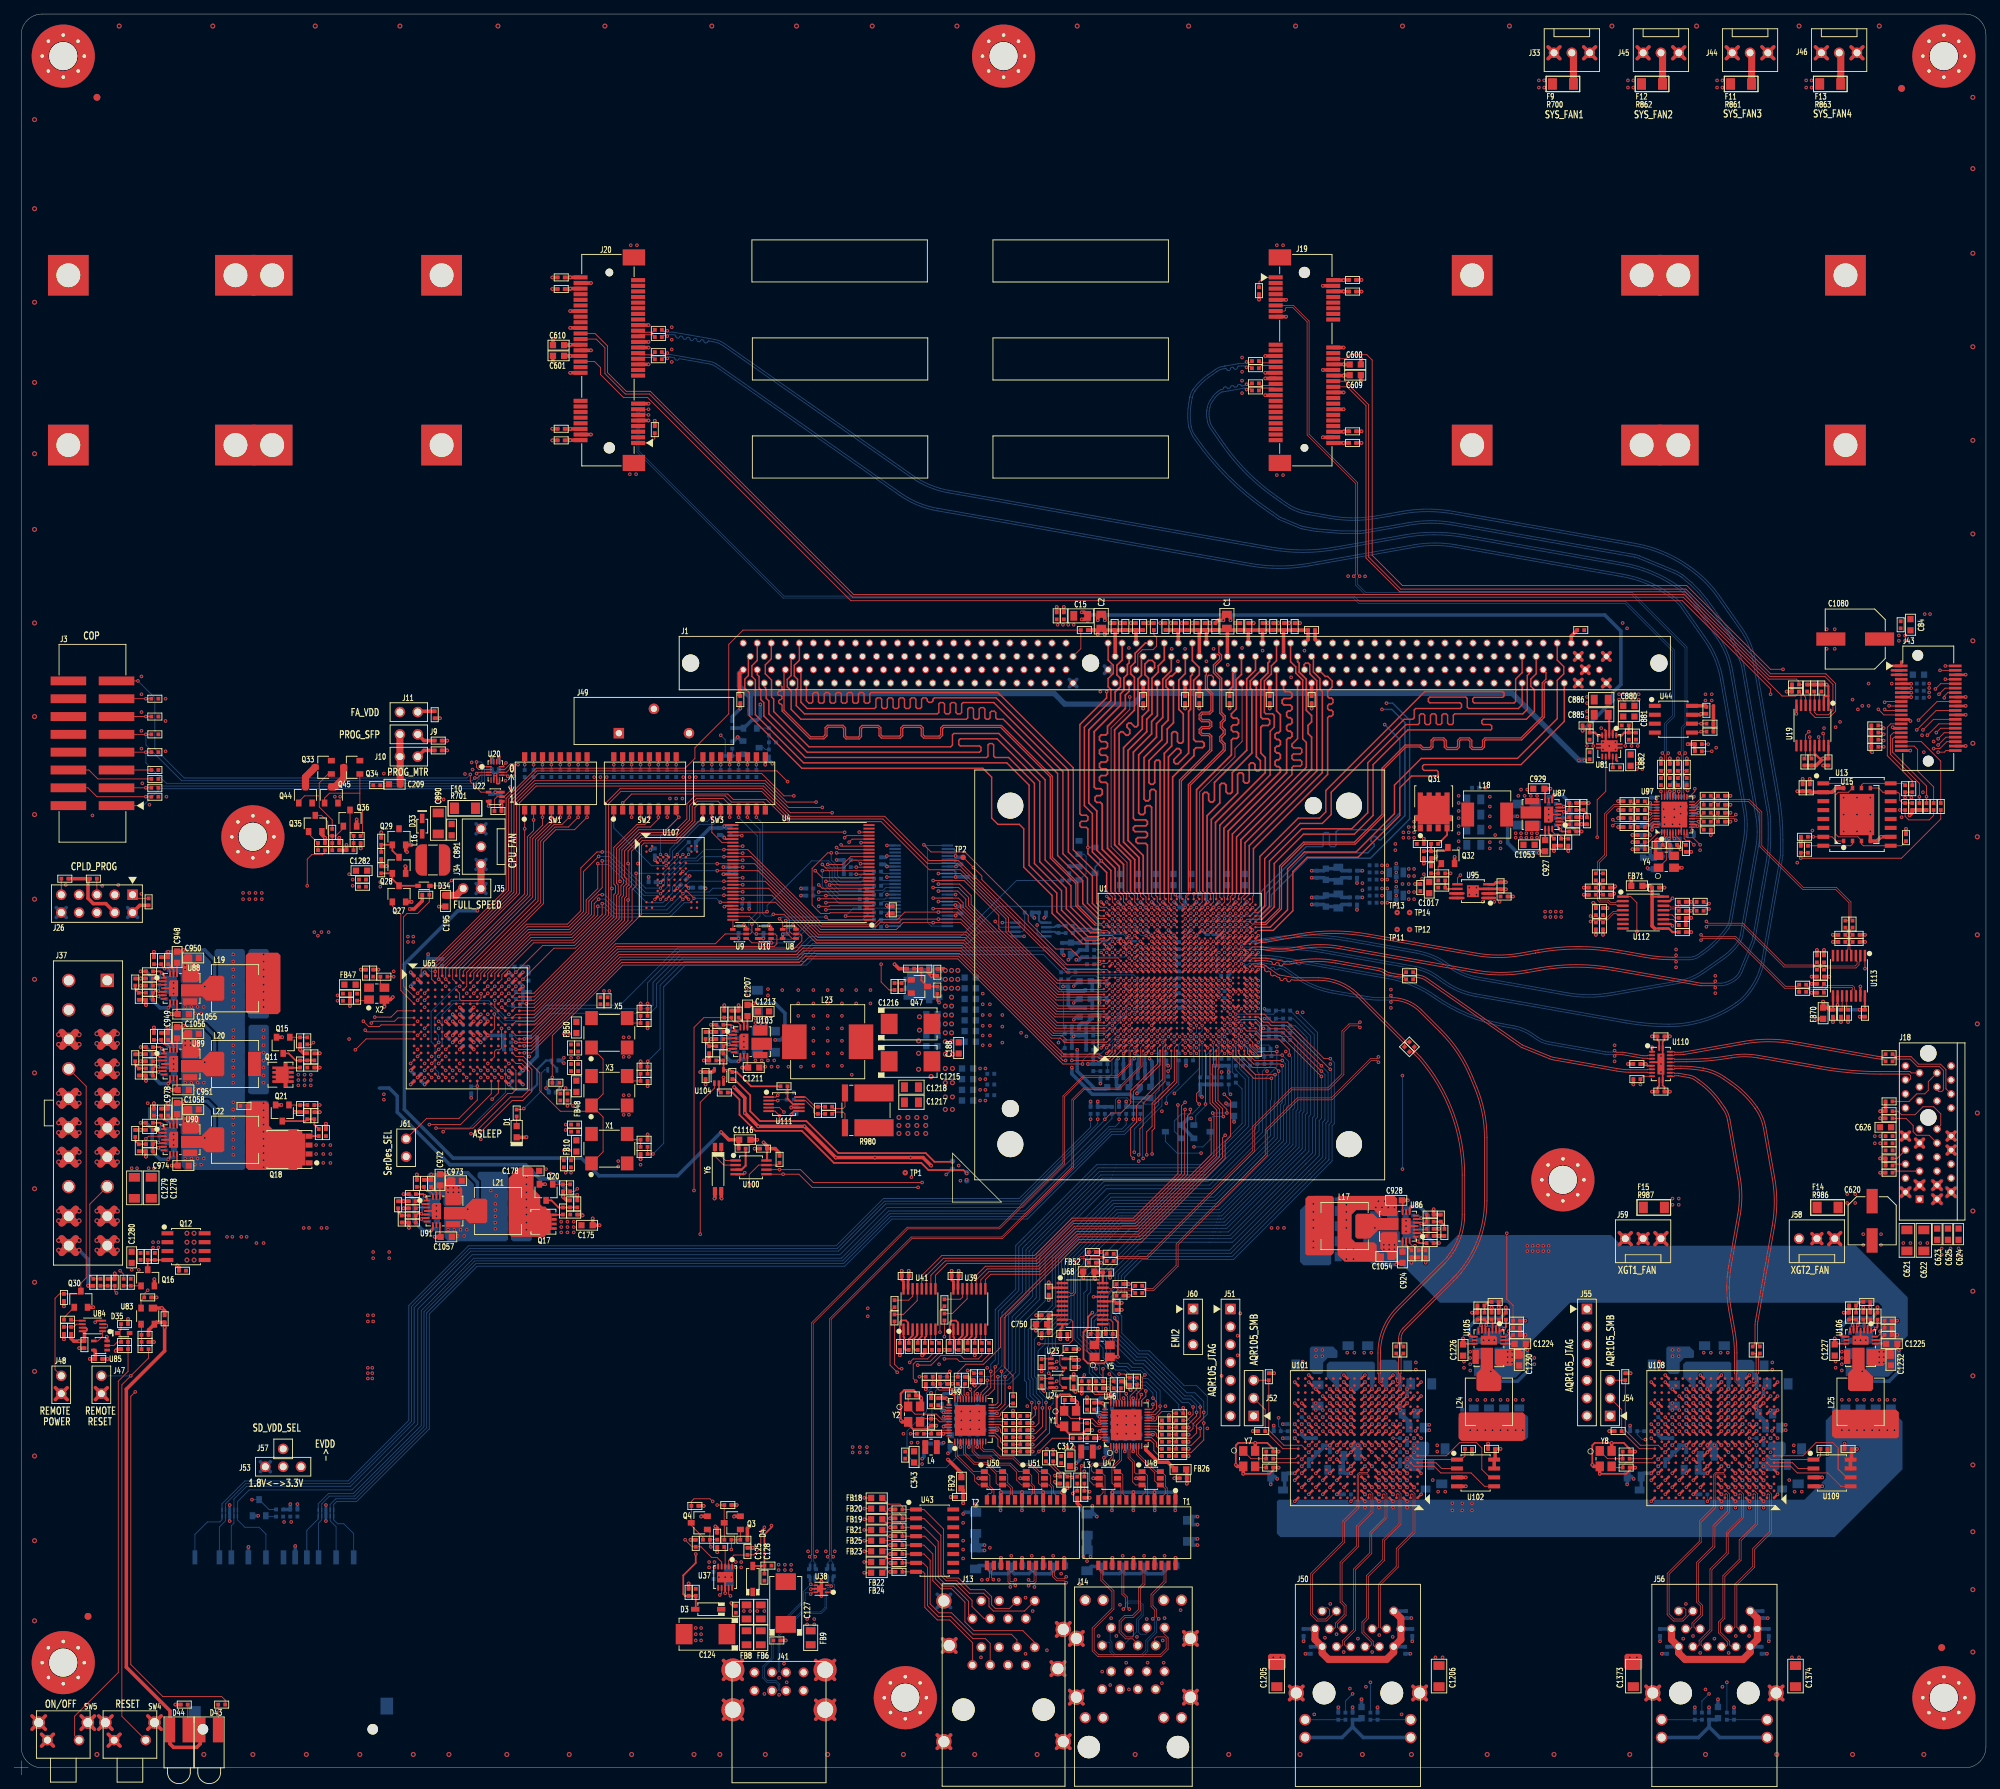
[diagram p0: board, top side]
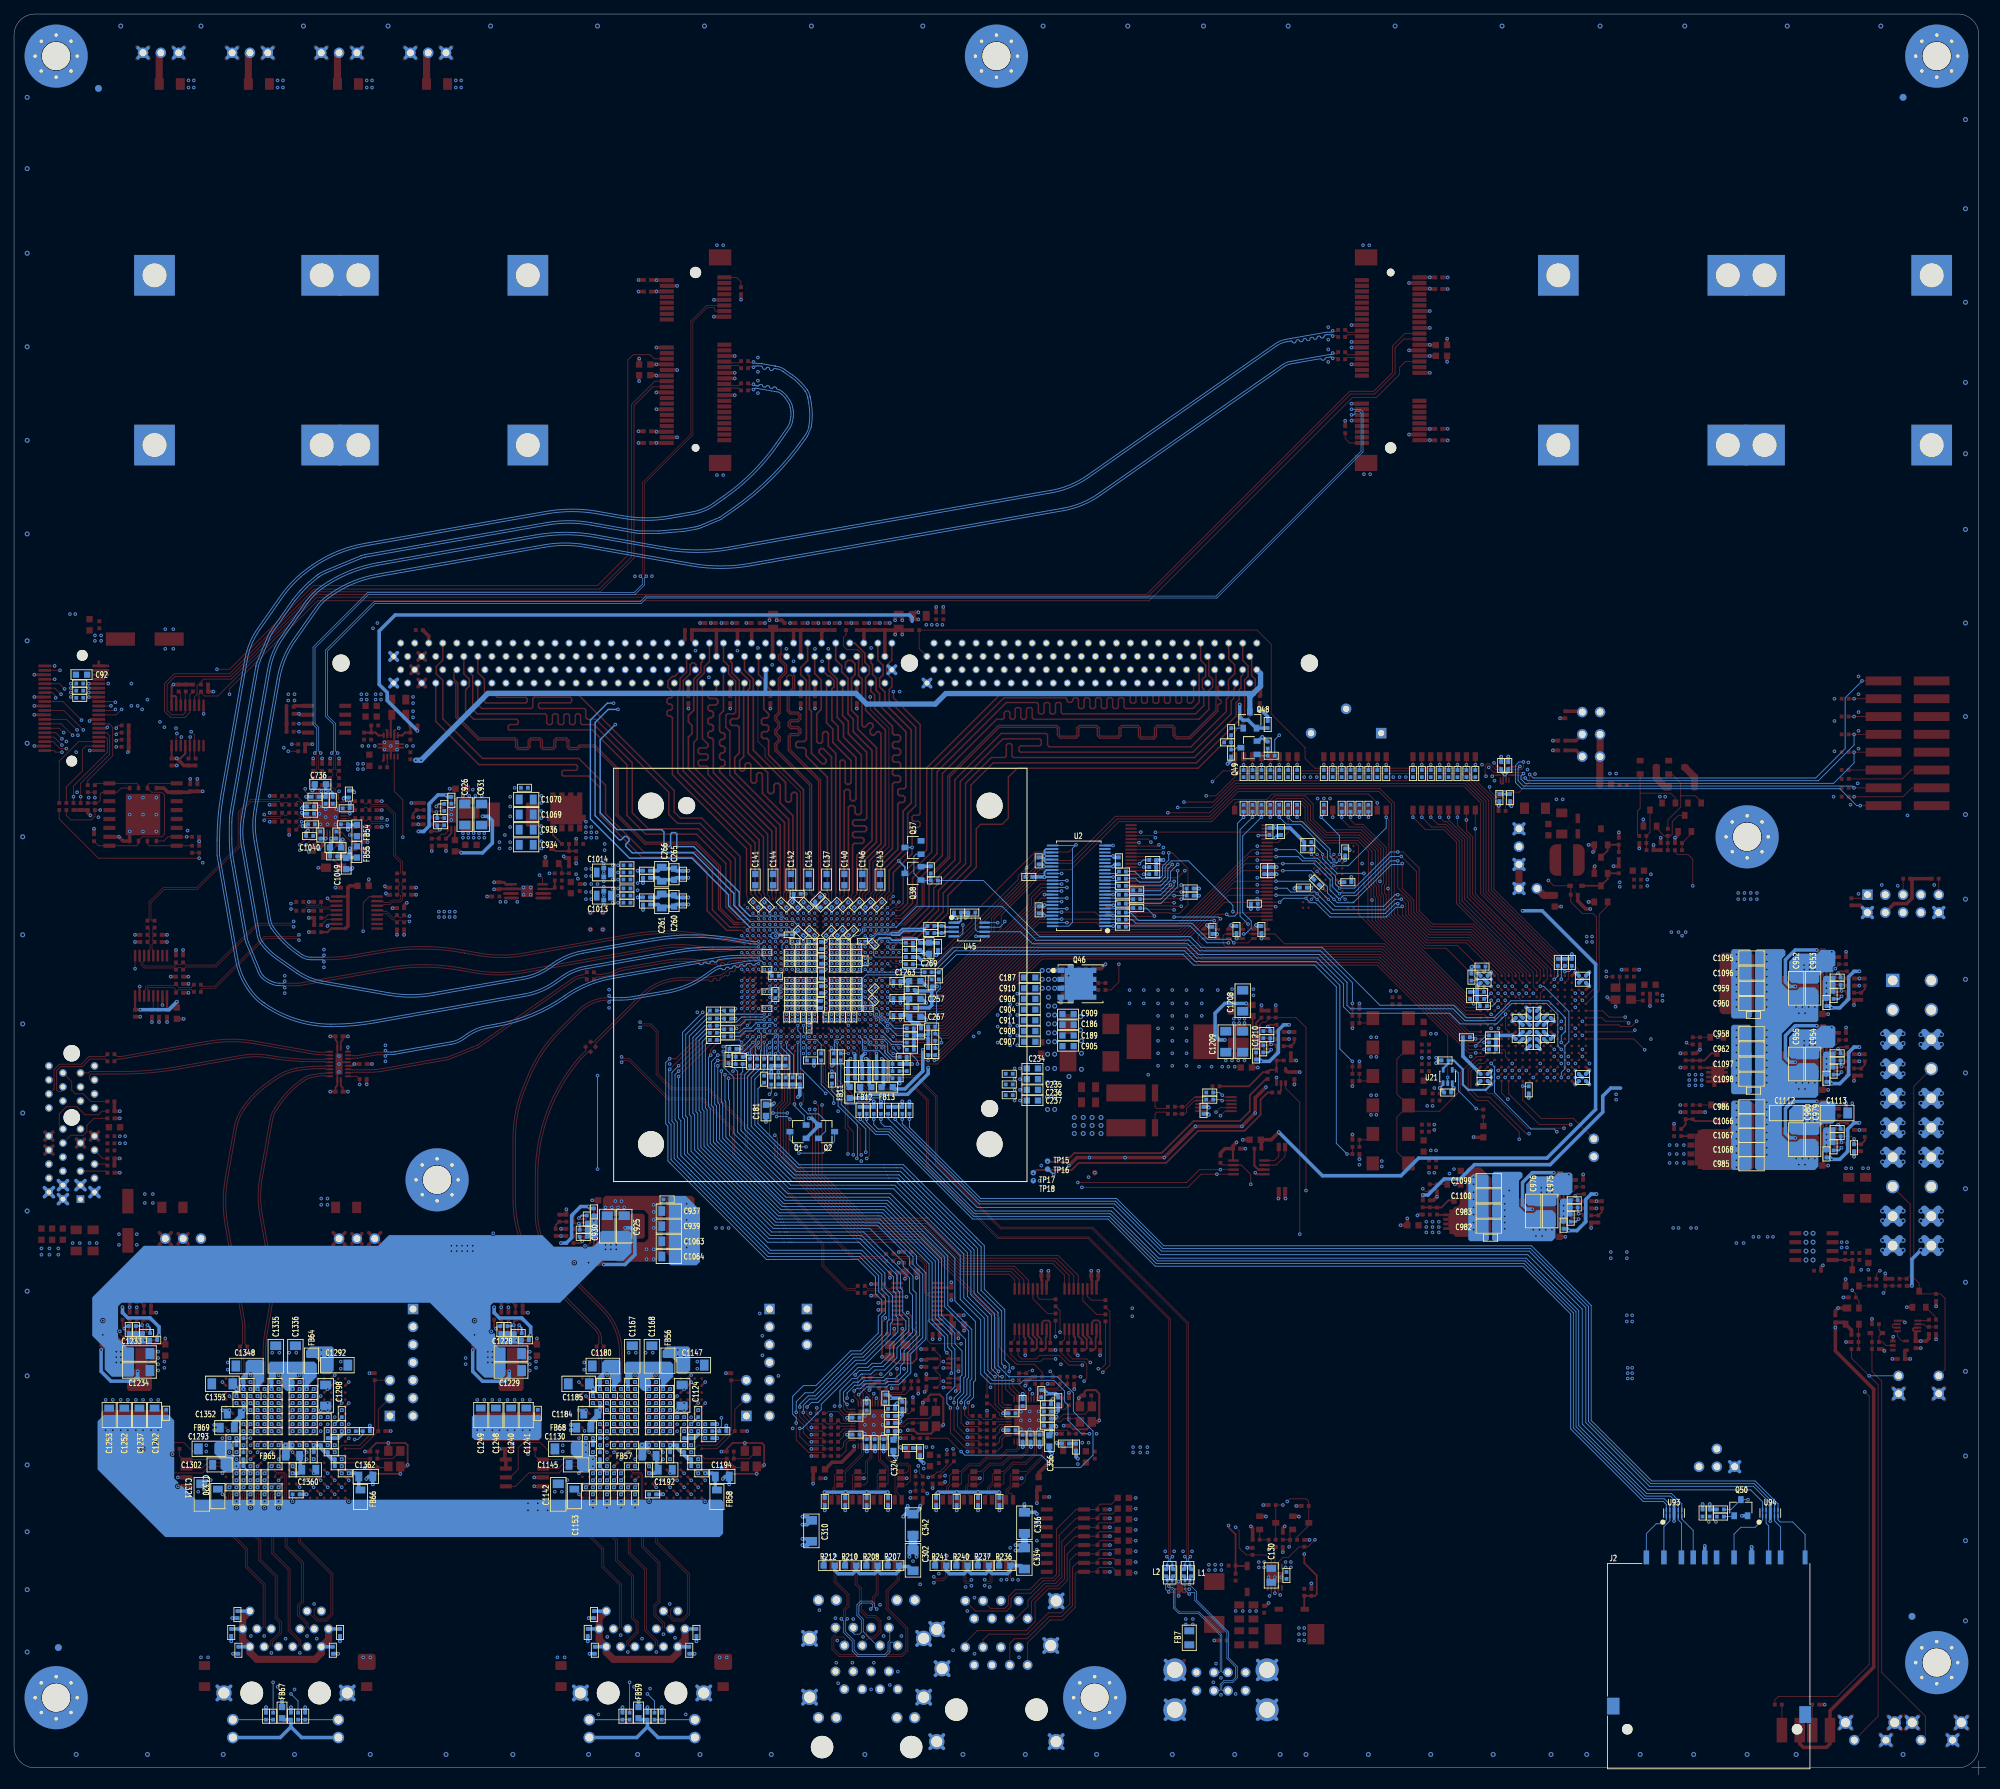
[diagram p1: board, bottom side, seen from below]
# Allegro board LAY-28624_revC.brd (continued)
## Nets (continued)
GND: C1.2 C2.2 C3.2 C4.2 C5.2 C6.2 C7.2 C8.2 C9.2 C10.2 C11.2 C12.2 C13.2 C14.2 C15.2 C16.2 C17.2 C18.2 C19.2 C20.2 C21.2 C22.2 C23.2 C24.2 C25.2 C26.2 C30.2 C31.2 C32.2 C33.2 C34.2 C35.2 C36.2 C37.2 C38.2 C39.2 C48.2 C49.2 C50.2 C51.2 C52.2 C53.2 C54.2 C55.1 C56.2 C57.2 C58.2 C84.2 C85.2 C92.2 C93.2 C94.2 C124.2 C125.2 C126.2 C127.2 C128.2 C129.2 C130.2 C131.2 C132.2 C133.2 C134.2 C135.2 C136.2 C137.2 C138.2 C139.2 C140.2 C141.2 C142.2 C143.2 C144.2 C145.2 C146.2 C147.2 C148.2 C149.2 C150.2 C151.2 C152.2 C153.2 C154.2 C155.2 C156.2 C157.2 C158.2 C159.2 C160.2 C161.2 C162.2 C163.2 C164.2 C165.2 C166.2 C167.2 C168.2 C169.2 C170.2 C171.2 C172.2 C173.2 C174.2 C175.2 C176.2 C177.2 C178.2 C179.2 C180.2 C181.2 C182.2 C183.2 C184.2 C185.2 C186.2 C187.2 C188.2 C189.2 C192.2 C195.2 C196.2 C197.2 C198.2 C199.2 C200.2 C201.2 C202.2 C203.2 C204.2 C205.2 C206.2 C207.2 C208.2 C209.2 C210.2 C211.2 C212.2 C213.2 C214.2 C215.2 C216.2 C217.2 C218.2 C219.2 C220.2 C222.2 C223.2 C224.2 C225.2 C226.2 C227.2 C228.2 C229.2 C230.2 C232.2 C234.2 C235.2 C236.2 C237.2 C238.2 C239.2 C240.2 C241.2 C242.2 C243.2 C244.2 C245.2 C246.2 C247.2 C248.2 C249.2 C250.2 C251.2 C252.2 C253.2 C254.2 C255.2 C257.2 C258.2 C267.2 C268.2 C269.2 C270.2 C272.2 C273.2 C275.2 C276.2 C277.2 C278.2 C279.2 C286.2 C287.2 C288.2 C289.2 C290.2 C291.2 C292.2 C293.2 C295.2 C296.1 C297.2 C298.1 C299.1 C300.1 C301.1 C303.2 C304.2 C305.2 C307.2 C308.2 C309.2 C310.1 C312.2 C313.2 C314.2 C315.2 C316.2 C317.2 C319.2 C320.2 C321.2 C322.2 C323.2 C324.2 C325.2 C326.2 C328.1 C329.2 C330.1 C331.1 C332.1 C333.1 C335.2 C336.1 C337.2 C338.2 C339.2 C340.2 C341.2 C342.1 C343.2 C344.2 C346.2 C347.2 C348.2 C349.2 C350.2 C351.2 C353.2 C354.2 C355.2 C356.2 C357.2 C358.2 C600.2 C601.2 C602.2 C603.2 C604.2 C605.2 C609.2 C610.2 C611.2 C612.2 C613.2 C614.2 C620.2 C621.2 C622.2 C623.2 C624.2 C625.2 C626.2 C627.2 C628.2 C629.2 C698.2 C699.2 C700.2 C701.2 C702.2 C703.2 C704.2 C705.2 C706.2 C707.2 C708.2 C709.2 C710.2 C711.2 C712.2 C713.2 C714.2 C715.2 C716.2 C718.2 C720.2 C721.2 C722.2 C723.2 C728.2 C729.2 C730.2 C731.2 C732.2 C733.2 C734.2 C735.2 C736.2 C737.2 C738.2 C739.2 C742.2 C743.2 C746.2 C747.2 C750.2 C751.2 C873.1 C875.1 C876.1 C880.2 C881.2 C882.2 C883.2 C884.2 C885.2 C886.2 C887.2 C892.2 C893.2 C894.2 C895.2 C896.2 C897.2 C898.2 C904.2 C905.2 C906.2 C907.2 C908.2 C909.2 C910.2 C911.2 C912.2 C913.2 C914.2 C915.2 C916.2 C917.2 C918.2 C919.2 C920.2 C921.2 C922.2 C923.2 C925.2 C926.2 C928.1 C929.1 C930.2 C931.2 C932.1 C933.2 C934.2 C936.2 C937.2 C938.1 C939.2 C940.2 C944.2 C945.2 C946.2 C947.2 C950.1 C951.1 C952.2 C953.2 C954.2 C955.2 C956.1 C957.1 C958.2 C959.2 C960.2 C961.2 C962.2 C963.2 C968.2 C969.2 C970.2 C971.2 C973.1 C974.1 C975.2 C976.2 C977.1 C979.2 C980.2 C981.1 C982.2 C983.2 C984.2 C985.2 C986.2 C987.2 C992.2 C993.2 C994.2 C995.2 C996.1 C998.2 C999.2 C1002.2 C1003.2 C1004.2 C1005.2 C1006.2 C1007.2 C1008.2 C1009.2 C1010.2 C1011.2 C1012.2 C1013.3 C1013.4 C1014.3 C1014.4 C1015.2 C1016.2 C1017.2 C1023.1 C1024.2 C1026.2 C1027.2 C1028.2 C1029.2 C1030.2 C1031.2 C1032.2 C1033.2 C1034.2 C1035.2 C1036.2 C1037.2 C1038.2 C1039.2 C1040.2 C1041.2 C1044.2 C1045.2 C1046.2 C1047.2 C1048.2 C1049.2 C1050.2 C1051.2 C1052.2 C1053.1 C1054.1 C1055.1 C1056.1 C1057.1 C1058.1 C1063.2 C1064.2 C1066.2 C1067.2 C1068.2 C1069.2 C1070.2 C1079.2 C1080.2 C1081.2 C1095.2 C1096.2 C1097.2 C1098.2 C1099.2 C1100.2 C1101.2 C1102.2 C1103.2 C1104.2 C1105.2 C1112.2 C1113.2 C1114.2 C1115.2 C1116.2 C1119.2 C1120.2 C1121.2 C1122.1 C1123.1 C1124.2 C1125.1 C1126.2 C1127.2 C1128.2 C1129.2 C1130.2 C1131.1 C1132.1 C1133.1 C1134.1 C1135.1 C1136.2 C1137.2 C1138.2 C1139.2 C1140.2 C1141.2 C1142.2 C1143.1 C1144.1 C1145.2 C1146.1 C1147.2 C1148.1 C1149.2 C1150.1 C1151.2 C1152.2 C1153.2 C1154.1 C1155.1 C1156.1 C1157.1 C1158.1 C1159.1 C1160.2 C1161.2 C1162.2 C1163.2 C1164.2 C1165.2 C1166.1 C1167.2 C1168.2 C1169.1 C1170.1 C1171.1 C1172.1 C1173.1 C1174.1 C1175.1 C1176.1 C1177.2 C1178.2 C1179.2 C1180.2 C1181.2 C1182.1 C1183.2 C1184.2 C1185.2 C1186.1 C1187.1 C1188.1 C1189.1 C1190.1 C1191.2 C1192.2 C1193.2 C1194.2 C1197.2 C1198.1 C1199.1 C1200.2 C1201.1 C1202.1 C1203.2 C1204.1 C1205.1 C1206.1 C1208.2 C1209.2 C1210.2 C1211.2 C1212.1 C1213.2 C1215.2 C1216.2 C1217.2 C1218.2 C1220.2 C1221.2 C1222.2 C1223.2 C1226.1 C1227.1 C1228.2 C1229.2 C1230.1 C1231.1 C1232.1 C1233.2 C1234.2 C1235.1 C1236.2 C1237.2 C1238.2 C1240.2 C1241.2 C1242.2 C1246.2 C1247.2 C1248.2 C1249.2 C1250.2 C1251.2 C1252.2 C1253.2 C1262.2 C1263.2 C1264.2 C1273.1 C1274.2 C1275.2 C1276.2 C1277.2 C1278.2 C1279.2 C1280.2 C1281.2 C1282.2 C1283.2 C1284.2 C1287.2 C1288.2 C1289.2 C1290.1 C1291.1 C1292.2 C1293.2 C1294.2 C1295.1 C1296.1 C1297.1 C1298.2 C1299.1 C1300.2 C1301.2 C1302.2 C1303.1 C1304.1 C1305.1 C1306.1 C1307.2 C1308.2 C1309.2 C1310.2 C1311.1 C1312.1 C1313.1 C1314.2 C1315.2 C1316.2 C1317.2 C1318.2 C1319.2 C1320.2 C1321.2 C1322.1 C1323.1 C1324.1 C1325.1 C1326.1 C1327.1 C1328.2 C1329.2 C1330.1 C1331.2 C1332.2 C1333.2 C1334.2 C1335.2 C1336.2 C1337.1 C1338.1 C1339.1 C1340.1 C1341.1 C1342.1 C1343.1 C1344.1 C1345.2 C1346.2 C1347.2 C1348.2 C1349.2 C1350.1 C1351.2 C1352.2 C1353.2 C1354.1 C1355.1 C1356.1 C1357.1 C1358.1 C1359.2 C1360.2 C1361.2 C1362.2 C1365.2 C1366.1 C1367.1 C1368.2 C1369.1 C1370.1 C1371.2 C1372.1 C1373.1 C1374.1 C1375.2 C1376.2 C1377.2 C1379.2 C1390.2 C1391.2 C1392.2 C1393.2 D1.1 FB7.2 FB9.2 J1.2(VSS#2) J1.5(VSS#5) J1.8(VSS#8) J1.11(VSS#11) J1.14(VSS#14) J1.17(VSS#17) J1.20(VSS#20) J1.23(VSS#23) J1.26(VSS#26) J1.29(VSS#29) J1.32(VSS#32) J1.35(VSS#35) J1.38(VSS#38) J1.41(VSS#41) J1.44(VSS#44) J1.47(VSS#47) J1.80(VSS#80) J1.83(VSS#83) J1.86(VSS#86) J1.89(VSS#89) J1.92(VSS#92) J1.95(VSS#95) J1.98(VSS#98) J1.101(VSS#101) J1.104(VSS#104) J1.107(VSS#107) J1.110(VSS#110) J1.113(VSS#113) J1.116(VSS#116) J1.119(SA2) J1.121(VSS#121) J1.124(VSS#124) J1.127(VSS#127) J1.130(VSS#130) J1.133(VSS#133) J1.136(VSS#136) J1.139(VSS#139) J1.142(VSS#142) J1.145(VSS#145) J1.148(VSS#148) J1.151(VSS#151) J1.154(VSS#154) J1.157(VSS#157) J1.160(VSS#160) J1.163(VSS#163) J1.166(VSS#166) J1.199(VSS#199) J1.202(VSS#202) J1.205(VSS#205) J1.208(VSS#208) J1.211(VSS#211) J1.214(VSS#214) J1.217(VSS#217) J1.220(VSS#220) J1.223(VSS#223) J1.226(VSS#226) J1.229(VSS#229) J1.232(VSS#232) J1.235(VSS#235) J1.237(SA1) J1.239(VSS#239) J2.3(VSS#3) J2.6(VSS#6) J2.12(COM1) J2.13(COM2) J3.12 J3.16 J13.A4 J13.A5 J13.B4 J13.B5 J14.A10 J14.B10 J18.A1(P\R\S\N\T\1\) J18.A4(GND#A4) J18.A12(GND#A12) J18.A15(GND#A15) J18.A18(GND#A18) J18.B4(GND#B4) J18.B7(GND#B7) J18.B13(GND#B13) J18.B16(GND#B16) J18.B18(GND#B18) J19.4(GND#4) J19.9(GND#9) J19.15(GND#15) J19.18(GND#18) J19.21(GND#21) J19.26(GND#26) J19.27(GND#27) J19.29(GND#29) J19.34(GND#34) J19.35(GND#35) J19.40(GND#40) J19.50(GND#50) J19.53(MS1) J19.54(MS2) J20.4(GND#4) J20.9(GND#9) J20.15(GND#15) J20.18(GND#18) J20.21(GND#21) J20.26(GND#26) J20.27(GND#27) J20.29(GND#29) J20.34(GND#34) J20.35(GND#35) J20.40(GND#40) J20.50(GND#50) J20.53(MS1) J20.54(MS2) J26.2 J26.10 J33.1 J33.3 J35.2 J37.3(COM#3) J37.5(COM#5) J37.7(COM#7) J37.13(COM#13) J37.15(COM#15) J37.16(COM#16) J37.17(COM#17) J43.5 J43.15 J43.19 J43.23 J43.26 J43.30 J43.37 J43.40 J44.1 J44.3 J45.1 J45.3 J46.1 J46.3 J47.2 J48.2 J49.2 J51.7 J52.1 J54.1 J55.7 J58.1 J58.3 J59.1 J59.3 J60.1 J61.2 M3.1 M4.1 M5.1 M6.1 M7.1 M8.1 M9.1 M10.1 M11.1 M12.1 M13.1 M14.1 M15.1 M16.1 M17.1 M18.1 Q3.2(S) Q4.2(S) Q15.2(S) Q16.2(S) Q20.2(S) Q21.2(S) Q27.2(S) Q28.2(S) Q29.2(S) Q30.2(E) Q32.2(S) Q35.2(S) Q36.2(S) Q37.2(S) Q38.2(S) Q47.2(S) Q49.2(S) R3.1 R13.1 R17.2 R19.2 R21.2 R23.2 R25.2 R27.2 R29.2 R31.2 R33.2 R34.2 R35.2 R36.2 R37.2 R38.2 R39.2 R40.2 R104.1 R105.1 R106.1 R123.1 R124.2 R161.1 R162.1 R165.1 R166.1 R171.1 R172.1 R173.1 R176.1 R177.1 R178.1 R179.1 R190.2 R193.2 R227.1 R228.2 R233.2 R256.1 R257.2 R261.2 R262.2 R400.2 R401.2 R496.1 R499.2 R500.2 R501.2 R503.2 R505.2 R507.2 R509.2 R513.1 R518.1 R519.2 R523.2 R524.1 R527.2 R528.1 R534.2 R535.1 R538.1 R541.1 R542.1 R543.1 R544.1 R656.1 R669.1 R671.1 R672.1 R673.1 R684.1 R685.1 R696.1 R699.1 R708.1 R712.1 R742.1 R743.1 R744.1 R745.1 R760.1 R761.1 R762.1 R763.1 R778.1 R779.1 R780.1 R781.1 R782.1 R786.1 R807.1 R814.1 R815.1 R821.1 R831.1 R835.2 R838.2 R842.1 R870.1 R888.2 R889.2 R890.2 R891.2 R892.2 R899.2 R900.2 R901.1 R909.1 R911.1 R913.1 R920.1 R935.1 R936.1 R937.1 R938.1 R945.1 R949.1 R950.1 R951.1 R955.1 R961.2 R962.2 R963.2 R964.2 R967.2 R972.2 R973.2 R974.1 R975.1 R979.1 R983.1 R984.1 R993.2 R995.2 R997.2 R999.2 R1000.2 R1001.2 R1002.2 R1003.2 R1004.1 R1005.1 R1006.1 R1007.1 R1008.1 R1009.1 R1010.1 R1011.1 R1013.2 R1014.1 SW3.9 SW4.1 SW4.3 SW4.4 SW5.1 SW5.3 SW5.4 U1.A2(GND001) U1.A20(GND002) U1.A27(GND003) U1.AA7(GND148) U1.AA11(GND149) U1.AA13(SD_GND05) U1.AA15(SD_GND06) U1.AA17(SD_GND08) U1.AA19(SD_GND09) U1.AA21(SD_GND11) U1.AA24(GND150) U1.AB2(GND151) U1.AB5(GND152) U1.AB7(GND153) U1.AB13(SD_GND12) U1.AB17(SD_GND13) U1.AB21(SD_GND14) U1.AB22(GND154) U1.AB26(GND155) U1.AC1(NC_AC1) U1.AC2(NC_AC2) U1.AC10(NC_AC10) U1.AC11(NC_AC11) U1.AC13(SD_GND15) U1.AC14(SD_GND16) U1.AC16(SD_GND17) U1.AC17(SD_GND18) U1.AC19(SD_GND19) U1.AC20(SD_GND20) U1.AC24(GND156) U1.AC26(GND157) U1.AD4(GND158) U1.AD6(GND159) U1.AD9(NC_AD9) U1.AD12(NC_AD12) U1.AD15(SD_GND21) U1.AD18(SD_GND22) U1.AD21(SD_GND23) U1.AD22(GND160) U1.AE2(GND161) U1.AE9(NC_AE9) U1.AE12(NC_AE12) U1.AE15(SD_GND24) U1.AE18(SD_GND25) U1.AE21(SD_GND26) U1.AE24(GND162) U1.AE26(GND163) U1.AF9(GND164) U1.AF10(NC_AF10) U1.AF11(NC_AF11) U1.AF12(NC_AF12) U1.AF13(NC_AF13) U1.AF14(NC_AF14) U1.AF15(SD_GND27) U1.AF16(SD_GND28) U1.AF17(SD_GND29) U1.AF18(SD_GND30) U1.AF19(SD_GND31) U1.AF20(SD_GND32) U1.AF21(GND165) U1.AG1(GND166) U1.AG4(GND167) U1.AG6(GND168) U1.AG9(NC_AG9) U1.AG10(NC_AG10) U1.AG11(NC_AG11) U1.AG12(NC_AG12) U1.AG13(NC_AG13) U1.AG14(NC_AG14) U1.AG15(SD_GND33) U1.AG18(SD_GND34) U1.AG21(SD_GND35) U1.AG22(GND169) U1.AG23(GND170) U1.AG26(GND171) U1.AH2(GND172) U1.AH9(NC_AH9) U1.AH10(NC_AH10) U1.AH11(NC_AH11) U1.AH12(NC_AH12) U1.AH13(NC_AH13) U1.AH14(NC_AH14) U1.AH15(SD_GND36) U1.AH18(SD_GND37) U1.AH21(SD_GND38) U1.B1(GND004) U1.B4(GND005) U1.B7(GND006) U1.B10(GND007) U1.B13(GND008) U1.B16(GND009) U1.B19(GND010) U1.B23(GND011) U1.B25(GND012) U1.B28(GND013) U1.C22(GND014) U1.C26(GND015) U1.D2(GND016) U1.D20(GND017) U1.D21(GND018) U1.D24(GND019) U1.E1(USB_AGND01) U1.E2(USB_AGND02) U1.E3(USB_AGND03) U1.E5(GND020) U1.E7(GND021) U1.E10(GND022) U1.E13(GND023) U1.E16(GND024) U1.E19(GND025) U1.E22(GND026) U1.E26(GND027) U1.F3(USB_AGND04) U1.F15(GND028) U1.F24(GND029) U1.G1(USB_AGND05) U1.G2(USB_AGND06) U1.G3(USB_AGND07) U1.G5(USB_AGND08) U1.G7(GND030) U1.G13(GND031) U1.G16(GND032) U1.G22(GND033) U1.G26(GND034) U1.H3(USB_AGND09) U1.H7(GND035) U1.H8(GND036) U1.H9(GND037) U1.H10(GND038) U1.H11(GND039) U1.H12(GND040) U1.H13(GND041) U1.H14(GND042) U1.H15(GND043) U1.H16(GND044) U1.H17(GND045) U1.H18(GND046) U1.H19(GND047) U1.H20(GND048) U1.H24(GND049) U1.J1(USB_AGND10) U1.J2(USB_AGND11) U1.J3(USB_AGND12) U1.J7(GND050) U1.J22(GND051) U1.J26(GND052) U1.K2(GND053) U1.K5(GND054) U1.K6(GND055) U1.K7(GND056) U1.K12(GND057) U1.K14(GND058) U1.K16(GND059) U1.K18(GND060) U1.K20(GND061) U1.K24(GND062) U1.L7(GND063) U1.L9(GND064) U1.L11(GND065) U1.L13(GND066) U1.L15(GND067) U1.L17(GND068) U1.L19(GND069) U1.L22(GND070) U1.L26(GND071) U1.M7(GND072) U1.M10(GND073) U1.M12(GND074) U1.M14(GND075) U1.M16(GND076) U1.M18(GND077) U1.M20(GND078) U1.M24(GND079) U1.N2(GND080) U1.N5(GND081) U1.N7(GND082) U1.N9(GND083) U1.N11(GND084) U1.N13(GND085) U1.N15(GND086) U1.N17(GND087) U1.N19(GND088) U1.N22(GND089) U1.N26(GND090) U1.P7(GND091) U1.P10(GND092) U1.P12(GND093) U1.P14(GND094) U1.P16(GND095) U1.P18(GND096) U1.P20(GND097) U1.P24(GND098) U1.R7(GND099) U1.R9(GND100) U1.R11(GND101) U1.R13(GND102) U1.R15(GND103) U1.R17(GND104) U1.R19(GND105) U1.R22(GND106) U1.R26(GND107) U1.T2(GND108) U1.T5(GND109) U1.T7(GND110) U1.T10(GND111) U1.T12(GND112) U1.T14(GND113) U1.T16(GND114) U1.T18(GND115) U1.T20(GND116) U1.T22(GND117) U1.T26(GND118) U1.U7(GND119) U1.U9(GND120) U1.U11(GND121) U1.U13(GND122) U1.U15(GND123) U1.U17(GND124) U1.U19(GND125) U1.U24(GND126) U1.V7(GND127) U1.V10(GND128) U1.V12(GND129) U1.V14(GND130) U1.V16(GND131) U1.V18(GND132) U1.V20(GND133) U1.V22(GND134) U1.V26(GND135) U1.W2(GND136) U1.W5(GND137) U1.W7(GND138) U1.W9(GND139) U1.W11(GND140) U1.W13(GND141) U1.W24(GND142) U1.Y7(GND143) U1.Y10(GND144) U1.Y12(GND145) U1.Y14(SD_GND01) U1.Y16(SD_GND02) U1.Y17(SD_GND03) U1.Y18(SD_GND04) U1.Y22(GND146) U1.Y26(GND147) U2.1(O\E\1\) U2.4(GND#4) U2.10(GND#10) U2.15(GND#15) U2.21(GND#21) U2.24(O\E\2\) U2.26(2D8) U2.27(2D7) U2.28(GND#28) U2.29(2D6) U2.30(2D5) U2.32(2D4) U2.34(GND#34) U2.39(GND#39) U2.45(GND#45) U4.33(GND#33) U4.52(GND#52) U8.3(GND) U9.3(GND) U10.3(GND) U13.10(GND) U15.4(GND) U15.9(EPAD) U19.8(VSS) U20.6(GND#6) U20.7(GND#7) U20.8(O\E\) U21.3(GND) U22.3(GND) U23.3(GND) U24.3(GND) U37.8(GND) U37.11(EPAD) U38.2 U39.15(GND) U41.15(GND) U43.9 U43.10 U43.11 U43.12 U43.13 U43.14 U43.15 U43.16 U44.1(A0) U44.2(A1) U44.3(A2) U44.4(GND) U44.7(WP) U45.5(GND) U46.47(GND) U46.49(EPAD) U47.2 U48.2 U49.47(GND) U49.49(EPAD) U50.2 U51.2 U65.A1(GNDIO#A1) U65.A16(GNDIO#A16) U65.B2(GNDIO#B2) U65.B15(GNDIO#B15) U65.G7(GNDIO#G7) U65.G8(GNDIO#G8) U65.G9(GNDIO#G9) U65.G10(GNDIO#G10) U65.H7(GNDINT#H7) U65.H9(GNDINT#H9) U65.J8(GNDINT#J8) U65.J10(GNDINT#J10) U65.K7(GNDIO#K7) U65.K8(GNDIO#K8) U65.K9(GNDIO#K9) U65.K10(GNDIO#K10) U65.R2(GNDIO#R2) U65.R15(GNDIO#R15) U65.T1(GNDIO#T1) U65.T16(GNDIO#T16) U68.17(VEE) U81.4(PGND) U81.8(GND) U81.11(PAD) U83.1(GND) U84.4(GND) U85.3(GND) U86.4(GND#4) U86.11(PGND) U86.17(GND#17) U87.4(GND#4) U87.11(PGND) U87.17(GND#17) U88.4(GND#4) U88.11(PGND) U88.17(GND#17) U89.4(GND#4) U89.11(PGND) U89.17(GND#17) U90.4(GND#4) U90.11(PGND) U90.17(GND#17) U91.4(GND#4) U91.11(PGND) U91.17(GND#17) U93.9 U94.9 U95.3(GND) U95.9(EPAD) U97.8(GNDDIG) U97.41(EPAD) U100.4(GND) U101.A1(RG_A1) U101.A18(RG_A18) U101.B3(AVSS#B3) U101.B5(AVSS#B5) U101.B7(AVSS#B7) U101.B9(AVSS#B9) U101.B12(AVSS#B12) U101.B14(AVSS#B14) U101.B16(AVSS#B16) U101.C2(AVSS#C2) U101.C4(AVSS#C4) U101.C6(AVSS#C6) U101.C8(AVSS#C8) U101.C11(AVSS#C11) U101.C13(AVSS#C13) U101.C15(AVSS#C15) U101.C17(AVSS#C17) U101.D3(AVSS#D3) U101.D5(AVSS#D5) U101.D7(AVSS#D7) U101.D9(AVSS#D9) U101.D12(AVSS#D12) U101.D14(AVSS#D14) U101.D16(AVSS#D16) U101.D18(AVSS#D18) U101.E1(DC_MASTER_N) U101.E4(AVSS#E4) U101.E6(AVSS_PLL) U101.E11(AVSS#E11) U101.E13(AVSS#E13) U101.E15(AVSS#E15) U101.E17(AVSS#E17) U101.F6(AVSS#F6) U101.F8(AVSS#F8) U101.F10(AVSS#F10) U101.F12(AVSS#F12) U101.G5(AVSS#G5) U101.G7(AVSS#G7) U101.G9(AVSS#G9) U101.G11(AVSS#G11) U101.H4(MDIO_1P2_SELECT_N) U101.H6(AVSS#H6) U101.H8(AVSS#H8) U101.H10(AVSS#H10) U101.H12(AVSS#H12) U101.J5(VSS#J5) U101.J7(VSS#J7) U101.J9(VSS#J9) U101.J11(VSS#J11) U101.J13(VSS#J13) U101.K6(VSS#K6) U101.K8(VSS#K8) U101.K10(VSS#K10) U101.K12(VSS#K12) U101.L4(RG_L4) U101.L7(VSS#L7) U101.L9(VSS#L9) U101.L11(VSS#L11) U101.L13(VSS#L13) U101.M6(VSS#M6) U101.M8(VSS#M8) U101.M10(VSS#M10) U101.M12(VSS#M12) U101.N1(VSS_SRDS#N1) U101.N2(VSS_SRDS#N2) U101.N5(VSS#N5) U101.N7(VSS#N7) U101.N9(VSS#N9) U101.N11(VSS#N11) U101.N13(VSS#N13) U101.P3(VSS_SRDS#P3) U101.P6(VSS#P6) U101.P8(VSS#P8) U101.P10(VSS#P10) U101.P12(VSS#P12) U101.P17(VSS_SRDS#P17) U101.P18(VSS_SRDS#P18) U101.R1(VSS_SRDS#R1) U101.R2(VSS_SRDS#R2) U101.R4(VSS_SRDS#R4) U101.R6(VSS_SRDS#R6) U101.R7(VSS#R7) U101.R9(VSS#R9) U101.R11(VSS#R11) U101.R13(VSS#R13) U101.R14(VSS_SRDS#R14) U101.T3(VSS_SRDS#T3) U101.T5(VSS_SRDS#T5) U101.T7(VSS_SRDS#T7) U101.T9(VSS_SRDS#T9) U101.T11(VSS_SRDS#T11) U101.T13(VSS_SRDS#T13) U101.T15(VSS_SRDS#T15) U101.U1(VSS_SRDS#U1) U101.U5(VSS_SRDS#U5) U101.U9(VSS_SRDS#U9) U101.U11(VSS_SRDS#U11) U101.U16(VSS_SRDS#U16) U101.U18(VSS_SRDS#U18) U101.V5(VSS_SRDS#V5) U101.V9(VSS_SRDS#V9) U101.V11(VSS_SRDS#V11) U101.V16(VSS_SRDS#V16) U102.4(GND) U103.4(GND#4) U103.11(PGND) U103.17(GND#17) U104.3(GND) U105.4(GND#4) U105.11(PGND) U105.17(GND#17) U106.4(GND#4) U106.11(PGND) U106.17(GND#17) U107.C5(VSS#C5) U107.F7(VSS#F7) U107.K3(VSS#K3) U107.K8(VSS#K8) U108.A1(RG_A1) U108.A18(RG_A18) U108.B3(AVSS#B3) U108.B5(AVSS#B5) U108.B7(AVSS#B7) U108.B9(AVSS#B9) U108.B12(AVSS#B12) U108.B14(AVSS#B14) U108.B16(AVSS#B16) U108.C2(AVSS#C2) U108.C4(AVSS#C4) U108.C6(AVSS#C6) U108.C8(AVSS#C8) U108.C11(AVSS#C11) U108.C13(AVSS#C13) U108.C15(AVSS#C15) U108.C17(AVSS#C17) U108.D3(AVSS#D3) U108.D5(AVSS#D5) U108.D7(AVSS#D7) U108.D9(AVSS#D9) U108.D12(AVSS#D12) U108.D14(AVSS#D14) U108.D16(AVSS#D16) U108.D18(AVSS#D18) U108.E1(DC_MASTER_N) U108.E4(AVSS#E4) U108.E6(AVSS_PLL) U108.E11(AVSS#E11) U108.E13(AVSS#E13) U108.E15(AVSS#E15) U108.E17(AVSS#E17) U108.F6(AVSS#F6) U108.F8(AVSS#F8) U108.F10(AVSS#F10) U108.F12(AVSS#F12) U108.G5(AVSS#G5) U108.G7(AVSS#G7) U108.G9(AVSS#G9) U108.G11(AVSS#G11) U108.H4(MDIO_1P2_SELECT_N) U108.H6(AVSS#H6) U108.H8(AVSS#H8) U108.H10(AVSS#H10) U108.H12(AVSS#H12) U108.J5(VSS#J5) U108.J7(VSS#J7) U108.J9(VSS#J9) U108.J11(VSS#J11) U108.J13(VSS#J13) U108.K6(VSS#K6) U108.K8(VSS#K8) U108.K10(VSS#K10) U108.K12(VSS#K12) U108.L4(RG_L4) U108.L7(VSS#L7) U108.L9(VSS#L9) U108.L11(VSS#L11) U108.L13(VSS#L13) U108.M6(VSS#M6) U108.M8(VSS#M8) U108.M10(VSS#M10) U108.M12(VSS#M12) U108.N1(VSS_SRDS#N1) U108.N2(VSS_SRDS#N2) U108.N5(VSS#N5) U108.N7(VSS#N7) U108.N9(VSS#N9) U108.N11(VSS#N11) U108.N13(VSS#N13) U108.P3(VSS_SRDS#P3) U108.P6(VSS#P6) U108.P8(VSS#P8) U108.P10(VSS#P10) U108.P12(VSS#P12) U108.P17(VSS_SRDS#P17) U108.P18(VSS_SRDS#P18) U108.R1(VSS_SRDS#R1) U108.R2(VSS_SRDS#R2) U108.R4(VSS_SRDS#R4) U108.R6(VSS_SRDS#R6) U108.R7(VSS#R7) U108.R9(VSS#R9) U108.R11(VSS#R11) U108.R13(VSS#R13) U108.R14(VSS_SRDS#R14) U108.T3(VSS_SRDS#T3) U108.T5(VSS_SRDS#T5) U108.T7(VSS_SRDS#T7) U108.T9(VSS_SRDS#T9) U108.T11(VSS_SRDS#T11) U108.T13(VSS_SRDS#T13) U108.T15(VSS_SRDS#T15) U108.U1(VSS_SRDS#U1) U108.U5(VSS_SRDS#U5) U108.U9(VSS_SRDS#U9) U108.U11(VSS_SRDS#U11) U108.U16(VSS_SRDS#U16) U108.U18(VSS_SRDS#U18) U108.V5(VSS_SRDS#V5) U108.V9(VSS_SRDS#V9) U108.V11(VSS_SRDS#V11) U108.V16(VSS_SRDS#V16) U109.4(GND) U110.2(PD) U110.5(GND#5) U110.11(GND#11) U110.20(GND#20) U110.21(EPAD) U111.7(GND) U112.10(VEE#10) U112.15(VEE#15) U113.10(VEE#10) U113.15(VEE#15) X1.2(GND) X2.2(GND) X3.2(GND) X5.2(GND) Y1.2 Y1.4 Y2.2 Y2.4 Y4.2 Y4.4 Y5.2 Y5.4 Y6.2 Y6.3 Y7.2 Y7.4 Y8.2 Y8.4 Z105.1 Z105.2 Z105.3 Z105.4 Z105.5 Z105.6 Z105.7 Z105.8 Z106.1 Z106.2 Z106.3 Z106.4 Z106.5 Z106.6 Z106.7 Z106.8 Z109.1 Z109.2 Z109.3 Z109.4 Z109.5 Z109.6 Z109.7 Z109.8 Z110.1 Z110.2 Z110.3 Z110.4 Z110.5 Z110.6 Z110.7 Z110.8 Z111.1 Z111.2 Z111.3 Z111.4 Z111.5 Z111.6 Z111.7 Z111.8 Z112.1 Z112.2 Z112.3 Z112.4 Z112.5 Z112.6 Z112.7 Z112.8
SVDD: C242.1 C243.1 C244.1 C245.1 C246.1 C247.1 C248.1 C1013.1 C1027.1 R139.1 U1.W15(S1VDD1) U1.W16(S1VDD2) U1.W17(S1VDD3) U1.W18(S1VDD4) U1.W19(S1VDD5) U1.W20(S1VDD6) U1.Y13(S1VDD7)
VDD_EN: U65.N5(IO_B1_N5) U95.5(EN)
VDD_EN_N: R919.1 U65.N12(IO_B1_N12)
VDD_SD: C38.1 C39.1 J2.4(VDD) J53.2 R954.1
VDD_SD_SENSE: Q50.3(C) R955.2 U65.D3(IO_B1_D3)
ASLEEP: R101.1 U1.B2(ASLEEP) U21.2(A)
BOOT_FLASH_SEL: R502.2 SW3.4 U65.F15(IO_B2_F15)
CFG_VBANK0: R504.2 SW3.5 U10.2(I1) U65.J16(IO_B2_J16)
CFG_VBANK1: R506.2 SW3.6 U9.2(I1) U65.H16(IO_B2_H16)
CFG_VBANK2: R508.2 SW3.7 U8.2(I1) U65.J15(IO_B2_J15)
CKE_ISO_EN: R830.1 U65.L4(IO_B1_L4)
CKSTP_OUT_N: R102.1 U1.F18(C\K\S\T\P\_\O\U\T\) U22.2(A)
COP_CKSTP_OUT_N: J3.15 U22.4(O)
COP_HRESET_N: J3.13 R107.2 U65.G1(IO_B1_G1)
COP_SRESET_N: J3.11 R110.2 U65.H1(IO_B1_H1)
COP_TCK: J3.7 R113.2 U20.3(A3)
COP_TDI: J3.3 R111.2 U20.1(A1)
COP_TDO: J3.1 U20.2(A2)
COP_TMS: J3.9 R114.2 U20.4(A4)
COP_TRST_N: J3.4 R109.1 U65.J1(IO_B1_J1)
CPLD_INT_N: R69.1 U1.F7(IRQ0) U65.E13(IO_B2_E13)
CPLD_REFCLK: R495.2 U65.H5(GCLK0P)
CPLD_TCK: J26.1 R496.2 U65.P3(TCK)
CPLD_TDI: J26.9 R498.2 U65.L6(TDI)
CPLD_TDO: J26.3 U65.M5(TDO)
CPLD_TMS: J26.5 R497.2 U65.N4(TMS)
DDR_DQ0: J1.3(DQ0) U1.C21(D1_MDQ00)
DDR_DQ1: J1.4(DQ1) U1.A22(D1_MDQ01)
DDR_DQ2: J1.9(DQ2) U1.A26(D1_MDQ02)
DDR_DQ3: J1.10(DQ3) U1.B26(D1_MDQ03)
DDR_DQ4: J1.122(DQ4) U1.B21(D1_MDQ04)
DDR_DQ5: J1.123(DQ5) U1.A21(D1_MDQ05)
DDR_DQ6: J1.128(DQ6) U1.B24(D1_MDQ06)
DDR_DQ7: J1.129(DQ7) U1.A25(D1_MDQ07)
DDR_DQ8: J1.12(DQ8) U1.C23(D1_MDQ08)
DDR_DQ9: J1.13(DQ9) U1.C24(D1_MDQ09)
DDR_DQ10: J1.18(DQ10) U1.F25(D1_MDQ10)
DDR_DQ11: J1.19(DQ11) U1.F26(D1_MDQ11)
DDR_DQ12: J1.131(DQ12) U1.D22(D1_MDQ12)
DDR_DQ13: J1.132(DQ13) U1.D23(D1_MDQ13)
DDR_DQ14: J1.137(DQ14) U1.B27(D1_MDQ14)
DDR_DQ15: J1.138(DQ15) U1.E25(D1_MDQ15)
DDR_DQ16: J1.21(DQ16) U1.E23(D1_MDQ16)
DDR_DQ17: J1.22(DQ17) U1.E24(D1_MDQ17)
DDR_DQ18: J1.27(DQ18) U1.J23(D1_MDQ18)
DDR_DQ19: J1.28(DQ19) U1.K23(D1_MDQ19)
DDR_DQ20: J1.140(DQ20) U1.F22(D1_MDQ20)
DDR_DQ21: J1.141(DQ21) U1.H22(D1_MDQ21)
DDR_DQ22: J1.146(DQ22) U1.H23(D1_MDQ22)
DDR_DQ23: J1.147(DQ23) U1.J24(D1_MDQ23)
DDR_DQ24: J1.30(DQ24) U1.H26(D1_MDQ24)
DDR_DQ25: J1.31(DQ25) U1.J25(D1_MDQ25)
DDR_DQ26: J1.36(DQ26) U1.P26(D1_MDQ26)
DDR_DQ27: J1.37(DQ27) U1.N25(D1_MDQ27)
DDR_DQ28: J1.149(DQ28) U1.G25(D1_MDQ28)
DDR_DQ29: J1.150(DQ29) U1.H25(D1_MDQ29)
DDR_DQ30: J1.155(DQ30) U1.M26(D1_MDQ30)
DDR_DQ31: J1.156(DQ31) U1.M25(D1_MDQ31)
DDR_DQ32: J1.81(DQ32) U1.T25(D1_MDQ32)
DDR_DQ33: J1.82(DQ33) U1.U25(D1_MDQ33)
DDR_DQ34: J1.87(DQ34) U1.AA26(D1_MDQ34)
DDR_DQ35: J1.88(DQ35) U1.AA25(D1_MDQ35)
DDR_DQ36: J1.200(DQ36) U1.P25(D1_MDQ36)
DDR_DQ37: J1.201(DQ37) U1.R25(D1_MDQ37)
DDR_DQ38: J1.206(DQ38) U1.W26(D1_MDQ38)
DDR_DQ39: J1.207(DQ39) U1.Y25(D1_MDQ39)
DDR_DQ40: J1.90(DQ40) U1.V24(D1_MDQ40)
DDR_DQ41: J1.91(DQ41) U1.W23(D1_MDQ41)
DDR_DQ42: J1.96(DQ42) U1.AA22(D1_MDQ42)
DDR_DQ43: J1.97(DQ43) U1.AC22(D1_MDQ43)
DDR_DQ44: J1.209(DQ44) U1.W22(D1_MDQ44)
DDR_DQ45: J1.210(DQ45) U1.V23(D1_MDQ45)
DDR_DQ46: J1.215(DQ46) U1.AB24(D1_MDQ46)
DDR_DQ47: J1.216(DQ47) U1.AB23(D1_MDQ47)
DDR_DQ48: J1.99(DQ48) U1.AD26(D1_MDQ48)
DDR_DQ49: J1.100(DQ49) U1.AD25(D1_MDQ49)
DDR_DQ50: J1.105(DQ50) U1.AD23(D1_MDQ50)
DDR_DQ51: J1.106(DQ51) U1.AE22(D1_MDQ51)
DDR_DQ52: J1.218(DQ52) U1.AB25(D1_MDQ52)
DDR_DQ53: J1.219(DQ53) U1.AC25(D1_MDQ53)
DDR_DQ54: J1.224(DQ54) U1.AC23(D1_MDQ54)
DDR_DQ55: J1.225(DQ55) U1.AE23(D1_MDQ55)
DDR_DQ56: J1.108(DQ56) U1.AG25(D1_MDQ56)
DDR_DQ57: J1.109(DQ57) U1.AH25(D1_MDQ57)
DDR_DQ58: J1.114(DQ58) U1.AH22(D1_MDQ58)
DDR_DQ59: J1.115(DQ59) U1.AF22(D1_MDQ59)
DDR_DQ60: J1.227(DQ60) U1.AF26(D1_MDQ60)
DDR_DQ61: J1.228(DQ61) U1.AH26(D1_MDQ61)
DDR_DQ62: J1.233(DQ62) U1.AH23(D1_MDQ62)
DDR_DQ63: J1.234(DQ63) U1.AF23(D1_MDQ63)
DDR_ECC0: J1.39(CB0) U1.L24(D1_MECC0)
DDR_ECC1: J1.40(CB1) U1.N23(D1_MECC1)
DDR_ECC2: J1.45(CB2) U1.T23(D1_MECC2)
DDR_ECC3: J1.46(CB3) U1.U23(D1_MECC3)
DDR_ECC4: J1.158(CB4) U1.L23(D1_MECC4)
DDR_ECC5: J1.159(CB5) U1.M23(D1_MECC5)
DDR_ECC6: J1.164(CB6) U1.R24(D1_MECC6)
DDR_ECC7: J1.165(CB7) U1.T24(D1_MECC7)
DDR_MA0: J1.188(A0) U1.V28(D1_MA00)
DDR_MA1: J1.181(A1) U1.N28(D1_MA01)
DDR_MA2: J1.61(A2) U1.N27(D1_MA02)
DDR_MA3: J1.180(A3) U1.M28(D1_MA03)
DDR_MA4: J1.59(A4) U1.L27(D1_MA04)
DDR_MA5: J1.58(A5) U1.L28(D1_MA05)
DDR_MA6: J1.178(A6) U1.K28(D1_MA06)
DDR_MA7: J1.56(A7) U1.J28(D1_MA07)
DDR_MA8: J1.177(A8) U1.J27(D1_MA08)
DDR_MA9: J1.175(A9) U1.G27(D1_MA09)
DDR_MA10: J1.70(A10/AP) U1.Y27(D1_MA10)
DDR_MA11: J1.55(A11) U1.H28(D1_MA11)
DDR_MA12: J1.174(A12/B\C\) U1.G28(D1_MA12)
DDR_MA13: J1.196(A13) U1.AE28(D1_MA13)
DDR_MA14: J1.172(A14) U1.E27(D1_MA14)
DDR_MA15: J1.171(A15) U1.D28(D1_MA15)
DDR_MAPAR_ERR: J1.53(E\R\R\O\U\T\/NC) R4.2 U1.F28(D\1\_\M\A\P\A\R\_\E\R\R\)
DDR_MAPAR_OUT: J1.68(PARIN/NC) U1.V27(D1_MAPAR_OUT)
DDR_MBA0: J1.71(BA0) U1.Y28(D1_MBA0)
DDR_MBA1: J1.190(BA1) U1.W28(D1_MBA1)
DDR_MBA2: J1.52(BA2) U1.E28(D1_MBA2)
DDR_MCAS_N: J1.74(C\A\S\) U1.AC28(D\1\_\M\C\A\S\)
DDR_MCK0_N: J1.185(C\K\0\) U1.T28(D\1\_\M\C\K\0\)
DDR_MCK0_P: J1.184(CK0) U1.T27(D1_MCK0)
DDR_MCK1_N: J1.64(C\K\1\) U1.R28(D\1\_\M\C\K\1\)
DDR_MCK1_P: J1.63(CK1) U1.R27(D1_MCK1)
DDR_MCKE0: J1.50(CKE0) Q37.3(D) U1.C27(D1_MCKE0)
DDR_MCKE1: J1.169(CKE1) Q38.3(D) U1.C28(D1_MCKE1)
DDR_MCS0_N: J1.193(S\0\) U1.AB28(D\1\_\M\C\S\0\)
DDR_MCS1_N: J1.76(S\1\) U1.AC27(D\1\_\M\C\S\1\)
DDR_MCS2_N: J1.79(S\2\/NC) U1.AG27(D\1\_\M\C\S\2\)
DDR_MCS3_N: J1.198(S\3\/NC) U1.AF28(D\1\_\M\C\S\3\)
DDR_MDM0: J1.125(DM0/DQS9) U1.B22(D1_MDM0)
DDR_MDM1: J1.134(DM1/DQS10) U1.C25(D1_MDM1)
DDR_MDM2: J1.143(DM2/DQS11) U1.F23(D1_MDM2)
DDR_MDM3: J1.152(DM3/DQS12) U1.K26(D1_MDM3)
DDR_MDM4: J1.203(DM4/DQS13) U1.U26(D1_MDM4)
DDR_MDM5: J1.212(DM5/DQS14) U1.Y24(D1_MDM5)
DDR_MDM6: J1.221(DM6/DQS15) U1.AD24(D1_MDM6)
DDR_MDM7: J1.230(DM7/DQS16) U1.AF24(D1_MDM7)
DDR_MDM8: J1.161(DM8/DQS17) U1.N24(D1_MDM8)
DDR_MDQS0_N: J1.6(D\Q\S\0\) U1.A23(D\1\_\M\D\Q\S\0\)
DDR_MDQS0_P: J1.7(DQS0) U1.A24(D1_MDQS0)
DDR_MDQS1_N: J1.15(D\Q\S\1\) U1.D25(D\1\_\M\D\Q\S\1\)
DDR_MDQS1_P: J1.16(DQS1) U1.D26(D1_MDQS1)
DDR_MDQS2_N: J1.24(D\Q\S\2\) U1.G23(D\1\_\M\D\Q\S\2\)
DDR_MDQS2_P: J1.25(DQS2) U1.G24(D1_MDQS2)
DDR_MDQS3_N: J1.33(D\Q\S\3\) U1.K25(D\1\_\M\D\Q\S\3\)
DDR_MDQS3_P: J1.34(DQS3) U1.L25(D1_MDQS3)
DDR_MDQS4_N: J1.84(D\Q\S\4\) U1.V25(D\1\_\M\D\Q\S\4\)
DDR_MDQS4_P: J1.85(DQS4) U1.W25(D1_MDQS4)
DDR_MDQS5_N: J1.93(D\Q\S\5\) U1.Y23(D\1\_\M\D\Q\S\5\)
DDR_MDQS5_P: J1.94(DQS5) U1.AA23(D1_MDQS5)
DDR_MDQS6_N: J1.102(D\Q\S\6\) U1.AF25(D\1\_\M\D\Q\S\6\)
DDR_MDQS6_P: J1.103(DQS6) U1.AE25(D1_MDQS6)
DDR_MDQS7_N: J1.111(D\Q\S\7\) U1.AH24(D\1\_\M\D\Q\S\7\)
DDR_MDQS7_P: J1.112(DQS7) U1.AG24(D1_MDQS7)
DDR_MDQS8_N: J1.42(D\Q\S\8\) U1.P23(D\1\_\M\D\Q\S\8\)
DDR_MDQS8_P: J1.43(DQS8) U1.R23(D1_MDQS8)
DDR_MODT0: J1.195(ODT0) U1.AD28(D1_MODT0)
DDR_MODT1: J1.77(ODT1) U1.AE27(D1_MODT1)
DDR_MRAS_N: J1.192(R\A\S\) U1.AA28(D\1\_\M\R\A\S\)
DDR_MWE_N: J1.73(W\E\) U1.AB27(D\1\_\M\W\E\)
DDR_REFCLK: R517.2 R518.2 U1.J21(DDRCLK)
DDR_RST_N: J1.168(R\E\S\E\T\) R2.2 U65.A2(IO_B2_A2)
DDRPWR_EN: U65.P4(IO_B1_P4) U81.7(EN)
DDRPWR_EN_N: R785.1 R948.1 U65.R4(IO_B1_R4)
DIFSYSCLK_OE_N: R844.2 U65.N15(IO_B2_N15) U97.38(O\E\5\)
EARTH: C302.2 C310.2 C334.2 C336.2 C342.2 C1205.2 C1206.2 C1373.2 C1374.2 J13.17 J13.18 J13.19 J13.20 J13.21 J13.22 J14.25 J14.26 J14.27 J14.28 J41.9 J41.10 J41.11 J41.12 J50.20 J50.21 J56.20 J56.21 Z107.1 Z107.2 Z107.3 Z107.4 Z107.5 Z107.6 Z107.7 Z107.8 Z108.1 Z108.2 Z108.3 Z108.4 Z108.5 Z108.6 Z108.7 Z108.8
EC1_GTXCLK: R127.1 U49.22(TXC)
EC1_INT_N: R71.1 R250.2 U1.AB4(IRQ2)
EC1_LED0: R247.1 R262.1 U49.34(LED0/PHY_AD0)
EC1_LED1: R248.1 R263.1 U49.35(LED1/PHY_AD1)
EC1_MDI0_N: T2.11 U49.2(MDI-[0]) U50.1
EC1_MDI0_P: T2.12 U49.1(MDI+[0]) U50.3
EC1_MDI1_N: T2.8 U49.5(MDI-[1]) U50.6
EC1_MDI1_P: T2.9 U49.4(MDI+[1]) U50.4
EC1_MDI2_N: T2.5 U49.8(MDI-[2]) U51.1
EC1_MDI2_P: T2.6 U49.7(MDI+[2]) U51.3
EC1_MDI3_N: T2.2 U49.11(MDI-[3]) U51.6
EC1_MDI3_P: T2.3 U49.10(MDI+[3]) U51.4
EC1_MDX0_N: J14.B2 T2.14
EC1_MDX0_P: J14.B1 T2.13
EC1_MDX1_N: J14.B6 T2.17
EC1_MDX1_P: J14.B3 T2.16
EC1_MDX2_N: J14.B5 T2.20
EC1_MDX2_P: J14.B4 T2.19
EC1_MDX3_N: J14.B8 T2.23
EC1_MDX3_P: J14.B7 T2.22
EC1_PME_N: R72.1 R251.2 U1.AC5(IRQ3) U65.P13(IO_B1_P13)
EC1_REFCLK: R246.2 U1.AG3(EC1_GTX_CLK125)
EC1_RST_N: R249.1 R252.2 U65.H3(IO_B1_H3)
EC1_RXCLK: R238.1 U1.AD1(EC1_RX_CLK)
EC1_RXCTL: R245.1 R261.1 U1.AG2(EC1_RX_DV)
EC1_RXD0: R239.1 R257.1 U1.AF2(EC1_RXD0)
EC1_RXD1: R242.1 R258.1 U1.AF1(EC1_RXD1)
EC1_RXD2: R243.1 R259.1 U1.AE1(EC1_RXD2)
EC1_RXD3: R244.1 R260.1 U1.AD2(EC1_RXD3)
EC1_RXDLY: R264.1 U49.32(LED2/RXDLY)
EC1_TXCTL: R125.1 U49.27(TXCTL)
EC1_TXD0: R115.1 U49.23(TXD0)
EC1_TXD1: R116.1 U49.24(TXD1)
EC1_TXD2: R119.1 U49.25(TXD2)
EC1_TXD3: R121.1 U49.26(TXD3)
EC2_GTXCLK: R128.2 U46.22(TXC)
EC2_INT_N: R73.1 R221.2 U1.L4(IRQ4)
EC2_LED0: R218.1 R233.1 U46.34(LED0/PHY_AD0)
EC2_LED1: R219.1 R234.1 U46.35(LED1/PHY_AD1)
EC2_MDI0_N: T1.11 U46.2(MDI-[0]) U47.1
EC2_MDI0_P: T1.12 U46.1(MDI+[0]) U47.3
EC2_MDI1_N: T1.8 U46.5(MDI-[1]) U47.6
EC2_MDI1_P: T1.9 U46.4(MDI+[1]) U47.4
EC2_MDI2_N: T1.5 U46.8(MDI-[2]) U48.1
EC2_MDI2_P: T1.6 U46.7(MDI+[2]) U48.3
EC2_MDI3_N: T1.2 U46.11(MDI-[3]) U48.6
EC2_MDI3_P: T1.3 U46.10(MDI+[3]) U48.4
EC2_MDX0_N: J14.A2 T1.14
EC2_MDX0_P: J14.A1 T1.13
EC2_MDX1_N: J14.A6 T1.17
EC2_MDX1_P: J14.A3 T1.16
EC2_MDX2_N: J14.A5 T1.20
EC2_MDX2_P: J14.A4 T1.19
EC2_MDX3_N: J14.A8 T1.23
EC2_MDX3_P: J14.A7 T1.22
EC2_PME_N: R74.1 R222.2 U1.U3(IRQ5)
EC2_REFCLK: R217.2 U1.AE5(TSEC_1588_TRIG_IN2)
EC2_RST_N: R220.1 R823.2 U65.J2(IO_B1_J2)
EC2_RXCLK: R211.1 U1.AF5(TSEC_1588_ALARM_OUT1)
EC2_RXCTL: R216.1 R232.1 U1.AF8(GPIO3_24)
EC2_RXD0: R209.1 R228.1 U1.AE8(GPIO3_25)
EC2_RXD1: R213.1 R229.1 U1.AH7(GPIO3_28)
EC2_RXD2: R214.1 R230.1 U1.AE6(TSEC_1588_PULSE_OUT1)
EC2_RXD3: R215.1 R231.1 U1.AH6(GPIO3_27)
EC2_RXDLY: R235.1 U46.32(LED2/RXDLY)
EC2_TXCTL: R126.2 U46.27(TXCTL)
EC2_TXD0: R117.2 U46.23(TXD0)
EC2_TXD1: R118.2 U46.24(TXD1)
EC2_TXD2: R120.2 U46.25(TXD2)
EC2_TXD3: R122.2 U46.26(TXD3)
EMI1_MDC: U23.2(B) U46.30(MDC)
EMI1_MDC_SLP: R129.1 R132.2 U23.1(A) U49.30(MDC)
EMI1_MDIO: U24.2(B) U46.31(MDIO)
EMI1_MDIO_SLP: R131.2 U1.AH4(EMI1_MDIO) U24.1(A) U49.31(MDIO)
EMI2_MDC: J60.3 R130.2 R134.2 U101.J18(MDC) U108.J18(MDC)
EMI2_MDIO: J60.2 R133.2 U1.V6(EMI2_MDIO) U101.L18(MDIO) U108.L18(MDIO)
ETH_REFCLK1_N: C1384.1 R543.2 U68.4(Q\0\)
ETH_REFCLK1_P: C1382.1 R544.2 U68.3(Q0)
ETH_REFCLK2_N: C1389.1 R541.2 U68.18(Q\1\)
ETH_REFCLK2_P: C1387.1 R542.2 U68.19(Q1)
ETH_REFCLK_SEL: U65.T12(IO_B1_T12) U68.9(F_SEL0)
EVDD: C185.1 C1282.1 C1283.1 C1284.1 J57.1 Q33.2(S) Q34.2(S) R60.2 R62.2 R63.2 R64.2 R67.2 R68.2 R815.2 U1.L8(EVDD)
EVDD_SEL: R820.1 U65.F1(IO_B1_F1)
EVT_BRD_ISO: R81.1 U1.A3(I\R\Q\_\O\U\T\) U65.K16(IO_B2_K16)
EVT_PWR_EN: R85.1 U1.C1(E\V\T\2\) U65.L15(IO_B2_L15)
EVT_PWR_OK: R813.1 U1.C2(E\V\T\3\) U65.L16(IO_B2_L16)
FAN_PWM: Q27.1(G) U65.E1(IO_B1_E1)
HRESET_N: R96.2 U1.E8(H\R\E\S\E\T\) U65.D14(IO_B2_D14)
I2C1_SCL: Q1.2(S) R89.1 U1.W1(IIC1_SCL) U44.6(SCL)
I2C1_SCL_SLP: J1.118(SCL) Q1.3(D) R91.1 U45.8(SCLK) U97.9(SCLK_3.3) U100.6(SCL) U111.5(SCL)
I2C1_SDA: Q2.2(S) R88.1 U1.V1(IIC1_SDA) U44.5(SDA)
I2C1_SDA_SLP: J1.238(SDA) Q2.3(D) R90.1 U45.7(SDATA) U97.10(SDATA_3.3) U100.5(SDA) U111.4(SDA)
I2C2_MPEX1_SCL: J19.30(SMB_CLK) R398.1 U19.5(SC0)
I2C2_MPEX1_SDA: J19.32(SMB_DATA) R404.1 U19.4(SD0)
I2C2_MPEX2_SCL: J20.30(SMB_CLK) R409.1 U19.7(SC1)
I2C2_MPEX2_SDA: J20.32(SMB_DATA) R410.1 U19.6(SD1)
I2C2_PEX_SCL: J18.B5(SMCLK) R406.1 U19.12(SC3)
I2C2_PEX_SDA: J18.B6(SMDAT) R407.1 U19.11(SD3)
IFC_A5: R14.2 U10.1(I0)
IFC_A6: R15.2 U9.1(I0)
IFC_A7: R16.2 U8.1(I0)
IFC_A8: R18.2 U4.2(A22)
IFC_A9: R20.2 U4.15(A21)
IFC_A10: R22.2 U4.12(A20)
IFC_A11: R24.2 U4.11(A19)
IFC_A12: R26.2 U4.18(A18)
IFC_A13: R28.2 U4.19(A17)
IFC_A14: R30.2 U4.54(A16)
IFC_A15: R32.2 U4.3(A15)
IFC_A16: R797.2 SW2.5 U1.C5(IFC_A16) U4.4(A14) U65.D16(IO_B2_D16)
IFC_A17: R798.2 SW2.6 U1.C6(IFC_A17) U4.5(A13) U65.E15(IO_B2_E15)
IFC_A18: R799.2 SW2.3 U1.D7(IFC_A18) U4.6(A12) U65.F14(IO_B2_F14)
IFC_A19: R800.2 SW2.4 U1.C7(IFC_A19) U4.7(A11) U65.F13(IO_B2_F13)
IFC_A20: R13.2 R864.2 U1.D8(IFC_A20) U4.8(A10)
IFC_A21: SW2.7 U1.C8(IFC_A21) U4.9(A9) U65.C10(IO_B2_C10)
IFC_A22: U1.D9(IFC_A22) U4.10(A8)
IFC_A23: U1.C9(IFC_A23) U4.20(A7)
IFC_A24: U1.D10(IFC_A24) U4.21(A6)
IFC_A25: U1.C10(IFC_A25) U4.22(A5)
IFC_A26: U1.E11(IFC_A26) U4.23(A4)
IFC_A27: U1.C11(IFC_A27) U4.24(A3) U65.C13(IO_B2_C13)
IFC_A28: U1.D11(IFC_A28) U4.25(A2) U65.C12(IO_B2_C12)
IFC_A29: U1.C12(IFC_A29) U4.26(A1) U65.C11(IO_B2_C11)
IFC_A30: U1.D12(IFC_A30) U4.31(A0) U65.D12(IO_B2_D12)
IFC_A31: U1.E12(IFC_A31) U65.A5(IO_B2_A5)
IFC_AD0: U1.A4(IFC_AD00) U4.51(DQ15/A-1) U65.A13(IO_B2_A13) U107.J8(I/O7)
IFC_AD1: U1.B5(IFC_AD01) U4.49(DQ14) U65.B13(IO_B2_B13) U107.K7(I/O6)
IFC_AD2: U1.A5(IFC_AD02) U4.47(DQ13) U65.B12(IO_B2_B12) U107.J7(I/O5)
IFC_AD3: U1.B6(IFC_AD03) U4.45(DQ12) U65.A12(IO_B2_A12) U107.K6(I/O4)
IFC_AD4: U1.A6(IFC_AD04) U4.42(DQ11) U65.A11(IO_B2_A11) U107.K5(I/O3)
IFC_AD5: U1.A7(IFC_AD05) U2.47(1D1) U4.40(DQ10) U65.B11(IO_B2_B11) U107.K4(I/O2)
IFC_AD6: U1.B8(IFC_AD06) U2.46(1D2) U4.38(DQ9) U65.B10(IO_B2_B10) U107.J4(I/O1)
IFC_AD7: U1.A8(IFC_AD07) U2.44(1D3) U4.36(DQ8) U65.A10(IO_B2_A10) U107.H4(I/O0)
IFC_AD8: SW1.1 U1.B9(IFC_AD08) U2.43(1D4) U4.50(DQ7) U65.A6(IO_B2_A6)
IFC_AD9: SW1.2 U1.A9(IFC_AD09) U2.41(1D5) U4.48(DQ6) U65.B7(IO_B2_B7)
IFC_AD10: SW1.3 U1.A10(IFC_AD10) U2.40(1D6) U4.46(DQ5) U65.A7(IO_B2_A7)
IFC_AD11: SW1.4 U1.B11(IFC_AD11) U2.38(1D7) U4.44(DQ4) U65.B8(IO_B2_B8)
IFC_AD12: SW1.5 U1.A11(IFC_AD12) U2.37(1D8) U4.41(DQ3) U65.A8(IO_B2_A8)
IFC_AD13: SW1.6 U1.B12(IFC_AD13) U2.36(2D1) U4.39(DQ2) U65.C8(IO_B2_C8)
IFC_AD14: SW1.7 U1.A12(IFC_AD14) U2.35(2D2) U4.37(DQ1) U65.A9(IO_B2_A9)
IFC_AD15: SW1.8 U1.A13(IFC_AD15) U2.33(2D3) U4.35(DQ0) U65.B9(IO_B2_B9)
IFC_AVD: R801.1 SW2.8 U1.D17(IFC_AVD) U2.25(LE2) U2.48(LE1) U65.C9(IO_B2_C9) U107.C4(ALE)
IFC_CLE: SW2.1 U1.F16(IFC_CLE) U65.D15(IO_B2_D15) U107.D5(CLE)
IFC_CLK: R12.2 U65.J12(GCLK2P)
IFC_CLK_R: R12.1 U1.A17(IFC_CLK0)
IFC_CS0_N: R11.1 U1.C13(I\F\C\_\C\S\0\) U65.B6(IO_B2_B6)
IFC_CS1_N: R10.1 U1.E15(I\F\C\_\C\S\1\) U65.B5(IO_B2_B5)
IFC_CS2_N: R9.1 U1.D16(I\F\C\_\C\S\2\) U65.A4(IO_B2_A4)
IFC_NDWE_N: U1.D14(IFC_NDDDR_CLK) U107.C7(W\E\)
IFC_OE_N: R803.1 SW3.2 U1.D15(I\F\C\_\O\E\) U4.34(O\E\) U65.G15(IO_B2_G15) U107.D4(R\E\)
IFC_RB0_N: R7.1 U1.B15(I\F\C\_\R\B\0\) U65.A15(IO_B2_A15)
IFC_RB1_N: R6.1 U1.A15(I\F\C\_\R\B\1\) U65.B16(IO_B2_B16)
IFC_TE: SW2.2 U1.B14(IFC_TE) U65.D11(IO_B2_D11)
IFC_VA5: U4.55(A25) U10.4(O)
IFC_VA6: U4.56(A24) U9.4(O)
IFC_VA7: U4.1(A23) U8.4(O)
IFC_WE_N: R804.1 SW3.1 U1.D13(I\F\C\_\W\E\0\) U4.13(W\E\) U65.H15(IO_B2_H15)
IFC_WP_N: R802.1 SW3.3 U1.F17(I\F\C\_\W\P\0\) U65.F16(IO_B2_F16) U107.C3(W\P\)
INA_VCORE_N: C1378.2 R982.1 U111.9(VIN-)
INA_VCORE_P: C1378.1 R981.1 U111.10(VIN+)
IO_B1: U65.B1(IO_B2_B1)
IO_B3: U65.B3(IO_B2_B3)
IO_B14: U65.B14(IO_B2_B14)
IO_C4: U65.C4(IO_B2_C4)
IO_C5: U65.C5(IO_B2_C5)
IO_C6: U65.C6(IO_B2_C6)
IO_D4: U65.D4(IO_B2_D4)
IO_D5: U65.D5(IO_B2_D5)
IO_E2: U65.E2(IO_B1_E2)
IO_E3: U65.E3(IO_B1_E3)
IO_E4: U65.E4(IO_B1_E4)
IO_F2: U65.F2(IO_B1_F2)
IO_F3: U65.F3(IO_B1_F3)
IO_G2: U65.G2(IO_B1_G2)
IO_G3: U65.G3(IO_B1_G3)
IO_G14: U65.G14(IO_B2_G14)
IO_H2: U65.H2(IO_B1_H2)
IO_H14: U65.H14(IO_B2_H14)
IO_J3: U65.J3(IO_B1_J3)
IO_J14: U65.J14(IO_B2_J14)
IO_K2: U65.K2(IO_B1_K2)
IO_K3: U65.K3(IO_B1_K3)
IO_K14: U65.K14(IO_B2_K14)
IO_L1: U65.L1(IO_B1_L1)
IO_L2: U65.L2(IO_B1_L2)
IO_L3: U65.L3(IO_B1_L3)
IO_L13: U65.L13(IO_B2_L13)
IO_L14: U65.L14(IO_B2_L14)
IO_M1: U65.M1(IO_B1_M1)
IO_M3: U65.M3(IO_B1_M3)
IO_M13: U65.M13(IO_B2_M13)
IO_M14: U65.M14(IO_B2_M14)
IO_N2: U65.N2(IO_B1_N2)
IO_N3: U65.N3(IO_B1_N3)
IO_N13: U65.N13(IO_B2_N13)
IO_P2: U65.P2(IO_B1_P2)
IO_P8: U65.P8(IO_B1_P8)
IO_P14: U65.P14(IO_B2_P14)
IO_R1: U65.R1(IO_B1_R1)
IO_R6: U65.R6(IO_B1_R6)
IO_R7: U65.R7(IO_B1_R7)
IO_R9: U65.R9(IO_B1_R9)
IO_R10: U65.R10(IO_B1_R10)
IO_R16: U65.R16(IO_B1_R16)
IO_T4: U65.T4(IO_B1_T4)
IO_T5: U65.T5(IO_B1_T5)
IO_T6: U65.T6(IO_B1_T6)
IO_T7: U65.T7(IO_B1_T7)
IO_T8: U65.T8(IO_B1_T8)
IO_T9: U65.T9(IO_B1_T9)
IO_T10: J61.1 R1016.1 U65.T10(IO_B1_T10)
IO_T11: U65.T11(IO_B1_T11)
IO_T15: U65.T15(IO_B1_T15)
IOPWR_EN: C938.2 C956.2 C1231.2 C1235.2 R670.1 R732.2 R750.2 R925.2 R927.2 U65.R8(IO_B1_R8) U86.16(EN) U88.16(EN) U105.16(EN) U106.16(EN)
IOPWR_EN_N: R666.1 R681.1 R682.1 U65.P10(IO_B1_P10)
JTAG_TCK: U1.E18(TCK) U20.10(B3)
JTAG_TDI: U1.A18(TDI) U20.12(B1)
JTAG_TDO: U1.C18(TDO) U20.11(B2)
JTAG_TMS: U1.B18(TMS) U20.9(B4)
JTAG_TRST_N: U1.D19(T\R\S\T\) U65.B4(IO_B2_B4)
LED_STATUS: R702.1 U65.D2(IO_B1_D2)
MPEX1_REFCLK_N: J19.13(REFCLK+) R526.2 R528.2
MPEX1_REFCLK_P: J19.11(REFCLK-) R524.2 R525.2
MPEX1_RST_N: J19.22(P\E\R\S\T\) U65.T2(IO_B1_T2)
MPEX1_RX_N: C1266.2 U1.AG19(SD1_RX2_N)
MPEX1_RX_P: C1265.2 U1.AH19(SD1_RX2_P)
MPEX1_TX_N: C599.2 U1.AE19(SD1_TX2_N)
MPEX1_TX_P: C598.2 U1.AD19(SD1_TX2_P)
MPEX2_REFCLK_N: J20.13(REFCLK+) R532.2 R534.1
MPEX2_REFCLK_P: J20.11(REFCLK-) R527.1 R530.2
MPEX2_RST_N: J20.22(P\E\R\S\T\) U65.R3(IO_B1_R3)
MPEX2_RX_N: C1270.2 U1.AG20(SD1_RX3_N)
MPEX2_RX_P: C1269.2 U1.AH20(SD1_RX3_P)
MPEX2_TX_N: C631.2 U1.AE20(SD1_TX3_N)
MPEX2_TX_P: C630.2 U1.AD20(SD1_TX3_P)
MVREF: C21.1 C22.1 Q48.2(S) R945.2 U1.F20(D1_MVREF)
MVREF_SLP: C18.1 C19.1 C883.1 J1.1(VREFDQ) J1.67(VREFCA) Q48.3(D) U81.6(REFOUT)
NAND_CS_N: R952.1 U65.G16(IO_B2_G16) U107.C6(C\E\)
NAND_RB_N: R953.1 U65.C7(IO_B2_C7) U107.C8(R/B\)
NOR_CS_N: R43.1 U4.32(C\E\) U65.D13(IO_B2_D13)
NOR_RB_N: R44.1 U4.17(RDY/B\U\S\Y\) U65.E14(IO_B2_E14)
NOR_RST_N: R47.1 U4.14(R\E\S\E\T\) U65.C14(IO_B2_C14)
OVDD_OSC_DDR: C731.1 C732.1 FB50.2 X5.4(VDD)
OVDD_OSC_SYS: C722.1 C723.1 FB48.2 X3.4(VDD)
PCIE_REFCLK1_N: C1386.1 R1012.2 R1013.1
PCIE_REFCLK1_P: C1388.1 R1014.2 R1015.2
PCIE_REFCLK2_N: C1383.1 R537.2 R538.2
PCIE_REFCLK2_P: C1385.1 R535.2 R536.2
PEX_PRS_N: J18.B17(P\R\S\N\T\2\_X1) R405.1 U65.P5(IO_B1_P5)
PEX_REFCLK_N: J18.A14(REFCLK-) R521.2 R523.1
PEX_REFCLK_P: J18.A13(REFCLK+) R519.1 R520.2
PEX_RST_N: J18.A11(P\E\R\S\T\) U65.R5(IO_B1_R5)
PEX_RX_N: J18.A17(PERN0) U110.17(B1+)
PEX_RX_P: J18.A16(PERP0) U110.16(B1-)
PEX_SEL_N: R979.2 U65.P6(IO_B1_P6) U110.9(SEL)
PEX_TX_N: C607.2 U110.18(B0-)
PEX_TX_P: C606.2 U110.19(B0+)
PEXCLK_OE_N: R843.2 U65.N16(IO_B2_N16) U97.13(O\E\0\) U97.21(O\E\1\) U97.24(O\E\2\) U97.30(O\E\3\) U97.35(O\E\4\)
PORESET_N: R94.2 U1.F13(P\O\R\E\S\E\T\) U65.C15(IO_B2_C15)
PWR_EN_N: J37.14(P\S\_\O\N\) J48.1 Q30.3(C) R710.1
PWR_GOOD: C894.1 R709.1 R712.2 U65.C2(IO_B1_C2)
PWR_RST_N: R708.2 U65.C3(IO_B1_C3) U83.2(R\E\S\E\T\)
RESET_REQ_N: R98.2 U1.B3(R\E\S\E\T\_\R\E\Q\) U65.K15(IO_B2_K15)
RS232_CTS1: C276.1 FB21.2 J13.A8 U43.4
RS232_CTS2: C289.1 FB25.2 J13.B8 U43.5
RS232_RTS1: C277.1 FB20.2 J13.A1 U43.2
RS232_RTS2: C290.1 FB24.2 J13.B1 U43.8
RS232_RXD1: C278.1 FB19.2 J13.A6 U43.3
RS232_RXD2: C291.1 FB23.2 J13.B6 U43.6
RS232_TXD1: C279.1 FB18.2 J13.A3 U43.1
RS232_TXD2: C292.1 FB22.2 J13.B3 U43.7
RTC_INT_N: R940.1 U65.P9(IO_B1_P9) U100.7(SQW\I\N\T\)
SD_REFCLK1_C_N: C68.2 U1.AA14(SD1_REF_CLK1_N)
SD_REFCLK1_C_P: C67.2 U1.AB14(SD1_REF_CLK1_P)
SD_REFCLK1_N: C68.1 R997.1 U113.14(Q0)
SD_REFCLK1_P: C67.1 R993.1 U113.13(Q\0\)
SD_REFCLK2_C_N: C1381.1 U1.AA18(SD1_REF_CLK2_N)
SD_REFCLK2_C_P: C1380.1 U1.AB18(SD1_REF_CLK2_P)
SD_REFCLK2_N: C1381.2 R995.1 U112.13(Q\0\)
SD_REFCLK2_P: C1380.2 R999.1 U112.14(Q0)
SD_REFCLK_SEL: U65.T13(IO_B1_T13) U112.1(CLK_SEL) U113.1(CLK_SEL)
SD_RX1_N: C1268.1 U110.7(A1+)
SD_RX1_P: C1267.1 U110.8(A1-)
SD_TX1_N: U1.AE17(SD1_TX1_N) U110.4(A0-)
SD_TX1_P: U1.AD17(SD1_TX1_P) U110.3(A0+)
SDHC_CD_N: J2.10(I\N\S\E\R\T\) R66.1 U1.L5(S\D\H\C\_\C\D\) U93.4 U93.5
SDHC_CLK: J2.5(CLK/SCLK) R61.2 R68.1 U94.1 U94.8
SDHC_CMD: J2.2(CMD/DIN) R67.1 U1.K3(SDHC_CMD) U93.3 U93.6
SDHC_DAT0: J2.7(D0/DOUT) R60.1 U1.L2(SDHC_DAT0) U94.2 U94.7
SDHC_DAT1: J2.8(D1/RSV) R62.1 U1.K4(SDHC_DAT1) U94.3 U94.6
SDHC_DAT2: J2.9(D2/RSV) R63.1 U1.L3(SDHC_DAT2) U93.1 U93.8
SDHC_DAT3: J2.1(D3/C\S\) R64.1 U1.L1(SDHC_DAT3) U93.2 U93.7
SDHC_VS: R874.1 R882.2 U65.M16(IO_B2_M16)
SDHC_WP: J2.11(P\R\O\T\E\C\T\) R65.1 U1.M5(SDHC_WP) U94.4 U94.5
SENSEGND: TP18.1(TP) U1.G20(SENSEGND)
SENSEGNDC: TP16.1(TP) U1.AB10(SENSEGNDC)
SENSEVDD: R918.1 TP17.1(TP) U1.G19(SENSEVDD)
SENSEVDD_EN_N: U65.P7(IO_B1_P7) U104.1(O\E\)
SENSEVDDC: R917.1 TP15.1(TP) U1.AB9(SENSEVDDC)
SGMII_RX_N: U108.V6(TX_LN2_N) U110.13(C1+)
SGMII_RX_P: U108.U6(TX_LN2_P) U110.12(C1-)
SGMII_TX_N: C1285.1 U110.14(C0-)
SGMII_TX_P: C1286.1 U110.15(C0+)
SPI_CLK: R59.2 R865.1 R867.2
SPI_CS0_N: R56.1 U1.M1(S\P\I\_\C\S\0\) U13.7(C\S\) U15.1(C\S\)
SPI_MISO: R54.1 R58.1 R868.2 U1.P1(SPI_MISO)
SPI_MOSI: R866.1 R869.2 U1.P2(SPI_MOSI)
SYS_REFCLK: R511.2 R513.2 U1.G15(SYSCLK)
SYS_REFCLK_N: R837.2 R838.1 U1.F14(D\I\F\F\_\S\Y\S\C\L\K\)
SYS_REFCLK_P: R835.1 R836.2 U1.G14(DIFF_SYSCLK)
SYSCLK_OE: U65.M15(IO_B2_M15) X1.1(OE) X3.1(OE) X5.1(OE)
TDMA_RCK_CLK8_12: J43.21 U1.M4(CLK12)
TDMA_RQ: J43.3 U1.R2(TDMA_RQ)
TDMA_RSYNC: J43.11 U1.U1(TDMA_RSYNC)
TDMA_RXD: J43.13 U1.U2(TDMA_RXD)
TDMA_TCK_CLK9: J43.17 U1.P4(CLK09)
TDMA_TSYNC: J43.9 U1.R1(TDMA_TSYNC)
TDMA_TXD: J43.7 U1.T1(TDMA_TXD)
TDMB_RCK_CLK10: J43.29 U1.P3(CLK10)
TDMB_RQ: J43.24 U1.R4(TDMB_RQ)
TDMB_RSYNC: J43.18 U1.T3(TDMB_RSYNC)
TDMB_RXD: J43.1 U1.U4(TDMB_RXD)
TDMB_TCK_CLK11: J43.39 U1.N4(CLK11)
TDMB_TSYNC: J43.22 U1.R3(TDMB_TSYNC)
TDMB_TXD: J43.20 U1.T4(TDMB_TXD)
TDMR1_INT_N: J43.31 R850.2 U65.R12(IO_B1_R12)
TDMR2_INT_N: J43.33 R851.2 U65.P11(IO_B1_P11)
TDMR_PRS_N: J43.27 R849.2 U65.P12(IO_B1_P12)
TDMR_RST_N: J43.35 R852.2 U65.R11(IO_B1_R11)
TDMR_SLP_N: J43.25 U65.R13(IO_B1_R13)
TDMR_SPI_CS0_N: J43.32 R872.1 U1.M2(S\P\I\_\C\S\1\)
TDMR_SPI_CS1_N: J43.34 R871.1 U1.M3(S\P\I\_\C\S\2\)
TEMP_DIODE_N: R206.1 U1.G21(TD1_CATHODE)
TEMP_DIODE_P: R205.1 U1.E21(TD1_ANODE)
TEST_SEL_N: R83.1 SW3.8 U1.G8(T\E\S\T\_\S\E\L\) U65.E16(IO_B2_E16)
THERM_ALERT_N: R853.1 U45.6(A\L\E\R\T\/T\H\E\R\M\2\) U65.M4(IO_B1_M4)
THERM_FAULT_N: D34.1 R204.1 U45.4(T\H\E\R\M\) U65.D1(IO_B1_D1)
U_EC2_GTXCLK: C56.1 R128.1 U1.AC8(TSEC_1588_CLK_IN)
U_EC2_TXCTL: R124.1 R126.1 U1.AD8(TSEC_1588_PULSE_OUT2)
U_EC2_TXD0: R117.1 U1.AC7(TSEC_1588_ALARM_OUT2)
U_EC2_TXD1: R118.1 U1.AD7(TSEC_1588_CLK_OUT)
U_EC2_TXD2: R120.1 U1.AB6(TSEC_1588_TRIG_IN1)
U_EC2_TXD3: R122.1 U1.AC6(GPIO3_26)
UART1_CTS_N: U1.Y2(U\A\R\T\1\_\C\T\S\) U39.9(R2-OUT)
UART1_RTS_N: U1.Y1(U\A\R\T\1\_\R\T\S\) U39.10(T2-IN)
UART1_RXD: U1.AA1(UART1_SIN) U39.12(R1-OUT)
UART1_TXD: U1.AA2(UART1_SOUT) U39.11(T1-IN)
UART2_CTS_N: U1.Y4(U\A\R\T\2\_\C\T\S\) U41.9(R2-OUT)
UART2_RTS_N: U1.V4(U\A\R\T\2\_\R\T\S\) U41.10(T2-IN)
UART2_RXD: U1.W4(UART2_SIN) U41.12(R1-OUT)
UART2_TXD: U1.AA4(UART2_SOUT) U41.11(T1-IN)
USB1_DM: J41.6 L1.3 R168.2 U38.4
USB1_DP: J41.7 L1.2 R167.2 U38.6
USB1_FLG_N: Q3.1(G) R157.2 R159.1 U37.9(F\L\T\A\)
USB1_PWREN: R162.2 U1.F6(USB1_DRVVBUS) U37.2(ONA)
USB1_VBUS: FB6.1 J41.5
USB1_VBUSCLMP: D4.2 R164.1 R166.2 U1.E4(USB1_VBUSCLMP)
USB2_DM: J41.2 L2.3 R170.2 U38.3
USB2_DP: J41.3 L2.2 R169.2 U38.1
USB2_FLG_N: Q4.1(G) R158.1 R160.2 U37.7(F\L\T\B\)
USB2_PWREN: R161.2 U1.J5(USB2_DRVVBUS) U37.4(ONB)
USB2_VBUS: FB8.1 J41.1
USB2_VBUSCLMP: D3.2 R163.1 R165.2 U1.J4(USB2_VBUSCLMP)
USB_REFCLK: R175.2 R176.2 R873.1 R880.2
VCORE: C186.1 C187.1 C188.1 C189.1 C200.1 C201.1 C202.1 C203.1 C204.1 C205.1 C206.1 C207.1 C212.1 C213.1 C214.1 C215.1 C216.1 C217.1 C218.1 C219.1 C223.1 C224.1 C225.1 C226.1 C227.1 C228.1 C229.1 C230.1 C904.1 C905.1 C906.1 C907.1 C908.1 C909.1 C910.1 C911.1 C912.1 C913.1 C914.1 C915.1 C1003.1 C1004.1 C1005.1 C1006.1 C1007.1 C1008.1 C1009.1 C1010.1 C1029.1 C1030.1 C1031.1 C1032.1 C1033.1 C1034.1 C1035.1 C1036.1 FB11.2 J11.2 Q46.1 Q46.2 Q46.3 R909.2 U1.K15(VDD01) U1.K17(VDD02) U1.K19(VDD03) U1.L12(VDD04) U1.L14(VDD05) U1.L16(VDD06) U1.L18(VDD07) U1.L20(NC_L20) U1.M9(NC_M9) U1.M13(VDD08) U1.M15(VDD09) U1.M17(VDD10) U1.M19(NC_M19) U1.N12(VDD11) U1.N14(VDD12) U1.N16(VDD13) U1.N18(VDD14) U1.N20(NC_N20) U1.P9(NC_P9) U1.P11(VDD15) U1.P13(VDD16) U1.P15(VDD17) U1.P17(VDD18) U1.P19(NC_P19) U1.R12(VDD19) U1.R14(VDD20) U1.R16(VDD21) U1.R18(VDD22) U1.R20(NC_R20) U1.T9(NC_T9) U1.T13(VDD23) U1.T15(VDD24) U1.T17(VDD25) U1.T19(NC_T19) U1.U14(VDD26) U1.U16(VDD27) U1.U18(VDD28) U1.U20(NC_U20) U1.V9(NC_V9) U1.V13(VDD29) U1.V15(VDD30) U1.V17(VDD31) U1.V19(NC_V19) U1.W14(NC_W14) U1.Y8(NC_Y8) U1.Y9(NC_Y9) U1.Y11(NC_Y11)
VCORE_EN: C1212.2 R906.2 U65.R14(IO_B1_R14) U103.16(EN)
VCORE_SLP: C234.1 C235.1 C236.1 C237.1 C238.1 C239.1 C240.1 C241.1 C916.1 C917.1 C918.1 C919.1 C920.1 C921.1 C922.1 C923.1 C1037.1 C1038.1 C1039.1 Q46.5 R980.4 U1.K11(VDDC01) U1.K13(VDDC02) U1.L10(VDDC03) U1.M11(VDDC04) U1.N10(VDDC05) U1.R10(VDDC06) U1.T11(VDDC07) U1.U10(VDDC08) U1.U12(VDDC09) U1.V11(VDDC10) U1.W10(VDDC11) U1.W12(VDDC12)
VTT: C15.1 C16.1 C17.1 C885.1 C886.1 J1.48(VTT/NC#48) J1.49(VTT/NC#49) J1.120(VTT#120) J1.240(VTT#240) R694.2 U81.3(VO)
XFI_RX_C_N: C60.2 U1.AG16(SD1_RX0_N)
XFI_RX_C_P: C59.2 U1.AH16(SD1_RX0_P)
XFI_RX_N: C60.1 U101.V6(TX_LN2_N)
XFI_RX_P: C59.1 U101.U6(TX_LN2_P)
XFI_TX_N: C1117.1 U1.AE16(SD1_TX0_N)
XFI_TX_P: C1118.1 U1.AD16(SD1_TX0_P)
XGT1_CM_N: J50.15 U101.D8(CM_N)
XGT1_CM_P: J50.14 U101.E8(CM_P)
XGT1_INT_N: R884.1 R885.2 U65.M2(IO_B1_M2)
XGT1_LED_GRN: R902.2 U101.K1(LED0)
XGT1_LED_YEL: R903.2 U101.L1(LED1)
XGT1_MDI0_N: J50.9 U101.A2(A_N)
XGT1_MDI0_P: J50.8 U101.B2(A_P)
XGT1_MDI1_N: J50.3 U101.A4(B_N)
XGT1_MDI1_P: J50.2 U101.B4(B_P)
XGT1_MDI2_N: J50.5 U101.A6(C_N)
XGT1_MDI2_P: J50.4 U101.B6(C_P)
XGT1_MDI3_N: J50.11 U101.A8(D_N)
XGT1_MDI3_P: J50.10 U101.B8(D_P)
XGT1_RST_N: R896.1 U65.P15(IO_B2_P15)
XGT1_SPI_CS_N: R943.1 U101.G2(CE_N) U102.1(C\S\)
XGT1_SPI_SCLK: U101.G1(SCLK) U102.6(SCK)
XGT1_SPI_SDI: U101.F2(SOUT) U102.5(SI)
XGT1_SPI_SDO: U101.F1(SIN) U102.2(SO)
XGT1_TCK: J51.3 U101.K14(TCK)
XGT1_TDI: J51.1 U101.L14(TDI)
XGT1_TDO: J51.5 U101.L15(TDO)
XGT1_TMS: J51.2 U101.M16(TMS)
XGT1_TRST_N: J51.4 R950.2 U101.M15(TRST_N)
XGT2_CM_N: J56.15 U108.D8(CM_N)
XGT2_CM_P: J56.14 U108.E8(CM_P)
XGT2_INT_N: R957.1 R959.2 U65.N1(IO_B1_N1)
XGT2_LED_GRN: R977.2 U108.K1(LED0)
XGT2_LED_YEL: R978.2 U108.L1(LED1)
XGT2_MDI0_N: J56.9 U108.A2(A_N)
XGT2_MDI0_P: J56.8 U108.B2(A_P)
XGT2_MDI1_N: J56.3 U108.A4(B_N)
XGT2_MDI1_P: J56.2 U108.B4(B_P)
XGT2_MDI2_N: J56.5 U108.A6(C_N)
XGT2_MDI2_P: J56.4 U108.B6(C_P)
XGT2_MDI3_N: J56.11 U108.A8(D_N)
XGT2_MDI3_P: J56.10 U108.B8(D_P)
XGT2_RST_N: R969.1 U65.N14(IO_B2_N14)
XGT2_SPI_CS_N: R976.1 U108.G2(CE_N) U109.1(C\S\)
XGT2_SPI_SCLK: U108.G1(SCLK) U109.6(SCK)
XGT2_SPI_SDI: U108.F2(SOUT) U109.5(SI)
XGT2_SPI_SDO: U108.F1(SIN) U109.2(SO)
XGT2_TCK: J55.3 U108.K14(TCK)
XGT2_TDI: J55.1 U108.L14(TDI)
XGT2_TDO: J55.5 U108.L15(TDO)
XGT2_TMS: J55.2 U108.M16(TMS)
XGT2_TRST_N: J55.4 R975.2 U108.M15(TRST_N)
XVDD: C249.1 C250.1 C251.1 C252.1 C253.1 C254.1 C255.1 C1014.2 C1026.1 R140.1 U1.AC9(NC_AC9) U1.AC12(X1VDD1) U1.AC15(X1VDD2) U1.AC18(X1VDD3) U1.AC21(X1VDD4)
N16747459: R1.2 U1.U28(D1_MDIC1)
N16747463: R3.2 U1.P28(D1_MDIC0)
N16800565: R42.1 U4.53(B\Y\T\E\)
N16800570: R41.1 U4.16(W\P\/ACC)
N16821816: R5.1 U1.E14(I\F\C\_\P\E\R\R\)
N16864329: R58.2 U13.8(SO) U15.2(SO)
N16864338: R55.1 R866.2 U13.15(SI) U15.5(SI)
N16864354: R865.2 U13.16(SCK) U15.6(SCK)
N16864378: R57.1 U13.1(H\O\L\D\) U13.9(W\P\) U15.3(W\P\) U15.7(H\O\L\D\)
N16869850: C300.2 R211.2 U46.19(RXC)
N16869910: R209.2 U46.14(RXD0/SELRGV)
N16869938: R213.2 U46.16(RXD1/TXDLY)
N16869959: R214.2 U46.17(RXD2/AN0)
N16869976: R215.2 U46.18(RXD3/AN1)
N16869978: R216.2 U46.13(RXCTL/PHY_AD2)
N16870294: R207.1 T1.15
N16870296: C302.1 R207.2 R208.2 R210.2 R212.2
N16870306: R208.1 T1.18
N16870310: R210.1 T1.21
N16870330: R212.1 T1.24
N16870380: C296.2 C298.2 C299.2 C301.2 T1.1 T1.4 T1.7 T1.10
N16870828: C297.1 FB26.2 J14.A11
N16870844: C307.1 FB63.2 J14.A12
N16870888: FB63.1 R219.2
N16870890: C308.1 FB62.2 J14.A9
N16870898: FB62.1 R218.2
N16871038: R221.1 U46.20(I\N\T\)
N16873302: C304.1 U46.42(CKXTAL1) Y1.1
N16873318: C305.1 U46.43(CKXTAL2) Y1.3
N16873350: R220.2 U46.29(P\H\Y\R\S\T\)
N16874872: C303.1 R217.1 U46.46(CLK125)
N16877780: R222.1 U46.33(P\M\E\)
N16879465: L3.1 R224.1 U46.48(REG_OUT)
N16880733: R822.2 U46.38(ENSWREG)
N16880820: C309.1 R224.2
N16890207: R227.2 U46.39(RSET)
N16973728: L4.1 R253.1 U49.48(REG_OUT)
N16973810: R825.2 U49.38(ENSWREG)
N16973842: C341.1 R253.2
N16974061: C331.2 R238.2 U49.19(RXC)
N16974094: R239.2 U49.14(RXD0/SELRGV)
N16974110: R242.2 U49.16(RXD1/TXDLY)
N16974123: R243.2 U49.17(RXD2/AN0)
N16974136: R244.2 U49.18(RXD3/AN1)
N16974138: R245.2 U49.13(RXCTL/PHY_AD2)
N16974225: R236.1 T2.15
N16974227: C334.1 R236.2 R237.2 R240.2 R241.2
N16974244: R237.1 T2.18
N16974248: R240.1 T2.21
N16974260: R241.1 T2.24
N16974322: C328.2 C330.2 C332.2 C333.2 T2.1 T2.4 T2.7 T2.10
N16974528: C329.1 FB29.2 J14.B11
N16974538: C337.1 FB61.2 J14.B12
N16974570: FB61.1 R248.2
N16974572: C338.1 FB60.2 J14.B9
N16974576: FB60.1 R247.2
N16974631: R250.1 U49.20(I\N\T\)
N16974829: C339.1 U49.42(CKXTAL1) Y2.1
N16974847: C340.1 U49.43(CKXTAL2) Y2.3
N16974885: R249.2 U49.29(P\H\Y\R\S\T\)
N16975047: C335.1 R246.1 U49.46(CLK125)
N16975158: R251.1 U49.33(P\M\E\)
N16975193: R256.2 U49.39(RSET)
N16980127: J18.B11(W\A\K\E\) R408.1
N16980167: J18.A8(JTAG5_TMS) R403.1
N16980179: J18.B9(JTAG1_T\R\S\T\) R400.1
N16980191: J18.A5(JTAG2_TCK) R401.1
N16980203: J18.A6(JTAG3_TDI) R402.1
N16980532: C607.1 J18.B15(PETN0)
N16980534: C606.1 J18.B14(PETP0)
N16984231: C598.1 J19.33(PETP0)
N16984233: C599.1 J19.31(PETN0)
N16984263: C1265.1 J19.25(PERP0)
N16984265: C1266.1 J19.23(PERN0)
N16985354: C630.1 J20.33(PETP0)
N16985356: C631.1 J20.31(PETN0)
N16985386: C1269.1 J20.25(PERP0)
N16985388: C1270.1 J20.23(PERN0)
N17013042: L1.1 R167.1 U1.F1(USB1_UDP)
N17013078: L1.4 R168.1 U1.F2(USB1_UDM)
N17013302: R172.2 U1.H4(USB2_UID)
N17013307: R173.2 U1.F4(USB1_UID)
N17013374: C1022.1 R171.2 U1.G4(USB_IBIAS_REXT)
N17020476: L2.1 R169.1 U1.H1(USB2_UDP)
N17020482: L2.4 R170.1 U1.H2(USB2_UDM)
N17021052: FB9.1 J41.4
N17021059: FB7.1 J41.8
N17021121: Q3.3(D) R156.1 R157.1 U1.F5(USB1_PWRFAULT)
N17021131: Q4.3(D) R155.1 R160.1 U1.H5(USB2_PWRFAULT)
N17040696: R59.1 U1.N1(SPI_CLK)
N17040868: R61.1 U1.K1(SDHC_CLK)
N17055310: C273.1 U39.2(V+)
N17055339: C275.1 U39.6(V-)
N17055373: C271.2 U39.1(C1+)
N17055376: C271.1 U39.3(C1-)
N17055394: C274.2 U39.4(C2+)
N17055396: C274.1 U39.5(C2-)
N17055419: R196.1 U39.14(T1-OUT)
N17055422: R197.1 U39.13(R1-IN)
N17055459: R199.1 U39.8(R2-IN)
N17055461: R198.1 U39.7(T2-OUT)
N17055495: FB18.1 R196.2
N17055507: FB19.1 R197.2
N17055527: FB20.1 R198.2
N17055529: FB21.1 R199.2
N17056698: C287.1 U41.2(V+)
N17056714: C288.1 U41.6(V-)
N17056740: C285.2 U41.1(C1+)
N17056750: C285.1 U41.3(C1-)
N17056764: C284.2 U41.4(C2+)
N17056766: C284.1 U41.5(C2-)
N17056776: R200.1 U41.14(T1-OUT)
N17056778: R201.1 U41.13(R1-IN)
N17056796: R203.1 U41.8(R2-IN)
N17056798: R202.1 U41.7(T2-OUT)
N17056816: FB22.1 R200.2
N17056834: FB23.1 R201.2
N17056844: FB24.1 R202.2
N17056846: FB25.1 R203.2
N17059643: R130.1 U1.U6(EMI2_MDC)
N17059732: R121.2 U1.AC3(EC1_TXD3)
N17059733: R116.2 U1.AE4(EC1_TXD1)
N17059734: R119.2 U1.AD3(EC1_TXD2)
N17059735: R115.2 U1.AE3(EC1_TXD0)
N17059985: R123.2 R125.2 U1.AF4(EC1_TX_EN)
N17060054: C55.2 R127.2 U1.AF3(EC1_GTX_CLK)
N17060498: R129.2 U1.AH3(EMI1_MDC)
N17072443: R106.2 TP2.1(TP) U1.B17(RTC)
N17082319: R140.2 U1.Y20(SD1_IMP_CAL_TX)
N17082346: R139.2 U1.AA12(SD1_IMP_CAL_RX)
N17109221: R95.1 U1.AA3(IIC4_SCL)
N17109223: R97.1 U1.AB3(IIC4_SDA)
N17109295: R87.1 U1.V3(IIC2_SCL) U19.14(SCL)
N17109336: R86.1 U1.Y3(IIC2_SDA) U19.15(SDA)
N17111815: J19.1(W\A\K\E\) R399.1
N17112169: J20.1(W\A\K\E\) R411.1
N17112712: R99.2 U19.3(R\E\S\E\T\)
N17112758: R104.2 U1.C20(FA_ANALOG_G_V)
N17112821: R105.2 U1.B20(FA_ANALOG_PIN)
N17112937: R84.1 U1.F9(S\C\A\N\_\M\O\D\E\)
N17116912: R70.1 R873.2 R874.2 U1.D3(IRQ1)
N17170143: C718.1 R511.1 X3.3(OUT)
N17232338: C728.1 R517.1 X5.3(OUT)
N17271631: R82.1 U1.F19(T\M\P\_\D\E\T\E\C\T\)
N17321001: R103.1 U21.4(O)
N17321019: D1.2 R103.2
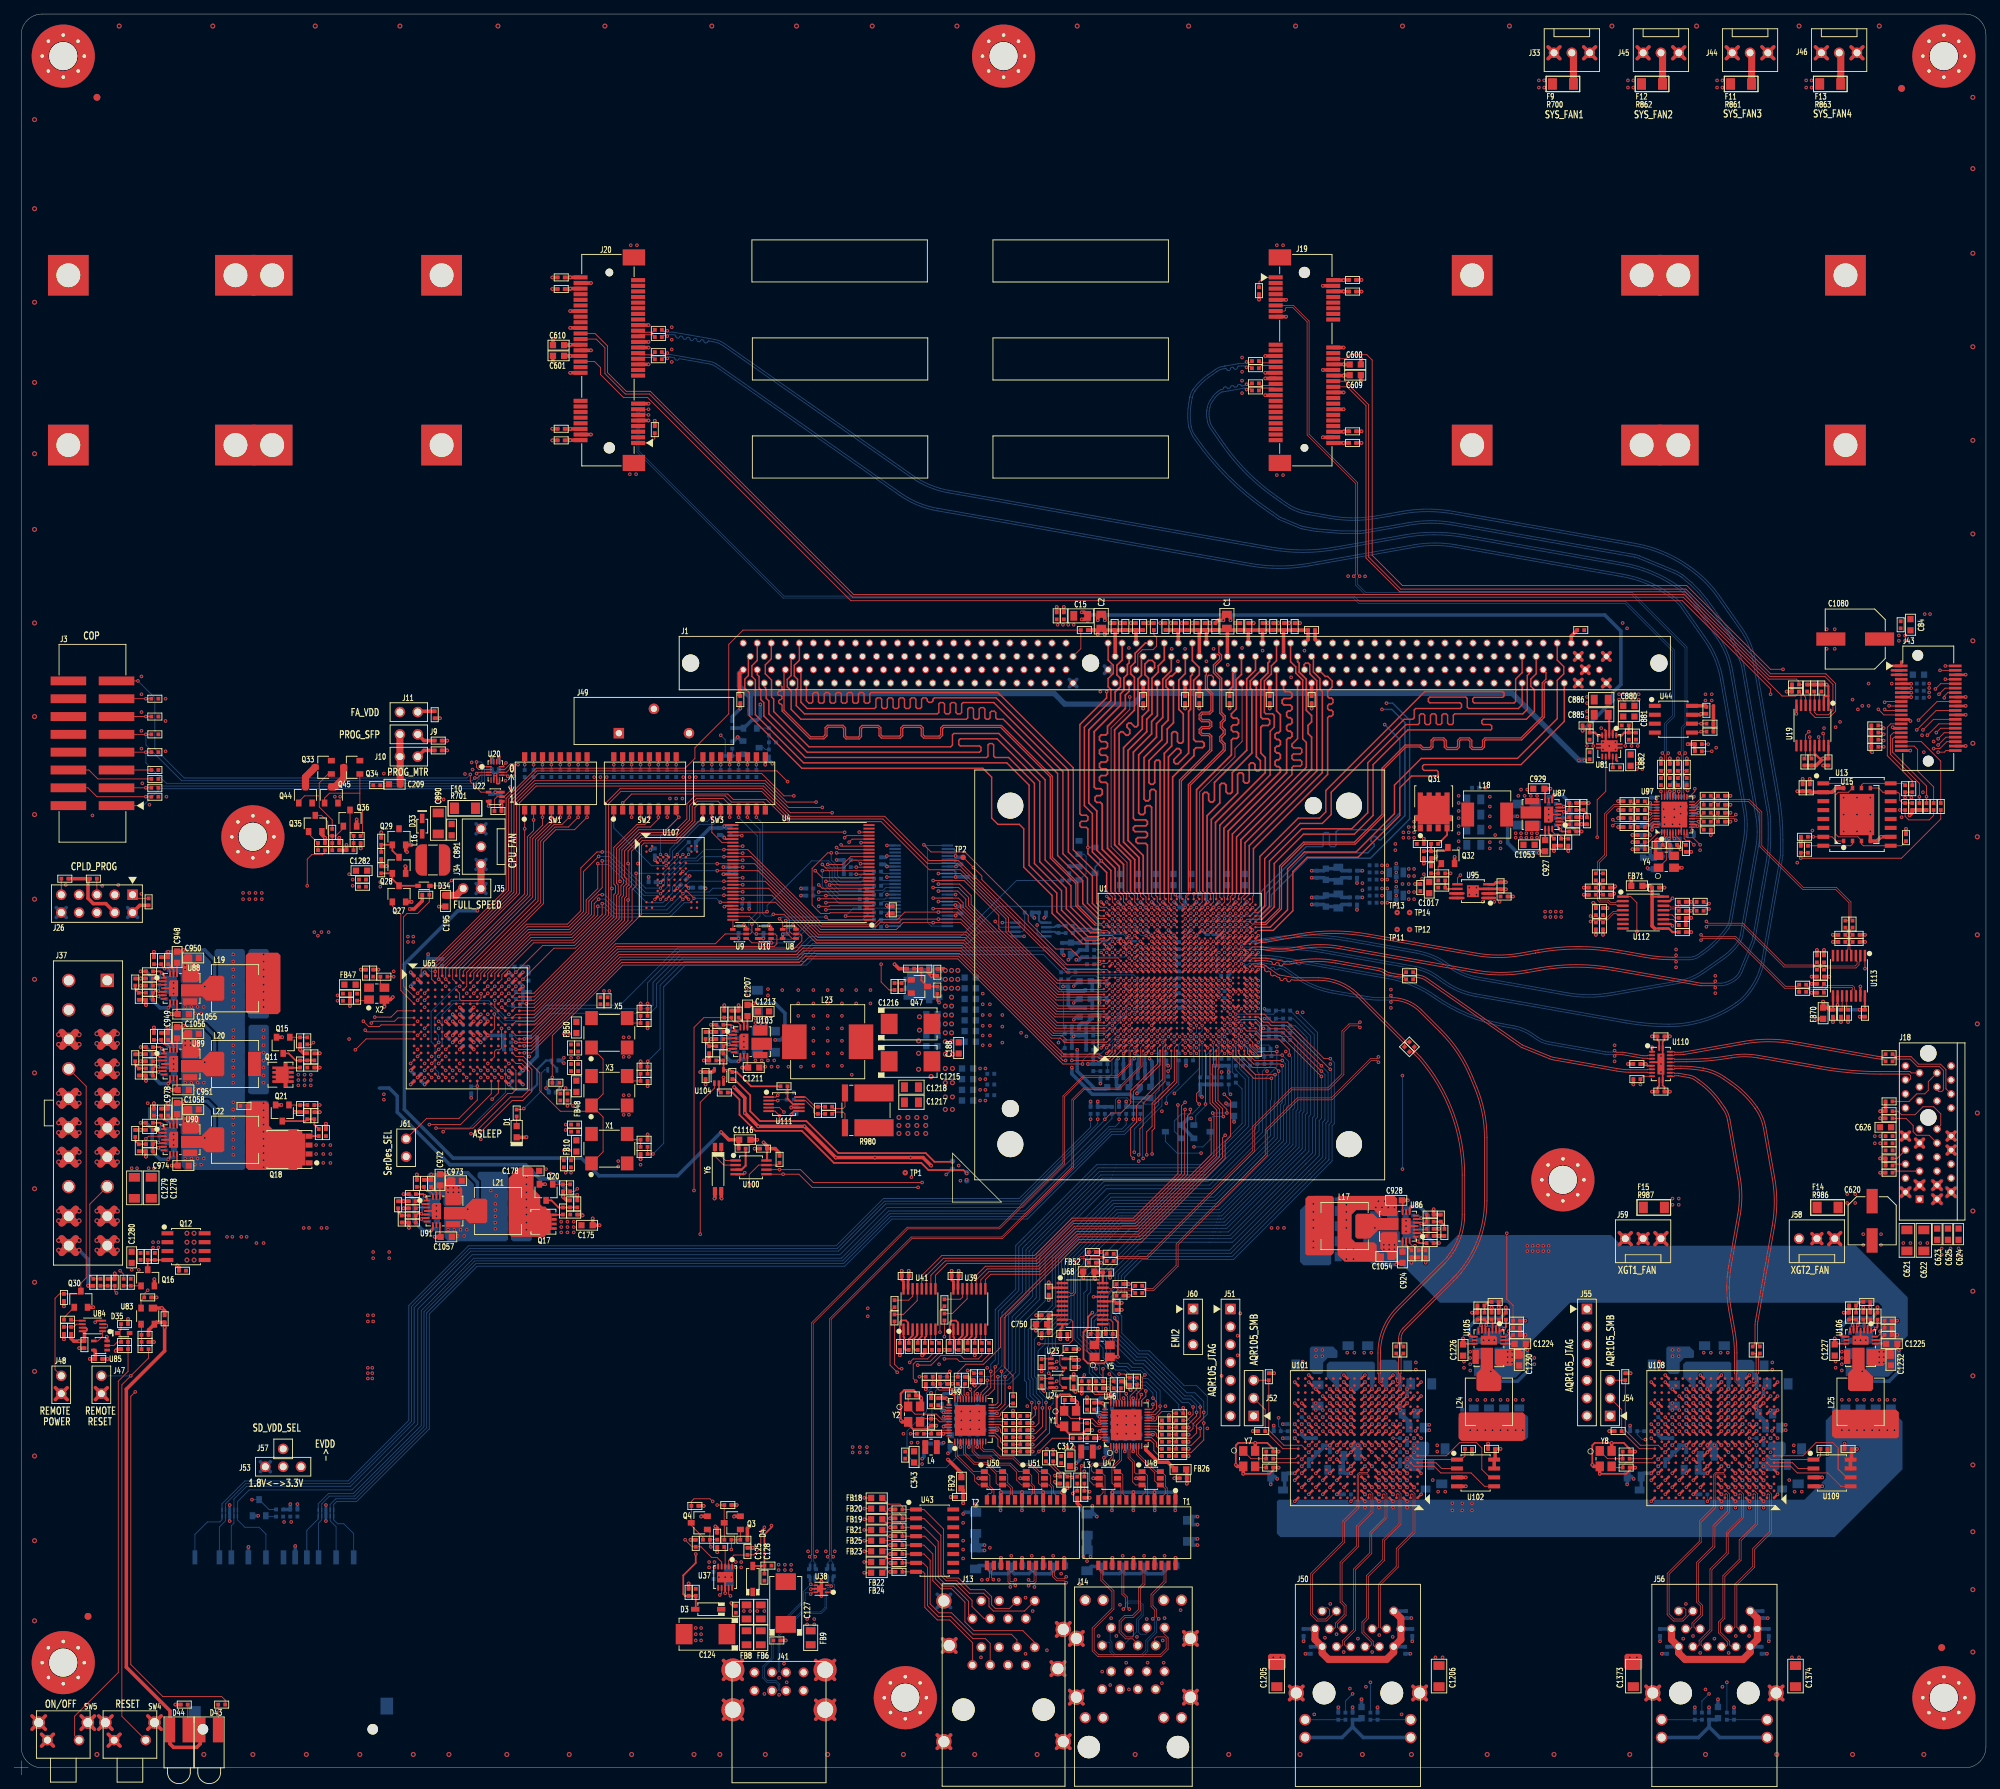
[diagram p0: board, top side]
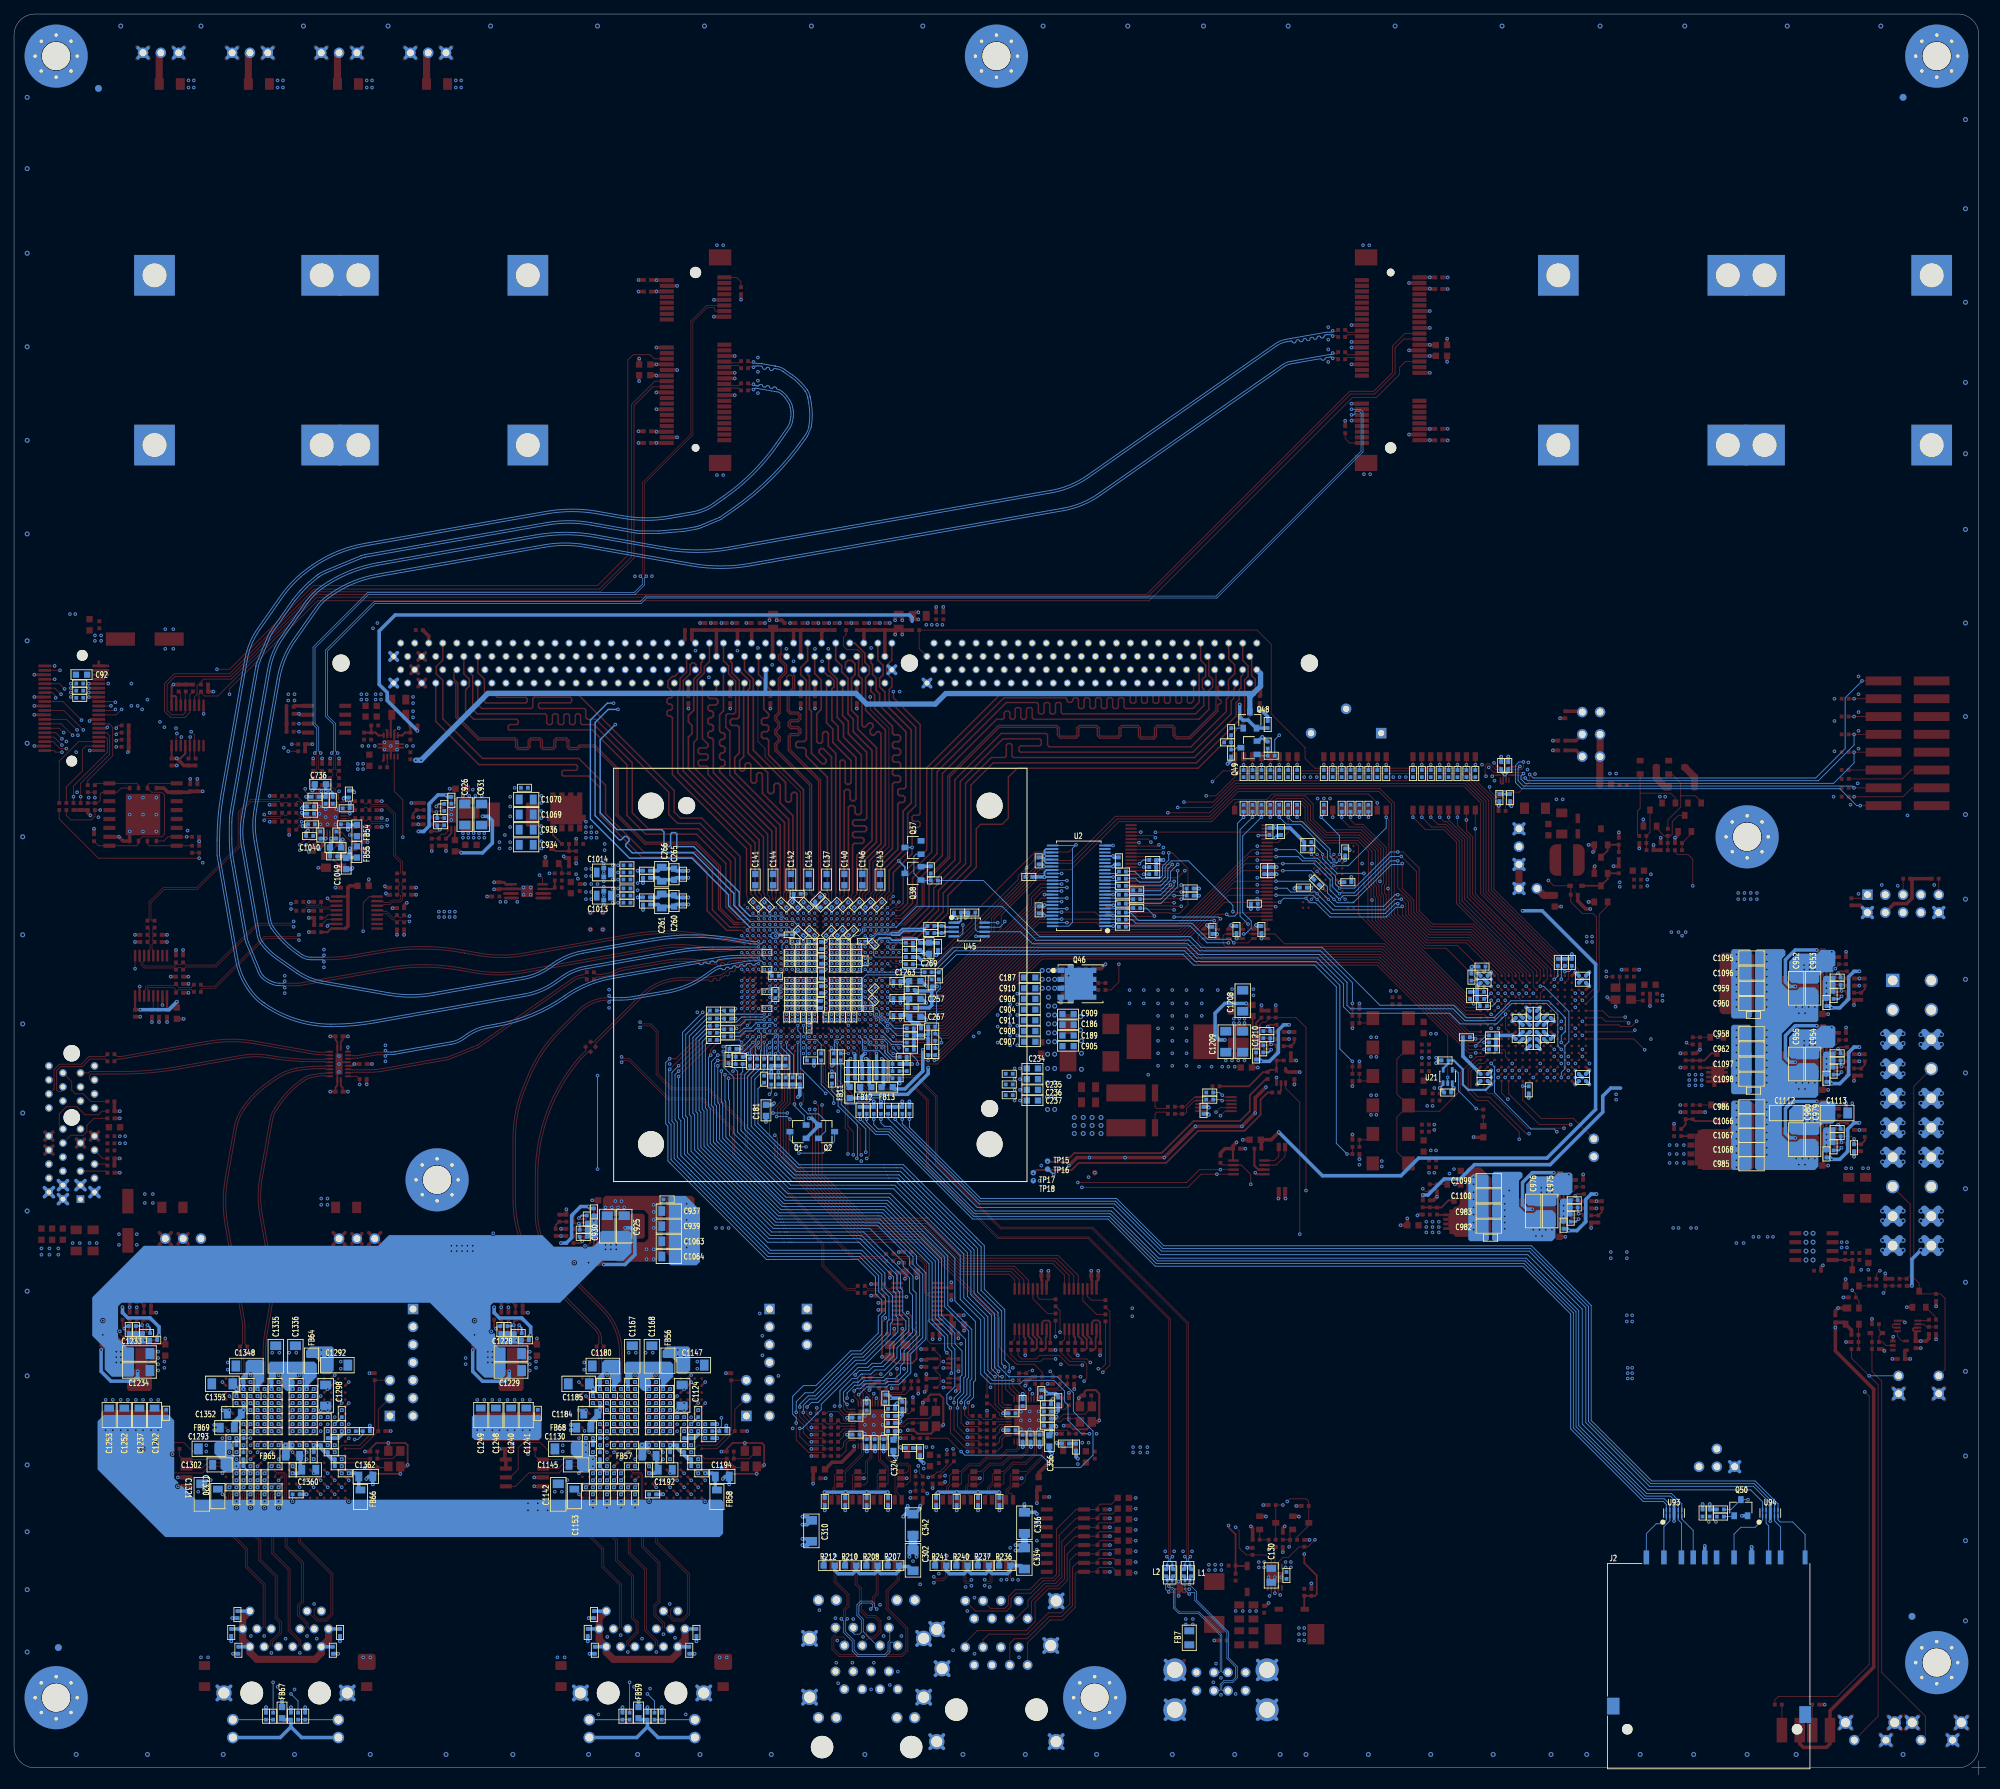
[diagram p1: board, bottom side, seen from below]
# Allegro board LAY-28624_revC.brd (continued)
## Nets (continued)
N17399246: C893.1 R705.1 R707.2 U83.3(M\R\)
N17399288: J47.1 R707.1 SW4.2
N17400346: D35.2 R711.1 R714.1 SW5.2
N17401317: U84.1(CLK) U85.4(O)
N17401544: C895.1 D35.1 R714.2 U85.2(I)
N17403382: C890.2 C891.2 J34.1 J34.3 J35.1 L16.2
N17403388: C890.1 C891.1 D33.1 F10.2 J34.2 R701.2
N17423481: J3.5 R112.2
N17423546: J3.6 R108.1
N17523688: U84.2(D) U84.3(Q\)
N17523697: R713.1 U84.5(Q)
N17523706: C896.1 R715.2 U84.6(C\L\R\)
N17523733: D33.2 L16.1 Q29.3(D)
N17524661: C892.1 Q28.3(D) Q29.1(G) R704.1
N17525004: D34.2 Q27.3(D) Q28.1(G) R703.1
N17736577: R17.1 SW1.16
N17736598: R19.1 SW1.15
N17736619: R21.1 SW1.14
N17736629: R23.1 SW1.13
N17736659: R25.1 SW1.12
N17736669: R27.1 SW1.11
N17736681: R29.1 SW1.10
N17736695: R31.1 SW1.9
N17736739: R33.1 SW2.16
N17736751: R34.1 SW2.15
N17736763: R35.1 SW2.14
N17736781: R36.1 SW2.13
N17736801: R39.1 SW2.11
N17736803: R37.1 SW2.12
N17736817: R38.1 SW2.10
N17736835: R40.1 SW2.9
N18263878: R904.2 U103.15(FF)
N18263905: C1220.1 R910.1 U103.8(3VCBP)
N18263955: R910.2 R911.2 U103.1(FCCM)
N18263961: C1207.2 L23.1 R905.1 R907.2 U103.12(PHASE)
N18263987: C1214.1 C1219.1 R905.2
N18264005: C1214.2 C1215.1 C1216.1 C1217.1 C1218.1 L23.2 R915.2 R980.1
N18264015: C1219.2 R913.2 R914.2 U103.5(FB)
N18264194: R908.2 U103.3(PGOOD)
N18264460: C1221.1 U103.6(SS)
N18264464: C1207.1 U103.14(BOOT)
N18264487: R907.1 U103.2(ISET)
N18271716: Q15.1(G) R666.2 R669.2
N18271718: C873.2 Q15.3(D) R659.2 R662.2
N18271794: Q11.4 R659.1
N18272820: C875.2 Q20.3(D) R675.2 R678.2
N18272822: Q20.1(G) R681.2 R684.2
N18272905: Q17.4 R675.1
N18273179: Q21.1(G) R682.2 R685.2
N18273181: C876.2 Q21.3(D) R676.2 R679.2
N18273262: Q18.4 R676.1
N18273767: Q16.1(G) R670.2 R671.2
N18273907: C874.2 Q12.4 Q16.3(D) R663.2
N18275087: C887.1 R695.1 R696.2 U81.1(REFIN)
N18275123: C884.1 R694.1 U81.5(VOSNS)
N18275169: R697.1 U81.9(PGOOD)
N18287015: R138.1 U23.4(C) U24.4(C)
N18382428: R499.1 SW3.16
N18382505: R500.1 SW3.15
N18382570: R501.1 SW3.14
N18382580: R503.1 SW3.13
N18382664: R507.1 SW3.11
N18382676: R509.1 SW3.10
N18562864: Q30.1(B) R713.2
N18563122: J37.8(PWR_OK) R706.1 R709.2
N18583652: R918.2 U104.2(A)
N18583655: R914.1 R915.1 R917.2 R985.2 U104.4(B)
N18586245: C294.2 R205.2 U45.2(D+)
N18586247: C294.1 R206.2 U45.3(D-)
N18848286: C1117.2 U101.V4(RX_LN2_N)
N18848288: C1118.2 U101.U4(RX_LN2_P)
N18849311: R885.1 U101.K18(INT_N)
N18850569: R897.1 U101.H3(RST_OUT_N)
N18882897: R901.2 U101.A10(RREF_BG)
N19017659: C1198.2 C1199.2 C1201.2 C1202.2 C1204.2 J50.1 J50.6 J50.7 J50.12 J50.13
N19034153: C1200.1 J50.16 R902.1
N19034169: C1197.1 FB59.1 J50.17 J50.19
N19034241: C1203.1 J50.18 R903.1
N19126530: R505.1 SW3.12
N19163046: R495.1 X2.3(OUT)
N19163064: R494.2 X2.1(OE)
N19623883: C996.2 Q32.3(D) R783.2 R784.2
N19623885: Q32.1(G) R785.2 R786.2
N19623968: Q31.4 R783.1
N19644915: C927.2 L18.1 R731.2 R735.1 U87.12(PHASE)
N19644936: C941.2 C943.2 R735.2
N19644956: C943.1 R736.1 R745.2 U87.5(FB)
N19644972: R739.2 U87.3(PGOOD)
N19644986: C932.2 R734.2 U87.16(EN)
N19645019: C946.1 R741.1 U87.8(3VCBP)
N19645035: R741.2 R743.2 U87.1(FCCM)
N19645080: C947.1 U87.6(SS)
N19645160: R728.2 U87.15(FF)
N19645192: C927.1 U87.14(BOOT)
N19645200: R731.1 U87.2(ISET)
N19646811: C949.2 L20.1 R749.2 R755.1 U89.12(PHASE)
N19646830: C965.2 C967.2 R755.2
N19646848: C967.1 R757.1 R763.2 U89.5(FB)
N19646866: R749.1 U89.2(ISET)
N19646870: R756.2 U89.3(PGOOD)
N19646891: C957.2 R754.2 U89.16(EN)
N19646930: C970.1 R759.1 U89.8(3VCBP)
N19646940: R759.2 R761.2 U89.1(FCCM)
N19646995: C971.1 U89.6(SS)
N19647070: R747.2 U89.15(FF)
N19647102: C949.1 U89.14(BOOT)
N19648273: C978.2 L22.1 R767.2 R775.1 U90.12(PHASE)
N19648275: C989.2 C991.2 R775.2
N19648310: C991.1 R772.1 R781.2 U90.5(FB)
N19648328: R767.1 U90.2(ISET)
N19648366: C981.2 R770.2 U90.16(EN)
N19648414: C994.1 R777.1 U90.8(3VCBP)
N19648420: R777.2 R779.2 U90.1(FCCM)
N19648465: C995.1 U90.6(SS)
N19648544: R765.2 U90.15(FF)
N19648572: C978.1 U90.14(BOOT)
N19650144: C972.2 L21.1 R766.2 R769.1 U91.12(PHASE)
N19650163: C988.2 C990.2 R769.2
N19650181: C990.1 R774.1 R780.2 U91.5(FB)
N19650199: R766.1 U91.2(ISET)
N19650212: R773.2 U91.3(PGOOD)
N19650233: C977.2 R768.2 U91.16(EN)
N19650272: C992.1 R776.1 U91.8(3VCBP)
N19650282: R776.2 R778.2 U91.1(FCCM)
N19650331: C993.1 U91.6(SS)
N19650402: R764.2 U91.15(FF)
N19650430: C972.1 U91.14(BOOT)
N19651609: C948.2 L19.1 R748.2 R751.1 U88.12(PHASE)
N19651628: C964.2 C966.2 R751.2
N19651646: C966.1 R753.1 R762.2 U88.5(FB)
N19651664: R748.1 U88.2(ISET)
N19651683: R752.2 U88.3(PGOOD)
N19651731: C968.1 R758.1 U88.8(3VCBP)
N19651747: R758.2 R760.2 U88.1(FCCM)
N19651788: C969.1 U88.6(SS)
N19651863: R746.2 U88.15(FF)
N19651895: C948.1 U88.14(BOOT)
N19653096: C924.2 L17.1 R729.2 R733.1 U86.12(PHASE)
N19653107: C935.2 C942.2 R733.2
N19653133: C942.1 R738.1 R744.2 U86.5(FB)
N19653151: R729.1 U86.2(ISET)
N19653170: R737.2 U86.3(PGOOD)
N19653218: C944.1 R740.1 U86.8(3VCBP)
N19653234: R740.2 R742.2 U86.1(FCCM)
N19653275: C945.1 U86.6(SS)
N19653350: R730.2 U86.15(FF)
N19653382: C924.1 U86.14(BOOT)
N20366563: R806.1 R807.2 U95.6(FB/ADJ)
N20516568: TP1.1(TP) U1.E6(CLK_OUT)
N20553507: Q37.1(G) Q38.1(G) R830.2 R831.2
N20559490: Q35.1(G) R820.2 R821.2
N20559492: C1023.2 Q35.3(D) Q36.1(G) R816.2 R818.2
N20559589: Q33.1(G) Q44.1(G) R816.1
N20559634: Q33.3(D) Q44.3(D)
N20559669: C1024.1 Q36.3(D) R817.1 R819.1
N20559724: Q34.1(G) Q45.1(G) R817.2
N20562248: TP11.1(TP) U1.Y15(SD1_PLL1_TPA)
N20562257: TP12.1(TP) U1.AB15(SD1_PLL1_TPD)
N20562271: TP13.1(TP) U1.Y19(SD1_PLL2_TPA)
N20562273: TP14.1(TP) U1.AB19(SD1_PLL2_TPD)
N20562350: C1022.2 R814.2
N21227087: J37.1(+3.3VDC#1)
N21227093: J37.2(+3.3VDC#2)
N21227121: J37.11(+3.3VDC#11)
N21754633: J43.28 R867.1
N21754692: J43.36 R868.1
N21754708: J43.38 R869.1
N22257590: R14.1 U2.2(1Q1)
N22257592: R15.1 U2.3(1Q2)
N22257594: R16.1 U2.5(1Q3)
N22258098: R20.1 U2.8(1Q5)
N22258100: R22.1 U2.9(1Q6)
N22258102: R24.1 U2.11(1Q7)
N22258104: R26.1 U2.12(1Q8)
N22258216: R18.1 U2.6(1Q4)
N22258634: R28.1 U2.13(2Q1)
N22258636: R30.1 U2.14(2Q2)
N22258638: R32.1 U2.16(2Q3)
N22360230: F9.2 J33.2 R700.2
N22360382: F11.2 J44.2 R861.2
N22360534: F12.2 J45.2 R862.2
N22361017: F13.2 J46.2 R863.2
N22361656: D43.1 R702.2
N22361689: D44.1 R699.2
N22440478: Q34.3(D) Q45.3(D)
N23085337: C1116.1 J49.1 R883.1
N23085351: R883.2 U100.3(VBACKUP)
N23085389: U100.2(X2) Y6.1
N23085395: U100.1(X1) Y6.4
N23146172: R520.1 U97.14(DIF0)
N23146174: R521.1 U97.15(D\I\F\0\)
N23146290: C733.1 U97.2(X1_25) Y4.1
N23146296: C734.1 U97.3(X2) Y4.3
N23146369: R525.1 U97.22(DIF2)
N23146371: R526.1 U97.23(D\I\F\2\)
N23146377: R530.1 U97.28(DIF3)
N23146379: R532.1 U97.29(D\I\F\3\)
N23146385: R536.1 U97.33(DIF4)
N23146387: R537.1 U97.34(D\I\F\4\)
N23146565: R837.1 U97.37(D\I\F\5\)
N23146571: R836.1 U97.36(DIF5)
N23146840: R829.2 R842.2 U97.1(SS_EN_TRI)
N23147063: R834.2 U97.6(SADR/REF1.8)
N23147551: C132.1 R175.1 X1.3(OUT)
N23148282: C739.1 U68.13(XTAL_IN) Y5.1
N23148288: C738.1 U68.12(XTAL_OUT) Y5.3
N23178619: R875.2 U1.AB1(NC_AB1)
N23180170: R881.2 U1.AD5(NC_AD5)
N23238405: C1119.1 R898.1 Y7.1
N23238411: C1120.1 U101.F18(XTAL_I) Y7.3
N23238429: R898.2 U101.G18(XTAL_O)
N23238970: R886.2 U101.N17(RX_DC_RST_N)
N23239280: R889.1 U101.J15(ADDR1)
N23239284: R892.1 U101.G17(ADDR4)
N23239286: R891.1 U101.H16(ADDR3)
N23239292: R890.1 U101.J16(ADDR2)
N23239393: R888.1 U101.K15(ADDR0)
N23240310: R895.2 R896.2 U101.J4(RST_N)
N23240770: R900.1 U101.F17(XTAL_SELECT_N)
N23240781: R899.1 U101.G13(50M_CLK_TERM)
N23327185: R887.2 U101.F5(TX_EN)
N23371818: R876.1 R882.1 U1.D1(NC_D1)
N23371833: R877.1 U1.D4(NC_D4)
N23371894: R878.1 U1.D5(NC_D5)
N23373428: R879.1 U1.E9(NC_E9)
N23374222: R880.1 U1.F8(NC_F8)
N23395649: C1224.2 L24.1 R922.2 R926.1 U105.12(PHASE)
N23395651: C1239.2 C1244.2 R926.2
N23395686: C1244.1 R930.1 R937.2 U105.5(FB)
N23395694: R922.1 U105.2(ISET)
N23395911: C1224.1 U105.14(BOOT)
N23398740: R931.2 U105.3(PGOOD)
N23398788: C1246.1 R933.1 U105.8(3VCBP)
N23398805: R933.2 R935.2 U105.1(FCCM)
N23398854: C1247.1 U105.6(SS)
N23398896: R923.2 U105.15(FF)
N23399971: C1225.2 L25.1 R924.2 R928.1 U106.12(PHASE)
N23399992: C1243.2 C1245.2 R928.2
N23400010: C1245.1 R929.1 R938.2 U106.5(FB)
N23400026: R924.1 U106.2(ISET)
N23400036: R932.2 U106.3(PGOOD)
N23400099: C1250.1 R934.1 U106.8(3VCBP)
N23400105: R934.2 R936.2 U106.1(FCCM)
N23400150: C1251.1 U106.6(SS)
N23400230: R921.2 U106.15(FF)
N23400248: C1225.1 U106.14(BOOT)
N23495851: Q49.1(G) R948.2 R949.2
N23495853: C1273.2 Q49.3(D) R946.2 R947.2
N23495929: Q48.1(G) R946.1
N23503182: J52.3 R942.1 U101.H17(SMB_CLK)
N23503185: J52.2 R941.1 U101.H18(SMB_DAT)
N23535138: R951.2 U37.3(ISET)
N23647021: Q50.1(B) R954.2
N23886478: C1285.2 U108.V4(RX_LN2_N)
N23886479: C1286.2 U108.U4(RX_LN2_P)
N23886494: R959.1 U108.K18(INT_N)
N23886496: R970.1 U108.H3(RST_OUT_N)
N23886499: R974.2 U108.A10(RREF_BG)
N23886523: C1287.1 R971.1 Y8.1
N23886526: C1288.1 U108.F18(XTAL_I) Y8.3
N23886535: R971.2 U108.G18(XTAL_O)
N23886543: R958.2 U108.N17(RX_DC_RST_N)
N23886546: R962.1 U108.J15(ADDR1)
N23886548: R967.1 U108.G17(ADDR4)
N23886549: R964.1 U108.H16(ADDR3)
N23886551: R963.1 U108.J16(ADDR2)
N23886557: R961.1 U108.K15(ADDR0)
N23886561: R968.2 R969.2 U108.J4(RST_N)
N23886562: R973.1 U108.F17(XTAL_SELECT_N)
N23886563: R972.1 U108.G13(50M_CLK_TERM)
N23886575: R960.2 U108.F5(TX_EN)
N23886602: J54.3 R965.1 U108.H17(SMB_CLK)
N23886603: J54.2 R966.1 U108.H18(SMB_DAT)
N23890340: C1366.2 C1367.2 C1369.2 C1370.2 C1372.2 J56.1 J56.6 J56.7 J56.12 J56.13
N23890653: C1368.1 J56.16 R977.1
N23890655: C1365.1 FB67.1 J56.17 J56.19
N23890663: C1371.1 J56.18 R978.1
N23926306: Q46.4 R912.2
N23926329: C1222.1 Q47.3(D) R912.1 R916.1
N23926341: Q47.1(G) R919.2 R920.2
N23927707: R980.2 R981.2
N23927714: R980.3 R982.2
N23928633: R983.2 U111.2(A0)
N23928636: R984.2 U111.1(A1)
N23929117: R985.1 U111.8(VBUS)
N23965067: C1268.2 U1.AG17(SD1_RX1_N)
N23965070: C1267.2 U1.AH17(SD1_RX1_P)
N24071716: F14.2 J58.2 R986.2
N24071917: F15.2 J59.2 R987.2
N24117705: R1015.1 U97.18(DIF1)
N24117707: R1012.1 U97.19(D\I\F\1\)
N24120812: C1382.2 R990.2 R1008.2 U113.3(P\C\L\K\0\)
N24120822: C1388.2 R996.2 R1004.2 U113.5(P\C\L\K\1\)
N24120824: C1386.2 R992.2 R1006.2 U113.4(PCLK1)
N24120892: C1384.2 R988.2 R1010.2 U113.2(PCLK0)
N24121080: R1000.1 U113.12(Q1)
N24121082: R1002.1 U113.11(Q\1\)
N24122901: C1385.2 R991.2 R1009.2 U112.3(P\C\L\K\0\)
N24122903: C1389.2 R998.2 R1005.2 U112.5(P\C\L\K\1\)
N24122905: C1387.2 R994.2 R1007.2 U112.4(PCLK1)
N24122973: C1383.2 R989.2 R1011.2 U112.2(PCLK0)
N24123129: R1001.1 U112.12(Q1)
N24123131: R1003.1 U112.11(Q\1\)

Pads without a net: J1 126 135 144 153 162 167 187 204 213 222 231; J3 2 8 10 14; J13 A2 A7 B2 B7; J18 A7 B12; J19 3 5 7 8 10 12 14 16 17 19 20 36 37 38 39 41 42 43 44 45 46 47 49 51; J20 3 5 7 8 10 12 14 16 17 19 20 36 37 38 39 41 42 43 44 45 46 47 49 51; J26 6 7 8; J43 8; U1 A14 A16 A19 AA5 AA6 AA8 AA9 AA10 AB8 AB11 AB12 AC4 AD10 AD11 AD13 AD14 AE7 AE10 AE11 AE13 AE14 AF6 AF7 AG5 AG7 AG8 AG28 AH5 AH8 AH27 C3 C4 C14 C15 C16 C17 C19 D6 D18 E17 F10 F21 G6 G17 H6 H21 J6 J20 K22 L6 M6 M22 N3 N6 P5 P6 P22 R5 R6 U5 U22 V2 V5 V21 W3 W6 W21 Y5 Y6 Y21; U2 17 19 20 22 23; U4 27 28 30; U13 3 4 5 6 11 12 13 14; U19 9 10; U20 5 14 15; U46 12; U47 5; U48 5; U49 12; U50 5; U51 5; U65 D6 D7 D8 D9 D10 E5 E6 E7 E8 E9 E10 E11 E12 F4 F5 F6 F7 F10 F11 F12 G4 G5 G6 G11 G12 G13 H4 H12 H13 J4 J5 J13 K4 K5 K6 K11 K12 K13 L5 L7 L10 L11 L12 M6 M7 M8 M9 M10 M11 M12 N6 N7 N8 N9 N10 N11; U68 1 5 6 7 11 14 15; U85 1; U86 7 9; U87 7 9; U88 7 9; U89 7 9; U90 7 9; U91 7 9; U97 7 20 25 40; U101 A11 A12 A13 A14 A15 A16 A17 B1 B10 B11 B13 B15 B17 B18 C1 C10 C12 C14 C16 C18 D1 D2 D10 D11 D13 D15 D17 E2 E12 E14 E16 F3 F4 F7 F9 F11 F13 F14 F15 F16 G3 G4 G6 G8 G10 G12 G14 G15 G16 H1 H2 H5 H7 H9 H11 H13 H14 H15 J1 J2 J14 J17 K2 K3 K17 L2 L3 L5 L17 M1 M2 M3 M4 M5 M14 M17 M18 N3 N4 N14 N15 N16 N18 P1 P2 P14 P15 P16 R15 R16 R17 R18 T1 T2 T14 T16 T17 T18 U2 U3 U7 U8 U10 U12 U13 U14 U15 U17 V1 V2 V3 V7 V8 V10 V12 V13 V14 V15 V17 V18; U103 7 9; U105 7 9; U106 7 9; U107 A1 A2 A9 A10 B1 B9 B10 D6 D7 D8 E3 E4 E5 E6 E7 E8 F3 F4 F5 F6 F8 G3 G5 G6 G7 G8 H3 H5 H6 H7 J3 J5 L1 L2 L9 L10 M1 M2 M9 M10; U108 A11 A12 A13 A14 A15 A16 A17 B1 B10 B11 B13 B15 B17 B18 C1 C10 C12 C14 C16 C18 D1 D2 D10 D11 D13 D15 D17 E2 E12 E14 E16 F3 F4 F7 F9 F11 F13 F14 F15 F16 G3 G4 G6 G8 G10 G12 G14 G15 G16 H1 H2 H5 H7 H9 H11 H13 H14 H15 J1 J2 J14 J17 K2 K3 K17 L2 L3 L5 L17 M1 M2 M3 M4 M5 M14 M17 M18 N3 N4 N14 N15 N16 N18 P1 P2 P14 P15 P16 R15 R16 R17 R18 T1 T2 T14 T16 T17 T18 U2 U3 U7 U8 U10 U12 U13 U14 U15 U17 V1 V2 V3 V7 V8 V10 V12 V13 V14 V15 V17 V18; U111 3; U112 6 7 8; U113 6 7 8; Z97 1; Z98 1; Z99 1; Z100 1; Z101 1; Z102 1; Z103 1; Z104 1

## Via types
v1: diameter 0.508, hole 0.254, TOP to BOTTOM, 2637 vias
v2: diameter 0.457, hole 0.254, TOP to BOTTOM, 618 vias
v3: diameter 0.711, hole 0.406, TOP to BOTTOM, 193 vias

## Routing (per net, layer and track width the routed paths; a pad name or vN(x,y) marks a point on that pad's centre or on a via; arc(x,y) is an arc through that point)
0V85: length 57.6
  TOP w0.305: U101.L10 v1(190.52,50.01) ; U101.K5 v1(196.52,49.01) ; U108.J8 v1(244.32,47.01) ; U101.P5 v1(196.52,53.01) ; U101.K9 v1(192.52,49.01) ; U101.J8 v1(193.52,47.01) ; U108.N8 v1(244.32,52.01) ; U101.K11 v1(189.52,49.01) ; U101.R8 v1(193.52,54.01) ; U101.N6 v1(195.52,52.01) ; U101.J12 v1(188.52,47.01) ; U108.K7 v1(245.32,49.01) ; U101.M13 v1(187.52,51.01) ; U101.R10 v1(190.52,54.01) ; U101.J10 v1(190.52,47.01) ; U108.J6 v1(246.32,47.01) ; U108.N12 v1(239.32,52.01) ; U108.L10 v1(241.32,50.01) ; U108.R12 v1(239.32,54.01) ; U108.P9 v1(243.32,53.01) ; U108.R8 v1(244.32,54.01) ; U101.L8 v1(193.52,50.01) ; U101.P13 v1(187.52,53.01) ; U108.M13 v1(238.32,51.01) ; U108.M7 v1(245.32,51.01) ; U101.K7 v1(194.52,49.01) ; U108.K11 v1(240.32,49.01) ; U108.M9 v1(243.32,51.01) ; U101.N12 v1(188.52,52.01) ; U108.K13 v1(238.32,49.01) ; U101.L12 v1(188.52,50.01) ; U101.P11 v1(189.52,53.01) ; U101.L6 v1(195.52,50.01) ; U101.M11 v1(189.52,51.01) ; U108.P11 v1(240.32,53.01) ; U108.P13 v1(238.32,53.01) ; U101.J6 v1(195.52,47.01) ; U108.J10 v1(241.32,47.01) ; U108.K5 v1(247.32,49.01) ; U108.N6 v1(246.32,52.01) ; U108.J12 v1(239.32,47.01) ; U108.N10 v1(241.32,52.01) ; U108.R10 v1(241.32,54.01) ; U108.L12 v1(239.32,50.01) ; U108.L8 v1(244.32,50.01) ; U108.M11 v1(240.32,51.01) ; U108.L6 v1(246.32,50.01) ; U108.K9 v1(243.32,49.01) ; U101.M7 v1(194.52,51.01) ; U108.P7 v1(245.32,53.01) ; U101.M9 v1(192.52,51.01) ; U101.P7 v1(194.52,53.01) ; U101.K13 v1(187.52,49.01) ; U101.N8 v1(193.52,52.01) ; U101.P9 v1(192.52,53.01) ; U108.P5 v1(247.32,53.01) ; U101.N10 v1(190.52,52.01) ; U101.R12 v1(188.52,54.01)
  TOP w0.508: v1(202.3,80.64) R738.2 202.31,79.88 C935.1
  L3SIG w0.508: 188.59,82.04 190.63,82.04 192.66,80.01 199.64,80.01 200.27,80.64 v1(202.3,80.64)
  vias: v1(185.17,81.41) v1(185.17,80.26) v1(185.17,79.12) v1(185.17,77.98) v1(185.17,76.07) v1(185.17,75.18) v1(185.55,60.58) v1(185.55,59.69) v1(185.51,53.01) v1(185.51,52.01) v1(186.44,60.58) v1(186.44,59.69) v1(186.51,52.01) v1(191.52,47.01) v1(236.35,60.58) v1(236.35,59.69) v1(236.31,53.01) v1(236.31,52.01) v1(237.24,60.58) v1(237.24,59.69) v1(237.31,52.01) v1(242.32,46.99)
0V85_XGT1_AFE: length 4.3
  TOP w0.305: U101.E10 v1(190.52,43.01)
  BOTTOM w0.508: FB57.1 189.41,45.4 189.41,43.7 C1192.1 189.71,43 C1191.1
0V85_XGT1_VDDSRDS: length 4.8
  TOP w0.305: U101.R5 v1(196.52,54.01) ; U101.T8 v1(193.52,55.01) ; U101.T12 v1(188.52,55.01) ; U101.T10 v1(190.52,55.01)
  BOTTOM w0.508: C1165.1 C1161.1 v1(193.52,55.01) ; C1164.1 C1162.1 v1(190.52,55.01)
0V85_XGT2_AFE: length 4.3
  TOP w0.305: U108.E10 v1(241.32,43.01)
  BOTTOM w0.508: FB65.1 240.21,45.4 240.21,43.7 C1360.1 240.51,43 C1359.1
0V85_XGT2_VDDSRDS: length 4.8
  TOP w0.305: U108.T8 v1(244.32,55.01) ; U108.T12 v1(239.32,55.01) ; U108.T10 v1(241.32,55.01) ; U108.R5 v1(247.32,54.01)
  BOTTOM w0.508: v1(241.32,55.01) C1332.1 C1333.1 ; v1(244.32,55.01) C1328.1 C1334.1
1V0_FA_VL: length 119.3
  TOP w0.305: U1.G18 v2(159.72,116.45)
  TOP w0.508: J11.1 57.65,151.63 R179.2
  L3SIG w0.508: 158.33,116.59 154.75,116.59 154.3,117.03 154.3,118.75 143.51,129.54 139.7,129.54 133.48,135.76 124.08,135.76 112.65,147.19 71.5,147.19 68.96,149.73 59.31,149.73 J11.1
1V0_USB_SVDD: length 5.4
  TOP w0.305: U1.K10 v2(162.12,110.05) ; U1.K9 v2(162.12,109.25)
  BOTTOM w0.457: C149.1 162.17,101.73 v2(161.8,102.11)
  BOTTOM w0.508: FB11.1 162.17,98.33 C1262.1 C138.1 C149.1
1V0S: length 3.8
  TOP w0.381: 204.64,125.01 U95.8 206.54,125.01 ; 204.65,125.66 U95.7 206.55,125.66
  vias: v1(198.75,125.86) v1(198.75,124.84) v1(199.52,125.86) v1(199.52,124.84)
1V2: length 43.3
  TOP w0.305: U108.D4 v1(248.32,42.01) ; U101.E9 v1(192.52,44.01) ; U108.E5 v1(247.32,43.01) ; U108.E9 v1(243.32,44.01) ; U1.T6 v2(167.72,106.85) ; U101.D6 v1(195.52,42.01) ; U101.E5 v1(196.52,43.01) ; U101.E7 v1(194.52,43.01) ; U101.D4 v1(197.52,42.01) ; U108.D6 v1(246.32,42.01) ; U108.E7 v1(245.32,43.01)
  TOP w0.508: C1239.1 208.54,65.91 R930.2 v1(207.78,65.9)
  L3SIG w0.508: v1(207.52,49.15) 206.76,49.91 206.76,54.61 208.41,56.26 208.41,63.37 207.78,64 v1(207.78,65.9)
  L6SIG w1.524: 216.66,49.78 v1(216.66,58.55) v1(216.66,59.44)
  BOTTOM w0.203: R960.1 C1308.1 ; R887.1 C1126.1
  BOTTOM w0.508: R895.1 197.52,44 R887.1 ; R968.1 248.32,44 R960.1 ; R133.1 v1(180.81,50.01) ; R134.1 v1(180.81,48.01)
  vias: v1(198.52,45) v1(198.52,44) v1(199.52,47.01) v1(199.52,46) v1(208.53,49.15) v1(209.68,49.15) v1(210.69,49.15) v1(211.84,49.15) v1(212.85,49.15) v1(214,49.15) v1(215.01,49.15) v1(249.32,44) v2(171.72,106.05)
1V5: length 33.7
  TOP w0.508: C609.1 189.54,199.53 v1(189.48,199.48) J19.28 ; C964.1 18.8,110.5 R753.2 v1(18.8,109.74) ; J19.48 v1(189.48,191.48) 189.53,191.53 C612.1 ; J20.28 v1(79.25,203.88) 79.2,203.82 C610.1 ; C611.1 189.5,211.45 v1(189.48,211.48) J19.6 ; C614.1 79.23,191.9 v1(79.25,191.88) J20.6 ; J20.48 v1(79.25,211.88) 79.2,211.82 C613.1
  L3SIG w0.508: v1(35.56,109.47) 34.8,108.71 30.23,108.71 28.45,110.49 21.72,110.49 20.96,109.74 v1(18.8,109.74)
  vias: v1(35.56,116.97) v1(35.56,115.95) v1(35.56,114.81) v1(35.56,113.79) v1(35.56,112.65) v1(35.56,111.63) v1(35.56,110.49)
1V05_EC1_AVDD: length 6.1
  TOP w0.203: U49.3 v1(134.87,46.75) ; U49.9 v1(137.27,46.75) ; v1(132.46,51.69) 132.6,51.55 U49.40
  BOTTOM w0.508: v1(134.87,46.75) 134.87,46.76 C354.1 ; C355.1 132.59,51.82 v1(132.46,51.69) 132.21,51.94 R826.2 ; C353.1 137.29,46.77 v1(137.27,46.75)
  vias: v1(127.89,47.37) v1(128.78,47.37)
1V05_EC1_DVDD: length 9.5
  TOP w0.203: U49.28 v1(137.27,54.34) ; v1(133.86,54.36) 134.07,54.14 U49.36
  L3SIG w0.508: v1(137.27,54.34) 136.52,53.59 134.62,53.59 v1(133.86,54.36)
  BOTTOM w0.508: C348.1 137.29,54.32 v1(137.27,54.34) ; C349.1 134.23,54.86 133.86,54.48 v1(133.86,54.36) 132.57,54.36 132.21,54 R826.1
1V05_EC2_AVDD: length 6.1
  TOP w0.203: U46.9 v1(159.5,46.12) ; U46.3 v1(157.1,46.12) ; v1(154.69,51.05) 154.83,50.91 U46.40
  BOTTOM w0.508: C322.1 154.81,51.18 v1(154.69,51.05) 154.43,51.31 R824.2 ; v1(157.1,46.12) 157.1,46.12 C323.1 ; v1(159.5,46.12) 159.51,46.13 C321.1
  vias: v1(150.11,46.74) v1(151,46.74)
1V05_EC2_DVDD: length 9.5
  TOP w0.203: U46.36 156.3,53.51 v1(156.08,53.72) ; U46.28 v1(159.5,53.7)
  L3SIG w0.508: v1(156.08,53.72) 156.84,52.96 158.75,52.96 v1(159.5,53.7)
  BOTTOM w0.508: R824.1 154.43,53.36 154.79,53.72 v1(156.08,53.72) 156.08,53.82 156.49,54.22 C316.1 ; v1(159.5,53.7) 159.51,53.69 C317.1
1V8: length 67.6
  TOP w0.203: v1(69.09,145.16) 69.18,145.07 U20.13
  TOP w0.254: U4.29 101.37,135.4 v1(101.22,135.25)
  TOP w0.305: U107.G4 v2(92.13,127.22) ; U1.J18 v2(161.32,117.25) ; U107.J6 v2(94.53,126.42) ; U1.J14 v2(161.32,113.25) ; U1.J15 v2(161.32,114.85) ; U107.H8 v2(96.13,126.42) ; U1.G9 v2(159.72,109.25) ; U1.J16 v2(161.32,115.65) ; U107.D3 v2(91.33,130.42) ; U1.J17 v2(161.32,116.45) ; U1.J19 v2(161.32,118.05)
  TOP w0.381: U10.5 v1(106.79,119.24) ; v1(69.46,138.17) 69.53,138.24 U22.1 ; U8.5 109.54,119.83 v1(109.55,119.84) ; U9.5 v1(103.25,119.24)
  TOP w0.508: v1(124.36,123.97) 124.51,123.82 C23.1 ; R102.2 v1(69.46,138.17) ; C195.1 v1(60.54,123.79)
  BOTTOM w0.254: v1(124.36,123.97) 124.38,124 U2.7 ; U2.42 v1(134.16,124) ; U2.31 v1(134.24,129.5) ; U2.18 v1(124.39,129.5)
  BOTTOM w0.508: R7.2 73.24,115.23 v1(73.28,115.19) 73.32,115.15 R6.2 ; v1(124.39,129.5) 124.09,129.8 C24.1 ; R82.2 152.15,116.59 151.76,116.2 v1(151.38,116.2) ; C30.1 v1(103.25,119.24) ; R47.2 R41.2 R44.2 v1(117.22,130.43) ; 150.24,111.76 150.24,109.73 150.62,109.35 R188.1 ; 150.24,111.76 152.53,111.76 R939.1 ; 150.24,111.76 R5.2 v1(149.49,112.4) ; v2(92.13,127.22) 92.09,127.25 C1276.1 ; C25.1 134.54,129.8 v1(134.24,129.5) ; 35.11,44.65 J53.3 ; J53.3 36.52,44.65 ; J53.3 35.11,43.23 ; J53.3 36.52,43.23 ; v2(94.53,126.42) 95.01,126.9 C1277.1 ; R42.2 v1(104.77,123.45) ; C53.1 69.34,138.29 v1(69.46,138.17) ; v1(106.79,119.24) 106.81,119.25 C32.1 ; v1(149.61,116.84) 149.35,117.09 R195.1 ; v1(109.55,119.84) 109.61,119.9 C31.1 ; R43.2 101.48,134.99 v1(101.22,135.25) 100.96,134.99 C35.1 99.17,134.99 R952.2 R953.2 ; C1275.1 96.2,126.49 v2(96.13,126.42) ; R864.1 v1(112.14,126.37) ; v1(59.01,117.01) R9.2 R10.2 R11.2 ; v2(91.33,130.42) 91.31,130.43 C1274.1 ; C50.1 v1(69.09,145.16) ; C26.1 134.33,123.82 v1(134.16,124) ; v1(151.51,103.38) 151.51,100.33 154.05,97.79 155.54,97.79 FB13.2
  vias: v1(40.51,99.82) v1(40.51,99.06) v1(40.51,98.3) v1(41.4,99.82) v1(41.4,99.06) v1(41.4,98.3) v1(42.29,99.82) v1(42.29,99.06) v1(42.29,98.3) v1(42.8,120.14) v1(43.31,119.63) v1(52.7,97.03) v1(52.7,96.27) v1(56.13,119.51) v1(56.13,118.75) v1(56.9,119.51) v1(56.9,118.75) v1(78.36,105.66) v1(79.12,105.66) v1(93.47,139.19) v1(94.36,139.19) v1(95.25,139.19)
1V8_0641_VDD: length 8.3
  TOP w0.203: v1(240.03,137.16) 239.98,137.11 U97.16 ; v1(234.06,139.19) 234.06,139.16 234.1,139.12 U97.31
  BOTTOM w0.508: v1(234.06,139.19) 233.93,139.33 C1051.1 ; R839.1 233.9,130.94 C1049.1 233.63,130.77 ; FB55.2 233.63,130.77 ; 233.63,130.77 233.17,131.23 v1(233.17,132.08) ; R841.1 v1(239.39,139.45) ; C1050.1 239.9,137.03 v1(240.03,137.16)
1V8_0641_VDDA: length 3.7
  TOP w0.203: U97.26 236.4,139.88 236.6,140.08 v1(236.6,140.21)
  BOTTOM w0.508: R841.2 236.61,139.45 C737.1 v1(236.6,140.21) 236.6,141.19 C736.1
1V8_0641_VDDIO: length 12.4
  TOP w0.203: U97.32 233.42,138.31 v1(233.17,138.56) ; v1(239.9,135.25) 239.65,135.51 U97.12 ; v1(235.97,140.21) 236,140.17 U97.27 ; v1(236.6,133.48) 236.4,133.68 U97.5 ; U97.17 239.61,137.51 239.9,137.79 v1(240.03,137.79) ; U97.39 233.68,135.51 233.43,135.25 v1(233.43,134.74)
  BOTTOM w0.508: C1052.1 236.61,133.48 v1(236.6,133.48) ; C1045.1 235.58,139.83 v1(235.97,140.21) ; v1(233.43,134.74) 233.43,134.75 C1047.1 233.34,135.42 FB54.1 ; C1044.1 239.78,138.05 v1(240.03,137.79) ; v1(233.17,138.56) 233.18,138.55 C1046.1 ; v1(239.9,135.25) 239.52,135.25 239.27,135.51 C1048.1
1V8_0641_VDDXTAL: length 4.4
  TOP w0.203: U97.4 236,133.64 v1(235.84,133.48)
  BOTTOM w0.508: C1041.1 235.83,133.48 v1(235.84,133.48) 235.84,132.37 C1040.1 235.96,132.16 R839.2
1V8_MTR: length 119.9
  TOP w0.305: U1.F11 v2(158.92,110.85)
  TOP w0.508: J10.1 58.42,146.05 R178.2
  L3SIG w0.508: 155.32,111.12 154.94,111.12 154.05,112.01 154.05,113.54 152.02,115.57 152.02,117.98 142.75,127.25 137.67,127.25 135.89,129.03 135.89,130.3 132.72,133.48 123.32,133.48 111.89,144.91 70.74,144.91 68.83,146.81 59.18,146.81 J10.1
  BOTTOM w0.305: C208.1 158.74,110.67 v2(158.92,110.85)
1V8_SFP: length 117.6
  TOP w0.305: U1.F12 v2(158.92,111.65)
  TOP w0.508: R177.2 58.42,147.45 J9.1
  L3SIG w0.508: 155.32,113.03 155.32,113.28 152.78,115.82 152.78,118.24 143,128.02 139.19,128.02 132.97,134.24 123.57,134.24 112.14,145.67 70.99,145.67 68.45,148.21 57.66,148.21 J9.1
  BOTTOM w0.305: v2(158.92,111.65) 158.74,111.82 C192.1
1V8_SLP: length 81.5
  TOP w0.203: U97.11 239.1,134.66 v1(239.14,134.62)
  TOP w0.305: U1.J13 v2(161.32,112.45) ; U1.J12 v2(161.32,111.65) ; U1.J11 v2(161.32,110.85)
  TOP w0.381: U65.A3 v1(58.52,114.43) ; U65.P16 v1(72.52,100.43) ; 209.25,125.66 U95.2 211.15,125.66 ; U65.F8 v1(63.52,109.43) ; 209.26,125.01 U95.1 211.03,125.01 ; U65.H10 v1(66.52,107.43) ; U65.J11 v1(67.52,105.43) ; U65.C16 v1(72.52,112.43) ; U65.J9 v1(65.52,105.43) ; U65.J7 v1(62.52,105.43) ; U65.A14 v1(70.52,114.43) ; U65.H8 v1(63.52,107.43) ; U65.F9 v1(65.52,109.43) ; U65.H11 v1(67.52,107.43)
  TOP w0.508: R834.1 v1(239.01,131.58) ; R843.1 v1(241.8,133.99) ; R829.1 v1(230.63,132.97) ; v1(18.8,98.94) R757.2 18.8,99.7 C965.1 ; R844.1 v1(230.63,133.98)
  TOP w1.016: J9.2 J10.2 55.03,145.12 C209.1
  L3SIG w0.508: v1(35.56,98.68) 34.8,97.92 29.84,97.92 28.19,99.57 21.46,99.57 20.84,98.94 v1(18.8,98.94)
  L5PWR w0.508: 54.28,149.04 J9.2 54.28,147.63 ; 54.28,144.45 J10.2 54.28,145.87
  BOTTOM w0.305: R96.1 72.52,110.24 72.13,109.85 R69.2 ; v1(77.85,97.92) 77.36,98.41 U21.1
  BOTTOM w0.508: v1(151,105.28) 150.75,105.03 R876.2 ; v1(151,105.28) 151.14,105.42 R194.1 151.77,105.41 R84.2 ; v1(151,105.28) 150.74,105.54 R70.2 ; v1(65.52,109.43) 65.02,108.93 C712.1 ; v1(58.52,114.43) 58.02,113.93 C715.1 ; v1(70.52,114.43) 71.01,113.93 C1105.1 ; R81.2 74.54,102.45 v1(72.52,100.43) 72.02,99.93 C713.1 ; R84.2 R878.2 R877.2 ; R84.2 152.78,105.42 ; R84.2 R879.2 ; U65.J9 v1(65.52,105.43) ; v1(239.14,134.62) 239.39,134.37 C735.1 ; C711.1 64.01,108.93 v1(63.52,109.43) ; R83.2 R94.1 ; R94.1 72.52,112.42 v1(72.52,112.43) 72.02,112.92 C1104.1 ; R94.1 R96.1 ; v1(67.52,107.43) 67.02,107.92 C714.1 ; v1(77.85,97.92) 77.22,97.28 C52.1 ; C716.1 67.02,104.93 v1(67.52,105.43) R813.2 R98.1 R85.2 ; U65.H10 v1(66.52,107.43) ; U65.J7 v1(62.52,105.43) ; U65.H8 v1(63.52,107.43)
  vias: v1(35.56,106.17) v1(35.56,105.16) v1(35.56,104.01) v1(35.56,103) v1(35.56,101.85) v1(35.56,100.84) v1(35.56,99.7) v1(78.36,89.03) v1(78.61,97.92) v1(79.12,89.03) v1(209.3,124.46) v1(210.95,124.46) v1(211.71,124.46)
1V8_USB_OVDD: length 5.4
  TOP w0.305: U1.J9 v2(161.32,109.25) ; U1.J10 v2(161.32,110.05)
  BOTTOM w0.457: v2(157.35,102.11) 157.11,101.86 C172.1
  BOTTOM w0.508: FB13.1 157.11,98.33 C174.1 C173.1 C172.1
1V8_XGT1_VREGSRDS: length 2.4
  TOP w0.305: v1(197.52,55.01) 197.35,54.84 197.31,54.79 197.3,54.79 U101.T4 ; U101.T6 v1(195.52,55.01)
  BOTTOM w0.508: C1179.1 C1178.1 v1(197.52,55.01)
1V8_XGT2_VREGSRDS: length 2.4
  TOP w0.305: U108.T6 v1(246.32,55.01) ; v1(248.32,55.01) 248.15,54.84 248.11,54.79 248.1,54.79 U108.T4
  BOTTOM w0.508: v1(248.32,55.01) C1346.1 C1347.1
1V35: length 20.3
  TOP w0.305: U1.M27 v2(163.72,124.45) ; U1.P27 v2(165.32,124.45) ; U1.AA27 v2(171.72,124.45) ; U1.D27 v2(157.32,124.45) ; U1.L21 v2(162.92,119.65) ; U1.U21 v2(168.52,119.65) ; U1.M21 v2(163.72,119.65) ; U1.AD27 v2(174.12,124.45) ; U1.W27 v2(170.12,124.45) ; U1.K27 v2(162.12,124.45) ; U1.N21 v2(164.52,119.65) ; U1.R21 v2(166.92,119.65) ; U1.F27 v2(158.92,124.45) ; U1.AF27 v2(175.72,124.45) ; U1.H27 v2(160.52,124.45) ; U1.U27 v2(168.52,124.45) ; U1.P21 v2(165.32,119.65) ; U1.K21 v2(162.12,119.65) ; U1.T21 v2(167.72,119.65)
  TOP w0.508: C1260.1 v1(157.61,164.2) ; C1254.1 v1(180.21,164.2) ; R4.1 v1(161.68,164.2) C1259.1 ; C1261.1 v1(163.33,164.2) ; C1255.1 v1(183.25,164.2) ; C1257.1 v1(170.43,164.2) ; C1256.1 v1(174,164.2) ; C1258.1 v1(166.38,164.2)
  BOTTOM w0.457: v2(170.12,124.45) 169.92,124.64 R1.1
  BOTTOM w0.508: R192.2 v1(191.38,127.13) ; R189.2 v1(191.38,123.32)
  vias: v1(197.99,134.37) v1(197.99,133.6) v1(198.75,135.13) v1(198.75,134.37) v1(198.75,133.6) v1(198.75,129.16) v1(198.75,128.14) v1(199.52,135.89) v1(199.52,135.13) v1(199.52,134.37) v1(199.52,133.6) v1(199.52,129.16) v1(199.52,128.14)
1V35_SLP: length 129.7
  TOP w0.305: U81.2 227.83,148.84 227.97,148.97
  TOP w0.508: C1259.2 C7.1 ; C7.1 159.9,163.19 ; C7.1 C1260.2 C12.1 ; C7.1 159.89,161.37 J1.173 ; 154.67,163.19 154.43,162.96 v1(154.43,162.56) ; 154.67,163.19 R2.1 ; 154.67,163.19 C2.1 155.2,163.2 ; J1.62 168.91,155.64 C10.1 ; C13.1 184.91,155.64 J1.78 ; J1.189 175.89,161.37 C998.1 ; J1.60 166.88,155.61 C9.1 ; C6.1 C1255.2 184.4,163.2 C999.1 184.41,161.84 J1.197 ; C6.1 180.92,163.14 J1.194 ; C6.1 180.98,163.19 ; C6.1 C1254.2 C4.1 ; v1(224.4,138.55) C941.1 222.63,138.55 R736.2 ; 168.78,163.2 C1257.2 169.93,163.2 ; 168.78,163.2 C5.1 C1258.2 C11.1 ; 168.78,163.2 168.92,163.07 J1.182 ; C998.1 C4.1 ; C998.1 C1256.2 173.11,163.2 172.92,163.4 ; 172.92,163.4 C1.1 172.58,163.2 C8.1 169.93,163.2 ; 172.92,163.4 J1.186 ; J1.183 169.93,161.36 169.93,163.2 ; C3.1 160.91,155.64 J1.54 ; C11.1 165.92,162.89 J1.179 ; C11.1 C1261.2 ; C4.1 177.93,161.36 J1.191 ; C14.1 178.94,155.62 J1.72 ; C12.1 156.92,163.13 J1.170 ; C12.1 155.2,163.2 ; 155.2,163.2 155.45,162.96 v1(155.45,162.56)
  L4PWR w0.508: 172.39,158.92 J1.186 ; J1.186 173.45,158.92 ; J1.186 172.39,159.98 ; J1.186 173.45,159.98 ; 181.39,157.02 J1.75 ; J1.75 182.45,157.02 ; J1.75 181.39,158.08 ; J1.75 182.45,158.08 ; J1.72 179.45,155.12 ; J1.72 179.45,156.18 ; J1.72 178.39,156.18 ; J1.72 178.39,155.12 ; J1.60 167.45,156.18 ; J1.60 166.39,156.18 ; J1.60 166.39,155.12 ; J1.60 167.45,155.12 ; 163.39,157.02 J1.57 ; J1.57 164.45,158.08 ; J1.57 164.45,157.02 ; J1.57 163.39,158.08 ; 172.39,155.12 J1.66 ; J1.66 172.39,156.18 ; J1.66 173.45,155.12 ; J1.66 173.45,156.18 ; 168.39,158.92 J1.182 ; J1.182 169.45,159.98 ; J1.182 168.39,159.98 ; J1.191 178.45,160.82 ; J1.191 177.39,161.88 ; J1.191 178.45,161.88 ; J1.191 177.39,160.82 ; 162.39,159.98 J1.176 ; J1.176 162.39,158.92 ; J1.176 163.45,158.92 ; J1.176 163.45,159.98 ; 175.39,157.02 J1.69 ; J1.69 176.45,157.02 ; J1.69 176.45,158.08 ; J1.69 175.39,158.08 ; J1.54 161.45,155.12 ; J1.54 160.39,155.12 ; J1.54 161.45,156.18 ; J1.54 160.39,156.18 ; 184.39,155.12 J1.78 ; J1.78 184.39,156.18 ; J1.78 185.45,156.18 ; J1.78 185.45,155.12 ; 183.39,160.82 J1.197 ; J1.197 183.39,161.88 ; J1.197 184.45,160.82 ; J1.197 184.45,161.88 ; J1.51 158.45,158.08 ; J1.51 157.39,158.08 ; J1.51 157.39,157.02 ; J1.51 158.45,157.02 ; J1.194 181.45,158.92 ; J1.194 180.39,159.98 ; J1.194 181.45,159.98 ; J1.194 180.39,158.92 ; 168.39,156.18 J1.62 ; J1.62 169.45,155.12 ; J1.62 169.45,156.18 ; J1.62 168.39,155.12 ; J1.65 172.45,157.02 ; J1.65 171.39,157.02 ; J1.65 171.39,158.08 ; J1.183 170.45,161.88 ; J1.183 169.39,161.88 ; J1.183 169.39,160.82 ; J1.170 157.45,158.92 ; J1.170 156.39,158.92 ; J1.170 157.45,159.98 ; J1.170 156.39,159.98 ; 175.39,161.88 J1.189 ; J1.189 176.45,161.88 ; J1.189 176.45,160.82 ; 165.39,161.88 J1.179 166.45,161.88 ; J1.173 160.45,160.82 ; J1.173 160.45,161.88 ; J1.173 159.39,161.88
  vias: v1(205.87,139.57) v1(205.87,138.56) v1(205.87,137.41) v1(205.87,136.4) v1(205.87,135.25) v1(205.87,134.24) v1(205.87,133.1) v1(205.87,132.08) v1(228.73,154.05) v1(228.73,153.29) v1(229.49,154.05) v1(229.49,153.29)
2V1: length 35.2
  TOP w0.305: U108.C3 v1(249.32,41.01) ; U101.C3 v1(198.52,41.01) ; U108.A3 v1(249.32,39.01) ; U108.C7 v1(245.32,41.01) ; U101.A3 v1(198.52,39.01) ; U108.A9 v1(243.32,39.01) ; U101.A7 v1(194.52,39.01) ; U101.C5 v1(196.52,41.01) ; U108.A7 v1(245.32,39.01) ; U101.C9 v1(192.52,41.01) ; U101.C7 v1(194.52,41.01) ; U101.A9 v1(192.52,39.01) ; U108.C9 v1(243.32,41.01) ; U108.C5 v1(247.32,41.01) ; U108.A5 v1(247.32,39.01) ; U101.A5 v1(196.52,39.01)
  TOP w0.508: v1(260.74,65.91) R929.2 261.5,65.91 C1243.1
  L3SIG w0.508: v1(260.74,65.91) 260.74,63.87 261.37,63.25 261.37,56.39 259.72,54.74 259.72,49.91 v1(260.48,49.15)
  BOTTOM w0.508: v1(252.48,49.91) 252.03,49.91 FB69.2 251.98,49.15 v1(252.48,49.15) ; v1(201.68,49.91) 201.23,49.91 FB68.2 201.18,49.15 v1(201.68,49.15)
  vias: v1(192.52,38.1) v1(194.52,38.1) v1(196.52,38.1) v1(198.52,38.1) v1(204.98,38.73) v1(204.98,37.72) v1(206.38,38.73) v1(206.38,37.72) v1(207.77,38.73) v1(207.77,37.72) v1(261.49,49.15) v1(262.64,49.15) v1(263.65,49.15) v1(264.8,49.15) v1(265.81,49.15) v1(266.95,49.15) v1(267.97,49.15)
2V1_XGT1_VDDSRDS: length 8.8
  TOP w0.305: U101.P4 197.02,52.51 ; 197.02,52.51 v1(197.52,53.01) 198.02,53.5 U101.R3 v1(198.52,54.01) ; 197.02,52.51 v1(197.52,52.01)
  BOTTOM w0.508: v1(197.52,53.01) v1(197.52,52.01) 197.52,51.81 C1184.1 ; C1185.1 198.52,55.24 C1181.1
  BOTTOM w0.762: C1184.1 197.82,51.23 198.82,50.23 FB68.1
  vias: v1(198.52,55.01)
2V1_XGT1_XTAL: length 4.3
  TOP w0.305: U101.E18 v1(182.52,43.01)
  BOTTOM w0.508: FB58.1 181.09,40.86 C1194.1 181.55,43.01 v1(182.52,43.01)
2V1_XGT2_VDDSRDS: length 8.8
  TOP w0.305: v1(249.32,54.01) U108.R3 v1(248.32,53.01) U108.P4 v1(248.32,52.01)
  BOTTOM w0.508: C1352.1 248.32,51.81 v1(248.32,52.01) v1(248.32,53.01) ; C1353.1 249.32,55.24 C1349.1
  BOTTOM w0.762: FB69.1 249.62,50.2 248.62,51.2 C1352.1
  vias: v1(249.32,55.01)
2V1_XGT2_XTAL: length 4.3
  TOP w0.305: U108.E18 v1(233.32,43.01)
  BOTTOM w0.508: FB66.1 231.89,40.86 C1362.1 232.35,43.01 v1(233.32,43.01)
2V5: length 120.8
  TOP w0.203: v1(162.31,48.51) 162.3,48.51 U46.15 ; U46.21 v1(162.29,50.91)
  TOP w0.305: U108.L16 v1(235.32,50.01) ; U101.J3 v1(198.52,48.01) ; U101.E3 v1(198.52,43.01) ; U101.L16 v1(184.52,50.01) ; U108.J3 v1(249.32,48.01) ; U1.V8 v2(169.32,108.45) ; U101.K16 v1(184.52,49.01) ; U101.K4 v1(197.52,49.01) ; U1.W8 v2(170.12,108.45) ; U108.K16 v1(235.32,49.01) ; U108.K4 v1(248.32,49.01) ; U108.E3 v1(249.32,43.01)
  TOP w0.508: R232.2 v1(167.39,45.47) ; R230.2 v1(167.39,48.51) ; U102.7 U102.8 211.07,45.09 C1121.1 v1(211.84,46.48) ; U109.7 U109.8 261.87,45.09 C1289.1 v1(262.64,46.48) ; R966.2 v1(227.33,49.02) ; R941.2 v1(176.53,49.02) ; U109.3 v1(257.68,42.42) ; R976.2 v1(258.44,45.73) ; R943.2 v1(207.76,45.73) ; R138.2 v1(151.76,60.71) ; R942.2 v1(179.57,57.27) ; R229.2 v1(167.39,47.5) ; R965.2 v1(230.37,57.27) ; R231.2 v1(167.39,49.53) ; U102.3 v1(206.88,42.42)
  L3SIG w0.508: v1(252.98,42.04) 252.98,24.38 251.59,22.99 251.59,16.38 249.17,13.97 246,13.97 v1(242.82,10.79) ; v1(192.02,10.79) 195.2,13.97 198.37,13.97 200.79,16.38 200.79,22.99 202.18,24.38 v1(202.18,42.04)
  L5PWR w0.508: J55.6 224.86,53.01 ; J55.6 223.45,54.43 ; J55.6 224.86,54.43 ; J55.6 223.45,53.01 ; 172.65,53.01 J51.6 ; J51.6 172.65,54.43 ; J51.6 174.06,53.01 ; J51.6 174.06,54.43
  BOTTOM w0.203: v1(184.52,50.01) 184.51,50.01 R886.1 ; R958.1 235.31,50.01 v1(235.32,50.01)
  BOTTOM w0.508: C315.1 162.27,50.93 v1(162.29,50.91) ; FB59.2 v1(192.02,10.79) ; R957.2 v1(230.31,49.81) ; C314.1 v1(162.31,48.51) ; R970.2 249.32,48 v1(249.32,48.01) ; FB67.2 v1(242.82,10.79) ; v1(198.52,48.01) 198.52,48 R897.2 ; R884.2 v1(179.51,49.81)
  vias: v1(77.98,78.87) v1(77.98,78.11) v1(77.98,77.34) v1(78.87,78.87) v1(78.87,78.11) v1(78.87,77.34) v1(79.76,78.87) v1(79.76,78.11) v1(79.76,77.34) v1(179.2,77.98) v1(180.09,77.98) v1(180.97,77.98)
2V5_SLP: length 36.4
  TOP w0.203: U49.15 140.08,49.15 v1(140.08,49.15) ; U49.21 v1(140.06,51.55)
  TOP w0.305: U1.U8 v2(168.52,108.45) ; U1.T8 v2(167.72,108.45)
  TOP w0.381: C58.1 150.85,59.32 U23.5 ; U24.5 150.85,56.53 C57.1
  TOP w0.508: v1(146.81,54.74) 146.43,55.12 R131.1 ; v1(56.27,77.99) R774.2 56.26,78.75 C988.1 ; R258.2 v1(145.16,48.13) ; R259.2 v1(145.16,49.15) ; R132.1 v1(146.43,57.53) ; C58.1 v1(151.76,59.17) ; R260.2 v1(145.16,50.16) ; C57.1 v1(151,57.15)
  L3SIG w0.508: v1(73.03,77.72) 71.25,75.95 58.31,75.95 v1(56.27,77.99)
  BOTTOM w0.508: C347.1 v1(140.08,49.15) ; R72.2 v1(173.1,100.2) R71.2 R875.1 R881.1 ; v1(140.06,51.55) 140.05,51.56 C346.1
  vias: v1(73.03,85.22) v1(73.03,84.2) v1(73.03,83.06) v1(73.03,82.04) v1(73.03,80.9) v1(73.03,79.88) v1(73.03,78.74)
3V3: length 168.5
  TOP w0.203: U46.44 154.98,49.31 v1(154.69,49.02) 154.8,48.91 U46.45 ; U20.16 67.98,145.07 v1(68.07,145.16) ; v1(155.19,52.96) 155.5,52.66 U46.37 ; v1(154.69,50.42) 154.78,50.51 U46.41 ; U46.6 v1(158.3,46.12)
  TOP w0.254: v1(232.54,101.35) 232.79,101.1 U110.6 ; U110.10 234.45,98.24 234.2,97.99 C1375.1 ; C1377.1 234.2,104.77 234.45,104.52 U110.1 ; U4.43 101.25,128.4 101.24,128.4 v1(101.09,128.4)
  TOP w0.305: U19.2 257.91,153.64 258.06,153.8 258.56,153.8 ; U1.P8 v2(165.32,108.45) ; 258.56,153.8 258.56,155.19 v1(258.31,155.44) ; 258.56,153.8 U19.1 ; U19.16 258.56,144.91 C48.1 ; U1.N8 v2(164.52,108.45) ; C742.1 156.89,67.51 U68.16 ; C743.1 149.11,63.51 149.4,63.8 U68.10 ; v1(257.82,144.9) 257.31,144.9 256.61,145.6 U19.13 ; U1.R8 v2(166.92,108.45) ; U1.M8 v2(163.72,108.45)
  TOP w0.381: U41.16 126.76,70.35 126.5,70.6 C286.1 ; J43.12 v1(270.36,154.92) ; U22.5 v1(67.63,138.11) ; C272.1 133.6,71.11 133.6,70.61 133.87,70.35 U39.16 ; J43.16 v1(270.36,153.65) ; J43.14 v1(270.36,154.28) ; J43.10 v1(270.36,155.55)
  TOP w0.508: J18.B8 276.61,89.64 ; J18.B8 276.61,88.51 ; J18.B8 275.48,88.51 ; J18.B8 275.48,89.64 ; J20.52 v1(79.25,213.48) 79.25,213.47 C605.1 ; R402.2 R403.2 v1(265.94,87.88) ; R991.1 v1(223.71,126.49) ; R989.1 227.97,126.49 v1(228.16,126.68) ; C272.1 v1(133.61,71.87) ; C742.1 v1(157.85,67.3) ; 270.98,90.64 J18.A9 ; J18.A9 270.98,89.51 ; J18.A9 272.11,89.51 ; J18.A9 272.11,90.64 ; R156.2 v1(102.99,38.48) ; R155.2 v1(98.29,38.35) ; 268.98,91.64 J18.A10 ; J18.A10 270.11,91.64 ; J18.A10 268.98,90.51 ; J18.A10 270.11,90.51 ; v1(161.29,46.86) 161.29,46.35 163.07,44.58 164.43,44.58 FB26.1 ; 260.73,140.68 259.68,140.68 259.08,140.08 U13.2 256.04,140.08 C36.1 C37.1 v1(254.13,140.22) ; 275.48,90.51 J18.B10 ; J18.B10 276.61,91.64 ; J18.B10 275.48,91.64 ; J18.B10 276.61,90.51 ; R234.2 v1(152.15,54.36) ; FB70.1 v1(256.83,107.78) ; J19.2 v1(189.48,213.08) 189.51,213.11 C603.1 ; R57.2 v1(269.62,134.87) ; C1377.1 v1(233.43,105.28) ; C1376.1 v1(232.54,101.35) ; R411.2 v1(91.31,193.04) ; J20.2 v1(79.25,190.28) 79.22,190.25 C604.1 ; FB71.1 v1(230.47,127.67) ; R871.2 R872.2 R55.2 270.51,137.16 v1(270.13,136.78) ; R410.2 R409.2 v1(252.6,154.43) ; C1375.1 v1(233.43,97.41) ; C601.1 79.23,202.29 v1(79.25,202.28) J20.24 ; J19.24 v1(189.48,201.08) 189.5,201.06 C600.1 ; C743.1 v1(149.11,62.11) ; R996.1 v1(259.21,119.76) ; v1(104.77,35.43) 104.51,35.17 R159.2 ; v1(152.4,70.87) 152.36,70.9 FB52.1 ; R822.1 155.07,53.08 v1(155.19,52.96) ; R849.1 R850.1 R851.1 R852.1 264.68,145.92 v1(264.8,145.8) ; R407.2 R406.2 256.82,143.9 v1(257.82,144.9) C48.1 ; R399.2 v1(177.42,210.31) ; R549.1 v1(146.44,62.24) ; R235.2 158.12,56.13 158.62,55.63 159,55.63 R823.1 159,54.99 v1(159.13,54.86) ; R54.2 v1(254.63,133.1) 254.64,133.1 R56.2 ; R405.2 R408.2 v1(265.94,94.62) ; v1(225.04,124.33) 225.42,123.95 R994.1 ; R88.2 R89.2 242.18,152.39 242.19,152.4 ; R998.1 v1(225.42,119.76) ; R990.1 v1(256.92,117.6) ; C293.1 241.04,152.4 U44.8 ; R988.1 v1(256.17,113.8) ; v1(258.31,155.44) R99.1 R404.2 R398.2 ; J19.52 v1(189.48,189.88) 189.48,189.88 C602.1 ; R992.1 v1(263.78,119.76) ; R158.2 100.2,35.18 v1(99.94,35.43) ; C286.1 v1(126.5,71.87)
  L4PWR w0.508: 275.48,90.51 J18.B10 ; J18.B10 275.48,91.64 ; J18.B10 276.61,90.51 ; J18.B10 276.61,91.64 ; 275.48,89.64 J18.B8 ; J18.B8 276.61,88.51 ; J18.B8 275.48,88.51 ; J18.B8 276.61,89.64 ; 268.98,90.51 J18.A10 ; J18.A10 268.98,91.64 ; J18.A10 270.11,90.51 ; J18.A10 270.11,91.64 ; 270.98,90.64 J18.A9 ; J18.A9 272.11,90.64 ; J18.A9 270.98,89.51 ; J18.A9 272.11,89.51 ; 40.19,44.65 J53.1 ; J53.1 41.6,43.23 ; J53.1 40.19,43.23 ; J53.1 41.6,44.65
  BOTTOM w0.508: v1(158.3,46.12) 158.37,46.19 C326.1 ; C319.1 154.94,50.16 v1(154.69,50.42) ; Q50.2 v1(34.79,36.95) ; C51.1 67.82,138.3 v1(67.63,138.11) ; C49.1 v1(68.07,145.16) ; v1(154.69,49.02) C325.1 155.46,48.04 C324.1 ; R65.2 v1(153.42,96.01) ; v1(160.02,97.16) 160.44,97.57 FB12.2 ; v1(155.19,52.96) 155.46,52.7 C320.1 ; v1(164.47,101.09) 164.21,101.35 R73.2 ; Q1.1 166.38,92.51 Q2.1 167.33,93.6 v1(167.77,93.6) ; R66.2 v1(157.48,96.01) ; R74.2 v1(167.01,101.1) ; v1(169.29,96.65) 169.04,96.9 R87.2 R86.2 R95.2 R97.2 ; v1(101.09,128.4) 101.1,128.4 C34.1 C33.1 ; C181.1 v1(173.86,93.09)
  vias: v1(21.59,153.42) v1(21.59,150.24) v1(21.59,145.92) v1(21.72,139.45) v1(32.64,125.73) v1(32.64,124.84) v1(33.53,125.73) v1(33.53,124.84) v1(34.42,125.73) v1(34.42,124.84) v1(35.31,125.73) v1(35.31,124.84) v1(43.05,89.79) v1(43.05,88.52) v1(43.05,87.25) v1(44.07,89.79) v1(44.07,88.52) v1(44.07,87.25) v1(45.09,89.79) v1(45.09,88.52) v1(45.09,87.25) v1(45.72,139.45) v1(46.47,139.45) v1(88.9,129.92) v1(241.05,154.05) v1(241.05,153.16) v1(241.94,154.05) v1(241.94,153.16)
3V3_859S0212I_1: length 12.7
  TOP w0.305: C1390.1 259.22,109.1 U113.9 ; U113.16 263.77,109.1 C1391.1
  TOP w0.508: v1(257.81,110.24) FB70.2 258.53,109.39 258.83,109.09 C1390.1 ; C1391.1 v1(263.02,109.09)
  BOTTOM w0.508: v1(263.02,109.09) 258.96,109.09 v1(257.81,110.24)
3V3_859S0212I_2: length 12.7
  TOP w0.305: U112.16 233.44,125.21 233.43,125.22 ; C1393.1 236.35,120.14 235.83,120.66 U112.9 233.82,120.66 233.81,120.65
  TOP w0.508: FB71.2 233.18,126.75 C1392.1 233.43,121.02 233.81,120.65
3V3_PGOOD: length 52
  TOP w0.127: v1(48.64,103.38) 50.19,104.93 U65.K1 ; U90.3 19.17,91.05 v1(18.8,90.68)
  L3SIG w0.102: v1(18.8,90.68) 20.83,90.68 22.23,89.28 27.43,89.28 30.35,92.2 36.7,92.2 39.37,94.87 39.37,100.33 41.27,102.23 44.51,102.23 45.66,103.38 v1(48.64,103.38)
  BOTTOM w0.127: R771.2 v1(18.8,90.68)
3V3_SLP: length 179.8
  TOP w0.203: U49.41 132.55,51.15 v1(132.46,51.05) ; U49.45 132.57,49.55 v1(132.46,49.66) 132.75,49.95 U49.44 ; v1(132.97,53.59) 133.27,53.29 U49.37 ; U49.6 v1(136.07,46.75)
  TOP w0.254: v1(110.74,94.11) 110.74,94.23 111.14,94.63 U111.6
  TOP w0.305: U100.8 107.31,87.67 C1115.1 ; 228.47,144.53 228.33,144.67 U81.10
  TOP w0.381: U65.J6 v1(61.52,105.43) ; U65.L8 v1(63.52,103.43) ; U65.L9 v1(65.52,103.43) ; U65.C1 v1(56.52,112.43) ; U65.T14 v1(70.52,98.43) ; U65.H6 v1(61.52,107.43) ; U65.T3 v1(58.52,98.43) ; C1016.1 211.83,127.25 211.2,127.25 210.91,126.96 U95.4 ; U65.P1 v1(56.52,100.43)
  TOP w0.508: 222.39,159.98 J1.236 ; J1.236 222.39,158.92 ; J1.236 223.45,158.92 ; J1.236 223.45,159.98 ; v1(212.6,127.25) 212.59,127.25 C1016.1 ; U104.5 99.48,100.2 C1223.1 v1(97.79,100.2) ; v1(136.91,55.5) 136.78,55.63 R252.1 136.77,56.26 136.4,56.26 135.9,56.76 R264.2 ; J1.117 224.45,157.02 ; J1.117 224.45,158.08 ; J1.117 223.39,158.08 ; J1.117 223.39,157.02 ; R204.2 58.17,124.59 57.02,123.44 v1(56.39,123.44) ; v1(133.1,44.96) 135,43.05 FB29.1 ; D43.2 26.54,4.44 26.04,3.94 22.73,3.94 22.23,4.45 D44.2 22.23,9.14 16,15.37 16,54.99 21.46,60.45 v1(21.46,63.75) C1002.1 20.27,64.52 U83.4 19.17,63.42 R705.2 ; v1(18.8,88.14) 18.8,88.15 R772.2 R771.1 C989.1 ; v1(53.09,129.54) 53.08,129.53 R703.2 R704.2 ; v1(106.81,90.17) 107.31,89.67 C1115.1 108.46,89.28 109.09,88.65 R940.2 ; v1(238.51,146.94) R91.2 R90.2 ; R263.2 v1(129.93,54.99) ; v1(132.97,53.59) 132.85,53.71 R825.1 ; R498.1 R497.1 10.54,127.5 10.54,124.97 11.3,124.21 13.08,124.21 J26.4
  L3SIG w0.508: v1(18.8,88.14) 20.83,88.14 21.34,88.65 29.08,88.65 30.1,87.63 v1(35.56,87.63)
  L4PWR w0.508: J26.4 15.06,122.23 ; J26.4 15.06,123.64 ; J26.4 13.64,123.64 ; J26.4 13.64,122.23
  BOTTOM w0.305: U21.5 77.36,100.7 76.59,101.46 C54.1 75.82,101.85 74.55,100.58 74.55,98.43 73.79,97.66 71.28,97.66 v1(70.52,98.43) ; U45.1 146.35,121.5 146.06,121.79 C295.1
  BOTTOM w0.508: v1(132.46,49.66) 132.59,49.78 C357.1 133.23,48.67 C356.1 ; C358.1 136.14,46.82 v1(136.07,46.75) ; C707.1 57.01,99.93 v1(56.52,100.43) ; C350.1 132.72,50.8 v1(132.46,51.05) ; C1379.1 110.88,94.24 v1(110.74,94.11) ; v1(65.52,103.43) 65.02,103.92 C1103.1 ; v1(61.52,107.43) 62.01,107.92 C706.1 ; v1(63.52,103.43) 64.01,103.92 C1102.1 ; v1(145.41,122.17) 145.03,122.56 R853.2 C295.1 ; v1(58.52,98.43) 58.02,98.92 C708.1 ; v1(56.52,112.43) 57.01,112.92 C705.1 ; v1(61.52,105.43) 62.01,104.93 C709.1 ; v1(132.97,53.59) 133.23,53.33 C351.1 ; R1016.2 v1(65.15,96.52) ; v1(70.52,98.43) 71.01,98.92 C710.1 ; R771.1 v1(18.8,88.14)
  vias: v1(35.56,95.76) v1(35.56,94.74) v1(35.56,93.73) v1(35.56,92.71) v1(35.56,91.69) v1(35.56,90.68) v1(35.56,89.66) v1(35.56,88.65) v1(35.56,86.61) v1(43.81,120.14) v1(46.1,111.12) v1(46.1,110.36) v1(229.23,164.21) v1(229.87,163.45) v1(231.27,144.14) v1(231.27,143.38) v1(232.03,144.14) v1(232.03,143.38)
3V3_USB_HVDD: length 5.6
  TOP w0.305: U1.J8 v2(161.32,108.45) ; U1.K8 v2(162.12,108.45)
  BOTTOM w0.457: v2(159.64,102.11) 159.51,102.11 159.14,101.73 C160.1
  BOTTOM w0.508: FB12.1 159.14,98.34 C161.1 C162.1 C160.1
3V3A_843002: length 4.7
  TOP w0.305: U68.8 147.47,65.56 C751.1
  TOP w0.508: C751.1 147.44,64.47 C750.1 147.44,64.05 R549.2
3V3O_843002: length 13.7
  TOP w0.305: C747.1 147.45,69.46 U68.2 ; C746.1 155.15,71.57 U68.20
  TOP w0.508: C746.1 154.09,71.63 FB52.2 153.96,70.83 v1(154.05,70.74) ; C747.1 v1(147.45,70.23)
  L6SIG w0.508: v1(154.05,70.74) 153.27,69.95 147.72,69.95 v1(147.45,70.23)
5V0_SB: length 20.8
  TOP w0.254: U84.7 10.23,63.76 10.39,63.6 10.39,63.41 10.23,63.26 9.78,63.26 ; 9.78,63.26 10.03,63 ; 9.78,63.26 U84.8
  TOP w0.508: R710.2 v1(7.11,66.8) ; 10.03,63 C898.1 v1(9.28,61.84) 8.52,61.84 8.13,62.23 R715.1 ; U85.5 11.56,60.37 C897.1 v1(10.79,59.31) ; R711.2 14.73,60.71 v1(14.48,60.45)
  TOP w1.016: J37.9 14.28,78.67 ; J37.9 12.3,78.67 ; J37.9 12.3,80.65 ; J37.9 14.28,80.65
  BOTTOM w1.016: J37.9 14.28,78.67 ; J37.9 14.28,80.65 ; J37.9 12.3,80.65 ; J37.9 12.3,78.67
  vias: v3(11.81,80.39) v3(11.81,78.99) v3(14.73,80.39) v3(14.73,78.99)
5V0_SLP: length 164.8
  TOP w0.254: C1057.2 60.69,76.81 U91.10 ; C1211.1 104.51,100.94 U103.10 ; U86.10 197.88,81.81 C928.2 ; U89.10 23.23,97.77 C951.2 ; C929.2 218.2,140.49 U87.10 ; U105.10 206.61,61.48 C1226.2 ; C1227.2 259.56,61.48 U106.10 ; v1(113.54,26.48) 113.6,26.54 U38.5 ; C1055.2 23.23,108.56 U88.10 ; U90.10 23.23,86.97 C974.2
  TOP w0.508: v1(219.46,131.7) R728.1 R734.1 ; R752.1 v1(18.03,112.52) ; R768.1 R764.1 v1(59.44,85.6) ; R737.1 v1(203.07,77.85) ; v1(22.48,108.46) C1055.2 ; v1(22.48,86.87) C974.2 ; v1(59.94,76.71) C1057.2 ; R732.1 R730.1 v1(199.14,73.03) ; v1(268.35,62.74) R921.1 R927.1 ; R739.1 v1(223.39,136.52) ; v1(21.97,95.76) R765.1 R770.1 ; v1(215.39,62.73) R923.1 R925.1 ; R908.1 v1(99.31,104.9) ; v1(21.97,117.35) R746.1 R750.1 ; R756.1 v1(18.03,101.73) ; R754.1 R747.1 v1(21.97,106.55) ; R706.2 v1(10.55,69.73) ; R906.1 R904.1 v1(103.25,109.73) ; v1(198.63,81.92) C928.2 ; v1(218.95,140.59) C929.2 ; R931.1 v1(210.57,66.67) ; v1(206.5,62.22) C1226.2 ; v1(22.48,97.66) C951.2 ; R773.1 v1(55.5,80.77) ; R932.1 v1(263.53,66.68) ; v1(259.46,62.23) C1227.2 ; C1211.1 v1(103.76,100.84)
  TOP w1.016: 6.8,74.47 J37.20 ; J37.20 8.78,76.45 ; J37.20 8.78,74.47 ; J37.20 6.8,76.45 ; 12.3,101.65 J37.4 ; J37.4 14.28,101.65 ; J37.4 12.3,99.67 ; J37.4 14.28,99.67 ; 6.8,80.65 J37.19 ; J37.19 6.8,78.67 ; J37.19 8.78,78.67 ; J37.19 8.78,80.65 ; 12.3,91.27 J37.6 ; J37.6 12.3,93.25 ; J37.6 14.28,91.27 ; J37.6 14.28,93.25
  L3SIG w1.016: 12.3,91.27 J37.6 ; J37.6 14.28,91.27 ; J37.6 14.28,93.25 ; J37.6 12.3,93.25 ; 6.8,80.65 J37.19 ; J37.19 8.78,78.67 ; J37.19 8.78,80.65 ; J37.19 6.8,78.67 ; J37.20 8.78,74.47 ; J37.20 8.78,76.45 ; J37.20 6.8,74.47 ; J37.20 6.8,76.45 ; J37.4 14.28,101.65 ; J37.4 14.28,99.67 ; J37.4 12.3,99.67 ; J37.4 12.3,101.65
  L5PWR w1.016: J37.20 8.78,76.45 ; J37.20 6.8,74.47 ; J37.20 8.78,74.47 ; J37.20 6.8,76.45 ; 12.3,91.27 J37.6 ; J37.6 14.28,91.27 ; J37.6 12.3,93.25 ; J37.6 14.28,93.25 ; J37.4 14.28,99.67 ; J37.4 12.3,101.65 ; J37.4 14.28,101.65 ; J37.4 12.3,99.67 ; J37.19 8.78,78.67 ; J37.19 8.78,80.65 ; J37.19 6.8,80.65 ; J37.19 6.8,78.67
  L6SIG w1.016: 6.8,80.65 J37.19 ; J37.19 6.8,78.67 ; J37.19 8.78,78.67 ; J37.19 8.78,80.65 ; 6.8,76.45 J37.20 ; J37.20 8.78,74.47 ; J37.20 8.78,76.45 ; J37.20 6.8,74.47 ; 12.3,91.27 J37.6 ; J37.6 14.28,93.25 ; J37.6 12.3,93.25 ; J37.6 14.28,91.27 ; 12.3,99.67 J37.4 ; J37.4 14.28,101.65 ; J37.4 14.28,99.67 ; J37.4 12.3,101.65
  BOTTOM w0.508: v1(10.55,69.73) 10.55,73.53 v3(9.27,74.8)
  BOTTOM w1.016: 12.3,101.65 J37.4 ; J37.4 12.3,99.67 ; J37.4 14.28,99.67 ; J37.4 14.28,101.65 ; 6.8,78.67 J37.19 ; J37.19 8.78,78.67 ; J37.19 8.78,80.65 ; J37.19 6.8,80.65 ; 12.3,91.27 J37.6 ; J37.6 14.28,93.25 ; J37.6 12.3,93.25 ; J37.6 14.28,91.27 ; 6.8,76.45 J37.20 ; J37.20 8.78,76.45 ; J37.20 6.8,74.47 ; J37.20 8.78,74.47
  vias: v1(24.38,115.44) v1(24.38,114.81) v1(24.38,104.65) v1(24.38,104.01) v1(24.38,93.85) v1(24.38,93.22) v1(25.15,115.44) v1(25.15,114.81) v1(25.15,104.65) v1(25.15,104.01) v1(25.15,93.85) v1(25.15,93.22) v1(25.91,115.44) v1(25.91,114.81) v1(25.91,104.65) v1(25.91,104.01) v1(25.91,93.85) v1(25.91,93.22) v1(61.85,83.69) v1(61.85,83.06) v1(62.61,83.69) v1(62.61,83.06) v1(63.37,83.69) v1(63.37,83.06) v1(99.05,30.35) v1(99.05,29.59) v1(99.82,30.35) v1(99.82,29.59) v1(102.86,30.35) v1(102.86,29.59) v1(103.63,30.35) v1(103.63,29.59) v1(105.66,107.82) v1(105.66,107.19) v1(106.43,107.82) v1(106.43,107.19) v1(107.19,107.82) v1(107.19,107.19) v1(195.2,75.57) v1(195.2,74.93) v1(195.96,75.57) v1(195.96,74.93) v1(196.72,75.57) v1(196.72,74.93) v1(212.85,60.32) v1(212.85,59.56) v1(212.85,58.8) v1(213.49,60.32) v1(213.49,59.56) v1(213.49,58.8) v1(214,134.24) v1(214,133.6) v1(214.76,134.24) v1(214.76,133.6) v1(215.52,134.24) v1(215.52,133.6) v1(215.65,75.44) v1(215.65,74.68) v1(216.28,134.24) v1(216.28,133.6) v1(216.41,75.44) v1(216.41,74.68) v1(217.04,134.24) v1(217.04,133.6) v1(217.17,75.44) v1(217.17,74.68) v1(217.93,75.44) v1(217.93,74.68) v1(218.19,123.06) v1(218.19,122.3) v1(218.69,75.44) v1(218.69,74.68) v1(218.95,123.06) v1(218.95,122.3) v1(219.71,123.06) v1(219.71,122.3) v1(220.47,123.06) v1(220.47,122.3) v1(265.81,60.32) v1(265.81,59.56) v1(265.81,58.8) v1(266.45,60.32) v1(266.45,59.56) v1(266.45,58.8) v3(6.35,80.39) v3(6.35,78.99) v3(6.35,76.2) v3(6.35,74.8) v3(9.27,80.39) v3(9.27,78.99) v3(9.27,76.2) v3(11.81,101.35) v3(11.81,99.95) v3(11.81,92.96) v3(11.81,91.57) v3(14.73,101.35) v3(14.73,99.95) v3(14.73,92.96) v3(14.73,91.57)
12V: length 39.2
  TOP w0.381: J43.6 267.61,156.82 ; J43.4 267.61,157.46 ; 268.95,158.71 J43.2 267.61,158.09
  TOP w0.508: 275.48,82.51 J18.B2 ; J18.B2 276.61,83.64 ; J18.B2 275.48,83.64 ; J18.B2 276.61,82.51 ; J18.B3 274.61,83.51 ; J18.B3 273.48,84.64 ; J18.B3 273.48,83.51 ; J18.B3 274.61,84.64 ; 270.98,83.51 J18.A3 ; J18.A3 272.11,84.64 ; J18.A3 270.98,84.64 ; J18.A3 272.11,83.51 ; J18.A2 270.11,83.64 ; J18.A2 270.11,82.51 ; J18.A2 268.98,83.64 ; J18.A2 268.98,82.51 ; J18.B1 274.61,81.51 ; J18.B1 273.48,81.51 ; J18.B1 273.48,82.64 ; J18.B1 274.61,82.64
  BOTTOM w0.508: 270.89,84.73 J18.A3 ; J18.A3 272.2,84.73 ; J18.A3 272.2,83.42 ; J18.A3 270.89,83.42 ; 275.39,83.73 J18.B2 ; J18.B2 276.7,82.42 ; J18.B2 275.39,82.42 ; J18.B2 276.7,83.73 ; 273.39,84.73 J18.B3 ; J18.B3 273.39,83.42 ; J18.B3 274.7,83.42 ; J18.B3 274.7,84.73 ; 268.89,82.42 J18.A2 ; J18.A2 268.89,83.73 ; J18.A2 270.2,83.73 ; J18.A2 270.2,82.42 ; J18.B1 274.7,81.42 ; J18.B1 273.39,81.42 ; J18.B1 274.7,82.73 ; J18.B1 273.39,82.73
  vias: v1(217.3,241.55) v1(217.3,240.54) v1(218.06,241.55) v1(218.06,240.54) v1(230,241.55) v1(230,240.54) v1(230.76,241.55) v1(230.76,240.54) v1(236.35,82.17) v1(236.35,81.28) v1(237.24,82.17) v1(237.24,81.28) v1(242.7,241.55) v1(242.7,240.54) v1(243.46,241.55) v1(243.46,240.54) v1(255.4,241.55) v1(255.4,240.54) v1(256.16,241.55) v1(256.16,240.54) v1(261.24,82.8) v1(261.24,81.53) v1(262.38,82.8) v1(262.38,81.53) v1(268.61,162.43) v1(268.61,161.67) v1(269.49,162.43) v1(269.49,161.67) v3(24.64,77.22) v3(24.64,75.95) v3(24.64,74.68) v3(24.64,73.41) v3(25.65,77.22) v3(25.65,75.95) v3(25.65,74.68) v3(25.65,73.41)
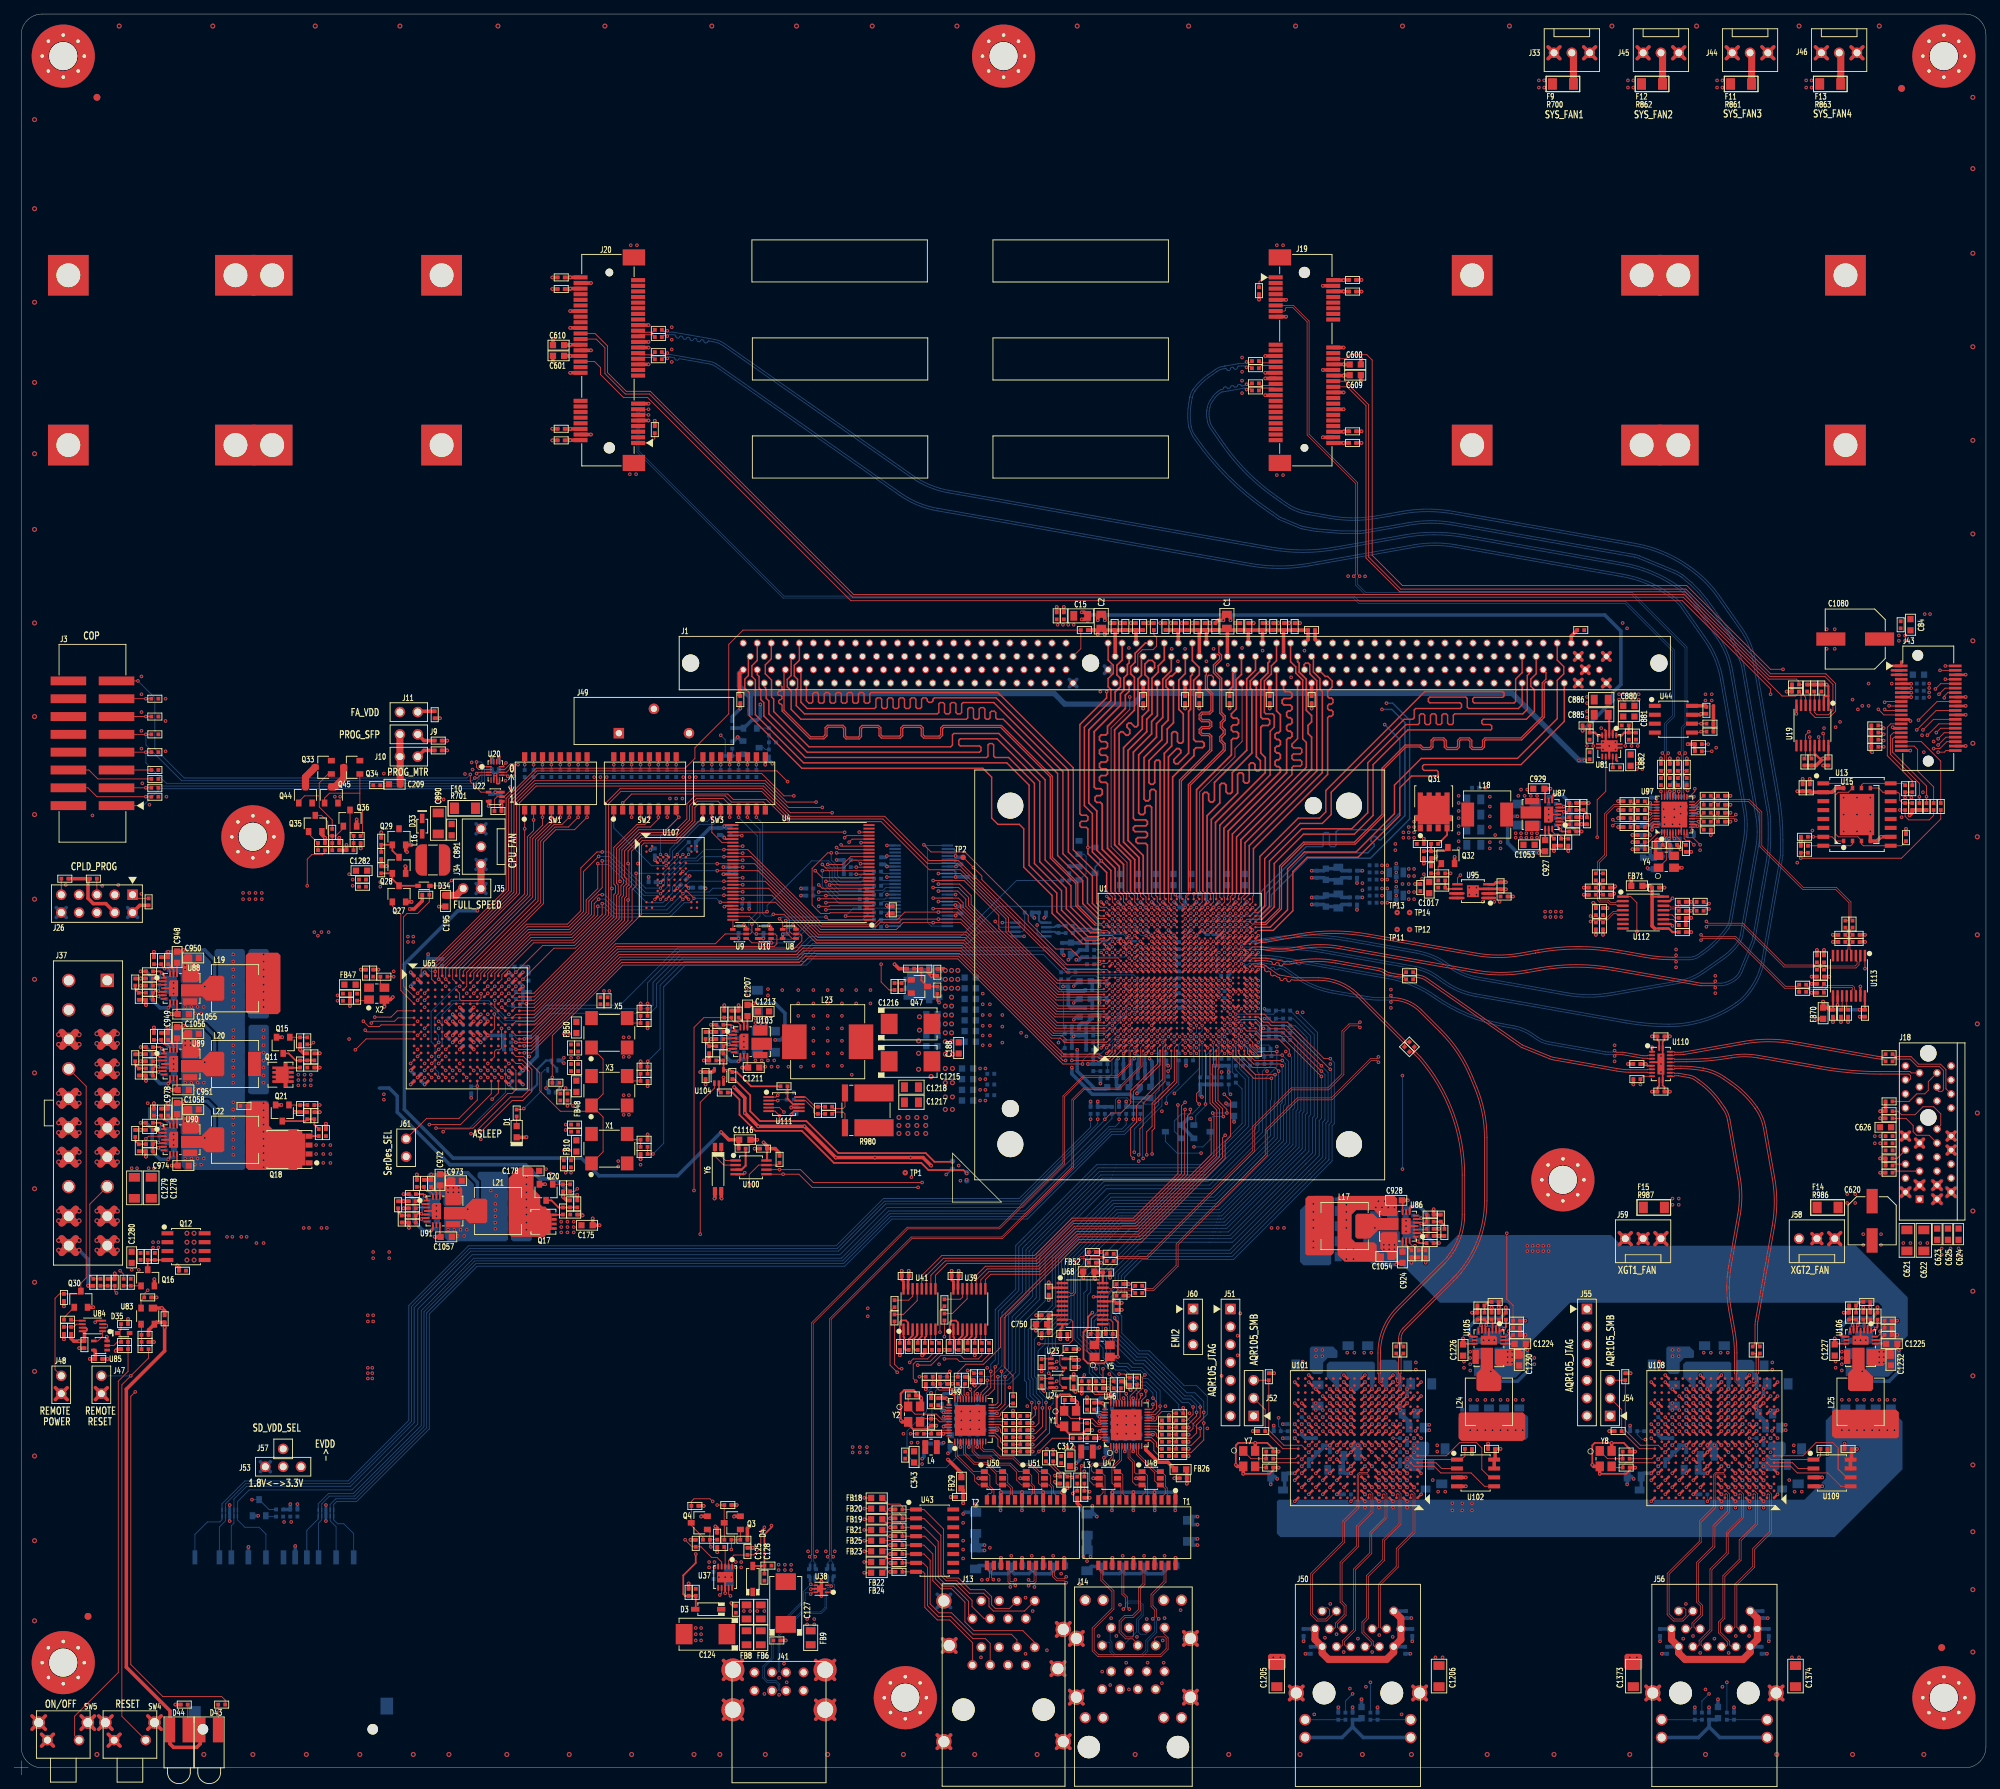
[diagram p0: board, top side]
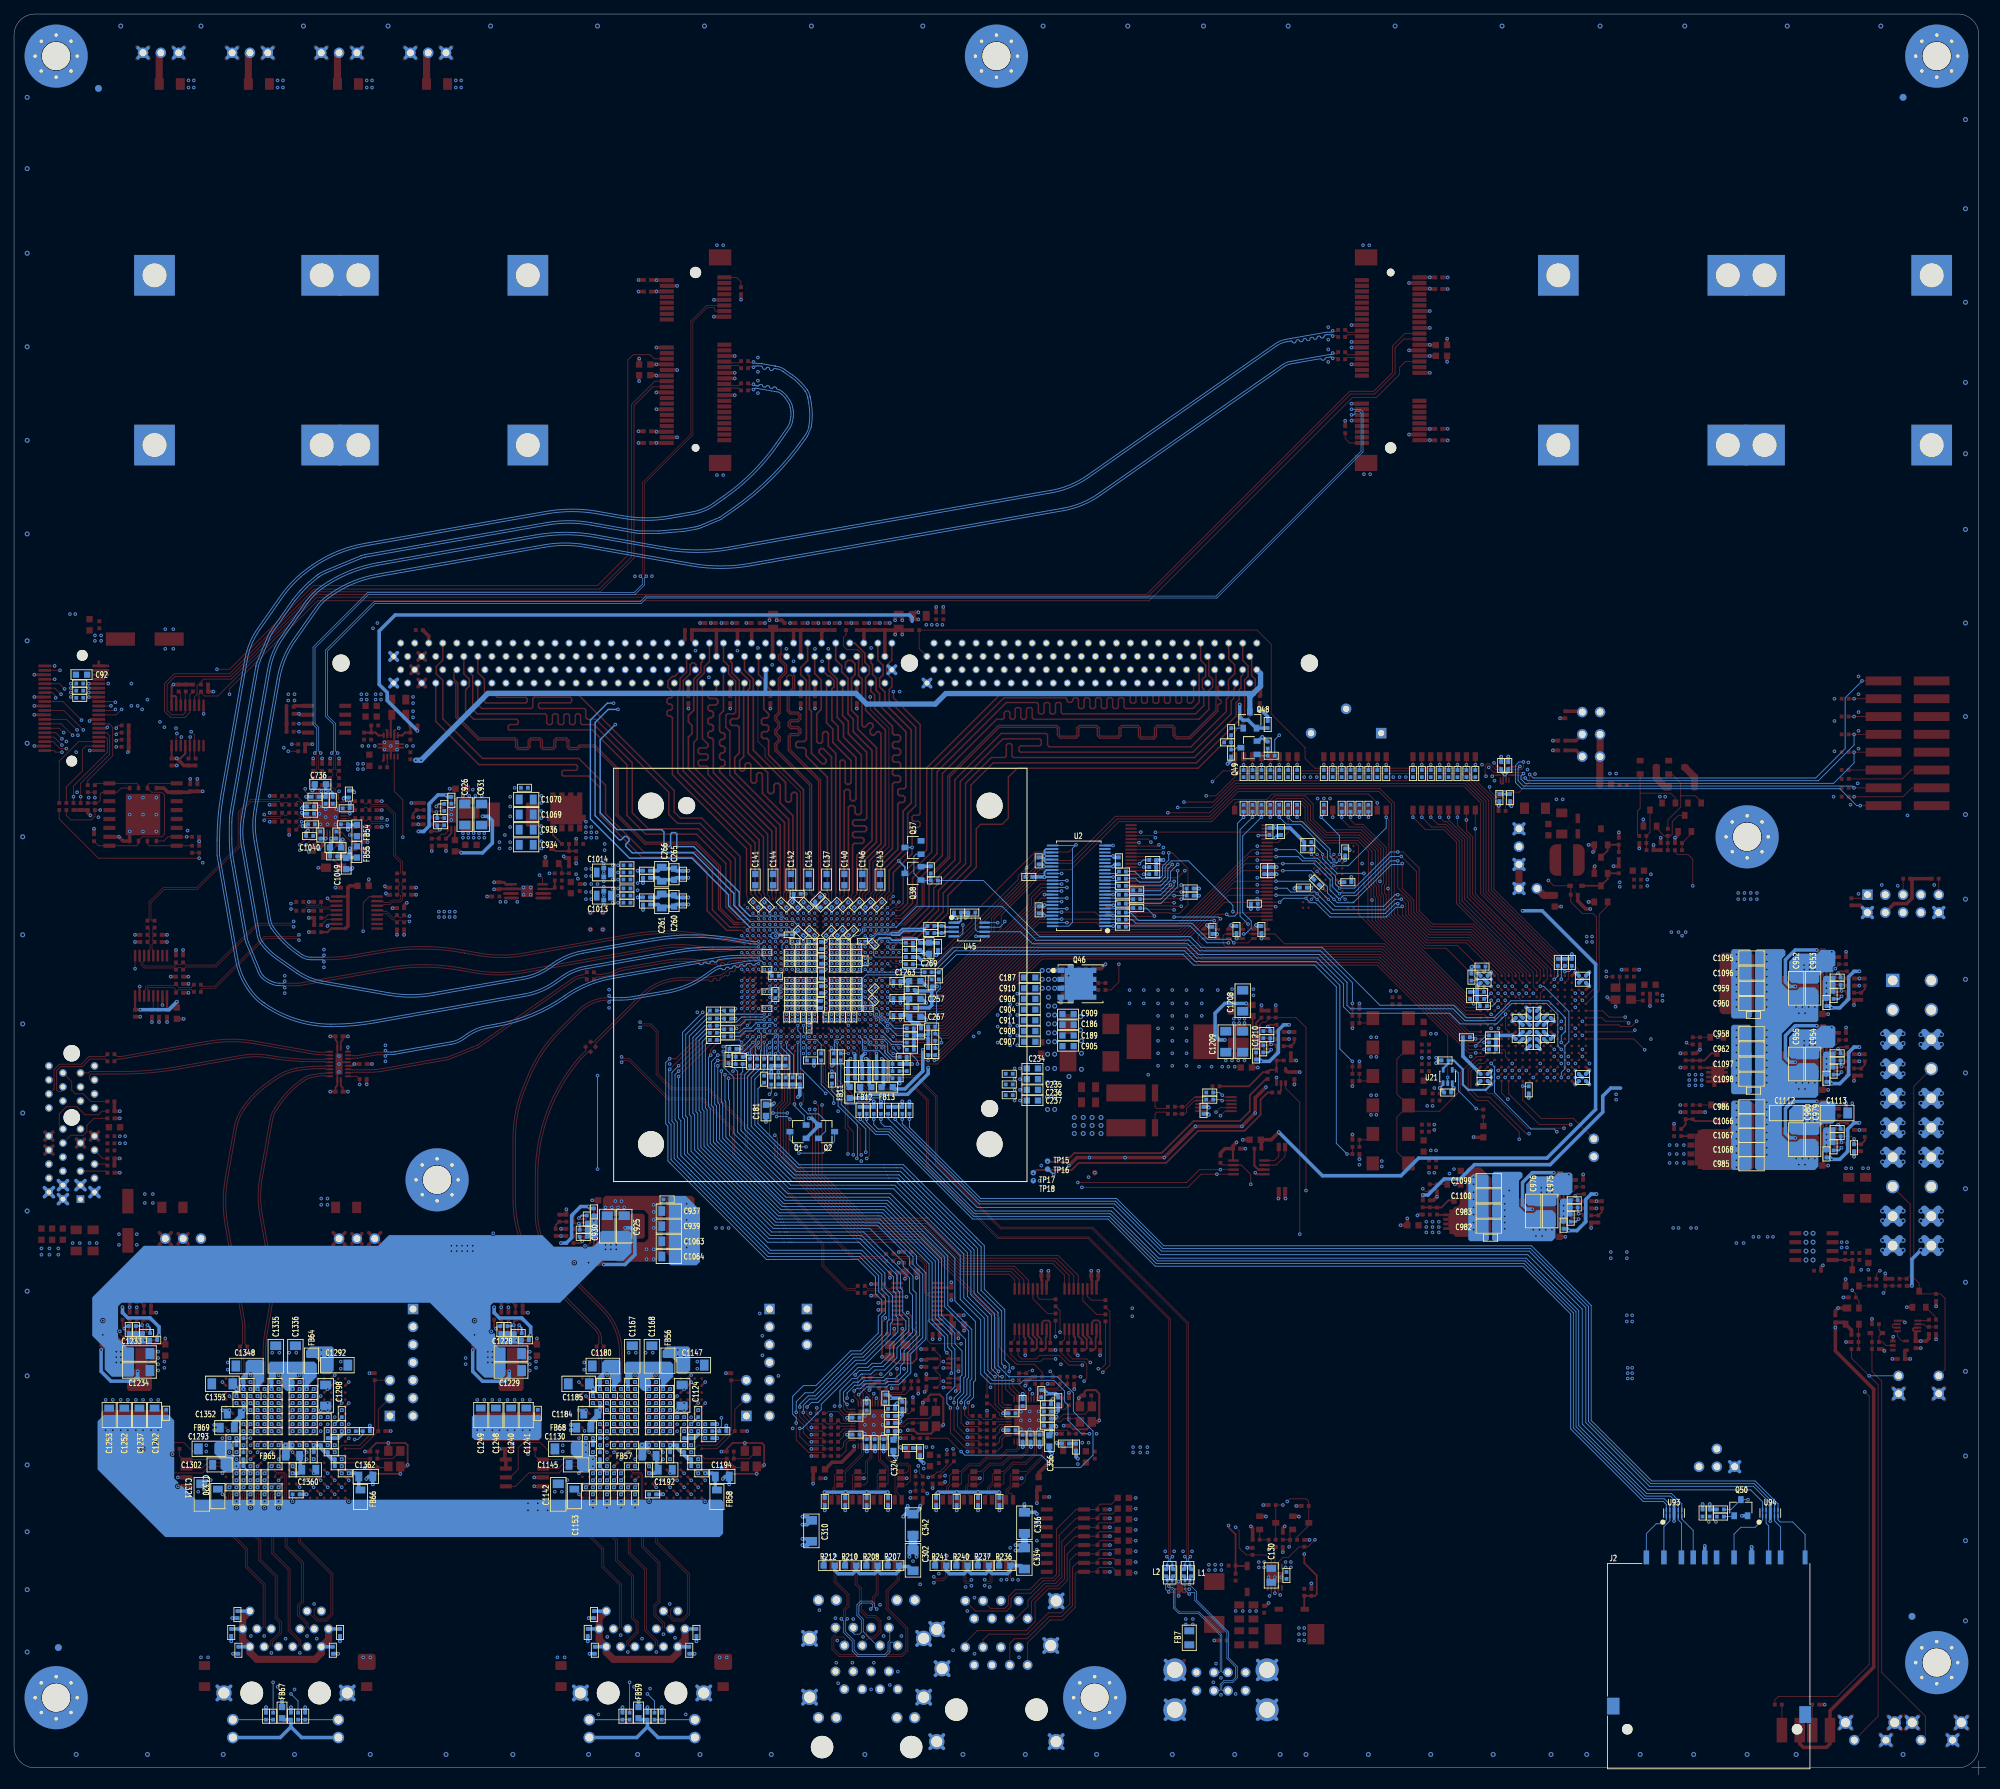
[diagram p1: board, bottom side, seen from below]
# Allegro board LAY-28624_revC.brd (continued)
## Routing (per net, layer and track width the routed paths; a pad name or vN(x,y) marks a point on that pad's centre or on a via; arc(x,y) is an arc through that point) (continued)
12V_SLP: length 432.8
  TOP w0.508: v1(43.56,102.87) 43.55,102.86 R662.1 ; R679.1 43.55,94.48 v1(43.56,94.49) ; R818.1 R819.2 v1(47.38,132.58) ; v1(125.48,115.57) 126.11,114.94 R916.2 ; R784.1 v1(200.91,129.92) ; R678.1 v1(80.26,82.68)
  TOP w1.016: 12.3,76.45 J37.10 ; J37.10 14.28,74.47 ; J37.10 12.3,74.47 ; J37.10 14.28,76.45
  L6SIG w0.508: 101.85,163.07 153.54,163.07 153.92,163.45 225.93,163.45 227.97,161.42 227.97,153.42 224.54,149.99 217.42,149.99 208.41,140.97 208.41,132.72 205.61,129.92 v1(200.91,129.92) ; 101.85,163.07 101.85,152.02 108.08,145.8 v1(108.08,144.14) ; 101.85,163.07 60.71,163.07 47.38,149.74 v1(47.38,132.58) 48.89,131.06 55.37,131.06 62.67,123.76 62.67,111.44 64.39,109.73 64.39,106.93 64.9,106.43 68.2,106.43 68.96,105.66 71.5,105.66 79.76,113.92 123.83,113.92 v1(125.48,115.57)
  BOTTOM w0.508: R947.1 107.57,144.65 v1(108.08,144.14) ; 52.07,97.92 53.47,97.92 54.61,96.77 54.61,94.49 62.1,87 72.9,87 74.93,84.96 77.22,84.96 79.5,82.68 v1(80.26,82.68)
  BOTTOM w1.016: 12.3,74.47 J37.10 ; J37.10 14.28,76.45 ; J37.10 12.3,76.45 ; J37.10 14.28,74.47
  vias: v1(19.81,75.95) v1(19.81,75.18) v1(20.57,75.95) v1(20.57,75.18) v1(60.32,139.06) v1(61.21,139.06) v3(11.81,76.2) v3(11.81,74.8) v3(14.73,76.2) v3(14.73,74.8)
AGND_SD1_PLL1: length 6.4
  TOP w0.305: U1.AA16 v2(171.72,115.65)
  BOTTOM w0.508: R190.1 189.21,125.09 C261.2 188.52,125.39 C260.2 186.64,125.09 C259.2 v1(184.92,125.09)
AGND_SD1_PLL2: length 6.4
  TOP w0.305: U1.AA20 v2(171.72,118.85)
  BOTTOM w0.508: R193.1 189.21,128.91 C266.2 188.52,129.2 C265.2 186.64,128.9 C264.2 v1(184.92,128.9)
AVDD_CGA1: length 3.9
  TOP w0.305: U1.G11 v2(159.72,110.85)
  BOTTOM w0.457: C258.1 154.69,110.06 v2(154.71,110.04)
  BOTTOM w0.508: R188.2 153.66,110.41 C257.1 153.58,110.74 C258.1
AVDD_CGA2: length 3.9
  TOP w0.305: U1.G12 v2(159.72,111.65)
  BOTTOM w0.457: v2(154.71,112.44) 154.69,112.46 C1264.1
  BOTTOM w0.508: C1264.1 C1263.1 153.66,112.95 R939.2
AVDD_DDR1: length 10.2
  TOP w0.305: U1.E20 v2(158.12,118.85)
  BOTTOM w0.254: v2(158.12,118.85) 157.66,119.3 156.21,119.3 155.91,119 154.69,119 154.38,119.3 152.45,119.3 151.89,118.75 C270.1
  BOTTOM w0.508: R195.2 150.58,118.61 C269.1 150.67,118.61 C270.1
AVDD_PLAT: length 5.4
  TOP w0.305: U1.G10 v2(159.72,110.05)
  BOTTOM w0.457: v2(154.71,107.64) 154.69,107.65 C268.1
  BOTTOM w0.508: R194.2 151.76,106.81 152.15,107.19 152.91,107.19 153.45,107.73 C267.1 153.71,108.33 C268.1
AVDD_SD1_PLL1: length 6.4
  TOP w0.305: U1.AB16 v2(172.52,115.65)
  BOTTOM w0.508: R189.1 189.21,124.08 C261.1 188.52,123.79 C260.1 186.64,124.09 C259.1 v1(184.92,124.09)
AVDD_SD1_PLL2: length 6.4
  TOP w0.305: U1.AB20 v2(172.52,118.85)
  BOTTOM w0.508: R192.1 189.21,127.89 C266.1 188.52,127.6 C265.1 186.64,127.9 C264.1 v1(184.92,127.9)
GND: length 2305.2
  TOP w0.203: v1(154.69,48.01) 154.79,48.11 U46.47 ; U20.6 68.38,142.42 v1(68.58,142.62) 68.78,142.42 U20.7 68.78,141.35 68.83,141.3 69.09,141.3 69.18,141.39 U20.8 ; U97.8 237.6,135.91 U97.41 ; U49.47 132.57,48.75 v1(132.46,48.64)
  TOP w0.254: C1375.2 235.2,98.05 234.95,98.3 U110.11 234.95,99.95 v1(234.7,100.2) ; U105.4 U105.17 ; v1(225.97,42.93) 229.74,42.93 230.24,43.43 C1288.2 ; U106.4 U106.17 ; v1(234.7,101.35) 234.45,101.6 U110.5 ; v1(174.12,44.2) 174.12,46.99 174.46,47.33 v1(176.87,47.33) 178.6,47.33 179.44,46.49 C1119.2 ; C1377.2 235.2,104.77 234.95,104.52 U110.20 234.95,102.74 v1(234.7,102.49) ; U86.4 U86.17 ; v1(224.92,44.2) 224.92,46.99 225.26,47.33 v1(227.67,47.33) 229.4,47.33 230.24,46.49 C1287.2 ; U103.4 v1(104.01,104.52) ; v1(153.67,65.91) 153.03,65.28 153.03,63.75 152.4,63.12 152.4,59.31 153.03,58.67 155.32,58.67 156.17,59.52 Y5.2 ; U89.4 U89.17 ; C1120.2 179.44,43.43 178.94,42.93 v1(175.17,42.93) ; U87.4 U87.17 ; U111.7 v1(110.75,95.13) ; v1(157.31,59.6) 157.31,64.56 156.84,65.02 v1(156.84,65.15) ; v1(101.34,28.19) U37.8 v1(101.34,25.91) ; U90.4 U90.17 ; U110.2 v1(233.45,103.74) ; U84.4 11.8,64.76 v1(11.56,64.52) ; v1(101.22,133.6) 101.42,133.4 U4.33 ; v1(101.22,123.77) 101.36,123.9 U4.52 ; U91.4 U91.17 ; U88.4 U88.17
  TOP w0.305: U101.N13 v1(187.52,52.01) ; U108.C17 v1(234.32,41.01) ; U1.N11 v2(164.52,110.85) ; U101.G7 v1(194.52,45.01) ; U1.AE21 v2(174.92,119.65) ; U1.M7 v2(163.72,107.65) ; U1.Y14 v2(170.92,113.25) ; U108.V9 v1(243.32,57.01) ; U108.R4 v1(248.32,54.01) U108.T3 ; U1.R15 v2(166.92,114.85) ; U101.C6 v1(195.52,41.01) ; U1.AC20 v2(173.32,118.85) ; U1.AF20 U1.AG21 v2(176.52,119.65) ; U1.AA19 v2(170.92,117.25) U1.Y18 ; U108.L11 v1(240.32,50.01) ; U100.4 103.93,85.64 v1(104.14,85.85) ; U101.U9 v1(192.52,56.01) ; U101.E1 v1(200.52,43.01) ; U1.D21 v2(157.32,118.85) U1.D20 ; U1.V14 v2(169.32,113.25) ; U101.P3 v1(198.52,53.01) ; U1.R11 v2(166.92,110.85) ; U108.E17 v1(234.32,43.01) ; U1.AF12 v2(175.72,111.65) ; U101.B12 v1(188.52,40.01) ; U1.N17 v2(164.52,116.45) ; U101.P12 v1(188.52,53.01) ; U108.R1 v1(251.32,54.01) ; U108.U18 v1(233.32,56.01) ; U101.D5 v1(196.52,42.01) ; U1.AC11 v2(173.32,110.85) ; U1.K7 v2(162.12,107.65) ; U101.H4 v1(196.52,46.01) ; U108.G9 v1(243.32,45.01) ; U1.AA11 v2(171.72,110.85) ; U1.AC26 v2(173.32,123.65) ; U108.J13 v1(238.32,47.01) ; U1.AH10 v2(177.32,110.05) ; U107.K3 v2(91.33,124.82) ; U1.G16 v2(159.72,115.65) ; U1.E19 v2(158.12,118.05) ; C340.2 130.56,49.79 130.05,49.28 128.14,49.28 127.42,50 Y2.2 ; U101.E13 v1(187.52,43.01) ; U1.N15 v2(164.52,114.85) ; U108.J5 v1(247.32,47.01) ; U101.C11 v1(189.52,41.01) ; U1.N5 v2(164.52,106.05) ; U1.AG14 v2(176.52,113.25) ; U108.U9 v1(243.32,56.01) ; U1.Y17 v2(170.92,116.45) ; U1.AF16 v2(175.72,114.85) U1.AF15 ; U1.K18 v2(162.12,117.25) ; U101.N2 v1(199.52,52.01) ; U108.E15 v1(236.32,43.01) ; v1(148.59,49.91) 148.59,53.72 149.1,54.23 150.41,54.23 150.74,53.9 C304.2 ; U1.E3 v2(158.12,104.45) ; U108.B12 v1(239.32,40.01) ; U108.C2 v1(250.32,41.01) ; U1.J2 v2(161.32,103.65) ; v1(236.35,121.03) 236.07,121.31 U112.10 ; U101.R7 v1(194.52,54.01) ; U1.B4 v2(155.72,105.25) ; U108.J7 v1(245.32,47.01) ; U1.F24 v2(158.92,122.05) ; U101.L7 v1(194.52,50.01) ; U1.V20 v2(169.32,118.85) ; U1.M12 v2(163.72,111.65) ; U1.H11 v2(160.52,110.85) ; U101.R13 v1(187.52,54.01) ; U101.T5 v1(196.52,55.01) ; U1.L26 v2(162.92,123.65) ; U101.A18 v1(182.52,39.01) ; U101.N5 v1(196.52,52.01) ; U1.AC2 v2(173.32,103.65) ; U108.N7 v1(245.32,52.01) ; U1.N26 v2(164.52,123.65) ; U1.B28 v2(155.72,125.25) ; U101.T13 v1(187.52,55.01) ; U1.P7 v2(165.32,107.65) ; U101.T11 v1(189.52,55.01) ; U112.15 235.94,124.56 v1(236.35,124.97) ; U113.10 v1(259.87,109.75) ; U108.H8 v1(244.32,46.01) ; U1.W5 v2(170.12,106.05) ; U101.N1 v1(200.52,52.01) ; U1.AB21 v2(172.52,119.65) ; U101.B5 v1(196.52,40.01) ; U101.J7 v1(194.52,47.01) ; v1(247.32,50.01) U108.L4 v1(248.32,50.01) ; U108.R14 v1(237.32,54.01) ; U1.E26 v2(158.12,123.65) ; U1.AD22 v2(174.12,120.45) ; U1.F15 v2(158.92,114.85) ; U108.B14 v1(237.32,40.01) ; U108.F8 v1(244.32,44.01) ; U1.R26 v2(166.92,123.65) ; U1.H9 v2(160.52,109.25) ; U1.B23 v2(155.72,121.25) ; U101.D12 v1(188.52,42.01) ; U108.E11 v1(241.32,44.01) U108.F10 ; U1.K14 v2(162.12,113.25) ; U101.D7 v1(194.52,42.01) ; U1.K24 v2(162.12,122.05) ; U101.P10 v1(190.52,53.01) ; U1.U15 v2(168.52,114.85) ; U1.P12 v2(165.32,111.65) ; U1.AE15 v2(174.92,114.85) ; U1.AD6 v2(174.12,106.85) ; U1.K6 v2(162.12,106.85) ; U1.T7 v2(167.72,107.65) ; U101.D9 v1(192.52,42.01) ; U1.L9 v2(162.92,109.25) ; U108.R13 v1(238.32,54.01) ; U1.R9 v2(166.92,109.25) ; U101.R9 v1(192.52,54.01) ; U1.T10 v2(167.72,110.05) ; U108.E4 v1(248.32,43.01) ; U1.AA15 v2(171.72,114.85) ; U81.8 v1(227.33,146.69) 226.83,147.19 U81.4 226.83,148.84 226.69,148.97 ; U108.P3 v1(249.32,53.01) ; U101.U18 v1(182.52,56.01) ; U1.T12 v2(167.72,111.65) ; U1.AD21 v2(174.12,119.65) ; U108.M10 v1(241.32,51.01) ; U101.H8 v1(193.52,46.01) ; U108.M6 v1(246.32,51.01) ; U101.C13 v1(187.52,41.01) ; C305.2 152.79,49.16 152.27,48.64 150.37,48.64 149.65,49.36 Y1.2 ; U108.V16 v1(235.32,57.01) ; U1.M18 v2(163.72,117.25) ; U1.Y10 v2(170.92,110.05) ; U1.M16 v2(163.72,115.65) ; U1.P20 v2(165.32,118.85) ; U1.L17 v2(162.92,116.45) ; U101.L11 v1(189.52,50.01) ; U101.H10 v1(190.52,46.01) U101.G11 ; U1.AH12 v2(177.32,111.65) ; U1.A2 v2(154.92,103.65) ; U101.M6 v1(195.52,51.01) ; U1.AG26 v2(176.52,123.65) ; U1.AA17 v2(171.72,116.45) ; U1.G22 v2(159.72,120.45) ; U1.V16 v2(169.32,115.65) ; v1(197.52,50.01) U101.L4 v1(196.52,50.01) ; U108.T13 v1(238.32,55.01) ; U108.V5 v1(247.32,57.01) ; U108.E1 v1(251.32,43.01) ; U1.U11 v2(168.52,110.85) ; U1.M20 v2(163.72,118.85) ; U1.T14 v2(167.72,113.25) ; U68.17 v1(153.84,68.16) ; U101.L9 v1(192.52,50.01) ; U1.AC16 v2(173.32,115.65) ; U101.M12 v1(188.52,51.01) ; U108.C6 v1(246.32,41.01) ; U1.V12 v2(169.32,111.65) ; U1.AB17 v2(172.52,116.45) ; U1.AG13 v2(176.52,112.45) ; v2(176.52,117.25) U1.AG18 U1.AF17 ; U107.F7 v2(95.33,128.82) ; U1.L19 v2(162.92,118.05) ; U108.K6 v1(246.32,49.01) ; U1.T16 v2(167.72,115.65) ; U1.AD12 v2(174.12,111.65) ; U1.K5 v2(162.12,106.05) ; U1.AF9 v2(175.72,109.25) ; U1.T20 v2(167.72,118.85) ; U101.C15 v1(185.52,41.01) ; U1.AG23 v2(176.52,120.45) U1.AG22 ; U108.G11 v1(241.32,46.01) U108.H10 ; U108.C11 v1(240.32,41.01) ; U1.K12 v2(162.12,111.65) ; U108.H6 v1(246.32,46.01) ; U108.H12 v1(239.32,46.01) ; U1.U9 v2(168.52,109.25) ; U101.D18 v1(182.52,42.01) ; U1.Y22 v2(170.92,120.45) ; U1.AA7 v2(170.92,107.65) U1.Y7 ; U101.P6 v1(195.52,53.01) ; U1.D24 v2(157.32,122.05) ; U101.J11 v1(189.52,47.01) ; U1.AF13 v2(175.72,112.45) ; U101.C17 v1(183.52,41.01) ; U101.E6 v1(195.52,43.01) ; U101.B16 v1(184.52,40.01) ; U1.AE2 v2(174.92,103.65) ; U1.W2 v2(170.12,103.65) ; U1.AC24 v2(173.32,122.05) ; U1.AC10 v2(173.32,110.05) ; U108.J9 v1(243.32,47.01) ; U101.R4 v1(197.52,54.01) U101.T3 ; U108.J11 v1(240.32,47.01) ; U1.AC19 v2(173.32,118.05) ; U1.AF19 v2(175.72,117.25) U1.AF18 ; U1.AF10 v2(175.72,110.05) ; U1.AH13 v2(177.32,112.45) ; U101.V5 v1(196.52,57.01) ; U108.T15 v1(236.32,55.01) ; U108.C13 v1(238.32,41.01) ; U108.B16 v1(235.32,40.01) ; U1.AH11 v2(177.32,110.85) ; U108.N13 v1(238.32,52.01) ; U1.B16 v2(156.52,115.65) ; U1.D2 v2(157.32,103.65) ; U1.Y26 v2(170.92,123.65) ; U1.AD18 v2(174.12,117.25) ; U1.C26 v2(156.52,123.65) ; U101.D3 v1(198.52,42.01) ; U1.R7 v2(166.92,107.65) ; U1.AB7 v2(172.52,107.65) ; U101.T15 v1(185.52,55.01) ; U1.U13 v2(168.52,112.45) ; U1.E5 v2(158.12,106.05) ; U108.N5 v1(247.32,52.01) ; U1.P24 v2(165.32,122.05) ; U1.M14 v2(163.72,113.25) ; U108.E13 v1(238.32,43.01) ; U108.D14 v1(237.32,42.01) ; U1.H16 v2(160.52,115.65) ; U108.D3 v1(249.32,42.01) ; U1.R22 v2(166.92,120.45) ; U1.AH9 v2(177.32,109.25) ; U1.B10 v2(155.72,110.05) ; U1.AA21 U1.AB22 v2(172.52,120.45) ; U101.P8 v1(193.52,53.01) ; U108.U16 v1(235.32,56.01) ; U1.G5 v2(159.72,106.05) ; U101.N11 v1(189.52,52.01) ; U101.R2 v1(199.52,54.01) ; U1.Y12 v2(170.92,111.65) ; U1.AG11 v2(176.52,110.85) ; U1.AF14 v2(175.72,113.25) ; U108.K8 v1(244.32,49.01) ; U1.AC14 v2(173.32,113.25) ; U108.C15 v1(236.32,41.01) ; U101.R6 v1(195.52,54.01) ; U101.B9 v1(192.52,40.01) ; U1.H10 v2(160.52,110.05) ; U1.E1 v2(158.12,102.85) ; U108.U1 v1(251.32,56.01) ; U1.W9 v2(170.12,109.25) ; U1.AG4 v2(176.52,105.25) ; U1.V22 v2(169.32,120.45) ; U1.AG10 v2(176.52,110.05) ; U108.P18 v1(233.32,53.01) ; U1.L11 v2(162.92,110.85) ; U108.E6 v1(246.32,43.01) ; U101.B14 v1(186.52,40.01) ; U101.D14 v1(186.52,42.01) ; U1.AG6 v2(176.52,106.85) ; U1.N7 v2(164.52,107.65) ; U1.B25 v2(155.72,122.85) ; U101.F8 v1(193.52,44.01) ; U108.L13 v1(238.32,50.01) ; U1.P18 v2(165.32,117.25) ; v1(126.37,50.55) 126.37,54.36 126.87,54.86 128.19,54.86 128.52,54.53 C339.2 ; U1.U19 v2(168.52,118.05) ; U1.T22 v2(167.72,120.45) ; U108.T9 v1(243.32,55.01) ; U1.G26 v2(159.72,123.65) ; U19.8 254.01,151.27 v1(254,151.26) ; U1.P14 v2(165.32,113.25) ; U101.T7 v1(194.52,55.01) ; U1.AG12 v2(176.52,111.65) ; U1.AE18 v2(174.92,117.25) ; U108.G5 v1(247.32,45.01) ; U108.D7 v1(245.32,42.01) ; U101.V11 v1(189.52,57.01) ; U108.D9 v1(243.32,42.01) ; U1.H7 v2(160.52,107.65) ; U1.H20 v2(160.52,118.85) ; U101.F10 v1(190.52,44.01) U101.E11 ; U108.R9 v1(243.32,54.01) ; U108.U11 v1(240.32,56.01) ; U1.H12 v2(160.52,111.65) ; U1.V10 v2(169.32,110.05) ; U108.C4 v1(248.32,41.01) ; U108.L7 v1(245.32,50.01) ; U101.G9 v1(192.52,45.01) ; U1.E10 v2(158.12,110.05) ; U101.J5 v1(196.52,47.01) ; U108.T7 v1(245.32,55.01) ; U108.P17 v1(234.32,53.01) ; U101.F12 v1(188.52,45.01) ; U101.E15 v1(185.52,43.01) ; U1.V7 v2(169.32,107.65) ; U108.D12 v1(239.32,42.01) ; U101.G5 v1(196.52,45.01) ; U1.G3 v2(159.72,104.45) ; U1.U7 v2(168.52,107.65) ; U108.C8 v1(244.32,41.01) ; U101.N7 v1(194.52,52.01) ; U108.H4 v1(247.32,46.01) ; U1.H18 v2(160.52,117.25) ; U108.D18 v1(233.32,42.01) ; U101.E4 v1(197.52,43.01) ; U1.A20 v2(155.72,118.05) U1.B19 ; U1.AH15 v2(177.32,114.85) ; U1.M10 v2(163.72,110.05) ; U1.AD15 v2(174.12,114.85) ; U1.AE12 v2(174.92,111.65) ; U101.N9 v1(192.52,52.01) ; U1.H3 v2(160.52,104.45) ; U1.W24 v2(170.12,122.05) ; U1.L7 v2(162.92,107.65) ; U1.R17 v2(166.92,116.45) ; U1.B1 v2(155.72,102.85) ; U108.A18 v1(233.32,39.01) ; U101.K12 v1(188.52,49.01) ; U107.C5 v2(92.93,131.22) ; U1.N2 v2(164.52,103.65) ; U108.B7 v1(245.32,40.01) ; U108.R2 v1(250.32,54.01) ; U108.N2 v1(250.32,52.01) ; U101.R11 v1(189.52,54.01) ; U108.N11 v1(240.32,52.01) ; U108.R11 v1(240.32,54.01) ; U1.AE26 v2(174.92,123.65) ; U1.U24 v2(168.52,122.05) ; U101.K6 v1(195.52,49.01) ; U1.AA24 v2(171.72,122.05) ; U108.L9 v1(243.32,50.01) ; U108.M12 v1(239.32,51.01) ; U107.K8 v2(96.13,124.82) ; U101.K10 v1(190.52,49.01) ; U1.H13 v2(160.52,112.45) ; U1.AE9 v2(174.12,109.25) U1.AD9 ; U1.AB13 v2(172.52,112.45) ; U1.AC13 v2(173.32,112.45) ; U101.C4 v1(197.52,41.01) ; U108.T11 v1(240.32,55.01) ; U108.B5 v1(247.32,40.01) ; U1.J22 v2(161.32,120.45) ; U1.H8 v2(160.52,108.45) ; U1.P10 v2(165.32,110.05) ; U108.B9 v1(243.32,40.01) ; U101.D16 v1(184.52,42.01) ; v1(263.12,112.4) U113.15 ; U1.J26 v2(161.32,123.65) ; U1.H14 v2(160.52,113.25) ; U108.P12 v1(239.32,53.01) ; U1.P16 v2(165.32,115.65) ; U1.B7 v2(155.72,107.65) ; U1.N19 v2(164.52,118.05) ; U1.V26 v2(169.32,123.65) ; U1.AG9 v2(176.52,109.25) ; U101.L13 v1(187.52,50.01) ; U1.E7 v2(158.12,107.65) ; U1.H17 v2(160.52,116.45) ; U1.AG1 v2(176.52,102.85) ; U1.Y16 v2(170.92,115.65) ; U101.V16 v1(184.52,57.01) ; U108.F12 v1(239.32,45.01) ; U101.U16 v1(184.52,56.01) ; U1.AB2 v2(172.52,103.65) ; U1.J3 v2(161.32,104.45) ; U1.L15 v2(162.92,114.85) ; U1.AH2 v2(177.32,103.65) ; U1.AH18 v2(177.32,117.25) ; U108.B3 v1(249.32,40.01) ; U108.M8 v1(244.32,51.01) ; U101.V9 v1(192.52,57.01) ; U101.J13 v1(187.52,47.01) ; U101.C8 v1(193.52,41.01) ; U101.R1 v1(200.52,54.01) ; U101.M8 v1(193.52,51.01) ; U101.K8 v1(193.52,49.01) ; U1.H19 v2(160.52,118.05) ; U1.U17 v2(168.52,116.45) ; U1.H15 v2(160.52,114.85) ; U1.AB26 v2(172.52,123.65) ; U1.G1 v2(159.72,102.85) ; U1.T26 v2(167.72,123.65) ; U108.F6 v1(246.32,44.01) ; U108.G7 v1(245.32,45.01) ; U101.U11 v1(189.52,56.01) ; U1.AH21 v2(177.32,119.65) ; U1.AG15 v2(176.52,114.85) ; U101.U1 v1(200.52,56.01) ; U108.R6 v1(246.32,54.01) ; U1.AC1 v2(173.32,102.85) ; U108.T5 v1(247.32,55.01) ; U1.G2 v2(159.72,103.65) ; U1.K20 v2(162.12,118.85) ; U108.V11 v1(240.32,57.01) ; U1.W13 v2(170.12,112.45) ; U101.U5 v1(196.52,56.01) ; U101.P18 v1(182.52,53.01) ; U1.V18 v2(169.32,117.25) ; U108.K12 v1(239.32,49.01) ; U1.AH14 v2(177.32,113.25) ; U101.A1 v1(200.52,40.01) ; U1.C22 v2(156.52,120.45) ; U1.J1 v2(161.32,102.85) ; U1.N22 v2(164.52,120.45) ; U101.C2 v1(199.52,41.01) ; U1.R19 v2(166.92,118.05) ; U1.AD4 v2(174.12,105.25) ; U108.N9 v1(243.32,52.01) ; U1.AF21 v2(175.72,119.65) ; U1.K16 v2(162.12,115.65) ; U1.F3 v2(158.92,104.45) ; U1.E2 v2(158.12,103.65) ; U101.P17 v1(183.52,53.01) ; U1.E22 v2(158.12,120.45) ; U108.U5 v1(247.32,56.01) ; U1.N13 v2(164.52,112.45) ; U1.M24 v2(163.72,122.05) ; U101.J9 v1(192.52,47.01) ; U1.AC17 v2(173.32,116.45) ; U101.F6 v1(195.52,44.01) ; U101.T9 v1(192.52,55.01) ; U1.R13 v2(166.92,112.45) ; U108.D5 v1(247.32,42.01) ; U1.T5 v2(167.72,106.05) ; U1.T18 v2(167.72,117.25) ; U1.G7 v2(159.72,107.65) ; U101.B7 v1(194.52,40.01) ; U1.W7 v2(170.12,107.65) ; U1.E16 v2(158.12,115.65) ; U1.L13 v2(162.92,112.45) ; U108.A1 v1(251.32,40.01) ; U1.AF11 v2(175.72,110.85) ; U108.P8 v1(244.32,53.01) ; U101.B3 v1(198.52,40.01) ; U1.B13 v2(155.72,112.45) ; U101.H12 v1(188.52,46.01) ; U1.T2 v2(167.72,103.65) ; U1.A27 v2(154.92,124.45) ; U1.J7 v2(161.32,107.65) ; U1.H24 v2(160.52,122.05) ; U1.W11 v2(170.12,110.85) ; U101.R14 v1(186.52,54.01) ; U1.G13 v2(159.72,112.45) ; U101.M10 v1(190.52,51.01) ; U1.AE24 v2(174.92,122.05) ; U1.AA13 v2(171.72,112.45) ; U101.H6 v1(195.52,46.01) ; U108.P6 v1(246.32,53.01) ; U108.K10 v1(241.32,49.01) ; U108.N1 v1(251.32,52.01) ; U108.D16 v1(235.32,42.01) ; U108.R7 v1(245.32,54.01) ; U1.K2 v2(162.12,103.65) ; U1.N9 v2(164.52,109.25) ; U101.E17 v1(183.52,43.01) ; U1.L22 v2(162.92,120.45) ; U1.E13 v2(158.12,112.45) ; U108.P10 v1(241.32,53.01) ; U1.AB5 v2(172.52,106.05)
  TOP w0.381: U65.B2 v1(57.52,113.43) ; J43.19 278.11,152.38 v1(278.13,152.4) ; U65.K10 v1(66.52,104.43) ; v1(208.41,126.49) 208.59,126.31 U95.3 211.77,126.31 C1016.2 ; v1(68.58,140.08) 68.59,140.1 U22.3 ; U23.3 v1(148.58,58.02) ; v1(278.13,153.67) 278.11,153.65 J43.15 ; J43.30 267.86,149.2 v1(267.72,149.35) ; J43.37 278.11,146.66 v1(278.13,146.69) ; C272.2 134.61,70.6 134.52,70.51 U39.15 ; U65.G10 v1(66.52,108.43) ; U65.K7 v1(62.52,104.43) ; v1(278.13,156.84) 278.11,156.82 J43.5 ; v1(278.13,151.13) 278.11,151.11 J43.23 ; U65.G7 v1(62.52,108.43) ; C286.2 127.5,70.6 127.41,70.51 U41.15 ; U65.T1 v1(56.52,98.43) ; U65.K8 v1(63.52,104.43) ; J43.26 270.02,150.47 v1(270.26,150.24) ; U65.K9 v1(65.52,104.43) ; v1(107.57,121.16) 107.88,120.84 U10.3 ; U65.A1 v1(56.52,114.43) ; U24.3 v1(148.58,55.23) ; U9.3 104.33,120.84 v1(104.01,121.16) ; J43.40 v1(270.23,146.03) ; U104.3 v1(101.11,99.43) ; U65.J8 v1(63.52,105.43) ; U65.J10 v1(66.52,105.43) ; v1(13.21,62.48) 13.27,62.42 U85.3 ; U65.T16 v1(72.52,98.43) ; U65.R15 v1(70.52,100.42) ; U65.G8 v1(63.52,108.43) ; U65.H9 v1(65.52,107.43) ; U8.3 111.44,120.72 v1(111,121.16) ; U65.B15 v1(71.52,113.43) ; U65.A16 v1(72.52,114.43) ; U65.R2 v1(57.52,99.43) ; U65.G9 v1(65.52,108.43) ; U65.H7 v1(62.52,107.43)
  TOP w0.508: R513.1 v1(89.29,101.72) ; R712.1 C894.2 v1(14.35,71.5) ; J19.9 v1(181.28,210.28) ; v1(237.49,131.95) 237.49,132.07 C734.2 ; C308.2 v1(153.29,39.5) ; C1121.2 v1(210.07,47.24) ; C892.2 v1(52.32,134.37) ; C611.2 v1(192.02,211.45) ; J33.1 225.39,246.34 ; J33.1 223.69,246.34 ; J33.1 223.69,244.64 ; J33.1 225.39,244.64 ; 5.88,55.21 J48.2 ; J48.2 5.88,53.51 ; J48.2 7.58,53.51 ; J48.2 7.58,55.21 ; 3.92,4.12 SW5.1 ; SW5.1 5.62,5.82 ; SW5.1 5.62,4.12 ; SW5.1 3.92,5.82 ; v1(234.19,133.35) 233.94,133.1 C733.2 233.93,132.58 233.93,131.45 Y4.4 ; C704.2 v1(51.94,114.8) ; U44.7 240.28,151.13 v1(240.41,151.26) C293.2 ; C998.2 176.65,164.2 v1(176.66,164.21) ; J58.3 260.31,77.3 ; J58.3 258.61,77.3 ; J58.3 260.31,75.6 ; J58.3 258.61,75.6 ; J59.3 235.55,77.3 ; J59.3 233.85,77.3 ; J59.3 235.55,75.6 ; J59.3 233.85,75.6 ; R1003.2 R1001.2 v1(239.01,122.17) ; 228.77,77.3 J59.1 ; J59.1 230.47,75.6 ; J59.1 228.77,75.6 ; J59.1 230.47,77.3 ; v1(124.39,122.5) 124.71,122.82 C23.2 ; U51.2 v1(143.38,42.29) ; C303.2 v1(154.69,48.01) ; C876.1 40.78,94.48 R685.1 40.01,94.5 v1(40,94.49) ; R177.1 v1(61.72,147.45) ; C129.2 v1(109.98,19.18) ; C276.2 v1(124.84,34.04) ; SW4.4 20.97,8.42 ; SW4.4 19.06,8.42 ; SW4.4 19.06,6.51 ; SW4.4 20.97,6.51 ; U48.2 v1(159.89,42.29) ; R544.1 v1(154.94,74.55) ; R227.1 v1(152.91,53.85) ; C17.2 v1(148.59,166.5) ; v1(224.92,44.2) 225.13,43.98 Y8.2 v1(225.97,42.93) ; C898.2 v1(9.28,60.84) ; R524.1 v1(238.38,144.91) ; C275.2 v1(136.91,59.82) ; C58.2 v1(151.76,58.17) ; J19.29 v1(178.31,199.08) ; Y6.3 100.78,82.23 v1(100.84,82.17) ; U109.4 v1(257.68,41.15) ; J44.3 245.71,244.64 ; J44.3 244.01,244.64 ; J44.3 244.01,246.34 ; J44.3 245.71,246.34 ; R165.1 v1(96.13,27.3) ; C610.2 v1(76.8,204.75) ; v1(132.59,60.58) 132.6,60.59 C273.2 ; v1(53.98,110.87) 53.63,110.53 X2.2 v1(52.79,109.52) ; v1(102.62,98.04) 104.14,96.52 v1(104.14,94.36) v1(106.05,92.46) v1(112.65,92.46) v1(117.09,88.01) v1(122.68,88.01) v1(127.76,88.01) 129.54,88.01 v1(130.68,86.87) ; C13.2 v1(184.91,152.02) ; v1(129.41,59.82) 129.79,60.2 C288.2 ; v1(178.69,164.21) 178.68,164.2 C4.2 ; J20.40 v1(79.25,208.68) ; C278.2 v1(124.84,35.31) ; C1377.2 v1(235.97,105.28) ; C600.2 v1(191.94,201.91) ; v1(155.45,164.59) 155.45,164.96 C2.2 154.43,164.96 v1(154.43,164.59) ; R684.1 v1(78.23,82.42) 78.75,81.91 C875.1 ; J19.35 v1(178.31,196.68) ; Y5.4 154.42,61.76 C739.2 v1(154.42,63.62) ; J1.199 185.41,161.85 C999.2 ; C1212.1 v1(101.22,109.73) ; R1006.1 v1(263.78,118.75) ; C1120.2 v1(180.21,43.81) ; C287.2 v1(126.24,59.82) ; C337.2 v1(150.11,40.89) ; C18.2 v1(173.23,152.02) ; J47.2 13.3,53.51 ; J47.2 13.3,55.21 ; J47.2 11.6,53.51 ; J47.2 11.6,55.21 ; J44.1 250.79,246.34 ; J44.1 250.79,244.64 ; J44.1 249.09,244.64 ; J44.1 249.09,246.34 ; J1.116 223.45,155.12 ; J1.116 222.39,156.18 ; J1.116 222.39,155.12 ; J1.116 223.45,156.18 ; C291.2 v1(124.84,31.5) ; R518.1 v1(89.29,109.97) ; SW4.1 15.12,5.82 ; SW4.1 13.42,4.12 ; SW4.1 15.12,4.12 ; SW4.1 13.42,5.82 ; J20.27 v1(90.42,203.48) ; R401.2 v1(265.94,85.85) ; C126.2 102.62,24.12 v1(102.23,24.51) ; J19.18 v1(189.48,203.48) ; C703.2 v1(49.41,114.8) ; C1235.1 v1(268.35,64.77) ; v1(115.06,27.56) U38.2 v1(115.06,25.53) ; C601.2 v1(76.8,201.44) ; C613.2 v1(76.71,211.82) ; J45.1 238.09,246.34 ; J45.1 236.39,246.34 ; J45.1 236.39,244.64 ; J45.1 238.09,244.64 ; R541.1 v1(158.88,68.33) ; v1(56.01,131.57) 55.81,131.77 Q29.2 v1(56.63,132.58) ; Q32.2 v1(205.29,130.88) ; v1(174.12,44.2) 174.33,43.98 Y7.2 v1(175.17,42.93) ; v1(151.89,38.35) 151.51,38.73 C307.2 ; J20.21 v1(90.42,201.08) ; R1008.1 v1(257.94,117.6) ; C19.2 v1(103.51,152.02) ; C742.2 v1(157.85,66.3) ; Y2.4 129.29,52.7 v1(129.29,53.72) 128.91,54.1 C339.2 ; C300.1 v1(164.58,51.3) ; R256.1 v1(130.68,54.48) ; C1023.1 v1(46.35,133.6) ; R179.1 v1(60.7,150.63) ; 267.44,133.73 v1(266.06,133.73) 265.47,133.13 U15.4 v1(264.54,134.49) ; C3.2 v1(160.91,152.02) ; R870.1 23.5,72.38 v1(23.24,72.64) ; v1(228.03,125.67) 227.84,125.48 R1011.1 ; C614.2 v1(76.71,191.9) ; R656.1 v1(43.56,100.84) ; C1119.2 v1(180.21,46.1) ; C1002.2 21.46,66.17 v1(21.08,66.55) 21.07,66.56 U83.1 ; R496.1 17.91,123.96 J26.2 ; R842.1 v1(230.63,131.95) ; R257.2 v1(145.16,47.12) ; 12.06,6.51 SW4.3 ; SW4.3 13.97,8.42 ; SW4.3 12.06,8.42 ; SW4.3 13.97,6.51 ; C290.2 v1(124.84,28.96) ; C718.2 v1(90.29,98.18) ; SW5.4 11.47,6.51 ; SW5.4 9.56,6.51 ; SW5.4 11.47,8.42 ; SW5.4 9.56,8.42 ; J19.50 v1(186.51,190.68) ; J19.21 v1(178.31,202.28) ; C1376.2 v1(230,101.35) ; J19.26 v1(186.51,200.28) ; Y4.2 v1(237.66,129.33) ; R1010.1 v1(258.7,113.8) ; J20.15 v1(90.42,195.48) ; U47.2 v1(153.8,42.29) ; Q36.2 v1(48.83,136.21) ; v1(89.28,87.76) 89.29,87.76 R176.1 ; C612.2 v1(192.02,191.53) ; Q16.2 v1(20,70.68) ; C609.2 v1(191.94,198.68) ; R835.2 v1(228.6,136.4) ; C1289.2 v1(260.87,47.24) ; C305.2 v1(153.66,49.16) ; R786.1 C996.1 202.45,130.69 v1(202.69,130.94) ; R1013.2 v1(244.6,139.57) ; C897.2 v1(13.34,59.31) ; J46.3 258.41,246.34 ; J46.3 258.41,244.64 ; J46.3 256.71,244.64 ; J46.3 256.71,246.34 ; R951.1 v1(100.21,31.76) ; v1(81.03,79.76) 80.9,79.88 R672.1 ; R1009.1 v1(223.71,125.48) ; J19.34 v1(189.48,197.08) ; Y7.4 v1(176.87,47.33) ; C277.2 v1(124.84,36.58) ; C6.2 v1(181.73,164.2) ; C938.1 v1(201.17,73.03) ; R261.2 v1(145.16,46.1) ; C1024.2 49.4,132.09 v1(49.4,132.08) ; Q35.2 43.88,134.04 v1(44.32,133.6) R821.1 ; v1(73.03,90.93) 72.99,90.89 D1.1 ; v1(55.75,129.54) 55.81,129.48 Q28.2 ; C1231.1 v1(215.39,64.76) ; v1(151.26,54.61) 151,54.86 C57.2 ; C1393.2 v1(239.01,120.14) ; C272.2 v1(134.61,71.87) ; C37.2 v1(254.89,141.99) ; C743.2 v1(150.11,62.11) ; J19.27 v1(178.31,199.88) ; Q15.2 v1(38.22,105.16) ; R534.2 v1(234.7,144.91) ; v1(56.64,124.46) 56.63,124.45 Q27.2 ; C329.2 v1(133.48,39.62) ; R673.1 v1(44.45,92.84) ; Y6.2 99.88,82.23 v1(99.82,82.17) ; C1287.2 v1(231.01,46.1) ; v1(105.28,32.38) 105.27,32.38 R162.1 ; R519.2 v1(244.6,135.89) ; C1391.2 v1(263.02,108.08) ; C896.2 v1(7.11,62.1) ; R542.1 v1(158.88,69.98) ; 2.56,6.51 SW5.3 ; SW5.3 4.47,8.42 ; SW5.3 4.47,6.51 ; SW5.3 2.56,8.42 ; C292.2 v1(124.84,30.23) ; C957.1 v1(19.94,106.55) ; C1375.2 v1(235.97,97.41) ; J20.35 v1(90.42,206.68) ; 231.31,246.34 J45.3 ; J45.3 231.31,244.64 ; J45.3 233.01,244.64 ; J45.3 233.01,246.34 ; J20.50 v1(82.22,212.68) ; v1(157.31,59.6) Y5.2 ; R782.1 v1(200.91,133.47) ; C14.2 v1(178.94,152.02) ; Q3.2 102.67,36.89 v1(102.61,36.83) ; C36.2 v1(255.91,141.99) ; C895.2 v1(16.25,65.02) ; R909.1 130.75,113.93 v1(130.74,113.92) 130.29,114.37 C1222.2 ; Q30.2 v1(11.3,66.67) ; Y2.2 126.58,50.33 v1(126.37,50.55) ; C279.2 v1(124.84,37.85) ; R538.1 v1(228.6,137.54) ; J19.4 v1(186.51,212.28) ; R699.1 v1(22.99,10.03) ; C297.2 v1(165.35,42.29) ; C1116.2 v1(105.92,90.55) ; J20.9 v1(90.42,193.08) ; R979.1 v1(230.77,98.43) ; C893.2 v1(19.94,61.72) ; R1014.1 v1(244.6,138.3) ; v1(152.15,164.72) 152.51,164.72 C15.2 152.51,165.73 v1(152.15,165.73) ; R995.2 v1(239.01,123.19) ; J33.3 220.31,246.34 ; J33.3 218.61,244.64 ; J33.3 220.31,244.64 ; J33.3 218.61,246.34 ; J19.15 v1(181.28,207.88) ; C10.2 v1(168.91,152.02) ; C604.2 v1(76.71,190.25) ; R543.1 v1(154.94,73.03) ; C338.2 148.58,41.54 v1(148.34,41.78) ; C977.1 v1(57.4,85.6) ; C48.2 v1(257.82,143.9) ; C1288.2 v1(231.01,43.81) ; C340.2 v1(131.44,49.79) ; J20.4 v1(82.22,191.08) ; Q21.2 v1(38.09,95.51) ; C603.2 v1(192.02,213.11) ; J20.26 v1(82.22,203.08) ; v1(83.44,78.36) C175.2 v1(82.46,79.34) ; R535.1 v1(228.6,138.81) ; J1.235 221.92,162.35 C20.2 ; C1016.2 v1(212.61,126.25) ; R400.2 v1(265.94,93.6) ; C956.1 v1(19.94,117.35) ; R669.1 v1(40.77,103.38) 41.28,102.86 C873.1 ; U102.4 v1(206.88,41.15) ; C286.2 v1(127.5,71.87) ; R1007.1 v1(227.08,123.56) ; C1390.2 v1(259.21,107.32) ; v1(148.59,49.91) 148.8,49.7 Y1.2 ; Q4.2 97.97,36.89 v1(97.91,36.83) ; R178.1 v1(61.72,146.05) ; C738.2 v1(155.58,63.62) ; C1223.2 v1(98.55,98.43) ; C605.2 v1(76.71,213.47) ; v1(47.87,109.61) C701.2 C702.2 ; R228.2 v1(167.39,46.48) ; C751.2 v1(145.67,65.53) ; C750.2 v1(145.63,63.33) ; J20.18 v1(79.25,199.88) ; C16.2 v1(149.61,166.5) ; R1005.1 v1(226.44,119.76) ; C11.2 v1(164.85,164.2) ; R997.2 v1(256.16,112.78) ; R838.2 v1(228.6,135.13) ; R1004.1 v1(259.21,118.75) ; R708.1 v1(20.32,68.07) ; R161.1 v1(96.4,33.52) ; C1115.2 v1(105.54,89.28) ; J20.34 v1(79.25,206.28) ; J46.1 263.49,246.34 ; J46.1 263.49,244.64 ; J46.1 261.79,244.64 ; J46.1 261.79,246.34 ; C981.1 v1(19.94,95.76) ; C602.2 v1(192.02,189.88) ; C7.2 v1(159.14,164.2) ; C746.2 v1(156.2,70.87) ; C12.2 v1(156.22,164.2) ; R523.2 v1(244.6,137.16) ; R262.2 v1(133.73,55.75) ; J19.40 v1(189.48,194.68) ; J20.29 v1(90.42,204.28) ; Y1.4 151.51,52.07 v1(151.51,53.09) 151.13,53.47 C304.2 ; C335.2 v1(132.46,48.64) ; R1000.2 v1(261.37,107.32) ; R1002.2 v1(260.35,107.32) ; C728.2 v1(90.29,106.43) ; v1(199.64,126.99) C1079.2 ; C132.2 v1(90.29,91.31) ; SW3.9 v1(107.06,144.02) ; R528.1 v1(237.11,144.91) ; R233.2 v1(155.96,55.12) ; v1(173.35,164.59) 173.35,164.96 C1.2 172.34,164.96 v1(172.34,164.59) 171.58,164.59 C8.2 ; C932.1 v1(221.49,131.7) ; C9.2 v1(166.88,152.02) ; C1015.2 v1(213.61,125.22) ; C747.2 v1(147.45,67.69) ; C331.1 v1(142.36,51.94) ; U50.2 v1(137.41,42.29) ; R527.2 v1(235.97,144.91) ; Q20.2 v1(75.68,84.21) ; C289.2 v1(124.84,32.77) ; C5.2 v1(167.89,164.2) ; Y8.4 v1(227.67,47.33) ; C1392.2 v1(235.2,126.49) ; R993.2 v1(256.16,111.51) ; R999.2 v1(239.01,124.46)
  TOP w1.016: 12.3,95.47 J37.5 ; J37.5 12.3,97.45 ; J37.5 14.28,95.47 ; J37.5 14.28,97.45 ; 12.3,87.07 J37.7 ; J37.7 12.3,89.05 ; J37.7 14.28,89.05 ; J37.7 14.28,87.07 ; 12.3,103.87 J37.3 ; J37.3 14.28,105.85 ; J37.3 12.3,105.85 ; J37.3 14.28,103.87 ; C195.2 63.03,125.39 J35.2 ; 6.8,95.47 J37.15 ; J37.15 6.8,97.45 ; J37.15 8.78,95.47 ; J37.15 8.78,97.45 ; J37.16 8.78,93.25 ; J37.16 6.8,93.25 ; J37.16 8.78,91.27 ; J37.16 6.8,91.27 ; 6.8,103.87 J37.13 ; J37.13 8.78,105.85 ; J37.13 8.78,103.87 ; J37.13 6.8,105.85 ; 6.8,87.07 J37.17 ; J37.17 8.78,87.07 ; J37.17 8.78,89.05 ; J37.17 6.8,89.05
  L2GND w0.508: SW5.1 5.47,4.26 ; SW5.1 4.06,5.67 ; SW5.1 4.06,4.26 ; SW5.1 5.47,5.67 ; 118.39,159.98 J1.136 ; J1.136 118.39,158.92 ; J1.136 119.45,159.98 ; J1.136 119.45,158.92 ; 231.45,246.2 J45.3 ; J45.3 232.86,244.78 ; J45.3 232.86,246.2 ; J45.3 231.45,244.78 ; 216.39,156.18 J1.110 ; J1.110 217.45,156.18 ; J1.110 216.39,155.12 ; J1.110 217.45,155.12 ; 103.39,161.88 J1.121 ; J1.121 104.45,161.88 ; J1.121 104.45,160.82 ; J1.121 103.39,160.82 ; 12.2,8.28 SW4.3 ; SW4.3 13.83,6.65 ; SW4.3 13.83,8.28 ; SW4.3 12.2,6.65 ; 116.39,155.12 J1.14 ; J1.14 117.45,155.12 ; J1.14 117.45,156.18 ; J1.14 116.39,156.18 ; 139.71,25.5 J13.A5 ; J13.A5 141.05,25.5 ; J13.A5 141.05,24.15 ; J13.A5 139.71,24.15 ; 140.98,16.34 J13.B5 ; J13.B5 140.98,14.99 ; J13.B5 142.32,14.99 ; J13.B5 142.32,16.34 ; 172.65,50.47 J51.7 ; J51.7 172.65,51.89 ; J51.7 174.06,51.89 ; J51.7 174.06,50.47 ; J1.107 214.45,157.02 ; J1.107 213.39,157.02 ; J1.107 213.39,158.08 ; J1.107 214.45,158.08 ; J1.130 113.45,159.98 ; J1.130 113.45,158.92 ; J1.130 112.39,158.92 ; J1.130 112.39,159.98 ; J1.214 201.45,158.92 ; J1.214 200.39,159.98 ; J1.214 200.39,158.92 ; J1.214 201.45,159.98 ; 275.48,98.51 J18.B16 ; J18.B16 275.48,99.64 ; J18.B16 276.61,99.64 ; J18.B16 276.61,98.51 ; 218.75,246.2 J33.3 ; J33.3 220.16,246.2 ; J33.3 220.16,244.78 ; J33.3 218.75,244.78 ; 268.98,94.51 J18.A12 ; J18.A12 270.11,95.64 ; J18.A12 268.98,95.64 ; J18.A12 270.11,94.51 ; 256.85,244.78 J46.3 ; J46.3 258.26,246.2 ; J46.3 258.26,244.78 ; J46.3 256.85,246.2 ; 128.39,155.12 J1.26 ; J1.26 129.45,155.12 ; J1.26 128.39,156.18 ; J1.26 129.45,156.18 ; J44.1 250.64,246.2 ; J44.1 250.64,244.78 ; J44.1 249.23,246.2 ; J44.1 249.23,244.78 ; J1.119 226.45,158.08 ; J1.119 226.45,157.02 ; J1.119 225.39,158.08 ; J1.119 225.39,157.02 ; J26.10 7.44,123.64 ; J26.10 6.02,122.23 ; J26.10 7.44,122.23 ; J26.10 6.02,123.64 ; 236.53,244.78 J45.1 ; J45.1 237.94,246.2 ; J45.1 237.94,244.78 ; J45.1 236.53,246.2 ; 133.39,161.88 J1.151 ; J1.151 134.45,161.88 ; J1.151 134.45,160.82 ; J1.151 133.39,160.82 ; J13.A4 142.32,22.96 ; J13.A4 140.98,21.61 ; J13.A4 142.32,21.61 ; J13.A4 140.98,22.96 ; 225.39,161.88 J1.239 ; J1.239 225.39,160.82 ; J1.239 226.45,161.88 ; J1.239 226.45,160.82 ; J48.2 7.44,55.06 ; J48.2 6.02,55.06 ; J48.2 6.02,53.65 ; J48.2 7.44,53.65 ; 192.39,156.18 J1.86 ; J1.86 193.45,156.18 ; J1.86 193.45,155.12 ; J1.86 192.39,155.12 ; J1.148 131.45,159.98 ; J1.148 131.45,158.92 ; J1.148 130.39,158.92 ; J1.148 130.39,159.98 ; 115.39,161.88 J1.133 ; J1.133 116.45,161.88 ; J1.133 116.45,160.82 ; J1.133 115.39,160.82 ; 131.39,157.02 J1.29 ; J1.29 132.45,158.08 ; J1.29 131.39,158.08 ; J1.29 132.45,157.02 ; J1.5 108.45,157.02 ; J1.5 107.39,158.08 ; J1.5 107.39,157.02 ; J1.5 108.45,158.08 ; J61.2 56.59,88.85 ; J61.2 56.59,87.43 ; J61.2 55.17,87.43 ; J61.2 55.17,88.85 ; 218.39,159.98 J1.232 ; J1.232 218.39,158.92 ; J1.232 219.45,158.92 ; J1.232 219.45,159.98 ; 11.74,53.65 J47.2 ; J47.2 11.74,55.06 ; J47.2 13.15,53.65 ; J47.2 13.15,55.06 ; J1.113 220.45,158.08 ; J1.113 220.45,157.02 ; J1.113 219.39,157.02 ; J1.113 219.39,158.08 ; 273.48,88.64 J18.B7 ; J18.B7 273.48,87.51 ; J18.B7 274.61,88.64 ; J18.B7 274.61,87.51 ; J1.20 123.45,155.12 ; J1.20 122.39,155.12 ; J1.20 123.45,156.18 ; J1.20 122.39,156.18 ; J1.95 202.45,157.02 ; J1.95 201.39,157.02 ; J1.95 202.45,158.08 ; J1.95 201.39,158.08 ; J18.A18 270.11,101.64 ; J18.A18 268.98,100.51 ; J18.A18 270.11,100.51 ; J18.A18 268.98,101.64 ; 207.39,158.08 J1.101 ; J1.101 208.45,158.08 ; J1.101 207.39,157.02 ; J1.101 208.45,157.02 ; J1.229 216.45,160.82 ; J1.229 215.39,160.82 ; J1.229 216.45,161.88 ; J1.229 215.39,161.88 ; 203.39,161.88 J1.217 ; J1.217 204.45,160.82 ; J1.217 203.39,160.82 ; J1.217 204.45,161.88 ; J1.226 213.45,158.92 ; J1.226 213.45,159.98 ; J1.226 212.39,159.98 ; J1.226 212.39,158.92 ; J1.8 111.45,155.12 ; J1.8 110.39,155.12 ; J1.8 111.45,156.18 ; J1.8 110.39,156.18 ; 175.73,52.11 J52.1 ; J52.1 177.59,50.25 ; J52.1 175.73,50.25 ; J52.1 177.59,52.11 ; J1.89 196.45,157.02 ; J1.89 195.39,158.08 ; J1.89 196.45,158.08 ; J1.89 195.39,157.02 ; J1.17 120.45,158.08 ; J1.17 120.45,157.02 ; J1.17 119.39,158.08 ; J1.17 119.39,157.02 ; 109.39,161.88 J1.127 ; J1.127 109.39,160.82 ; J1.127 110.45,161.88 ; J1.127 110.45,160.82 ; SW5.4 11.33,6.65 ; SW5.4 11.33,8.28 ; SW5.4 9.7,6.65 ; SW5.4 9.7,8.28 ; J1.220 207.45,158.92 ; J1.220 206.39,158.92 ; J1.220 206.39,159.98 ; J1.220 207.45,159.98 ; 197.39,160.82 J1.211 ; J1.211 197.39,161.88 ; J1.211 198.45,160.82 ; J1.211 198.45,161.88 ; J1.145 128.45,161.88 ; J1.145 127.39,160.82 ; J1.145 127.39,161.88 ; J1.145 128.45,160.82 ; J26.2 17.6,123.64 ; J26.2 16.18,123.64 ; J26.2 17.6,122.23 ; J26.2 16.18,122.23 ; J1.38 141.45,156.18 ; J1.38 140.39,156.18 ; J1.38 140.39,155.12 ; J1.38 141.45,155.12 ; J1.157 140.45,161.88 ; J1.157 139.39,160.82 ; J1.157 140.45,160.82 ; J1.157 139.39,161.88 ; J18.A4 270.11,85.64 ; J18.A4 270.11,84.51 ; J18.A4 268.98,85.64 ; J18.A4 268.98,84.51 ; 143.39,158.08 J1.41 ; J1.41 143.39,157.02 ; J1.41 144.45,158.08 ; J1.41 144.45,157.02 ; J18.B13 274.61,95.51 ; J18.B13 273.48,95.51 ; J18.B13 273.48,96.64 ; J18.B13 274.61,96.64 ; J1.160 143.45,158.92 ; J1.160 142.39,159.98 ; J1.160 142.39,158.92 ; J1.160 143.45,159.98 ; 226.53,52.11 J54.1 ; J54.1 226.53,50.25 ; J54.1 228.39,52.11 ; J54.1 228.39,50.25 ; J1.199 186.45,161.88 ; J1.199 185.39,160.82 ; J1.199 186.45,160.82 ; J1.199 185.39,161.88 ; 275.48,84.51 J18.B4 ; J18.B4 276.61,84.51 ; J18.B4 276.61,85.64 ; J18.B4 275.48,85.64 ; 113.39,157.02 J1.11 ; J1.11 114.45,158.08 ; J1.11 114.45,157.02 ; J1.11 113.39,158.08 ; 186.39,155.12 J1.80 ; J1.80 187.45,155.12 ; J1.80 186.39,156.18 ; J1.80 187.45,156.18 ; J60.1 168.95,65.49 ; J60.1 167.09,65.49 ; J60.1 167.09,67.35 ; J60.1 168.95,67.35 ; J1.83 190.45,158.08 ; J1.83 190.45,157.02 ; J1.83 189.39,157.02 ; J1.83 189.39,158.08 ; J1.104 211.45,155.12 ; J1.104 210.39,156.18 ; J1.104 210.39,155.12 ; J1.104 211.45,156.18 ; 149.39,157.02 J1.47 ; J1.47 150.45,158.08 ; J1.47 150.45,157.02 ; J1.47 149.39,158.08 ; J58.3 260.17,75.75 ; J58.3 260.17,77.16 ; J58.3 258.75,77.16 ; J58.3 258.75,75.75 ; J1.116 223.45,155.12 ; J1.116 222.39,156.18 ; J1.116 223.45,156.18 ; J1.116 222.39,155.12 ; 209.39,161.88 J1.223 ; J1.223 209.39,160.82 ; J1.223 210.45,160.82 ; J1.223 210.45,161.88 ; 106.39,158.92 J1.124 ; J1.124 107.45,158.92 ; J1.124 106.39,159.98 ; J1.124 107.45,159.98 ; 223.39,160.82 J1.237 ; J1.237 224.45,161.88 ; J1.237 224.45,160.82 ; J1.237 223.39,161.88 ; 191.39,161.88 J1.205 ; J1.205 192.45,160.82 ; J1.205 192.45,161.88 ; J1.205 191.39,160.82 ; 223.83,246.2 J33.1 ; J33.1 225.24,246.2 ; J33.1 223.83,244.78 ; J33.1 225.24,244.78 ; J49.2 91.89,151.27 ; J49.2 90.48,151.27 ; J49.2 91.89,152.68 ; J49.2 90.48,152.68 ; J1.139 122.45,160.82 ; J1.139 122.45,161.88 ; J1.139 121.39,161.88 ; J1.139 121.39,160.82 ; J58.1 255.09,77.16 ; J58.1 253.67,77.16 ; J58.1 255.09,75.75 ; J58.1 253.67,75.75 ; J59.3 235.4,75.75 ; J59.3 233.99,75.75 ; J59.3 233.99,77.16 ; J59.3 235.4,77.16 ; J1.154 137.45,158.92 ; J1.154 136.39,158.92 ; J1.154 136.39,159.98 ; J1.154 137.45,159.98 ; 139.71,18.88 J13.B4 ; J13.B4 139.71,17.53 ; J13.B4 141.05,17.53 ; J13.B4 141.05,18.88 ; 198.39,156.18 J1.92 ; J1.92 199.45,156.18 ; J1.92 199.45,155.12 ; J1.92 198.39,155.12 ; SW4.4 20.83,6.65 ; SW4.4 19.2,6.65 ; SW4.4 20.83,8.28 ; SW4.4 19.2,8.28 ; J44.3 245.56,244.78 ; J44.3 244.15,244.78 ; J44.3 245.56,246.2 ; J44.3 244.15,246.2 ; 275.48,100.51 J18.B18 ; J18.B18 276.61,100.51 ; J18.B18 275.48,101.64 ; J18.B18 276.61,101.64 ; 148.39,158.92 J1.166 ; J1.166 149.45,159.98 ; J1.166 149.45,158.92 ; J1.166 148.39,159.98 ; 194.39,159.98 J1.208 ; J1.208 195.45,159.98 ; J1.208 195.45,158.92 ; J1.208 194.39,158.92 ; 228.91,77.16 J59.1 ; J59.1 228.91,75.75 ; J59.1 230.32,77.16 ; J59.1 230.32,75.75 ; J1.32 135.45,156.18 ; J1.32 135.45,155.12 ; J1.32 134.39,156.18 ; J1.32 134.39,155.12 ; 223.45,51.89 J55.7 ; J55.7 224.86,51.89 ; J55.7 224.86,50.47 ; J55.7 223.45,50.47 ; 125.39,158.08 J1.23 ; J1.23 126.45,158.08 ; J1.23 125.39,157.02 ; J1.23 126.45,157.02 ; J1.98 205.45,156.18 ; J1.98 205.45,155.12 ; J1.98 204.39,155.12 ; J1.98 204.39,156.18 ; SW5.3 4.33,8.28 ; SW5.3 2.7,6.65 ; SW5.3 2.7,8.28 ; SW5.3 4.33,6.65 ; J1.35 138.45,158.08 ; J1.35 137.39,157.02 ; J1.35 137.39,158.08 ; J1.35 138.45,157.02 ; J1.163 146.45,161.88 ; J1.163 145.39,160.82 ; J1.163 145.39,161.88 ; J1.163 146.45,160.82 ; J1.235 222.45,161.88 ; J1.235 221.39,160.82 ; J1.235 221.39,161.88 ; J1.235 222.45,160.82 ; 104.39,155.12 J1.2 ; J1.2 105.45,156.18 ; J1.2 104.39,156.18 ; J1.2 105.45,155.12 ; J18.A1 272.27,82.8 ; J18.A1 272.27,81.35 ; J18.A1 270.82,81.35 ; J18.A1 270.82,82.8 ; 146.39,155.12 J1.44 ; J1.44 146.39,156.18 ; J1.44 147.45,156.18 ; J1.44 147.45,155.12 ; J1.202 189.45,159.98 ; J1.202 188.39,159.98 ; J1.202 188.39,158.92 ; J1.202 189.45,158.92 ; J46.1 263.34,246.2 ; J46.1 261.93,244.78 ; J46.1 263.34,244.78 ; J46.1 261.93,246.2 ; 13.56,5.67 SW4.1 ; SW4.1 14.97,4.26 ; SW4.1 14.97,5.67 ; SW4.1 13.56,4.26 ; J35.2 64.72,125.66 ; J35.2 63.3,125.66 ; J35.2 64.72,127.07 ; J35.2 63.3,127.07 ; 124.39,158.92 J1.142 ; J1.142 125.45,158.92 ; J1.142 125.45,159.98 ; J1.142 124.39,159.98 ; J18.A15 272.11,98.64 ; J18.A15 272.11,97.51 ; J18.A15 270.98,97.51 ; J18.A15 270.98,98.64
  L2GND w1.016: J37.17 8.78,87.07 ; J37.17 6.8,89.05 ; J37.17 8.78,89.05 ; J37.17 6.8,87.07 ; J37.3 14.28,103.87 ; J37.3 12.3,103.87 ; J37.3 12.3,105.85 ; J37.3 14.28,105.85 ; 12.3,97.45 J37.5 ; J37.5 12.3,95.47 ; J37.5 14.28,97.45 ; J37.5 14.28,95.47 ; 6.8,95.47 J37.15 ; J37.15 8.78,95.47 ; J37.15 6.8,97.45 ; J37.15 8.78,97.45 ; 12.3,87.07 J37.7 ; J37.7 14.28,89.05 ; J37.7 14.28,87.07 ; J37.7 12.3,89.05 ; J37.16 8.78,91.27 ; J37.16 8.78,93.25 ; J37.16 6.8,93.25 ; J37.16 6.8,91.27 ; 6.8,103.87 J37.13 ; J37.13 8.78,103.87 ; J37.13 6.8,105.85 ; J37.13 8.78,105.85
  L3SIG w0.508: v1(147.19,17.78) 149.48,17.78 151,16.26 151,14.48 153.42,12.06 153.42,10.92 155.2,9.14 J14.B10 ; J44.3 245.56,244.78 ; J44.3 245.56,246.2 ; J44.3 244.15,244.78 ; J44.3 244.15,246.2 ; 249.23,246.2 J44.1 ; J44.1 250.64,244.78 ; J44.1 250.64,246.2 ; J44.1 249.23,244.78 ; 236.53,244.78 J45.1 ; J45.1 237.94,244.78 ; J45.1 236.53,246.2 ; J45.1 237.94,246.2 ; J33.1 225.24,246.2 ; J33.1 225.24,244.78 ; J33.1 223.83,246.2 ; J33.1 223.83,244.78 ; 218.75,246.2 J33.3 ; J33.3 220.16,244.78 ; J33.3 220.16,246.2 ; J33.3 218.75,244.78 ; J46.3 258.26,244.78 ; J46.3 256.85,246.2 ; J46.3 258.26,246.2 ; J46.3 256.85,244.78 ; J46.1 263.34,246.2 ; J46.1 261.93,246.2 ; J46.1 263.34,244.78 ; J46.1 261.93,244.78 ; 231.45,244.78 J45.3 ; J45.3 232.86,244.78 ; J45.3 231.45,246.2 ; J45.3 232.86,246.2
  L4PWR w0.508: J44.3 245.56,244.78 ; J44.3 244.15,244.78 ; J44.3 245.56,246.2 ; J44.3 244.15,246.2 ; 236.53,244.78 J45.1 ; J45.1 237.94,246.2 ; J45.1 237.94,244.78 ; J45.1 236.53,246.2 ; 19.2,6.65 SW4.4 ; SW4.4 20.83,6.65 ; SW4.4 19.2,8.28 ; SW4.4 20.83,8.28 ; 13.56,5.67 SW4.1 ; SW4.1 13.56,4.26 ; SW4.1 14.97,4.26 ; SW4.1 14.97,5.67 ; SW4.3 13.83,8.28 ; SW4.3 12.2,8.28 ; SW4.3 13.83,6.65 ; SW4.3 12.2,6.65 ; 140.98,22.96 J13.A4 ; J13.A4 140.98,21.61 ; J13.A4 142.32,21.61 ; J13.A4 142.32,22.96 ; 139.71,17.53 J13.B4 ; J13.B4 141.05,18.88 ; J13.B4 141.05,17.53 ; J13.B4 139.71,18.88 ; 261.93,244.78 J46.1 ; J46.1 263.34,244.78 ; J46.1 263.34,246.2 ; J46.1 261.93,246.2 ; J46.3 258.26,246.2 ; J46.3 258.26,244.78 ; J46.3 256.85,246.2 ; J46.3 256.85,244.78 ; 6.02,123.64 J26.10 ; J26.10 7.44,122.23 ; J26.10 6.02,122.23 ; J26.10 7.44,123.64 ; J33.3 220.16,246.2 ; J33.3 218.75,246.2 ; J33.3 218.75,244.78 ; J33.3 220.16,244.78 ; 231.45,244.78 J45.3 ; J45.3 232.86,244.78 ; J45.3 231.45,246.2 ; J45.3 232.86,246.2 ; 226.53,52.11 J54.1 ; J54.1 228.39,50.25 ; J54.1 226.53,50.25 ; J54.1 228.39,52.11 ; J44.1 250.64,246.2 ; J44.1 249.23,244.78 ; J44.1 250.64,244.78 ; J44.1 249.23,246.2 ; 2.7,8.28 SW5.3 ; SW5.3 4.33,6.65 ; SW5.3 2.7,6.65 ; SW5.3 4.33,8.28 ; J48.2 7.44,55.06 ; J48.2 6.02,55.06 ; J48.2 7.44,53.65 ; J48.2 6.02,53.65 ; 11.74,53.65 J47.2 11.74,55.06 ; 9.7,8.28 SW5.4 ; SW5.4 9.7,6.65 ; SW5.4 11.33,6.65 ; SW5.4 11.33,8.28 ; J55.7 224.86,50.47 ; J55.7 224.86,51.89 ; J55.7 223.45,50.47 ; J55.7 223.45,51.89 ; J13.B5 142.32,16.34 ; J13.B5 140.98,16.34 ; J13.B5 142.32,14.99 ; J13.B5 140.98,14.99 ; 223.83,244.78 J33.1 ; J33.1 225.24,244.78 ; J33.1 225.24,246.2 ; J33.1 223.83,246.2 ; 141.05,24.15 J13.A5 139.71,24.15 ; SW5.1 5.47,5.67 ; SW5.1 4.06,5.67 ; SW5.1 5.47,4.26 ; SW5.1 4.06,4.26
  L4PWR w1.016: 6.8,91.27 J37.16 ; J37.16 6.8,93.25 ; J37.16 8.78,91.27 ; J37.16 8.78,93.25 ; 6.8,97.45 J37.15 ; J37.15 6.8,95.47 ; J37.15 8.78,95.47 ; J37.15 8.78,97.45 ; 6.8,87.07 J37.17 ; J37.17 6.8,89.05 ; J37.17 8.78,87.07 ; J37.17 8.78,89.05 ; 11.96,96.46 J37.5 12,95.91 ; 12,87.51 J37.7 11.96,88.06 ; J37.13 8.78,103.87 ; J37.13 6.8,103.87 ; J37.13 6.8,105.85 ; J37.13 8.78,105.85 ; 11.96,104.86 J37.3 12,104.31
  L5PWR w0.508: SW4.1 14.97,4.26 ; SW4.1 13.56,4.26 ; SW4.1 14.97,5.67 ; SW4.1 13.56,5.67 ; 253.67,77.16 J58.1 ; J58.1 255.09,77.16 ; J58.1 255.09,75.75 ; J58.1 253.67,75.75 ; J18.A18 270.11,101.64 ; J18.A18 270.11,100.51 ; J18.A18 268.98,100.51 ; J18.A18 268.98,101.64 ; 139.71,17.53 J13.B4 ; J13.B4 139.71,18.88 ; J13.B4 141.05,17.53 ; J13.B4 141.05,18.88 ; 228.91,77.16 J59.1 ; J59.1 230.32,77.16 ; J59.1 228.91,75.75 ; J59.1 230.32,75.75 ; J46.3 258.26,244.78 ; J46.3 258.26,246.2 ; J46.3 256.85,244.78 ; J46.3 256.85,246.2 ; 275.48,85.64 J18.B4 ; J18.B4 275.48,84.51 ; J18.B4 276.61,84.51 ; J18.B4 276.61,85.64 ; J13.A4 142.32,22.96 ; J13.A4 140.98,21.61 ; J13.A4 140.98,22.96 ; J13.A4 142.32,21.61 ; J18.B13 274.61,96.64 ; J18.B13 274.61,95.51 ; J18.B13 273.48,96.64 ; J18.B13 273.48,95.51 ; J47.2 13.15,53.65 ; J47.2 11.74,55.06 ; J47.2 13.15,55.06 ; J47.2 11.74,53.65 ; J18.B7 274.61,88.64 ; J18.B7 273.48,87.51 ; J18.B7 273.48,88.64 ; J18.B7 274.61,87.51 ; 268.98,84.51 J18.A4 ; J18.A4 270.11,84.51 ; J18.A4 270.11,85.64 ; J18.A4 268.98,85.64 ; 140.98,14.99 J13.B5 ; J13.B5 142.32,14.99 ; J13.B5 140.98,16.34 ; J13.B5 142.32,16.34 ; 258.75,77.16 J58.3 ; J58.3 260.17,77.16 ; J58.3 258.75,75.75 ; J58.3 260.17,75.75 ; J33.1 225.24,244.78 ; J33.1 225.24,246.2 ; J33.1 223.83,244.78 ; J33.1 223.83,246.2 ; J13.A5 141.05,25.5 ; J13.A5 139.71,25.5 ; J13.A5 139.71,24.15 ; J13.A5 141.05,24.15 ; J44.1 250.64,246.2 ; J44.1 249.23,246.2 ; J44.1 249.23,244.78 ; J44.1 250.64,244.78 ; J18.A1 272.27,82.8 ; J18.A1 270.82,82.8 ; J18.A1 272.27,81.35 ; J18.A1 270.82,81.35 ; 244.15,244.78 J44.3 ; J44.3 245.56,244.78 ; J44.3 245.56,246.2 ; J44.3 244.15,246.2 ; 218.75,246.2 J33.3 ; J33.3 220.16,244.78 ; J33.3 218.75,244.78 ; J33.3 220.16,246.2 ; 6.02,123.64 J26.10 ; J26.10 7.44,122.23 ; J26.10 7.44,123.64 ; J26.10 6.02,122.23 ; 6.02,53.65 J48.2 ; J48.2 6.02,55.06 ; J48.2 7.44,55.06 ; J48.2 7.44,53.65 ; 16.18,123.64 J26.2 ; J26.2 17.6,122.23 ; J26.2 17.6,123.64 ; J26.2 16.18,122.23 ; SW5.1 5.47,4.26 ; SW5.1 4.06,5.67 ; SW5.1 4.06,4.26 ; SW5.1 5.47,5.67 ; 9.7,8.28 SW5.4 ; SW5.4 11.33,6.65 ; SW5.4 9.7,6.65 ; SW5.4 11.33,8.28 ; J59.3 235.4,75.75 ; J59.3 235.4,77.16 ; J59.3 233.99,77.16 ; J59.3 233.99,75.75 ; J18.A15 272.11,98.64 ; J18.A15 270.98,97.51 ; J18.A15 270.98,98.64 ; J18.A15 272.11,97.51 ; J46.1 263.34,244.78 ; J46.1 261.93,244.78 ; J46.1 263.34,246.2 ; J46.1 261.93,246.2 ; J45.3 232.86,246.2 ; J45.3 231.45,244.78 ; J45.3 232.86,244.78 ; J45.3 231.45,246.2 ; J18.B18 276.61,101.64 ; J18.B18 275.48,101.64 ; J18.B18 275.48,100.51 ; J18.B18 276.61,100.51 ; J45.1 237.94,244.78 ; J45.1 237.94,246.2 ; J45.1 236.53,246.2 ; J45.1 236.53,244.78 ; 268.98,94.51 J18.A12 ; J18.A12 270.11,94.51 ; J18.A12 270.11,95.64 ; J18.A12 268.98,95.64 ; 275.48,98.51 J18.B16 ; J18.B16 275.48,99.64 ; J18.B16 276.61,98.51 ; J18.B16 276.61,99.64 ; SW4.4 20.83,8.28 ; SW4.4 20.83,6.65 ; SW4.4 19.2,6.65 ; SW4.4 19.2,8.28 ; SW5.3 4.33,6.65 ; SW5.3 4.33,8.28 ; SW5.3 2.7,6.65 ; SW5.3 2.7,8.28 ; 12.2,6.65 SW4.3 ; SW4.3 13.83,6.65 ; SW4.3 12.2,8.28 ; SW4.3 13.83,8.28
  L6SIG w0.508: 249.23,244.78 J44.1 ; J44.1 250.64,244.78 ; J44.1 249.23,246.2 ; J44.1 250.64,246.2 ; J33.3 220.16,246.2 ; J33.3 218.75,244.78 ; J33.3 218.75,246.2 ; J33.3 220.16,244.78 ; J33.1 225.24,244.78 ; J33.1 223.83,244.78 ; J33.1 225.24,246.2 ; J33.1 223.83,246.2 ; J46.3 258.26,244.78 ; J46.3 258.26,246.2 ; J46.3 256.85,244.78 ; J46.3 256.85,246.2 ; J45.1 237.94,246.2 ; J45.1 236.53,246.2 ; J45.1 237.94,244.78 ; J45.1 236.53,244.78 ; v1(154.3,36.83) 154.3,25.82 J14.A10 ; 261.93,244.78 J46.1 ; J46.1 261.93,246.2 ; J46.1 263.34,244.78 ; J46.1 263.34,246.2 ; 244.15,244.78 J44.3 ; J44.3 245.56,244.78 ; J44.3 244.15,246.2 ; J44.3 245.56,246.2 ; J45.3 232.86,244.78 ; J45.3 232.86,246.2 ; J45.3 231.45,244.78 ; J45.3 231.45,246.2
  L7GND w0.508: 222.39,156.18 J1.116 ; J1.116 223.45,155.12 ; J1.116 222.39,155.12 ; J1.116 223.45,156.18 ; 121.39,160.82 J1.139 ; J1.139 121.39,161.88 ; J1.139 122.45,160.82 ; J1.139 122.45,161.88 ; 110.39,156.18 J1.8 ; J1.8 110.39,155.12 ; J1.8 111.45,155.12 ; J1.8 111.45,156.18 ; J61.2 56.59,87.43 ; J61.2 55.17,87.43 ; J61.2 55.17,88.85 ; J61.2 56.59,88.85 ; 128.39,155.12 J1.26 ; J1.26 129.45,156.18 ; J1.26 128.39,156.18 ; J1.26 129.45,155.12 ; J58.1 255.09,77.16 ; J58.1 253.67,77.16 ; J58.1 255.09,75.75 ; J58.1 253.67,75.75 ; 270.98,98.64 J18.A15 ; J18.A15 272.11,98.64 ; J18.A15 272.11,97.51 ; J18.A15 270.98,97.51 ; J1.113 220.45,158.08 ; J1.113 219.39,158.08 ; J1.113 220.45,157.02 ; J1.113 219.39,157.02 ; 195.39,157.02 J1.89 ; J1.89 195.39,158.08 ; J1.89 196.45,158.08 ; J1.89 196.45,157.02 ; J1.47 150.45,158.08 ; J1.47 150.45,157.02 ; J1.47 149.39,158.08 ; J1.47 149.39,157.02 ; J1.20 123.45,156.18 ; J1.20 123.45,155.12 ; J1.20 122.39,156.18 ; J1.20 122.39,155.12 ; J18.B7 274.61,88.64 ; J18.B7 273.48,87.51 ; J18.B7 274.61,87.51 ; J18.B7 273.48,88.64 ; 140.39,156.18 J1.38 ; J1.38 141.45,155.12 ; J1.38 140.39,155.12 ; J1.38 141.45,156.18 ; 139.71,25.5 J13.A5 ; J13.A5 141.05,25.5 ; J13.A5 139.71,24.15 ; J13.A5 141.05,24.15 ; J1.239 226.45,160.82 ; J1.239 226.45,161.88 ; J1.239 225.39,161.88 ; J1.239 225.39,160.82 ; J1.124 107.45,159.98 ; J1.124 106.39,158.92 ; J1.124 107.45,158.92 ; J1.124 106.39,159.98 ; 143.39,157.02 J1.41 ; J1.41 144.45,158.08 ; J1.41 143.39,158.08 ; J1.41 144.45,157.02 ; SW4.3 13.83,8.28 ; SW4.3 13.83,6.65 ; SW4.3 12.2,6.65 ; SW4.3 12.2,8.28 ; J47.2 13.15,53.65 ; J47.2 11.74,55.06 ; J47.2 11.74,53.65 ; J47.2 13.15,55.06 ; J54.1 228.39,50.25 ; J54.1 228.39,52.11 ; J54.1 226.53,52.11 ; J54.1 226.53,50.25 ; 204.39,156.18 J1.98 ; J1.98 205.45,155.12 ; J1.98 204.39,155.12 ; J1.98 205.45,156.18 ; J1.11 114.45,158.08 ; J1.11 113.39,157.02 ; J1.11 114.45,157.02 ; J1.11 113.39,158.08 ; 268.98,94.51 J18.A12 ; J18.A12 270.11,95.64 ; J18.A12 268.98,95.64 ; J18.A12 270.11,94.51 ; J1.208 195.45,158.92 ; J1.208 195.45,159.98 ; J1.208 194.39,159.98 ; J1.208 194.39,158.92 ; 225.39,157.02 J1.119 ; J1.119 226.45,158.08 ; J1.119 226.45,157.02 ; J1.119 225.39,158.08 ; J18.B18 276.61,101.64 ; J18.B18 275.48,101.64 ; J18.B18 276.61,100.51 ; J18.B18 275.48,100.51 ; J46.1 263.34,244.78 ; J46.1 261.93,246.2 ; J46.1 261.93,244.78 ; J46.1 263.34,246.2 ; J1.86 193.45,155.12 ; J1.86 192.39,155.12 ; J1.86 192.39,156.18 ; J1.86 193.45,156.18 ; 107.39,158.08 J1.5 ; J1.5 108.45,158.08 ; J1.5 108.45,157.02 ; J1.5 107.39,157.02 ; J1.32 135.45,156.18 ; J1.32 135.45,155.12 ; J1.32 134.39,155.12 ; J1.32 134.39,156.18 ; 188.39,158.92 J1.202 ; J1.202 188.39,159.98 ; J1.202 189.45,158.92 ; J1.202 189.45,159.98 ; J49.2 91.89,151.27 ; J49.2 90.48,152.68 ; J49.2 91.89,152.68 ; J49.2 90.48,151.27 ; 175.73,50.25 J52.1 ; J52.1 175.73,52.11 ; J52.1 177.59,50.25 ; J52.1 177.59,52.11 ; 140.98,22.96 J13.A4 ; J13.A4 140.98,21.61 ; J13.A4 142.32,21.61 ; J13.A4 142.32,22.96 ; J18.B13 274.61,96.64 ; J18.B13 273.48,95.51 ; J18.B13 274.61,95.51 ; J18.B13 273.48,96.64 ; J1.142 125.45,158.92 ; J1.142 124.39,159.98 ; J1.142 124.39,158.92 ; J1.142 125.45,159.98 ; J45.3 232.86,246.2 ; J45.3 231.45,246.2 ; J45.3 231.45,244.78 ; J45.3 232.86,244.78 ; J33.1 225.24,244.78 ; J33.1 223.83,246.2 ; J33.1 225.24,246.2 ; J33.1 223.83,244.78 ; J1.226 213.45,159.98 ; J1.226 213.45,158.92 ; J1.226 212.39,158.92 ; J1.226 212.39,159.98 ; J1.163 146.45,161.88 ; J1.163 145.39,161.88 ; J1.163 146.45,160.82 ; J1.163 145.39,160.82 ; 249.23,244.78 J44.1 ; J44.1 250.64,246.2 ; J44.1 250.64,244.78 ; J44.1 249.23,246.2 ; SW5.3 4.33,6.65 ; SW5.3 2.7,8.28 ; SW5.3 4.33,8.28 ; SW5.3 2.7,6.65 ; J1.211 198.45,160.82 ; J1.211 197.39,161.88 ; J1.211 197.39,160.82 ; J1.211 198.45,161.88 ; 116.39,156.18 J1.14 ; J1.14 117.45,156.18 ; J1.14 116.39,155.12 ; J1.14 117.45,155.12 ; J1.83 190.45,157.02 ; J1.83 190.45,158.08 ; J1.83 189.39,157.02 ; J1.83 189.39,158.08 ; 139.39,160.82 J1.157 ; J1.157 140.45,161.88 ; J1.157 140.45,160.82 ; J1.157 139.39,161.88 ; J1.101 208.45,158.08 ; J1.101 208.45,157.02 ; J1.101 207.39,158.08 ; J1.101 207.39,157.02 ; J1.95 202.45,158.08 ; J1.95 201.39,158.08 ; J1.95 201.39,157.02 ; J1.95 202.45,157.02 ; 63.3,125.66 J35.2 ; J35.2 64.72,127.07 ; J35.2 64.72,125.66 ; J35.2 63.3,127.07 ; 172.65,51.89 J51.7 ; J51.7 172.65,50.47 ; J51.7 174.06,51.89 ; J51.7 174.06,50.47 ; 198.39,155.12 J1.92 ; J1.92 199.45,155.12 ; J1.92 198.39,156.18 ; J1.92 199.45,156.18 ; J58.3 260.17,75.75 ; J58.3 258.75,77.16 ; J58.3 260.17,77.16 ; J58.3 258.75,75.75 ; 148.39,158.92 J1.166 ; J1.166 149.45,159.98 ; J1.166 149.45,158.92 ; J1.166 148.39,159.98 ; 213.39,158.08 J1.107 ; J1.107 213.39,157.02 ; J1.107 214.45,158.08 ; J1.107 214.45,157.02 ; 104.39,155.12 J1.2 ; J1.2 105.45,156.18 ; J1.2 104.39,156.18 ; J1.2 105.45,155.12 ; 244.15,244.78 J44.3 ; J44.3 244.15,246.2 ; J44.3 245.56,244.78 ; J44.3 245.56,246.2 ; SW5.4 11.33,8.28 ; SW5.4 11.33,6.65 ; SW5.4 9.7,6.65 ; SW5.4 9.7,8.28 ; J1.235 222.45,161.88 ; J1.235 221.39,160.82 ; J1.235 222.45,160.82 ; J1.235 221.39,161.88 ; 275.48,98.51 J18.B16 ; J18.B16 276.61,98.51 ; J18.B16 276.61,99.64 ; J18.B16 275.48,99.64 ; J48.2 7.44,53.65 ; J48.2 6.02,55.06 ; J48.2 7.44,55.06 ; J48.2 6.02,53.65 ; 216.39,155.12 J1.110 ; J1.110 217.45,155.12 ; J1.110 217.45,156.18 ; J1.110 216.39,156.18 ; 218.75,244.78 J33.3 ; J33.3 220.16,244.78 ; J33.3 218.75,246.2 ; J33.3 220.16,246.2 ; 203.39,161.88 J1.217 ; J1.217 203.39,160.82 ; J1.217 204.45,160.82 ; J1.217 204.45,161.88 ; 13.56,4.26 SW4.1 ; SW4.1 14.97,5.67 ; SW4.1 13.56,5.67 ; SW4.1 14.97,4.26 ; 270.82,82.8 J18.A1 ; J18.A1 272.27,82.8 ; J18.A1 270.82,81.35 ; J18.A1 272.27,81.35 ; J1.136 119.45,159.98 ; J1.136 118.39,158.92 ; J1.136 118.39,159.98 ; J1.136 119.45,158.92 ; J1.232 219.45,158.92 ; J1.232 219.45,159.98 ; J1.232 218.39,158.92 ; J1.232 218.39,159.98 ; 139.71,18.88 J13.B4 ; J13.B4 139.71,17.53 ; J13.B4 141.05,17.53 ; J13.B4 141.05,18.88 ; 112.39,158.92 J1.130 ; J1.130 112.39,159.98 ; J1.130 113.45,159.98 ; J1.130 113.45,158.92 ; J18.B4 276.61,85.64 ; J18.B4 275.48,84.51 ; J18.B4 275.48,85.64 ; J18.B4 276.61,84.51 ; J1.29 132.45,157.02 ; J1.29 131.39,157.02 ; J1.29 131.39,158.08 ; J1.29 132.45,158.08 ; J26.2 17.6,122.23 ; J26.2 16.18,122.23 ; J26.2 16.18,123.64 ; J26.2 17.6,123.64 ; 167.09,67.35 J60.1 ; J60.1 167.09,65.49 ; J60.1 168.95,65.49 ; J60.1 168.95,67.35 ; 19.2,6.65 SW4.4 ; SW4.4 19.2,8.28 ; SW4.4 20.83,8.28 ; SW4.4 20.83,6.65 ; J1.237 224.45,160.82 ; J1.237 223.39,160.82 ; J1.237 223.39,161.88 ; J1.237 224.45,161.88 ; J1.145 128.45,160.82 ; J1.145 127.39,160.82 ; J1.145 127.39,161.88 ; J1.145 128.45,161.88 ; J1.154 137.45,158.92 ; J1.154 137.45,159.98 ; J1.154 136.39,158.92 ; J1.154 136.39,159.98 ; J18.A4 270.11,85.64 ; J18.A4 270.11,84.51 ; J18.A4 268.98,85.64 ; J18.A4 268.98,84.51 ; 210.39,155.12 J1.104 ; J1.104 210.39,156.18 ; J1.104 211.45,156.18 ; J1.104 211.45,155.12 ; J1.199 186.45,161.88 ; J1.199 186.45,160.82 ; J1.199 185.39,160.82 ; J1.199 185.39,161.88 ; 236.53,244.78 J45.1 ; J45.1 237.94,246.2 ; J45.1 236.53,246.2 ; J45.1 237.94,244.78 ; 223.45,50.47 J55.7 ; J55.7 224.86,51.89 ; J55.7 223.45,51.89 ; J55.7 224.86,50.47 ; 109.39,161.88 J1.127 ; J1.127 110.45,161.88 ; J1.127 109.39,160.82 ; J1.127 110.45,160.82 ; J26.10 7.44,123.64 ; J26.10 6.02,123.64 ; J26.10 6.02,122.23 ; J26.10 7.44,122.23 ; J1.220 207.45,158.92 ; J1.220 206.39,158.92 ; J1.220 207.45,159.98 ; J1.220 206.39,159.98 ; SW5.1 5.47,4.26 ; SW5.1 5.47,5.67 ; SW5.1 4.06,5.67 ; SW5.1 4.06,4.26 ; J59.1 230.32,75.75 ; J59.1 228.91,77.16 ; J59.1 230.32,77.16 ; J59.1 228.91,75.75 ; J1.17 120.45,158.08 ; J1.17 119.39,158.08 ; J1.17 120.45,157.02 ; J1.17 119.39,157.02 ; 137.39,158.08 J1.35 ; J1.35 138.45,157.02 ; J1.35 137.39,157.02 ; J1.35 138.45,158.08 ; J1.223 210.45,161.88 ; J1.223 210.45,160.82 ; J1.223 209.39,161.88 ; J1.223 209.39,160.82 ; J13.B5 142.32,16.34 ; J13.B5 142.32,14.99 ; J13.B5 140.98,16.34 ; J13.B5 140.98,14.99 ; J1.205 192.45,160.82 ; J1.205 191.39,161.88 ; J1.205 192.45,161.88 ; J1.205 191.39,160.82 ; 115.39,160.82 J1.133 ; J1.133 115.39,161.88 ; J1.133 116.45,161.88 ; J1.133 116.45,160.82 ; J1.229 216.45,161.88 ; J1.229 215.39,160.82 ; J1.229 216.45,160.82 ; J1.229 215.39,161.88 ; J1.214 201.45,159.98 ; J1.214 201.45,158.92 ; J1.214 200.39,158.92 ; J1.214 200.39,159.98 ; 186.39,155.12 J1.80 ; J1.80 187.45,156.18 ; J1.80 186.39,156.18 ; J1.80 187.45,155.12 ; 125.39,158.08 J1.23 ; J1.23 125.39,157.02 ; J1.23 126.45,157.02 ; J1.23 126.45,158.08 ; J18.A18 270.11,101.64 ; J18.A18 268.98,101.64 ; J18.A18 268.98,100.51 ; J18.A18 270.11,100.51 ; J1.44 147.45,155.12 ; J1.44 146.39,156.18 ; J1.44 146.39,155.12 ; J1.44 147.45,156.18 ; J1.151 134.45,160.82 ; J1.151 134.45,161.88 ; J1.151 133.39,161.88 ; J1.151 133.39,160.82 ; J1.160 143.45,159.98 ; J1.160 142.39,158.92 ; J1.160 142.39,159.98 ; J1.160 143.45,158.92 ; 256.85,244.78 J46.3 ; J46.3 256.85,246.2 ; J46.3 258.26,246.2 ; J46.3 258.26,244.78 ; 103.39,160.82 J1.121 ; J1.121 104.45,161.88 ; J1.121 103.39,161.88 ; J1.121 104.45,160.82 ; 130.39,159.98 J1.148 ; J1.148 131.45,159.98 ; J1.148 130.39,158.92 ; J1.148 131.45,158.92 ; J59.3 235.4,75.75 ; J59.3 235.4,77.16 ; J59.3 233.99,77.16 ; J59.3 233.99,75.75
  L7GND w1.016: 6.8,89.05 J37.17 ; J37.17 6.8,87.07 ; J37.17 8.78,87.07 ; J37.17 8.78,89.05 ; J37.7 14.28,87.07 ; J37.7 12.3,87.07 ; J37.7 12.3,89.05 ; J37.7 14.28,89.05 ; 6.8,103.87 J37.13 ; J37.13 6.8,105.85 ; J37.13 8.78,105.85 ; J37.13 8.78,103.87 ; 12.3,105.85 J37.3 ; J37.3 14.28,105.85 ; J37.3 12.3,103.87 ; J37.3 14.28,103.87 ; 6.8,95.47 J37.15 ; J37.15 8.78,95.47 ; J37.15 6.8,97.45 ; J37.15 8.78,97.45 ; 6.8,93.25 J37.16 ; J37.16 6.8,91.27 ; J37.16 8.78,91.27 ; J37.16 8.78,93.25 ; 12.3,97.45 J37.5 ; J37.5 14.28,95.47 ; J37.5 12.3,95.47 ; J37.5 14.28,97.45
  BOTTOM w0.254: U2.15 v1(124.39,128) ; U2.27 134.13,131.5 134.18,131.44 ; U2.45 v1(134.18,122.5) ; 134.18,131.44 v1(134.18,131) ; 134.18,131.44 134.18,131.76 133.94,132 U2.26 ; v1(134.18,131) U2.28 ; v1(134.18,131) 134.18,130.56 ; U2.4 v1(124.39,122.5) ; U2.1 v1(124.39,121) ; U2.24 v1(124.39,132.5) ; U2.10 v1(124.39,125.5) ; U2.39 v1(134.18,125.5) ; U2.21 v1(124.39,131) ; U2.29 134.12,130.5 134.18,130.56 ; U2.30 133.93,130 134.18,130.24 134.18,130.56 ; U2.32 133.89,129 134.18,128.71 v1(134.18,128) U2.34
  BOTTOM w0.305: v2(158.12,112.45) 158.3,112.26 C192.2 ; v2(158.12,110.05) 158.3,110.23 C208.2 ; v2(158.12,118.05) 158.3,118.23 C22.2 ; v1(75.82,97.92) 76.06,98.16 U21.3 ; U45.5 v1(143.93,119.55)
  BOTTOM w0.381: v1(44.45,38.48) U93.9 v1(44.45,36.2) ; C167.2 169.91,119.76 C254.2 ; v1(30.73,36.2) U94.9 v1(30.73,38.48)
  BOTTOM w0.457: v2(176.52,102.85) 177,102.36 C55.1 ; v2(158.12,102.85) 158.11,102.84 C172.2 ; v2(155.72,112.45) 155.69,112.47 C1264.2 ; v2(151,107.64) 151.44,108.08 C267.2 ; R123.1 177.46,103.51 v2(177.32,103.65) ; C913.2 165.41,118.75 v2(165.32,118.85) ; C257.2 151.58,110.62 v2(151,110.04) ; v2(178.18,109.22) 178.44,108.97 R124.2 ; v2(161.32,102.85) 161.17,102.7 C149.2 ; v2(166.92,109.25) 166.82,109.34 C238.2 ; C915.2 165.62,113.55 v2(165.32,113.25) ; C1263.2 151.72,113.16 v2(151,112.44) ; C914.2 165.52,111.44 v2(165.32,111.65) ; v2(155.72,110.05) 155.69,110.07 C258.2 ; C912.2 165.32,115.65 v2(165.32,115.65) ; C268.2 155.69,107.67 v2(155.72,107.65) ; v2(159.72,102.85) 159.74,102.82 159.82,102.82 160.22,102.41 160.22,101.43 C160.2 ; C169.2 166.12,123.65 v2(166.92,123.65) 166.85,123.71 R3.1 ; C56.2 v2(178.18,107.82)
  BOTTOM w0.508: 236.53,246.2 J45.1 ; J45.1 236.53,244.78 ; J45.1 237.94,244.78 ; J45.1 237.94,246.2 ; C50.2 69.09,143.13 v1(68.58,142.62) 68.07,143.13 C49.2 ; U65.H9 v1(65.52,107.43) ; v1(135.25,37.21) 135.49,37.44 C336.1 v1(137.03,38.61) ; R949.1 102.48,147.31 v1(103.12,147.95) 103.7,147.38 Q49.2 ; C332.1 v1(146.69,37.72) ; v1(103.51,152.02) 102.36,150.88 R945.1 ; C330.1 v1(143.64,37.72) ; v1(232.79,129.29) 232.96,129.12 C1049.2 ; J46.1 263.34,244.78 ; J46.1 261.93,246.2 ; J46.1 263.34,246.2 ; J46.1 261.93,244.78 ; v1(111,121.16) 110.74,120.9 C31.2 ; 244.15,244.78 J44.3 ; J44.3 245.56,246.2 ; J44.3 245.56,244.78 ; J44.3 244.15,246.2 ; v1(168.66,35.69) 168,35.69 C310.1 167.92,36.83 v1(168.66,36.83) ; v1(187.52,47.01) 187.51,47 R899.2 ; 2.7,8.28 SW5.3 ; SW5.3 4.33,8.28 ; SW5.3 2.7,6.65 ; SW5.3 4.33,6.65 ; J26.2 17.6,122.23 ; J26.2 17.6,123.64 ; J26.2 16.18,122.23 ; J26.2 16.18,123.64 ; R900.2 R892.2 184.91,45 185.51,45.6 R891.2 185.91,46 186.51,46.6 R889.2 C1182.1 ; v1(153.67,38.35) 153.67,37.55 153.31,37.19 ; v1(57.52,99.43) 58.01,99.92 C707.2 ; C705.2 58.01,112.93 v1(57.52,113.43) ; 11.74,53.65 J47.2 ; J47.2 13.15,53.65 ; J47.2 13.15,55.06 ; J47.2 11.74,55.06 ; SW4.3 13.83,8.28 ; SW4.3 13.83,6.65 ; SW4.3 12.2,6.65 ; SW4.3 12.2,8.28 ; 218.75,246.2 J33.3 ; J33.3 218.75,244.78 ; J33.3 220.16,244.78 ; J33.3 220.16,246.2 ; v1(234.31,49.01) 234.31,48.51 234.81,48.01 R963.2 236.31,48.01 R961.2 ; v1(65.52,104.43) 65.02,104.92 C1103.2 ; J26.10 7.44,122.23 ; J26.10 6.02,122.23 ; J26.10 6.02,123.64 ; J26.10 7.44,123.64 ; v1(153.03,101.35) 153.04,101.34 R814.1 153.8,101.35 ; U65.J10 v1(66.52,105.43) ; R901.1 188.52,40 v1(188.52,40.01) ; 19.2,8.28 SW4.4 ; SW4.4 19.2,6.65 ; SW4.4 20.83,6.65 ; SW4.4 20.83,8.28 ; 231.45,246.2 J45.3 ; J45.3 231.45,244.78 ; J45.3 232.86,246.2 ; J45.3 232.86,244.78 ; C1104.2 71.02,112.93 v1(71.52,113.43) ; R888.2 185.51,48.01 R890.2 184.01,48.01 183.51,48.51 v1(183.51,49.01) ; v1(78.36,101.47) 77.98,101.85 C54.2 ; v1(101.09,129.41) 101.1,129.41 C34.2 C33.2 ; C24.2 124.2,130.8 v1(124.39,131) ; 4.06,5.67 SW5.1 ; SW5.1 5.47,5.67 ; SW5.1 4.06,4.26 ; SW5.1 5.47,4.26 ; 13.56,5.67 SW4.1 ; SW4.1 14.97,4.26 ; SW4.1 13.56,4.26 ; SW4.1 14.97,5.67 ; R974.1 239.32,40 v1(239.32,40.01) ; v1(234.19,133.35) 234.4,133.13 C1040.2 ; C181.2 172.94,95.54 v1(172.72,95.76) ; C709.2 v1(62.52,104.43) ; v1(146.81,122.17) 147.06,122.42 C295.2 ; v1(155.32,45.21) 155.7,45.59 C324.2 ; R190.2 v1(192.15,125.09) ; v1(230.81,42.2) 230.46,42.55 C1362.2 v1(229.89,41.42) ; v1(63.52,108.43) 64.01,107.93 C711.2 ; 6.02,53.65 J48.2 ; J48.2 6.02,55.06 ; J48.2 7.44,53.65 ; J48.2 7.44,55.06 ; C52.2 76.21,97.53 v1(75.82,97.92) ; C1372.1 v1(234.83,17.28) ; v1(151.89,38.35) 151.89,37.97 152.68,37.19 C342.1 153.31,37.19 ; C333.1 v1(149.61,37.72) ; C1051.2 232.78,140.33 v1(232.54,140.08) ; C328.1 v1(140.59,37.72) ; v1(238.51,140.33) 238.16,140.68 C736.2 ; C1343.1 R962.2 237.31,46.6 236.71,46 R964.2 236.31,45.6 235.71,45 R967.2 R973.2 ; 9.7,8.28 SW5.4 ; SW5.4 11.33,8.28 ; SW5.4 9.7,6.65 ; SW5.4 11.33,6.65 ; C1274.2 90.92,132.07 v1(90.68,131.83) ; J33.1 225.24,244.78 ; J33.1 223.83,244.78 ; J33.1 225.24,246.2 ; J33.1 223.83,246.2 ; C298.1 v1(159.51,37.72) ; 153.31,37.19 153.95,37.19 v1(154.3,36.83) ; 249.23,244.78 J44.1 ; J44.1 249.23,246.2 ; J44.1 250.64,246.2 ; J44.1 250.64,244.78 ; C1379.2 110.86,95.24 v1(110.75,95.13) ; R13.1 v1(112.14,125.35) ; 256.85,246.2 J46.3 ; J46.3 258.26,246.2 ; J46.3 256.85,244.78 ; J46.3 258.26,244.78 ; C301.1 v1(165.48,37.72) ; Q38.2 151.7,129.53 R831.1 ; C38.2 v1(40.39,38.61) ; R172.1 v1(154.82,98.56) ; v1(179.09,41.42) C1194.2 179.66,42.55 v1(180.01,42.2) ; C341.2 129.67,45.34 v1(129.41,45.09) ; C715.2 v1(56.52,114.43) ; U65.J8 v1(63.52,105.43) ; C174.2 C173.2 C172.2 ; C706.2 v1(62.52,108.43) ; v1(65.52,108.43) 65.02,107.93 C712.2 ; v1(39.37,38.61) C39.2 39.36,37.85 R955.1 ; C1275.2 98.43,126.49 v1(98.55,126.37) ; 153.8,101.35 R171.1 ; 153.8,101.35 R173.1 ; C1365.2 v1(241.55,9.65) ; v1(151.38,44.45) 151.89,44.96 C309.2 ; C714.2 v1(66.52,108.43) ; C1197.2 v1(190.75,9.65) ; C1262.2 C138.2 C149.2 ; v1(134.18,128) 134.2,128.02 R106.1 ; C708.2 v1(56.52,98.43) ; C53.2 68.84,139.82 v1(68.58,140.08) 68.32,139.82 C51.2 ; v1(101.22,133.6) 100.83,133.99 C35.2 ; C1202.1 v1(184.03,17.28) ; R193.2 v1(192.15,128.91) ; C1102.2 64.01,104.92 v1(63.52,104.43) ; C1371.2 v1(239.52,9.65) ; C30.2 103.88,121.02 v1(104.01,121.16) ; C1200.2 v1(194.31,9.65) ; C1204.1 v1(183.77,19.05) ; J2.3 v1(40.07,32.64) ; C32.2 107.43,121.02 v1(107.57,121.16) ; C1367.1 v1(249.8,17.28) ; C299.1 v1(162.56,37.72) ; C296.1 v1(156.46,37.72) ; U65.H7 v1(62.52,107.43) ; R104.1 R105.1 151.9,117.6 C270.2 151.34,117.06 C269.2 150.62,116.59 v1(150.24,116.2) ; v1(133.1,45.85) 133.48,46.23 C356.2 ; v1(33.4,32.51) 33.4,32.51 J2.6 ; C1198.1 v1(199.13,22.36) ; C1199.1 v1(199.26,19.05) ; R972.2 238.31,47 v1(238.32,47.01) ; C161.2 C162.2 C160.2 ; C1201.1 v1(199,17.28) ; C1203.2 v1(188.72,9.65) ; C713.2 v1(70.52,100.42) ; C1370.1 v1(234.57,19.05) ; C1369.1 v1(250.06,19.05) ; v1(134.18,131) 134.37,130.8 C25.2 ; C1368.2 v1(245.11,9.65) ; C1366.1 v1(249.93,22.36) ; C1276.2 v1(90.43,128.01) ; C716.2 v1(66.52,104.43) ; C1277.2 v1(96.27,128.14) ; C1105.2 v1(72.52,114.43) ; C26.2 134.5,122.82 v1(134.18,122.5) ; C710.2 v1(72.52,98.43)
  BOTTOM w1.016: J37.15 8.78,95.47 ; J37.15 8.78,97.45 ; J37.15 6.8,97.45 ; J37.15 6.8,95.47 ; J37.3 14.28,103.87 ; J37.3 12.3,105.85 ; J37.3 14.28,105.85 ; J37.3 12.3,103.87 ; J37.5 14.28,95.47 ; J37.5 12.3,97.45 ; J37.5 12.3,95.47 ; J37.5 14.28,97.45 ; J37.17 8.78,89.05 ; J37.17 6.8,87.07 ; J37.17 6.8,89.05 ; J37.17 8.78,87.07 ; 12.3,87.07 J37.7 ; J37.7 12.3,89.05 ; J37.7 14.28,87.07 ; J37.7 14.28,89.05 ; J37.13 8.78,105.85 ; J37.13 6.8,105.85 ; J37.13 8.78,103.87 ; J37.13 6.8,103.87 ; 6.8,93.25 J37.16 ; J37.16 6.8,91.27 ; J37.16 8.78,93.25 ; J37.16 8.78,91.27
  vias: v1(7.37,126.87) v1(11.18,136.78) v1(12.57,126.75) v1(14.86,126.87) v1(16.76,86.49) v1(16.76,72.01) v1(17.53,86.49) v1(17.78,72.01) v1(18.16,156.59) v1(18.16,154.05) v1(18.16,151.51) v1(18.16,148.84) v1(18.16,146.3) v1(18.16,125.6) v1(18.29,141.35) v1(19.05,95.76) v1(19.18,86.49) v1(19.3,138.3) v1(19.94,86.49) v1(22.73,112.9) v1(22.73,112.14) v1(22.73,111.38) v1(22.73,102.11) v1(22.73,101.35) v1(22.73,100.58) v1(22.73,91.31) v1(22.73,90.55) v1(22.73,89.79) v1(24.38,109.47) v1(24.38,98.68) v1(24.38,87.88) v1(25.27,109.47) v1(25.27,98.68) v1(25.27,87.88) v1(25.78,108.59) v1(25.78,97.79) v1(25.78,87) v1(26.16,109.47) v1(26.16,98.68) v1(26.16,87.88) v1(26.67,108.59) v1(26.67,97.79) v1(26.67,87) v1(27.05,109.47) v1(27.05,98.68) v1(27.05,87.88) v1(30.35,76.71) v1(31.12,76.71) v1(31.24,116.97) v1(31.24,115.95) v1(31.24,114.81) v1(31.24,113.79) v1(31.24,112.65) v1(31.24,111.63) v1(31.24,110.49) v1(31.24,109.47) v1(31.24,106.17) v1(31.24,105.16) v1(31.24,104.01) v1(31.24,103) v1(31.24,101.85) v1(31.24,100.84) v1(31.24,99.7) v1(31.24,98.68) v1(31.24,95.89) v1(31.24,94.87) v1(31.24,93.73) v1(31.24,92.71) v1(31.24,91.57) v1(31.24,90.55) v1(31.24,89.41) v1(31.24,88.39) v1(32.38,76.71) v1(33.15,76.71) v1(34.54,75.82) v1(35.56,75.82) v1(41.27,77.98) v1(42.04,77.98) v1(43.81,77.98) v1(44.58,77.98) v1(44.83,120.14) v1(47.75,128.4) v1(48.26,127.64) v1(48.26,126.75) v1(50.42,65.53) v1(50.42,64.64) v1(50.42,58.04) v1(50.42,57.28) v1(50.42,56.52) v1(51.05,58.04) v1(51.05,57.28) v1(51.05,56.52) v1(51.18,74.55) v1(51.18,73.66) v1(51.18,65.53) v1(51.18,64.64) v1(52.7,142.75) v1(53.47,74.55) v1(53.47,73.66) v1(53.59,142.75) v1(54.1,114.55) v1(57.51,107.43) v1(57.51,103.42) v1(58.51,109.43) v1(58.51,105.43) v1(58.51,101.42) v1(59.51,102.42) v1(60.2,81.15) v1(60.2,80.39) v1(60.2,79.63) v1(60.52,106.43) v1(61.51,112.43) v1(61.51,102.42) v1(61.85,77.72) v1(62.51,99.42) v1(62.74,77.72) v1(63.25,76.84) v1(63.52,101.42) v1(63.63,77.72) v1(64.14,76.84) v1(64.26,142.68) v1(64.52,111.43) v1(64.52,77.72) v1(65.21,144.34) v1(65.34,143.32) v1(66.52,99.42) v1(67.52,108.43) v1(67.52,101.42) v1(67.95,83.31) v1(68.58,81.41) v1(68.58,80.52) v1(68.58,79.63) v1(68.58,78.74) v1(68.58,77.85) v1(68.71,82.55) v1(70.04,141.73) v1(70.52,108.43) v1(70.52,106.43) v1(71.82,144.02) v1(73.42,102.42) v1(75.82,86.36) v1(76.45,85.73) v1(78.36,102.23) v1(78.61,92.71) v1(78.61,91.95) v1(78.61,85.85) v1(78.87,95.38) v1(79.38,102.23) v1(79.38,85.85) v1(79.63,95.38) v1(80.39,102.23) v1(82.68,142.24) v1(83.57,142.24) v1(84.07,111.76) v1(84.45,142.24) v1(84.84,111.76) v1(86.11,87.5) v1(86.11,86.74) v1(86.87,105.16) v1(86.87,102.36) v1(86.87,96.9) v1(86.87,94.11) v1(87.63,105.16) v1(87.63,102.36) v1(87.63,96.9) v1(87.63,94.11) v1(87.76,185.42) v1(87.88,218.06) v1(88.65,185.42) v1(88.77,218.06) v1(89.28,87) v1(93.73,206.38) v1(93.73,204.6) v1(93.73,203.2) v1(93.73,201.42) v1(95.38,142.24) v1(96.27,142.24) v1(97.16,142.24) v1(97.15,20.95) v1(97.15,20.07) v1(97.15,19.18) v1(97.91,20.95) v1(97.91,20.07) v1(97.91,19.18) v1(100.45,28.19) v1(102.23,28.19) v1(104.01,105.28) v1(104.01,103.76) v1(104.01,23.37) v1(104.39,112.01) v1(104.39,111.12) v1(104.9,23.37) v1(105.66,101.85) v1(105.91,23.37) v1(106.55,101.85) v1(106.93,23.37) v1(106.93,11.56) v1(107.06,100.97) v1(107.44,112.01) v1(107.44,111.12) v1(107.44,101.85) v1(107.95,100.97) v1(108.33,101.85) v1(108.84,100.97) v1(108.96,29.97) v1(108.96,29.21) v1(109.03,13.84) v1(109.03,11.43) v1(109.47,111.89) v1(109.73,15.88) v1(109.85,29.97) v1(109.85,29.21) v1(110.11,13.21) v1(110.36,100.97) v1(110.74,29.97) v1(110.74,29.21) v1(111.76,111.89) v1(111.76,109.98) v1(111.76,108.2) v1(112.14,100.97) v1(113.02,22.23) v1(113.02,21.46) v1(113.15,31.88) v1(113.92,111.89) v1(113.92,109.98) v1(113.92,108.2) v1(113.92,106.43) v1(113.92,104.65) v1(113.92,102.87) v1(113.92,101.09) v1(114.04,22.23) v1(114.04,21.46) v1(114.42,31.88) v1(115.69,31.88) v1(115.95,111.89) v1(115.95,109.98) v1(115.95,108.2) v1(115.95,106.43) v1(115.95,104.65) v1(115.95,102.87) v1(115.95,101.09) v1(116.96,31.88) v1(117.98,111.89) v1(117.98,109.98) v1(117.98,108.2) v1(117.98,106.43) v1(117.98,104.65) v1(117.98,102.87) v1(117.98,101.09) v1(119.51,46.74) v1(119.51,45.97) v1(120.02,111.89) v1(120.02,109.98) v1(120.52,46.74) v1(120.52,45.97) v1(121.54,46.74) v1(121.54,45.97) v1(121.66,66.53) v1(121.66,65.38) v1(122.05,111.89) v1(122.05,109.98) v1(126.75,48.64) v1(127.89,85.22) v1(129.41,44.32) v1(131.83,58.55) v1(134.62,86.87) v1(134.87,84.71) v1(135,51.82) v1(135,50.55) v1(135,49.28) v1(135.25,35.94) v1(135.25,33.4) v1(135.25,32.13) v1(135.25,30.86) v1(136.27,51.82) v1(136.27,50.55) v1(136.27,49.28) v1(137.54,51.82) v1(137.54,50.55) v1(137.54,49.28) v1(137.79,16.76) v1(138.05,111.38) v1(138.05,109.86) v1(138.05,108.33) v1(138.05,106.81) v1(138.05,105.41) v1(138.05,104.01) v1(138.68,58.04) v1(139.06,109.86) v1(139.06,108.33) v1(139.06,106.81) v1(139.06,105.41) v1(139.06,104.01) v1(140.84,108.33) v1(140.84,106.68) v1(140.84,104.39) v1(141.86,55.24) v1(144.14,25.27) v1(144.14,17.27) v1(144.4,52.58) v1(145.16,23.37) v1(147.57,53.72) v1(151.38,43.69) v1(154.19,57.9) v1(154.81,154.43) v1(157.23,51.18) v1(157.23,49.91) v1(157.23,48.64) v1(158.5,51.18) v1(158.5,49.91) v1(158.5,48.64) v1(158.88,160.66) v1(159.77,51.18) v1(159.77,49.91) v1(159.77,48.64) v1(160.27,87.5) v1(161.54,53.34) v1(164.08,52.58) v1(164.97,160.53) v1(165.86,158.75) v1(166.88,160.53) v1(167.51,51.56) v1(169.93,158.75) v1(170.05,49.4) v1(170.94,160.53) v1(172.08,56.9) v1(172.97,158.24) v1(174.37,62.61) v1(174.37,59.82) v1(174.75,65.79) v1(175.01,202.06) v1(175.01,200.02) v1(175.01,198.75) v1(175.01,196.98) v1(175.01,160.66) v1(177.93,160.27) v1(178.56,100.33) v1(179.45,16.76) v1(179.96,218.06) v1(179.96,185.29) v1(179.96,103.82) v1(180.47,16.76) v1(180.85,218.06) v1(180.85,185.29) v1(181.23,103.12) v1(181.99,156.46) v1(183.51,50.01) v1(183.64,108.71) v1(183.64,58.93) v1(183.64,57.91) v1(183.9,160.27) v1(185.29,8.64) v1(186.51,51.01) v1(186.82,19.56) v1(187.58,101.35) v1(187.58,24.38) v1(188.47,20.07) v1(189.48,17.53) v1(189.86,81.28) v1(189.86,80.26) v1(189.86,79.12) v1(189.86,77.98) v1(189.86,74.93) v1(189.86,73.53) v1(189.99,60.2) v1(190.12,170.89) v1(190.37,12.32) v1(190.88,74.93) v1(190.88,73.53) v1(191.01,60.2) v1(191.52,19.43) v1(192.15,127.13) v1(192.15,126.11) v1(192.41,60.2) v1(192.53,170.87) v1(192.66,12.57) v1(193.42,60.2) v1(193.55,17.53) v1(194.06,80.9) v1(194.44,81.79) v1(194.56,19.94) v1(194.94,80.9) v1(195.33,81.79) v1(195.83,80.9) v1(196.22,111.95) v1(196.22,109.35) v1(196.47,19.69) v1(196.72,80.9) v1(196.85,132.72) v1(196.85,131.83) v1(196.98,129.92) v1(196.98,128.65) v1(196.98,127.38) v1(196.98,126.62) v1(196.98,125.35) v1(196.98,124.08) v1(197.74,8.64) v1(197.87,127) v1(198.37,78.99) v1(198.37,78.23) v1(198.37,77.47) v1(198.75,127) v1(199.52,48.01) v1(199.77,58.8) v1(199.77,57.78) v1(200.66,127.76) v1(200.91,128.4) v1(202.56,16.76) v1(202.82,46.99) v1(202.82,46.1) v1(202.95,40.39) v1(203.58,16.76) v1(203.96,40.39) v1(206.63,58.93) v1(206.63,58.04) v1(207.39,126.49) v1(207.39,125.48) v1(207.52,60.32) v1(207.52,59.44) v1(207.52,58.55) v1(207.52,57.66) v1(207.52,53.47) v1(208.41,125.48) v1(208.53,53.47) v1(209.42,61.97) v1(209.68,140.72) v1(209.68,53.47) v1(210.19,61.97) v1(210.31,139.45) v1(210.31,138.05) v1(210.31,136.65) v1(210.31,135.13) v1(210.31,132.97) v1(210.31,132.08) v1(210.69,53.47) v1(210.95,61.97) v1(211.07,133.98) v1(211.84,132.97) v1(211.84,132.08) v1(211.84,53.47) v1(212.85,53.47) v1(214,53.47) v1(214.38,139.57) v1(214.76,140.46) v1(215.01,53.47) v1(215.26,139.57) v1(215.65,140.46) v1(216.15,139.57) v1(217.04,139.57) v1(218.69,137.67) v1(218.69,136.91) v1(218.69,136.14) v1(224.16,153.67) v1(224.16,152.78) v1(224.16,151.64) v1(224.16,150.75) v1(224.16,146.69) v1(225.04,146.69) v1(226.19,149.22) v1(226.44,147.19) v1(226.44,146.18) v1(228.09,104.01) v1(228.09,101.73) v1(228.22,147.19) v1(228.22,146.18) v1(229.62,146.69) v1(230.25,16.76) v1(230.5,146.69) v1(230.76,154.05) v1(230.76,153.29) v1(231.27,16.76) v1(231.39,146.69) v1(231.52,154.05) v1(231.52,153.29) v1(234.31,50.01) v1(234.44,58.93) v1(234.44,57.91) v1(235.08,137.67) v1(235.2,136.52) v1(235.2,135.51) v1(236.35,135.51) v1(236.6,137.67) v1(236.6,136.52) v1(236.85,117.67) v1(236.85,115.13) v1(237.36,135.51) v1(237.31,51.01) v1(237.49,138.05) v1(237.49,137.03) v1(237.87,19.43) v1(238.25,24.38) v1(239.27,19.81) v1(240.28,131.83) v1(240.28,17.4) v1(240.79,60.2) v1(241.05,12.19) v1(241.81,60.2) v1(242.32,19.43) v1(242.44,113.92) v1(242.44,111.44) v1(242.57,146.43) v1(243.2,60.2) v1(243.32,38.1) v1(243.46,12.57) v1(244.22,60.2) v1(244.35,17.4) v1(245.32,38.1) v1(245.36,19.81) v1(247.32,38.1) v1(247.27,19.81) v1(249.32,45) v1(249.32,38.1) v1(250.32,48.01) v1(250.32,46) v1(250.57,58.8) v1(250.57,57.78) v1(253.36,16.76) v1(253.62,46.99) v1(253.62,46.1) v1(253.75,40.39) v1(254.13,130.05) v1(254.38,16.76) v1(254.76,40.39) v1(256.29,134.62) v1(257.94,149.22) v1(258.32,163.32) v1(258.32,160.53) v1(259.46,163.32) v1(259.46,160.53) v1(259.59,58.94) v1(259.59,58.05) v1(260.48,60.33) v1(260.48,59.44) v1(260.48,58.55) v1(260.48,57.67) v1(260.48,53.47) v1(260.73,139.32) v1(260.73,136.91) v1(260.73,134.49) v1(261.49,53.47) v1(262.38,61.98) v1(262.64,139.32) v1(262.64,136.91) v1(262.64,134.49) v1(262.64,53.47) v1(263.14,61.98) v1(263.53,77.09) v1(263.53,75.57) v1(263.65,53.47) v1(263.91,61.98) v1(264.29,155.57) v1(264.54,139.32) v1(264.54,136.91) v1(264.8,53.47) v1(265.18,91.06) v1(265.18,90.04) v1(265.81,53.47) v1(265.94,91.06) v1(265.94,90.04) v1(266.06,77.09) v1(266.06,75.57) v1(266.95,53.47) v1(267.59,155.57) v1(267.97,53.47) v1(268.99,136.52) v1(269.24,75.82) v1(270.26,75.82) v1(270.38,139.32) v1(271.65,75.82) v1(271.91,148.21) v1(272.03,140.08) v1(272.16,145.8) v1(272.29,165.48) v1(272.67,75.82) v1(272.92,155.57) v1(272.92,154.94) v1(272.92,154.3) v1(272.92,153.67) v1(273.05,165.48) v1(273.56,147.32) v1(274.7,75.06) v1(274.7,74.17) v1(275.97,75.06) v1(275.97,74.17) v1(277.11,75.06) v1(277.11,74.17) v2(158.91,109.24) v2(162.91,110.04) v2(166.12,105.25) v2(174.92,106.85) v3(2.92,235.97) v3(2.92,223.27) v3(2.92,209.93) v3(2.92,198.5) v3(2.92,188.34) v3(2.92,177.55) v3(2.92,164.21) v3(2.92,150.88) v3(2.92,136.91) v3(2.92,124.84) v3(2.92,113.41) v3(2.92,100.08) v3(2.92,83.57) v3(2.92,70.23) v3(2.92,57.53) v3(2.92,45.47) v3(2.92,33.4) v3(2.92,21.97) v3(6.35,105.54) v3(6.35,104.14) v3(6.35,97.16) v3(6.35,95.76) v3(6.35,92.96) v3(6.35,91.57) v3(6.35,88.77) v3(6.35,87.38) v3(9.27,105.54) v3(9.27,104.14) v3(9.27,97.16) v3(9.27,95.76) v3(9.27,92.96) v3(9.27,91.57) v3(9.27,88.77) v3(9.27,87.38) v3(11.81,105.66) v3(11.81,104.27) v3(11.81,97.16) v3(11.81,95.76) v3(11.81,88.77) v3(11.81,87.38) v3(11.81,2.92) v3(14.73,105.66) v3(14.73,104.27) v3(14.73,97.16) v3(14.73,95.76) v3(14.73,88.77) v3(14.73,87.38) v3(14.99,249.3) v3(27.05,2.92) v3(28.32,249.3) v3(34.04,2.92) v3(41.66,2.92) v3(42.93,249.3) v3(49.28,2.92) v3(54.99,249.3) v3(56.9,2.92) v3(61.98,2.92) v3(68.96,249.3) v3(70.23,2.92) v3(79.12,2.92) v3(84.2,249.3) v3(88.01,2.92) v3(96.9,2.92) v3(99.44,249.3) v3(111.51,249.3) v3(122.3,249.3) v3(128.91,104.65) v3(128.91,102.87) v3(128.91,100.58) v3(129.03,108.08) v3(129.03,106.17) v3(130.68,99.57) v3(132.72,102.74) v3(132.72,100.71) v3(132.72,98.68) v3(132.72,96.65) v3(132.72,94.87) v3(133.73,102.74) v3(133.73,100.71) v3(133.73,98.68) v3(133.73,96.65) v3(133.73,94.87) v3(134.37,249.3) v3(151.51,249.3) v3(167.39,249.3) v3(182.63,249.3) v3(197.87,249.3) v3(213.11,249.3) v3(227.71,249.3) v3(239.78,249.3) v3(254.38,249.3) v3(265.81,249.3) v3(279.15,239.14) v3(279.15,228.98) v3(279.15,216.92) v3(279.15,203.58) v3(279.15,190.25) v3(279.15,176.91) v3(279.15,161.67) v3(279.15,147.07) v3(279.15,80.39) v3(279.15,68.96) v3(279.15,56.9) v3(279.15,44.2) v3(279.15,34.67) v3(279.15,26.42) v3(279.15,17.53) v3(279.78,133.73) v3(279.78,119.76) v3(279.78,107.06) v3(279.78,94.36)
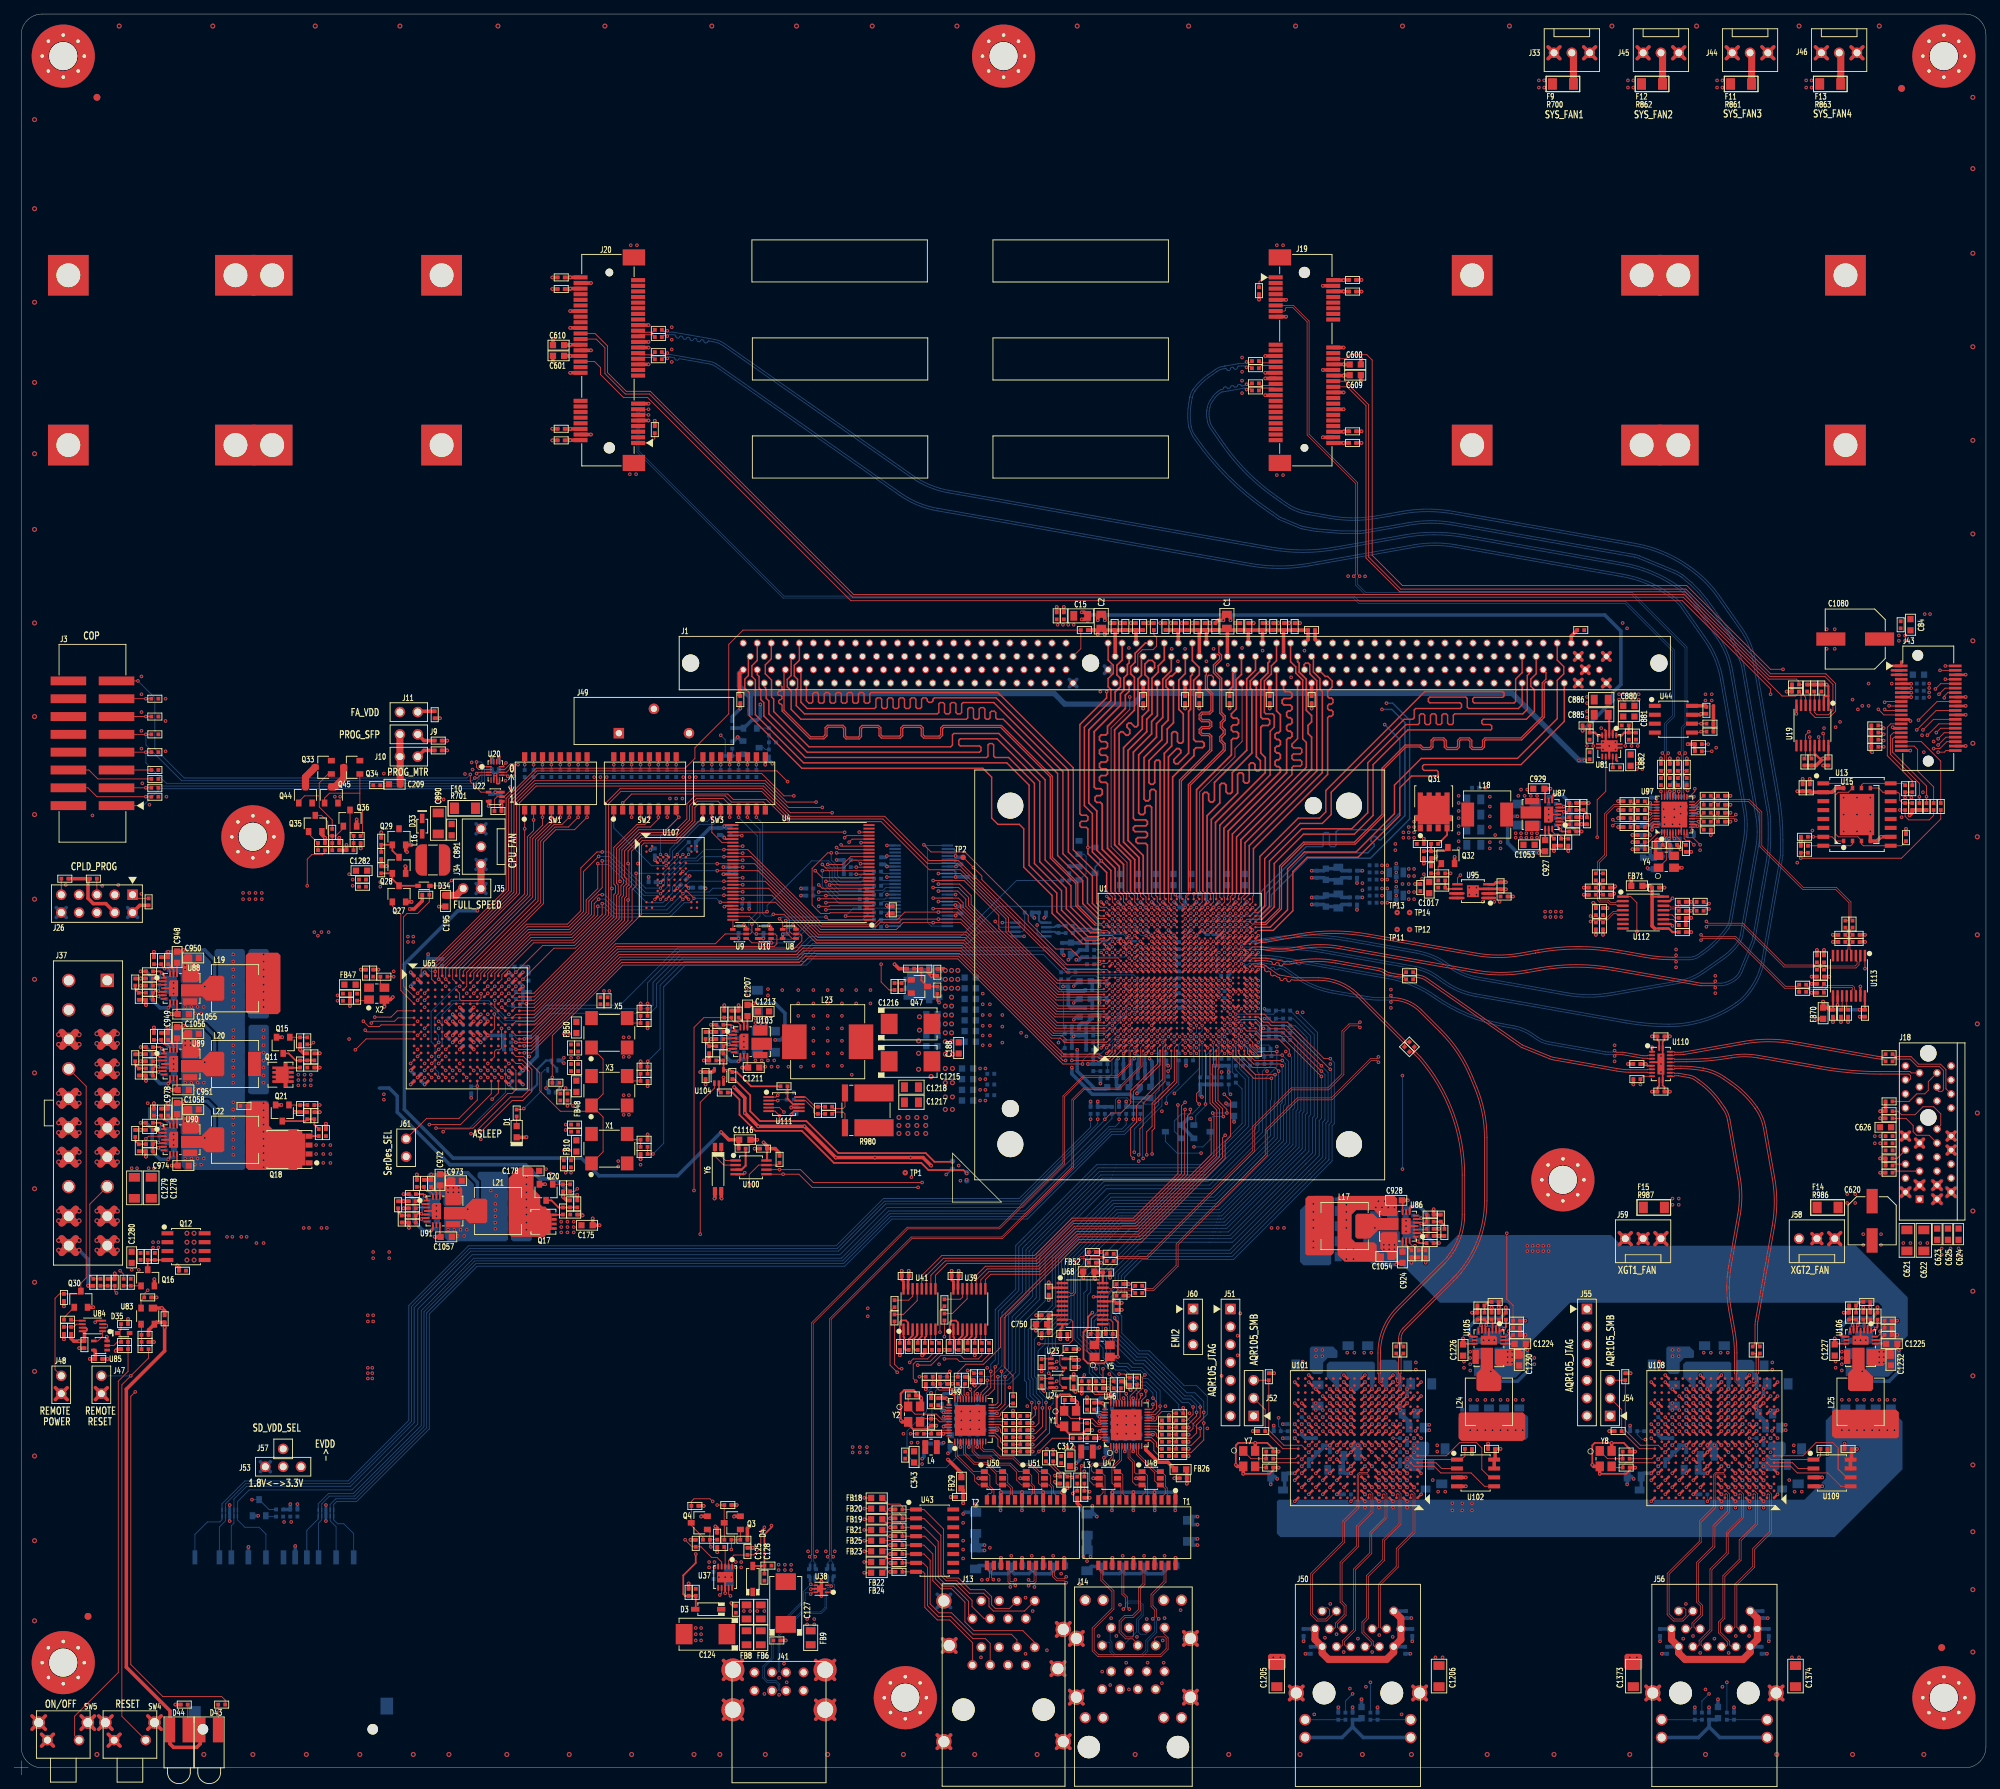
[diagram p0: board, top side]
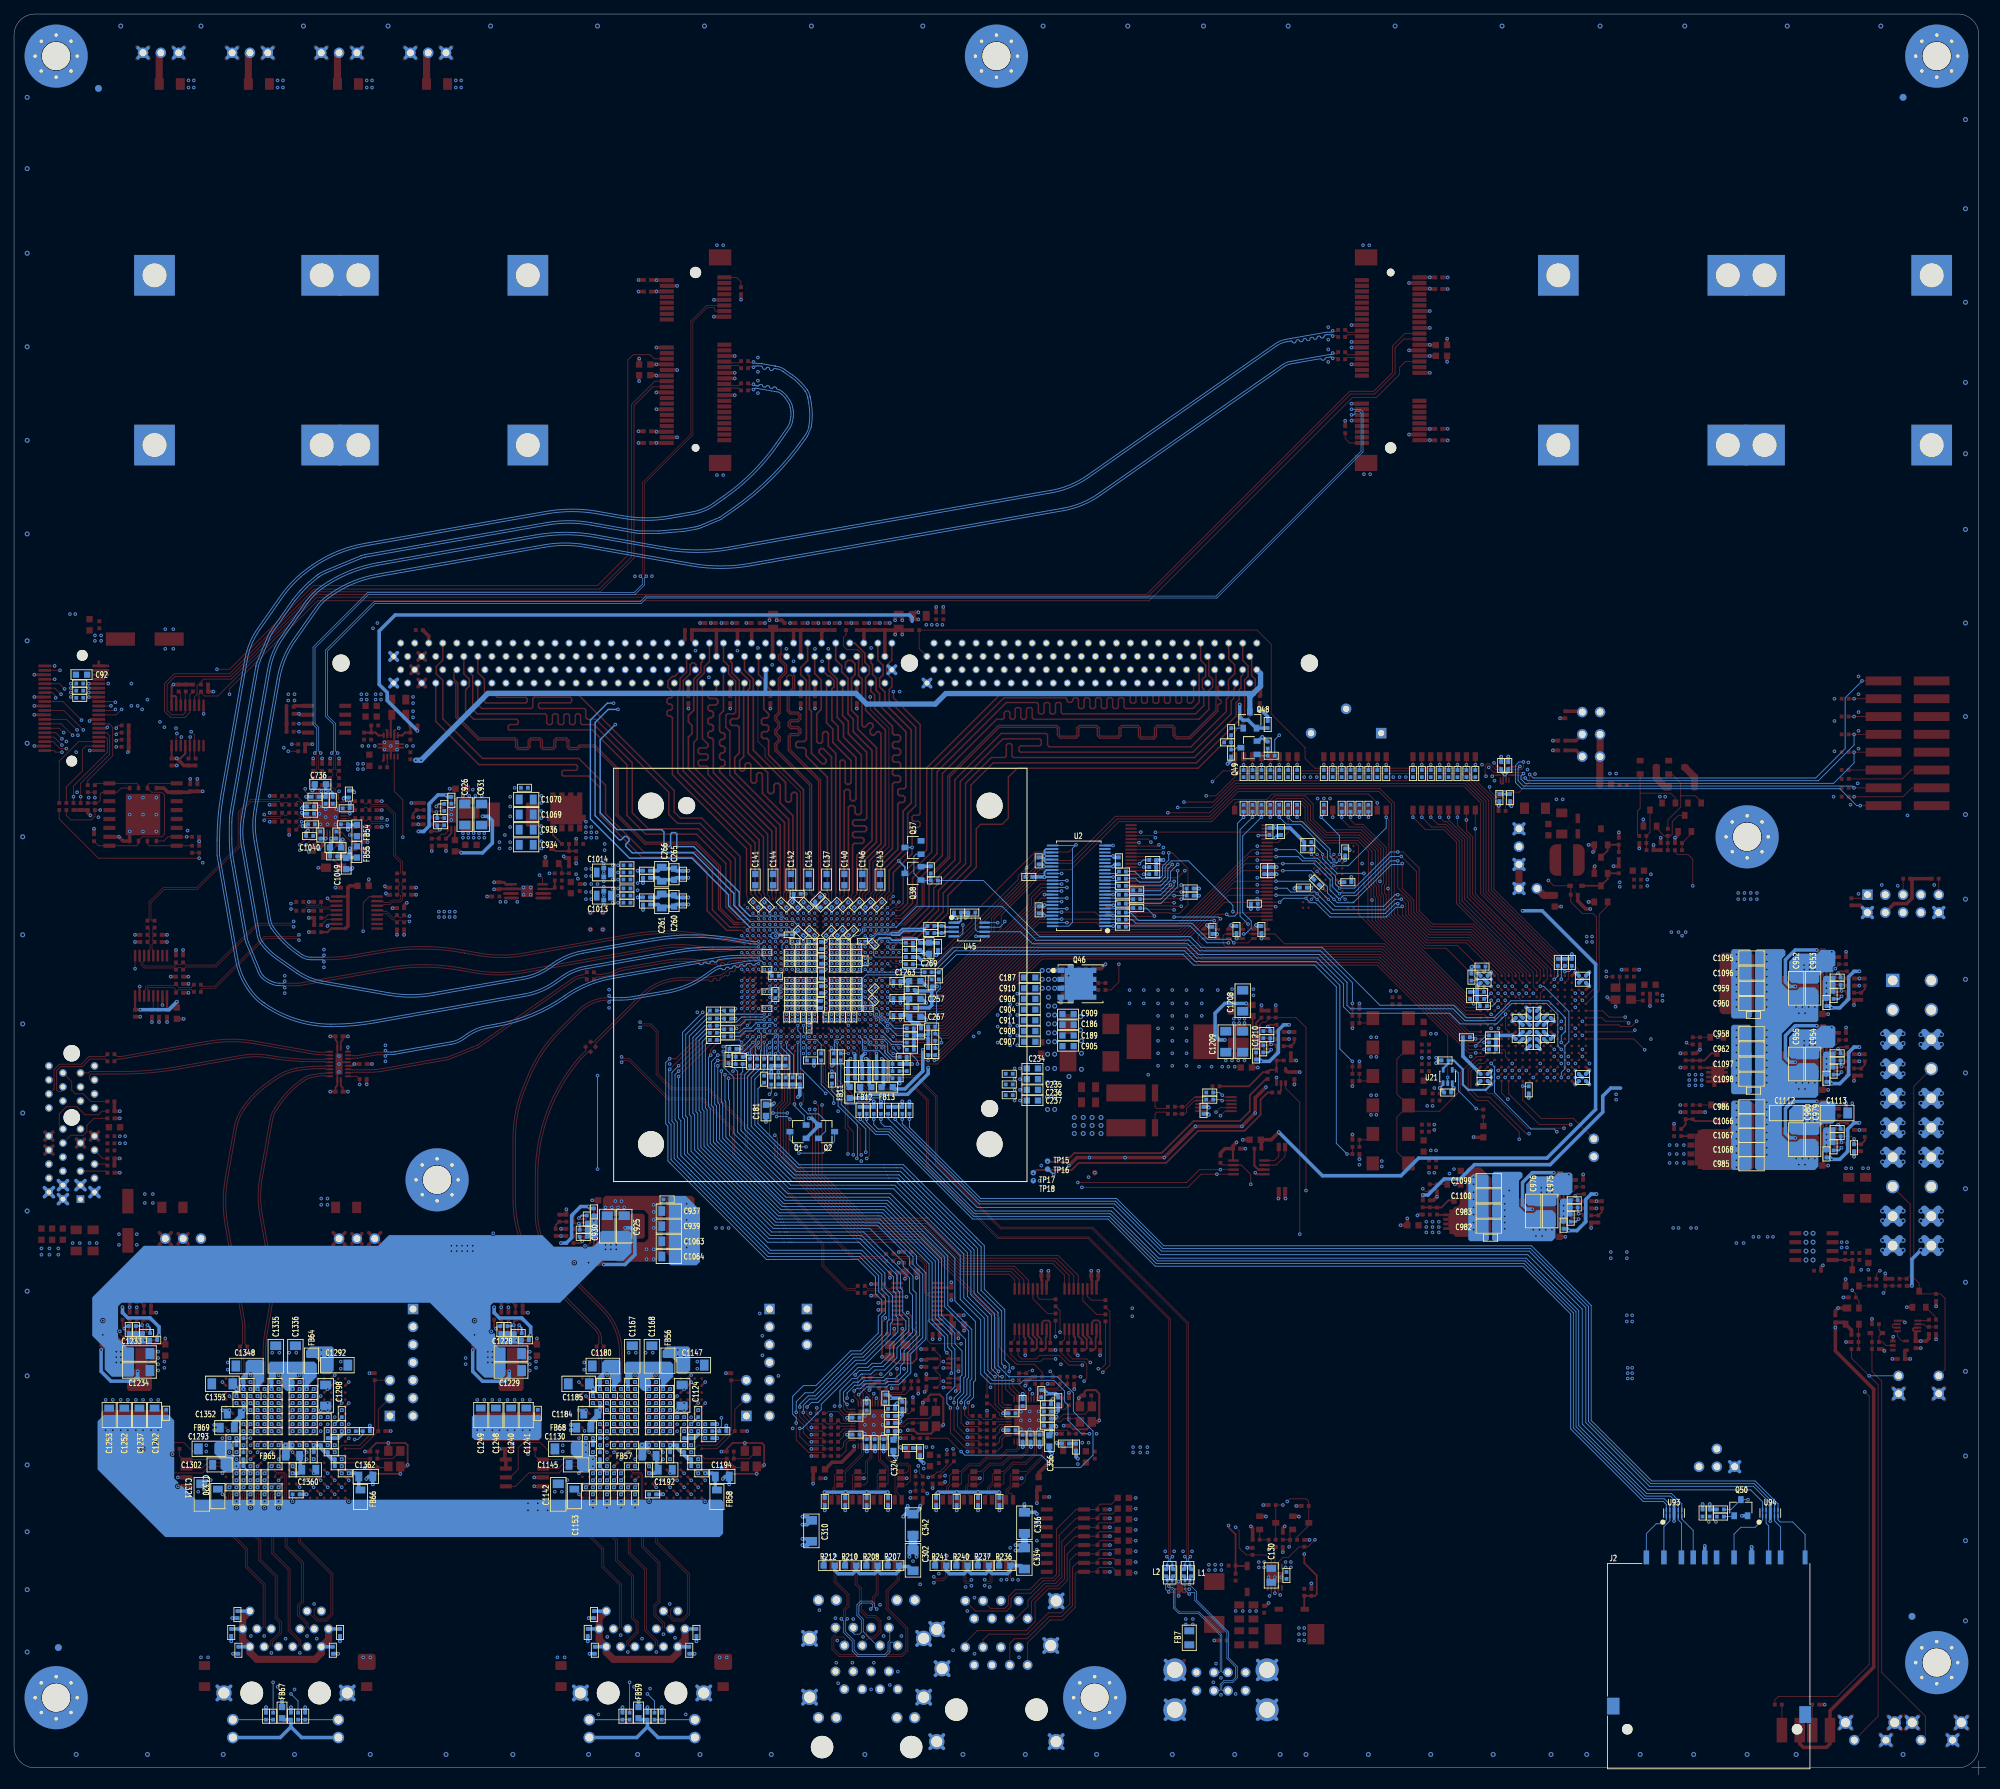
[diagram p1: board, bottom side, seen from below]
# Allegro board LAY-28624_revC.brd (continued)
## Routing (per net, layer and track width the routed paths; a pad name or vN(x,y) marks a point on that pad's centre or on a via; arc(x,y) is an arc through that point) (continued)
SVDD: length 5.9
  TOP w0.305: U1.W16 v2(170.12,115.65) ; U1.W18 v2(170.12,117.25) ; U1.Y13 v2(170.92,112.45) ; U1.W19 v2(170.12,118.05) ; U1.W17 v2(170.12,116.45) ; U1.W20 v2(170.12,118.85) ; U1.W15 v2(170.12,114.85)
  BOTTOM w0.127: R139.1 172.22,112.04 171.32,112.04 v2(170.92,112.45)
  vias: v1(194.94,126.37) v1(194.94,125.35) v1(194.94,124.33) v1(195.71,126.37) v1(195.71,124.33)
VDD_EN: length 397.4
  TOP w0.127: v1(206.12,128.27) 205.7,127.85 U95.5 ; U65.N5 v1(60.51,101.42)
  L6SIG w0.102: v1(60.51,101.42) 60.51,100.42 61.01,99.92 61.01,98.12 69.22,89.92 69.22,85.34 71.12,83.44 71.12,78.87 71.76,78.23 75.18,78.23 77.34,76.07 93.85,76.07 94.62,75.31 153.15,75.31 153.86,76.02 177.6,76.02 182.63,70.99 208.15,70.99 214.76,77.6 226.19,77.6 228.09,79.5 274.07,79.5 277.5,82.93 277.5,143.26 275.84,144.91 275.84,148.46 272.16,152.15 269.49,152.15 267.34,154.3 259.52,154.3 249.08,143.86 246.98,143.86 243.59,140.46 243.59,133.73 239.65,129.79 216.03,129.79 215.01,128.78 206.63,128.78 v1(206.12,128.27)
VDD_EN_N: length 68.5
  TOP w0.127: v1(69.47,106.43) 69.47,103.63 69.21,103.38 68.71,103.38 68.45,103.12 68.45,102.36 U65.N12 ; R919.1 124.71,111.89 123.57,113.03 v1(123.57,115.57)
  L6SIG w0.102: v1(123.57,115.57) 123.19,115.95 80.01,115.95 73.41,109.35 72.39,109.35 v1(69.47,106.43)
VDD_SD: length 4
  L3SIG w0.508: 37.65,44.65 J53.2 ; J53.2 37.65,43.23 ; J53.2 39.06,43.23 ; J53.2 39.06,44.65
  vias: v1(38.48,36.07) v1(39.5,36.07)
VDD_SD_SENSE: length 89.4
  TOP w0.127: v1(58.51,110.43) 59.01,110.93 U65.D3
  L6SIG w0.102: v1(33.91,39.25) 33.91,70.87 36.34,73.29 36.34,80.41 39.22,83.29 39.22,89.69 41.5,91.97 44.93,91.97 51.43,98.48 51.43,105.53 55.83,109.93 58.01,109.93 v1(58.51,110.43)
  BOTTOM w0.127: R955.2 36.33,37.85 Q50.3 v1(33.91,39.25)
ASLEEP: length 99.1
  TOP w0.127: v1(152.27,101.35) 149.48,101.35 134.49,116.33 113.03,116.33 112.14,115.44 86.74,115.44 76.71,105.41 v1(76.71,99.44) 76.72,99.43 R101.1 ; U1.B2 v2(155.72,103.65)
  BOTTOM w0.127: U21.2 v1(76.71,99.44) ; v2(155.72,103.65) 154.94,102.87 153.29,102.87 152.27,101.85 v1(152.27,101.35)
BOOT_FLASH_SEL: length 53.3
  TOP w0.127: U65.F15 71.52,109.43 74.12,109.43 74.12,109.43 86.61,121.92 86.61,125.09 86.87,125.35 86.87,126.62 87.25,127 87.25,127.76 87,128.02 87,131.7 89.28,133.98 94.11,133.98 96.27,136.14 96.27,138.18 97.28,139.19 101.09,139.19 101.98,138.3 SW3.4 v1(101.98,136.52)
  BOTTOM w0.127: R502.2 v1(101.98,136.52)
CFG_VBANK0: length 66.7
  TOP w0.127: v1(105.79,119.89) U10.2 108.46,119.89 108.71,119.63 108.71,118.49 108.33,118.11 85.85,118.11 73.67,105.93 U65.J16 ; SW3.5 v1(103.25,136.52)
  BOTTOM w0.127: v1(105.79,119.89) 105.54,119.89 104.71,120.71 104.71,121.73 105.92,122.94 105.92,133.86 v1(103.25,136.52) R504.2
CFG_VBANK1: length 58
  TOP w0.127: v1(105.16,121.29) 105.16,120.14 104.9,119.89 U9.2 101.35,119.89 99.95,118.49 85.73,118.49 74.16,106.93 U65.H16 ; SW3.6 v1(104.52,136.52)
  BOTTOM w0.127: R506.2 v1(104.52,136.52) 106.3,134.75 106.3,122.43 v1(105.16,121.29)
CFG_VBANK2: length 71.7
  TOP w0.127: U65.J15 71.52,105.43 73.68,105.43 85.98,117.73 111.12,117.73 112.27,118.87 112.27,119.63 112.01,119.89 U8.2 110.87,119.89 110.49,120.27 110.49,121.92 109.73,122.68 v1(108.2,122.68) ; 105.79,137.54 v1(105.79,136.52)
  BOTTOM w0.127: v1(108.2,122.68) 107.95,122.43 107.06,122.43 106.68,122.81 106.68,135.64 v1(105.79,136.52) R508.2
CKE_ISO_EN: length 104
  TOP w0.127: U65.L4 60.02,103.93 v1(60.51,104.42)
  BOTTOM w0.127: v1(60.51,104.42) 60.51,105.43 59.94,105.99 59.94,107.95 62.36,110.36 67.69,110.36 70.1,107.95 74.04,107.95 75.82,109.73 86.36,109.73 94.62,117.98 111.85,117.98 113.37,119.51 134.87,119.51 142.88,127.51 R830.1
CKSTP_OUT_N: length 108.1
  TOP w0.127: R102.1 68.46,139.07 68.83,139.45 U22.2 69.85,139.45 70.74,140.33 v1(70.74,140.84) ; U1.F18 v2(158.92,117.25)
  L6SIG w0.102: v1(70.74,140.84) 71.25,140.33 109.85,140.33 110.87,141.35 121.79,141.35 130.17,132.97 130.17,130.68 136.4,124.46 141.35,124.46 143.26,122.55 143.26,120.9 148.72,115.44 155.03,115.44 156.04,116.46 158.13,116.46 v2(158.92,117.25)
COP_CKSTP_OUT_N: length 64.8
  TOP w0.127: v1(65.02,142.62) 65.02,141.6 66.53,140.1 U22.4 ; J3.15 v1(17.65,155.96)
  BOTTOM w0.127: v1(65.02,142.62) 64.52,142.11 24.26,142.11 20.07,146.3 20.07,153.54 v1(17.65,155.96)
COP_HRESET_N: length 72.9
  TOP w0.127: J3.13 v1(18.8,153.42) R107.2 ; U65.G1 54.71,107.93 54.22,107.44 51.18,107.44 v1(50.93,107.19)
  L6SIG w0.102: v1(50.93,107.19) 50.93,107.32 50.29,107.95 46.99,107.95 38.73,116.2 38.73,117.6 20.32,136.02 20.32,148.46 19.43,149.35 19.43,150.37 19.56,150.5 19.56,151.76 18.8,152.53 v1(18.8,153.42)
COP_SRESET_N: length 70.6
  TOP w0.127: v1(49.78,107.44) 50.55,106.68 52.07,106.68 52.32,106.93 U65.H1 ; R110.2 v1(18.8,150.88) J3.11
  L6SIG w0.102: v1(18.8,150.88) 18.8,149.22 19.81,148.21 19.81,136.02 38.35,117.48 38.35,115.95 46.86,107.44 v1(49.78,107.44)
COP_TCK: length 58.2
  TOP w0.127: J3.7 v1(18.8,145.8) R113.2 ; v1(65.91,142.75) 66.09,142.93 U20.3
  BOTTOM w0.127: v1(18.8,145.8) 18.8,144.27 21.72,141.35 65.66,141.35 66.26,141.96 66.26,142.4 v1(65.91,142.75)
COP_TDI: length 56.7
  TOP w0.127: J3.3 v1(18.8,140.72) R111.2 ; U20.1 66.96,143.73 66.93,143.76 v1(66.42,143.76)
  BOTTOM w0.127: v1(66.42,143.76) 66.68,143.51 66.68,141.73 65.91,140.97 19.05,140.97 v1(18.8,140.72)
COP_TDO: length 60.2
  TOP w0.127: v1(65.91,144.4) 65.91,143.64 66.24,143.32 66.61,143.32 66.61,143.33 U20.2 ; J3.1 v1(17.91,138.18)
  BOTTOM w0.127: v1(17.91,138.18) 18.41,138.18 20.83,140.59 66.17,140.59 67.06,141.48 67.06,143.89 66.55,144.4 v1(65.91,144.4)
COP_TMS: length 57.8
  TOP w0.127: J3.9 v1(18.8,148.34) R114.2 ; U20.4 66.46,142.53 66.04,142.11 v1(65.66,142.11)
  BOTTOM w0.127: v1(65.66,142.11) 65.28,141.73 23.88,141.73 18.8,146.81 v1(18.8,148.34)
COP_TRST_N: length 67.1
  TOP w0.127: R109.1 v1(18.8,139.45) 11.81,139.45 10.54,140.72 J3.4 ; v1(50.04,106.17) 50.28,105.93 U65.J1
  L6SIG w0.102: v1(50.04,106.17) 49,107.21 46.77,107.21 45.27,108.71 45.09,108.71 37.97,115.82 37.97,117.35 18.8,136.52 v1(18.8,139.45)
CPLD_INT_N: length 102.2
  TOP w0.127: U1.F7 v2(158.92,107.65) ; v1(69.52,110.43) U65.E13
  L6SIG w0.102: v2(158.92,107.65) 158.92,107.48 158.5,107.06 158.5,105.89 158.27,105.66 158,105.66 157.73,105.4 157.73,105.13 157.46,104.85 147.62,104.85 136.7,115.77 126.8,115.77 125.86,116.71 79.63,116.71 73.85,110.93 70.02,110.93 v1(69.52,110.43)
  BOTTOM w0.127: R69.1 70.35,109.6 v1(69.52,110.43)
CPLD_REFCLK: length 11.2
  TOP w0.127: U65.H5 v1(60.51,107.43) ; R495.2 v1(54.1,113.79)
  L3SIG w0.102: v1(54.1,113.79) 54.1,112.9 59.57,107.43 v1(60.51,107.43)
CPLD_TCK: length 55.8
  TOP w0.127: U65.P3 v1(58.52,100.43) ; J26.1 17.41,124.96 R496.2
  L3SIG w0.102: J26.1 17.65,126.24 27.81,126.24 53.09,100.97 57.91,100.97 58.45,100.43 v1(58.52,100.43)
CPLD_TDI: length 68.5
  TOP w0.127: J26.9 6.74,125.48 R498.2 ; U65.L6 v1(61.52,103.43)
  L3SIG w0.102: v1(61.52,103.43) 61.09,103.86 51.34,103.86 27.81,127.38 8.64,127.38 J26.9
CPLD_TDO: length 57.7
  TOP w0.127: U65.M5 v1(60.52,102.43)
  L3SIG w0.102: J26.3 15.88,127 27.81,127 51.94,102.87 60.07,102.87 v1(60.52,102.43)
CPLD_TMS: length 63.2
  TOP w0.127: R497.2 11.8,125.48 J26.5 ; U65.N4 v1(59.52,101.43)
  L3SIG w0.102: v1(59.52,101.43) 59.02,101.92 52.51,101.92 27.81,126.62 16,126.62 15.49,126.11 15.49,124.97 14.9,124.38 12.91,124.38 J26.5
DDR_DQ0: length 82.1
  TOP w0.127: U1.C21 156.51,119.65 154.7,119.65 154.56,119.51 154.43,119.51
  TOP w0.203: J1.3 105.92,156.85 106.17,156.59 106.17,154.94 106.43,154.69 106.43,153.29 106.86,152.86 106.86,150.95 112.78,145.03 138.59,145.03 138.79,145.24 138.79,146.82 139,147.02 139.4,147.02 139.61,146.82 139.61,145.24 139.81,145.03 141.73,145.03 145.41,141.35 145.41,129.92 149.28,126.06 149.28,123.27 153.03,119.51 154.43,119.51
DDR_DQ1: length 82.3
  TOP w0.127: U1.A22 154.43,120.05
  TOP w0.203: 154.43,120.05 153.39,120.05 149.95,123.48 149.95,126.4 146.18,130.17 146.18,141.6 140.08,147.7 134.84,147.7 134.64,147.5 134.64,146.89 134.84,146.69 137.59,146.69 137.79,146.48 137.79,146 137.59,145.8 113.03,145.8 107.57,151.26 107.57,153.1 107.19,153.48 107.19,154.69 107.1,154.77 107.1,154.97 106.92,155.15 J1.4
DDR_DQ2: length 82.3
  TOP w0.127: U1.A26 154.67,123.25 154.43,123.48
  TOP w0.203: 154.43,123.48 153.67,124.24 153.67,128.14 150.24,131.57 150.24,143.26 139.95,153.54 131.16,153.54 130.96,153.34 130.96,153.11 130.75,152.91 130.35,152.91 130.14,153.11 130.14,153.34 129.94,153.54 129.54,153.54 129.33,153.34 129.33,152.22 129.13,152.02 128.72,152.02 128.52,152.22 128.52,153.34 128.32,153.54 127.91,153.54 127.71,153.34 127.71,152.22 127.5,152.02 127.1,152.02 126.89,152.22 126.89,153.34 126.69,153.54 126.28,153.54 126.08,153.34 126.08,152.22 125.88,152.02 125.47,152.02 125.27,152.22 125.27,153.34 125.06,153.54 124.66,153.54 124.46,153.34 124.46,152.22 124.25,152.02 123.85,152.02 123.64,152.22 123.64,153.34 123.44,153.54 123.03,153.54 122.83,153.34 122.83,152.22 122.63,152.02 113.03,152.02 112.14,152.91 112.14,157.32 J1.9
DDR_DQ3: length 82.2
  TOP w0.127: 154.43,124.14 154.88,123.7 155.66,123.7 U1.B26
  TOP w0.203: 154.43,124.14 154.3,124.27 154.3,128.52 150.95,131.88 150.95,143.56 140.21,154.3 122.16,154.3 121.95,154.1 121.95,152.98 121.75,152.78 121.34,152.78 121.14,152.98 121.14,154.1 120.94,154.3 120.53,154.3 120.33,154.1 120.33,152.98 120.12,152.78 119.72,152.78 119.51,152.98 119.51,154.1 119.31,154.3 118.91,154.3 118.7,154.1 118.7,152.98 118.5,152.78 118.09,152.78 117.89,152.98 117.89,154.1 117.69,154.3 117.28,154.3 117.08,154.1 117.08,152.98 116.87,152.78 116.47,152.78 116.26,152.98 116.26,154.1 116.06,154.3 115.65,154.3 115.45,154.1 115.45,152.98 115.25,152.78 114.84,152.78 114.64,152.98 114.64,154.1 114.43,154.3 114.03,154.3 113.83,154.1 113.83,152.98 113.62,152.78 113.28,152.78 112.92,153.15 J1.10
DDR_DQ4: length 82.3
  TOP w0.127: U1.B21 155.74,118.87 155.07,118.87 154.69,118.49
  TOP w0.203: 154.69,118.49 152.27,118.49 147.93,122.83 147.93,125.37 143.89,129.41 143.89,134.87 143.26,135.51 140.21,135.51 139.32,136.4 139.32,142.24 138.05,143.51 112.27,143.51 104.78,151 104.78,154.29 104.14,154.92 104.14,156.21 104.65,156.72 104.65,159.18 J1.122
DDR_DQ5: length 82.1
  TOP w0.127: 154.43,119 154.56,119 154.81,119.25 U1.A21
  TOP w0.203: J1.123 105.92,158.88 105.16,158.12 105.16,156.59 105.64,156.1 105.64,151.15 112.52,144.27 141.48,144.27 144.65,141.1 144.65,129.67 148.6,125.72 148.6,123.05 152.65,119 154.43,119
DDR_DQ6: length 82.2
  TOP w0.127: U1.B24 155.69,122.07 154.43,122.07
  TOP w0.203: J1.128 110.74,159.27 110.74,156.72 110.19,156.16 110.19,155.12 110.74,154.56 110.74,151.89 112.14,150.5 135.71,150.5 135.92,150.7 135.92,151.94 136.12,152.15 136.53,152.15 136.73,151.94 136.73,150.7 136.93,150.5 137.34,150.5 137.54,150.7 137.54,151.94 137.75,152.15 138.15,152.15 138.36,151.94 138.36,150.7 138.56,150.5 138.89,150.5 139.09,150.7 139.09,151.43 139.29,151.64 139.7,151.64 139.9,151.43 139.9,150.7 140.11,150.5 140.97,150.5 148.72,142.75 148.72,131.06 152.3,127.48 152.3,124.21 154.43,122.07
DDR_DQ7: length 82.2
  TOP w0.127: 154.43,122.81 154.79,122.45 U1.A25
  TOP w0.203: 154.43,122.81 152.97,124.27 152.97,127.83 149.48,131.32 149.48,143 139.61,152.87 135.24,152.87 135.04,152.67 135.04,151.46 134.84,151.26 134.43,151.26 134.23,151.46 134.23,152.67 134.02,152.87 133.62,152.87 133.41,152.67 133.41,151.46 133.21,151.26 132.81,151.26 132.6,151.46 132.6,152.67 132.4,152.87 131.99,152.87 131.79,152.67 131.79,151.46 131.59,151.26 112.65,151.26 111.47,152.44 111.47,154.78 111.66,154.97 111.66,156.18 111.19,156.66 111.19,158.18 111.92,158.91 J1.129
DDR_DQ8: length 69.4
  TOP w0.127: U1.C23 v2(156.52,121.25)
  L3SIG w0.102: 154.43,122.56 155.19,121.79 155.97,121.79 v2(156.52,121.25)
  L3SIG w0.203: 154.43,122.56 152.78,124.21 152.78,124.84 144.4,133.22 139.95,133.22 135.53,137.65 135.53,140.39 135.32,140.59 134.69,140.59 134.49,140.39 134.49,139.14 134.28,138.94 133.88,138.94 133.67,139.14 133.67,140.39 133.47,140.59 133.06,140.59 132.86,140.39 132.86,139.14 132.66,138.94 132.25,138.94 132.05,139.14 132.05,140.39 131.85,140.59 123.95,140.59 122.3,142.24 122.3,143.31 122.1,143.51 121.29,143.51 120.9,143.89 120.9,145.08 120.7,145.29 119.89,145.29 119.76,145.41 119.76,145.85 119.56,146.05 118.11,146.05 117.6,146.56 117.6,147.83 114.92,150.51 J1.12
DDR_DQ9: length 69.3
  TOP w0.127: U1.C24 v2(156.52,122.05)
  L3SIG w0.102: 154.43,123.44 155.45,122.43 156.13,122.43 v2(156.52,122.05)
  L3SIG w0.203: J1.13 116.08,157.71 116.08,158.55 115.87,158.75 115.44,158.75 115.19,158.5 115.19,156.84 115.64,156.39 115.64,150.93 117.73,148.84 119.05,148.84 119.25,148.64 119.25,148.13 118.75,147.62 118.75,147.14 118.95,146.94 120.32,146.94 120.52,146.74 120.52,146.25 120.73,146.05 121.54,146.05 121.67,145.92 121.67,144.62 121.87,144.42 122.92,144.42 123.06,144.27 123.06,142.62 124.33,141.35 136.13,141.35 136.33,141.15 136.33,137.99 140.33,133.98 144.78,133.98 153.54,125.22 153.54,124.33 154.43,123.44
DDR_DQ10: length 69
  TOP w0.127: U1.F25 v2(158.92,122.85)
  L3SIG w0.102: 157.49,125.73 157.49,125.59 158.01,125.07 158.01,124.31 158.5,123.83 158.5,123.8 158.5,123.8 158.5,123.19 158.84,122.85 v2(158.92,122.85)
  L3SIG w0.203: J1.18 120.92,154 121.12,153.8 128.96,153.8 129.16,153.59 129.16,153.11 128.96,152.91 128.09,152.91 127.89,152.7 127.89,152.25 128.09,152.04 128.96,152.04 129.16,151.84 129.16,151.43 128.96,151.23 128.09,151.23 127.89,151.03 127.89,146.13 128.09,145.92 140.78,145.92 151.03,135.67 151.03,133.83 151.26,133.6 151.69,133.6 151.89,133.81 151.89,134.05 152.1,134.26 152.55,134.26 152.75,134.05 152.75,133.17 152.95,132.97 153.59,132.97 153.8,132.77 153.8,131.14 154.13,130.81 154.43,130.81 154.62,131 154.62,131.43 154.83,131.64 155.07,131.64 156.06,130.65 156.06,127.83 157.49,126.4 157.49,125.73
DDR_DQ11: length 69.1
  TOP w0.127: U1.F26 v2(158.92,123.65)
  L3SIG w0.102: 158.17,125.73 158.17,125.43 158.39,125.2 158.39,124.31 158.92,123.79 v2(158.92,123.65)
  L3SIG w0.203: 158.17,125.73 158.17,126.68 156.73,128.11 156.73,131.05 141.1,146.69 131.73,146.69 131.53,146.89 131.53,148.89 131.33,149.1 130.92,149.1 130.72,148.89 130.72,146.89 130.51,146.69 130.12,146.69 129.92,146.89 129.92,147.71 129.72,147.92 128.85,147.92 128.65,148.12 128.65,148.53 128.85,148.73 129.72,148.73 129.92,148.93 129.92,149.34 129.72,149.54 128.85,149.54 128.65,149.75 128.65,150.15 128.85,150.36 129.72,150.36 129.92,150.56 129.92,154.48 129.72,154.69 122.17,154.69 121.92,154.94 J1.19
DDR_DQ12: length 70
  TOP w0.127: U1.D22 v2(157.32,120.45)
  L3SIG w0.102: v2(157.32,120.45) 157.28,120.45 156.84,120.02 155.19,120.02 154.43,120.78
  L3SIG w0.203: J1.131 113.92,159 113.03,158.11 113.03,157.1 113.67,156.46 113.67,155.21 113.42,154.97 113.42,149.72 115.89,147.26 115.89,146.11 122.81,139.19 127.51,139.19 129.29,137.41 133.6,137.41 139.32,131.7 143.51,131.7 154.43,120.78
DDR_DQ13: length 69.6
  TOP w0.127: U1.D23 v2(157.32,121.25)
  L3SIG w0.102: v2(157.32,121.25) 157.31,121.25 156.89,120.83 155.27,120.83 154.43,121.67
  L3SIG w0.203: J1.132 114.68,159.21 114.68,156.44 114.19,155.95 114.19,150.1 116.78,147.51 116.78,146.24 123.1,139.92 129.02,139.92 129.23,139.71 129.23,138.76 129.43,138.56 129.83,138.56 130.04,138.76 130.04,139.71 130.24,139.92 130.87,139.92 131.07,139.71 131.07,138.38 131.27,138.18 133.98,138.18 139.7,132.46 144.02,132.46 152.02,124.46 152.02,124.08 154.43,121.67
DDR_DQ14: length 69.9
  TOP w0.127: U1.B27 v2(155.72,124.45)
  L3SIG w0.102: v2(155.72,124.45) 155.07,125.09 155.07,125.73
  L3SIG w0.203: J1.137 119.23,160.66 118.67,160.66 117.98,159.97 117.98,158.75 117.09,157.86 117.09,156.72 117.64,156.17 117.64,155.11 117.35,154.81 117.35,151.64 118.49,150.5 121.54,150.5 121.79,150.24 121.79,149.81 121.59,149.61 121.11,149.61 120.9,149.4 120.9,148.92 121.11,148.72 121.59,148.72 121.79,148.51 121.79,147.95 121.94,147.81 124.51,147.81 124.71,147.61 124.71,143.13 124.97,142.88 137.85,142.88 138.05,142.67 138.05,138.43 140.97,135.51 145.29,135.51 155.07,125.73
DDR_DQ15: length 69.5
  TOP w0.127: U1.E25 v2(158.12,122.85)
  L3SIG w0.102: v2(158.12,122.85) 158.12,122.93 157.73,123.32 157.73,124.82 156.84,125.7 156.84,125.73
  L3SIG w0.203: 156.84,125.73 156.84,126.09 155.38,127.55 155.38,128.33 150.11,133.6 150.11,135.46 149.86,135.71 149.43,135.71 149.22,135.51 149.22,135.2 149.02,135 148.72,135 148.46,135.25 148.46,137.29 148.21,137.54 147.78,137.54 147.57,137.34 147.57,136.98 147.37,136.78 147.02,136.78 146.81,136.98 146.81,138.73 140.51,145.03 127.33,145.03 127.13,145.24 127.13,152.7 126.92,152.91 120.4,152.91 120.14,153.16 120.14,156.46 120.92,157.24 120.92,157.99 121.67,158.74 121.67,159.24 121.46,159.45 J1.138
DDR_DQ16: length 66.3
  TOP w0.127: U1.E23 v2(158.12,121.25)
  L6SIG w0.102: v2(158.12,121.25) 157.7,120.83 155.27,120.83 154.81,121.29 154.43,121.29
  L6SIG w0.203: 154.43,121.29 154.18,121.29 152.15,123.32 152.15,128.65 149.73,131.06 149.73,132.59 149.1,133.22 144.6,133.22 144.4,133.43 144.4,134.45 144.2,134.65 143.66,134.65 143.46,134.45 143.46,133.43 143.25,133.23 140.73,133.23 140.53,133.43 140.53,133.74 140.73,133.94 142.54,133.94 142.74,134.14 142.74,134.45 142.54,134.65 139.1,134.65 123.41,150.34 123.41,150.9 123.41,154.97 123.7,155.26 123.7,156.59 123.92,156.81 J1.21
DDR_DQ17: length 66.7
  TOP w0.127: U1.E24 v2(158.12,122.05)
  L6SIG w0.102: v2(158.12,122.05) 157.86,122.05 157.47,122.43 155.32,122.43 154.43,123.32
  L6SIG w0.203: J1.22 124.92,154.99 125.35,154.56 125.35,150.3 136.84,138.81 139.1,138.81 139.3,139.01 139.3,140.89 139.51,141.1 143.38,141.1 144.53,139.95 144.53,136.73 144.73,136.52 145.19,136.52 145.39,136.73 145.39,138.1 145.59,138.3 145.9,138.3 146.1,138.1 146.1,135.08 146.3,134.87 146.83,134.87 147.03,135.08 147.03,136.51 147.24,136.72 147.54,136.72 147.75,136.51 147.75,135.08 147.95,134.87 149.73,134.87 151.38,133.22 151.38,131.57 153.92,129.03 153.92,123.83 154.43,123.32
DDR_DQ18: length 66.8
  TOP w0.127: U1.J23 v2(161.32,121.25)
  L6SIG w0.102: v2(161.32,121.25) 161.32,121.26 160.9,121.68 160.9,122.2 160.64,122.46 160.36,122.46 160.1,122.73 160.1,125.57 159.94,125.73
  L6SIG w0.203: J1.27 129.64,157.27 129.64,155.17 129.41,154.94 129.41,151.76 129.67,151.51 130.16,151.51 130.36,151.31 130.36,150.06 130.57,149.86 130.97,149.86 131.18,150.06 131.18,151.31 131.38,151.51 132,151.51 132.21,151.31 132.21,150.06 132.41,149.86 135.89,149.86 136.14,149.61 136.14,148.97 136.4,148.72 139.61,148.72 139.81,148.51 139.81,148.11 139.61,147.9 137.62,147.9 137.41,147.7 137.41,147.29 137.62,147.09 140.42,147.09 140.62,147.29 140.62,148.51 140.83,148.72 141.22,148.72 157.35,132.59 157.35,129.79 159.47,127.67 159.47,126.19 159.94,125.73
DDR_DQ19: length 66.7
  TOP w0.127: U1.K23 v2(162.12,121.25)
  L6SIG w0.102: v2(162.12,121.25) 161.7,121.66 161.7,125.73
  L6SIG w0.203: J1.28 130.92,154.95 131.12,154.74 137.41,154.74 137.62,154.54 137.62,154.13 137.41,153.92 131.14,153.92 130.93,153.72 130.93,153.4 131.17,153.16 137.41,153.16 137.67,152.91 137.67,150.44 137.87,150.24 141.73,150.24 158.88,133.1 158.88,130.56 160.82,128.61 160.82,126.75 161.2,126.37 161.7,125.88 161.7,125.73
DDR_DQ20: length 66.4
  TOP w0.127: U1.F22 v2(158.92,120.45)
  L6SIG w0.102: 154.43,120.4 155.96,120.4 156.33,120.02 158.23,120.02 158.66,120.45 v2(158.92,120.45)
  L6SIG w0.203: J1.140 123.19,159.17 123.19,157.85 123.19,157.85 123.19,156.97 122.17,155.96 122.17,155.13 122.56,154.75 122.56,150.24 140.34,132.46 147.16,132.46 147.37,132.26 147.37,131.01 147.57,130.81 147.88,130.81 148.08,131.01 148.08,132.26 148.28,132.46 148.7,132.46 148.91,132.26 148.91,130.62 151.26,128.27 151.26,123.06 153.92,120.4 154.43,120.4
DDR_DQ21: length 67.2
  TOP w0.127: U1.H22 v2(160.52,120.45)
  L6SIG w0.102: 154.43,119.76 158.33,119.76 158.6,120.03 160.1,120.03 v2(160.52,120.45)
  L6SIG w0.203: 154.43,119.76 153.42,119.76 150.5,122.68 150.5,126.37 145.16,131.7 140.15,131.7 121.67,150.18 121.67,156.27 122.64,157.24 122.64,158.15 122.05,158.75 122.05,159.77 123.63,161.35 J1.141
DDR_DQ22: length 66.9
  TOP w0.127: U1.H23 v2(160.52,121.25)
  L6SIG w0.102: v2(160.52,121.25) 160.14,120.86 159.56,120.86 159.3,121.13 159.3,121.4 159.04,121.66 158.76,121.66 158.5,121.93 158.5,122.2 158.24,122.46 157.95,122.46 157.73,122.68 157.73,125.22 157.23,125.73
  L6SIG w0.203: J1.146 128.33,159.45 126.87,157.99 126.87,157.23 126.11,156.46 126.11,150.5 134.62,141.99 135.53,141.99 135.74,141.78 135.74,141.17 135.94,140.97 136.35,140.97 136.55,141.17 136.55,141.78 136.75,141.99 137.21,141.99 137.41,141.78 137.41,139.9 137.62,139.7 138.1,139.7 138.3,139.9 138.3,141.78 138.51,141.99 143.64,141.99 152.15,133.48 152.15,131.83 154.69,129.29 154.69,128.27 157.23,125.73
DDR_DQ23: length 66.8
  TOP w0.127: U1.J24 v2(161.32,122.05)
  L6SIG w0.102: v2(161.32,122.05) 161.32,122.27 160.94,122.66 160.94,125.69 160.89,125.73
  L6SIG w0.203: 160.89,125.73 160.53,126.09 160.15,126.47 160.15,128.14 158.11,130.17 158.11,132.84 141.48,149.48 137.11,149.48 136.91,149.68 136.91,150.52 136.7,150.72 133.3,150.72 133.1,150.93 133.1,151.33 133.3,151.54 136.7,151.54 136.91,151.74 136.91,152.2 136.7,152.4 130.38,152.4 130.17,152.6 130.17,156.34 130.81,156.97 130.81,158.12 129.92,159 129.92,161.34 J1.147
DDR_DQ24: length 56.9
  TOP w0.127: U1.H26 v2(160.52,123.65)
  L3SIG w0.102: 160.19,125.73 160.19,125.01 160.02,124.84 160.02,124.37 160.52,123.87 v2(160.52,123.65)
  L3SIG w0.203: J1.30 132.92,151.71 133.12,151.51 133.78,151.51 133.98,151.31 133.98,149.17 134.19,148.97 143.96,148.97 144.16,148.77 144.16,148.41 143.96,148.21 143.51,148.21 143.38,148.08 143.38,147.52 143.59,147.32 145.72,147.32 146.33,146.71 146.33,144.5 146.56,144.27 146.99,144.27 147.19,144.48 147.19,145.03 147.34,145.18 147.86,145.18 148.17,144.87 148.17,142.82 148.37,142.62 148.84,142.62 148.99,142.76 148.99,143.23 149.19,143.43 149.61,143.43 149.86,143.18 149.86,140.97 158.75,132.08 158.75,131.17 158.75,128.95 160.19,127.51 160.19,125.73
DDR_DQ25: length 56.9
  TOP w0.127: U1.J25 v2(161.32,122.85)
  L3SIG w0.102: v2(161.32,122.85) 160.91,123.25 160.91,125.09 160.86,125.15 160.86,125.73
  L3SIG w0.203: J1.31 133.92,156.9 133.69,156.68 133.69,152.48 133.9,152.27 134.54,152.27 134.75,152.07 134.75,149.94 134.95,149.73 144.59,149.73 144.91,149.42 144.91,148.34 145.05,148.19 146.07,148.19 147.19,147.07 147.19,146.13 147.4,145.92 148.34,145.92 148.97,145.29 148.97,144.46 149.16,144.27 149.99,144.27 150.69,143.57 150.69,141.29 150.88,141.1 151.31,141.1 151.51,141.3 151.51,141.86 151.65,142 152.26,142 152.46,141.8 152.46,139.51 159.42,132.55 159.42,129.25 160.86,127.81 160.86,125.73
DDR_DQ26: length 56.8
  TOP w0.127: U1.P26 v2(165.32,123.65)
  L3SIG w0.102: 164.72,125.73 164.72,124.21 165.28,123.65 v2(165.32,123.65)
  L3SIG w0.203: 164.72,125.73 164.72,129.29 163.19,130.81 163.19,135.89 162.69,136.4 162.69,139.5 162.48,139.7 162,139.7 161.8,139.5 161.8,138.06 161.59,137.86 161.11,137.86 160.91,138.06 160.91,142.96 160.71,143.16 160.24,143.16 160.04,142.96 160.04,141.96 159.83,141.75 159.33,141.75 159.13,141.96 159.13,144.02 149.35,153.8 139.7,153.8 138.92,154.58 J1.36
DDR_DQ27: length 57.1
  TOP w0.127: U1.N25 v2(164.52,122.85)
  L3SIG w0.102: 166.12,125.73 166.12,125.22 165.73,124.84 165.73,123.44 165.56,123.26 164.92,123.26 164.52,122.86 v2(164.52,122.85)
  L3SIG w0.203: 166.12,125.73 165.35,126.49 165.35,129.79 163.96,131.19 163.96,140.21 163.7,140.46 162,140.46 161.8,140.67 161.8,143.94 161.59,144.14 160.15,144.14 152.27,152.02 152.27,154.48 152.07,154.69 151.59,154.69 151.38,154.48 151.38,153.87 151.18,153.67 150.66,153.67 149.73,154.6 140.3,154.6 139.92,154.98 J1.37
DDR_DQ28: length 57.2
  TOP w0.127: U1.G25 v2(159.72,122.85)
  L3SIG w0.102: v2(159.72,122.85) 159.34,123.23 159.34,124.64 158.84,125.13 158.84,125.73
  L3SIG w0.203: J1.149 131.92,159.09 130.94,158.11 130.94,157.1 131.7,156.34 131.7,155.07 131.32,154.69 131.32,150.06 131.52,149.86 132.08,149.86 132.33,149.61 132.33,147.65 132.54,147.45 141.35,147.45 157.4,131.4 157.4,128.39 158.84,126.96 158.84,125.73
DDR_DQ29: length 56.7
  TOP w0.127: U1.H25 v2(160.52,122.85)
  L3SIG w0.102: v2(160.52,122.85) 160.14,123.23 160.14,123.84 159.64,124.33 159.64,124.84 159.51,124.97 159.51,125.73
  L3SIG w0.203: 159.51,125.73 159.51,127.23 158.08,128.67 158.08,131.74 144.59,145.22 144.59,145.61 144.78,145.8 145.34,145.8 145.54,146 145.54,146.36 145.34,146.56 143.26,146.56 141.61,148.21 133.48,148.21 133.22,148.46 133.22,150.42 133.02,150.62 132.33,150.62 132.19,150.77 132.19,156.44 132.92,157.17 J1.150
DDR_DQ30: length 56.4
  TOP w0.127: U1.M26 v2(163.72,123.65)
  L3SIG w0.102: v2(163.72,123.65) 163.72,123.81 163.32,124.21 163.32,125.71 163.3,125.73
  L3SIG w0.203: 163.3,125.73 163.3,128.68 161.77,130.2 161.77,134.65 159.13,137.29 159.13,138.54 158.93,138.75 157.67,138.75 157.48,138.94 157.48,143.51 148.72,152.27 138.94,152.27 137.41,153.8 137.41,154.75 137.73,155.06 137.73,156.15 137.03,156.84 137.03,158.09 137.92,158.97 J1.155
DDR_DQ31: length 56.8
  TOP w0.127: U1.M25 v2(163.72,122.85)
  L3SIG w0.102: 163.96,125.73 163.96,124.97 164.14,124.79 164.14,123.24 163.74,122.85 v2(163.72,122.85)
  L3SIG w0.203: J1.156 138.92,156.95 138.18,156.21 138.18,154.3 139.45,153.03 148.97,153.03 158.24,143.76 158.24,139.9 158.45,139.7 158.93,139.7 159.13,139.9 159.13,140.64 159.33,140.84 159.82,140.84 160.02,140.64 160.02,137.67 162.45,135.24 162.45,130.48 163.96,128.97 163.96,125.73
DDR_DQ32: length 56.6
  TOP w0.127: U1.T25 v2(167.72,122.85)
  L3SIG w0.102: 167.64,125.73 167.64,125.02 167.3,124.67 167.3,123.28 167.72,122.86 v2(167.72,122.85)
  L3SIG w0.203: 167.64,125.73 167.64,147.57 173.1,153.03 174.04,153.03 174.24,152.83 174.24,150.7 174.44,150.5 174.85,150.5 175.05,150.7 175.05,152.83 175.26,153.03 186.56,153.03 188.09,154.56 188.09,157.38 J1.81
DDR_DQ33: length 57.1
  TOP w0.127: U1.U25 v2(168.52,122.85)
  L3SIG w0.102: 168.66,125.73 168.66,125.48 168.4,125.22 168.27,125.22 167.77,124.71 167.77,124.13 168.1,123.8 168.1,123.26 v2(168.52,122.85)
  L3SIG w0.203: J1.82 188.92,154.25 186.05,151.38 184.01,151.38 183.8,151.59 183.8,152.16 183.6,152.36 183.19,152.36 182.99,152.16 182.99,151.59 182.79,151.38 182.46,151.38 182.25,151.59 182.25,152.16 182.05,152.36 181.64,152.36 181.44,152.16 181.44,151.59 181.24,151.38 180.83,151.38 180.63,151.59 180.63,152.16 180.42,152.36 180.02,152.36 179.81,152.16 179.81,151.59 179.61,151.38 178.24,151.38 178.04,151.59 178.04,152.16 177.84,152.36 177.43,152.36 177.23,152.16 177.23,151.59 177.02,151.38 176.15,151.38 175.89,151.13 175.89,149.94 175.69,149.73 170.81,149.73 168.66,147.57 168.66,125.73
DDR_DQ34: length 56.8
  TOP w0.127: U1.AA26 v2(171.72,123.65)
  L3SIG w0.102: 173.14,125.73 173.14,125.39 172.59,124.84 172.59,124.33 171.91,123.65 v2(171.72,123.65)
  L3SIG w0.203: J1.87 194.24,157.55 195.83,155.96 195.83,153.92 187.64,145.73 181.42,145.73 177.8,142.11 177.8,138.89 177.6,138.68 174.7,138.68 174.5,138.48 174.5,138 174.7,137.79 177.47,137.79 177.67,137.59 177.67,137.11 177.47,136.91 174.7,136.91 174.5,136.7 174.5,135.76 173.14,134.4 173.14,125.73
DDR_DQ35: length 56.5
  TOP w0.127: U1.AA25 v2(171.72,122.85)
  L3SIG w0.102: 172.47,125.73 172.47,125.35 172.19,125.08 172.19,124.31 171.94,124.06 171.56,124.06 171.32,123.83 171.32,123.24 v2(171.72,122.85)
  L3SIG w0.203: J1.88 195.07,155.49 195.07,154.18 187.33,146.43 180.85,146.43 177.31,142.89 175.53,142.89 175.39,142.75 175.39,142.22 175.59,142.01 176.83,142.01 177.04,141.81 177.04,141.3 176.83,141.1 174.84,141.1 174.64,140.89 174.64,140.54 174.84,140.33 176.82,140.33 177.02,140.13 177.02,139.68 176.78,139.45 173.94,139.45 173.74,139.24 173.74,136.02 172.47,134.75 172.47,125.73
DDR_DQ36: length 56.6
  TOP w0.127: U1.P25 v2(165.32,122.85)
  L3SIG w0.102: v2(165.32,122.85) 165.64,122.85 166.12,123.32 166.12,124.77 166.69,125.34 166.69,125.73
  L3SIG w0.203: 166.69,125.73 166.69,125.92 166.67,125.94 166.67,126.01 166.13,126.56 166.13,148.09 170.94,152.91 170.94,153.47 170.74,153.67 170.26,153.67 170.05,153.87 170.05,154.42 170.2,154.56 185.17,154.56 185.93,155.32 185.93,156.21 186.69,156.97 186.69,158.24 186.92,158.47 J1.200
DDR_DQ37: length 56.6
  TOP w0.127: U1.R25 v2(166.92,122.85)
  L3SIG w0.102: v2(166.92,122.85) 166.5,123.26 166.5,124.59 167.13,125.22 167.13,125.73
  L3SIG w0.203: J1.201 187.92,158.71 187.19,157.98 187.19,156.6 187.64,156.14 187.64,155.13 186.31,153.8 172.85,153.8 166.92,147.87 166.92,126.72 167.13,126.5 167.13,125.73
DDR_DQ38: length 56.8
  TOP w0.127: U1.W26 v2(170.12,123.65)
  L3SIG w0.102: 171.12,125.73 171.12,125.4 170.69,124.97 170.69,124.45 170.12,123.88 v2(170.12,123.65)
  L3SIG w0.203: 171.12,125.73 171.12,135.69 172.02,136.59 172.02,144.45 172.22,144.65 172.67,144.65 172.87,144.45 172.87,142.82 173.08,142.62 173.48,142.62 173.69,142.82 173.69,144.45 173.89,144.65 176.78,144.65 180.09,147.95 186.82,147.95 193.64,154.78 193.64,155.95 192.66,156.93 192.66,159.19 J1.206
DDR_DQ39: length 57
  TOP w0.127: U1.Y25 v2(170.92,122.85)
  L3SIG w0.102: 171.79,125.73 171.79,125.18 170.53,123.93 170.53,123.23 v2(170.92,122.85)
  L3SIG w0.203: J1.207 193.92,158.86 193.19,158.14 193.19,157.24 194.18,156.25 194.18,155.19 194.31,155.07 194.31,154.43 187.07,147.19 180.47,147.19 177.05,143.78 174.64,143.78 174.5,143.64 174.5,141.94 174.29,141.73 173.11,141.73 172.91,141.53 172.91,141.16 173.11,140.96 173.53,140.96 173.74,140.75 173.74,140.35 173.53,140.14 173.11,140.14 172.91,139.94 172.91,136.33 171.79,135.22 171.79,125.73
DDR_DQ40: length 65.5
  TOP w0.127: U1.V24 v2(169.32,122.05)
  L6SIG w0.102: 169.93,125.73 169.93,125.09 169.7,124.87 169.7,122.43 v2(169.32,122.05)
  L6SIG w0.203: J1.90 196.97,155.59 196.97,152.2 195.99,151.22 194.11,151.22 193.91,151.42 193.91,153.85 193.7,154.05 193.3,154.05 193.09,153.85 193.09,151.42 192.89,151.22 192.48,151.22 192.28,151.42 192.28,153.85 192.08,154.05 191.54,154.05 191.34,153.85 191.34,153.49 191.14,153.29 190.73,153.29 190.53,153.49 190.53,153.85 190.32,154.05 181.99,154.05 170.43,142.49 170.43,128.78 169.93,128.27 169.93,128.06 169.93,125.73
DDR_DQ41: length 65.4
  TOP w0.127: U1.W23 v2(170.12,121.25)
  L6SIG w0.102: 170.69,125.73 170.69,125.22 170.53,125.07 170.53,121.77 170.12,121.35 v2(170.12,121.25)
  L6SIG w0.203: 170.69,125.73 170.69,127.89 171.2,128.4 171.2,142.11 182.37,153.29 189.53,153.29 189.74,153.09 189.74,150.7 189.94,150.5 190.39,150.5 190.59,150.7 190.59,152.32 190.8,152.53 191.2,152.53 191.41,152.32 191.41,150.7 191.61,150.5 196.21,150.5 197.64,151.93 197.64,157.27 J1.91
DDR_DQ42: length 65.7
  TOP w0.127: U1.AA22 v2(171.72,120.45)
  L6SIG w0.102: v2(171.72,120.45) 171.72,120.53 172.05,120.86 172.67,120.86 172.93,121.13 172.93,121.4 173.2,121.66 173.47,121.66 173.73,121.93 173.73,122.2 173.96,122.43 174.27,122.43 174.53,122.69 174.53,125.73
  L6SIG w0.203: 174.53,125.73 174.53,126.27 175.26,127 175.26,139.06 178.44,142.24 180.77,142.24 180.97,142.44 180.97,142.8 180.77,143 180.16,143 179.96,143.21 179.96,143.56 180.16,143.76 185.42,143.76 185.67,144.02 185.67,145.34 185.88,145.54 186.26,145.54 186.46,145.34 186.46,143.97 186.66,143.76 187.07,143.76 187.27,143.97 187.27,145.34 187.48,145.54 198.25,145.54 203.33,150.62 203.33,155.24 J1.96
DDR_DQ43: length 65.5
  TOP w0.127: U1.AC22 v2(173.32,120.45)
  L6SIG w0.102: v2(173.32,120.45) 173.32,120.61 173.73,121.03 173.73,121.4 174,121.66 174.27,121.66 174.53,121.93 174.53,122.2 174.76,122.43 175.13,122.43 175.33,122.63 175.33,125.73
  L6SIG w0.203: 175.33,125.73 175.33,126.08 176.15,126.9 176.15,138.46 176.35,138.66 176.76,138.66 176.96,138.46 176.96,137.36 177.16,137.16 177.57,137.16 177.77,137.36 177.77,140.31 178.82,141.35 181.79,141.35 181.99,141.55 181.99,142.8 182.19,143 187.99,143 188.2,143.21 188.2,144.64 188.34,144.78 198.63,144.78 204.09,150.24 204.09,153.42 204.09,153.42 204.09,156.08 203.92,156.26 J1.97
DDR_DQ44: length 64.8
  TOP w0.127: U1.W22 v2(170.12,120.45)
  L6SIG w0.203: J1.209 195.92,158.96 195.07,158.11 195.07,156.72 195.71,156.08 195.71,155.19 195.2,154.69 195.2,153.16 v1(195.58,152.78)
  BOTTOM w0.127: v2(170.12,120.45) 170.12,120.46 170.5,120.84 176.15,120.84
  BOTTOM w0.203: v1(195.58,152.78) 196.47,152.78 198.88,150.37 198.88,136.27 193.29,130.68 184.4,130.68 179.2,125.48 179.2,123.89 176.15,120.84
DDR_DQ45: length 64.8
  TOP w0.127: U1.V23 v2(169.32,121.25)
  L6SIG w0.203: v1(194.94,151.89) 195.71,151.89 196.3,152.48 196.3,154.98 196.19,155.09 196.19,156.06 196.92,156.78 J1.210
  BOTTOM w0.127: v2(169.32,121.25) 169.51,121.25 169.91,121.65 171.88,121.65 171.89,121.67 172.34,121.67 172.35,121.65 176.14,121.65
  BOTTOM w0.203: 176.14,121.65 178.44,123.95 178.44,125.67 184.21,131.44 192.91,131.44 193.85,132.38 193.85,132.67 193.37,133.14 193.37,133.43 193.73,133.79 194.02,133.79 194.49,133.31 194.78,133.31 198.21,136.74 198.21,150.03 196.34,151.89 v1(194.94,151.89)
DDR_DQ46: length 65.5
  TOP w0.127: U1.AB24 v2(172.52,122.05)
  L6SIG w0.102: 172.9,125.73 172.9,122.69 172.52,122.31 v2(172.52,122.05)
  L6SIG w0.203: 172.9,125.73 172.9,126.41 173.61,127.13 173.61,139.7 179.45,145.54 181.91,145.54 182.12,145.75 182.12,146.1 181.91,146.3 180.92,146.3 180.72,146.51 180.72,146.86 180.92,147.07 197.49,147.07 201.68,151.26 201.68,156.08 201.04,156.72 201.04,158.11 201.92,158.99 J1.215
DDR_DQ47: length 65
  TOP w0.127: U1.AB23 v2(172.52,121.25)
  L6SIG w0.102: 173.73,125.73 173.73,122.73 173.47,122.46 173.2,122.46 172.93,122.2 172.93,121.79 172.52,121.37 v2(172.52,121.25)
  L6SIG w0.203: 173.73,125.73 173.73,126.49 174.5,127.25 174.5,139.45 179.7,144.65 182.75,144.65 182.99,144.89 182.99,146.1 183.19,146.3 183.72,146.3 183.92,146.1 183.92,144.86 184.12,144.65 184.53,144.65 184.73,144.86 184.73,146.1 184.94,146.3 197.87,146.3 202.56,151 202.56,154.69 202.19,155.06 202.19,156.09 202.92,156.81 J1.216
DDR_DQ48: length 65.4
  TOP w0.127: U1.AD26 v2(174.12,123.65)
  L3SIG w0.102: v2(174.12,123.65) 174.12,123.82 174.62,124.33 174.62,124.85 175.25,125.47 175.25,125.73
  L3SIG w0.203: J1.99 206.12,157.34 206.12,154.43 204.72,153.03 198.58,153.03 198.37,152.83 198.37,147.78 198.17,147.57 192.79,147.57 188.47,143.26 184.61,143.26 184.4,143.05 184.4,141.81 184.2,141.6 182.07,141.6 181.86,141.4 181.86,138.89 181.63,138.65 181.34,138.65 181.1,138.89 181.1,141.29 180.9,141.5 180.61,141.5 180.09,140.97 180.09,135.89 178.82,134.62 176.53,134.62 175.25,133.34 175.25,125.73
DDR_DQ49: length 65.4
  TOP w0.127: U1.AD25 v2(174.12,122.85)
  L3SIG w0.102: 176.02,125.73 175.01,124.71 175.01,124.3 174.53,123.83 174.53,123.48 174.12,123.06 v2(174.12,122.85)
  L3SIG w0.203: 176.02,125.73 176.02,133.1 176.78,133.86 179.2,133.86 180.97,135.64 180.97,137.59 181.18,137.79 181.99,137.79 182.63,138.43 182.63,140.64 182.83,140.84 185.04,140.84 185.29,141.1 185.29,142.24 185.55,142.49 188.85,142.49 191.39,145.03 195.76,145.03 195.96,145.24 195.96,145.72 195.76,145.92 193.15,145.92 192.94,146.13 192.94,146.61 193.15,146.81 198.88,146.81 199.14,147.07 199.14,152.07 199.34,152.27 205.1,152.27 206.92,154.08 J1.100
DDR_DQ50: length 65.2
  TOP w0.127: U1.AD23 v2(174.12,121.25)
  L3SIG w0.102: 177.8,120.27 177.6,120.06 174.76,120.06 174.5,120.32 174.5,120.86 v2(174.12,121.25)
  L3SIG w0.203: 177.8,120.27 181.86,124.33 181.86,128.02 184.28,130.43 186.87,130.43 187.07,130.63 187.07,131.37 187.27,131.57 187.88,131.57 188.09,131.37 188.09,130.63 188.29,130.43 192.79,130.43 205.61,143.26 205.61,144.27 213.87,152.53 213.87,156.08 212.4,157.55 J1.105
DDR_DQ51: length 65.2
  TOP w0.127: U1.AE22 v2(174.92,120.45)
  L3SIG w0.102: v2(174.92,120.45) 175.3,120.83 177.47,120.83 177.8,121.16
  L3SIG w0.203: 177.8,121.16 180.97,124.33 180.97,128.4 185.04,132.46 188.9,132.46 189.1,132.26 189.1,131.78 189.31,131.57 189.89,131.57 190.1,131.78 190.1,132.26 190.3,132.46 190.8,132.46 191.01,132.26 191.01,131.78 191.21,131.57 191.82,131.57 192.02,131.78 192.02,132.26 192.23,132.46 193.8,132.46 197.48,136.14 197.48,139.39 197.69,139.59 198.3,139.59 198.5,139.39 198.5,138.25 198.7,138.05 199.31,138.05 199.52,138.25 199.52,139.34 199.77,139.59 200.68,139.59 204.72,143.64 204.72,145.16 205.93,146.37 206.57,146.37 212.92,152.72 J1.106
DDR_DQ52: length 65.2
  TOP w0.127: U1.AB25 v2(172.52,122.85)
  L3SIG w0.102: 173.9,125.73 173.9,125.47 172.93,124.5 172.93,123.26 v2(172.52,122.85)
  L3SIG w0.203: J1.218 204.92,158.69 204.72,158.5 204.72,156.97 203.96,156.21 203.96,154.76 203.76,154.56 197.05,154.56 196.85,154.36 196.85,149.22 196.71,149.08 192.13,149.08 187.96,144.91 181.81,144.91 181.61,144.7 181.61,144.22 181.81,144.02 182.68,144.02 182.88,143.81 182.88,143.33 182.68,143.13 180.09,143.13 178.56,141.6 178.56,136.52 178.18,136.14 175.89,136.14 173.9,134.15 173.9,125.73
DDR_DQ53: length 65.2
  TOP w0.127: U1.AC25 v2(173.32,122.85)
  L3SIG w0.102: v2(173.32,122.85) 173.7,123.23 173.7,124.59 174.57,125.47 174.57,125.73
  L3SIG w0.203: 174.57,125.73 174.57,133.68 176.28,135.38 178.44,135.38 179.32,136.27 179.32,141.22 180.47,142.37 183.44,142.37 183.64,142.57 183.64,143.89 183.9,144.14 188.21,144.14 192.41,148.34 197.36,148.34 197.61,148.59 197.61,153.59 197.82,153.8 204.34,153.8 205.64,155.1 205.64,156.56 205.19,157.02 205.19,158.2 205.92,158.93 J1.219
DDR_DQ54: length 65.7
  TOP w0.127: U1.AC23 v2(173.32,121.25)
  L3SIG w0.102: v2(173.32,121.25) 173.73,121.66 175.13,121.66 175.51,122.05 176.91,122.05 177.8,122.94
  L3SIG w0.203: 177.8,122.94 179.49,124.63 179.49,129.2 184.28,133.98 193.04,133.98 195.83,136.78 195.83,140.33 196.72,141.22 200.02,141.22 202.95,144.14 202.95,148.08 203.33,148.46 206.38,148.46 211.2,153.29 211.2,154.6 211.71,155.1 211.71,155.96 210.69,156.97 210.69,159.22 J1.224
DDR_DQ55: length 65.6
  TOP w0.127: U1.AE23 v2(174.92,121.25)
  L3SIG w0.102: v2(174.92,121.25) 175.09,121.25 175.51,121.67 177.42,121.67 177.8,122.05
  L3SIG w0.203: 177.8,122.05 180.16,124.41 180.16,128.73 184.66,133.22 193.42,133.22 196.66,136.46 196.66,140.02 197.1,140.46 200.41,140.46 203.83,143.89 203.83,145.54 205.49,147.19 206.25,147.19 212.19,153.13 212.19,156.11 211.19,157.11 211.19,158.1 211.92,158.83 J1.225
DDR_DQ56: length 72.8
  TOP w0.127: U1.AG25 176.17,122.45 176.63,122.91 177.26,122.91 177.8,123.44
  TOP w0.203: 177.8,123.44 178.23,123.88 178.23,130.61 183.26,135.64 186.44,135.64 187.71,136.91 187.71,140.08 198.12,150.5 199.33,150.5 199.53,150.7 199.53,151.82 199.74,152.02 206.08,152.02 206.28,152.22 206.28,152.63 206.08,152.83 201.75,152.83 201.55,153.03 201.55,153.44 201.75,153.64 206.89,153.64 207.09,153.44 207.09,152.22 207.29,152.02 214.38,152.02 214.92,152.56 J1.108
DDR_DQ57: length 73
  TOP w0.127: 177.8,122.68 177.56,122.45 U1.AH25
  TOP w0.203: J1.109 215.92,156.99 215.65,156.72 215.65,151.89 215.01,151.26 205.31,151.26 205.11,151.05 205.11,149.94 204.9,149.73 204.5,149.73 204.29,149.94 204.29,151.05 204.09,151.26 203.69,151.26 203.48,151.05 203.48,149.94 203.28,149.73 202.87,149.73 202.67,149.94 202.67,151.05 202.47,151.26 202.06,151.26 201.86,151.05 201.86,149.94 201.65,149.73 201.25,149.73 201.04,149.94 201.04,151.05 200.84,151.26 200.48,151.26 200.28,151.05 200.28,149.94 200.08,149.73 198.37,149.73 192.91,144.27 192.91,137.16 190.63,134.87 183.51,134.87 178.9,130.26 178.9,123.79 177.8,122.68
DDR_DQ58: length 72.5
  TOP w0.127: U1.AH22 177.27,120.4 177.8,120.4
  TOP w0.203: 177.8,120.4 179.45,120.4 182.25,123.19 182.25,128.78 184.28,130.81 191.52,130.81 197.48,136.78 197.48,140.72 199.16,142.39 202.74,142.39 202.95,142.6 202.95,143 202.74,143.21 200.93,143.21 200.72,143.41 200.72,143.81 200.93,144.02 214.76,144.02 220.92,150.18 J1.114
DDR_DQ59: length 69.6
  TOP w0.127: U1.AF22 v2(175.72,120.45)
  L6SIG w0.102: 177.67,125.73 177.42,125.48 176.91,125.48 176.66,125.22 176.66,124.46 176.91,124.21 176.91,122.68 176.4,122.17 176.4,121.13 v2(175.72,120.45)
  L6SIG w0.203: 177.67,125.73 178.69,126.75 178.69,128.91 185.04,135.25 191.13,135.25 197.23,141.35 202.56,141.35 211.73,150.52 213.79,150.52 214,150.72 214,151.13 213.79,151.33 213.34,151.33 213.13,151.54 213.13,151.94 213.34,152.15 219.07,152.15 221.92,154.99 J1.115
DDR_DQ60: length 69.2
  TOP w0.127: U1.AF26 v2(175.72,123.65)
  L6SIG w0.102: 176.15,125.73 176.15,124.33 175.72,123.9 v2(175.72,123.65)
  L6SIG w0.203: 176.15,125.73 176.15,126.03 177.04,126.92 177.04,129.79 183.13,135.89 183.13,138.94 184.28,140.08 187.32,140.08 190.12,142.88 201.8,142.88 212.33,153.4 212.33,154.42 212.47,154.56 213.03,154.56 213.23,154.36 213.23,153.87 213.44,153.67 215.57,153.67 215.77,153.87 215.77,154.34 215.57,154.54 214.14,154.54 214,154.69 214,156.08 214.88,156.97 214.88,157.86 213.92,158.83 J1.227
DDR_DQ61: length 72.9
  TOP w0.127: 177.55,125.73 177.55,123.88 U1.AH26
  TOP w0.203: 177.55,125.73 177.55,130.94 183.01,136.4 186.05,136.4 186.94,137.29 186.94,140.33 201.04,154.43 212.14,154.43 212.34,154.23 212.34,153.82 212.14,153.62 208.09,153.62 207.88,153.42 207.88,153.01 208.09,152.81 213.77,152.81 214,153.04 214,156.21 214.92,157.13 J1.228
DDR_DQ62: length 72.7
  TOP w0.127: U1.AH23 177.8,120.85
  TOP w0.203: J1.233 219.92,158.93 220.85,157.99 220.85,156.97 219.92,156.03 219.92,150.57 214.25,144.91 200.53,144.91 196.72,141.1 196.72,137.03 191.26,131.57 183.9,131.57 181.48,129.16 181.48,123.32 179.01,120.85 177.8,120.85
DDR_DQ63: length 69
  TOP w0.127: U1.AF23 v2(175.72,121.25)
  L6SIG w0.102: v2(175.72,121.25) 175.72,122.25 176.13,122.67 176.13,123.94 176.4,124.21 176.4,125.48 176.66,125.73
  L6SIG w0.203: J1.234 220.92,157.16 219.96,156.21 219.96,154.76 219.76,154.56 217.63,154.56 217.42,154.36 217.42,153.14 217.22,152.93 213,152.93 202.18,142.11 190.5,142.11 187.55,139.16 187.55,137.51 186.18,136.14 184.53,136.14 177.8,129.41 177.8,126.87 176.66,125.73
DDR_ECC0: length 52.4
  TOP w0.127: U1.L24 v2(162.92,122.05)
  L6SIG w0.102: 162.86,125.73 162.86,124.42 163.32,123.95 163.32,122.45 v2(162.92,122.05)
  L6SIG w0.203: 162.86,125.73 162.85,125.73 162.85,132.02 162.65,132.22 160.99,132.22 160.78,132.42 160.78,132.83 160.99,133.03 162.65,133.03 162.85,133.24 162.85,133.65 162.65,133.86 160.78,133.86 142.88,151.76 141.17,151.76 140.97,151.97 140.97,154.43 140.19,155.21 140.19,156.06 141.67,157.55 J1.39
DDR_ECC1: length 52.5
  TOP w0.127: U1.N23 v2(164.52,121.25)
  L6SIG w0.102: v2(164.52,121.25) 164.55,121.25 164.97,121.66 165.47,121.66 165.73,121.93 165.73,124.64 164.94,125.44 164.94,125.73
  L6SIG w0.203: 164.94,125.73 164.94,134.78 162.81,136.91 160.73,136.91 160.53,137.11 160.53,137.46 160.73,137.67 161.58,137.67 161.78,137.87 161.78,138.23 161.58,138.43 159.09,138.43 158.88,138.64 158.88,138.99 159.08,139.19 160.02,139.19 160.22,139.4 160.22,139.75 160.02,139.95 157.73,139.95 143.64,154.05 143.64,154.93 J1.40
DDR_ECC2: length 52.7
  TOP w0.127: U1.T23 v2(167.72,121.25)
  L6SIG w0.102: 167.64,125.73 167.64,124.33 167.3,123.99 167.3,121.66 v2(167.72,121.25)
  L6SIG w0.203: J1.45 147.7,157.33 147.7,155.15 147.45,154.9 147.45,154.18 149.48,152.15 153.47,152.15 153.67,151.94 153.67,150.83 153.87,150.62 154.61,150.62 154.81,150.42 154.81,148.92 155.02,148.72 155.37,148.72 155.57,148.92 155.57,150.42 155.78,150.62 156.13,150.62 156.34,150.42 156.34,148.01 167.64,136.7 167.64,125.73
DDR_ECC3: length 52.6
  TOP w0.127: U1.U23 v2(168.52,121.25)
  L6SIG w0.102: v2(168.52,121.25) 168.9,121.63 168.9,123.94 169.2,124.24 169.2,125.73
  L6SIG w0.203: 169.2,125.73 169.2,136.92 157.62,148.5 157.62,151.94 157.42,152.15 155.4,152.15 155.19,152.35 155.19,152.7 155.4,152.91 157.53,152.91 157.73,153.11 157.73,153.47 157.53,153.67 149.99,153.67 148.92,154.74 J1.46
DDR_ECC4: length 53
  TOP w0.127: U1.L23 v2(162.92,121.25)
  L6SIG w0.102: v2(162.92,121.25) 162.85,121.25 162.5,121.6 162.5,124.9 162.18,125.22 162.18,125.73
  L6SIG w0.203: J1.158 140.92,157.43 139.64,156.15 139.64,151.21 139.85,151 142.62,151 159.89,133.73 159.89,131.65 160.1,131.44 161.98,131.44 162.18,131.24 162.18,130.89 161.98,130.68 161.49,130.68 161.29,130.48 161.29,130.17 161.49,129.97 161.98,129.97 162.18,129.77 162.18,125.73
DDR_ECC5: length 52.7
  TOP w0.127: U1.M23 v2(163.72,121.25)
  L6SIG w0.102: 163.54,125.73 163.54,125.3 164.1,124.75 164.1,121.63 v2(163.72,121.25)
  L6SIG w0.203: 163.54,125.73 163.54,134.15 163.07,134.62 161.04,134.62 143.15,152.51 141.94,152.51 141.73,152.71 141.73,156.33 142.64,157.24 142.64,158.22 141.92,158.95 J1.159
DDR_ECC6: length 52.8
  TOP w0.127: U1.R24 v2(166.92,122.05)
  L6SIG w0.102: 167,125.73 167,124.46 166.5,123.95 166.5,122.43 166.88,122.05 v2(166.92,122.05)
  L6SIG w0.203: J1.164 146.92,156.82 146.18,156.08 146.18,155.28 146.69,154.77 146.69,153.92 149.12,151.49 151.08,151.49 151.28,151.29 151.28,150.32 151.49,150.11 151.89,150.11 152.1,150.32 152.1,151.29 152.3,151.49 152.7,151.49 152.91,151.29 152.91,150.06 153.11,149.86 153.85,149.86 154.05,149.66 154.05,148.29 154.25,148.08 155.37,148.08 167,136.45 167,125.73
DDR_ECC7: length 53.2
  TOP w0.127: U1.T24 v2(167.72,122.05)
  L6SIG w0.102: 168.61,125.73 168.61,125.3 168.1,124.79 168.1,122.43 v2(167.72,122.05)
  L6SIG w0.203: J1.165 147.92,158.92 148.84,157.99 148.84,156.84 148.19,156.19 148.19,154.45 149.73,152.91 154.23,152.91 154.43,152.7 154.43,151.59 154.64,151.38 156.77,151.38 156.97,151.18 156.97,148.26 168.61,136.63 168.61,125.73
DDR_MA0: length 40.3
  TOP w0.127: 168.52,125.93 168.72,125.73 168.72,125.04 U1.V28
  TOP w0.241: J1.188 174.92,156.88 174.17,156.13 174.17,151.94 173.48,151.26 173.48,150.89 173.72,150.65 174.26,150.65 174.5,150.41 174.5,149.92 174.26,149.68 173.72,149.68 173.48,149.44 173.48,148.96 173.72,148.72 174.26,148.72 174.5,148.48 174.5,147.99 174.26,147.75 173.72,147.75 173.48,147.51 173.48,145.41 168.52,140.45 168.52,125.93
DDR_MA1: length 40.9
  TOP w0.127: 165.12,125.85 164.92,125.66 U1.N28
  TOP w0.241: 165.12,125.85 165.12,142.26 168.15,145.29 168.15,146.13 168.45,146.43 169.36,146.43 169.6,146.67 169.6,147.08 169.36,147.32 168.4,147.32 168.11,147.62 168.11,156.03 168.91,156.83 168.91,157.86 167.92,158.85 J1.181
DDR_MA2: length 40.6
  TOP w0.127: U1.N27 164.51,124.45 164.51,125.73
  TOP w0.241: 164.51,125.73 164.51,145.13 165.69,146.31 166.03,146.31 166.27,146.06 166.27,145.72 165.28,144.73 165.28,144.39 165.52,144.14 165.86,144.14 167.39,145.67 167.39,151.64 167.66,151.92 167.66,156.61 167.92,156.87 J1.61
DDR_MA3: length 40.1
  TOP w0.127: U1.M28 163.92,125.05 163.92,125.73
  TOP w0.241: J1.180 166.92,157.01 165.99,156.08 165.99,151.89 166.62,151.26 166.62,147.32 166.38,147.08 166.04,147.08 165.8,147.32 165.8,148.48 165.56,148.72 165.21,148.72 164.97,148.48 164.97,146.69 163.92,145.63 163.92,125.73
DDR_MA4: length 40.5
  TOP w0.127: 162.71,125.73 162.71,125.35 162.91,125.15 162.91,124.49 163.32,124.09 U1.L27
  TOP w0.241: J1.59 165.02,156.65 164.78,156.65 164.17,156.04 164.17,155.11 164.47,154.81 164.47,150.37 163.58,149.48 163.58,147.57 161.04,145.03 161.04,139.1 161.28,138.86 161.62,138.86 161.86,139.1 161.86,140.24 162.1,140.48 162.47,140.48 162.71,140.24 162.71,125.73
DDR_MA5: length 40.3
  TOP w0.127: U1.L28 163.32,125.73
  TOP w0.241: J1.58 165.23,155.34 165.23,149.99 164.34,149.1 164.34,147.2 161.74,144.6 161.74,141.47 161.98,141.22 162.32,141.22 162.56,141.47 162.56,144.42 162.8,144.66 163.14,144.66 163.31,144.49 163.31,125.93 163.32,125.93 163.32,125.73
DDR_MA6: length 40.5
  TOP w0.127: 162.11,125.73 162.11,125.25 U1.K28
  TOP w0.241: J1.178 164.92,157.42 163.7,156.21 163.7,150.75 162.81,149.86 162.81,147.95 160.27,145.41 160.27,137.15 160.52,136.91 160.92,136.91 161.16,137.15 161.16,137.93 161.4,138.18 161.87,138.18 162.11,137.93 162.11,125.73
DDR_MA7: length 40.2
  TOP w0.127: 161.52,125.73 161.52,125.65 161.72,125.45 U1.J28
  TOP w0.241: J1.56 162.92,154.74 162.94,154.72 162.94,151 162.12,150.18 162.12,148.4 159.51,145.8 159.51,136.39 159.75,136.14 161.27,136.14 161.52,135.9 161.52,135.53 161.27,135.29 159.75,135.29 159.51,135.05 159.51,134.71 159.75,134.47 161.27,134.47 161.52,134.23 161.52,133.86 161.27,133.62 160.13,133.62 159.89,133.38 159.89,133.04 160.13,132.79 161.27,132.79 161.52,132.55 161.52,125.73
DDR_MA8: length 40.7
  TOP w0.127: U1.J27 161.31,124.45 161.31,125.15 160.91,125.55 160.91,125.73
  TOP w0.241: 160.91,125.73 160.91,131.06 158.75,133.22 158.75,146.05 161.42,148.72 161.42,150.5 162.17,151.25 162.17,156.33 163.07,157.23 163.07,158.11 163.92,158.96 J1.177
DDR_MA9: length 41.6
  TOP w0.127: U1.G27 159.71,124.45 159.71,125.35 159.11,125.96
  TOP w0.241: 159.11,125.96 159.11,130.32 156.84,132.59 156.84,148.97 159.66,151.79 159.66,156.44 159.13,156.97 159.13,157.99 159.77,158.62 159.77,159.89 161.22,161.35 J1.175
DDR_MA10: length 41.1
  TOP w0.127: 170.62,125.93 170.92,125.63 170.92,124.45 U1.Y27
  TOP w0.241: J1.70 177.04,155.52 177.04,145.16 177.61,144.59 177.61,143.37 177.39,143.14 177.07,143.14 176.84,143.37 176.84,144.03 176.6,144.27 176.26,144.27 176.02,144.03 176.02,141.64 175.78,141.4 175.44,141.4 175.2,141.64 175.2,142.62 174.95,142.86 174.61,142.86 174.37,142.62 174.37,139.95 170.62,136.2 170.62,125.93
DDR_MA11: length 39.5
  TOP w0.127: U1.H28 160.51,125.25 160.51,125.73 160.31,125.93
  TOP w0.241: J1.55 162.25,157.55 162.54,157.84 162.54,158.51 162.18,158.88 161.67,158.88 161.16,158.37 161.16,156.84 161.67,156.34 161.67,151.76 160.78,150.88 160.78,149.1 158.11,146.43 158.11,132.97 160.31,130.77 160.31,125.93
DDR_MA12: length 40.2
  TOP w0.127: U1.G28 160.12,125.55 159.71,125.96
  TOP w0.241: 159.71,125.96 159.71,130.48 157.48,132.72 157.48,148.46 157.73,148.72 157.99,148.72 158.5,148.21 158.75,148.21 159,148.46 159,148.97 158.6,149.37 158.6,149.71 158.83,149.94 159.17,149.94 159.7,149.42 159.96,149.42 160.17,149.63 160.17,156.23 160.66,156.73 160.66,159.19 J1.174
DDR_MA13: length 40.2
  TOP w0.127: U1.AE28 174.52,125.41 174.84,125.73
  TOP w0.241: 174.84,125.73 174.84,133.31 184.91,143.38 184.91,147.94 184.4,148.45 184.4,149.61 184.91,150.11 184.91,151 184.15,151.76 184.15,156.21 183.13,157.23 183.13,158.5 182.92,158.71 J1.196
DDR_MA14: length 41.3
  TOP w0.127: 157.51,125.96 158.11,125.35 158.11,124.45 U1.E27
  TOP w0.241: J1.172 158.92,158.53 158.66,158.28 158.66,156.89 158.17,156.39 158.17,154.61 157.67,154.11 157.67,152.46 153.92,148.72 153.92,140.83 154.17,140.59 154.88,140.59 155.07,140.4 155.07,139.84 154.83,139.6 154.29,139.6 154.05,139.36 154.05,138.87 154.29,138.63 154.83,138.63 155.07,138.39 155.07,131.95 157.51,129.51 157.51,125.96
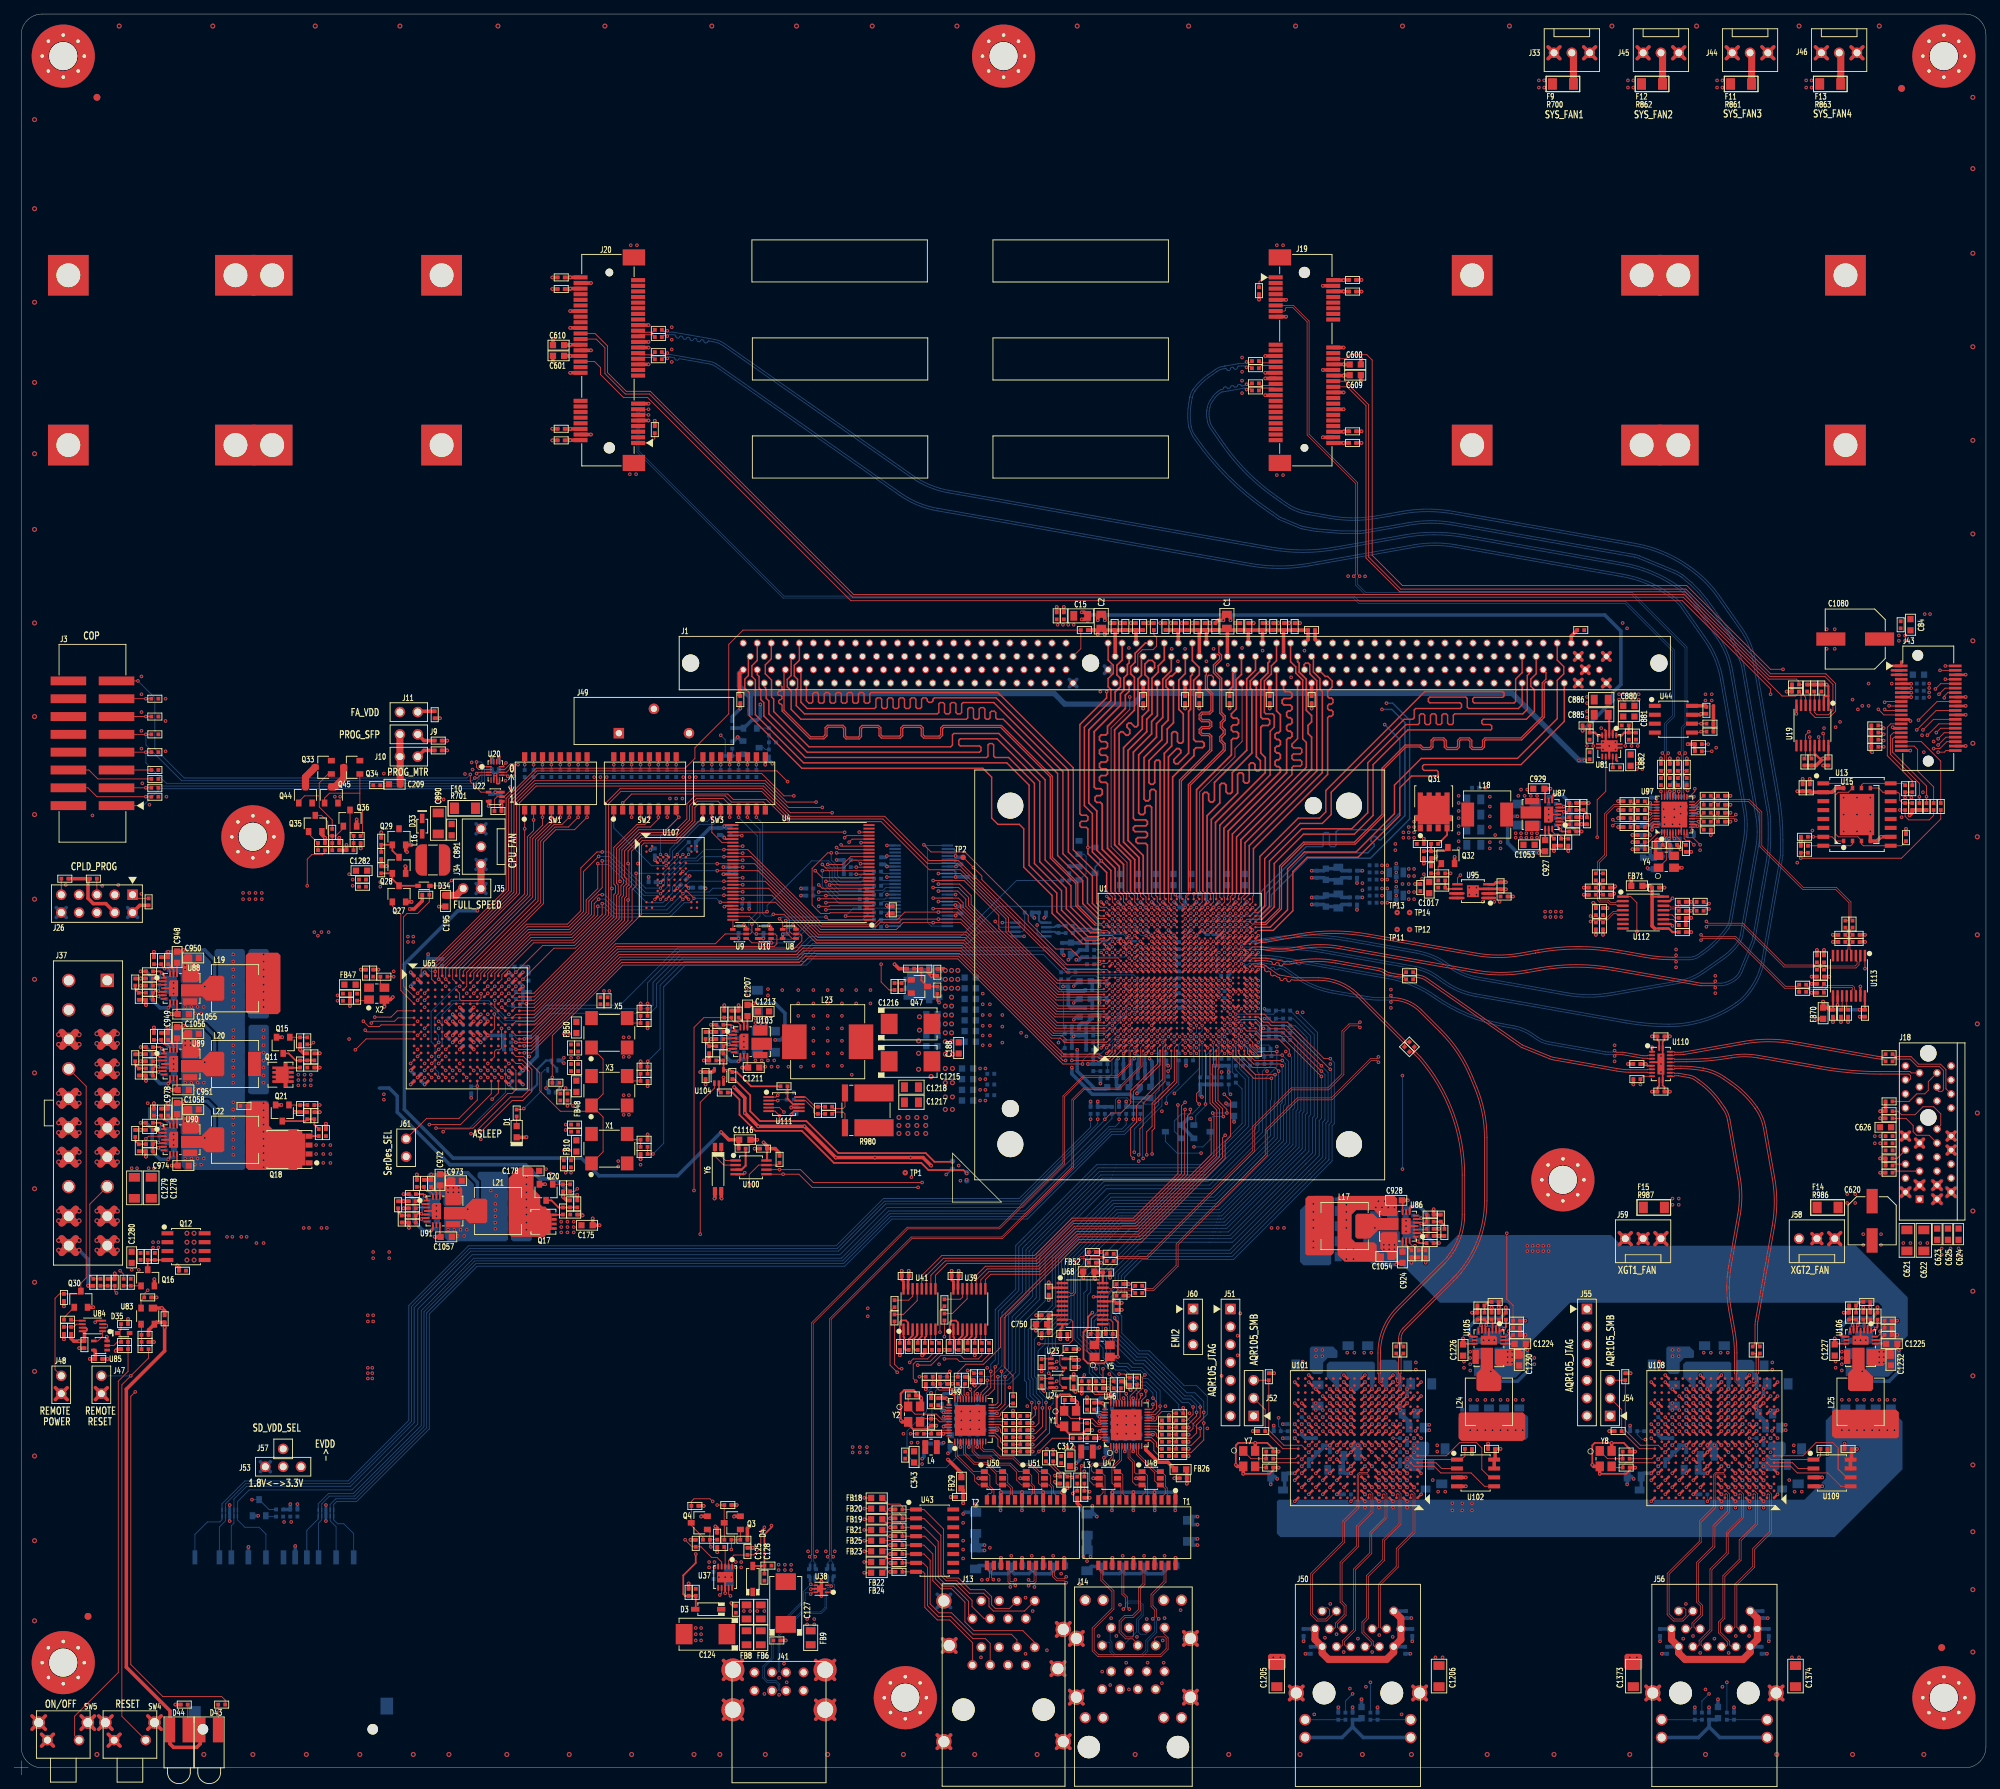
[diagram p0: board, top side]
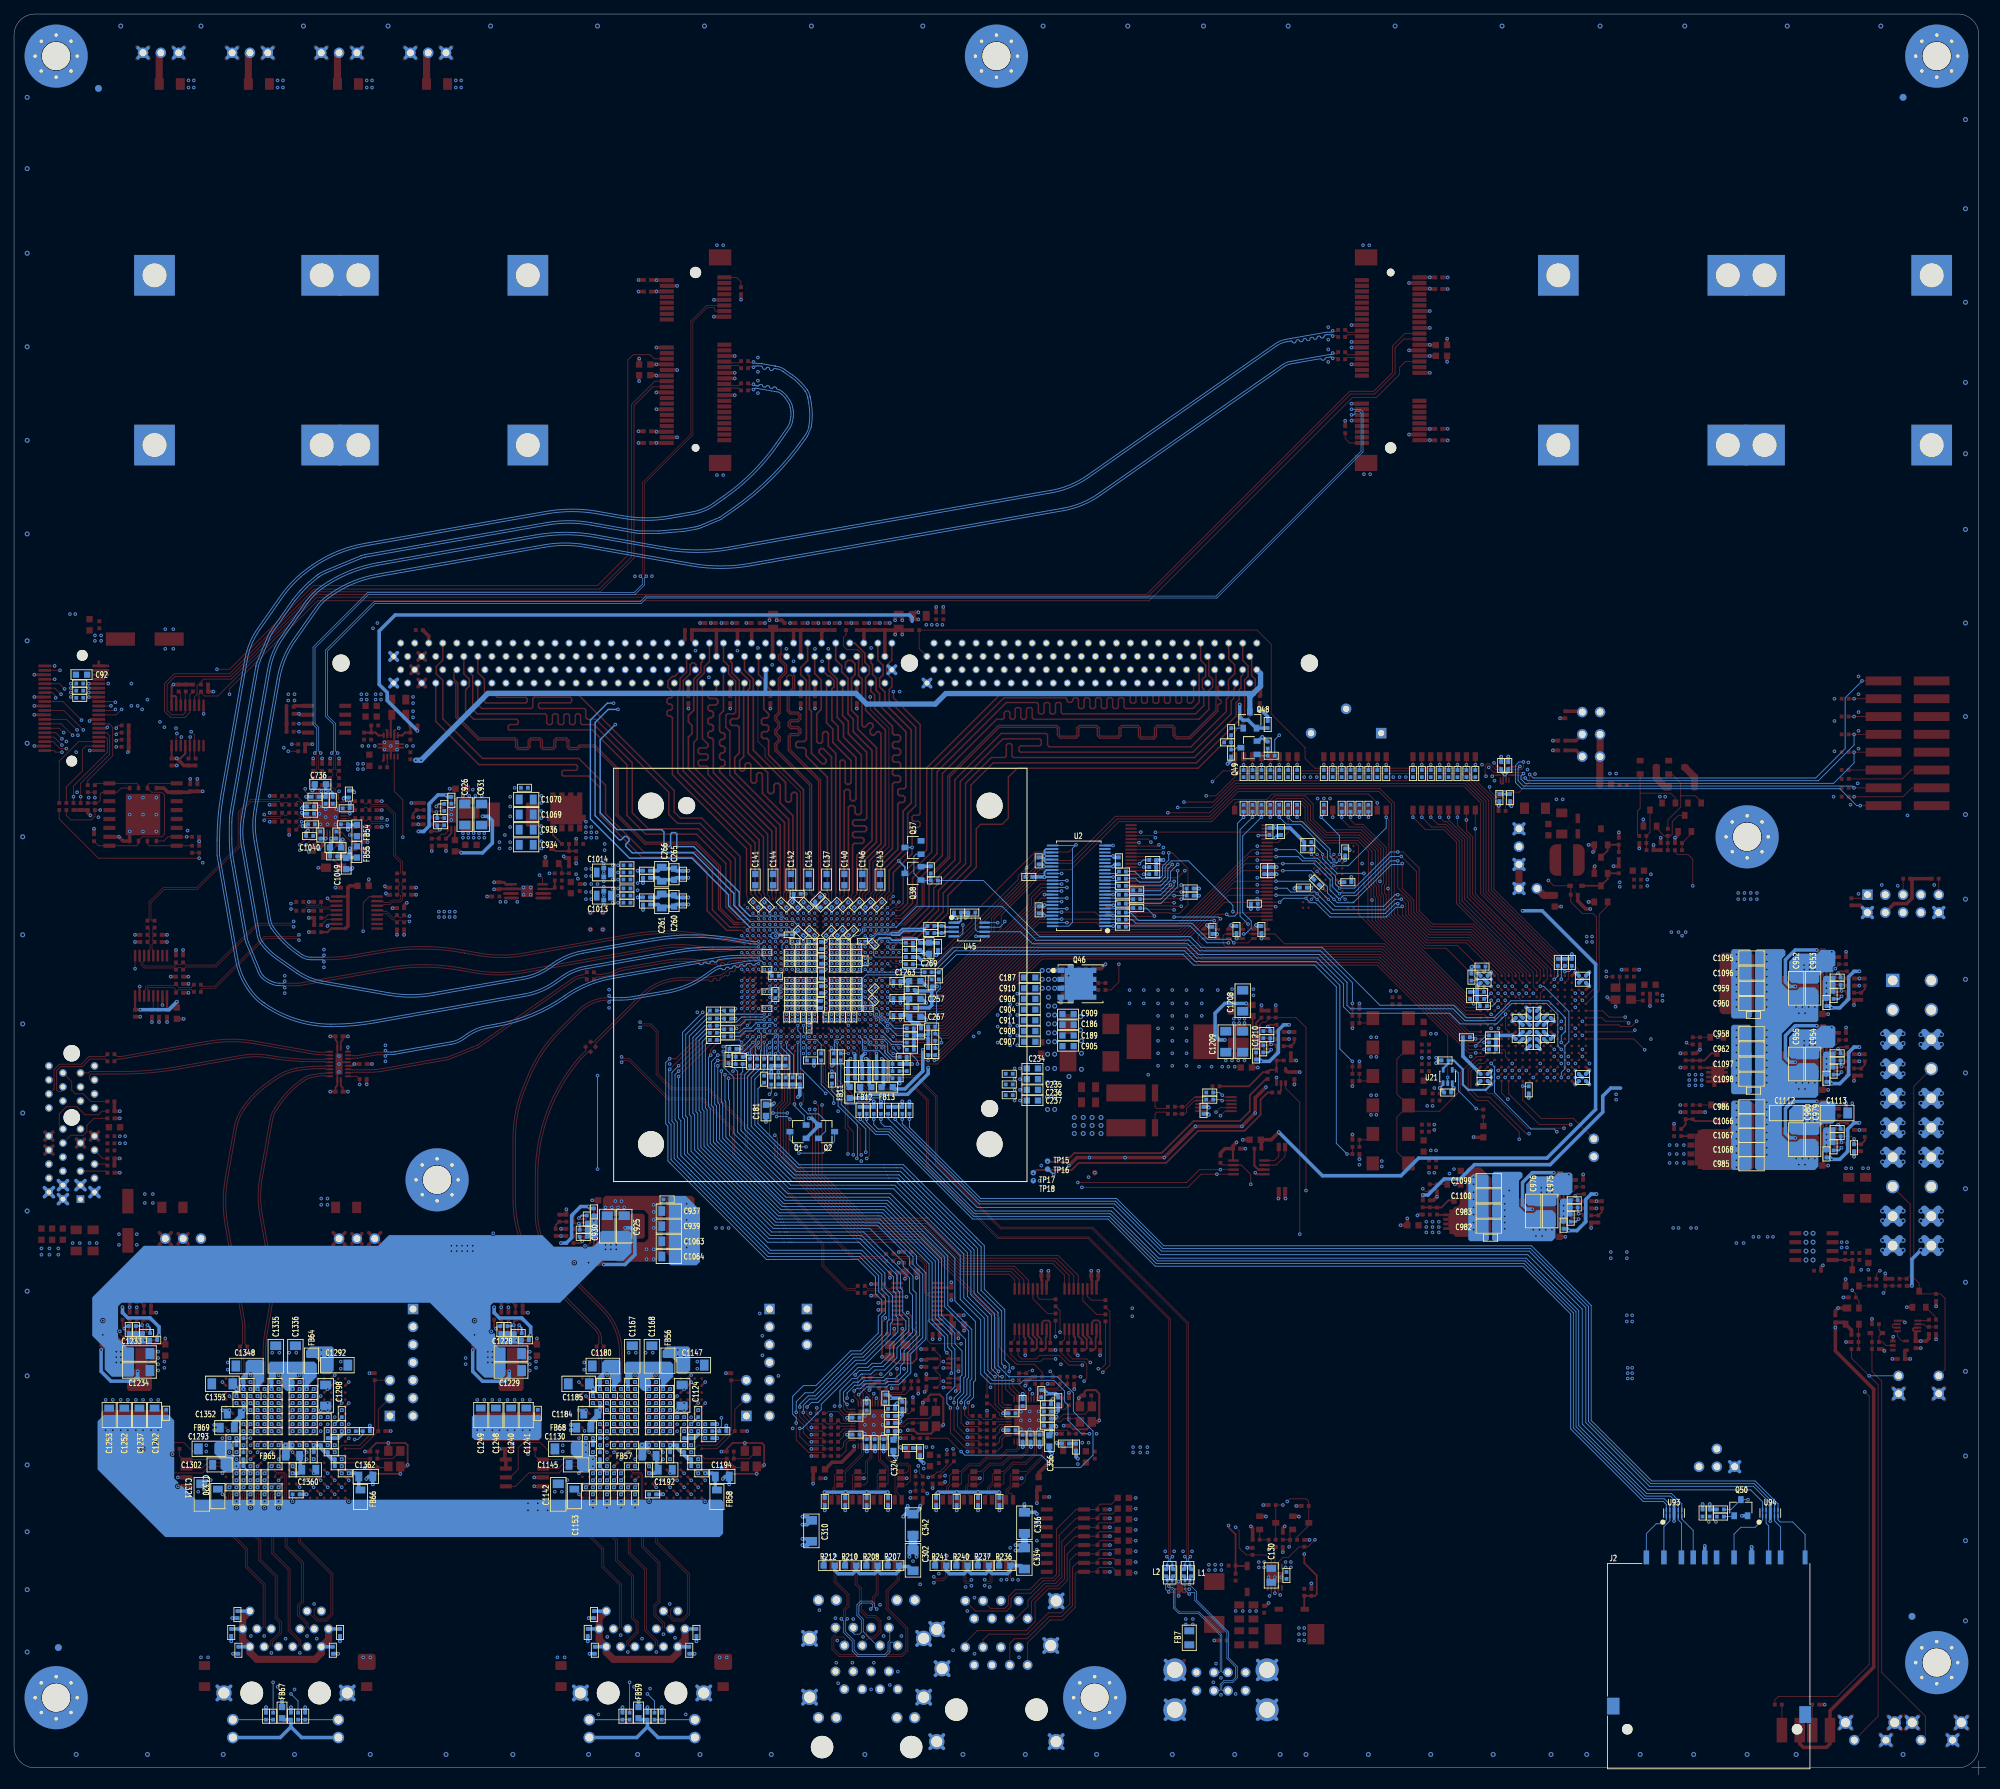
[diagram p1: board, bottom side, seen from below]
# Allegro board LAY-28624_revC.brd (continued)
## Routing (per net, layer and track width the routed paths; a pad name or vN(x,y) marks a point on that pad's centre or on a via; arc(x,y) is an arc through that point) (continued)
DDR_MA15: length 40.8
  TOP w0.127: 156.91,125.96 157.72,125.15 U1.D28
  TOP w0.241: 156.91,125.96 156.91,129.22 154.3,131.83 154.3,137.41 153.16,138.56 153.16,148.97 156.91,152.72 156.91,154.37 157.66,155.12 157.66,156.32 157.17,156.82 157.17,158.18 157.92,158.93 J1.171
DDR_MAPAR_ERR: length 43.3
  TOP w0.127: J1.53 160.15,157.78 160.15,159.77 160.78,160.4 162.31,160.4 162.81,160.91 162.81,162.18 162.43,162.56 R4.2 ; v1(159,153.67) 159,151.89 156.34,149.22 156.34,132.33 158.61,130.06 158.61,125.96 158.91,125.65 158.91,125.25 U1.F28
  L6SIG w0.102: J1.53 159.92,154.58 v1(159,153.67)
DDR_MAPAR_OUT: length 34.5
  TOP w0.127: J1.68 175.01,155.56 175.01,147.32 173.99,146.3 173.99,145.16 168.96,140.13 168.96,126.01 169.32,125.65 169.32,124.45 U1.V27
DDR_MBA0: length 39.8
  TOP w0.127: 170.02,125.93 170.52,125.43 U1.Y28
  TOP w0.241: J1.71 177.76,157.55 176.17,155.96 176.17,154.92 176.4,154.69 176.4,145.67 173.61,142.88 173.61,140.14 173.37,139.9 172.96,139.9 172.72,140.14 172.72,141.11 172.48,141.35 172.07,141.35 171.83,141.11 171.83,138.56 170.02,136.74 170.02,125.93
DDR_MBA1: length 41
  TOP w0.127: 169.42,126.03 169.72,125.73 U1.W28
  TOP w0.241: J1.190 176.92,157.49 175.66,156.23 175.66,146.07 171.07,141.48 171.07,138.93 170.83,138.69 170.49,138.69 170.24,138.94 170.24,139.83 170,140.07 169.66,140.07 169.42,139.83 169.42,126.03
DDR_MBA2: length 40.1
  TOP w0.127: 158.11,125.96 158.52,125.55 U1.E28
  TOP w0.241: 158.11,125.96 158.11,129.8 155.83,132.08 155.83,141.26 155.59,141.5 154.93,141.5 154.69,141.74 154.69,142.22 154.93,142.46 155.59,142.46 155.83,142.7 155.83,143.19 155.59,143.43 154.93,143.43 154.69,143.67 154.69,144.15 154.93,144.39 155.59,144.39 155.83,144.63 155.83,145.12 155.59,145.36 154.93,145.36 154.69,145.6 154.69,146.08 154.93,146.32 155.59,146.32 155.83,146.56 155.83,147.05 155.59,147.29 154.93,147.29 154.69,147.53 154.69,148.01 154.93,148.25 155.59,148.25 155.83,148.5 155.83,149.48 158.37,152.02 158.37,153.92 158.92,154.47 J1.52
DDR_MCAS_N: length 39.8
  TOP w0.127: 173.02,125.73 173.02,125.35 172.92,125.25 U1.AC28
  TOP w0.241: J1.74 180.92,154.66 181.16,154.41 181.88,154.41 182.12,154.17 182.12,153.69 181.88,153.45 180.96,153.45 180.72,153.21 180.72,152.78 180.97,152.53 181.88,152.53 182.12,152.29 182.12,151.92 181.88,151.68 181.6,151.68 181.36,151.43 181.36,150.95 181.6,150.71 181.88,150.71 182.12,150.47 182.12,149.99 181.88,149.75 181.6,149.75 181.36,149.5 181.36,149.02 181.6,148.78 181.88,148.78 182.12,148.54 182.12,148.06 181.88,147.82 181.6,147.82 181.36,147.57 181.36,142.88 173.02,134.54 173.02,125.73
DDR_MCK0_N: length 40.8
  TOP w0.102: U1.T28 167.13,125.03 167.13,125.22 167.59,125.68 167.59,126.02 167.63,126.06 167.63,126.09
  TOP w0.178: 167.63,126.09 167.63,141.07 172.59,146.04 172.59,147.01 172.11,147.49 172.11,147.88 172.59,148.36 172.59,148.99 172.17,149.41 172.17,149.93 172.59,150.35 172.59,150.97 172.11,151.45 172.11,156.31 171.2,157.23 171.2,158.1 172.08,158.99 172.08,159.64 171.7,160.02 171.7,161.13 J1.185
DDR_MCK0_P: length 40.7
  TOP w0.102: 167.35,126.09 167.35,126.06 167.39,126.02 167.39,125.76 166.93,125.31 166.93,124.43 U1.T27
  TOP w0.178: 167.35,126.09 167.35,141.19 172.31,146.15 172.31,146.89 171.83,147.37 171.83,148 172.31,148.48 172.31,148.87 171.89,149.29 171.89,150.04 172.31,150.46 172.31,150.85 171.83,151.34 171.83,156.2 170.92,157.11 170.92,158.22 171.81,159.11 171.81,159.52 171.58,159.75 171.22,159.75 J1.184
DDR_MCK1_N: length 40.8
  TOP w0.102: U1.R28 166.32,125.04 166.32,125.9 166.36,125.94 166.36,125.96
  TOP w0.178: 166.36,125.96 166.36,141.71 170.69,146.04 170.69,148.1 170.35,148.44 169.37,148.44 169.16,148.64 169.16,148.95 169.37,149.15 170.35,149.15 170.69,149.49 170.69,150.08 170.35,150.42 169.37,150.42 169.16,150.62 169.16,151.03 169.37,151.23 170.42,151.23 170.84,151.65 170.84,154.15 170.05,154.94 170.05,156.58 170.24,156.76 170.65,156.76 170.92,156.49 J1.64
DDR_MCK1_P: length 40.8
  TOP w0.102: 166.08,125.96 166.08,125.94 166.12,125.9 166.12,124.45 U1.R27
  TOP w0.178: 166.08,125.96 166.08,141.82 170.41,146.15 170.41,147.98 170.23,148.16 169.25,148.16 168.88,148.52 168.88,149.06 169.25,149.43 170.23,149.43 170.41,149.61 170.41,149.96 170.23,150.14 169.25,150.14 168.88,150.51 168.88,151.14 169.25,151.51 170.31,151.51 170.56,151.76 170.56,154.04 169.77,154.82 169.77,156.69 169.92,156.84 J1.63
DDR_MCKE0: length 39
  TOP w0.127: U1.C27 156.51,124.45 156.51,125.15 155.71,125.96
  TOP w0.216: v1(155.7,154.43) 155.7,153.54 151.89,149.73 151.89,137.02 152.11,136.81 152.82,136.81 153.03,136.59 153.03,136.16 152.82,135.94 152.11,135.94 151.89,135.73 151.89,135.29 152.11,135.08 152.82,135.08 153.03,134.86 v1(153.03,132.21) 153.03,131.32 155.71,128.64 155.71,125.96
  L6SIG w0.216: v1(155.7,154.43) J1.50
  BOTTOM w0.216: Q37.3 v1(153.03,132.21)
DDR_MCKE1: length 42.8
  TOP w0.127: 156.31,125.96 156.92,125.35 U1.C28
  TOP w0.216: 156.31,125.96 156.31,128.93 v1(154.94,130.3) 153.67,131.57 153.67,137.03 152.53,138.18 152.53,149.35 156.31,153.13 156.31,154.71 155.91,155.11 155.91,156.28 156.65,157.02 156.65,158.18 155.92,158.92 J1.169
  BOTTOM w0.216: v1(154.94,130.3) 154.06,129.42 Q38.3
DDR_MCS0_N: length 41.7
  TOP w0.127: 171.83,125.73 171.83,125.13 U1.AB28
  TOP w0.216: J1.193 179.92,158.83 179.18,158.1 179.18,156.95 178.18,155.95 178.18,151.47 178.4,151.26 179.36,151.26 179.58,151.04 179.58,149.35 179.01,148.78 179.01,142.56 171.83,135.38 171.83,125.73
DDR_MCS1_N: length 40.3
  TOP w0.127: 173.62,125.73 173.62,125.45 173.32,125.15 173.32,124.45 U1.AC27
  TOP w0.216: J1.76 182.92,147.74 182.12,146.94 182.12,146.62 182.33,146.41 183.3,146.41 183.51,146.19 183.51,145.76 183.3,145.54 182.33,145.54 182.12,145.33 182.12,144.89 182.33,144.68 183.3,144.68 183.51,144.46 183.51,144.03 183.3,143.81 182.33,143.81 182.12,143.6 182.12,142.62 173.62,134.12 173.62,125.73
DDR_MCS2_N: length 41.4
  TOP w0.127: U1.AG27 176.53,124.46 176.53,125.26 176.62,125.35 176.62,125.73
  TOP w0.216: J1.79 186.87,156.59 187.2,156.59 187.83,155.96 187.83,155.07 187.2,154.43 187.2,153.73 187.41,153.51 187.74,153.51 187.96,153.29 187.96,152.86 187.74,152.65 187.41,152.65 187.2,152.43 187.2,152 187.41,151.78 187.74,151.78 187.96,151.57 187.96,151.14 187.74,150.92 187.41,150.92 187.2,150.7 187.2,142.62 176.62,132.05 176.62,125.73
DDR_MCS3_N: length 39.8
  TOP w0.127: 176.02,125.73 176.02,125.55 U1.AF28
  TOP w0.216: 176.02,125.73 176.02,132.46 186.44,142.88 186.44,154.43 186.11,154.76 186.11,156.28 185.17,157.23 185.17,159.2 J1.198
DDR_MDM0: length 82.4
  TOP w0.127: U1.B22 155.77,120.4 154.94,120.4 154.81,120.52 154.43,120.52
  TOP w0.203: 154.43,120.52 153.8,120.52 150.62,123.7 150.62,126.75 146.94,130.43 146.94,141.86 140.33,148.46 133.93,148.46 133.73,148.26 133.73,146.81 133.48,146.56 113.28,146.56 108.25,151.59 108.25,153.36 107.95,153.67 107.95,156.08 107.06,156.97 107.06,158.24 107.92,159.1 J1.125
DDR_MDM1: length 69.6
  TOP w0.127: U1.C25 v2(156.52,122.85)
  L3SIG w0.102: v2(156.52,122.85) 156.52,122.88 155.83,123.57 155.07,123.57 154.43,124.21
  L3SIG w0.203: 154.43,124.21 154.18,124.46 154.18,125.6 145.03,134.75 140.72,134.75 137.22,138.24 137.22,141.91 137.02,142.11 124.59,142.11 123.83,142.88 123.83,144.96 123.62,145.16 122.72,145.16 122.52,145.36 122.52,145.83 122.72,146.03 123.73,146.03 123.93,146.24 123.93,146.74 123.73,146.94 121.38,146.94 121.17,147.14 121.17,147.68 121.03,147.83 120.22,147.83 120.02,148.03 120.02,149.4 119.81,149.61 118.11,149.61 116.46,151.26 116.46,154.81 116.19,155.08 116.19,156.32 116.64,156.78 116.64,159.17 J1.134
DDR_MDM2: length 66.6
  TOP w0.127: U1.F23 v2(158.92,121.25)
  L6SIG w0.102: v2(158.92,121.25) 158.66,121.25 158.24,121.66 155.45,121.66 154.94,122.17 154.43,122.17
  L6SIG w0.203: 154.43,122.17 153.03,123.57 153.03,128.91 150.5,131.44 150.5,132.97 149.48,133.98 145.49,133.98 145.29,134.19 145.29,135.31 145.08,135.51 139.19,135.51 138.95,135.75 138.95,136.03 139.56,136.63 139.56,136.92 139.25,137.22 138.97,137.22 138.37,136.62 138.08,136.62 137.81,136.89 137.81,137.18 138.03,137.4 138.03,137.69 137.75,137.97 137.46,137.97 137.24,137.75 136.95,137.75 124.19,150.51 124.19,156.06 124.97,156.84 124.97,158.12 125.92,159.06 J1.143
DDR_MDM3: length 56.3
  TOP w0.127: U1.K26 v2(162.12,123.65)
  L3SIG w0.102: v2(162.12,123.65) 161.53,124.23 161.53,125.73
  L3SIG w0.203: J1.152 134.92,156.89 134.18,156.15 134.18,155.16 134.37,154.97 134.37,154.94 134.62,154.69 134.62,153.42 135.51,152.53 135.51,150.75 135.74,150.52 144.75,150.52 153.29,141.99 153.29,139.84 153.49,139.64 153.97,139.64 154.18,139.84 154.18,140.59 154.3,140.72 154.86,140.72 155.07,140.51 155.07,138.05 160.1,133.02 160.1,129.51 161.53,128.07 161.53,125.73
DDR_MDM4: length 57
  TOP w0.127: U1.U26 v2(168.52,123.65)
  L3SIG w0.102: 169.37,125.73 169.37,125.72 168.62,124.97 168.4,124.97 168.13,124.7 168.13,124.22 168.52,123.84 v2(168.52,123.65)
  L3SIG w0.203: 169.37,125.73 169.37,147.27 171.07,148.97 176.44,148.97 176.64,149.17 176.64,150.48 176.78,150.62 186.31,150.62 189.92,154.23 189.92,156.03 189.1,156.84 189.1,158.24 189.92,159.06 J1.203
DDR_MDM5: length 64.8
  TOP w0.127: U1.Y24 v2(170.92,122.05)
  L6SIG w0.203: J1.212 198.92,156.88 198.19,156.15 198.19,155.25 198.51,154.93 198.51,151.78 196.47,149.73 v1(195.33,149.73)
  BOTTOM w0.127: 176.15,122.43 175.09,122.43 175.08,122.44 173.15,122.44 173.14,122.43 172.69,122.43 172.68,122.44 171.55,122.44 171.16,122.05 v2(170.92,122.05)
  BOTTOM w0.203: 176.15,122.43 177.67,123.95 177.67,125.86 184.15,132.33 186.42,132.33 186.56,132.48 186.56,134.13 186.77,134.34 187.25,134.34 187.45,134.13 187.45,132.54 187.66,132.33 188.19,132.33 188.39,132.54 188.39,134.42 188.73,134.75 195.07,134.75 197.48,137.16 197.48,147.57 v1(195.33,149.73)
DDR_MDM6: length 65.9
  TOP w0.127: U1.AD24 v2(174.12,122.05)
  L3SIG w0.102: 176.83,125.73 175.94,124.84 175.57,124.84 175.33,124.6 175.33,123.52 175.08,123.26 174.8,123.26 174.5,122.97 174.5,122.43 v2(174.12,122.05)
  L3SIG w0.203: J1.221 207.92,159.02 207.01,158.11 207.01,156.97 207.9,156.08 207.9,153.8 205.49,151.38 200.15,151.38 200.01,151.24 200.01,146.29 199.64,145.92 197.18,145.92 196.98,145.72 196.98,144.48 196.77,144.27 191.77,144.27 189.17,141.67 186.37,141.67 186.17,141.46 186.17,140.45 185.67,139.95 184.15,139.95 183.39,139.19 183.39,138.05 181.86,136.52 181.86,135.38 179.51,133.03 177.99,133.03 176.83,131.87 176.83,125.73
DDR_MDM7: length 73.2
  TOP w0.127: U1.AF24 175.37,121.65 175.71,121.99 177.8,121.99
  TOP w0.203: J1.230 216.92,156.97 216.15,156.21 216.15,155.19 216.66,154.69 216.66,151.64 215.52,150.5 209.37,150.5 209.17,150.29 209.17,149.94 209.37,149.73 210.38,149.73 210.58,149.53 210.58,149.11 210.44,148.97 198.63,148.97 193.67,144.02 193.67,136.78 191.01,134.11 183.77,134.11 179.58,129.92 179.58,123.73 177.83,121.99 177.8,121.99
DDR_MDM8: length 52.3
  TOP w0.127: U1.N24 v2(164.52,122.05)
  L6SIG w0.102: v2(164.52,122.05) 164.94,122.46 164.94,124.5 164.21,125.22 164.21,125.73
  L6SIG w0.203: J1.161 143.92,158.92 143.13,158.13 143.13,156.97 142.19,156.03 142.19,155.12 142.75,154.56 142.75,153.92 161.38,135.29 161.85,135.29 162.05,135.49 162.05,135.94 162.26,136.14 162.56,136.14 164.21,134.49 164.21,125.73
DDR_MDQS0_N: length 82.3
  TOP w0.102: 154.04,121.15 154.05,121.14 155.02,121.14 U1.A23
  TOP w0.178: J1.6 109.45,155.11 109.45,154.68 109.27,154.5 109.02,154.5 108.84,154.33 108.84,154.07 109.02,153.9 109.27,153.9 109.45,153.72 109.45,153.47 109.27,153.29 109.14,153.29 108.98,153.12 108.98,152.85 109.14,152.68 109.27,152.68 109.45,152.51 109.45,151.66 113.41,147.7 115.41,147.7 115.86,148.14 115.86,149.17 116.04,149.35 118.02,149.35 118.22,149.15 118.22,148.02 118.56,147.68 120.43,147.68 120.78,148.02 120.78,149.15 120.95,149.33 123.09,149.33 123.26,149.15 123.26,148.14 123.61,147.8 126.3,147.8 126.64,148.14 126.64,149.15 126.82,149.33 129.11,149.33 129.28,149.15 129.28,148.14 129.62,147.8 131.94,147.8 132.33,148.19 132.33,149.15 132.51,149.33 140.6,149.33 147.68,142.25 147.68,130.71 151.32,127.06 151.32,123.87 154.04,121.15
DDR_MDQS0_P: length 82.3
  TOP w0.102: U1.A24 155.02,121.35 154.24,121.35 154.2,121.39
  TOP w0.178: J1.7 109.73,157.36 109.73,151.78 113.53,147.98 115.3,147.98 115.58,148.26 115.58,149.29 115.92,149.63 118.13,149.63 118.5,149.26 118.5,148.13 118.68,147.95 120.32,147.95 120.5,148.13 120.5,149.26 120.84,149.61 123.2,149.61 123.54,149.26 123.54,148.26 123.72,148.08 126.19,148.08 126.37,148.26 126.37,149.26 126.71,149.61 129.22,149.61 129.56,149.26 129.56,148.26 129.74,148.08 131.83,148.08 132.05,148.31 132.05,149.26 132.4,149.61 140.72,149.61 147.95,142.37 147.95,130.82 151.6,127.18 151.6,123.99 154.2,121.39
DDR_MDQS1_N: length 69.3
  TOP w0.127: U1.D25 v2(157.32,122.85)
  L3SIG w0.102: v2(157.32,122.85) 156.9,123.26 156.9,123.98 156.59,124.28 156.59,124.76 156.58,124.77 156.58,124.8
  L3SIG w0.178: J1.15 118.11,157.35 118.11,155.19 118.49,154.81 118.49,152 118.97,151.52 125.66,151.52 125.79,151.39 125.79,150.71 125.61,150.53 123.1,150.53 122.76,150.19 122.76,149.22 123.12,148.85 125.55,148.85 125.73,148.68 125.73,144.08 126.07,143.74 140.41,143.74 145.16,138.99 145.16,137.03 154.41,127.79 154.41,127.28 156.58,125.11 156.58,124.8
DDR_MDQS1_P: length 69.4
  TOP w0.127: U1.D26 v2(157.32,123.65)
  L3SIG w0.102: 156.86,124.74 156.79,124.67 156.79,124.37 157.1,124.06 157.1,123.86 v2(157.32,123.65)
  L3SIG w0.178: 156.86,124.74 156.86,125.22 154.68,127.4 154.68,127.9 145.44,137.15 145.44,139.11 140.53,144.02 126.19,144.02 126.01,144.2 126.01,148.79 125.67,149.13 123.24,149.13 123.04,149.34 123.04,150.07 123.21,150.25 125.73,150.25 126.07,150.59 126.07,151.51 125.78,151.8 119.09,151.8 118.77,152.12 118.77,154.2 119.76,155.19 119.76,156.34 119.39,156.7 119.09,156.7 118.92,156.53 J1.16
DDR_MDQS2_N: length 66.6
  TOP w0.127: U1.G23 v2(159.72,121.25)
  L6SIG w0.102: 158.8,125.38 158.8,125.36 158.83,125.32 158.83,125.05 158.54,124.75 158.54,122.69 158.76,122.46 159.07,122.46 159.34,122.2 159.34,121.89 159.72,121.51 v2(159.72,121.25)
  L6SIG w0.178: J1.24 127.58,155.65 127.76,155.47 127.76,150.73 130.31,148.18 135.01,148.18 135.14,148.06 135.14,147.09 135.01,146.96 133.74,146.96 133.45,146.67 133.45,145.48 133.79,145.14 136.32,145.14 136.5,144.96 136.5,143.6 136.84,143.26 138.03,143.26 138.37,143.6 138.37,145.36 138.55,145.54 139.62,145.54 139.8,145.36 139.8,143.6 140.14,143.26 141.28,143.26 141.62,143.6 141.62,145.12 141.8,145.3 142.21,145.3 155.82,131.7 155.82,128.54 158.8,125.56 158.8,125.38
DDR_MDQS2_P: length 66.7
  TOP w0.127: U1.G24 v2(159.72,122.05)
  L6SIG w0.102: v2(159.72,122.05) 159.72,122.22 159.34,122.61 159.34,124.75 159.04,125.05 159.04,125.32 159.07,125.36 159.07,125.38
  L6SIG w0.178: 159.07,125.38 159.07,125.67 156.1,128.65 156.1,131.81 142.33,145.58 141.68,145.58 141.34,145.24 141.34,143.71 141.16,143.54 140.26,143.54 140.08,143.71 140.08,145.48 139.74,145.82 138.43,145.82 138.09,145.48 138.09,143.71 137.91,143.54 136.96,143.54 136.78,143.71 136.78,145.07 136.44,145.41 133.91,145.41 133.73,145.59 133.73,146.56 133.86,146.69 135.13,146.69 135.42,146.97 135.42,148.17 135.13,148.46 130.43,148.46 128.04,150.85 128.04,155.58 127.77,155.86 127.77,157.4 J1.25
DDR_MDQS3_N: length 56.9
  TOP w0.127: U1.K25 v2(162.12,122.85)
  L3SIG w0.102: v2(162.12,122.85) 162.54,123.26 162.54,123.93
  L3SIG w0.178: J1.33 136.14,157.32 136.14,156.57 135.76,156.19 135.76,153.91 136.5,153.17 136.5,151.92 137.2,151.22 145.71,151.22 147.09,149.83 147.58,149.83 148.28,150.54 148.53,150.54 149.28,149.8 149.28,149.54 148.51,148.78 148.51,148.29 149.32,147.48 149.8,147.48 150.57,148.25 150.82,148.25 151.58,147.49 151.58,147.23 150.94,146.59 150.94,146.11 156.21,140.84 156.21,138.45 160.79,133.87 160.79,129.8 162.28,128.31 162.28,125.23 162.69,124.83 162.69,124.08 162.54,123.93
DDR_MDQS3_P: length 56.8
  TOP w0.127: U1.L25 v2(162.92,122.85)
  L3SIG w0.102: 162.97,124.13 163.3,123.8 163.3,123.23 v2(162.92,122.85)
  L3SIG w0.178: J1.34 136.92,156.14 136.72,156.34 136.31,156.34 136.04,156.07 136.04,154.03 136.78,153.29 136.78,152.03 137.31,151.5 145.82,151.5 147.21,150.11 147.46,150.11 148.17,150.82 148.65,150.82 149.55,149.91 149.55,149.43 148.79,148.66 148.79,148.41 149.44,147.76 149.69,147.76 150.46,148.53 150.94,148.53 151.86,147.6 151.86,147.12 151.22,146.48 151.22,146.23 156.49,140.96 156.49,138.57 161.07,133.98 161.07,129.91 162.56,128.43 162.56,125.35 162.97,124.94 162.97,124.13
DDR_MDQS4_N: length 56.6
  TOP w0.127: U1.V25 v2(169.32,122.85)
  L3SIG w0.102: v2(169.32,122.85) 169.32,123.06 168.9,123.48 168.9,123.81 169.22,124.13 169.22,124.69 169.18,124.73 169.18,124.74
  L3SIG w0.178: J1.84 190.92,156.25 191.13,156.46 191.39,156.46 191.74,156.11 191.74,154.66 186.69,149.61 178.27,149.61 177.93,149.26 177.93,147.88 177.75,147.7 174.97,147.7 174.62,147.36 174.62,146.23 174.45,146.05 173.15,146.05 172.97,146.23 172.97,147.36 172.63,147.7 171.18,147.7 170.69,147.21 170.69,137.17 170.14,136.63 170.14,125.82 169.18,124.86 169.18,124.74
DDR_MDQS4_P: length 56.7
  TOP w0.127: U1.W25 v2(170.12,122.85)
  L3SIG w0.102: v2(170.12,122.85) 169.7,123.26 169.7,123.8 169.42,124.08 169.42,124.7 169.46,124.74
  L3SIG w0.178: 169.46,124.74 170.42,125.7 170.42,136.51 170.97,137.06 170.97,147.09 171.3,147.42 172.52,147.42 172.69,147.24 172.69,146.11 173.04,145.77 174.56,145.77 174.9,146.11 174.9,147.24 175.08,147.42 177.87,147.42 178.21,147.76 178.21,149.15 178.38,149.33 186.81,149.33 192.02,154.54 192.02,156.22 191.59,156.66 191.59,157.22 J1.85
DDR_MDQS5_N: length 65.3
  TOP w0.127: U1.Y23 v2(170.92,121.25)
  L6SIG w0.102: v2(170.92,121.25) 171.3,121.63 171.3,124.69 171.6,124.99 171.6,125.39 171.56,125.43 171.56,125.45
  L6SIG w0.178: J1.93 200.02,157.44 200.02,156.48 199.77,156.22 199.77,151.64 196.98,148.84 188.37,148.84 188.19,149.02 188.19,150.41 187.85,150.75 186.12,150.75 185.78,150.41 185.78,149.02 185.6,148.84 184.23,148.84 184.05,149.02 184.05,150.41 183.71,150.75 181.98,150.75 181.64,150.41 181.64,149.02 181.46,148.84 180.09,148.84 172.34,141.1 172.34,128.14 171.56,127.36 171.56,125.45
DDR_MDQS5_P: length 65.3
  TOP w0.127: U1.AA23 v2(171.72,121.25)
  L6SIG w0.102: 171.84,125.45 171.84,125.43 171.8,125.39 171.8,125 172.1,124.7 172.1,121.68 171.72,121.3 v2(171.72,121.25)
  L6SIG w0.178: 171.84,125.45 171.84,127.25 172.62,128.03 172.62,140.98 180.2,148.56 181.58,148.56 181.92,148.91 181.92,150.29 182.1,150.47 183.6,150.47 183.77,150.29 183.77,148.91 184.12,148.56 185.72,148.56 186.06,148.91 186.06,150.29 186.24,150.47 187.74,150.47 187.91,150.29 187.91,148.91 188.26,148.56 197.09,148.56 200.05,151.52 200.05,156.11 200.34,156.39 200.6,156.39 200.92,156.08 J1.94
DDR_MDQS6_N: length 65.6
  TOP w0.127: U1.AF25 v2(175.72,122.85)
  L3SIG w0.102: 177.21,123.61 177.19,123.6 177.19,123.58 176.24,122.63 175.93,122.63 v2(175.72,122.85)
  L3SIG w0.178: 177.21,123.61 177.93,124.33 177.93,129.92 183.67,135.66 186.19,135.66 187.17,136.64 187.17,139.55 188.6,140.97 192.66,140.97 193.04,140.59 193.04,139.19 193.27,138.96 194.39,138.96 194.56,139.14 194.56,142.53 194.91,142.88 198.07,142.88 198.25,143.05 198.25,144.06 198.61,144.42 201.18,144.42 201.4,144.64 201.4,149.67 201.74,150.01 205.77,150.01 209.8,154.05 209.8,156.58 209.54,156.84 209.04,156.84 208.66,156.46 208.66,155.9 J1.102
DDR_MDQS6_P: length 65.6
  TOP w0.127: U1.AE25 v2(174.92,122.85)
  L3SIG w0.102: 177.36,123.37 177.27,123.37 176.32,122.43 175.33,122.43 v2(174.92,122.85)
  L3SIG w0.178: J1.103 209.92,156.86 210.08,156.69 210.08,153.94 205.88,149.73 201.85,149.73 201.68,149.56 201.68,144.53 201.29,144.14 198.73,144.14 198.53,143.94 198.53,142.94 198.19,142.6 195.02,142.6 194.84,142.42 194.84,139.03 194.5,138.68 193.15,138.68 192.76,139.08 192.76,140.47 192.54,140.69 188.71,140.69 187.45,139.43 187.45,136.52 186.31,135.38 183.78,135.38 178.21,129.81 178.21,124.22 177.36,123.37
DDR_MDQS7_N: length 72.6
  TOP w0.102: 177.8,121.53 177.77,121.53 177.74,121.49 177.07,121.49 U1.AH24
  TOP w0.178: 177.8,121.53 178.3,121.53 180.34,123.57 180.34,129.54 183.77,132.97 191.01,132.97 194.94,136.91 194.94,143.51 198.25,146.81 200.46,146.81 200.81,146.46 201.75,146.46 201.93,146.63 201.93,147.49 202.27,147.83 203.76,147.83 204.1,147.49 204.1,146.63 204.27,146.46 205.54,146.46 205.71,146.63 205.71,147.49 206.06,147.83 207.41,147.83 207.75,147.49 207.75,146.63 207.92,146.46 209.09,146.46 209.27,146.63 209.27,147.49 209.61,147.83 214.74,147.83 217.78,150.86 217.78,155.68 218.31,156.21 218.31,157.15 J1.111
DDR_MDQS7_P: length 72.6
  TOP w0.102: 177.8,121.25 177.77,121.25 177.74,121.29 176.48,121.29 U1.AG24
  TOP w0.178: 177.8,121.25 178.41,121.25 180.62,123.46 180.62,129.42 183.88,132.69 191.12,132.69 195.22,136.79 195.22,143.39 198.36,146.53 200.34,146.53 200.7,146.18 201.87,146.18 202.21,146.52 202.21,147.37 202.39,147.55 203.64,147.55 203.82,147.37 203.82,146.52 204.16,146.18 205.65,146.18 205.99,146.52 205.99,147.37 206.17,147.55 207.29,147.55 207.47,147.37 207.47,146.52 207.81,146.18 209.21,146.18 209.55,146.52 209.55,147.37 209.73,147.55 214.86,147.55 218.06,150.75 218.06,155.56 218.33,155.83 218.74,155.83 218.92,155.65 J1.112
DDR_MDQS8_N: length 52.8
  TOP w0.127: U1.P23 v2(165.32,121.25)
  L6SIG w0.102: v2(165.32,121.25) 165.86,121.25 166.03,121.41 166.03,124.79 165.99,124.83 165.99,124.94
  L6SIG w0.178: 165.99,124.94 165.99,135.24 159.26,141.97 159.01,141.97 158.36,141.33 157.88,141.33 156.96,142.25 156.96,142.74 157.6,143.38 157.6,143.63 156.97,144.26 156.72,144.26 156.07,143.62 155.58,143.62 154.53,144.67 154.53,145.15 155.18,145.8 155.18,146.05 154.7,146.53 152.72,146.53 152.37,146.87 152.37,148.39 152.2,148.56 150.38,148.56 145.67,153.27 145.67,154.64 145.49,154.81 144.65,154.81 144.14,155.32 144.14,155.69 144.32,155.87 144.69,155.87 J1.42
DDR_MDQS8_P: length 52.8
  TOP w0.127: U1.R23 v2(166.92,121.25)
  L6SIG w0.102: v2(166.92,121.25) 166.4,121.25 166.23,121.41 166.23,124.88 166.27,124.92 166.27,124.94
  L6SIG w0.178: J1.43 145.67,157.3 145.67,155.07 145.95,154.79 145.95,153.39 150.5,148.84 152.31,148.84 152.65,148.5 152.65,146.99 152.83,146.81 154.81,146.81 155.46,146.16 155.46,145.68 154.81,145.03 154.81,144.78 155.69,143.9 155.96,143.9 156.6,144.54 157.08,144.54 157.88,143.75 157.88,143.26 157.24,142.62 157.24,142.37 158,141.61 158.25,141.61 158.89,142.25 159.37,142.25 166.27,135.36 166.27,124.94
DDR_MODT0: length 41.7
  TOP w0.127: U1.AD28 174.02,125.15 174.02,125.53 174.22,125.73
  TOP w0.216: J1.195 181.92,158.7 182.65,157.96 182.65,157.07 183.65,156.07 183.65,147.69 184.15,147.19 184.15,143.64 174.22,133.71 174.22,125.73
DDR_MODT1: length 41
  TOP w0.127: 175.42,125.73 175.42,125.55 174.88,125.01 174.88,124.41 U1.AE27
  TOP w0.216: J1.77 183.84,157.62 183.84,158.28 184.06,158.5 184.44,158.5 184.66,158.28 184.66,156.97 185.65,155.98 185.65,143.11 175.42,132.88 175.42,125.73
DDR_MRAS_N: length 40.3
  TOP w0.127: U1.AA28 171.32,125.73 171.22,125.83
  TOP w0.241: J1.192 178.92,158.72 178.69,158.5 178.69,157.1 177.67,156.08 177.67,150.81 177.91,150.56 178.7,150.56 178.94,150.32 178.94,149.84 178.7,149.6 177.91,149.6 177.67,149.36 177.67,145.67 178.31,145.03 178.31,142.88 171.22,135.79 171.22,125.83
DDR_MWE_N: length 40.1
  TOP w0.127: U1.AB27 172.52,124.45 172.52,125.05 172.42,125.15 172.42,125.73
  TOP w0.241: J1.73 179.92,151.68 180.47,151.13 180.47,148.81 180.23,148.57 179.95,148.57 179.7,148.33 179.7,147.85 179.95,147.61 180.23,147.61 180.47,147.37 180.47,146.88 180.23,146.64 179.95,146.64 179.7,146.4 179.7,145.92 179.95,145.68 180.23,145.68 180.47,145.44 180.47,144.95 180.23,144.71 179.95,144.71 179.7,144.47 179.7,143.99 179.95,143.75 180.23,143.75 180.47,143.51 180.47,143 172.42,134.96 172.42,125.73
DDR_REFCLK: length 82.8
  TOP w0.127: R517.2 R518.2 v1(90.29,109.97) ; U1.J21 v2(161.32,119.65)
  BOTTOM w0.127: v2(161.32,119.65) 160.64,119.65 160.12,120.17 160.12,120.6 159.87,120.85 155.31,120.85 152.33,123.83 140.21,123.83 135.38,119 113.58,119 112.06,117.48 94.83,117.48 90.29,112.94 v1(90.29,109.97)
DDR_RST_N: length 133.4
  TOP w0.127: J1.168 152.03,160.56 R2.2 103.89,163.19 101.85,161.16 101.85,151.26 97.03,146.43 97.03,144.91 95.63,143.51 74.42,143.51 70.12,139.21 70.12,126.25 59.05,115.19 58.46,115.19 58.02,114.74 U65.A2
DDRPWR_EN: length 391.2
  TOP w0.127: U65.P4 v1(59.52,100.43) ; v1(225.62,133.67) 225.62,139 226.83,140.22 U81.7
  L6SIG w0.102: v1(59.52,100.43) 60.01,99.93 60.01,98.36 68.71,89.66 68.71,85.09 70.61,83.19 70.61,78.61 72.39,76.84 75.82,76.84 77.09,75.57 93.6,75.57 94.36,74.8 153.29,74.8 154,75.51 177.34,75.51 182.37,70.48 208.36,70.48 214.97,77.09 226.44,77.09 228.35,78.99 274.28,78.99 278,82.72 278,143.51 276.35,145.16 276.35,148.84 272.54,152.65 269.75,152.65 267.59,154.81 259.27,154.81 248.95,144.49 246.6,144.49 243.08,140.97 243.08,133.98 239.39,130.3 228.98,130.3 v1(225.62,133.67)
DDRPWR_EN_N: length 485.5
  TOP w0.127: v1(60.51,99.42) 60.02,99.92 U65.R4 ; R785.1 v1(204.72,128.52)
  L6SIG w0.102: v1(204.72,128.52) 205.23,129.03 214.88,129.03 215.9,130.05 239.52,130.05 243.33,133.86 243.33,140.72 246.79,144.18 249.02,144.18 259.4,154.56 267.46,154.56 269.62,152.4 272.29,152.4 276.1,148.59 276.1,145.03 277.75,143.38 277.75,82.83 274.17,79.25 228.22,79.25 226.31,77.34 214.86,77.34 208.26,70.74 182.5,70.74 177.47,75.77 153.93,75.77 153.22,75.06 94.49,75.06 93.73,75.82 77.22,75.82 75.95,77.09 72.52,77.09 70.87,78.74 70.87,83.31 68.96,85.22 68.96,89.79 60.51,98.24 v1(60.51,99.42) ; v1(100.71,148.21) 97.41,144.91 69.98,144.91 69.47,144.4 69.47,140.72 70.48,139.7 70.48,116.97 66.42,112.9 63.99,112.9 v1(63.51,112.43)
  BOTTOM w0.127: v1(100.71,148.21) 101.35,147.57 R948.1 ; v1(60.51,99.42) 60.51,100.14 60.01,100.65 60.01,103.95 59.44,104.52 59.44,108.84 63.03,112.43 v1(63.51,112.43)
DIFSYSCLK_OE_N: length 382.4
  TOP w0.127: U97.38 233.57,135.91 232.92,135.25 232.92,134.49 233.17,134.24 v1(233.17,133.98) R844.2 ; U65.N15 71.02,101.93 71.52,101.42 72.31,101.42 73.41,100.33 73.41,97.66 72.39,96.65 70.75,96.65 65.52,91.41 v1(65.12,91.41)
  L6SIG w0.102: v1(65.12,91.41) 65.12,89.19 68.2,86.11 68.2,84.84 70.1,82.93 70.1,78.36 72.14,76.33 75.57,76.33 76.84,75.06 93.34,75.06 94.11,74.3 153.43,74.3 154.19,75.06 177.04,75.06 182.12,69.98 208.57,69.98 215.18,76.58 226.69,76.58 228.6,78.49 274.49,78.49 278.48,82.47 278.48,143.8 276.86,145.41 276.86,152.65 273.43,156.08 259.78,156.08 248.73,145.03 246.13,145.03 242.19,141.1 234.31,141.1 232.16,138.94 232.16,135 v1(233.17,133.98)
EARTH: length 603.3
  TOP w0.508: 114.24,16.32 J41.12 ; J41.12 116.93,16.32 ; J41.12 116.93,13.63 ; J41.12 114.24,13.63 ; 101.1,16.32 J41.11 ; J41.11 103.79,13.63 ; J41.11 101.1,13.63 ; J41.11 103.79,16.32 ; J13.20 149.72,14.2 ; J13.20 149.72,16.11 ; J13.20 147.81,16.11 ; J13.20 147.81,14.2 ; J13.22 150.48,5.7 ; J13.22 148.57,5.7 ; J13.22 148.57,3.79 ; J13.22 150.48,3.79 ; J50.20 183.68,12.64 ; J50.20 181.77,12.64 ; J50.20 181.77,10.73 ; J50.20 183.68,10.73 ; 166.69,10.13 J14.26 ; J14.26 166.69,12.04 ; J14.26 168.6,12.04 ; J14.26 168.6,10.13 ; 132.32,19.41 J13.19 ; J13.19 132.32,17.5 ; J13.19 134.23,19.41 ; J13.19 134.23,17.5 ; J50.21 201.26,12.64 ; J50.21 201.26,10.73 ; J50.21 199.35,12.64 ; J50.21 199.35,10.73 ; J14.25 152.34,10.13 ; J14.25 150.43,10.13 ; J14.25 150.43,12.04 ; J14.25 152.34,12.04 ; 166.69,20.42 J14.28 ; J14.28 168.6,20.42 ; J14.28 168.6,18.51 ; J14.28 166.69,18.51 ; 150.43,18.51 J14.27 ; J14.27 152.34,20.42 ; J14.27 152.34,18.51 ; 250.15,12.64 J56.21 ; J56.21 250.15,10.73 ; J56.21 252.06,10.73 ; J56.21 252.06,12.64 ; J41.9 103.79,10.64 ; J41.9 101.1,7.95 ; J41.9 101.1,10.64 ; J41.9 103.79,7.95 ; 131.56,5.7 J13.21 ; J13.21 131.56,3.79 ; J13.21 133.47,5.7 ; J13.21 133.47,3.79 ; 114.24,10.64 J41.10 ; J41.10 116.93,7.95 ; J41.10 114.24,7.95 ; J41.10 116.93,10.64 ; 148.57,21.7 J13.18 ; J13.18 148.57,19.79 ; J13.18 150.48,21.7 ; 232.57,12.64 J56.20 ; J56.20 232.57,10.73 ; J56.20 234.48,10.73 ; J56.20 234.48,12.64
  L2GND w0.508: 101.1,16.32 J41.11 ; J41.11 103.79,13.63 ; J41.11 103.79,16.32 ; J41.11 101.1,13.63 ; J14.26 168.6,12.04 ; J14.26 166.69,12.04 ; J14.26 166.69,10.13 ; J14.26 168.6,10.13 ; J41.9 103.79,10.64 ; J41.9 101.1,10.64 ; J41.9 101.1,7.95 ; J41.9 103.79,7.95 ; J13.19 134.23,19.41 ; J13.19 132.32,19.41 ; J13.19 134.23,17.5 ; J13.19 132.32,17.5 ; J41.12 116.93,16.32 ; J41.12 114.24,13.63 ; J41.12 114.24,16.32 ; J41.12 116.93,13.63 ; J50.21 201.26,10.73 ; J50.21 199.35,10.73 ; J50.21 199.35,12.64 ; J50.21 201.26,12.64 ; 232.57,12.64 J56.20 ; J56.20 232.57,10.73 ; J56.20 234.48,12.64 ; J56.20 234.48,10.73 ; 166.69,18.51 J14.28 ; J14.28 168.6,20.42 ; J14.28 166.69,20.42 ; J14.28 168.6,18.51 ; J14.25 152.34,12.04 ; J14.25 150.43,12.04 ; J14.25 150.43,10.13 ; J14.25 152.34,10.13 ; 131.56,3.79 J13.21 ; J13.21 133.47,5.7 ; J13.21 133.47,3.79 ; J13.21 131.56,5.7 ; J56.21 252.06,12.64 ; J56.21 250.15,12.64 ; J56.21 252.06,10.73 ; J56.21 250.15,10.73 ; 150.43,18.51 J14.27 ; J14.27 152.34,18.51 ; J14.27 152.34,20.42 ; 148.57,19.79 J13.18 ; J13.18 150.48,21.7 ; J13.18 148.57,21.7 ; 148.57,3.79 J13.22 ; J13.22 150.48,3.79 ; J13.22 148.57,5.7 ; J13.22 150.48,5.7 ; J13.20 149.72,16.11 ; J13.20 149.72,14.2 ; J13.20 147.81,16.11 ; J13.20 147.81,14.2 ; J41.10 116.93,7.95 ; J41.10 116.93,10.64 ; J41.10 114.24,7.95 ; J41.10 114.24,10.64 ; J50.20 183.68,12.64 ; J50.20 183.68,10.73 ; J50.20 181.77,10.73 ; J50.20 181.77,12.64
  L4PWR w0.508: J13.19 134.23,19.41 ; J13.19 132.32,17.5 ; J13.19 134.23,17.5 ; J13.19 132.32,19.41 ; J41.11 103.79,16.32 ; J41.11 101.1,16.32 ; J41.11 101.1,13.63 ; J41.11 103.79,13.63 ; 150.43,18.51 J14.27 ; J14.27 152.34,18.51 ; J14.27 152.34,20.42 ; 131.56,3.79 J13.21 ; J13.21 133.47,5.7 ; J13.21 133.47,3.79 ; J13.21 131.56,5.7 ; J14.28 168.6,18.51 ; J14.28 168.6,20.42 ; J14.28 166.69,18.51 ; J14.28 166.69,20.42 ; J14.26 168.6,12.04 ; J14.26 166.69,10.13 ; J14.26 168.6,10.13 ; J14.26 166.69,12.04 ; 232.57,12.64 J56.20 ; J56.20 234.48,10.73 ; J56.20 232.57,10.73 ; J56.20 234.48,12.64 ; J50.21 201.26,12.64 ; J50.21 199.35,10.73 ; J50.21 201.26,10.73 ; J50.21 199.35,12.64 ; J41.9 103.79,10.64 ; J41.9 101.1,10.64 ; J41.9 103.79,7.95 ; J41.9 101.1,7.95 ; J13.18 150.48,21.7 ; J13.18 148.57,21.7 ; J13.18 148.57,19.79 ; 114.24,13.63 J41.12 ; J41.12 116.93,16.32 ; J41.12 114.24,16.32 ; J41.12 116.93,13.63 ; 181.77,10.73 J50.20 ; J50.20 181.77,12.64 ; J50.20 183.68,10.73 ; J50.20 183.68,12.64 ; 147.81,16.11 J13.20 ; J13.20 147.81,14.2 ; J13.20 149.72,14.2 ; J13.20 149.72,16.11 ; 148.57,3.79 J13.22 ; J13.22 148.57,5.7 ; J13.22 150.48,5.7 ; J13.22 150.48,3.79 ; 150.43,10.13 J14.25 ; J14.25 152.34,12.04 ; J14.25 152.34,10.13 ; J14.25 150.43,12.04 ; 250.15,12.64 J56.21 ; J56.21 252.06,10.73 ; J56.21 250.15,10.73 ; J56.21 252.06,12.64 ; J41.10 116.93,7.95 ; J41.10 114.24,7.95 ; J41.10 114.24,10.64 ; J41.10 116.93,10.64
  L5PWR w0.508: 148.57,5.7 J13.22 ; J13.22 150.48,3.79 ; J13.22 150.48,5.7 ; J13.22 148.57,3.79 ; J13.20 149.72,16.11 ; J13.20 147.81,14.2 ; J13.20 147.81,16.11 ; J13.20 149.72,14.2 ; 101.1,13.63 J41.11 ; J41.11 101.1,16.32 ; J41.11 103.79,13.63 ; J41.11 103.79,16.32 ; 199.35,12.64 J50.21 ; J50.21 201.26,12.64 ; J50.21 199.35,10.73 ; J50.21 201.26,10.73 ; 181.77,10.73 J50.20 ; J50.20 183.68,10.73 ; J50.20 183.68,12.64 ; J50.20 181.77,12.64 ; 101.1,10.64 J41.9 ; J41.9 103.79,7.95 ; J41.9 101.1,7.95 ; J41.9 103.79,10.64 ; 150.43,12.04 J14.25 ; J14.25 152.34,12.04 ; J14.25 152.34,10.13 ; J14.25 150.43,10.13 ; 132.32,17.5 J13.19 ; J13.19 134.23,17.5 ; J13.19 134.23,19.41 ; J13.19 132.32,19.41 ; 232.57,12.64 J56.20 ; J56.20 234.48,10.73 ; J56.20 232.57,10.73 ; J56.20 234.48,12.64 ; J56.21 252.06,12.64 ; J56.21 252.06,10.73 ; J56.21 250.15,10.73 ; J56.21 250.15,12.64 ; 166.69,18.51 J14.28 ; J14.28 168.6,18.51 ; J14.28 168.6,20.42 ; J14.28 166.69,20.42 ; J41.10 116.93,10.64 ; J41.10 114.24,7.95 ; J41.10 116.93,7.95 ; J41.10 114.24,10.64 ; J14.27 152.34,20.42 ; J14.27 152.34,18.51 ; J14.27 150.43,18.51 ; 131.56,5.7 J13.21 ; J13.21 133.47,3.79 ; J13.21 133.47,5.7 ; J13.21 131.56,3.79 ; 114.24,13.63 J41.12 ; J41.12 116.93,13.63 ; J41.12 116.93,16.32 ; J41.12 114.24,16.32 ; J13.18 150.48,21.7 ; J13.18 148.57,19.79 ; J13.18 148.57,21.7 ; J14.26 168.6,10.13 ; J14.26 166.69,12.04 ; J14.26 168.6,12.04 ; J14.26 166.69,10.13
  L7GND w0.508: 114.24,10.64 J41.10 ; J41.10 114.24,7.95 ; J41.10 116.93,7.95 ; J41.10 116.93,10.64 ; J13.19 134.23,19.41 ; J13.19 132.32,17.5 ; J13.19 132.32,19.41 ; J13.19 134.23,17.5 ; J14.27 152.34,18.51 ; J14.27 152.34,20.42 ; J14.27 150.43,18.51 ; 101.1,10.64 J41.9 ; J41.9 101.1,7.95 ; J41.9 103.79,7.95 ; J41.9 103.79,10.64 ; 131.56,5.7 J13.21 ; J13.21 133.47,5.7 ; J13.21 131.56,3.79 ; J13.21 133.47,3.79 ; 166.69,18.51 J14.28 ; J14.28 168.6,20.42 ; J14.28 168.6,18.51 ; J14.28 166.69,20.42 ; 199.35,10.73 J50.21 ; J50.21 201.26,10.73 ; J50.21 199.35,12.64 ; J50.21 201.26,12.64 ; 181.77,12.64 J50.20 ; J50.20 183.68,12.64 ; J50.20 183.68,10.73 ; J50.20 181.77,10.73 ; 148.57,5.7 J13.22 ; J13.22 150.48,5.7 ; J13.22 148.57,3.79 ; J13.22 150.48,3.79 ; 250.15,12.64 J56.21 ; J56.21 250.15,10.73 ; J56.21 252.06,10.73 ; J56.21 252.06,12.64 ; J41.12 116.93,13.63 ; J41.12 116.93,16.32 ; J41.12 114.24,16.32 ; J41.12 114.24,13.63 ; J13.18 150.48,21.7 ; J13.18 148.57,21.7 ; J13.18 148.57,19.79 ; J41.11 103.79,16.32 ; J41.11 103.79,13.63 ; J41.11 101.1,13.63 ; J41.11 101.1,16.32 ; 166.69,12.04 J14.26 ; J14.26 168.6,12.04 ; J14.26 166.69,10.13 ; J14.26 168.6,10.13 ; J56.20 234.48,12.64 ; J56.20 234.48,10.73 ; J56.20 232.57,10.73 ; J56.20 232.57,12.64 ; J13.20 149.72,14.2 ; J13.20 147.81,16.11 ; J13.20 149.72,16.11 ; J13.20 147.81,14.2 ; J14.25 152.34,10.13 ; J14.25 152.34,12.04 ; J14.25 150.43,12.04 ; J14.25 150.43,10.13
  BOTTOM w0.508: J14.28 168.6,18.51 ; J14.28 168.6,20.42 ; J14.28 166.69,20.42 ; J14.28 166.69,18.51 ; J14.27 152.34,18.51 ; J14.27 150.43,18.51 ; J14.27 152.34,20.42 ; v1(168.66,32.77) 167.92,32.77 C310.2 167.74,33.66 v1(168.66,33.66) ; 199.35,12.64 J50.21 ; J50.21 199.35,10.73 ; J50.21 201.26,10.73 ; J50.21 201.26,12.64 ; J41.12 116.93,16.32 ; J41.12 114.24,13.63 ; J41.12 116.93,13.63 ; 150.43,10.13 J14.25 ; J14.25 152.34,10.13 ; J14.25 150.43,12.04 ; J14.25 152.34,12.04 ; J13.19 134.23,19.41 ; J13.19 132.32,19.41 ; J13.19 134.23,17.5 ; J13.19 132.32,17.5 ; v1(138.3,32.77) 137.44,32.77 C334.2 137.39,32 v1(138.3,32) ; 101.1,10.64 J41.9 ; J41.9 103.79,10.64 ; J41.9 101.1,7.95 ; J41.9 103.79,7.95 ; 232.57,10.73 J56.20 ; J56.20 234.48,12.64 ; J56.20 232.57,12.64 ; J56.20 234.48,10.73 ; 166.69,10.13 J14.26 ; J14.26 168.6,12.04 ; J14.26 166.69,12.04 ; J14.26 168.6,10.13 ; 181.77,12.64 J50.20 ; J50.20 183.68,12.64 ; J50.20 181.77,10.73 ; J50.20 183.68,10.73 ; J56.21 252.06,12.64 ; J56.21 252.06,10.73 ; J56.21 250.15,10.73 ; J56.21 250.15,12.64 ; 147.81,14.2 J13.20 ; J13.20 149.72,14.2 ; J13.20 147.81,16.11 ; J13.20 149.72,16.11 ; J41.10 116.93,10.64 ; J41.10 114.24,10.64 ; J41.10 116.93,7.95 ; J41.10 114.24,7.95 ; 148.57,3.79 J13.22 ; J13.22 150.48,5.7 ; J13.22 150.48,3.79 ; J13.22 148.57,5.7 ; J13.18 150.48,21.7 ; J13.18 148.57,19.79 ; J13.18 148.57,21.7 ; 131.56,5.7 J13.21 ; J13.21 133.47,5.7 ; J13.21 133.47,3.79 ; J13.21 131.56,3.79 ; J41.11 103.79,13.63 ; J41.11 101.1,16.32 ; J41.11 101.1,13.63 ; J41.11 103.79,16.32 ; J13.17 133.47,23.85 ; J13.17 131.56,25.76 ; J13.17 131.56,23.85 ; J13.17 133.47,25.76 ; v1(153.42,31.12) 153.42,31.6 C302.2 152.91,32 152.4,31.5 v1(152.4,31.12)
  BOTTOM w1.016: C336.2 C334.2
  BOTTOM w1.27: C342.2 C302.2
  vias: v1(137.92,27.81) v1(139.06,32.38) v1(140.33,27.81) v1(141.99,26.8) v1(142.11,31.24) v1(145.03,31.24) v1(145.41,26.8) v1(148.08,31.24) v1(149.22,28.7) v1(151.89,27.18) v1(152.91,30.48) v1(154.56,19.81) v1(155.07,14.73) v1(156.21,12.83) v1(156.34,22.35) v1(157.1,19.81) v1(157.61,24.26) v1(157.99,31.24) v1(158.5,16) v1(158.88,12.19) v1(160.02,19.69) v1(161.04,31.24) v1(161.42,22.23) v1(161.54,16) v1(163.58,13.08) v1(163.7,19.18) v1(163.83,16) v1(163.96,31.24) v1(163.96,22.35) v1(166.24,23.49) v3(100.58,2.92) v3(107.06,2.92) v3(115.95,2.92) v3(126.75,2.92) v3(136.91,2.92) v3(145.8,2.92) v3(159.77,2.92) v3(173.1,2.92) v3(183.26,2.92) v3(192.15,2.92) v3(199.14,2.92) v3(209.93,2.92) v3(219.46,2.92) v3(230.25,2.92) v3(241.05,2.92) v3(251.21,2.92) v3(262,2.92) v3(272.16,2.92)
EC1_GTXCLK: length 74.7
  TOP w0.127: U49.22 139.84,51.95 139.88,51.99 140.38,51.99 141.22,52.83 v1(141.22,56.77)
  BOTTOM w0.127: R127.1 177.17,100.25 177.42,100.01 177.42,91.86 170.14,84.58 156.12,84.58 155.28,84.58 145.16,74.46 145.16,68.24 142.24,65.32 142.24,57.66 141.35,56.77 v1(141.22,56.77)
EC1_INT_N: length 75
  TOP w0.127: U1.AB4 v2(172.52,105.25) ; v1(172.47,97.03) 173.35,96.14 173.35,91.06 172.59,90.3 172.59,87.88 160.66,75.95 151.89,75.95 141.1,65.15 141.1,58.17 142.37,56.9 R250.2
  L3SIG w0.102: v1(172.47,97.03) 172.59,97.16 172.59,102.11 172.93,102.45 172.93,104.83 v2(172.52,105.25)
  BOTTOM w0.127: v2(172.52,105.25) 172.92,104.84 172.92,102.28 R71.1
EC1_LED0: length 5.5
  TOP w0.127: U49.34 134.87,53.98 134.75,54.1 134.75,54.48 134.11,55.12 132.33,55.12 131.96,55.49 R262.1 R247.1
EC1_LED1: length 6
  TOP w0.127: R248.1 R263.1 131.82,54.86 133.98,54.86 134.47,54.38 U49.35
EC1_MDI0_N: length 11.6
  TOP w0.102: U49.2 134.47,47.07 134.41,47.01 134.41,45.55 136.72,43.24 U50.1 138.5,43.24 139.06,42.67 139.06,41.22 139.64,40.64 T2.11
EC1_MDI0_P: length 11.6
  TOP w0.102: T2.12 138.64,39.87 138.91,40.13 139.19,40.13 139.37,40.31 139.37,40.52 138.55,41.34 U50.3 137.47,41.34 136.9,41.92 136.9,42.66 134.13,45.43 134.13,47.02 134.07,47.08 U49.1
EC1_MDI1_N: length 13
  TOP w0.102: U49.5 135.67,47.08 135.61,47.02 135.61,45.87 136.91,44.58 138.7,44.58 140.03,43.24 U50.6 141.16,43.24 141.61,42.79 141.61,41.65 142.28,40.98 142.28,39.96 142.64,39.6 T2.8
EC1_MDI1_P: length 13.1
  TOP w0.102: U49.4 135.27,47.08 135.33,47.02 135.33,45.76 136.79,44.3 138.58,44.3 139.95,42.93 139.95,41.61 140.22,41.34 U50.4 141.52,41.34 142.01,40.86 142.01,40.02 141.64,39.66 T2.9
EC1_MDI2_N: length 14.8
  TOP w0.102: T2.5 145.65,39.9 145.41,40.13 145.41,41.16 145.03,41.54 145.03,42.67 144.47,43.24 U51.1 143.2,43.24 141.99,44.45 140.21,44.45 139.19,45.47 137.54,45.47 136.81,46.2 136.81,47.02 136.87,47.08 U49.8
EC1_MDI2_P: length 14.9
  TOP w0.102: U49.7 136.47,47.09 136.53,47.03 136.53,46.08 137.43,45.19 139.08,45.19 140.09,44.17 141.87,44.17 142.88,43.17 142.88,42.04 143.57,41.34 U51.3 144.84,41.34 145.14,41.05 145.14,40.11 144.65,39.62 T2.6
EC1_MDI3_N: length 16.1
  TOP w0.102: U49.11 138.07,47.09 138.01,47.03 138.01,46.65 138.3,46.35 139.58,46.35 140.59,45.34 142.51,45.34 143.5,44.35 145.01,44.35 146.12,43.24 U51.6 147.13,43.24 147.7,42.67 147.7,41.54 148.11,41.14 148.11,40.23 148.65,39.7 T2.2
EC1_MDI3_P: length 16.1
  TOP w0.102: U49.10 137.67,47.09 137.73,47.03 137.73,46.53 138.19,46.08 139.46,46.08 140.48,45.06 142.39,45.06 143.38,44.07 144.89,44.07 146,42.96 146,41.58 146.24,41.34 U51.4 147.51,41.34 147.83,41.02 147.83,39.88 147.65,39.69 T2.3
EC1_MDX0_N: length 29.5
  TOP w0.102: v1(139.57,27.85) 139.28,28.13 139.28,29.03 139.64,29.39 T2.14
  L3SIG w0.102: v1(139.57,27.85) 139.28,27.57 139.28,26.97 139.97,26.29 146.69,26.29 148.82,24.16 149.96,24.16 153.8,20.32 153.8,15.24 155.32,13.72 155.7,13.72 156.34,14.36 J14.B2
EC1_MDX0_P: length 29.5
  TOP w0.102: T2.13 138.64,29.39 139.01,29.03 139.01,28.13 v1(138.72,27.85)
  L3SIG w0.102: v1(138.72,27.85) 139.01,27.57 139.01,26.86 139.85,26.01 146.57,26.01 148.7,23.88 149.85,23.88 153.52,20.2 153.52,15.12 155.32,13.32 155.32,12.48 J14.B1
EC1_MDX1_N: length 39.7
  TOP w0.102: v1(142.7,27.84) 142.42,27.56 142.03,27.56 141.92,27.66 141.92,28.93 142.03,29.03 142.28,29.03 142.64,29.39 T2.17
  L3SIG w0.102: J14.B6 161.92,14.26 161.92,13.18 161.82,13.08 161.18,13.08 160.27,13.98 160.27,15.81 160.68,16.22 160.68,16.36 160.54,16.5 160.39,16.5 159.96,16.08 159.82,16.08 159.68,16.22 159.68,16.36 160.1,16.79 160.1,16.93 159.96,17.08 159.82,17.08 159.39,16.65 159.24,16.65 159,16.89 159,19.18 157.73,20.45 157.73,22.1 157.1,22.73 157.1,25.53 155.93,26.7 149.34,26.7 147.33,28.7 143.88,28.7 143.48,28.31 143.48,27.78 143.27,27.56 142.98,27.56 v1(142.7,27.84)
EC1_MDX1_P: length 39.6
  TOP w0.102: v1(142.7,27) 142.42,27.28 141.91,27.28 141.64,27.54 T2.16
  L3SIG w0.102: v1(142.7,27) 142.98,27.28 143.38,27.28 143.76,27.66 143.76,28.19 143.99,28.42 147.22,28.42 149.22,26.42 155.81,26.42 156.82,25.41 156.82,22.62 157.45,21.98 157.45,20.33 158.72,19.06 158.72,16.78 159.99,15.51 159.99,13.87 161.16,12.7 161.16,11.68 160.66,11.18 158.66,11.18 J14.B3
EC1_MDX2_N: length 27.9
  TOP w0.102: v1(144.58,26.97) 144.91,27.3 145.38,27.3 145.65,27.57 T2.20
  L3SIG w0.102: v1(144.58,26.97) 144.91,27.3 146.81,27.3 148.97,25.15 150.08,25.15 156.18,19.04 156.18,16.9 157.45,15.63 157.45,13.85 158.23,13.08 159.3,13.08 J14.B5
EC1_MDX2_P: length 27.9
  TOP w0.102: T2.19 144.65,29.47 145.08,29.03 145.26,29.03 145.37,28.93 145.37,27.69 145.26,27.58 144.81,27.58 v1(144.58,27.81)
  L3SIG w0.102: J14.B4 159.26,14.39 159.26,13.59 159.03,13.36 158.34,13.36 157.73,13.97 157.73,15.75 156.46,17.02 156.46,19.16 150.2,25.43 149.09,25.43 146.93,27.58 144.81,27.58 v1(144.58,27.81)
EC1_MDX3_N: length 29.1
  TOP w0.102: T2.23 148.65,29.39 148.28,29.03 148.28,28.39 148.71,27.97 149.66,27.97 v1(149.94,28.25)
  L3SIG w0.102: v1(149.94,28.25) 149.94,28.24 150.24,27.94 157.24,27.94 160.3,24.88 160.3,20.44 161.57,19.17 161.57,17.39 162.84,16.12 162.84,14.2 163.19,13.84 163.7,13.84 163.96,14.1 J14.B8
EC1_MDX3_P: length 29.2
  TOP w0.102: T2.22 147.65,29.39 148.01,29.03 148.01,28.27 148.59,27.69 149.66,27.69 v1(149.94,27.41)
  L3SIG w0.102: J14.B7 162.81,12.35 162.81,13.83 162.56,14.08 162.56,16 161.29,17.27 161.29,19.05 160.02,20.32 160.02,24.77 157.12,27.66 150.19,27.66 v1(149.94,27.41)
EC1_PME_N: length 199.8
  TOP w0.127: R251.2 134.49,57.4 135.64,58.55 138.18,58.55 140.59,60.96 140.59,65.15 151.76,76.33 160.53,76.33 172.21,88.01 172.21,90.81 v1(172.59,91.19) ; U1.AC5 v2(173.32,106.05) ; U65.P13 v1(69.52,100.42)
  L3SIG w0.102: v2(173.32,106.05) 173.32,105.07 173.73,104.65 173.73,99.82 173.35,99.44 v1(173.35,97.03) 173.35,91.95 v1(172.59,91.19)
  L6SIG w0.102: v1(69.52,100.42) 70.02,99.92 70.02,97.49 70.74,96.77 75.44,96.77 77.09,95.12 77.09,88.9 79.12,86.87 83.31,86.87 84.71,85.47 87.12,85.47 90.93,81.66 116.2,81.66 118.75,79.12 143.38,79.12 154.94,90.68 165.86,90.68 168.4,88.14 170.56,88.14 172.59,90.17 v1(172.59,91.19)
  BOTTOM w0.127: v1(173.35,97.03) 173.1,97.28 R72.1
EC1_REFCLK: length 97.3
  TOP w0.127: v1(179.96,103.12) 177.28,103.12 176.53,103.88 176.53,104.43 U1.AG3 ; v1(127.76,48.64) R246.2
  BOTTOM w0.127: v1(179.96,103.12) 179.96,100.97 178.44,99.44 178.44,91.44 170.56,83.57 155.7,83.57 146.18,74.04 146.18,67.82 143.26,64.9 143.26,57.15 141.86,55.75 137.67,55.75 137.16,56.26 132.84,56.26 131.32,54.74 131.32,53.21 130.81,52.71 130.81,50.55 128.91,48.64 v1(127.76,48.64)
EC1_RST_N: length 120.3
  TOP w0.127: v1(58.51,106.43) 59.01,106.93 U65.H3 ; v1(135.89,57.66) 136.39,57.66 R252.2 R249.1
  L6SIG w0.102: v1(135.89,57.66) 135.89,61.47 127.89,69.47 93.22,69.47 91.41,71.27 74.96,71.27 73.72,72.52 69.47,72.52 65.53,76.45 65.53,80.9 64.39,82.04 64.39,84.2 54.61,93.98 54.61,104.27 56.27,105.93 58.01,105.93 v1(58.51,106.43)
EC1_RXCLK: length 79.9
  TOP w0.127: R238.1 144.78,51.18 145.03,51.43 v1(145.03,53.09) ; U1.AD1 173.72,102.25 176.66,99.31 v1(179.2,99.31)
  BOTTOM w0.127: v1(145.03,53.09) 144.27,53.85 144.27,56.01 144.02,56.26 144.02,64.66 146.94,67.58 146.94,68 146.94,73.68 156.13,82.87 170.78,82.87 173.09,85.17 179.07,91.16 179.07,96.15 179.2,96.28 v1(179.2,99.31)
EC1_RXCTL: length 89.7
  TOP w0.127: v1(147.57,52.32) 147.57,48.77 145.41,46.61 143.64,46.61 143.39,46.36 R261.1 R245.1 ; v1(180.72,102.62) 177.3,102.62 176.12,103.8 U1.AG2
  BOTTOM w0.127: v1(147.57,52.32) 147.57,52.45 148.08,52.96 148.08,54.23 146.94,55.37 146.94,60.71 147.38,61.15 147.38,62.81 149.73,65.16 149.73,73.24 157.07,80.58 158.18,80.58 171.73,80.58 181.11,89.96 181.11,89.97 181.36,90.21 181.36,95.2 181.61,95.46 181.61,101.73 v1(180.72,102.62)
EC1_RXD0: length 89
  TOP w0.127: v1(147.07,53.09) 147.07,49.25 145.44,47.62 143.51,47.62 143.39,47.51 R257.1 R239.1 ; v1(180.72,101.85) 176.78,101.85 175.77,102.87 175.77,103.59 U1.AF2
  BOTTOM w0.127: v1(147.07,53.09) 147.07,53.72 146.18,54.61 146.18,56.77 145.92,57.02 145.92,60.45 146.94,61.47 146.94,63 149.29,65.35 149.29,73.42 156.89,81.03 171.55,81.03 180.67,90.15 180.91,90.39 180.91,95.39 181.17,95.64 181.17,101.41 v1(180.72,101.85)
EC1_RXD1: length 86.7
  TOP w0.127: v1(146.56,52.32) 146.56,49.66 145.54,48.64 143.64,48.64 143.39,48.39 R258.1 R242.1 ; v1(180.72,101.09) 180.47,101.35 176.66,101.35 175.32,102.69 U1.AF1
  BOTTOM w0.127: v1(180.72,101.09) 180.72,95.82 180.47,95.57 180.47,90.58 180.22,90.33 171.36,81.47 156.71,81.47 156.45,81.21 148.84,73.61 148.84,65.53 145.41,62.1 145.41,56.84 145.67,56.59 145.67,54.43 146.56,53.54 v1(146.56,52.32)
EC1_RXD2: length 85.2
  TOP w0.127: v1(180.21,100.33) 179.7,100.84 176.53,100.84 174.52,102.85 U1.AE1 ; v1(146.05,53.09) 146.05,50.16 145.54,49.66 143.64,49.66 143.39,49.41 R259.1 R243.1
  BOTTOM w0.127: v1(146.05,53.09) 146.05,53.42 145.22,54.24 145.22,56.4 144.97,56.66 144.97,63.31 148.4,66.74 148.4,73.79 156,81.39 156.52,81.92 171.18,81.92 179.78,90.52 180.02,90.76 180.02,95.75 180.21,95.95 v1(180.21,100.33)
EC1_RXD3: length 84.2
  TOP w0.127: v1(179.7,99.82) 176.91,99.82 174.12,102.62 174.12,103.63 173.72,104.03 U1.AD2 ; R244.1 R260.1 143.39,50.43 143.64,50.67 144.91,50.67 145.54,51.31 v1(145.54,52.32)
  BOTTOM w0.127: v1(145.54,52.32) 145.54,52.88 145.54,53.3 144.78,54.06 144.78,56.22 144.53,56.47 144.53,63.5 147.95,66.93 147.95,73.98 156.34,82.36 170.99,82.36 179.33,90.7 179.33,90.7 179.58,90.94 179.58,95.94 179.7,96.07 v1(179.7,99.82)
EC1_RXDLY: length 2.4
  TOP w0.127: U49.32 135.67,53.94 135.38,54.23 135.38,55.63 R264.1
EC1_TXCTL: length 75.8
  TOP w0.127: v1(138.68,56.26) 138.68,55.37 137.79,54.48 137.79,54.24 137.67,54.11 U49.27
  BOTTOM w0.127: v1(138.68,56.26) 141.6,56.26 142.75,57.4 142.75,65.11 145.67,68.03 145.67,74.25 155.49,84.07 155.91,84.07 170.35,84.07 177.93,91.65 177.93,100.33 178.44,100.84 178.82,100.84 179.2,101.22 R125.1
EC1_TXD0: length 73.9
  TOP w0.127: U49.23 140.1,52.35 140.72,52.96 v1(140.72,57.53)
  BOTTOM w0.127: R115.1 175.13,100.95 176.47,99.61 176.47,92.26 169.74,85.53 156.52,85.53 154.89,85.53 144.47,75.12 144.21,74.86 144.21,68.64 141.35,65.78 141.35,65.78 141.29,65.71 141.29,58.1 v1(140.72,57.53)
EC1_TXD1: length 73.5
  TOP w0.127: v1(140.21,56.77) 140.21,53.09 139.87,52.75 U49.24
  BOTTOM w0.127: v1(140.21,56.77) 140.59,56.77 141.73,57.91 141.73,65.53 141.99,65.78 141.99,65.79 144.65,68.45 144.65,74.67 155.07,85.09 156.33,85.09 169.93,85.09 176.91,92.07 176.91,99.8 176.15,100.56 R116.1
EC1_TXD2: length 72.3
  TOP w0.127: U49.25 138.47,53.98 138.6,54.1 138.81,54.1 139.7,54.99 139.7,58.04 v1(139.83,58.17)
  BOTTOM w0.127: R119.1 174.12,100.52 175.45,99.19 175.45,92.68 169.32,86.55 156.94,86.55 156.94,86.55 155.31,86.55 155.31,86.55 154.47,86.55 144.05,76.13 143.19,75.28 143.19,69.06 140.33,66.2 140.33,66.2 140.27,66.13 140.27,58.61 v1(139.83,58.17)
EC1_TXD3: length 69.5
  TOP w0.127: U49.26 138.07,54.12 139.19,55.24 v1(139.19,57.53)
  BOTTOM w0.127: R121.1 175.01,97.8 175.01,92.86 169.14,87 157.12,87 155.49,87 154.28,87 143.86,76.58 142.75,75.46 142.75,69.24 139.89,66.38 139.89,66.38 139.83,66.32 139.83,59.18 139.19,58.55 v1(139.19,57.53)
EC2_GTXCLK: length 86.5
  TOP w0.127: v1(163.32,52.58) 163.32,52.07 162.61,51.36 162.11,51.36 162.06,51.31 U46.22
  BOTTOM w0.127: R128.2 182.28,107.82 183.97,106.13 184.78,105.32 184.78,94.14 184.53,93.89 184.53,88.89 183.71,88.07 173.04,77.41 171.89,77.41 171.15,77.41 170.78,77.41 159.95,77.41 153.42,70.87 153.42,68.83 152.97,68.39 152.97,64.27 152.97,63.52 152.97,63.52 152.97,63.1 155.19,60.87 155.19,59.48 156.95,57.72 158.31,57.72 158.88,57.15 160.08,57.15 160.27,57.15 160.34,57.09 160.91,56.52 161.58,56.52 163.32,54.77 v1(163.32,52.58)
EC2_INT_N: length 70.5
  TOP w0.127: R221.2 166.62,52.32 v1(166.62,52.32) ; U1.L4 v2(162.92,105.25)
  L3SIG w0.102: v1(166.62,52.32) 162.56,56.39 156.08,56.39 155.65,56.82 155.65,57.48 156.08,57.91 156.08,68.4 158.37,70.68 158.37,72.14 163.58,77.34 v1(163.58,94.62) 163.19,95 163.19,100.58 164.11,101.5 164.11,104.64 163.89,104.87 163.56,104.87 163.18,105.25 v2(162.92,105.25)
  BOTTOM w0.127: R73.1 164.11,102.96 164.11,104.61 163.88,104.84 163.32,104.84 v2(162.92,105.25)
EC2_LED0: length 5.5
  TOP w0.127: U46.34 157.1,53.34 156.97,53.47 156.97,53.85 156.34,54.48 154.56,54.48 154.19,54.86 R233.1 R218.1
EC2_LED1: length 6
  TOP w0.127: U46.35 156.7,53.74 156.21,54.23 154.04,54.23 R234.1 R219.1
EC2_MDI0_N: length 11.8
  TOP w0.102: U46.2 156.7,46.43 156.64,46.37 156.64,45.13 155.68,44.17 153.79,44.17 153.57,43.95 153.57,43.34 153.86,43.05 154.47,43.05 U47.1 154.88,43.24 155.47,42.65 155.47,39.27 T1.11
EC2_MDI0_P: length 11.8
  TOP w0.102: T1.12 154.52,39.57 155.19,40.25 155.19,41.15 155,41.34 U47.3 153.86,41.34 153.29,41.91 153.29,44.07 153.67,44.45 155.56,44.45 156.36,45.25 156.36,46.39 156.3,46.45 U46.1
EC2_MDI1_N: length 9.3
  TOP w0.102: U46.5 157.9,46.44 157.84,46.38 157.84,44.87 156.74,43.77 156.74,43.41 156.91,43.24 U47.6 157.55,43.24 158.01,42.77 158.01,40.11 158.52,39.6 T1.8
EC2_MDI1_P: length 9.3
  TOP w0.102: U46.4 157.5,46.44 157.56,46.38 157.56,44.98 156.46,43.89 156.46,41.61 156.73,41.34 U47.4 157.54,41.34 157.73,41.15 157.73,39.75 157.52,39.54 T1.9
EC2_MDI2_N: length 9.8
  TOP w0.102: U46.8 159.1,46.45 159.04,46.39 159.04,45.32 159.66,44.69 159.66,43.15 159.89,42.93 160.44,42.93 U48.1 160.98,43.24 161.52,42.7 T1.5
EC2_MDI2_P: length 9.8
  TOP w0.102: U46.7 158.7,46.46 158.76,46.4 158.76,45.21 159.38,44.58 159.38,41.78 159.83,41.34 U48.3 161.06,41.34 161.24,41.16 161.24,40.34 160.52,39.62 T1.6
EC2_MDI3_N: length 9.9
  TOP w0.102: T1.2 164.34,39.4 164.34,40.91 164.09,41.15 164.09,42.66 163.51,43.24 U48.6 162.77,43.24 160.24,45.77 160.24,46.39 160.3,46.45 U46.11
EC2_MDI3_P: length 9.9
  TOP w0.102: T1.3 163.52,39.57 164.06,40.11 164.06,40.79 163.51,41.34 U48.4 163.13,41.34 162.56,41.91 162.56,43.05 159.96,45.66 159.96,46.39 159.9,46.45 U46.10
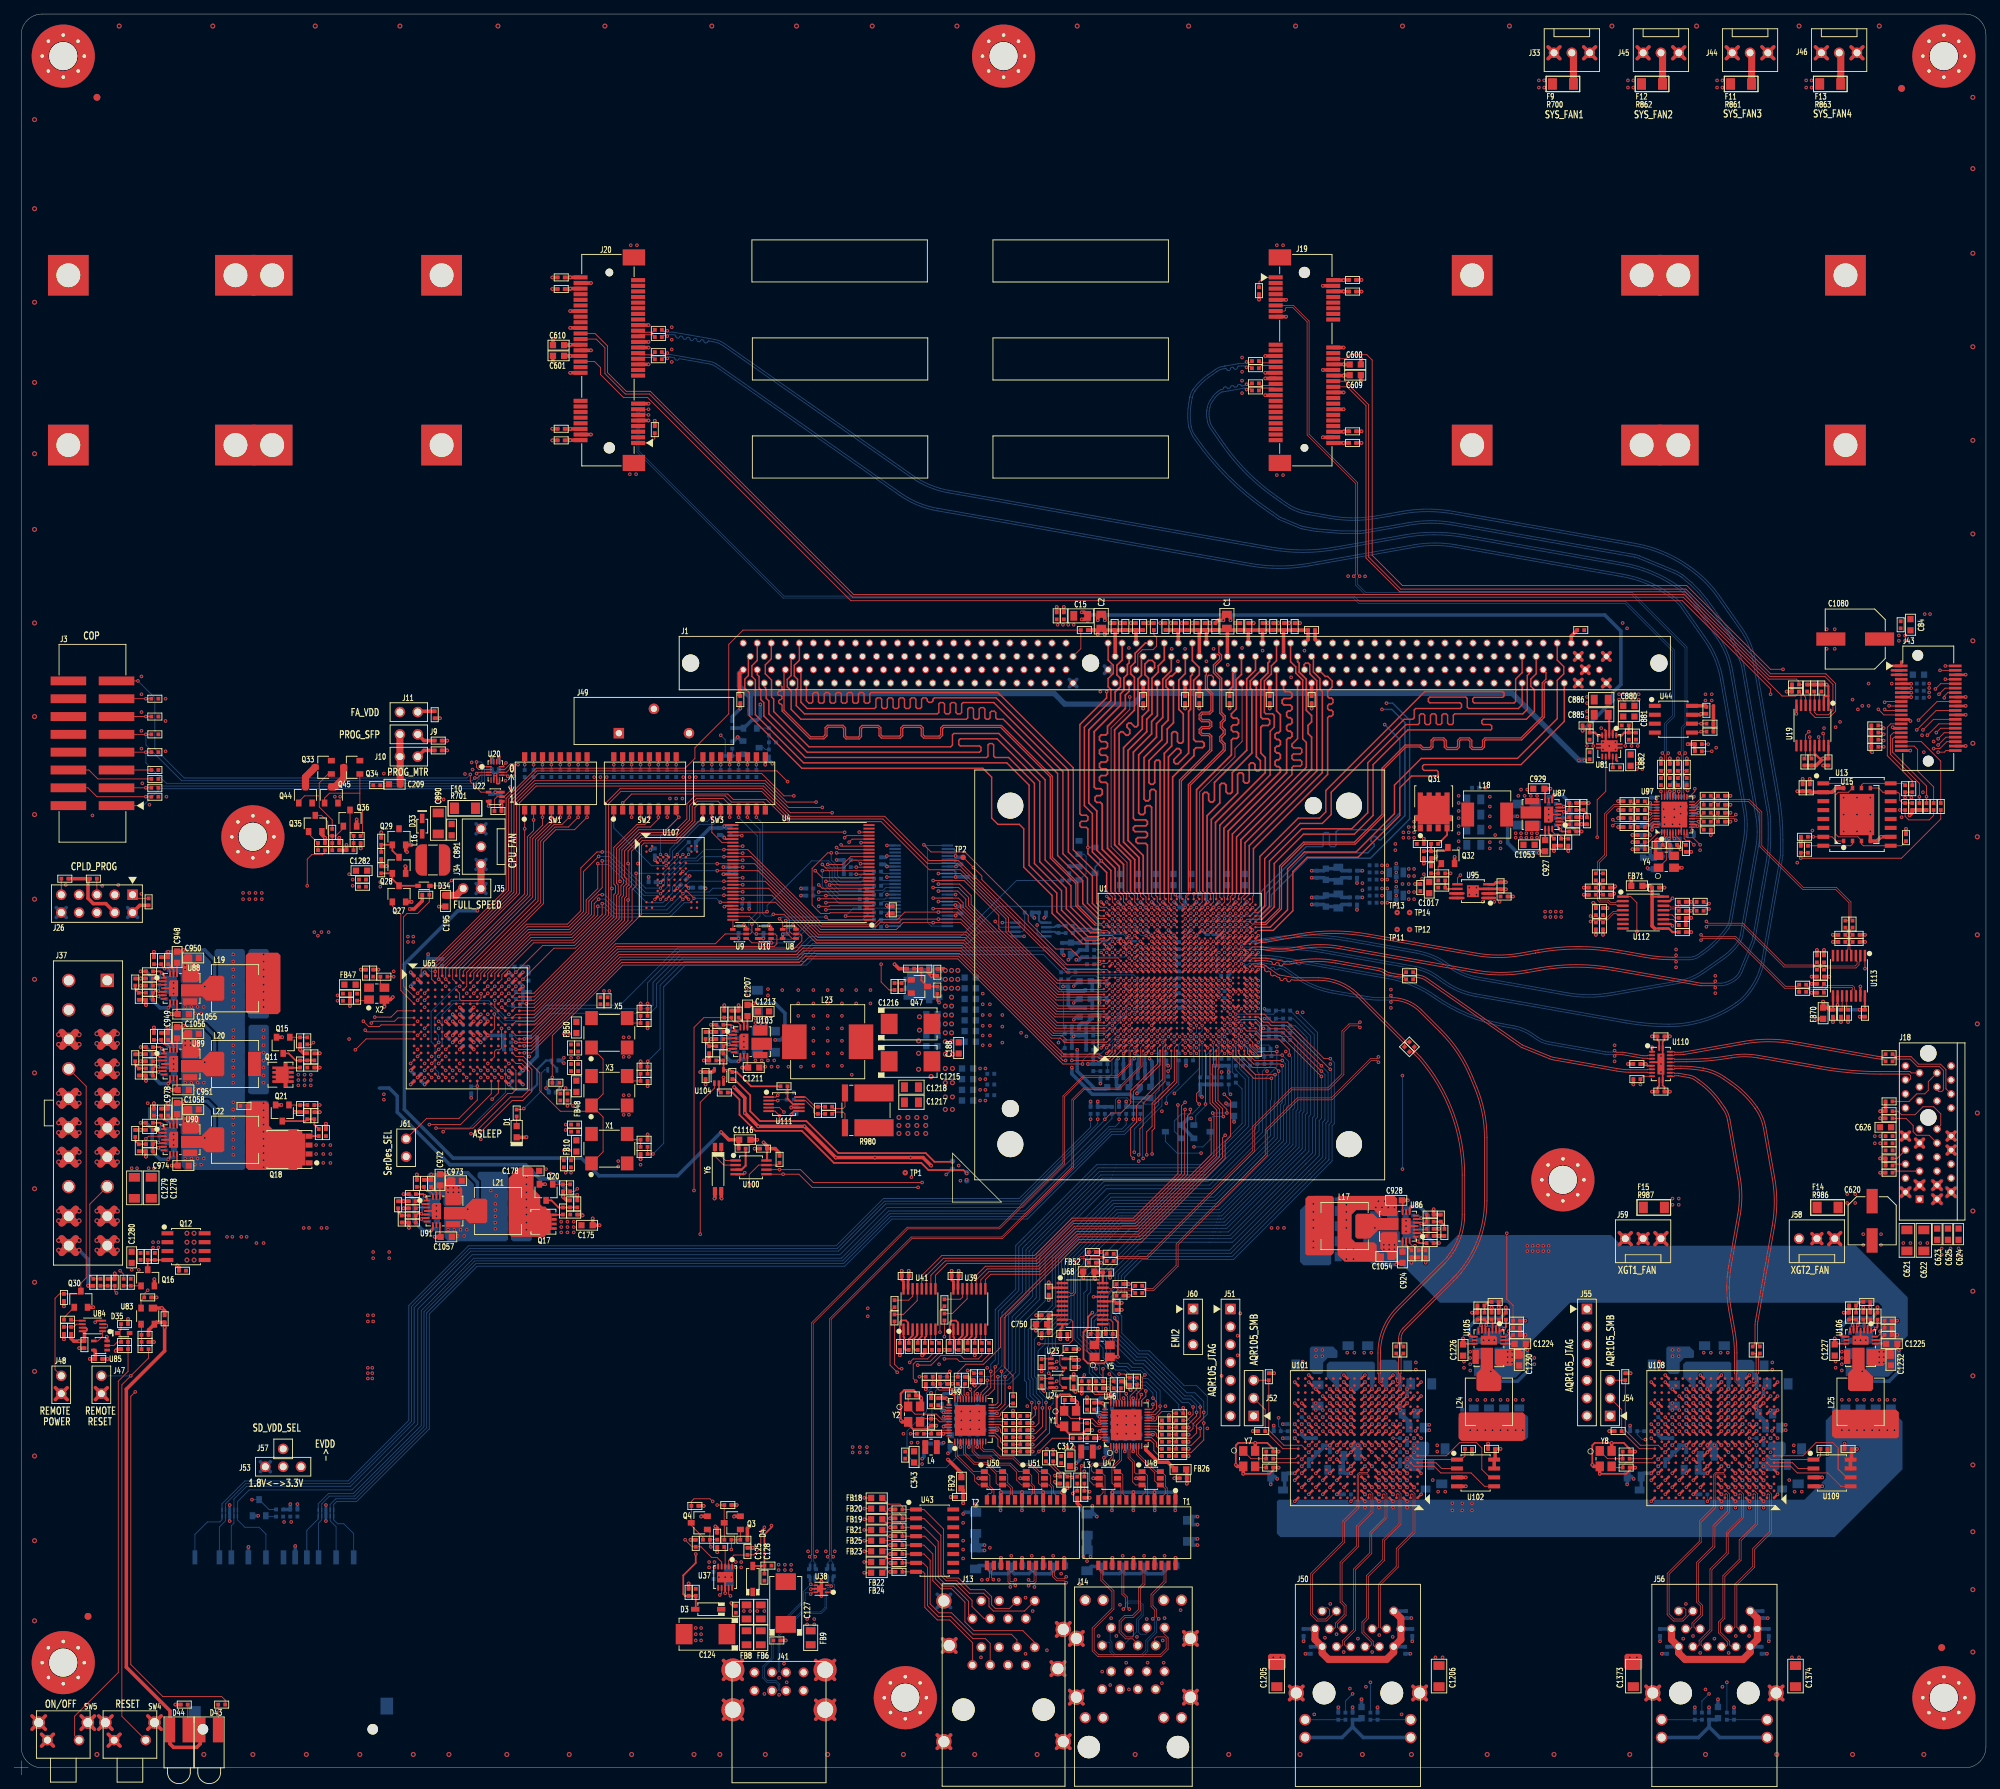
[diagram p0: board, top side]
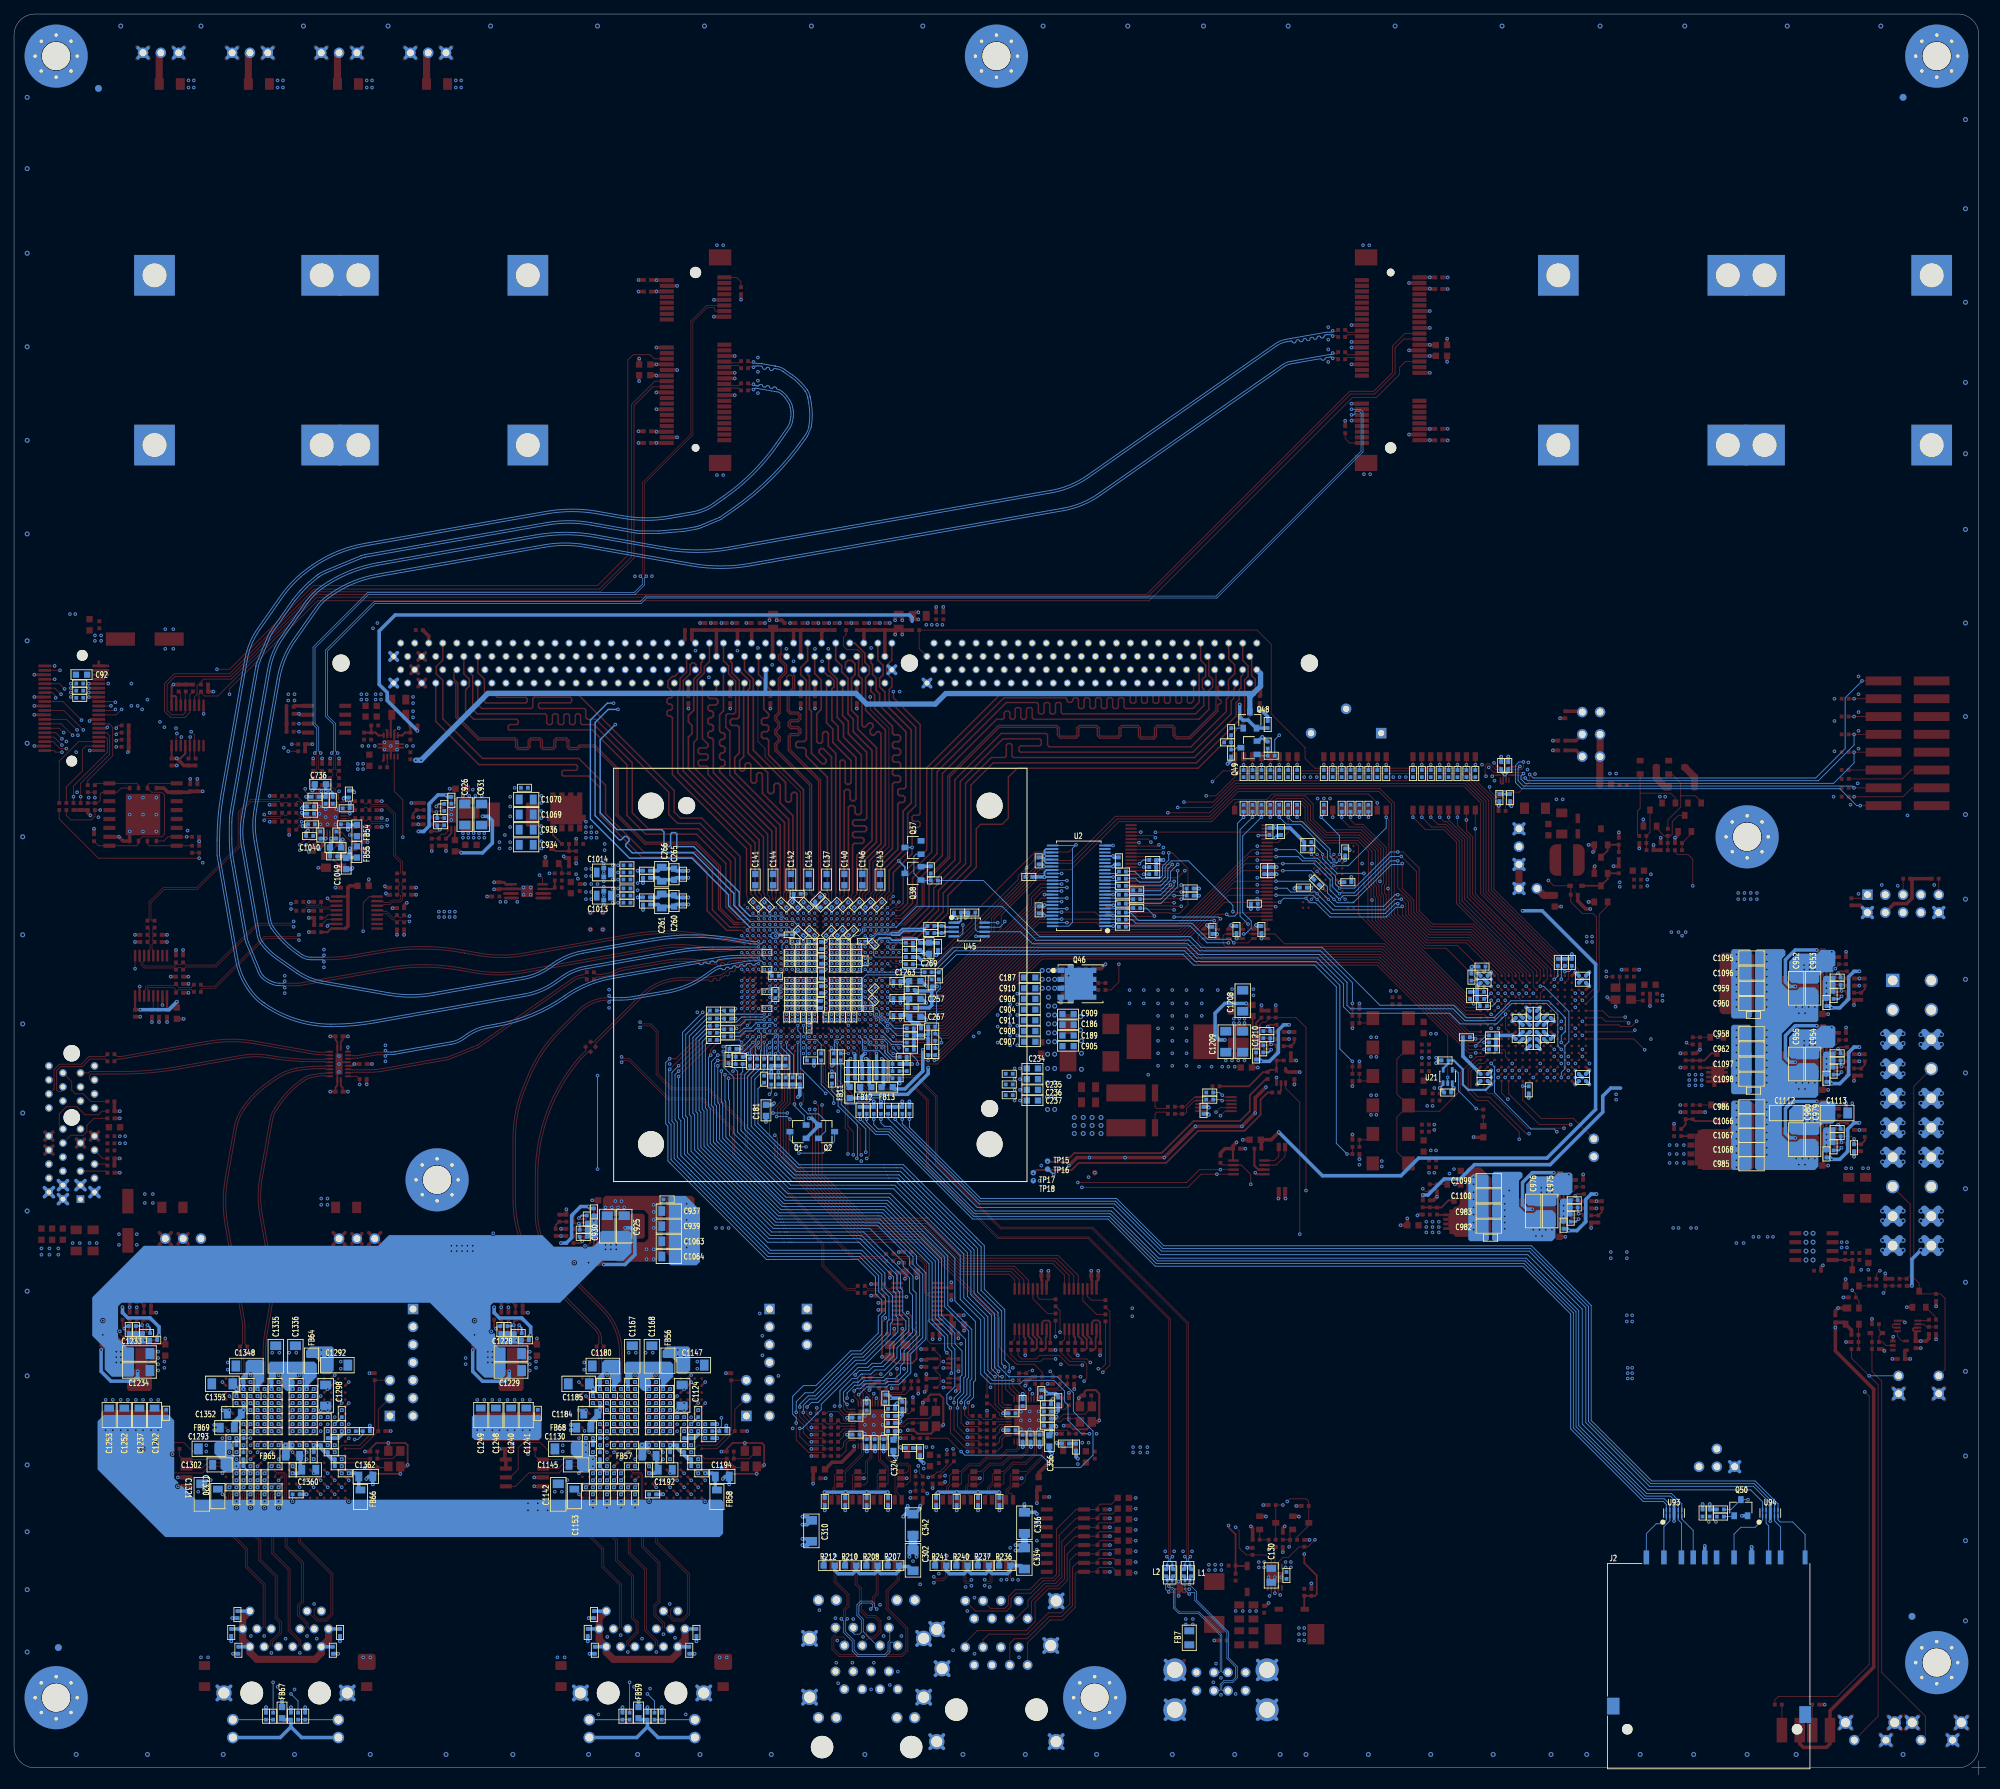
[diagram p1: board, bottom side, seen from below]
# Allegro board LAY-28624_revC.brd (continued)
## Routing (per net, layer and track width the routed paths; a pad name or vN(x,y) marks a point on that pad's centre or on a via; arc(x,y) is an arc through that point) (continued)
EC2_MDX0_N: length 29.2
  TOP w0.102: J14.A2 162.56,18.59 162.56,19.43 162.81,19.69 163.94,19.69 164.19,19.44 164.19,18.01 163.32,17.15 154.57,17.15 153.92,17.79 153.92,20.83 156.74,23.65 156.74,26.26 155.16,27.85 155.16,29.18 155.52,29.54 T1.14
EC2_MDX0_P: length 29.2
  TOP w0.102: J14.A1 163.83,20.86 163.83,20.19 164.47,19.56 164.47,17.89 163.44,16.87 154.46,16.87 153.64,17.68 153.64,20.94 156.46,23.76 156.46,26.15 154.88,27.73 154.88,29.14 154.52,29.5 T1.13
EC2_MDX1_N: length 16.8
  TOP w0.102: v1(158.93,23.65) 158.65,23.93 158.65,25.39 158.16,25.88 158.16,29.13 158.52,29.49 T1.17
  BOTTOM w0.102: v1(158.93,23.65) 158.65,23.93 158.65,24.27 158.89,24.51 160.26,24.51 160.63,24.14 160.63,22.85 159.99,22.21 159.99,20.42 158.03,18.46 J14.A6
EC2_MDX1_P: length 16.9
  TOP w0.102: v1(158.09,23.65) 158.37,23.93 158.37,25.27 157.88,25.76 157.88,29.06 157.52,29.42 T1.16
  BOTTOM w0.102: J14.A3 161.54,20.87 161.54,20.32 161.29,20.07 160.53,20.07 160.27,20.32 160.27,22.1 160.91,22.73 160.91,24.26 160.38,24.79 158.78,24.79 158.37,24.38 158.37,23.93 v1(158.09,23.65)
EC2_MDX2_N: length 15.4
  TOP w0.102: J14.A5 159.16,21 159.51,20.64 159.51,19.81 159.38,19.69 158.51,19.69 157.76,20.44 157.76,21.86 158.36,22.45 159.49,22.45 160.53,23.49 160.53,26.54 161.16,27.17 161.16,29.08 161.52,29.44 T1.20
EC2_MDX2_P: length 15.3
  TOP w0.102: T1.19 160.52,29.47 160.88,29.11 160.88,27.29 160.25,26.66 160.25,23.61 159.37,22.73 158.24,22.73 157.48,21.97 157.48,20.55 157.48,20.32 158.39,19.41 159.41,19.41 160.15,18.66 J14.A4
EC2_MDX3_N: length 22.9
  TOP w0.102: T1.23 164.52,29.39 164.16,29.03 164.16,27.49 162.31,25.64 162.31,24.13 162.84,23.6 162.84,22.53 v1(163.12,22.25)
  BOTTOM w0.102: J14.A8 155.07,18.69 155.3,18.92 156.08,18.92 156.18,18.82 156.18,17.54 156.86,16.87 160.77,16.87 161.57,17.66 161.57,19.06 162.84,20.33 162.84,21.97 v1(163.12,22.25)
EC2_MDX3_P: length 22.8
  TOP w0.102: T1.22 163.52,29.39 163.88,29.03 163.88,27.61 162.03,25.76 162.03,24.01 162.56,23.48 162.56,22.53 v1(162.28,22.25)
  BOTTOM w0.102: J14.A7 156.21,20.86 156.21,19.19 156.46,18.94 156.46,17.65 156.97,17.15 160.66,17.15 161.29,17.78 161.29,19.18 162.56,20.45 162.56,21.97 v1(162.28,22.25)
EC2_PME_N: length 58.6
  TOP w0.127: v1(156.08,57.15) 156.72,56.52 R222.2 ; U1.U3 v2(168.52,104.45)
  L3SIG w0.102: v1(156.08,57.15) 156.41,57.48 156.41,68.28 158.75,70.61 158.75,72.01 164.08,77.34 164.08,95 163.58,95.5 163.58,96.77 167,100.2 168.27,100.2 168.91,100.84 168.91,104.05 v2(168.52,104.45)
  BOTTOM w0.127: R74.1 168.11,101.95 168.11,104.04 v2(168.52,104.45)
EC2_REFCLK: length 120.8
  TOP w0.127: R217.2 147.95,48.01 v1(146.05,46.1) ; U1.AE5 v2(174.92,106.05)
  BOTTOM w0.127: v1(146.05,46.1) 145.54,45.59 134.62,45.59 132.84,43.81 129.03,43.81 127.25,45.59 127.25,49.02 130.05,51.82 130.05,54.48 132.34,56.77 139.24,56.77 140.78,58.31 140.78,65.92 140.84,65.99 140.84,65.99 143.7,68.85 143.7,75.07 144.26,75.62 154.68,86.04 155.1,86.04 155.1,86.04 156.73,86.04 169.53,86.04 175.96,92.47 175.96,99.4 174.62,100.73 174.62,103.25 174.52,103.35 174.52,105.65 v2(174.92,106.05)
EC2_RST_N: length 139
  TOP w0.127: U65.J2 58.01,105.93 v1(57.51,105.43) ; R220.1 R823.2 158.76,56.63 158.24,57.15 v1(157.48,57.15)
  L6SIG w0.102: v1(57.51,105.43) 56.15,105.43 54.99,104.27 54.99,93.98 64.64,84.33 64.64,82.17 65.79,81.03 65.79,76.58 69.6,72.77 73.79,72.77 75.06,71.5 91.57,71.5 93.34,69.72 128,69.72 137.02,60.71 148.59,60.71 149.22,60.07 155.57,60.07 157.48,58.17 v1(157.48,57.15)
EC2_RXCLK: length 91
  TOP w0.127: U1.AF5 175.72,106.05 177.04,106.05 177.67,105.41 179.27,105.41 180.47,105.41 v1(186.31,99.57) ; R211.1 167.18,50.55 168.02,51.39 v1(168.02,52.45)
  BOTTOM w0.127: v1(186.31,99.57) 186.31,93.6 185.99,93.28 185.99,88.29 184.31,86.61 173.65,75.94 171.28,75.94 171.28,75.94 170.54,75.94 170.54,75.95 170.18,75.95 160.6,75.95 155.7,71.04 155.7,68.96 155.32,68.58 155.32,65.39 155.07,65.13 155.07,63.16 159.62,58.61 160.92,58.61 166.45,53.09 167.39,53.09 v1(168.02,52.45)
EC2_RXCTL: length 103.4
  TOP w0.127: R216.1 R232.1 165.62,45.73 165.86,45.97 167.77,45.97 169.54,47.75 v1(169.54,50.16) ; v1(187.58,102.11) 186.69,102.11 181.48,107.32 179.32,107.32 178.18,108.46 175.7,108.46 U1.AF8
  BOTTOM w0.127: v1(169.54,50.16) 169.54,50.93 170.05,51.43 170.05,53.98 168.53,55.5 166.75,55.5 161.8,60.45 160.4,60.45 157.86,62.99 157.86,65.41 157.35,65.91 157.35,67.69 158.24,68.58 158.24,70.98 160.73,73.47 172.67,73.47 173.41,73.47 173.41,73.47 173.78,73.47 185.07,84.77 187.57,87.26 187.83,87.52 187.83,92.52 188.15,92.84 188.15,101.54 v1(187.58,102.11)
EC2_RXD0: length 104.7
  TOP w0.127: U1.AE8 v2(174.92,109.25) ; v1(169.04,49.4) 169.04,48.26 167.77,46.99 165.73,46.99 165.62,46.87 R228.1 R209.1
  L3SIG w0.102: v1(182.88,108.71) 175.51,108.71 174.98,109.25 v2(174.92,109.25)
  BOTTOM w0.127: v1(169.04,49.4) 168.66,49.4 165.99,52.07 165.99,52.83 160.71,58.1 159.32,58.1 158.75,58.67 157.48,58.67 156.21,59.94 156.21,61.2 153.92,63.49 153.92,64.71 154.81,65.6 154.81,68.83 155.19,69.22 155.19,70.83 155.19,71.25 160.39,76.45 170.39,76.45 170.75,76.45 170.76,76.45 171.49,76.45 173.44,76.45 184.1,87.12 185.48,88.5 185.48,93.49 185.74,93.75 185.74,105.85 v1(182.88,108.71)
EC2_RXD1: length 97.8
  TOP w0.127: R213.1 R229.1 165.62,47.76 165.86,48.01 167.77,48.01 168.53,48.77 168.53,49.91 169.54,50.93 v1(169.54,51.69) ; v1(187.58,100.58) 181.36,106.81 179.2,106.81 178.69,107.32 178.05,107.32 177.32,108.05 U1.AH7
  BOTTOM w0.127: v1(187.58,100.58) 187.71,100.46 187.71,93.02 187.39,92.7 187.39,87.71 187.38,87.7 184.89,85.21 173.59,73.91 172.86,73.91 160.55,73.91 157.8,71.16 157.8,68.9 156.84,67.94 156.84,65.79 157.35,65.28 157.35,62.87 160.21,60.01 161.61,60.01 167.13,54.48 168.27,54.48 169.54,53.21 v1(169.54,51.69)
EC2_RXD2: length 98.2
  TOP w0.127: R214.1 R230.1 165.62,48.78 165.86,49.02 167.64,49.02 168.02,49.4 168.02,50.04 169.04,51.05 v1(169.04,52.45) ; U1.AE6 174.97,107.7 177.04,107.7 177.87,106.87 178.5,106.87 179.01,106.36 181.04,106.36 v1(186.31,101.09)
  BOTTOM w0.127: v1(186.31,101.09) 187.26,100.14 187.26,93.2 186.94,92.89 186.94,87.89 184.71,85.65 173.41,74.36 160.37,74.36 157.35,71.35 157.35,69.22 157.29,69.16 157.29,69.15 156.34,68.2 156.34,64.9 156.59,64.65 156.59,62.99 160.02,59.56 161.32,59.56 166.84,54.04 167.83,54.04 169.04,52.83 v1(169.04,52.45)
EC2_RXD3: length 93.7
  TOP w0.127: R215.1 R231.1 165.62,49.79 165.86,50.04 167.39,50.04 168.53,51.18 v1(168.53,51.69) ; U1.AH6 177.52,106.65 177.52,106.21 177.81,105.92 180.72,105.92 v1(186.31,100.33)
  BOTTOM w0.127: v1(186.31,100.33) 186.82,99.82 186.82,93.39 186.5,93.07 186.5,88.08 184.52,86.1 173.86,75.44 173.23,74.8 160.18,74.8 156.91,71.53 156.91,69.41 155.83,68.33 155.83,64.64 156.15,64.33 156.15,62.8 159.83,59.12 161.13,59.12 166.66,53.59 167.64,53.59 168.53,52.7 v1(168.53,51.69)
EC2_RXDLY: length 2.4
  TOP w0.127: U46.32 157.9,53.3 157.61,53.59 157.61,55 R235.1
EC2_TXCTL: length 83.6
  TOP w0.127: U46.27 159.9,53.48 160.02,53.6 160.02,54.36 160.78,55.12 160.78,56.64 v1(161.16,57.02)
  BOTTOM w0.127: v1(161.16,57.02) 160.53,57.66 159.13,57.66 158.56,58.23 157.16,58.23 155.7,59.69 155.7,61.08 153.48,63.31 153.48,64.06 153.48,65.09 154.37,65.98 154.37,69.09 154.69,69.41 154.69,71.37 160.21,76.9 170.57,76.9 170.57,76.9 170.94,76.9 170.94,76.9 171.68,76.9 173.25,76.9 183.92,87.56 185.04,88.68 185.04,93.68 185.29,93.93 185.29,105.53 R126.2
EC2_TXD0: length 87.9
  TOP w0.127: v1(162.31,53.72) 162.81,53.21 162.81,52.2 162.33,51.71 U46.23
  BOTTOM w0.127: R117.2 182.46,106.3 183.83,104.92 183.83,94.54 183.58,94.28 183.58,89.29 183.31,89.02 172.65,78.36 172.28,78.36 172.28,78.36 171.54,78.36 171.18,78.36 157.99,78.36 155.59,75.95 153.42,73.78 153.42,72.64 151.96,71.18 151.96,62.67 154.18,60.45 154.18,58.8 154.69,58.29 154.69,57.28 155.45,56.52 156.72,56.52 157.04,56.2 159.68,56.2 159.88,56.2 159.94,56.13 159.94,56.13 160.51,55.56 160.56,55.56 161.19,55.56 162.31,54.44 v1(162.31,53.72)
EC2_TXD1: length 84.6
  TOP w0.127: v1(162.31,52.83) 162.31,52.32 162.09,52.11 U46.24
  BOTTOM w0.127: R118.2 182.58,106.81 183.76,105.62 184.28,105.11 184.28,94.35 184.02,94.1 184.02,89.1 183.5,88.58 172.83,77.91 172.1,77.91 171.36,77.91 170.99,77.91 159.07,77.91 154.3,73.15 154.3,72.52 152.91,71.12 152.91,69.15 152.46,68.71 152.46,64.48 152.46,63.73 152.46,63.73 152.46,62.89 154.69,60.66 154.69,59.18 157.23,56.64 159.87,56.64 160.06,56.64 160.13,56.58 160.13,56.58 160.7,56.01 160.74,56.01 160.74,56.01 161.37,56.01 162.81,54.56 162.81,53.34 v1(162.31,52.83)
EC2_TXD2: length 82.7
  TOP w0.127: v1(161.29,54.74) 161.29,53.98 160.7,53.38 U46.25
  BOTTOM w0.127: v1(161.29,54.74) 160.91,55.12 160.37,55.12 160.33,55.12 159.76,55.69 159.7,55.75 159.5,55.75 156.84,55.75 156.59,56.01 156.58,56.01 156.52,56.07 155.13,56.07 153.67,57.53 153.67,60.2 151.51,62.36 151.51,71.37 152.91,72.77 152.91,73.9 157.81,78.8 171.36,78.8 171.73,78.8 172.46,78.8 183.13,89.47 183.13,94.47 183.39,94.72 183.39,104.74 182.34,105.79 R120.2
EC2_TXD3: length 83.5
  TOP w0.127: v1(160.66,54.23) 160.53,54.1 160.53,53.72 160.3,53.49 U46.26
  BOTTOM w0.127: v1(160.66,54.23) 160.59,54.23 159.51,55.31 159.32,55.31 156.65,55.31 156.34,55.63 154.94,55.63 153.23,57.34 153.23,60.01 151.07,62.17 151.07,71.56 152.4,72.9 152.4,74.02 157.63,79.25 171.54,79.25 171.91,79.25 171.91,79.25 172.28,79.25 182.69,89.66 182.69,94.65 182.94,94.9 182.94,104.56 182.22,105.28 R122.2
EMI1_MDC: length 16.4
  TOP w0.127: U46.30 158.7,53.9 158.5,54.1 v1(158.5,54.36) ; U23.2 148.34,58.67 v1(148.59,58.93)
  L6SIG w0.102: v1(148.59,58.93) 149.73,58.93 150.5,59.69 155.32,59.69 156.88,58.13 156.88,55.46 157.99,54.36 v1(158.5,54.36)
EMI1_MDC_SLP: length 85.6
  TOP w0.127: R132.2 146.45,59.32 U23.1 147.77,59.88 v1(148.08,60.2) ; U49.30 136.47,54.54 136.27,54.74 v1(136.27,54.99)
  L6SIG w0.102: v1(148.08,60.2) 147.7,60.2 145.92,58.42 144.91,58.42 143.38,56.9 142.09,56.9 141.43,56.23 141.43,56.21 140.08,54.86 136.4,54.86 v1(136.27,54.99)
  BOTTOM w0.127: v1(148.08,60.2) 148.4,60.52 148.4,62.42 150.62,64.64 150.62,72.87 157.44,79.69 157.81,79.69 171.73,79.69 171.73,79.69 172.1,79.69 182.25,89.84 182.25,94.83 182.5,95.09 182.5,104.13 R129.1
EMI1_MDIO: length 16.3
  TOP w0.127: v1(148.59,56.13) 148.34,55.88 U24.2 ; U46.31 158.3,53.54 v1(158.11,53.72)
  L6SIG w0.102: v1(148.59,56.13) 148.59,56.64 150.62,58.67 155.83,58.67 156.53,57.98 156.53,55.31 v1(158.11,53.72)
EMI1_MDIO_SLP: length 91.3
  TOP w0.127: v1(135.89,54.36) 136.07,54.17 U49.31 ; U1.AH4 177.66,104.9 180.21,104.9 181.74,103.38 v1(181.74,102.62) ; R131.2 146.45,56.53 U24.1 147.77,56.96 v1(147.45,57.28)
  L6SIG w0.102: v1(147.45,57.28) 146.68,56.51 142.23,56.51 140.21,54.48 138.43,54.48 137.79,53.85 136.4,53.85 v1(135.89,54.36)
  BOTTOM w0.127: v1(181.74,102.62) 182.05,102.3 182.05,95.27 181.8,95.02 181.8,90.02 171.91,80.14 157.99,80.14 157.26,80.14 150.18,73.06 150.18,64.83 147.95,62.61 147.95,60.96 147.38,60.39 147.38,57.34 v1(147.45,57.28)
EMI2_MDC: length 147.7
  TOP w0.127: U108.J18 v1(233.32,48.01) ; U101.J18 v1(182.52,48.01)
  L3SIG w0.102: v1(182.52,48.01) 181.25,49.28 178.82,49.28 178.05,50.04 172.72,50.04 171.45,51.31 171.45,55.37 169.04,57.78 169.04,60.32 J60.3 164.47,64.9 164.47,95.5 v1(164.21,95.76)
  L6SIG w0.102: v1(182.52,48.01) 182.52,48.15 183.01,48.64 183.01,50.8 184.02,51.82 184.02,57.15 184.78,57.91 186.56,57.91 196.47,67.82 226.95,67.82 232.28,62.48 232.28,49.04 v1(233.32,48.01)
  BOTTOM w0.127: R130.2 165.99,98.43 164.21,96.65 v1(164.21,95.76)
EMI2_MDIO: length 150
  TOP w0.127: U1.V6 v2(169.32,106.85) ; U108.L18 v1(233.32,50.01) ; U101.L18 v1(182.52,50.01)
  L3SIG w0.102: v1(165.35,97.16) 165.35,96.77 164.85,96.27 164.85,65.15 166.12,63.88 J60.2 169.42,62.48 169.42,58.04 171.96,55.5 171.96,53.09 172.72,52.32 180.2,52.32 v1(182.52,50.01)
  L6SIG w0.102: v1(233.32,50.01) 232.66,50.66 232.66,62.61 227.08,68.2 196.34,68.2 186.44,58.29 184.66,58.29 183.01,56.64 183.01,51.43 182.52,50.94 v1(182.52,50.01)
  BOTTOM w0.127: v1(165.35,97.16) 168.91,100.71 168.91,105.66 169.32,106.07 v2(169.32,106.85)
ETH_REFCLK1_N: length 11.9
  TOP w0.102: C1384.1 155.35,73.63 153.39,73.63 153.17,73.41 R543.2 152.55,73.65 152.15,73.65 151.28,72.78 151.28,68.72 150.91,68.34 150.56,68.34 150.37,68.16 U68.4
ETH_REFCLK1_P: length 11.9
  TOP w0.102: C1382.1 155.33,73.91 153.42,73.91 153.17,74.16 R544.2 152.55,73.93 152.03,73.93 151,72.9 151,68.83 150.79,68.62 150.56,68.62 150.37,68.81 U68.3
ETH_REFCLK2_N: length 5.7
  TOP w0.102: C1389.1 159.47,69.01 157.21,69.01 157.11,68.91 R541.2 156.44,68.99 156.22,68.99 156.03,68.81 U68.18
ETH_REFCLK2_P: length 5.8
  TOP w0.102: 157.11,69.97 156.41,69.27 156.2,69.27 156.02,69.46 U68.19 ; 157.11,69.97 R542.2 ; 157.11,69.97 157.11,69.39 157.21,69.29 159.34,69.29 C1387.1
ETH_REFCLK_SEL: length 126.9
  TOP w0.127: v1(59.18,92.71) 63.63,92.71 68.02,97.1 U65.T12 ; U68.9 150.61,64.91 150.88,64.64 150.88,61.98 150.37,61.47 v1(146.05,61.47)
  L6SIG w0.102: v1(146.05,61.47) 136.78,61.47 128.14,70.1 93.34,70.1 91.69,71.76 75.18,71.76 73.91,73.03 69.72,73.03 66.17,76.58 66.17,81.15 65.02,82.3 65.02,84.58 59.18,90.42 v1(59.18,92.71)
EVDD: length 10.2
  TOP w0.305: U1.L8 v2(162.92,108.45)
  L6SIG w0.508: J57.1 39.06,47.19 ; J57.1 37.65,47.19 ; J57.1 37.65,45.77 ; J57.1 39.06,45.77
  BOTTOM w0.508: R63.2 R64.2 R67.2 v1(158.5,96.01) ; R68.2 R60.2 R62.2 v1(154.43,96.01)
  vias: v1(52.2,127.25) v1(52.2,126.62)
EVDD_SEL: length 38.4
  TOP w0.127: R820.1 44.32,131.56 43.94,131.19 42.44,131.19 41.78,130.54 v1(41.78,126.75) ; U65.F1 54.61,108.93 53.71,108.03 v1(51.41,108.03)
  L6SIG w0.102: v1(41.78,126.75) 42.67,125.86 42.67,121.03 42.16,120.52 42.16,113.41 47.24,108.33 50.42,108.33 50.72,108.03 v1(51.41,108.03)
EVT_BRD_ISO: length 95.3
  TOP w0.127: U1.A3 155.24,104.78 149.99,104.78 149.35,105.41 147.95,105.41 135.13,118.24 112.27,118.24 111.38,117.35 86.11,117.35 73.68,104.93 v1(72.72,104.93) U65.K16
  BOTTOM w0.127: R81.1 72.95,105.16 v1(72.72,104.93)
EVT_PWR_EN: length 99.3
  TOP w0.127: U1.C1 156.92,102.94 156.08,102.11 154.69,102.11 154.43,102.36 149.48,102.36 134.75,117.09 112.65,117.09 111.76,116.2 86.49,116.2 73.71,103.42 v1(71.52,103.42) 71.52,103.42 U65.L15
  BOTTOM w0.127: R85.1 v1(71.52,103.42)
EVT_PWR_OK: length 100.3
  TOP w0.127: U1.C2 156.46,103.59 156.46,103 155.89,102.43 155,102.43 154.69,102.74 149.61,102.74 134.87,117.48 112.52,117.48 111.63,116.59 86.36,116.59 73.7,103.93 72.72,103.93 v1(72.72,103.92) 72.72,103.93 U65.L16
  BOTTOM w0.127: v1(72.72,103.92) 71.22,105.43 R813.1
FAN_PWM: length 15.8
  TOP w0.127: U65.E1 55.12,111.82 55.12,122.68 53.91,123.89 Q27.1
HRESET_N: length 100.3
  TOP w0.127: U65.D14 v1(70.52,111.43) ; U1.E8 v2(158.12,108.45)
  L6SIG w0.102: v2(158.12,108.45) 158.5,108.07 158.5,107.49 158.24,107.23 157.96,107.23 157.7,106.97 157.7,105.89 157.44,105.63 157.06,105.63 156.84,105.41 156.09,105.41 155.79,105.71 147.14,105.71 136.86,116 126.95,116 125.98,116.97 79.5,116.97 73.97,111.43 v1(70.52,111.43)
  BOTTOM w0.127: R96.2 71.32,110.63 v1(70.52,111.43)
I2C1_SCL: length 148.3
  TOP w0.127: U44.6 v1(240.41,149.86) R89.1 ; U1.W1 169.8,103.16 v1(169.8,95.63)
  L3SIG w0.102: v1(240.41,149.86) 240.92,149.35 240.92,145.41 236.85,141.35 232.92,141.35 232.03,140.46 232.03,131.83 233.04,130.81 239.39,130.81 243.2,127 243.2,119.38 237.62,113.79 221.74,113.79 201.17,93.22 188.6,93.22 185.55,90.17 172.21,90.17 171.45,90.93 171.45,94.62 170.43,95.63 v1(169.8,95.63)
  BOTTOM w0.127: Q1.2 168.4,92.91 168.4,93.98 169.8,95.38 v1(169.8,95.63)
I2C1_SCL_SLP: length 275.1
  TOP w0.127: v1(239.39,132.59) 238.76,133.22 238.25,133.22 238,133.47 U97.9 ; v1(129.41,84.45) 113.92,84.45 112.09,86.29 v1(109.09,86.29) U100.6 ; U111.5 108.44,94.63 v1(109.09,93.98) ; R91.1 v1(241.43,146.94)
  L3SIG w0.102: v1(109.09,93.98) 109.35,93.73 109.35,86.54 v1(109.09,86.29) ; v1(144.27,105.28) 144.27,117.48 140.84,120.9 v1(140.84,121.5) ; v1(168.15,89.54) 168.27,89.66 185.55,89.66 188.72,92.84 201.29,92.84 221.87,113.41 237.87,113.41 243.59,119.13 243.59,127.25 239.78,131.06 239.78,132.08 239.39,132.46 v1(239.39,132.59) 240.92,134.11 240.92,143.51 241.43,144.02 v1(241.43,146.94) 241.43,149.61 240.66,150.37 228.85,150.37 224.92,154.31 J1.118
  L6SIG w0.102: v1(168.15,89.54) 166.24,91.44 154.69,91.44 143,79.76 133.35,79.76 129.41,83.69 v1(129.41,84.45) 129.41,87.63 131.19,89.41 133.29,89.41 144.27,100.39 v1(144.27,105.28)
  BOTTOM w0.127: Q1.3 170.44,90.56 169.42,89.54 v1(168.15,89.54) ; U45.8 v1(140.84,121.5)
I2C1_SDA: length 151.8
  TOP w0.127: v1(168.91,95.63) 168.53,96.01 168.53,97.15 168.92,97.54 U1.V1 ; U44.5 240.28,148.59 v1(240.41,148.72) R88.1
  L3SIG w0.102: v1(240.41,148.72) 240.41,145.54 236.6,141.73 232.79,141.73 231.65,140.59 231.65,131.7 232.92,130.43 239.27,130.43 242.82,126.87 242.82,119.38 237.62,114.17 221.61,114.17 201.04,93.6 188.47,93.6 185.42,90.55 172.34,90.55 171.83,91.06 171.83,94.74 170.43,96.14 169.42,96.14 v1(168.91,95.63)
  BOTTOM w0.127: Q2.2 165.35,91.77 165.35,93.22 166.37,94.23 167.89,94.23 168.91,95.25 v1(168.91,95.63)
I2C1_SDA_SLP: length 287.8
  TOP w0.127: U100.5 v1(109.6,85.64) 111.85,85.64 113.73,83.76 v1(128.84,83.76) ; U97.10 238.4,133.71 238.51,133.6 239.27,133.6 v1(240.28,132.59) ; R90.1 v1(241.94,145.92) ; v1(109.73,94.49) 109.09,95.13 U111.4
  L3SIG w0.102: v1(109.73,94.49) 109.73,85.77 v1(109.6,85.64) ; v1(169.16,88.65) 169.8,89.28 185.67,89.28 188.85,92.46 201.42,92.46 222,113.03 238,113.03 243.97,119 243.97,127.38 240.79,130.56 240.79,132.08 v1(240.28,132.59) 241.3,133.6 241.3,143.26 241.94,143.89 v1(241.94,145.92) 241.94,149.86 241.05,150.75 229.11,150.75 225.81,154.05 225.81,156.08 224.92,156.97 J1.238 ; v1(143.51,105.79) 143.89,106.17 143.89,117.35 139.83,121.41 v1(139.83,121.67)
  L6SIG w0.102: v1(143.51,105.79) 143.51,100.14 133.16,89.79 130.94,89.79 128.84,87.69 v1(128.84,83.76) 133.22,79.38 143.13,79.38 154.81,91.06 165.99,91.06 168.4,88.65 v1(169.16,88.65)
  BOTTOM w0.127: Q2.3 164.08,90.3 165.73,88.65 v1(169.16,88.65) ; U45.7 140.52,120.85 139.83,121.54 v1(139.83,121.67)
I2C2_MPEX1_SCL: length 113.6
  TOP w0.127: J19.30 189.69,198.68 193.04,195.33 193.04,173.61 197.61,169.04 238.25,169.04 250.32,156.97 258.19,156.97 259.59,155.57 259.59,151.64 258.7,150.75 256.67,150.75 255.96,151.46 U19.5 255.96,154 R398.1
I2C2_MPEX1_SDA: length 111.2
  TOP w0.127: J19.32 189.98,197.88 192.66,195.2 192.66,173.48 197.48,168.66 238.12,168.66 250.19,156.59 258.06,156.59 259.21,155.45 259.21,151.76 258.57,151.13 256.92,151.13 256.61,151.44 U19.4 256.61,154.37 R404.1
I2C2_MPEX2_SCL: length 199.3
  TOP w0.127: U19.7 254.66,154.14 R409.1 254.37,154.3 253.87,153.8 251.97,153.8 237.87,167.89 119.51,167.89 90.55,196.85 87.12,196.85 84.2,199.77 84.2,203.44 82.96,204.68 J20.30
I2C2_MPEX2_SDA: length 200.4
  TOP w0.127: U19.6 255.31,153.63 254.94,154 254.94,155.27 254.76,155.45 R410.1 254.37,155.84 254,156.21 250.06,156.21 238,168.27 119.63,168.27 90.68,197.23 87.25,197.23 84.58,199.9 84.58,203.69 82.8,205.48 J20.32
I2C2_PEX_SCL: length 91.7
  TOP w0.127: v1(255.91,147.95) 255.96,147.9 U19.12 255.96,145.1 R406.1
  L6SIG w0.102: v1(255.91,147.95) 261.75,153.8 267.08,153.8 269.24,151.64 271.78,151.64 275.34,148.08 275.34,144.65 276.99,143 276.99,88.65 276.48,88.14 275.72,88.14 275.08,87.5 275.08,87.11 J18.B5
I2C2_PEX_SDA: length 90.9
  TOP w0.127: R407.1 255.31,145.07 U19.11 255.31,148.25 v1(255.78,148.72)
  L6SIG w0.102: v1(255.78,148.72) 261.11,154.05 267.21,154.05 269.37,151.89 272.03,151.89 275.62,148.31 275.62,144.75 277.24,143.13 277.24,88.27 J18.B6
IFC_A5: length 16.3
  TOP w0.127: v1(107.95,118.62) 107.88,118.68 U10.1
  BOTTOM w0.127: R14.2 122.44,121.03 113.41,121.03 111,118.62 v1(107.95,118.62)
IFC_A6: length 19.9
  TOP w0.127: v1(107.19,118.62) 105.16,118.62 104.54,119.24 U9.1
  BOTTOM w0.127: v1(107.19,118.62) 107.7,119.13 110.87,119.13 113.16,121.41 121.16,121.41 121.67,121.92 R15.2
IFC_A7: length 16.5
  TOP w0.127: v1(109.98,121.79) 110.13,121.64 110.13,119.99 110.89,119.24 U8.1
  BOTTOM w0.127: v1(109.98,121.79) 120.78,121.79 121.92,122.94 R16.2
IFC_A8: length 5.9
  TOP w0.127: v1(118.49,122.43) 118.52,122.4 U4.2
  BOTTOM w0.127: R18.2 119.63,123.57 v1(118.49,122.43)
IFC_A9: length 17.3
  TOP w0.127: U4.15 115.32,128.9 115.32,128.91 v1(115.19,128.91)
  BOTTOM w0.127: R20.2 117.6,124.21 115.19,126.62 v1(115.19,128.91)
IFC_A10: length 12.4
  TOP w0.127: U4.12 115.72,127.4 v1(115.7,127.38)
  BOTTOM w0.127: R22.2 117.6,124.84 115.7,126.75 v1(115.7,127.38)
IFC_A11: length 12.6
  TOP w0.127: U4.11 116.23,126.9 v1(116.2,126.87)
  BOTTOM w0.127: v1(116.2,126.87) 117.6,125.48 R24.2
IFC_A12: length 14.9
  TOP w0.127: U4.18 119.35,130.4 118.24,129.29 115.7,129.29 v1(115.19,129.79)
  BOTTOM w0.127: v1(115.19,129.79) 116.2,128.78 116.2,127.51 117.6,126.11 R26.2
IFC_A13: length 15
  TOP w0.127: v1(115.95,129.79) 118.11,129.79 119.22,130.9 U4.19
  BOTTOM w0.127: R28.2 117.6,126.75 116.59,127.76 116.59,129.16 v1(115.95,129.79)
IFC_A14: length 26
  TOP w0.127: U4.54 107.15,122.9 v1(107.32,123.06)
  BOTTOM w0.127: R30.2 121.16,127.76 120.65,127.25 117.73,127.25 116.97,128.02 116.97,129.41 116.08,130.3 113.67,130.3 107.32,123.95 v1(107.32,123.06)
IFC_A15: length 26.9
  TOP w0.127: v1(116.46,131.44) 115.95,131.44 113.73,129.22 113.73,124.02 114.94,122.81 116.21,122.81 116.3,122.9 U4.3
  BOTTOM w0.127: v1(116.46,131.44) 116.46,130.43 117.35,129.54 117.35,128.21 117.79,127.76 120.27,127.76 121.29,128.78 R32.2
IFC_A16: length 122.6
  TOP w0.127: SW2.5 v1(90.55,136.52) 90.55,136.14 89.92,135.51 88.77,135.51 85.47,132.21 85.47,126.99 85.73,126.74 85.73,125.74 85.47,125.48 85.47,122.3 74.1,110.93 U65.D16 ; U1.C5 v2(156.52,106.05) ; U4.4 115.78,123.4 v1(115.7,123.32)
  L6SIG w0.102: v1(90.55,136.52) 90.55,136.41 95.36,131.6 96.37,131.6 97.54,130.43 102.11,130.43 103.63,128.91 106.3,128.91 111.89,123.32 v1(115.7,123.32) 118.36,123.32 123.06,118.62 125.09,118.62 127.25,116.46 137.16,116.46 147.19,106.43 156.14,106.43 v2(156.52,106.05)
  BOTTOM w0.127: R797.2 v1(90.55,136.52)
IFC_A17: length 125.2
  TOP w0.127: v1(114.68,123.83) 116.13,123.83 116.2,123.9 U4.5 ; U65.E15 71.52,110.43 74.11,110.43 85.85,122.17 85.85,125.35 86.11,125.6 86.11,126.87 85.85,127.13 85.85,132.08 88.9,135.13 90.68,135.13 91.82,136.27 v1(91.82,136.52) SW2.6 ; U1.C6 v2(156.52,106.85)
  L6SIG w0.102: v1(91.82,136.52) 91.82,135.64 95.5,131.95 96.52,131.95 97.09,131.38 102.17,131.38 103.63,129.92 105.79,129.92 111.89,123.83 v1(114.68,123.83) 118.24,123.83 123.22,118.85 125.25,118.85 127.38,116.71 137.29,116.71 147.32,106.68 156.35,106.68 v2(156.52,106.85)
  BOTTOM w0.127: R798.2 v1(91.82,136.52)
IFC_A18: length 142.7
  TOP w0.127: SW2.3 v1(88.01,136.52) ; U4.6 115.77,124.4 v1(115.7,124.33) ; U65.F14 v1(69.51,109.43) ; U1.D7 v2(157.32,107.65)
  L3SIG w0.102: v1(88.01,136.52) 84.96,139.57 73.15,139.57 69.6,136.02 69.6,123.7 67.18,121.29 67.18,112.71 67.09,112.61 67.09,112.25 67.45,111.89 67.67,111.89 67.95,111.61 67.95,111.25 68.26,110.93 68.77,110.93 69.02,110.68 69.02,109.92 v1(69.51,109.43)
  L6SIG w0.102: v2(157.32,107.65) 157.3,107.65 156.88,107.23 156.36,107.23 156.07,106.93 147.45,106.93 137.41,116.97 127.51,116.97 125.4,119.08 123.37,119.08 118.11,124.33 v1(115.7,124.33) 111.89,124.33 105.28,130.94 103.63,130.94 102.23,132.33 95.63,132.33 92.33,135.64 92.33,136.63 91.92,137.03 90.45,137.03 89.43,136.02 88.52,136.02 v1(88.01,136.52)
  BOTTOM w0.127: R799.2 v1(88.01,136.52)
IFC_A19: length 144.1
  TOP w0.127: SW2.4 v1(89.28,136.52) ; v1(68.51,110.43) 68.51,109.43 U65.F13 ; v1(114.68,124.84) 114.74,124.9 U4.7 ; U1.C7 v2(156.52,107.65)
  L3SIG w0.102: v1(68.51,110.43) 67.81,110.43 67.06,111.19 67.06,111.51 66.42,112.14 66.42,121.54 68.83,123.95 68.83,136.27 72.9,140.33 85.73,140.33 89.28,136.78 v1(89.28,136.52)
  L6SIG w0.102: v1(89.28,136.52) 90.17,137.41 92.08,137.41 92.66,136.83 92.66,135.94 95.88,132.72 102.74,132.72 103.51,131.95 104.78,131.95 111.89,124.84 v1(114.68,124.84) 117.98,124.84 123.52,119.3 125.55,119.3 127.64,117.22 137.54,117.22 147.57,107.19 155.83,107.19 156.29,107.65 v2(156.52,107.65)
  BOTTOM w0.127: R800.2 v1(89.28,136.52)
IFC_A20: length 58.5
  TOP w0.127: U4.8 115.75,125.4 v1(115.7,125.35) ; U1.D8 v2(157.32,108.45)
  L6SIG w0.102: v1(115.7,125.35) 117.86,125.35 123.67,119.53 125.7,119.53 127.76,117.48 137.67,117.48 147.1,108.05 156.94,108.05 157.32,108.42 v2(157.32,108.45)
  BOTTOM w0.127: R864.2 R13.2 v1(115.7,125.35)
IFC_A21: length 139.2
  TOP w0.127: U65.C10 v1(65.51,111.42) ; U1.C8 v2(156.52,108.45) ; v1(114.68,125.86) 114.72,125.9 U4.9 ; SW2.7 v1(93.09,136.52)
  L3SIG w0.102: v1(93.09,136.52) 88.9,140.72 72.77,140.72 68.45,136.4 68.45,124.08 66.04,121.67 66.04,111.95 v1(65.51,111.42)
  L6SIG w0.102: v2(156.52,108.45) 147.08,108.45 137.79,117.73 127.89,117.73 125.86,119.76 123.82,119.76 117.73,125.86 v1(114.68,125.86) 111.38,125.86 104.14,133.1 96.01,133.1 93.09,136.02 v1(93.09,136.52)
IFC_A22: length 58.2
  TOP w0.127: U4.10 115.15,126.4 v1(114.68,126.87) ; U1.D9 v2(157.32,109.25)
  L6SIG w0.102: v2(157.32,109.25) 156.91,108.84 147.07,108.84 137.92,117.98 128.02,117.98 126.01,119.99 123.98,119.99 117.6,126.37 115.19,126.37 v1(114.68,126.87)
IFC_A23: length 56.4
  TOP w0.127: U1.C9 v2(156.52,109.25) ; U4.20 117.26,131.4 v1(117.22,131.44)
  L6SIG w0.102: v2(156.52,109.25) 156.36,109.09 147.19,109.09 138.05,118.24 128.14,118.24 126.16,120.22 124.13,120.22 117.98,126.37 117.98,130.68 v1(117.22,131.44)
IFC_A24: length 57.9
  TOP w0.127: U1.D10 v2(157.32,110.05) ; U4.21 117.53,131.9 v1(117.22,132.21)
  L6SIG w0.102: v2(157.32,110.05) 157.29,110.05 156.87,109.63 156.24,109.63 155.96,109.35 147.32,109.35 138.18,118.49 128.27,118.49 126.31,120.45 124.28,120.45 118.36,126.37 118.36,131.06 v1(117.22,132.21)
IFC_A25: length 56.5
  TOP w0.127: v1(117.86,132.59) 118.04,132.4 U4.22 ; U1.C10 v2(156.52,110.05)
  L6SIG w0.102: v1(117.86,132.59) 120.02,130.43 120.78,130.43 121.67,129.54 121.67,123.57 123.7,121.54 125.6,121.54 128.4,118.75 138.3,118.75 147.45,109.6 155.83,109.6 156.27,110.05 v2(156.52,110.05)
IFC_A26: length 51.5
  TOP w0.127: U4.23 v1(120.71,132.9) ; U1.E11 v2(158.12,110.85)
  L6SIG w0.102: v2(158.12,110.85) 157.73,111.23 157.73,111.77 157.47,112.03 149.72,112.03 149.67,111.97 149.31,111.97 149.25,112.03 146.93,112.03 138.94,120.02 129.03,120.02 124.59,124.46 124.21,124.46 123.57,125.09 123.57,130.04 v1(120.71,132.9)
IFC_A27: length 128.9
  TOP w0.127: U1.C11 v2(156.52,110.85) ; U4.24 119.43,133.4 v1(119,132.97) ; U65.C13 v1(69.52,112.43)
  L3SIG w0.102: v1(69.52,112.43) 69.52,121.08 71.5,123.06 71.5,135.38 73.91,137.79 82.04,137.79 86.23,133.6 100.46,133.6 100.89,133.17 101.68,133.17 101.96,133.45 115.34,133.45 115.57,133.22 117.98,133.22 118.24,132.97 v1(119,132.97)
  L6SIG w0.102: v2(156.52,110.85) 146.96,110.85 138.56,119.25 128.65,119.25 125.86,122.05 124.08,122.05 122.43,123.7 122.43,129.54 v1(119,132.97)
IFC_A28: length 132.5
  TOP w0.127: U4.25 118.66,133.9 v1(118.36,133.6) ; U65.C12 68.02,111.93 v1(68.52,112.43) ; U1.D11 v2(157.32,110.85)
  L3SIG w0.102: v1(118.36,133.6) 116.01,133.6 115.63,133.98 104.52,133.98 104.01,134.49 86.36,134.49 82.42,138.43 73.53,138.43 70.74,135.64 70.74,123.32 68.52,121.1 v1(68.52,112.43)
  L6SIG w0.102: v1(118.36,133.6) 118.36,132.72 120.27,130.81 120.78,130.81 122.05,129.54 122.05,123.57 123.83,121.79 125.73,121.79 128.52,119 138.43,119 146.96,110.47 156.94,110.47 v2(157.32,110.85)
IFC_A29: length 131.2
  TOP w0.127: v1(120.44,134.4) 120.44,134.4 U4.26 ; U1.C12 v2(156.52,111.65) ; v1(67.52,112.43) 67.02,111.93 U65.C11
  L3SIG w0.102: v1(67.52,112.43) 67.52,121.11 69.98,123.57 69.98,135.89 73.28,139.19 83.69,139.19 87.2,135.69 101.61,135.69 102.17,135.13 119.25,135.13 119.98,134.4 v1(120.44,134.4)
  L6SIG w0.102: v1(120.44,134.4) 120.14,134.1 120.14,132.84 123.19,129.79 123.19,124.08 123.95,123.32 125.35,123.32 125.51,123.16 128.88,119.79 138.79,119.79 146.93,111.65 v2(156.52,111.65)
IFC_A30: length 146
  TOP w0.127: U1.D12 v2(157.32,111.65) ; v1(118.36,134.37) 118.33,134.4 U4.31 ; U65.D12 v1(68.52,111.43)
  L3SIG w0.102: v1(68.52,111.43) 68.09,111.86 68.09,121.17 70.36,123.44 70.36,135.76 73.41,138.81 82.55,138.81 86.54,134.82 104.19,134.82 104.65,134.37 v1(118.36,134.37)
  L6SIG w0.102: v1(118.36,134.37) 118.36,134.24 122.81,129.79 122.81,123.95 123.76,123 125.28,123 128.78,119.51 138.68,119.51 146.94,111.25 156.92,111.25 v2(157.32,111.65)
IFC_A31: length 135.6
  TOP w0.127: v1(115.19,137.92) 110.36,137.92 106.93,141.35 74.3,141.35 71.63,138.68 71.63,125.73 61.02,115.12 U65.A5 ; U1.E12 v2(158.12,111.65)
  L6SIG w0.102: v2(158.12,111.65) 158.12,111.89 157.73,112.27 157.73,112.65 157.52,112.87 157.14,112.87 156.9,113.1 156.9,113.4 156.64,113.67 146.81,113.67 139.45,121.03 129.54,121.03 125.98,124.59 125.98,133.1 120.65,138.43 115.7,138.43 v1(115.19,137.92)
IFC_AD0: length 102.7
  TOP w0.127: U107.J8 95.85,126.02 v2(96.9,124.97) ; U1.A4 155.23,105.73 148.15,105.73 135.25,118.62 114.3,118.62 108.52,124.4 U4.51 v1(100.64,124.4) ; U65.A13 69.02,114.23 73.79,119 79.63,119 83.19,122.56 v1(83.19,123.83)
  BOTTOM w0.127: v1(100.64,124.4) 100.08,124.97 v2(96.9,124.97) 96.27,124.33 95.5,124.33 93.47,122.3 85.47,122.3 84.07,123.7 83.31,123.7 v1(83.19,123.83)
IFC_AD1: length 103.5
  TOP w0.127: v1(101.17,125.4) U4.49 108.02,125.4 114.43,119 135.38,119 148.34,106.05 155.71,106.05 U1.B5 ; v1(83.82,124.21) 83.82,122.68 79.76,118.62 74.04,118.62 69.52,114.1 69.52,113.43 U65.B13 ; U107.K7 v2(95.33,124.82)
  BOTTOM w0.127: v1(83.82,124.21) 84.2,124.21 85.6,122.81 93.32,122.81 v2(95.33,124.82) 95.91,125.4 v1(101.17,125.4)
IFC_AD2: length 104.4
  TOP w0.127: U107.J7 v2(95.33,125.62) ; U1.A5 148.44,106.45 135.51,119.38 114.55,119.38 107.53,126.4 U4.47 v1(101.17,126.4) ; v1(83.31,124.84) 82.68,124.21 82.68,122.56 79.5,119.38 73.66,119.38 68.52,114.24 68.52,113.43 U65.B12
  BOTTOM w0.127: v1(101.17,126.4) 99.6,126.4 99.06,125.86 95.57,125.86 v2(95.33,125.62) 93.03,123.32 85.73,123.32 84.2,124.84 v1(83.31,124.84)
IFC_AD3: length 105.6
  TOP w0.127: v1(101.17,127.4) U4.45 107.04,127.4 114.68,119.76 135.64,119.76 148.59,106.81 155.68,106.81 U1.B6 ; v1(83.82,125.48) 83.31,125.48 82.3,124.46 82.3,122.68 79.38,119.76 73.53,119.76 68.02,114.24 U65.A12 ; U107.K6 v2(93.73,124.82)
  BOTTOM w0.127: v1(101.17,127.4) 96.31,127.4 v2(93.73,124.82) 92.74,123.83 85.85,123.83 84.2,125.48 v1(83.82,125.48)
IFC_AD4: length 112.5
  TOP w0.127: v1(100.21,128.9) U4.42 106.05,128.9 114.81,120.14 135.76,120.14 148.68,107.22 155.29,107.22 U1.A6 ; U107.K5 v2(92.93,124.82) ; v1(83.19,129.92) 83.19,126.37 81.53,124.71 81.53,122.94 79.12,120.52 73.28,120.52 67.02,114.26 U65.A11
  BOTTOM w0.127: v1(100.21,128.9) 96.13,128.9 93.85,126.62 93.85,125.74 v2(92.93,124.82) 92.44,124.33 90.17,124.33 84.71,129.79 83.31,129.79 v1(83.19,129.92)
IFC_AD5: length 117
  TOP w0.127: v1(83.82,130.3) 83.82,126.49 81.92,124.59 81.92,122.81 79.25,120.14 73.41,120.14 67.52,114.25 67.52,113.43 U65.B11 ; U1.A7 155.3,108.06 148.35,108.06 134.92,121.5 v1(130.98,121.5) 126.7,121.5 125.73,120.52 114.94,120.52 105.56,129.9 U4.40 v1(100.21,129.9) ; U107.K4 v2(92.13,124.82)
  BOTTOM w0.127: U2.47 v1(130.98,121.5) ; v1(83.82,130.3) 84.84,130.3 89.79,125.35 91.59,125.35 v2(92.13,124.82) 93.47,126.16 93.47,127.64 95.74,129.9 v1(100.21,129.9)
IFC_AD6: length 118.8
  TOP w0.127: U65.B10 66.52,113.43 66.52,114.27 73.15,120.9 78.99,120.9 81.15,123.06 81.15,128.78 v1(83.31,130.94) ; U1.B8 155.73,108.46 148.46,108.46 134.93,122 v1(131.73,122) 126.57,122 126.11,121.54 123.44,121.54 122.81,120.9 115.06,120.9 105.07,130.9 U4.38 v1(101.17,130.9) ; U107.J4 v2(92.13,125.62)
  BOTTOM w0.127: v1(83.31,130.94) 84.84,130.94 90.04,125.73 92.01,125.73 v2(92.13,125.62) 93.09,126.58 93.09,127.89 95.5,130.3 97.41,130.3 98.01,130.9 v1(101.17,130.9) ; U2.46 v1(131.73,122)
IFC_AD7: length 118.3
  TOP w0.127: v1(83.82,131.57) 83.06,131.57 80.77,129.29 80.77,123.19 78.87,121.29 73.03,121.29 66.02,114.28 U65.A10 ; U107.H4 v2(92.13,126.42) ; U1.A8 148.6,108.85 134.45,123 v1(131.73,123) 126.93,123 125.86,121.92 123.32,121.92 122.68,121.29 115.19,121.29 104.57,131.9 U4.36 v1(101.17,131.9)
  BOTTOM w0.127: v1(101.17,131.9) 98.37,131.9 97.16,130.68 95.25,130.68 92.71,128.14 92.71,127 v2(92.13,126.42) 89.99,126.42 84.84,131.57 v1(83.82,131.57) ; U2.44 v1(131.73,123)
IFC_AD8: length 127.1
  TOP w0.127: U1.B9 155.69,109.22 148.72,109.22 134.44,123.5 v1(130.98,123.5) ; U65.A6 62.02,114.85 72.77,125.6 v1(72.77,134.87) SW1.1 ; U4.50 v1(103.84,124.9)
  L3SIG w0.102: v1(72.77,134.87) 72.77,133.86 78.99,127.64 84.84,127.64 86.47,126 93.08,126 93.88,125.2 93.88,125.2 94.11,124.97 94.11,124.97 94.74,124.33 96.9,124.33 97.47,124.9 v1(103.84,124.9) 112.67,124.9 114.18,123.39 114.86,123.39 115.29,123.83 118.11,123.83 118.44,123.5 v1(130.98,123.5)
  BOTTOM w0.127: U2.43 v1(130.98,123.5)
IFC_AD9: length 127.1
  TOP w0.127: U1.A9 155.29,109.62 148.82,109.62 134.87,123.57 134.87,124.08 134.46,124.5 v1(131.73,124.5) ; U65.B7 62.51,113.43 62.51,114.84 73.15,125.48 73.15,133.73 74.04,134.62 v1(74.04,136.14) SW1.2 ; U4.48 v1(103.84,125.9)
  L3SIG w0.102: v1(74.04,136.14) 74.04,133.1 79.12,128.02 84.96,128.02 86.14,126.83 94.91,126.83 95.84,125.9 v1(103.84,125.9) 112.86,125.9 114.43,124.33 114.94,124.33 115.44,124.84 118.11,124.84 118.45,124.5 v1(131.73,124.5)
  BOTTOM w0.127: U2.41 v1(131.73,124.5)
IFC_AD10: length 126.3
  TOP w0.127: U65.A7 63.02,114.83 73.53,125.35 73.53,133.6 75.31,135.38 v1(75.31,136.52) SW1.3 ; v1(130.98,125) 134.59,125 135.25,124.33 135.25,123.7 148.49,110.46 155.3,110.46 U1.A10 ; U4.46 v1(103.84,126.9)
  L3SIG w0.102: v1(75.31,136.52) 75.31,132.59 79.25,128.65 86.61,128.65 87.76,127.51 90.81,127.51 91.06,127.76 96.01,127.76 96.87,126.9 v1(103.84,126.9) 112.75,126.9 114.3,125.35 114.94,125.35 115.44,125.86 118.24,125.86 119.1,125 v1(130.98,125)
  BOTTOM w0.127: U2.40 v1(130.98,125)
IFC_AD11: length 125.3
  TOP w0.127: SW1.4 v1(76.58,136.52) 76.58,136.14 73.91,133.48 73.91,125.14 63.52,114.74 63.52,113.43 U65.B8 ; U4.44 v1(103.84,127.9) ; v1(131.73,126) 134.48,126 135.64,124.84 135.64,123.83 148.59,110.87 155.74,110.87 U1.B11
  L3SIG w0.102: v1(131.73,126) 118.86,126 118.49,126.37 114.43,126.37 113.41,127.38 112.78,127.38 112.26,127.9 v1(103.84,127.9) 97.4,127.9 96.65,128.65 95.89,128.65 95.67,128.44 91.02,128.44 90.42,129.03 83.31,129.03 80.52,131.83 79.12,131.83 76.58,134.37 v1(76.58,136.52)
  BOTTOM w0.127: U2.38 v1(131.73,126)
IFC_AD12: length 124
  TOP w0.127: U65.A8 64.02,114.56 74.3,124.84 74.3,133.35 76.84,135.89 77.22,135.89 v1(77.85,136.52) SW1.5 ; U4.41 v1(103.84,129.4) ; v1(130.98,126.5) 134.62,126.5 136.02,125.09 136.02,123.95 148.72,111.25 U1.A11
  L3SIG w0.102: v1(130.98,126.5) 118.99,126.5 117.68,127.81 112.85,127.81 111.26,129.4 v1(103.84,129.4) 102.12,129.4 101.68,129.84 100.89,129.84 100.46,129.41 94.87,129.41 94.23,128.78 91.31,128.78 90.68,129.41 87.25,129.41 84.43,132.23 79.6,132.23 77.85,133.98 v1(77.85,136.52)
  BOTTOM w0.127: U2.37 v1(130.98,126.5)
IFC_AD13: length 125.2
  TOP w0.127: SW1.6 v1(79.12,136.52) 78.11,135.51 76.96,135.51 74.68,133.22 74.68,124.59 64.52,114.43 64.52,112.43 U65.C8 ; U1.B12 155.7,111.63 148.84,111.63 136.4,124.08 136.4,125.35 134.75,127 v1(131.73,127) ; U4.39 v1(103.84,130.4)
  L3SIG w0.102: v1(131.73,127) 119.13,127 117.98,128.14 113.28,128.14 111.03,130.4 v1(103.84,130.4) 97.25,130.4 96.89,130.03 89.78,130.03 89.38,130.43 86.74,130.43 84.45,132.72 80.39,132.72 79.12,133.98 v1(79.12,136.52)
  BOTTOM w0.127: U2.36 v1(131.73,127)
IFC_AD14: length 122.9
  TOP w0.127: U65.A9 65.02,114.29 75.06,124.33 75.06,133.1 77.09,135.13 78.99,135.13 v1(80.39,136.52) SW1.7 ; v1(130.98,127.5) 135.39,127.5 140.33,122.56 140.33,120.65 149.03,111.96 155.23,111.96 U1.A12 ; U4.37 v1(103.84,131.4)
  L3SIG w0.102: v1(130.98,127.5) 119.26,127.5 118.29,128.47 113.59,128.47 110.66,131.4 v1(103.84,131.4) 97.11,131.4 96.52,130.81 86.87,130.81 84.58,133.1 81.03,133.1 80.39,133.73 v1(80.39,136.52)
  BOTTOM w0.127: U2.35 v1(130.98,127.5)
IFC_AD15: length 120.8
  TOP w0.127: 81.66,137.54 v1(81.66,136.52) 79.88,134.75 77.22,134.75 75.44,132.97 75.44,124.21 65.52,114.28 65.52,113.43 U65.B9 ; v1(131.73,128.5) 134.9,128.5 141.35,122.05 141.35,120.14 148.63,112.86 155.3,112.86 U1.A13 ; U4.35 v1(103.84,132.4)
  L3SIG w0.102: v1(81.66,136.52) 85.78,132.4 v1(103.84,132.4) 110.3,132.4 113.36,129.34 117.93,129.34 119.38,127.89 120.52,127.89 121.13,128.5 v1(131.73,128.5)
  BOTTOM w0.127: U2.33 v1(131.73,128.5)
IFC_AVD: length 174.5
  TOP w0.127: U65.C9 v1(65.52,112.43) ; U107.C4 v2(92.13,131.22) ; U1.D17 157.3,116.46 151.89,116.46 150.62,117.73 148.46,117.73 144.53,121.67 144.53,122.56 135.51,131.57 130.68,131.57 v1(129.67,132.59) ; v1(86.36,127.38) 86.23,127.51 86.23,131.95 89.03,134.75 92.96,134.75 v1(94.74,136.52) 94.36,136.91 SW2.8
  L3SIG w0.102: v1(65.52,112.43) 65.66,112.57 65.66,121.79 68.07,124.21 68.07,136.65 68.96,137.54 68.96,138.37 71.69,141.1 90.17,141.1 v1(94.74,136.52)
  L6SIG w0.102: v1(129.67,132.59) 129.67,132.97 121.54,141.1 111.12,141.1 109.54,139.51 97.73,139.51 v1(94.74,136.52)
  BOTTOM w0.127: 129.76,132.5 130.17,132.08 130.17,121.54 130.72,121 U2.48 ; 129.76,132.5 v1(129.67,132.59) ; 129.76,132.5 U2.25 ; v2(92.13,131.22) 92.13,133.91 v1(94.74,136.52) 94.36,136.91 R801.1
IFC_CLE: length 140.2
  TOP w0.127: U1.F16 v2(158.92,115.65) ; SW2.1 v1(85.47,136.52) 85.09,136.14 85.09,126.49 v1(85.22,126.37) 85.09,126.24 85.09,122.43 74.09,111.43 71.52,111.43 U65.D15 ; U107.D5 v2(92.93,129.62)
  L6SIG w0.102: v1(85.47,136.52) 87.5,138.56 92.84,138.56 94.23,137.16 94.23,136.27 94.49,136.02 95,136.02 96.65,137.67 98.93,137.67 100.51,136.09 101.04,136.09 101.22,136.27 101.22,136.91 102.62,138.3 110.62,138.3 112.27,139.95 121.16,139.95 127.51,133.6 127.51,131.06 130.3,128.27 130.3,126.49 131.32,125.48 132.84,125.48 133.73,124.59 134.2,124.59 135.09,123.7 140.08,123.7 141.86,121.92 141.86,120.14 147.32,114.68 155.7,114.68 156.25,115.23 158.5,115.23 v2(158.92,115.65)
  BOTTOM w0.127: v2(92.93,129.62) 90.86,129.62 85.47,135 v1(85.47,136.52)
IFC_CLK: length 95.3
  TOP w0.127: v1(68.45,108.46) 68.45,106.37 68.02,105.93 U65.J12
  BOTTOM w0.127: R12.2 152.5,115.57 152.44,115.51 149.67,115.51 147.19,117.98 114,117.98 112.48,116.46 95.25,116.46 91.57,112.78 91.57,109.52 90.63,108.59 76.45,108.59 74.93,107.06 69.72,107.06 68.45,108.33 v1(68.45,108.46)
IFC_CLK_R: length 1.6
  TOP w0.127: v2(154.69,115.95) 154.78,116.05 U1.A17
  BOTTOM w0.127: v2(154.69,115.95) 154.56,115.95 154.18,115.57 R12.1
IFC_CS0_N: length 135
  TOP w0.127: v1(116.59,137.16) 110.62,137.16 106.81,140.97 74.42,140.97 72.01,138.56 72.01,125.63 61.51,115.13 v1(61.51,113.43) 62.02,112.93 U65.B6 ; U1.C13 v2(156.52,112.45)
  L6SIG w0.102: v2(156.52,112.45) 156.29,112.45 155.83,112.9 146.43,112.9 139.06,120.27 129.16,120.27 124.84,124.59 124.84,132.72 120.4,137.16 v1(116.59,137.16)
  BOTTOM w0.127: R11.1 61.01,113.87 61.45,113.43 v1(61.51,113.43)
IFC_CS1_N: length 139.9
  TOP w0.127: U65.B5 61.02,112.93 v1(60.51,113.43) 60.51,115.12 71.25,125.86 71.25,138.81 74.17,141.73 107.06,141.73 110.11,138.68 v1(114.3,138.68) ; U1.E15 v2(158.12,114.85)
  L6SIG w0.102: v2(158.12,114.85) 157.44,114.17 147.06,114.17 141.35,119.89 141.35,121.67 139.86,123.16 133.76,123.16 133.35,123.57 131.69,123.57 131.18,123.06 128.52,123.06 126.75,124.84 126.75,133.35 120.9,139.19 114.81,139.19 v1(114.3,138.68)
  BOTTOM w0.127: R10.1 60.51,114.83 v1(60.51,113.43)
IFC_CS2_N: length 135.6
  TOP w0.127: v1(111.12,139.57) 109.73,139.57 106.55,142.75 74.68,142.75 70.87,138.94 70.87,125.98 60.01,115.13 v1(60.01,114.53) 60.02,114.53 U65.A4 ; U1.D16 v2(157.32,115.65)
  L6SIG w0.102: v2(157.32,115.65) 156.91,116.05 156.31,116.05 155.19,114.94 147.45,114.94 142.11,120.27 142.11,122.05 140.21,123.95 135.25,123.95 134.24,124.97 133.86,124.97 133.48,125.35 133.48,126.49 132.33,127.64 131.57,127.64 127.89,131.32 127.89,133.73 121.29,140.33 111.89,140.33 v1(111.12,139.57)
  BOTTOM w0.127: v1(60.01,114.53) 59.34,114.53 59.01,114.86 R9.1
IFC_NDWE_N: length 104.6
  TOP w0.127: U107.C7 v2(95.33,131.22) ; U1.D14 v2(157.32,113.25)
  L6SIG w0.102: v2(157.32,113.25) 157.32,113.45 156.82,113.94 146.91,113.94 139.57,121.29 133.19,121.29 132.04,122.43 128.65,122.43 126.37,124.71 126.37,133.22 120.78,138.81 115.19,138.81 113.92,137.54 103,137.54 102.49,137.03 102.49,135.76 101.47,134.75 100.46,134.75 98.93,136.27 98.93,136.78 98.43,137.29 96.77,137.29 95.12,135.64 94.49,135.64 93.85,136.27 93.85,137.03 92.71,138.18 88.39,138.18 87.25,137.03 87.25,135.76 90.55,132.46 94.08,132.46 v2(95.33,131.22)
IFC_OE_N: length 141.7
  TOP w0.127: U65.G15 71.52,108.43 74.14,108.43 87.5,121.79 v1(87.5,124.71) 87.63,124.84 87.63,126.37 88.01,126.75 88.01,131.7 89.54,133.22 94.36,133.22 97.03,135.89 97.03,137.92 97.54,138.43 99.19,138.43 99.44,138.18 SW3.2 v1(99.44,136.52) 99.44,134.37 100.91,132.9 U4.34 ; U107.D4 v2(92.93,130.42) ; U1.D15 v2(157.32,114.85)
  L6SIG w0.102: v1(99.44,136.52) 100.2,135.76 101.22,135.76 101.47,136.02 101.47,136.65 102.74,137.92 110.74,137.92 112.39,139.57 121.03,139.57 127.13,133.48 127.13,129.03 130.3,125.86 130.3,124.97 131.32,123.95 133.48,123.95 133.98,123.44 139.95,123.44 141.6,121.79 141.6,120.02 147.19,114.43 156.97,114.43 157.32,114.77 v2(157.32,114.85)
  BOTTOM w0.127: R803.1 v1(99.44,136.52) 98.81,135.89 97.41,135.89 93.47,131.95 93.47,130.96 v2(92.93,130.42)
IFC_RB0_N: length 117.2
  TOP w0.127: U65.A15 v1(71.52,114.43) 75.33,118.24 79.88,118.24 84.33,122.68 84.33,138.56 86.36,140.59 106.68,140.59 110.62,136.65 124.08,136.65 130.37,130.36 134.56,130.36 150.11,114.81 155.75,114.81 U1.B15
  BOTTOM w0.127: R7.1 71.32,114.63 v1(71.52,114.43)
IFC_RB1_N: length 115.5
  TOP w0.127: U1.A15 149.97,114.45 134.46,129.96 130.14,129.96 123.83,136.27 110.49,136.27 106.55,140.21 86.49,140.21 84.71,138.43 84.71,122.56 80.01,117.86 76.95,117.86 v1(72.52,113.43) U65.B16
  BOTTOM w0.127: R6.1 72.72,113.23 v1(72.52,113.43)
IFC_TE: length 129.6
  TOP w0.127: U65.D11 v1(67.52,111.43) ; 86.74,137.54 v1(86.74,138.56) 88.01,139.83 101.73,139.83 102.49,139.06 107.19,139.06 110.36,135.89 123.57,135.89 130.43,129.03 134.87,129.03 141.73,122.17 141.73,120.27 148.72,113.28 155.75,113.28 U1.B14
  L3SIG w0.102: v1(86.74,138.56) 85.34,139.95 73.03,139.95 69.22,136.14 69.22,123.83 66.8,121.41 66.8,112.15 v1(67.52,111.43)
IFC_VA5: length 4.7
  TOP w0.127: U4.55 104.8,122.4 105.98,121.22 U10.4
IFC_VA6: length 1.4
  TOP w0.127: U9.4 102.44,120.55 U4.56
IFC_VA7: length 14.7
  TOP w0.127: U8.4 109.54,121.6 v1(109.09,122.05) ; v1(115.7,122.3) 116.1,121.9 U4.1
  BOTTOM w0.127: v1(109.09,122.05) 109.35,122.3 v1(115.7,122.3)
IFC_WE_N: length 141.1
  TOP w0.127: U4.13 115.18,127.9 v1(114.17,128.91) ; U65.H15 71.52,107.43 74.15,107.43 89.41,122.68 89.41,132.46 89.79,132.84 94.49,132.84 v1(98.17,136.52) SW3.1 ; U1.D13 v2(157.32,112.45)
  L6SIG w0.102: v1(98.17,136.52) 98.17,136.02 100.15,134.04 102.57,134.04 103.13,133.47 104.27,133.47 108.84,128.91 v1(114.17,128.91) 114.17,135.76 116.08,137.67 120.4,137.67 125.22,132.84 125.22,124.59 129.26,120.55 139.17,120.55 146.54,113.16 155.96,113.16 156.29,112.83 156.79,112.83 157.17,112.45 v2(157.32,112.45)
  BOTTOM w0.127: R804.1 v1(98.17,136.52)
IFC_WP_N: length 137.8
  TOP w0.127: U107.C3 v2(92.13,130.42) ; v1(100.71,136.52) SW3.3 100.71,138.43 100.33,138.81 97.41,138.81 96.65,138.05 96.65,136.02 94.23,133.6 89.41,133.6 87.5,131.7 v1(87.5,129.92) 87.63,129.79 87.63,126.89 87.25,126.51 87.25,125.22 87,124.97 87,121.79 74.13,108.93 U65.F16 ; U1.F17 v2(158.92,116.45)
  L6SIG w0.102: v1(100.71,136.52) 100.71,136.91 102.49,138.68 109.24,138.68 111.28,140.72 121.41,140.72 128.27,133.86 128.27,131.32 131.57,128.02 132.46,128.02 136.27,124.21 140.36,124.21 142.37,122.2 142.37,120.4 147.57,115.19 155.07,115.19 156.13,116.26 158.33,116.26 158.52,116.45 v2(158.92,116.45)
  BOTTOM w0.127: v2(92.13,130.42) 92.52,130.02 93.32,130.02 93.85,130.56 93.85,131.7 97.66,135.51 99.7,135.51 v1(100.71,136.52) R802.1
INA_VCORE_N: length 4.7
  TOP w0.127: R982.1 114.56,94.23 C1378.2 114.17,94.24 113.92,94.49 113.92,95 112.78,96.13 U111.9
INA_VCORE_P: length 4.2
  TOP w0.127: R981.1 114.56,95.25 C1378.1 114.18,95.24 112.79,96.63 U111.10
IO_B14: length 0.7
  TOP w0.127: U65.B14 v1(70.52,113.43)
IO_T10: length 16
  TOP w0.127: J61.1 58.8,93.6 63.41,93.6 66.02,96.2 v1(66.02,98.19) U65.T10
  BOTTOM w0.127: v1(66.02,98.19) 65.98,98.16 R1016.1
IOPWR_EN: length 390.8
  TOP w0.127: U105.16 212.6,62.48 212.98,62.86 v1(212.98,63.24) 213.49,63.75 R925.2 C1231.2 213.62,66.92 212.72,67.82 v1(212.72,77.22) ; R670.1 15.62,71.37 v1(15.11,71.88) ; C956.2 R750.2 20.95,115.44 v1(21.46,114.94) 21.97,114.94 22.23,114.68 U88.16 ; v1(64.52,99.42) 64.02,99.92 U65.R8 ; U86.16 198.88,75.82 199.26,75.44 v1(199.64,75.44) 200.15,74.93 R732.2 C938.2 ; C1235.2 R927.2 266.45,63.75 v1(265.94,63.25) 265.94,62.86 265.56,62.48 U106.16
  L3SIG w0.102: v1(21.46,114.94) 22.73,116.2 26.16,116.2 29.08,113.28 39.37,113.28 v1(47.75,104.9) 48.26,104.9 53.17,99.99 63.95,99.99 v1(64.52,99.42) ; v1(212.98,63.24) 219.08,63.24 221.23,61.09 221.23,49.66 225.36,45.53 247.59,45.53 247.84,45.78 247.84,50.48 248.28,50.93 251.33,50.93 252.35,51.94 252.35,64.01 256.03,67.69 265.68,67.69 266.19,67.18 266.19,65.91 265.94,65.66 v1(265.94,63.25)
  L6SIG w0.102: v1(212.72,77.22) 212.22,76.71 204.85,76.71 203.2,75.06 200.02,75.06 v1(199.64,75.44) 197.99,73.79 193.29,73.79 191.52,75.57 189.61,75.57 186.75,78.42 153.73,78.42 152.4,77.09 111,77.09 110.17,77.91 82.17,77.91 79.44,80.65 77.47,80.65 74.68,83.44 74.68,84.58 71.25,88.01 71.25,91.69 64.52,98.43 v1(64.52,99.42) ; v1(47.75,104.9) 47.75,96.27 45.34,93.85 41.91,93.85 38.23,90.17 38.23,83.82 32.77,78.36 29.72,78.36 26.92,75.57 26.92,73.15 25.78,72.01 18.92,72.01 18.29,71.37 16.13,71.37 15.62,71.88 v1(15.11,71.88)
IOPWR_EN_N: length 65.2
  TOP w0.127: R681.1 79.89,83.19 v1(80.26,83.57) ; R666.1 42.43,104.15 v1(42.67,104.39) ; v1(66.52,100.42) 66.02,100.92 U65.P10 ; R682.1 v1(43.56,95.5)
  L3SIG w0.102: v1(66.52,100.42) 66.02,99.92 66.02,99.16 65.77,98.92 53.86,98.92 48.39,104.39 v1(42.67,104.39)
  L6SIG w0.102: v1(43.56,95.5) 44.2,96.14 44.2,103.51 43.31,104.39 v1(42.67,104.39) ; v1(80.26,83.57) 77.34,83.57 71.76,89.15 71.76,91.95 67.02,96.69 67.02,99.92 v1(66.52,100.42)
JTAG_TCK: length 104
  TOP w0.127: U20.10 70.16,142.93 v1(70.87,143.64) ; U1.E18 v2(158.12,117.25)
  L6SIG w0.102: v2(158.12,117.25) 157.7,117.66 152.29,117.66 151.97,117.98 150.62,117.98 150.24,118.36 147.7,118.36 144.53,121.54 144.53,123.19 137.29,130.43 133.35,130.43 132.08,131.7 132.08,133.6 122.5,143.19 98.99,143.19 97.16,141.35 73.66,141.35 71.37,143.64 v1(70.87,143.64)
JTAG_TDI: length 101.3
  TOP w0.127: U20.12 69.56,143.73 v1(70.1,144.27) ; U1.A18 v2(154.92,117.25)
  L6SIG w0.102: v1(70.1,144.27) 70.1,143.64 70.54,143.21 71.42,143.21 73.53,141.1 97.54,141.1 99.25,142.81 122.36,142.81 131.7,133.48 131.7,131.57 133.22,130.05 137.29,130.05 144.27,123.06 144.27,121.41 147.57,118.11 150.11,118.11 150.56,117.67 151.83,117.67 152.25,117.25 v2(154.92,117.25)
JTAG_TDO: length 104.2
  TOP w0.127: v1(71.25,142.37) 71.37,142.49 71.37,143.89 71.12,144.14 70.75,144.14 69.93,143.33 U20.11 ; U1.C18 v2(156.52,117.25)
  L6SIG w0.102: v2(156.52,117.25) 156.26,117.25 155.6,116.59 152.15,116.59 151.73,117 150.46,117 149.86,117.6 147.32,117.6 143.76,121.16 143.76,122.81 141.6,124.97 137.92,124.97 134.37,128.52 133.35,128.52 130.94,130.94 130.94,133.22 122.1,142.06 99.26,142.06 97.79,140.59 73.03,140.59 v1(71.25,142.37)
JTAG_TMS: length 101.6
  TOP w0.127: U1.B18 v2(155.72,117.25) ; U20.9 70.23,142.53 70.36,142.4 v1(70.36,142.37)
  L6SIG w0.102: v1(70.36,142.37) 70.48,142.37 70.99,142.87 71.37,142.87 73.41,140.84 97.66,140.84 99.26,142.44 122.23,142.44 131.32,133.35 131.32,131.19 133.6,128.91 134.49,128.91 138.18,125.22 141.73,125.22 144.02,122.94 144.02,121.29 147.45,117.86 149.99,117.86 150.5,117.35 151.77,117.35 152.28,116.84 155.31,116.84 v2(155.72,117.25)
JTAG_TRST_N: length 133.9
  TOP w0.127: U1.D19 157.32,117.25 v2(157.31,117.25) ; v1(110.24,141.6) 108.71,143.13 74.51,143.13 70.48,139.11 70.48,126.11 59.51,115.14 59.51,113.43 60.02,112.93 U65.B4
  L6SIG w0.102: v2(157.31,117.25) 156.77,116.71 156.01,116.71 155.63,116.33 152.02,116.33 151.67,116.68 150.4,116.68 149.73,117.35 147.19,117.35 143.51,121.03 143.51,122.68 141.48,124.71 136.65,124.71 130.56,130.81 130.56,133.1 121.92,141.73 110.36,141.73 v1(110.24,141.6)
LED_STATUS: length 131.4
  TOP w0.127: R702.1 30.09,10.68 29.59,11.18 21.21,11.18 16.64,15.75 16.64,53.98 v1(17.27,54.61) ; U65.D2 58.01,110.93 v1(57.51,110.43)
  L6SIG w0.102: v1(17.27,54.61) 36.07,73.41 36.07,80.52 38.99,83.44 38.99,89.79 41.4,92.2 44.83,92.2 51.18,98.55 51.18,105.6 56.01,110.43 v1(57.51,110.43)
MPEX1_REFCLK_N: length 116.7
  TOP w0.102: J19.13 181.09,208.68 181.2,208.79 181.2,209.1 181.31,209.2 182.22,209.2 184.28,207.14 184.28,191.01 191.2,184.09 191.2,171.16 v1(190.92,170.88) ; R526.2 237.49,142.49 237.49,142.76 R528.2 237.35,143.14 237.59,143.38 237.59,145.39 v1(237.31,145.67)
  BOTTOM w0.102: v1(237.31,145.67) 237.59,145.95 237.59,149.33 238.12,149.86 238.12,160.66 230.5,168.27 192.52,168.27 191.2,169.59 191.2,170.6 v1(190.92,170.88)
MPEX1_REFCLK_P: length 116.8
  TOP w0.102: v1(191.76,170.88) 191.48,171.16 191.48,184.2 184.56,191.12 184.56,207.25 182.33,209.48 J19.11 ; v1(238.15,145.67) 237.87,145.39 237.87,143.38 238.12,143.14 R524.2 238,142.76 238,142.49 R525.2
  BOTTOM w0.102: v1(238.15,145.67) 237.87,145.95 237.87,149.21 238.4,149.74 238.4,160.77 230.62,168.55 192.63,168.55 191.48,169.71 191.48,170.6 v1(191.76,170.88)
MPEX1_RST_N: length 443
  TOP w0.127: v1(252.09,157.61) 250.32,157.61 238.38,169.54 197.87,169.54 193.55,173.86 193.55,201.69 192.79,202.45 190.37,202.45 189.79,201.88 J19.22 ; U65.T2 v1(58.51,99.42)
  L6SIG w0.102: v1(252.09,157.61) 253.11,156.59 273.69,156.59 277.37,152.91 277.37,145.67 278.93,144.1 278.93,82.21 274.7,77.98 228.85,77.98 226.95,76.07 215.39,76.07 208.79,69.47 181.86,69.47 177.04,74.3 159.64,74.3 159.13,73.79 93.85,73.79 93.09,74.55 76.58,74.55 75.31,75.82 71.88,75.82 69.6,78.11 69.6,82.68 67.69,84.58 67.69,85.85 59.01,94.53 59.01,98.92 v1(58.51,99.42)
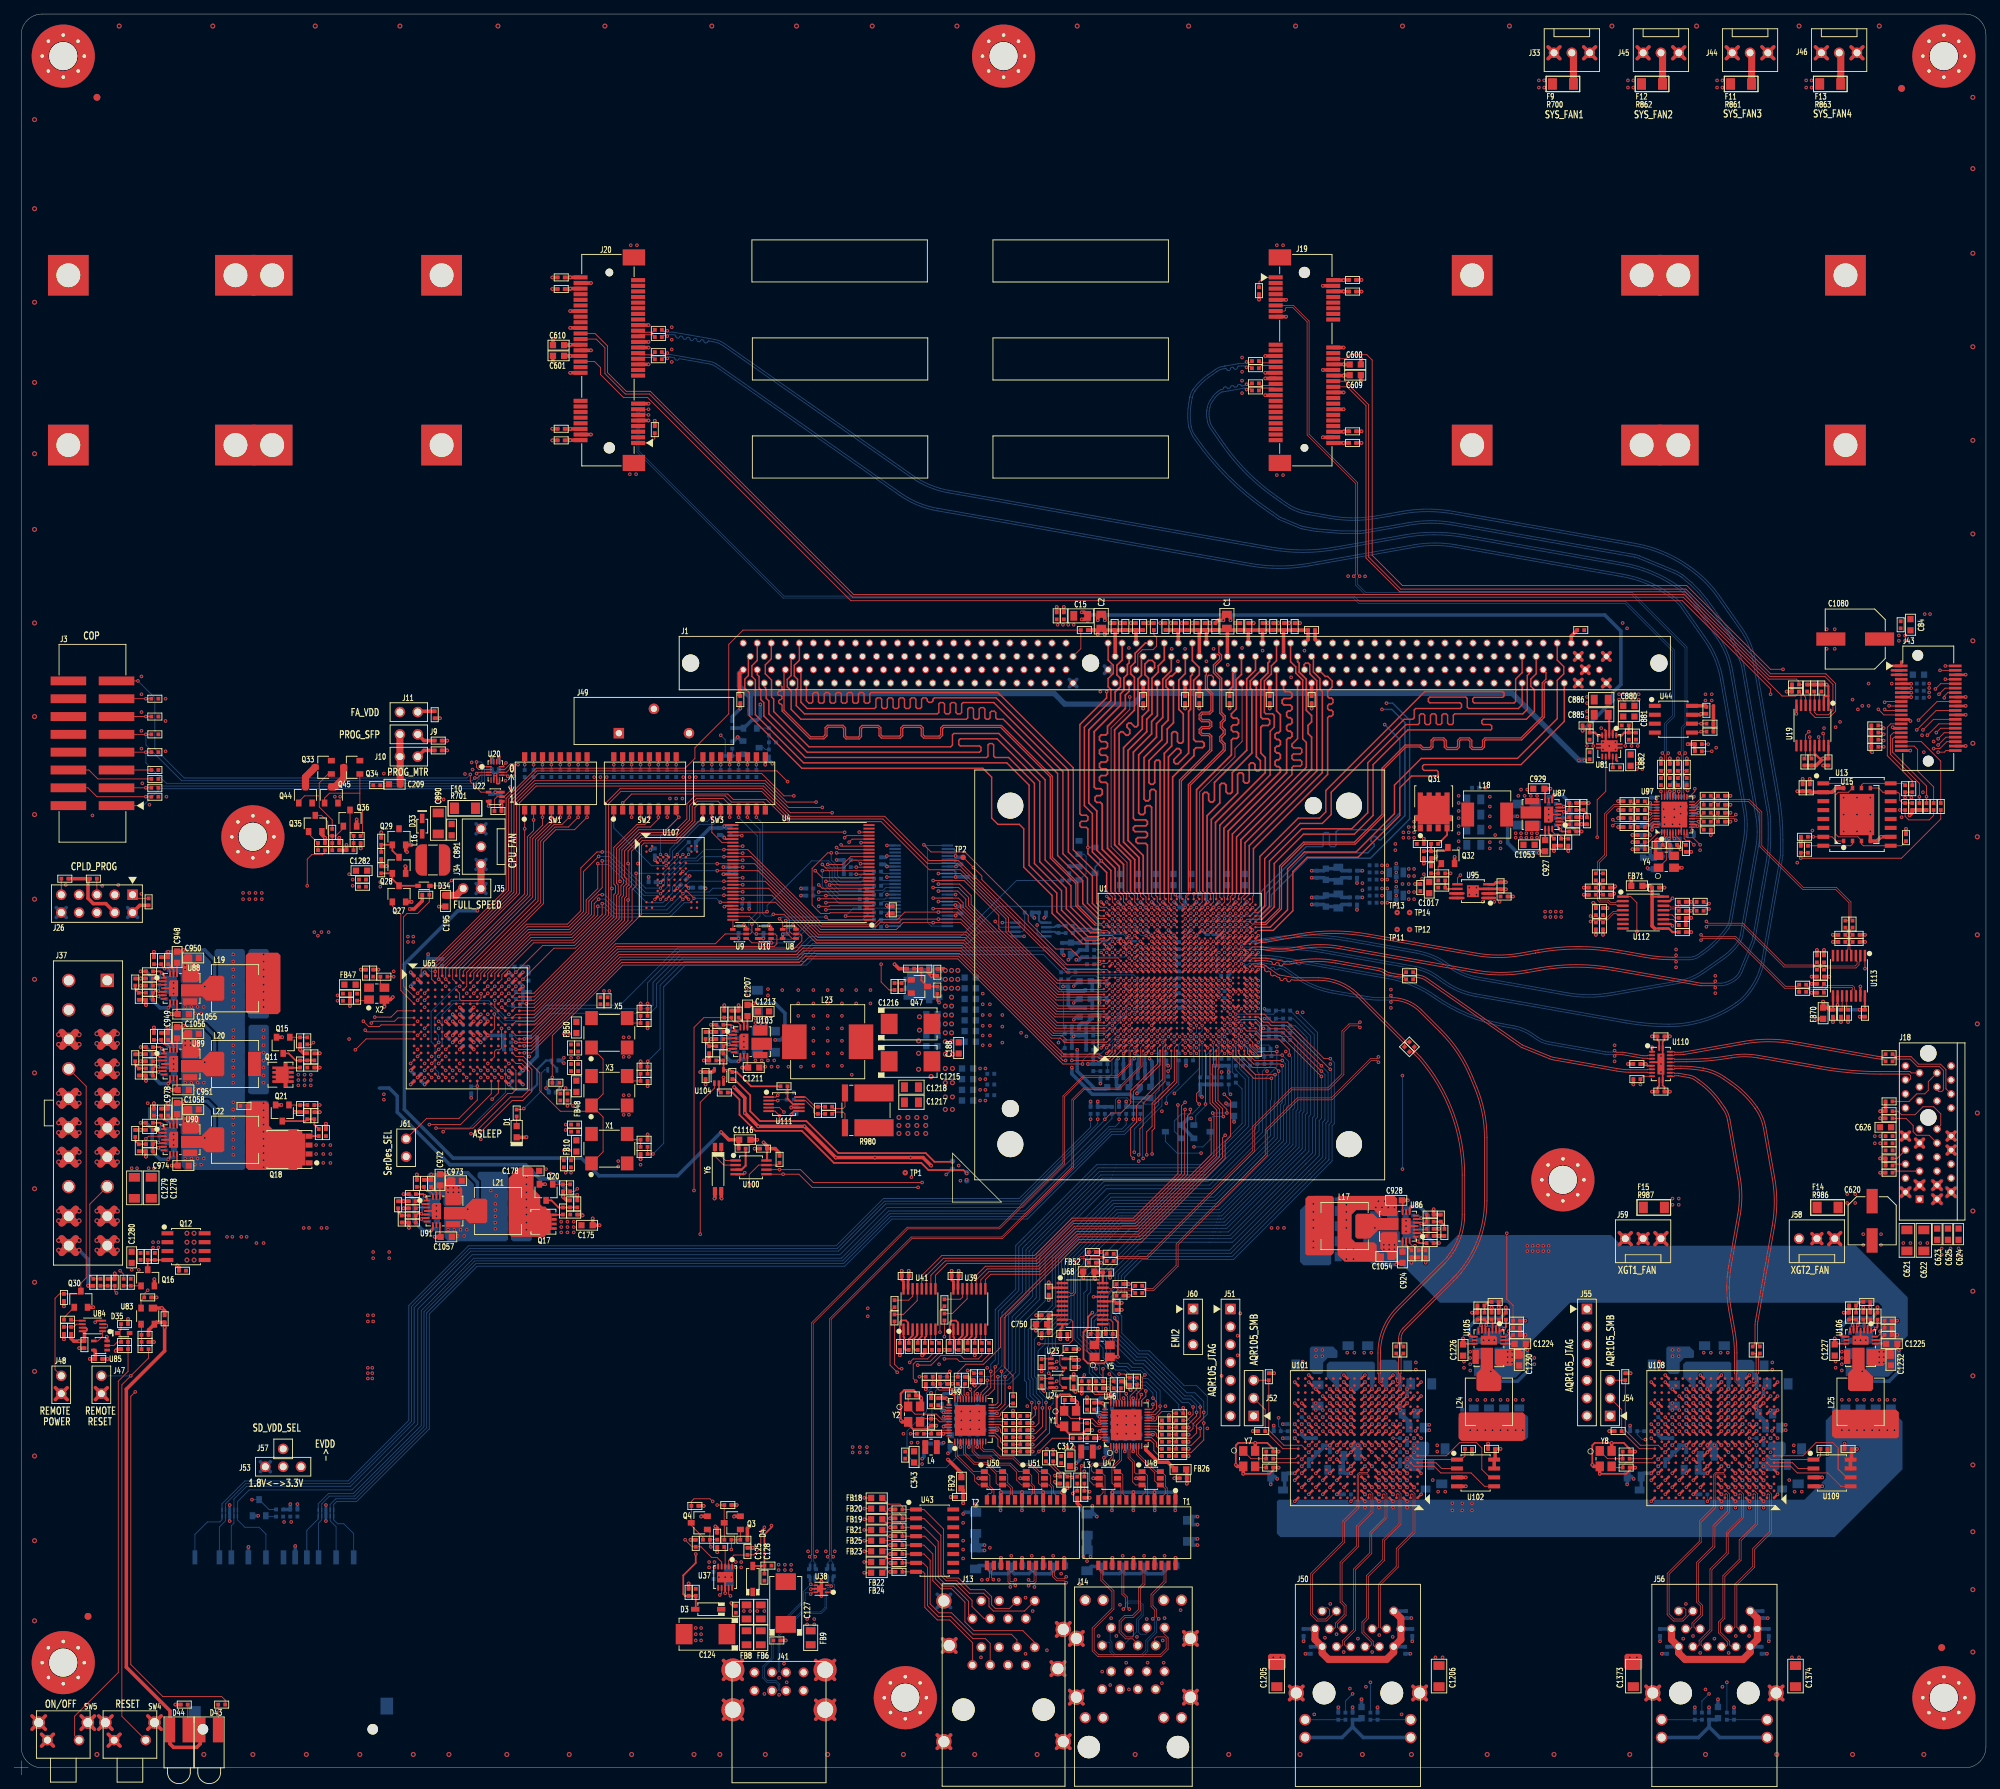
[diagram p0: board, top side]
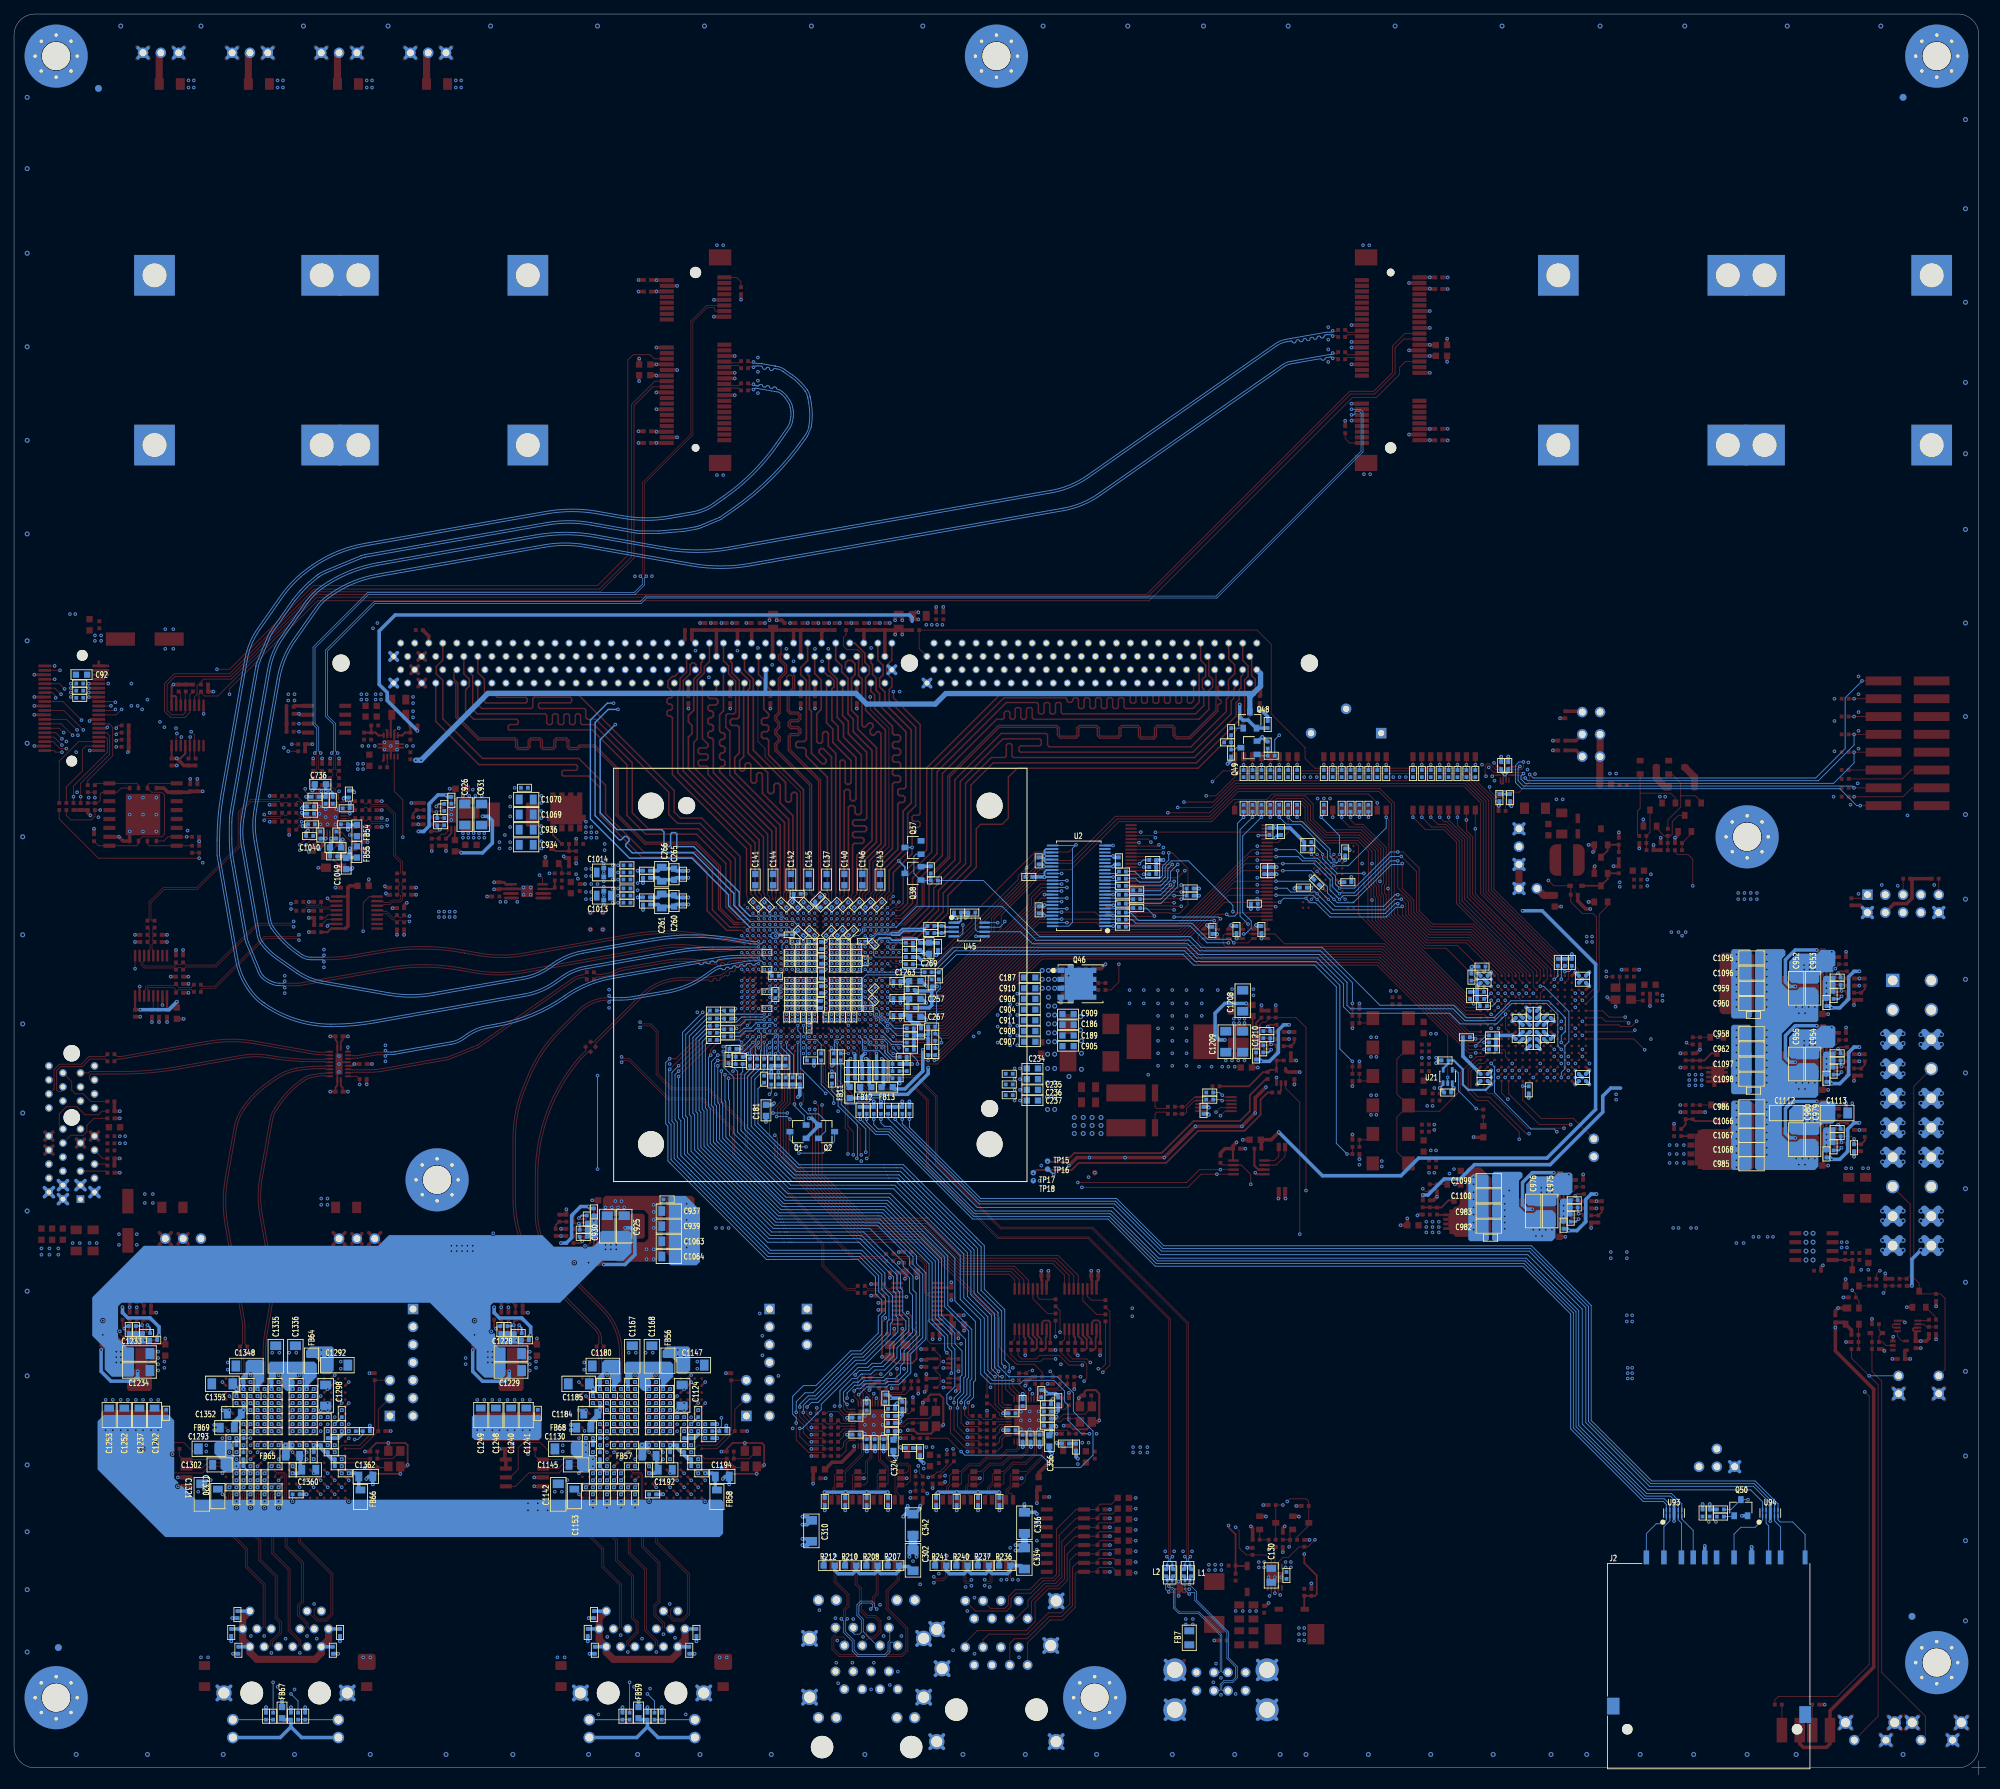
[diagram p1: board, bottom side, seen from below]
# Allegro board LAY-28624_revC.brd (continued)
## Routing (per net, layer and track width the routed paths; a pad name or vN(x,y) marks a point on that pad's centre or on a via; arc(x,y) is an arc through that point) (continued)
MPEX1_RX_N: length 224.4
  TOP w0.127: v1(175.64,201.42) 175.77,201.29 176.16,201.29 C1266.2 ; v1(242.44,113.15) 242.44,112.99 arc(242.41,112.9) 242.32,112.86 240.42,112.86 227.84,115.06 arc(222.61,115.51) 217.38,115.05 215.48,114.71 arc(211.91,114.4) 208.33,114.71 189.02,118.12 arc(186.18,118.37) 183.35,118.12 182.31,117.94 arc(180.39,117.77) 178.47,117.93 178.09,118 arc(177.87,118.03) 177.65,118.04 176.72,118.04 arc(176.53,118) 176.36,117.89 U1.AG19
  BOTTOM w0.127: v1(175.64,201.42) 175.64,201.41 arc(175.43,201.27) 175.18,201.22 174.92,201.22 arc(174.7,201.21) 174.49,201.18 174.43,201.17 172.56,200.84 172.55,200.84 172.26,200.79 arc(171.72,200.63) 171.24,200.37 171.19,200.33 170.08,199.55 arc(168.94,198.6) 167.98,197.46 167.98,197.46 arc(167.72,196.97) 167.56,196.44 167.55,196.39 167.41,195.57 arc(167.26,193.88) 167.4,192.19 arc(167.4,192.16) 167.41,192.13 167.94,190.86 168.33,190.3 arc(172.85,184.91) 178.23,180.39 180.28,178.96 183.08,177.79 arc(183.21,177.74) 183.34,177.7 183.55,177.64 arc(183.69,177.6) 183.83,177.57 185.55,177.27 189.12,176.97 191.81,176.98 191.84,176.98 arc(192.06,176.99) 192.28,177.01 198.78,178.16 arc(201.95,178.44) 205.12,178.16 230.93,173.61 arc(230.95,173.6) 230.97,173.6 230.97,173.6 arc(231.21,173.54) 231.45,173.46 236.53,171.36 arc(237.05,171.11) 237.54,170.8 237.54,170.8 arc(237.62,170.75) 237.69,170.69 238.85,169.71 239.98,168.58 241.02,167.35 241.02,167.35 244.24,162.75 arc(244.37,162.53) 244.48,162.31 246.04,158.55 arc(246.13,158.28) 246.2,158.01 249.84,137.31 arc(249.95,136.55) 249.98,135.78 249.98,133.43 arc(249.92,131.83) 249.71,130.25 247.76,119.2 arc(247.7,118.97) 247.63,118.74 245.86,114.47 arc(245.71,114.18) 245.49,113.92 arc(244.95,113.47) 244.34,113.15 244.06,113.03 arc(243.65,112.91) 243.22,112.86 242.57,112.86 arc(242.48,112.9) 242.44,112.99 v1(242.44,113.15)
MPEX1_RX_P: length 224.3
  TOP w0.127: v1(175.64,200.66) 175.77,200.79 176.16,200.79 C1265.2 ; U1.AH19 176.96,117.69 177.65,117.69 arc(177.84,117.68) 178.03,117.65 178.41,117.58 arc(180.39,117.41) 182.37,117.58 183.41,117.77 arc(186.18,118.01) 188.95,117.77 208.27,114.36 arc(211.91,114.04) 215.54,114.36 217.44,114.7 arc(222.61,115.15) 227.78,114.71 240.39,112.51 arc(240.4,112.51) 240.42,112.51 242.32,112.51 arc(242.41,112.47) 242.44,112.38 v1(242.44,112.23)
  BOTTOM w0.127: v1(175.64,200.66) 175.62,200.68 arc(175.42,200.82) 175.18,200.86 174.92,200.86 arc(174.73,200.86) 174.55,200.83 174.51,200.82 arc(174.38,200.75) 174.33,200.62 174.33,200.59 arc(174.28,200.46) 174.16,200.39 174.05,200.37 arc(173.91,200.4) 173.83,200.52 arc(173.76,200.64) 173.62,200.67 173.5,200.65 arc(173.38,200.57) 173.33,200.44 173.33,200.42 arc(173.28,200.28) 173.16,200.21 173.05,200.19 arc(172.91,200.22) 172.83,200.34 arc(172.76,200.46) 172.62,200.49 172.61,200.49 172.32,200.44 arc(171.86,200.3) 171.44,200.07 171.39,200.04 170.28,199.26 arc(169.19,198.35) 168.28,197.26 168.27,197.25 arc(168.04,196.84) 167.91,196.38 167.9,196.33 167.76,195.51 arc(167.61,193.88) 167.75,192.25 167.76,192.19 arc(167.93,191.6) 168.23,191.06 168.62,190.5 arc(173.1,185.16) 178.44,180.68 180.45,179.27 183.22,178.12 arc(183.33,178.08) 183.44,178.04 183.66,177.98 arc(183.78,177.95) 183.9,177.92 185.6,177.62 189.14,177.33 191.81,177.33 arc(192.03,177.34) 192.25,177.37 198.71,178.51 arc(201.95,178.79) 205.18,178.51 231.03,173.95 arc(231.32,173.88) 231.59,173.79 236.66,171.69 arc(237.22,171.42) 237.74,171.09 237.75,171.09 arc(237.84,171.03) 237.92,170.96 239.09,169.97 240.24,168.82 241.3,167.56 244.54,162.94 arc(244.69,162.71) 244.8,162.46 246.38,158.64 arc(246.48,158.38) 246.54,158.11 246.55,158.08 arc(246.55,158.08) 246.55,158.08 250.2,137.37 arc(250.3,136.58) 250.34,135.78 250.34,133.43 arc(250.27,131.8) 250.06,130.19 248.11,119.14 arc(248.05,118.87) 247.96,118.61 246.19,114.34 arc(246,113.98) 245.75,113.67 arc(245.15,113.18) 244.47,112.82 244.2,112.7 arc(243.72,112.56) 243.23,112.51 242.57,112.51 arc(242.48,112.47) 242.44,112.38 v1(242.44,112.23)
MPEX1_TX_N: length 226.5
  TOP w0.127: C599.2 176.21,198.17 175.72,198.17 v1(175.64,198.25) ; U1.AE19 v2(174.92,118.05)
  BOTTOM w0.127: v1(175.64,198.25) 175.49,198.1 arc(175.43,198.06) 175.36,198.04 175.35,198.04 arc(175.26,198.04) 175.17,198.03 175.01,198 175,198 arc(174.9,198.02) 174.84,198.11 174.84,198.12 arc(174.78,198.2) 174.68,198.22 174.47,198.18 arc(174.38,198.13) 174.34,198.03 174.34,198.01 arc(174.31,197.91) 174.22,197.86 174,197.82 arc(173.9,197.85) 173.84,197.93 arc(173.79,198.02) 173.68,198.04 173.47,198.01 arc(173.38,197.95) 173.34,197.86 173.34,197.83 arc(173.31,197.74) 173.22,197.69 173,197.65 arc(172.9,197.67) 172.84,197.76 172.84,197.76 arc(172.79,197.85) 172.68,197.87 172.46,197.83 arc(172.38,197.78) 172.34,197.68 172.34,197.67 arc(172.32,197.57) 172.23,197.51 171.94,197.46 arc(171.85,197.41) 171.76,197.35 171.49,197.16 arc(171.15,196.87) 170.87,196.54 170.48,195.98 arc(170.22,195.5) 170.06,194.97 169.97,194.46 169.97,194.44 arc(169.93,194) 169.97,193.56 170.08,192.95 arc(170.23,192.42) 170.5,191.94 172.15,189.57 arc(175.6,185.46) 179.71,182.01 181.17,180.99 arc(182.65,180.18) 184.28,179.7 187.47,179.14 arc(190.88,178.84) 194.3,179.14 197.9,179.78 arc(201.47,180.09) 205.04,179.78 231.01,175.2 arc(234.84,174.08) 238.34,172.16 238.74,171.88 arc(240.92,170.05) 242.75,167.87 246.04,163.17 arc(247.14,161.18) 247.77,159 251.16,139.78 arc(251.59,136.55) 251.73,133.29 251.73,131.11 249.1,116.2 arc(248.49,114.12) 247.45,112.21 247.24,111.92 arc(246.41,110.93) 245.42,110.1 245.41,110.09 arc(240.87,107.81) 235.86,107.03 235.73,107.03 arc(232.73,107.16) 229.75,107.55 208.32,111.33 arc(206.06,111.99) 204.01,113.12 202.81,113.95 arc(201.31,114.78) 199.67,115.26 186.43,117.59 arc(183.97,117.91) 181.5,118.02 174.94,118.02 v2(174.92,118.05)
MPEX1_TX_P: length 226.5
  TOP w0.127: U1.AD19 v2(174.12,118.05) ; C598.2 176.2,197.57 175.73,197.57 v1(175.64,197.48)
  BOTTOM w0.127: v1(175.64,197.48) 175.48,197.64 arc(175.43,197.68) 175.38,197.69 175.35,197.69 arc(175.29,197.69) 175.23,197.68 175.07,197.65 173.06,197.3 172.29,197.16 172.15,197.16 arc(172.05,197.12) 171.97,197.06 171.69,196.87 arc(171.4,196.62) 171.16,196.33 170.77,195.78 arc(170.55,195.36) 170.41,194.91 170.32,194.38 arc(170.29,194) 170.32,193.62 170.43,193.01 arc(170.56,192.56) 170.79,192.14 172.44,189.78 arc(175.85,185.71) 179.92,182.3 181.37,181.28 arc(182.79,180.5) 184.34,180.05 187.53,179.49 arc(190.88,179.2) 194.23,179.49 197.84,180.13 arc(201.47,180.44) 205.1,180.13 231.07,175.55 arc(234.98,174.41) 238.55,172.45 238.95,172.17 arc(241.18,170.3) 243.04,168.07 246.33,163.37 arc(247.46,161.31) 248.12,159.06 251.51,139.84 arc(251.94,136.58) 252.08,133.29 252.08,131.08 249.45,116.14 arc(248.82,113.98) 247.74,112.01 247.53,111.71 arc(246.66,110.68) 245.63,109.81 245.61,109.8 arc(240.98,107.47) 235.86,106.67 235.73,106.67 arc(232.7,106.8) 229.69,107.2 208.25,110.98 arc(205.93,111.66) 203.8,112.82 202.61,113.66 arc(201.17,114.45) 199.61,114.91 186.36,117.24 arc(183.94,117.56) 181.5,117.67 175.09,117.67 175.08,117.65 174.78,117.65 arc(174.53,117.7) 174.32,117.84 v2(174.12,118.05)
MPEX2_REFCLK_N: length 187.8
  TOP w0.102: R532.2 235.08,142.49 235.08,142.76 R534.1 234.93,143.14 235.18,143.38 235.18,145.39 v1(234.9,145.67) ; J20.13 v1(90.42,194.68)
  BOTTOM w0.102: v1(90.42,194.68) 89.18,194.68 88.77,194.27 88.77,188.59 109.6,167.77 190.87,167.77 191.63,167 229.57,167 236.35,160.22 236.35,151.02 235.18,149.85 235.18,145.95 v1(234.9,145.67)
MPEX2_REFCLK_P: length 187.7
  TOP w0.102: J20.11 v1(90.42,193.88) ; R530.2 235.58,142.49 235.58,142.76 R527.1 235.7,143.14 235.46,143.38 235.46,145.39 v1(235.74,145.67)
  BOTTOM w0.102: v1(235.74,145.67) 235.46,145.95 235.46,149.73 236.63,150.9 236.63,160.34 229.68,167.28 191.74,167.28 190.98,168.05 109.72,168.05 89.05,188.71 89.05,194.16 89.29,194.4 89.83,194.4 89.93,194.3 89.93,194.02 90.07,193.88 v1(90.42,193.88)
MPEX2_RST_N: length 534.8
  TOP w0.127: v1(250.32,154.05) 250.32,154.81 237.74,167.39 119.25,167.39 90.3,196.34 86.87,196.34 83.57,199.64 83.57,200.64 82.73,201.48 J20.22 ; v1(59.51,99.42) 59.02,99.92 U65.R3
  L6SIG w0.102: v1(250.32,154.05) 252.6,156.34 273.56,156.34 277.11,152.78 277.11,145.54 278.7,143.95 278.7,82.34 274.59,78.23 228.73,78.23 226.82,76.33 215.28,76.33 208.68,69.72 181.99,69.72 177.17,74.55 159.51,74.55 159,74.04 93.98,74.04 93.22,74.8 76.71,74.8 75.44,76.07 72.01,76.07 69.85,78.23 69.85,82.8 67.95,84.71 67.95,85.98 59.51,94.41 v1(59.51,99.42)
MPEX2_RX_N: length 273.3
  TOP w0.127: v1(93.09,201.93) 92.96,202.06 92.58,202.06 C1270.2 ; U1.AG20 176.37,118.7 arc(176.53,118.81) 176.73,118.85 177.07,118.88 177.48,118.98 arc(177.95,119) 178.41,119.06 182.98,119.87 arc(187.97,120.31) 192.96,119.87 208.36,117.16 arc(211.54,116.88) 214.72,117.16 216.7,117.5 216.77,117.52 217.18,117.59 arc(222.88,118.09) 228.58,117.59 232.42,116.91 arc(234.4,116.65) 236.4,116.57 236.73,116.57 arc(236.82,116.6) 236.85,116.69 v1(236.85,116.85)
  BOTTOM w0.127: v1(93.09,201.93) 93.25,202.09 arc(93.3,202.12) 93.36,202.13 93.38,202.13 arc(93.44,202.13) 93.5,202.12 94.08,202.02 arc(94.16,201.97) 94.19,201.87 arc(94.21,201.77) 94.3,201.71 94.53,201.67 arc(94.63,201.69) 94.69,201.78 arc(94.74,201.86) 94.84,201.89 99.11,201.13 arc(99.57,201) 99.99,200.77 126.23,182.39 arc(128.74,181.02) 131.48,180.22 176.11,172.35 arc(180.3,171.98) 184.5,172.35 199.55,175 arc(202.48,175.26) 205.42,175 229.24,170.8 arc(232.62,169.82) 235.7,168.13 236.25,167.74 arc(237,167.11) 237.63,166.36 240.92,161.67 arc(242.33,159.09) 243.16,156.25 246.44,137.66 arc(246.63,135.43) 246.44,133.19 244.42,121.75 arc(244.29,121.31) 244.08,120.9 244.06,120.88 arc(242.45,118.95) 240.53,117.34 239.98,116.96 arc(239.39,116.67) 238.73,116.57 236.98,116.57 arc(236.89,116.6) 236.85,116.69 v1(236.85,116.85)
MPEX2_RX_P: length 273.2
  TOP w0.127: v1(236.85,115.93) 236.85,116.08 arc(236.82,116.17) 236.73,116.21 236.4,116.21 arc(234.37,116.3) 232.36,116.56 228.52,117.24 arc(222.88,117.73) 217.24,117.24 217.24,117.24 216.83,117.16 216.82,117.16 216.82,117.17 214.78,116.81 arc(211.54,116.52) 208.3,116.81 192.9,119.52 arc(187.97,119.95) 183.04,119.52 178.47,118.71 arc(178,118.65) 177.53,118.63 177.31,118.57 U1.AH20 ; C1269.2 92.58,202.56 92.96,202.56 v1(93.09,202.69)
  BOTTOM w0.127: v1(236.85,115.93) 236.85,116.08 arc(236.89,116.17) 236.98,116.21 238.73,116.21 arc(239.49,116.33) 240.19,116.67 240.73,117.05 arc(242.7,118.7) 244.35,120.67 arc(244.36,120.69) 244.37,120.7 arc(244.62,121.17) 244.77,121.69 246.79,133.13 arc(246.99,135.43) 246.79,137.72 243.51,156.31 arc(242.66,159.22) 241.21,161.88 237.92,166.57 arc(237.25,167.36) 236.46,168.03 235.9,168.42 arc(232.75,170.15) 229.3,171.15 205.48,175.35 arc(202.48,175.62) 199.49,175.35 184.43,172.7 arc(180.3,172.34) 176.17,172.7 131.54,180.57 arc(128.87,181.35) 126.44,182.68 100.19,201.06 arc(99.71,201.33) 99.17,201.48 93.56,202.47 arc(93.47,202.49) 93.38,202.49 93.37,202.49 arc(93.3,202.5) 93.24,202.54 v1(93.09,202.69)
MPEX2_TX_N: length 283.6
  TOP w0.127: v1(93.09,205.1) 92.96,205.23 92.58,205.23 C631.2 ; U1.AE20 v2(174.92,118.85)
  BOTTOM w0.127: v2(174.92,118.85) 174.95,118.81 175.58,118.81 arc(175.77,118.82) 175.96,118.84 178.26,119.25 arc(184.15,119.76) 190.04,119.25 199.92,117.5 arc(202.17,116.85) 204.22,115.72 204.89,115.25 arc(206.62,114.31) 208.51,113.75 221.27,111.5 arc(224.44,111.23) 227.6,111.5 237.14,113.18 arc(238.92,113.7) 240.54,114.59 243.49,116.66 arc(244.65,117.64) 245.63,118.8 245.64,118.81 arc(245.87,119.22) 246,119.68 248.23,132.31 arc(248.41,134.45) 248.23,136.59 244.54,157.47 arc(243.83,159.91) 242.61,162.13 239.19,167.02 arc(238.21,168.19) 237.04,169.17 237.03,169.18 arc(233.26,171.24) 229.14,172.45 206.62,176.42 arc(202.41,176.78) 198.19,176.42 188.31,174.67 arc(183.69,174.27) 179.07,174.67 133.19,182.76 arc(130.4,183.58) 127.85,184.97 101.06,203.73 arc(100.42,204.08) 99.72,204.29 99.04,204.41 99.03,204.41 arc(98.9,204.38) 98.82,204.27 98.82,204.26 arc(98.73,204.15) 98.59,204.13 98.47,204.15 arc(98.35,204.22) 98.32,204.35 arc(98.3,204.48) 98.18,204.56 98.03,204.58 arc(97.9,204.56) 97.82,204.44 arc(97.75,204.33) 97.62,204.3 97.47,204.33 arc(97.35,204.4) 97.32,204.53 arc(97.29,204.66) 97.18,204.73 97.03,204.76 arc(96.9,204.73) 96.82,204.62 arc(96.75,204.51) 96.62,204.48 96.46,204.5 arc(96.35,204.58) 96.32,204.71 arc(96.29,204.84) 96.18,204.91 96.03,204.94 arc(95.89,204.91) 95.82,204.8 arc(95.75,204.68) 95.62,204.65 95.46,204.68 arc(95.35,204.75) 95.32,204.88 arc(95.29,205.01) 95.18,205.09 95.02,205.11 arc(94.89,205.09) 94.82,204.97 arc(94.75,204.86) 94.62,204.83 94.46,204.86 arc(94.35,204.93) 94.32,205.06 94.32,205.06 arc(94.29,205.19) 94.18,205.26 93.93,205.31 93.43,205.31 arc(93.3,205.28) 93.2,205.22 v1(93.09,205.1)
MPEX2_TX_P: length 283.6
  TOP w0.127: C630.2 92.53,205.78 93.01,205.78 v1(93.09,205.87) ; U1.AD20 v2(174.12,118.85)
  BOTTOM w0.127: v1(93.09,205.87) 93.2,205.76 arc(93.3,205.69) 93.43,205.66 93.96,205.66 99.78,204.64 arc(100.56,204.41) 101.26,204.03 128.05,185.27 arc(130.53,183.91) 133.25,183.11 179.13,175.02 arc(183.69,174.62) 188.25,175.02 198.13,176.77 arc(202.41,177.14) 206.69,176.77 229.2,172.8 arc(233.4,171.57) 237.24,169.47 237.25,169.46 arc(238.46,168.44) 239.48,167.23 242.9,162.34 arc(244.16,160.04) 244.9,157.53 248.58,136.65 arc(248.77,134.45) 248.58,132.25 246.35,119.62 arc(246.19,119.09) 245.93,118.6 245.93,118.6 arc(244.91,117.39) 243.69,116.37 240.74,114.3 arc(239.05,113.37) 237.2,112.83 227.66,111.15 arc(224.44,110.87) 221.21,111.15 208.45,113.4 arc(206.48,113.98) 204.69,114.96 204.02,115.43 arc(202.03,116.52) 199.86,117.15 189.98,118.9 arc(184.15,119.41) 178.32,118.9 176.03,118.49 arc(175.81,118.46) 175.58,118.45 174.73,118.45 arc(174.55,118.49) 174.4,118.59 174.14,118.85 v2(174.12,118.85)
MVREF: length 74.7
  TOP w0.305: U1.F20 v2(158.92,118.85)
  L4PWR w0.381: 158.24,119.51 158.9,118.85 v2(158.92,118.85)
  L4PWR w0.508: v1(106.35,152.6) 125.09,133.86 136.27,133.86 150.62,119.51 158.24,119.51
  BOTTOM w0.305: C22.1 158.73,118.66 v2(158.92,118.85) 158.92,118.85 C21.1
  BOTTOM w0.508: v1(106.35,152.6) 106.35,150.8 105.92,150.37 105.16,150.37 104.01,149.22 Q48.2 103.94,149.23 R945.2
MVREF_SLP: length 142.9
  TOP w0.305: J1.67 173.7,157.33 173.7,155.15 173.23,154.69 C18.1
  TOP w0.508: J1.1 103.38,157.01 103.38,153.92 C19.1
  BOTTOM w0.508: J1.67 173.92,154.25 173.99,154.18
  BOTTOM w0.762: v1(223.77,144.65) v1(223.01,144.65) 213.49,154.18 161.04,154.18 159.51,152.65 149.73,152.65 148.23,154.15 104.42,154.15 ; Q48.3 104.9,153.67 104.42,154.15 ; 104.42,154.15 103.38,155.19 103.38,157.01 J1.1
NAND_CS_N: length 39.1
  TOP w0.127: U107.C6 v2(94.53,131.22) ; v1(88.65,128.52) 88.65,126.75 88.07,126.17 88.07,121.86 74.14,107.93 U65.G16
  BOTTOM w0.127: R952.1 94.53,131.35 v2(94.53,131.22) 94.53,130.59 92.46,128.52 v1(88.65,128.52)
NAND_RB_N: length 53.5
  TOP w0.127: v1(66.55,111.38) 66.55,110.74 66.17,110.37 63.75,110.37 63.5,110.62 63.5,111.44 U65.C7 ; U107.C8 v2(96.13,131.22)
  L6SIG w0.102: v2(96.13,131.22) 97.41,129.93 97.41,119.89 95,117.48 79.25,117.48 74.68,112.9 67.18,112.9 66.55,112.27 v1(66.55,111.38)
  BOTTOM w0.127: v2(96.13,131.22) 96.15,131.24 R953.1
NOR_CS_N: length 64.2
  TOP w0.127: U4.32 v1(103.72,133.9) ; U65.D13 v1(69.52,111.43)
  L3SIG w0.102: v1(69.52,111.43) 69.09,111.86 69.09,121.16 71.12,123.19 71.12,135.51 73.74,138.13 82.22,138.13 86.23,134.11 103.51,134.11 v1(103.72,133.9)
  BOTTOM w0.127: v1(103.72,133.9) 103.62,133.99 R43.1
NOR_RB_N: length 82.5
  TOP w0.127: U4.17 120.64,129.9 v1(120.64,129.9) ; U65.E14 v1(70.52,110.43)
  L3SIG w0.102: v1(70.52,110.43) 69.98,110.97 69.98,112.78 69.79,112.97 69.79,120.84 71.88,122.94 71.88,135.25 74.04,137.41 81.92,137.41 86.11,133.22 100.33,133.22 100.65,132.91 101.92,132.91 102.17,133.16 113.86,133.16 116.08,130.94 117.98,130.94 119.02,129.9 v1(120.64,129.9)
  BOTTOM w0.127: v1(120.64,129.9) 120.11,130.43 R44.1
NOR_RST_N: length 79.4
  TOP w0.127: U65.C14 v1(70.52,112.43) ; U4.14 120.02,128.4 v1(120.02,128.4)
  L3SIG w0.102: v1(70.52,112.43) 70.52,112.74 70.04,113.22 70.04,120.65 72.26,122.87 72.26,135.13 74.17,137.03 81.79,137.03 85.98,132.84 100.2,132.84 100.39,132.65 102.17,132.65 102.36,132.84 113.67,132.84 116.59,129.92 117.86,129.92 119.38,128.4 v1(120.02,128.4)
  BOTTOM w0.127: R47.1 v1(120.02,128.4)
PCIE_REFCLK1_N: length 32.1
  TOP w0.102: R1012.2 242.12,139.26 242.51,139.26 R1013.1 242.83,139.5 243.27,139.06 247.27,139.06 249.07,137.26 249.07,132.45 255,126.52 259.7,126.52 261.77,124.45 261.77,122.01 C1386.1
PCIE_REFCLK1_P: length 32
  TOP w0.102: C1388.1 261.36,121.79 261.49,121.92 261.49,124.33 259.59,126.24 254.89,126.24 248.79,132.33 248.79,137.15 247.15,138.79 243.24,138.79 242.83,138.37 R1014.2 242.5,138.63 242.13,138.63 R1015.2
PCIE_REFCLK2_N: length 14.9
  TOP w0.102: R537.2 231.02,137.92 230.75,137.92 R538.2 230.37,137.8 230.12,138.05 228.09,138.05 226.95,136.91 226.95,131.05 225.93,130.03 225.93,128.62 226.03,128.52 C1383.1
PCIE_REFCLK2_P: length 15
  TOP w0.102: C1385.1 225.65,128.74 225.65,130.15 226.67,131.17 226.67,137.02 227.98,138.33 230.15,138.33 230.37,138.55 R535.2 230.75,138.43 231.02,138.43 R536.2
PEX_PRS_N: length 260.5
  TOP w0.127: R405.1 270.07,96.01 271.15,97.09 272.29,97.09 272.8,97.6 272.8,98.83 J18.B17 ; U65.P5 61.02,100.92 v1(61.51,100.42)
  L6SIG w0.102: J18.B17 272.8,98.83 272.8,96.14 270.38,93.73 270.38,81.66 268.73,80.01 227.84,80.01 225.93,78.11 214.62,78.11 208.01,71.5 182.88,71.5 177.85,76.53 153.62,76.53 152.91,75.82 94.87,75.82 94.11,76.58 77.6,76.58 73.79,80.39 72.14,80.39 71.63,80.9 71.63,83.69 69.72,85.6 69.72,90.17 62.01,97.88 62.01,99.92 v1(61.51,100.42)
PEX_REFCLK_N: length 62.2
  TOP w0.102: v1(245.36,136.91) 245.1,136.64 243.06,136.64 242.83,136.87 R523.1 242.45,136.78 242.18,136.78 R521.2
  L3SIG w0.102: v1(245.36,136.91) 245.62,136.65 246.9,136.65 251.98,131.57 257.3,131.57 265.58,123.29 265.58,98.4 267.72,96.27 270.14,96.27 270.38,96.51 270.38,96.9 270.21,97.08 J18.A14
PEX_REFCLK_P: length 62.1
  TOP w0.102: v1(245.36,136.09) 245.1,136.36 243.06,136.36 242.83,136.13 R519.1 242.45,136.27 242.18,136.27 R520.2
  L3SIG w0.102: v1(245.36,136.09) 245.64,136.37 246.79,136.37 251.87,131.29 257.19,131.29 265.3,123.18 265.3,98.28 267.6,95.99 270.26,95.99 270.53,96.27 271.36,96.27 J18.A13
PEX_RST_N: length 243
  TOP w0.127: U65.R5 61.02,99.92 v1(61.51,99.42)
  L6SIG w0.102: v1(61.51,99.42) 61.51,98 69.47,90.04 69.47,85.47 71.37,83.57 71.37,79.76 71.88,79.25 74.55,79.25 77.47,76.33 93.98,76.33 94.74,75.57 153.03,75.57 153.75,76.28 177.72,76.28 182.75,71.25 208.08,71.25 214.69,77.85 226.06,77.85 227.97,79.76 268.86,79.76 270.64,81.53 270.64,91.17 J18.A11
PEX_RX_N: length 35.9
  TOP w0.127: J18.A17 270.38,100.08 270.19,100.27 265.93,100.27 arc(261.67,100.45) 257.44,101.01 248.58,102.57 arc(246.61,102.74) 244.65,102.57 244.65,102.57 arc(241.53,102.16) 238.38,102.02 236.63,102.02 236.55,102.1 U110.17
PEX_RX_P: length 35.9
  TOP w0.127: J18.A16 270.13,99.08 270.26,99.2 270.26,99.7 270.04,99.91 265.93,99.91 arc(261.64,100.1) 257.38,100.66 248.52,102.22 arc(246.62,102.39) 244.72,102.22 244.72,102.22 arc(241.56,101.81) 238.38,101.67 236.63,101.67 236.55,101.6 U110.16
PEX_SEL_N: length 209.7
  TOP w0.127: U110.9 232.18,99.6 R979.2 v1(231.77,98.43) ; v1(62.52,100.42) 62.02,100.92 U65.P6
  L6SIG w0.102: v1(231.77,98.43) 231.77,84.32 225.81,78.36 214.5,78.36 207.9,71.76 183.01,71.76 177.93,76.84 153.54,76.84 152.78,76.07 95,76.07 94.23,76.84 77.72,76.84 73.15,81.41 72.39,81.41 71.88,81.92 71.88,83.82 69.98,85.73 69.98,90.3 62.99,97.28 62.99,99.94 v1(62.52,100.42)
PEX_TX_N: length 31.3
  TOP w0.127: U110.18 236.55,102.6 236.63,102.67 237.55,102.67 arc(237.77,102.68) 237.99,102.71 246.6,104.22 arc(250.01,104.52) 253.42,104.22 265.48,102.1 arc(265.7,102.07) 265.93,102.06 266.16,102.06 arc(266.36,102.02) 266.53,101.9 C607.2
PEX_TX_P: length 31.3
  TOP w0.127: U110.19 236.55,103.1 236.63,103.02 237.55,103.02 arc(237.74,103.03) 237.93,103.06 246.54,104.57 arc(250.01,104.88) 253.48,104.57 265.55,102.45 arc(265.73,102.42) 265.93,102.41 266.16,102.41 arc(266.36,102.45) 266.53,102.57 C606.2
PEXCLK_OE_N: length 385.5
  TOP w0.127: U97.24 237.2,140.17 v1(237.24,140.21) ; U97.21 238.72,139.41 239.52,140.21 v1(239.52,140.59) ; U97.13 240.01,135.91 v1(240.03,135.89) 240.03,135.76 240.41,135.38 240.41,135.14 R843.2 ; v1(66.52,90.61) 66.52,91.66 70.99,96.14 72.52,96.14 73.79,97.41 73.79,100.58 72.44,101.93 U65.N16 ; U97.30 234.8,140.1 v1(234.7,140.21) ; U97.35 233.24,137.11 v1(233.17,137.03)
  L6SIG w0.102: v1(240.03,135.89) 240.41,135.89 241.17,136.65 241.17,139.32 240.54,139.95 239.14,139.95 238.89,139.7 237.74,139.7 v1(237.24,140.21) ; v1(66.52,90.61) 66.52,88.17 68.45,86.23 68.45,84.96 70.36,83.06 70.36,78.49 72.26,76.58 75.69,76.58 76.96,75.31 93.47,75.31 94.23,74.55 153.36,74.55 154.1,75.29 177.19,75.29 182.24,70.23 208.47,70.23 215.07,76.84 226.57,76.84 228.47,78.74 274.38,78.74 278.25,82.61 278.25,143.65 276.61,145.29 276.61,148.97 272.67,152.91 269.88,152.91 267.72,155.07 259.14,155.07 248.86,144.78 246.38,144.78 242.19,140.59 v1(239.52,140.59) 239.27,140.84 237.87,140.84 v1(237.24,140.21) ; v1(233.17,137.03) 232.54,137.67 232.54,138.87 233.88,140.21 v1(234.7,140.21) 235.2,140.72 236.73,140.72 v1(237.24,140.21)
PORESET_N: length 102.3
  TOP w0.127: U1.F13 v2(158.92,112.45) ; U65.C15 v1(71.52,112.43)
  L6SIG w0.102: v1(71.52,112.43) 72.06,111.89 74.04,111.89 79.38,117.22 126.11,117.22 127.1,116.23 137.01,116.23 147.19,106.05 155.96,106.05 156.34,105.67 156.67,105.67 156.9,105.89 156.9,106.61 157.73,107.44 157.73,109.08 157.73,109.08 157.73,109.4 157.73,109.41 157.73,110.2 157.96,110.43 158.24,110.43 158.5,110.69 158.5,112.02 158.92,112.43 v2(158.92,112.45)
  BOTTOM w0.127: R94.2 v1(71.52,112.43)
PWR_EN_N: length 48.6
  TOP w0.127: J37.14 10.29,98.16 10.29,70.87 9.53,70.1 Q30.3 9.13,68.57 R710.1 6.47,68.57 5.84,67.95 5.84,57.78 J48.1
PWR_GOOD: length 73.8
  TOP w0.127: R709.1 R712.2 C894.1 14.35,68.96 v1(14.61,68.71) ; U65.C2 58.01,111.93 v1(57.51,111.43)
  L6SIG w0.102: v1(57.51,111.43) 56.21,111.43 50.67,105.89 50.67,98.81 45.44,93.57 42.01,93.57 38.48,90.04 38.48,83.69 32.89,78.11 29.84,78.11 27.18,75.44 27.18,73.03 25.91,71.76 19.18,71.76 16.13,68.71 v1(14.61,68.71)
PWR_RST_N: length 70.9
  TOP w0.127: v1(19.05,69.09) 18.55,68.59 R708.2 18.1,67.62 U83.2 ; U65.C3 59.01,111.93 v1(58.51,111.43)
  L6SIG w0.102: v1(19.05,69.09) 19.05,70.74 19.81,71.5 26.03,71.5 27.43,72.9 27.43,75.31 29.97,77.85 33.02,77.85 38.73,83.57 38.73,89.92 42.16,93.34 45.59,93.34 50.93,98.68 50.93,105.75 56.11,110.93 58.01,110.93 v1(58.51,111.43)
RESET_REQ_N: length 97.3
  TOP w0.127: U65.K15 v1(71.52,104.42) 73.69,104.42 86.23,116.97 111.51,116.97 112.39,117.86 135,117.86 147.83,105.03 149.1,105.03 149.73,104.39 155.66,104.39 U1.B3
  BOTTOM w0.127: R98.2 v1(71.52,104.42)
RS232_CTS1: length 22.1
  TOP w0.127: FB21.2 123.99,34.67 126.37,34.67 126.61,34.42 C276.1 U43.4 129.79,34.04 131.32,32.51 131.32,27.94 132.33,26.92 133.86,26.92 136.02,24.77 136.02,22.84 J13.A8
RS232_CTS2: length 32.4
  TOP w0.127: FB25.2 126.24,33.4 126.61,33.03 C289.1 U43.5 129.67,32.77 130.94,31.5 130.94,27.69 132.08,26.54 133.6,26.54 135.51,24.64 135.51,21.84 136.78,20.57 143.76,20.57 145.46,18.88 J13.B8
RS232_RTS1: length 32.5
  TOP w0.127: J13.A1 144,23.37 139.57,23.37 138.94,24 138.94,25.15 138.18,25.91 136.14,25.91 134.37,27.69 132.84,27.69 132.08,28.45 132.08,34.16 129.67,36.58 U43.2 C277.1 126.61,36.84 126.24,37.21 124.5,37.21 FB20.2
RS232_RTS2: length 23.9
  TOP w0.127: FB24.2 124.5,29.59 126.37,29.59 126.61,29.34 C290.1 U43.8 129.54,28.96 129.79,28.7 129.79,23.88 131.57,22.1 133.35,22.1 136.57,18.88 J13.B1
RS232_RXD1: length 25
  TOP w0.127: J13.A6 138.24,22.29 136.52,24 136.52,24.89 134.11,27.3 132.59,27.3 131.7,28.19 131.7,33.27 129.67,35.31 U43.3 C278.1 126.61,35.69 126.37,35.94 124.24,35.94 FB19.2
RS232_RXD2: length 29.5
  TOP w0.127: J13.B6 142.92,19.26 142.11,20.07 136.65,20.07 133.6,23.11 131.83,23.11 130.56,24.38 130.56,30.61 129.67,31.5 U43.6 C291.1 126.61,31.76 126.24,32.13 123.99,32.13 FB23.2
RS232_TXD1: length 30.9
  TOP w0.127: FB18.2 124.63,38.61 126.24,38.61 126.61,38.23 C279.1 U43.1 129.67,37.85 132.46,35.05 132.46,28.58 132.97,28.07 134.62,28.07 136.27,26.42 138.3,26.42 139.32,25.4 139.32,24.26 139.83,23.75 141.86,23.75 142.92,24.81 J13.A3
RS232_TXD2: length 27.1
  TOP w0.127: J13.B3 139.11,18.75 138.43,19.43 136.65,19.43 133.48,22.61 131.7,22.61 130.17,24.13 130.17,29.59 129.54,30.23 U43.7 C292.1 126.61,30.61 126.37,30.86 124.24,30.86 FB22.2
RTC_INT_N: length 58.5
  TOP w0.127: v1(65.52,100.42) 65.02,100.92 U65.P9 ; v1(104.78,84.2) 104.78,85.6 106.12,86.94 U100.7 108.78,86.94 R940.1
  L6SIG w0.102: v1(104.78,84.2) 103,85.98 84.96,85.98 83.57,87.38 79.38,87.38 77.6,89.15 77.6,95.38 75.69,97.28 72.01,97.28 71.5,97.79 71.5,100.08 70.61,100.97 66.06,100.97 v1(65.52,100.42)
SD_REFCLK1_C_N: length 99
  TOP w0.102: v1(240.41,119.76) 240.66,119.51 245.36,119.51 252.45,112.42 254.16,112.42 C68.2 ; U1.AA14 v2(171.72,113.25)
  L3SIG w0.102: v1(240.41,119.76) 240.16,119.51 230.12,119.51 226.16,123.47 222.66,123.47 204.85,105.66 188.72,105.66 183.74,110.64 181.2,110.64 178.44,113.41 177.69,113.41 177.47,113.63 175.87,113.63 175.87,113.63 172.1,113.63 v2(171.72,113.25)
SD_REFCLK1_C_P: length 99.3
  TOP w0.102: U1.AB14 v2(172.52,113.25) ; v1(240.41,119) 240.64,119.23 245.25,119.23 252.33,112.14 254.25,112.14 254.39,112.01 C67.2
  L3SIG w0.102: v2(172.52,113.25) 172.3,113.25 172.16,113.1 172.16,112.96 172.25,112.87 176.36,112.87 176.36,112.86 177.47,112.86 177.74,113.13 178.32,113.13 181.09,110.36 183.63,110.36 188.61,105.38 204.97,105.38 222.77,123.19 226.05,123.19 230.01,119.23 240.18,119.23 v1(240.41,119)
SD_REFCLK1_N: length 8.9
  TOP w0.102: U113.14 262.47,111.8 262.28,111.99 262.28,112.28 262.02,112.55 258.16,112.55 R997.1 257.93,112.64 257.56,112.27 255.77,112.27 C68.1
SD_REFCLK1_P: length 8.7
  TOP w0.102: C67.1 255.74,111.99 257.56,111.99 257.93,111.62 ; 257.93,111.62 R993.1 ; 257.93,111.62 257.93,111.88 258.32,112.27 261.9,112.27 262,112.17 262,112.02 261.82,111.83 U113.13
SD_REFCLK2_C_N: length 92.7
  TOP w0.102: C1381.1 241.04,123.44 v1(241.55,123.44) ; U1.AA18 v2(171.72,117.25)
  L3SIG w0.102: v2(171.72,117.25) 172.1,116.86 175.07,116.86 175.33,117.13 175.33,117.4 175.76,117.83 180.06,117.83 183.49,121.26 211.18,121.26 219.81,129.9 221.35,129.9 224.79,133.34 224.79,136.64 226.18,138.02 229.12,138.02 229.62,137.53 229.62,130.03 234.07,125.58 238.77,125.58 240.74,123.61 241.39,123.61 v1(241.55,123.44)
SD_REFCLK2_C_P: length 92.3
  TOP w0.102: U1.AB18 v2(172.52,117.25) ; C1380.1 241.04,124.21 v1(241.55,124.21)
  L3SIG w0.102: v1(241.55,124.21) 241.55,124.02 241.43,123.89 240.86,123.89 238.89,125.86 234.19,125.86 229.9,130.15 229.9,137.64 229.23,138.3 226.06,138.3 224.51,136.75 224.51,133.45 221.23,130.17 219.7,130.17 211.06,121.54 183.37,121.54 179.94,118.11 175.65,118.11 175.16,117.63 172.36,117.63 172.28,117.55 172.28,117.4 172.44,117.25 v2(172.52,117.25)
SD_REFCLK2_N: length 5.4
  TOP w0.102: U112.13 235.91,123.26 236.1,123.45 236.99,123.45 R995.1 237.24,123.32 237.62,123.7 239.28,123.7 C1381.2
SD_REFCLK2_P: length 5.9
  TOP w0.102: 237.24,124.39 237.65,123.98 239.3,123.98 C1380.2 ; 237.24,124.39 R999.1 ; 237.24,124.39 237.24,123.83 237.14,123.73 236.07,123.73 235.88,123.91 U112.14
SD_REFCLK_SEL: length 290.4
  TOP w0.127: U113.1 v1(263.77,114.94) ; v1(68.14,96.33) 69.02,97.21 U65.T13 ; U112.1 230.39,125.21 231.27,124.33 v1(231.27,120.27)
  L6SIG w0.102: v1(231.27,120.27) 231.27,116.46 230.25,115.44 213.61,115.44 v1(197.87,99.7) ; v1(68.14,96.33) 68.14,96.2 72.01,92.33 72.01,89.28 77.09,84.2 82.93,84.2 85.22,81.92 85.22,81.28 87.76,78.74 93.09,78.74 93.85,79.5 116.2,79.5 118.11,77.6 145.29,77.6 152.15,84.45 195.96,84.45 v1(197.87,86.36) 216.28,104.78 244.22,104.78 254.38,114.94 v1(263.77,114.94)
  BOTTOM w0.127: v1(197.87,99.7) v1(197.87,86.36)
SD_RX1_N: length 37.8
  TOP w0.127: U110.7 232.84,100.6 232.77,100.52 230.38,100.52 arc(229.42,100.57) 228.46,100.69 219.41,102.29 arc(219.19,102.34) 218.97,102.41 214.99,104.03 arc(214.94,104.05) 214.9,104.08 201.35,113.57 arc(200.87,113.83) 200.34,113.99 200.17,114.02 arc(199.75,114.16) C1268.1
SD_RX1_P: length 37.9
  TOP w0.127: C1267.1 199.38,113.53 199.49,113.63 arc(199.62,113.71) 199.77,113.72 200.27,113.64 arc(200.73,113.5) 201.15,113.27 214.86,103.68 214.92,103.68 218.83,102.09 arc(219.09,102) 219.35,101.94 228.4,100.34 arc(229.38,100.21) 230.38,100.17 232.77,100.17 232.84,100.1 U110.8
SD_TX1_N: length 62.7
  TOP w0.127: v1(228.09,102.49) 228.27,102.67 229.25,102.67 232.09,102.17 232.77,102.17 232.84,102.1 U110.4 ; U1.AE17 v2(174.92,116.45)
  BOTTOM w0.127: v1(228.09,102.49) 227.98,102.6 arc(227.88,102.67) 227.76,102.69 227.19,102.69 arc(226.97,102.7) 226.75,102.73 218.65,104.16 arc(217.76,104.42) 216.95,104.86 216.22,105.37 arc(214.98,106.05) 213.61,106.45 212.16,106.71 arc(207.07,108.19) 202.42,110.75 202.27,110.85 arc(199.2,112.54) 195.83,113.52 183.45,115.7 arc(183.35,115.68) 183.3,115.6 arc(183.24,115.51) 183.15,115.49 182.9,115.54 arc(182.82,115.59) 182.8,115.68 arc(182.78,115.78) 182.69,115.83 182.44,115.88 arc(182.35,115.86) 182.3,115.77 arc(182.24,115.69) 182.15,115.67 181.9,115.71 arc(181.82,115.76) 181.8,115.86 arc(181.77,115.96) 181.69,116.01 181.44,116.05 arc(181.35,116.03) 181.3,115.95 181.3,115.95 arc(181.24,115.87) 181.15,115.85 180.9,115.89 arc(180.82,115.94) 180.79,116.04 arc(180.77,116.13) 180.69,116.19 180.44,116.23 arc(179,116.42) 177.55,116.48 174.93,116.48 174.92,116.47 v2(174.92,116.45)
SD_TX1_P: length 62.7
  TOP w0.127: U1.AD17 v2(174.12,116.45) ; v1(228.09,103.25) 228.32,103.03 229.28,103.03 232.12,102.52 232.77,102.52 232.84,102.6 U110.3
  BOTTOM w0.127: v1(228.09,103.25) 227.98,103.14 arc(227.88,103.07) 227.76,103.05 227.19,103.05 arc(227,103.06) 226.82,103.08 218.71,104.51 arc(217.9,104.75) 217.16,105.15 216.43,105.66 arc(215.11,106.38) 213.68,106.8 212.22,107.06 arc(207.21,108.52) 202.62,111.04 202.47,111.14 arc(199.33,112.86) 195.89,113.87 180.5,116.58 arc(179.03,116.77) 177.55,116.84 174.78,116.84 arc(174.53,116.79) 174.32,116.65 v2(174.12,116.45)
SDHC_CD_N: length 171.6
  TOP w0.127: U1.L5 v2(162.92,106.05)
  L3SIG w0.102: v1(157.48,93.47) 157.61,93.47 160.45,96.32 160.45,96.98 160.45,97.59 161.04,98.17 161.04,101.92 161.71,102.6 161.71,105.38 161.96,105.63 162.27,105.63 162.69,106.05 v2(162.92,106.05)
  BOTTOM w0.127: R66.1 v1(157.48,93.47) 157.48,92.96 156.97,92.46 156.08,92.46 144.02,80.39 124.63,80.39 117.9,73.66 65.51,73.66 58.04,66.19 58.04,49.81 48.36,40.13 44.83,40.13 43.35,38.65 U93.5 U93.4 43.35,36.49 41.73,34.87 J2.10
SDHC_CLK: length 183.3
  BOTTOM w0.127: R61.2 163.19,97.61 162.62,97.04 162.62,95.82 162.43,95.63 161.16,95.63 160.85,95.94 159.2,95.94 158.62,96.52 157.23,96.52 156.97,96.27 156.97,94.36 156.84,94.23 156.47,94.23 R68.1 156.46,93.6 143.76,80.9 124.42,80.9 117.69,74.17 65.3,74.17 57.53,66.4 57.53,50.02 48.15,40.64 33.53,40.64 31.83,38.95 U94.8 U94.1 31.83,36.36 32.89,35.31 34.92,35.31 35.9,34.33 J2.5
SDHC_CMD: length 169.3
  TOP w0.127: U1.K3 v2(162.12,104.45)
  L3SIG w0.102: v2(162.12,104.45) 162.12,104.19 162.5,103.8 162.5,102.17 161.42,101.09 161.42,98.04 160.73,97.36 160.73,95.96 158.5,93.73 v1(158.5,93.47)
  BOTTOM w0.127: R67.1 v1(158.5,93.47) 158.5,92.71 157.86,92.08 156.21,92.08 144.14,80.01 124.79,80.01 118.05,73.28 65.67,73.28 58.42,66.03 58.42,49.65 48.52,39.75 44.96,39.75 43.85,38.64 U93.6 U93.3 43.85,36.36 43.4,35.9 J2.2
SDHC_DAT0: length 180.1
  TOP w0.127: U1.L2 163.32,104.01 162.94,103.63 162.94,101.35 159.13,97.54 159.13,95.76 157.73,94.36 156.34,94.36 v1(155.45,93.47)
  BOTTOM w0.127: J2.7 30.97,35.54 31.33,35.91 U94.2 U94.7 31.33,39.33 33.15,41.15 47.94,41.15 57.02,50.23 57.02,66.61 65.09,74.68 117.48,74.68 124.21,81.41 143.47,81.41 155.45,93.39 v1(155.45,93.47) R60.1
SDHC_DAT1: length 185.1
  TOP w0.127: U1.K4 v2(162.12,105.25)
  L3SIG w0.102: v2(162.12,105.25) 162.12,105.15 162.54,104.73 162.54,104.22 162.81,103.94 162.81,101.98 161.8,100.97 161.8,96.52 159,93.73 159,93.14 158.83,92.96 154.94,92.96 v1(154.43,93.47)
  BOTTOM w0.127: J2.8 29.27,35.36 30.13,36.23 U94.3 U94.6 30.13,38.64 33.02,41.53 47.78,41.53 56.64,50.39 56.64,66.77 64.93,75.06 117.32,75.06 124.05,81.79 143.38,81.79 154.43,92.84 v1(154.43,93.47) R62.1
SDHC_DAT2: length 170
  TOP w0.127: U1.L3 v2(162.92,104.45)
  L3SIG w0.102: v1(160.4,93.47) 162.18,95.25 162.18,100.71 163.07,101.6 163.07,104.14 162.92,104.29 v2(162.92,104.45)
  BOTTOM w0.127: R63.1 160.53,93.6 v1(160.4,93.47) 158.24,91.31 156.46,91.31 144.4,79.25 125.1,79.25 118.37,72.52 65.98,72.52 59.18,65.72 59.18,49.33 48.84,38.99 45.97,38.99 45.55,38.57 U93.8 U93.1 45.55,36.36 46.1,35.81 46.99,35.81 48.4,34.41 J2.9
SDHC_DAT3: length 167
  TOP w0.127: U1.L1 163.32,101.21 159.51,97.41 v1(159.51,93.47)
  BOTTOM w0.127: J2.1 45.9,35.38 45.05,36.23 U93.2 U93.7 45.05,38.57 45.85,39.37 48.68,39.37 58.8,49.49 58.8,65.88 65.82,72.9 118.21,72.9 124.94,79.63 144.27,79.63 156.34,91.69 158.11,91.69 159.51,93.09 v1(159.51,93.47) R64.1
SDHC_VS: length 93.3
  TOP w0.127: U65.M16 v1(72.72,102.93) 73.72,102.93 86.61,115.82 111.89,115.82 112.78,116.71 134.62,116.71 149.48,101.85 v1(149.86,101.85)
  BOTTOM w0.127: v1(149.86,101.85) 149.48,101.85 149.22,102.11 149.22,103.31 149.54,103.62 R882.2 R874.1
SDHC_WP: length 191.6
  TOP w0.127: U1.M5 v2(163.72,106.05)
  L3SIG w0.102: v2(163.72,106.05) 163.3,105.63 162.76,105.63 162.54,105.4 162.54,105.09 162.78,104.84 163.11,104.84 163.31,104.64 163.31,101.34 162.56,100.58 162.56,94.87 160.27,92.58 154.3,92.58 v1(153.42,93.47)
  BOTTOM w0.127: J2.11 25.78,34.28 27.56,36.07 29.34,36.07 29.63,36.36 U94.4 U94.5 29.63,38.65 32.89,41.91 47.62,41.91 56.26,50.55 56.26,66.93 64.77,75.44 117.16,75.44 123.89,82.17 143.26,82.17 153.42,92.33 v1(153.42,93.47) R65.1
SENSEGND: length 52.7
  TOP w0.254: U1.G20 v2(159.72,118.05)
  L6SIG w0.127: v2(159.72,118.05) 159.72,117.91 160.11,117.51 160.11,117.09 160.35,116.85 160.67,116.85 160.91,116.61 160.91,104.24 160.71,104.04 160.71,103.94
  L6SIG w0.254: v1(135.76,84.83) 136.05,85.12 136.99,85.12 137.75,85.88 137.75,91.02 139.5,92.77 143.25,92.77 150.2,99.72 158.8,99.72 160.71,101.63 160.71,101.86 160.71,103.94
SENSEGNDC: length 60.6
  TOP w0.254: U1.AB10 v2(172.52,110.05)
  L6SIG w0.127: 162.71,103.94 162.52,104.13 162.52,106.26 163.19,106.93 167.2,106.93 167.5,107.24 169.75,107.24
  L6SIG w0.254: v2(172.52,110.05) 172.29,109.82 171.98,109.82 171.46,109.31 171.46,107.49 171.02,107.04 169.95,107.04 169.75,107.24 ; v1(132.84,85.59) 132.84,83.97 133.69,83.12 140.3,83.12 145.22,88.05 145.22,90.74 151.99,97.51 154.67,97.51 155.58,98.43 159.89,98.43 162.73,101.26 162.73,103.92 162.71,103.94
  BOTTOM w0.254: TP16.1 v1(132.84,85.59)
SENSEVDD: length 90.9
  TOP w0.254: U1.G19 v2(159.72,117.25) ; R918.1 102.36,97.28 103.38,96.27 103.38,94.11 105.66,91.82 112.27,91.82 116.84,87.25 129.29,87.25 130.3,86.23 135.28,86.23 v1(135.76,85.75)
  L6SIG w0.127: 160.36,103.94 160.36,104.05 160.12,104.28 160.12,116.64 159.72,117.04 v2(159.72,117.25)
  L6SIG w0.254: v1(135.76,85.75) 136.05,85.47 136.84,85.47 137.39,86.02 137.39,91.17 139.36,93.13 143.1,93.13 150.05,100.08 158.65,100.08 160.36,101.78 160.36,103.94
SENSEVDD_EN_N: length 71.8
  TOP w0.127: v1(63.52,100.42) 63.02,100.92 U65.P7 ; U104.1 99.81,97.9 97.79,95.89 v1(97.79,77.09)
  L6SIG w0.102: v1(63.52,100.42) 64.02,99.92 64.02,96.77 70.74,90.04 70.74,85.98 72.01,84.71 73.53,84.71 74.17,84.07 74.17,83.19 77.47,79.88 79.76,79.88 82.04,77.6 94.62,77.6 95.12,77.09 v1(97.79,77.09)
SENSEVDDC: length 101
  TOP w0.254: v1(133.73,87.4) 131.16,87.4 129.92,88.65 117.48,88.65 112.9,93.22 106.3,93.22 104.9,94.62 104.9,96.9 102.61,99.19 R917.1 ; U1.AB9 v2(172.52,109.25)
  L6SIG w0.127: 163.11,103.94 163.32,104.15 163.32,106.43 163.58,106.68 167.2,106.68 167.44,106.44 169.69,106.44 169.8,106.55
  L6SIG w0.254: v2(172.52,109.25) 172.29,109.47 172.13,109.47 171.82,109.16 171.82,107.34 171.37,106.89 171.16,106.68 169.93,106.68 169.8,106.55 ; 163.11,103.94 163.11,101.11 160.05,98.04 155.74,98.04 154.82,97.13 152.15,97.13 145.61,90.58 145.61,87.89 140.45,82.74 140.14,82.74 133.53,82.74 131.61,84.67 131.61,86.18 132.58,87.15 133.48,87.15 v1(133.73,87.4)
SGMII_RX_N: length 49.7
  TOP w0.102: U108.V6 245.82,56.39 245.71,56.29 245.55,56.29 245.45,56.39 245.45,57.19 245.53,57.26 245.53,57.28
  TOP w0.127: 245.53,57.28 245.53,60.16 arc(245.46,61.7) 245.26,63.23 244.71,66.35 arc(244.44,69.45) 244.71,72.55 246,79.88 arc(246.23,82.49) 246,85.11 244.54,93.39 arc(244.27,94.3) 243.82,95.13 243.25,95.95 arc(241.83,97.64) 240.14,99.06 239.64,99.41 arc(239.25,99.62) 238.83,99.74 237.24,100.02 236.63,100.02 236.55,100.1 U110.13
SGMII_RX_P: length 49.7
  TOP w0.102: 245.17,57.28 245.17,57.25 245.21,57.21 arc(245.24,57.17) 245.25,57.13 245.25,56.08 U108.U6
  TOP w0.127: 245.17,57.28 245.17,60.16 arc(245.1,61.67) 244.91,63.17 244.36,66.29 arc(244.08,69.45) 244.36,72.61 245.65,79.94 arc(245.87,82.49) 245.65,85.04 244.19,93.33 arc(243.95,94.16) 243.53,94.93 242.95,95.75 arc(241.58,97.39) 239.93,98.77 239.44,99.12 arc(239.12,99.29) 238.76,99.39 237.2,99.67 236.63,99.67 236.55,99.6 U110.12
SGMII_TX_N: length 48.8
  TOP w0.127: C1285.1 247.95,61.25 arc(248.07,61.43) 248.11,61.63 248.11,64.22 arc(248.12,64.44) 248.15,64.66 250.56,78.34 arc(250.85,81.71) 250.56,85.08 249.3,92.2 arc(248.89,93.62) 248.18,94.91 248.12,94.99 arc(246.54,96.88) 244.65,98.46 243.64,99.17 arc(242.23,99.95) 240.69,100.4 240.66,100.41 arc(239.09,100.61) 237.5,100.68 236.64,100.68 236.55,100.6 U110.14
SGMII_TX_P: length 49.4
  TOP w0.127: U110.15 236.55,101.1 236.61,101.04 237.5,101.04 arc(239.12,100.97) 240.72,100.76 240.72,100.76 arc(240.74,100.75) 240.75,100.75 arc(242.36,100.28) 243.84,99.47 244.86,98.75 arc(246.79,97.13) 248.41,95.2 248.47,95.12 arc(249.22,93.75) 249.65,92.26 250.91,85.14 arc(251.21,81.71) 250.91,78.28 248.5,64.6 arc(248.47,64.41) 248.46,64.22 248.46,61.63 arc(248.5,61.43) 248.62,61.25 C1286.1
SPI_CLK: length 150.4
  TOP w0.127: v1(269.49,139.31) R865.1 R867.2
  L6SIG w0.102: v1(269.49,139.31) 269.49,135.51 268.92,134.94 268.92,133.67 255.59,120.33 255.59,117.86 244.28,106.55 216.28,106.55 195.07,85.34 167.13,85.34 164.85,87.63 161.16,87.63 v1(160.91,87.88)
  BOTTOM w0.127: R59.2 164.47,97.54 163.58,96.65 163.58,95.38 160.83,92.63 160.83,87.96 v1(160.91,87.88)
SPI_CS0_N: length 147.9
  TOP w0.127: 260.73,133.13 259.68,133.13 259.08,133.73 v1(256.41,133.73) R56.1 ; U1.M1 164.02,103.15 164.02,98.86 160.91,95.75 160.91,92.58 160.44,92.11 160.44,88.55 v1(160.27,88.39)
  L6SIG w0.102: v1(160.27,88.39) 160.83,88.95 162.38,88.95 162.69,88.65 165.23,88.65 167.64,86.23 194.58,86.23 216.04,107.7 243.9,107.7 253.62,117.41 253.62,132.72 254.63,133.73 v1(256.41,133.73)
SPI_MISO: length 160.9
  TOP w0.127: R58.1 R54.1 v1(254.63,130.68) 268.99,130.68 274.57,136.27 R868.2 ; U1.P1 165.72,98.74 162.56,95.59 162.56,92.2 162.18,91.82 v1(162.18,88.52)
  L6SIG w0.102: v1(254.63,130.68) 254.63,118.05 243.9,107.32 216.03,107.32 194.69,85.98 167.51,85.98 165.1,88.39 162.31,88.39 v1(162.18,88.52)
SPI_MOSI: length 157.7
  TOP w0.127: R869.2 273.56,136.78 272.92,136.14 270,136.14 269.49,136.65 R866.1 v1(268.74,137.55) ; U1.P2 165.35,103.68 165.35,98.93 162.18,95.76 162.18,92.46 161.42,91.69 v1(161.42,88.39)
  L6SIG w0.102: v1(268.74,137.55) 268.48,137.29 268.48,133.86 255.21,120.59 255.21,118.11 244.03,106.93 215.97,106.93 194.76,85.73 167.39,85.73 165.1,88.01 161.8,88.01 v1(161.42,88.39)
SYS_REFCLK: length 85
  TOP w0.127: v1(90.3,101.73) 90.29,101.72 R513.2 R511.2 ; U1.G15 v2(159.72,114.85)
  BOTTOM w0.127: v1(90.3,101.73) 92.08,103.51 92.08,112.57 95.46,115.95 112.69,115.95 114.21,117.48 146.94,117.48 149.44,114.97 154.65,114.97 155.17,114.45 159.31,114.45 159.71,114.85 v2(159.72,114.85)
SYS_REFCLK_N: length 84.6
  TOP w0.102: R837.2 231.02,135.51 230.75,135.51 R838.1 230.37,135.36 230.12,135.61 228.12,135.61 v1(227.84,135.33) ; U1.F14 v2(158.92,113.25)
  L3SIG w0.102: v2(158.92,113.25) 159.3,112.87 159.87,112.87 160.1,113.09 160.1,113.47 160.54,113.92 171.58,113.92 171.81,114.15 180.96,114.15 185.28,118.47 210.3,118.47 220.08,128.24 222.11,128.24 226.95,133.08 226.95,134.93 227.34,135.33 v1(227.84,135.33)
SYS_REFCLK_P: length 84.7
  TOP w0.102: v1(227.84,136.17) 228.12,135.89 230.12,135.89 230.37,136.14 R835.1 230.75,136.02 231.02,136.02 R836.2 ; U1.G14 v2(159.72,113.25)
  L3SIG w0.102: v2(159.72,113.25) 159.47,113.25 159.36,113.35 159.36,113.69 159.47,113.79 160.02,113.79 160.43,114.2 171.46,114.2 171.69,114.43 180.85,114.43 185.17,118.75 210.19,118.75 219.96,128.52 222,128.52 226.67,133.2 226.67,135.05 227.33,135.71 227.33,136.07 227.43,136.17 v1(227.84,136.17)
SYSCLK_OE: length 35.8
  TOP w0.127: X3.1 81.48,94.62 77.85,94.62 74.93,97.54 74.93,100.08 72.58,102.42 71.52,102.42 71.02,102.93 U65.M15 ; X3.1 83.95,93.78 83.95,88.83 X1.1 ; X3.1 83.95,97.09 83.95,102.04 X5.1
TDMA_RCK_CLK8_12: length 159.4
  TOP w0.127: U1.M4 v2(163.72,105.25) ; v1(271.15,148.97) 273.92,151.74 J43.21
  L6SIG w0.102: v2(163.72,105.25) 164.21,104.75 164.21,104.14 163.96,103.89 163.96,100.08 167.84,96.19 167.84,95.85 167.84,95.85 167.84,95.51 168.56,94.79 173.18,94.79 175.49,92.48 198.15,92.48 215.58,109.92 243.01,109.92 251.59,118.49 251.59,134.62 254.13,137.16 256.54,137.16 263.88,144.5 263.88,146.83 263.88,146.83 263.88,147.42 264.69,148.23 264.69,149.06 265.7,150.06 267.64,150.06 268.73,148.97 v1(271.15,148.97)
TDMA_RQ: length 151.9
  TOP w0.127: U1.R2 v2(166.92,103.65) ; J43.3 v1(274.47,157.46)
  L3SIG w0.102: v1(263.4,152.4) 263.4,152.78 268.08,157.46 v1(274.47,157.46)
  L6SIG w0.102: v2(166.92,103.65) 167.3,103.27 167.3,102.58 171.2,98.68 174.62,98.68 177.67,95.63 197.61,95.63 214.63,112.65 238.32,112.65 241.81,116.14 245.24,116.14 248.92,119.82 248.92,135.64 254.25,140.97 256.67,140.97 260.73,145.03 260.73,148.34 261.75,149.35 261.75,150.11 263.4,151.76 v1(263.4,152.4)
TDMA_RSYNC: length 145.9
  TOP w0.127: J43.11 275.19,154.92 v1(274.32,154.05) ; U1.U1 v2(168.52,102.85)
  L3SIG w0.102: v1(260.22,150.11) 261.37,151.26 271.91,151.26 274.32,153.67 v1(274.32,154.05)
  L6SIG w0.102: v1(260.22,150.11) 260.22,149.35 259.59,148.72 259.59,147.45 248,135.86 248,120.17 244.79,116.97 241.3,116.97 237.93,113.6 214.44,113.6 197.61,96.77 178.05,96.77 175.06,99.77 171.59,99.77 v2(168.52,102.85)
TDMA_RXD: length 145.2
  TOP w0.127: v1(275.08,153.54) 275.08,153.8 275.57,154.28 J43.13 ; U1.U2 v2(168.52,103.65)
  L3SIG w0.102: v1(259.59,149.35) 260.22,149.35 261.75,150.88 272.42,150.88 v1(275.08,153.54)
  L6SIG w0.102: v1(259.59,149.35) 259.21,148.97 259.21,147.45 247.71,135.95 247.71,120.33 244.6,117.22 241.11,117.22 237.81,113.92 214.38,113.92 197.61,97.16 178.18,97.16 174.5,100.84 171.32,100.84 v2(168.52,103.65)
TDMA_TCK_CLK9: length 155.9
  TOP w0.127: J43.17 274.04,153.01 v1(271.4,150.37) ; U1.P4 v2(165.32,105.25)
  L6SIG w0.102: v1(271.4,150.37) 270.64,151.13 268.48,151.13 268.22,151.38 265.18,151.38 263.47,149.68 263.47,148.92 262.38,147.83 262.38,144.91 256.16,138.68 253.75,138.68 250.16,135.1 250.16,119.09 245.85,114.78 245.66,114.78 245.62,114.74 242.38,114.74 238.95,111.32 215.07,111.32 197.74,93.98 175.89,93.98 173.28,96.6 171.5,96.6 170.97,97.13 169.06,97.13 165.75,100.44 165.75,104.81 v2(165.32,105.25)
TDMA_TSYNC: length 151.4
  TOP w0.127: U1.R1 v2(166.92,102.85) ; v1(273.81,154.81) 274.55,155.55 J43.9
  L3SIG w0.102: v1(273.81,154.81) 273.81,153.87 272.98,153.03 269.49,153.03 268.99,153.54 265.43,153.54 v1(264.29,152.4)
  L6SIG w0.102: v1(264.29,152.4) 264.29,152.15 262.25,150.11 262.25,149.35 261.11,148.21 261.11,145.03 255.78,139.7 253.36,139.7 249.17,135.51 249.17,119.63 245.36,115.82 241.87,115.82 238.44,112.4 214.76,112.4 197.61,95.25 177.55,95.25 174.47,98.32 171.04,98.32 166.92,102.45 v2(166.92,102.85)
TDMA_TXD: length 150
  TOP w0.127: U1.T1 v2(167.72,102.85) ; J43.7 v1(275.23,156.19)
  L3SIG w0.102: v1(275.23,156.19) 274.57,156.84 267.97,156.84 263.86,152.73 263.86,152.22 263.53,151.89 v1(262.76,151.89)
  L6SIG w0.102: v2(167.72,102.85) 167.72,102.67 171.32,99.06 174.75,99.06 177.8,96.01 197.61,96.01 214.57,112.97 238.25,112.97 241.68,116.4 245.11,116.4 248.6,119.89 248.6,135.7 254.13,141.22 256.41,141.22 260.35,145.16 260.35,148.46 261.24,149.35 261.24,150.37 v1(262.76,151.89)
TDMB_RCK_CLK10: length 155.7
  TOP w0.127: J43.29 274.55,149.2 v1(273.94,148.59) ; U1.P3 v2(165.32,104.45)
  L6SIG w0.102: v1(273.94,148.59) 272.64,149.89 271.22,149.89 270.38,150.72 268.25,150.72 268.1,150.88 265.3,150.88 263.88,149.45 263.88,148.63 262.89,147.64 262.89,144.78 256.29,138.18 253.87,138.18 250.67,134.97 250.67,118.84 242.7,110.87 215.26,110.87 197.87,93.47 175.77,93.47 173.05,96.19 168.99,96.19 168.66,96.52 168.66,96.84 168.66,96.9 165.32,100.24 v2(165.32,104.45)
TDMB_RQ: length 146.5
  TOP w0.127: U1.R4 v2(166.92,105.25) ; v1(265.68,151.89) 266.47,151.11 J43.24
  L6SIG w0.102: v2(166.92,105.25) 166.15,104.48 166.15,100.67 169.29,97.54 174.24,97.54 177.29,94.49 197.61,94.49 214.88,111.76 238.76,111.76 242.19,115.19 245.68,115.19 249.71,119.22 249.71,135.29 253.62,139.19 256.03,139.19 261.87,145.03 261.87,147.96 263.07,149.15 263.07,149.35 263.07,149.36 263.07,149.91 265.05,151.89 v1(265.68,151.89)
TDMB_RSYNC: length 141.3
  TOP w0.127: v1(266.57,152.91) 266.68,153.01 J43.18 ; U1.T3 v2(167.72,104.45)
  L6SIG w0.102: v1(266.57,152.91) 263.02,152.91 260.73,150.62 260.73,149.35 259.97,148.59 259.97,145.25 256.2,141.48 254,141.48 248.28,135.76 248.28,120.08 244.92,116.71 241.49,116.71 238.06,113.28 214.5,113.28 197.61,96.39 177.93,96.39 174.88,99.44 171.32,99.44 168.14,102.63 168.14,103.77 167.72,104.19 v2(167.72,104.45)
TDMB_RXD: length 147.5
  TOP w0.127: J43.1 v1(275.23,158.09) ; U1.U4 v2(168.52,105.25)
  L3SIG w0.102: v1(262,153.29) 263.4,153.29 268.2,158.09 v1(275.23,158.09)
  L6SIG w0.102: v2(168.52,105.25) 168.91,104.85 168.91,104.28 171.59,101.6 174.75,101.6 178.56,97.79 197.48,97.79 214.25,114.55 237.55,114.55 240.79,117.79 244.22,117.79 247.11,120.68 247.11,136.11 258.44,147.45 258.44,149.73 v1(262,153.29)
TDMB_TCK_CLK11: length 160.6
  TOP w0.127: J43.39 275.31,146.03 275.08,145.8 v1(274.19,145.8) ; U1.N4 v2(164.52,105.25)
  L6SIG w0.102: v2(164.52,105.25) 164.91,104.85 164.91,100.01 168.25,96.67 168.25,95.68 168.73,95.2 173.41,95.2 175.72,92.89 197.92,92.89 215.46,110.43 242.89,110.43 251.17,118.71 251.17,134.84 254,137.67 256.41,137.67 263.4,144.65 263.4,147.57 264.29,148.46 264.29,149.22 265.53,150.47 267.87,150.47 268.86,149.48 272.16,149.48 273.48,148.16 274.37,148.16 274.7,147.83 274.7,146.3 v1(274.19,145.8)
TDMB_TSYNC: length 144.1
  TOP w0.127: v1(266.57,151.89) 266.72,151.74 J43.22 ; U1.R3 v2(166.92,104.45)
  L6SIG w0.102: v2(166.92,104.45) 166.5,104.03 166.5,102.36 170.94,97.92 174.37,97.92 177.42,94.87 197.61,94.87 214.82,112.08 238.63,112.08 242.06,115.51 245.55,115.51 249.43,119.38 249.43,135.38 253.49,139.45 255.91,139.45 261.47,145.01 261.47,148.06 262.64,149.22 262.64,149.99 265.05,152.4 266.06,152.4 v1(266.57,151.89)
TDMB_TXD: length 139.5
  TOP w0.127: J43.20 267.23,152.38 v1(267.21,152.4) ; U1.T4 v2(167.72,105.25)
  L6SIG w0.102: v1(267.21,152.4) 267.21,153.01 266.8,153.42 262.89,153.42 258.83,149.35 258.83,147.45 247.4,136.02 247.4,120.46 244.41,117.48 240.92,117.48 237.68,114.24 214.31,114.24 197.61,97.54 178.31,97.54 174.62,101.22 171.48,101.22 168.67,104.03 168.36,104.03 168.13,104.25 168.13,104.83 v2(167.72,105.25)
TDMR1_INT_N: length 267.2
  TOP w0.127: v1(68.52,99.42) 68.02,99.92 U65.R12 ; J43.31 275.06,148.57 v1(274.19,147.7) ; R850.2 266.19,148.59 v1(266.45,148.34)
  L6SIG w0.102: v1(68.52,99.42) 68.52,97.6 70.1,96.01 75.06,96.01 76.33,94.74 76.33,87.38 78.74,84.96 83.82,84.96 88.37,80.42 116.39,80.42 118.45,78.36 143.7,78.36 155.25,89.92 165.48,89.92 168.4,87 193.97,87 215.82,108.84 243.52,108.84 252.6,117.92 252.6,134.24 254.51,136.14 256.92,136.14 265.63,144.86 265.63,147.52 v1(266.45,148.34) 267.08,147.7 271.15,147.7 271.4,147.45 273.05,147.45 273.35,147.75 274.14,147.75 v1(274.19,147.7)
TDMR2_INT_N: length 269.8
  TOP w0.127: v1(67.52,100.42) 67.02,100.92 U65.P11 ; J43.33 275.31,147.93 v1(274.19,146.81) ; R851.2 266.32,147.57 v1(266.45,147.45)
  L6SIG w0.102: v1(67.52,100.42) 68.02,99.92 68.02,97.72 69.98,95.76 74.87,95.76 76.07,94.56 76.07,87.25 78.61,84.71 83.57,84.71 85.98,82.3 85.98,81.66 88.27,79.38 92.71,79.38 93.5,80.16 116.29,80.16 118.34,78.11 144.82,78.11 156.38,89.66 165.35,89.66 168.28,86.74 194.08,86.74 215.79,108.46 243.65,108.46 252.86,117.67 252.86,134.11 254.64,135.89 257.94,135.89 265.94,143.89 265.94,146.94 v1(266.45,147.45) 266.57,147.32 271.02,147.32 271.27,147.07 273.18,147.07 273.43,146.81 v1(274.19,146.81)
TDMR_PRS_N: length 268.4
  TOP w0.127: v1(68.52,100.42) 68.02,100.92 U65.P12 ; J43.27 274.3,149.84 v1(272.67,148.21) ; R849.2 266.19,149.61 266.45,149.35 v1(266.45,149.22)
  L6SIG w0.102: v1(272.67,148.21) 272.24,147.78 271.58,147.78 271.27,148.08 267.59,148.08 v1(266.45,149.22) 265.56,148.34 265.56,147.93 265.33,147.7 265.33,144.93 256.79,136.4 254.38,136.4 252.28,134.3 252.28,118.11 243.33,109.16 215.77,109.16 193.87,87.25 168.53,87.25 165.61,90.17 155.15,90.17 143.59,78.61 118.55,78.61 116.01,81.15 88.14,81.15 82.93,86.36 78.87,86.36 76.58,88.65 76.58,94.87 75.18,96.27 70.23,96.27 69.02,97.48 69.02,99.92 v1(68.52,100.42)
TDMR_RST_N: length 268.4
  TOP w0.127: U65.R11 67.02,99.92 v1(67.52,99.42) ; R852.2 v1(266.45,146.56) ; J43.35 275.44,147.3 274.45,146.3 v1(273.56,146.3)
  L6SIG w0.102: v1(67.52,99.42) 67.52,97.84 69.85,95.5 74.68,95.5 75.82,94.36 75.82,87.12 78.49,84.45 83.31,84.45 85.6,82.17 85.6,81.53 88.01,79.12 92.96,79.12 93.69,79.84 116.24,79.84 118.24,77.85 144.92,77.85 156.48,89.41 165.23,89.41 168.15,86.49 194.18,86.49 215.77,108.08 243.78,108.08 253.11,117.41 253.11,133.98 254.76,135.64 258.06,135.64 266.45,144.02 v1(266.45,146.56) 266.57,146.69 273.18,146.69 v1(273.56,146.3)
TDMR_SLP_N: length 265.9
  TOP w0.127: v1(272.03,148.97) 273.54,150.47 J43.25 ; U65.R13 69.02,99.92 v1(69.52,99.42)
  L6SIG w0.102: v1(69.52,99.42) 69.52,97.36 70.36,96.52 75.31,96.52 76.84,95 76.84,88.77 78.99,86.61 83.06,86.61 88.27,81.41 116.12,81.41 118.66,78.87 143.49,78.87 155.04,90.42 165.73,90.42 168.66,87.5 193.76,87.5 215.73,109.47 243.14,109.47 251.99,118.32 251.99,134.39 254.25,136.65 256.67,136.65 264.29,144.27 264.29,147.19 265.1,148.01 265.1,148.89 265.87,149.66 266.65,149.66 267.84,148.46 271.53,148.46 v1(272.03,148.97)
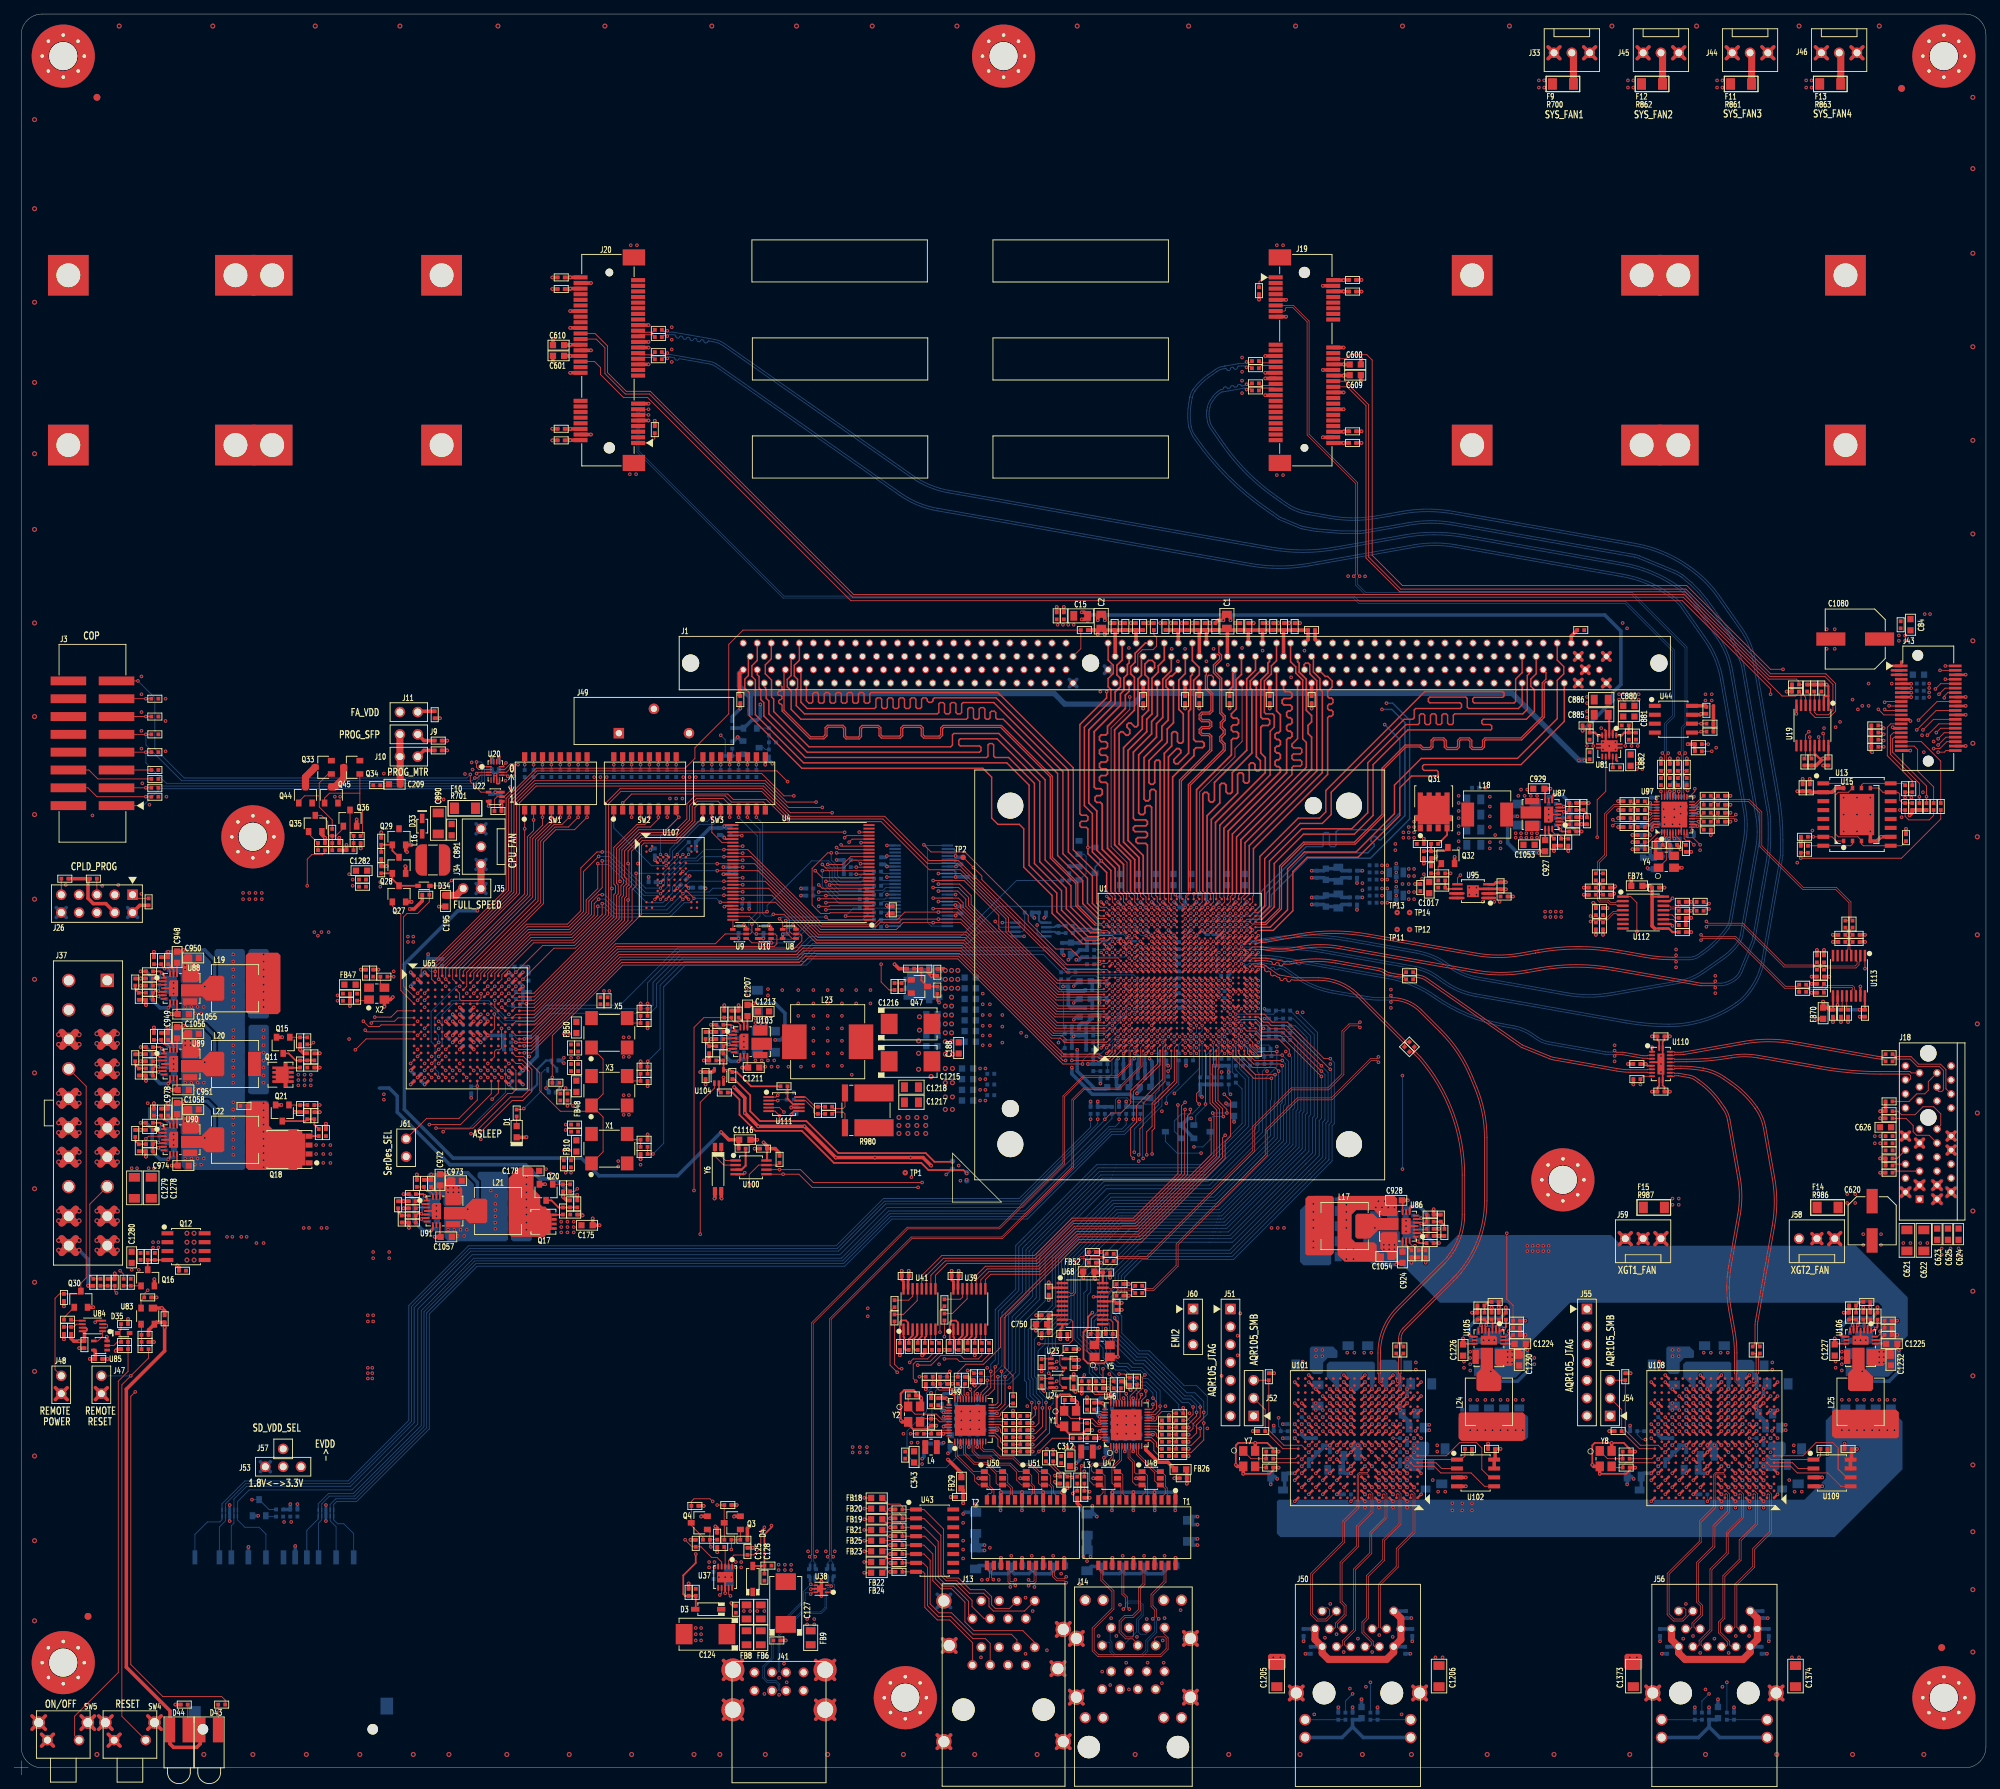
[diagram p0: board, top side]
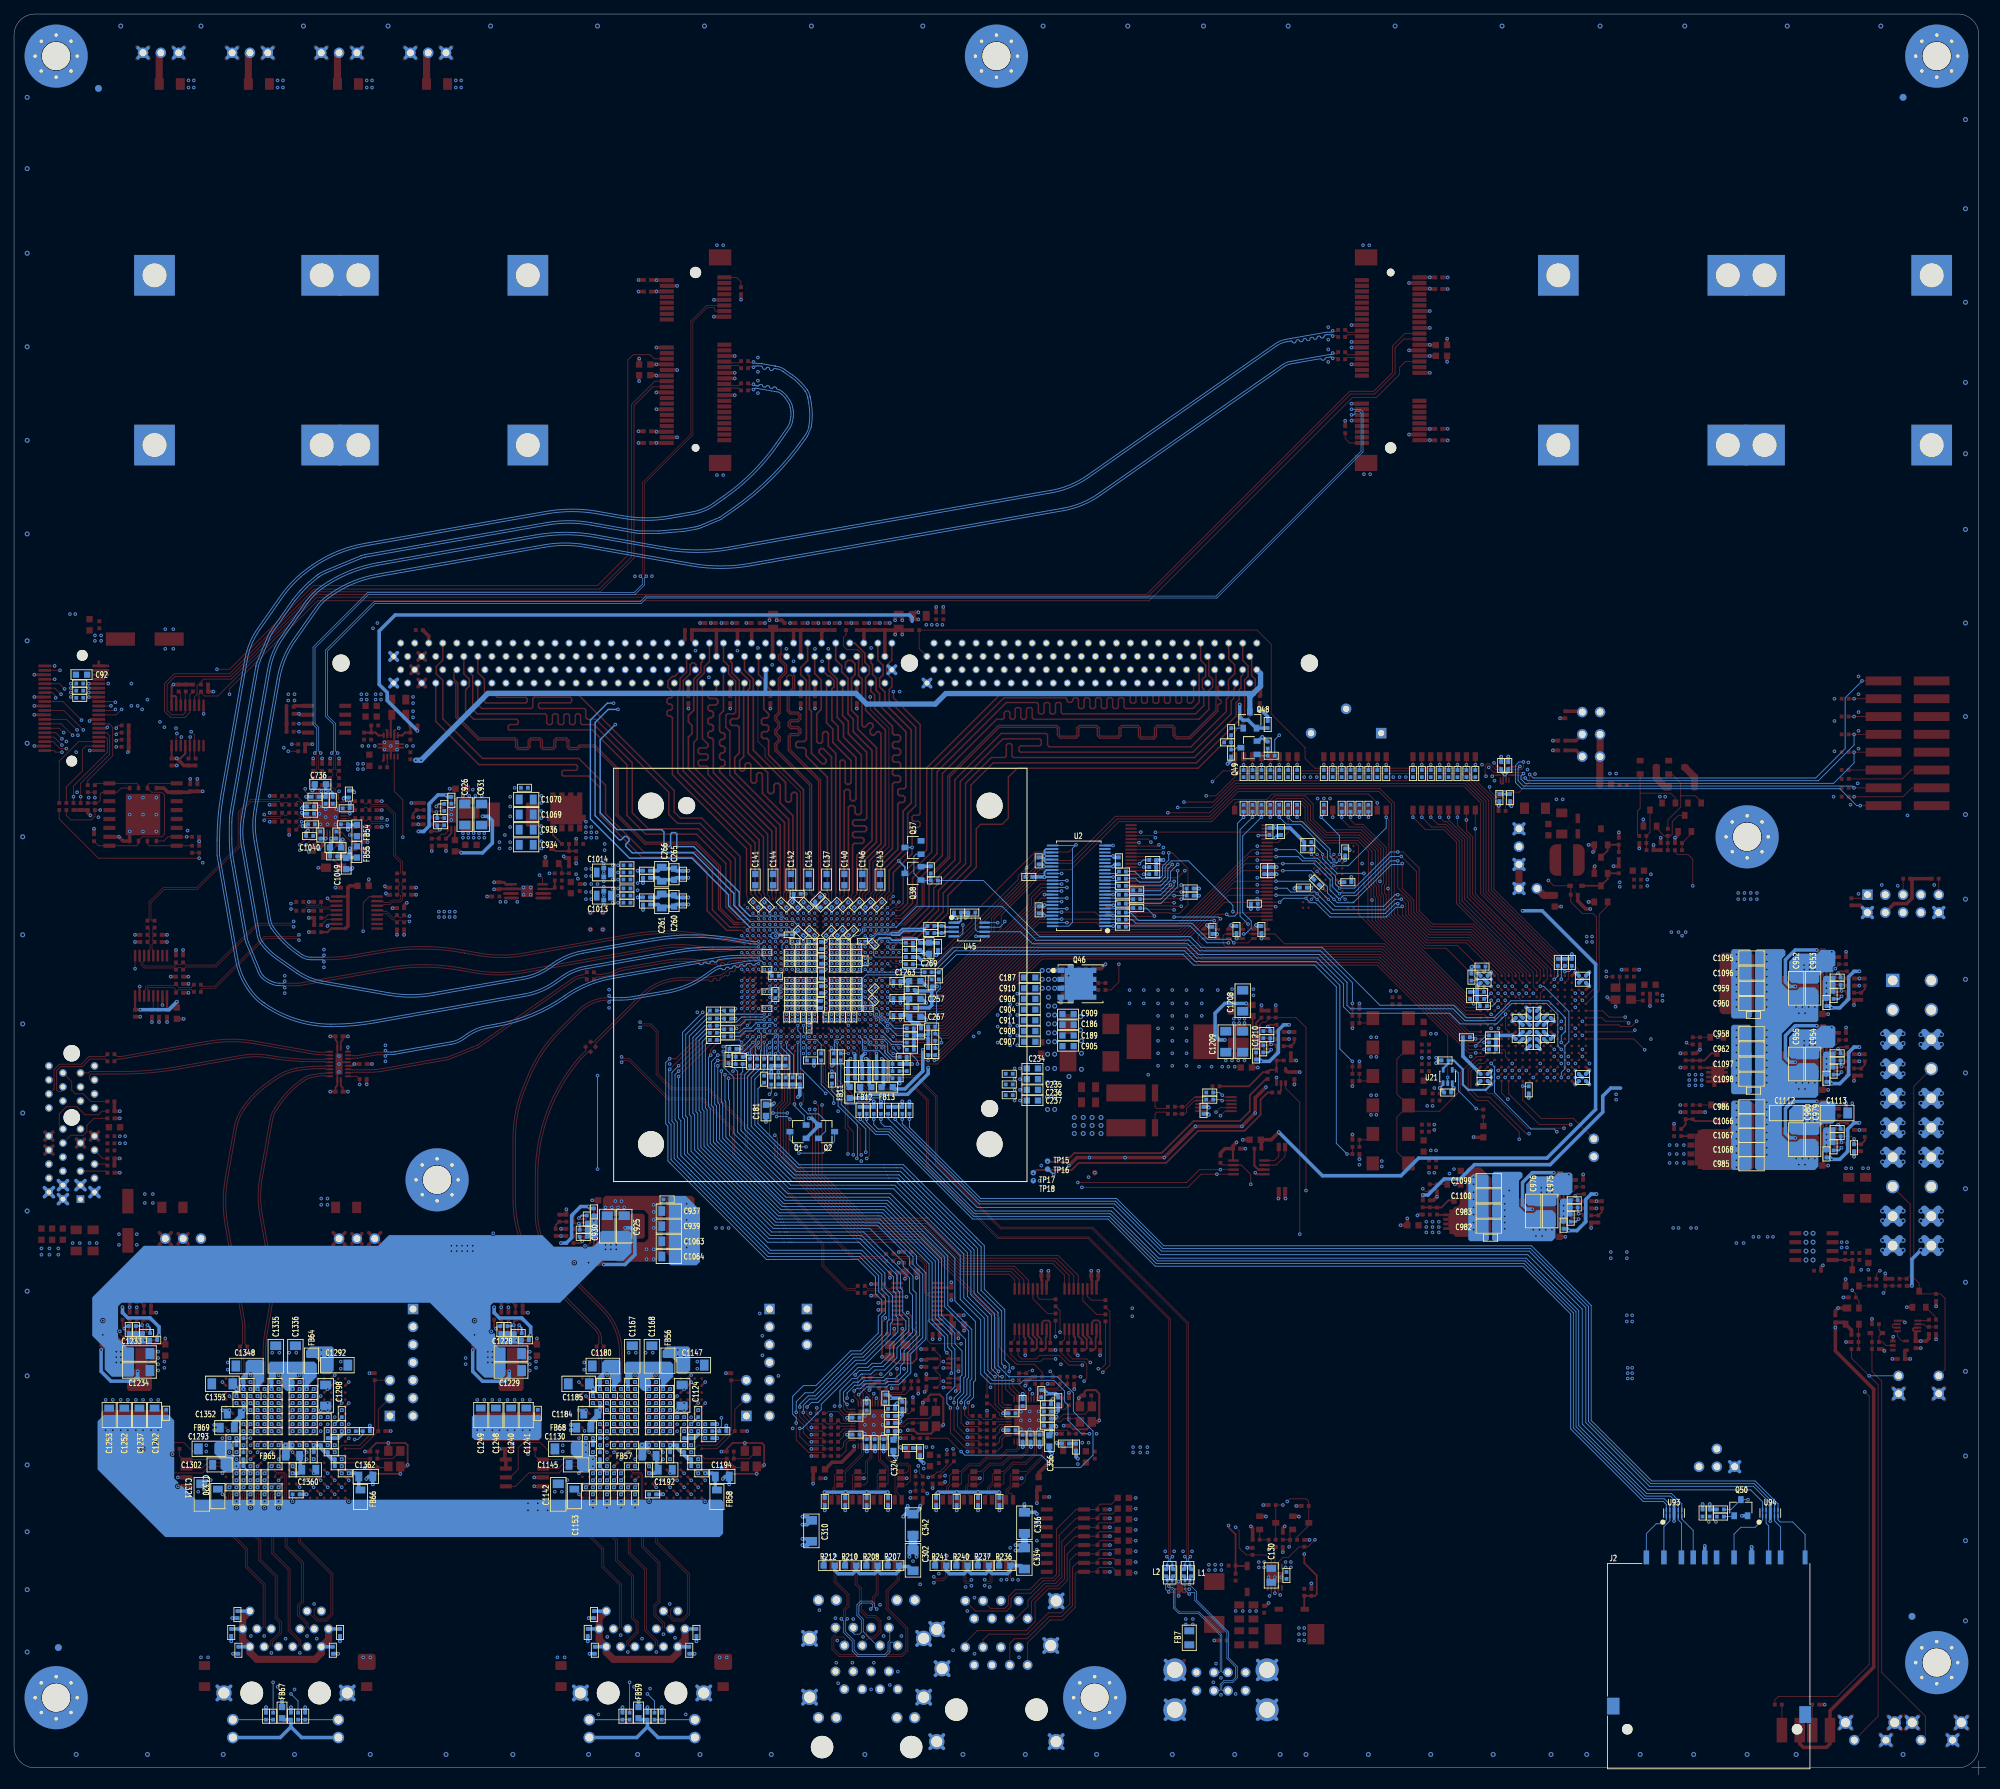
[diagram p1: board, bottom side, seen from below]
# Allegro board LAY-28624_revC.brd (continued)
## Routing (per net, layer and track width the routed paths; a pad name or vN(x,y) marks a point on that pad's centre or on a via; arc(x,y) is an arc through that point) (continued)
TDMR_SPI_CS0_N: length 171.2
  TOP w0.127: R872.1 v1(271.53,139.45) 271.53,141.35 267.4,145.48 267.4,148.15 267.82,148.57 J43.32 ; U1.M2 163.7,103.63 163.7,99.19 159.96,95.44 159.96,93.03 159.13,92.21 159.13,88.27 v1(159.51,87.88)
  L6SIG w0.102: v1(159.51,87.88) 159.51,87.38 159.82,87.07 164.77,87.07 166.88,84.96 195.33,84.96 216.53,106.17 244.54,106.17 255.97,117.6 255.97,120.08 271.53,135.64 v1(271.53,139.45)
TDMR_SPI_CS1_N: length 172.8
  TOP w0.127: R871.1 v1(272.54,139.45) 272.54,140.97 267.72,145.8 267.72,147.7 267.95,147.93 J43.34 ; U1.M3 v2(163.72,104.45)
  L6SIG w0.102: v1(272.54,139.45) 272.54,137.67 271.91,137.03 271.91,135.44 256.45,119.98 256.45,117.57 244.69,105.82 216.56,105.82 195.45,84.71 166.75,84.71 164.72,86.74 159.51,86.74 159,87.25 159,88.14 v1(159.64,88.77)
  BOTTOM w0.127: v2(163.72,104.45) 163.72,97.42 163.13,96.83 163.13,95.57 159.64,92.07 v1(159.64,88.77)
TEMP_DIODE_N: length 10.2
  TOP w0.254: U1.G21 v2(159.72,119.65)
  BOTTOM w0.127: v2(159.72,119.65) 159.71,119.65 159.31,119.25 158.63,119.25 158.09,119.79 156.02,119.79 155.96,119.72 155.92,119.72
  BOTTOM w0.254: 155.92,119.72 154.86,119.72 154.28,120.29 151.15,120.29 R206.1
TEMP_DIODE_P: length 9.2
  TOP w0.254: U1.E21 v2(158.92,119.65)
  BOTTOM w0.127: 155.92,120.08 155.96,120.08 156.02,120.01 158.18,120.01 158.55,119.65 v2(158.92,119.65)
  BOTTOM w0.254: R205.1 151.25,120.65 154.43,120.65 155,120.08 155.92,120.08
TEST_SEL_N: length 155
  TOP w0.127: U1.G8 v2(159.72,108.45) ; SW3.8 107.06,138.43 106.81,138.68 102.23,138.68 101.35,139.57 97.03,139.57 95.89,138.43 95.89,136.27 93.98,134.37 89.15,134.37 86.61,131.83 86.61,127.89 86.87,127.63 86.87,127.13 86.49,126.75 86.49,125.48 86.23,125.22 86.23,122.05 74.11,109.93 73.03,109.93 v1(73.02,109.93) 73.02,109.93 U65.E16
  L6SIG w0.102: v2(159.72,108.45) 159.72,108.41 159.3,107.99 159.3,105.89 159.07,105.66 158.79,105.66 158.54,105.4 158.54,105.13 158.24,104.83 157.96,104.83 157.7,104.57 157.7,104.29 157.47,104.07 149.4,104.07 149.23,103.89 148.21,103.89 136.65,115.44 126.62,115.44 125.86,116.2 79.88,116.2 73.61,109.93 v1(73.02,109.93)
  BOTTOM w0.127: R83.1 73.52,110.43 v1(73.02,109.93)
THERM_ALERT_N: length 100.2
  TOP w0.127: U65.M4 v1(60.51,103.42)
  BOTTOM w0.127: v1(60.51,103.42) 61.01,103.92 61.01,108.38 62.61,109.98 67.56,109.98 69.98,107.57 74.3,107.57 75.95,109.22 90.55,109.22 91.06,109.73 91.06,112.99 95.04,116.97 112.27,116.97 113.79,118.49 135.89,118.49 137.6,120.2 U45.6 143.69,120.2 144.03,120.53 R853.1
THERM_FAULT_N: length 128.3
  TOP w0.127: U65.D1 57.01,110.93 55.5,112.44 55.5,122.3 56.01,122.81 57.53,122.81 59.17,124.45 R204.1 59.17,126.65 D34.1 61.59,126.75 v1(62.36,127.51)
  L3SIG w0.102: v1(62.36,127.51) 62.74,127.89 66.68,127.89 67.69,128.91 67.69,136.78 68.58,137.67 68.58,139.45 70.61,141.48 90.42,141.48 95.88,136.02 101.85,136.02 102.36,135.51 120.14,135.51 123.83,131.83 124.59,131.83 127.38,129.03 134.37,129.03 142.24,121.16 v1(145.8,121.16)
  BOTTOM w0.127: v1(145.8,121.16) 145.8,120.02 146.26,119.55 U45.4
U_EC2_GTXCLK: length 8.9
  TOP w0.127: U1.AC8 v2(173.32,108.45)
  BOTTOM w0.127: v2(173.32,108.45) 173.72,108.04 177.33,108.04 178.05,107.32 179.5,107.32 179.82,107.64 C56.1 R128.1
U_EC2_TXCTL: length 7.6
  TOP w0.127: U1.AD8 v2(174.12,108.45)
  BOTTOM w0.127: R126.1 R124.1 179.82,108.79 179.48,108.45 v2(174.12,108.45)
U_EC2_TXD0: length 6.6
  TOP w0.127: U1.AC7 v2(173.32,107.65)
  L3SIG w0.102: v1(178.05,106.43) 177.21,107.27 173.7,107.27 v2(173.32,107.65)
  BOTTOM w0.127: R117.1 178.18,106.3 v1(178.05,106.43)
U_EC2_TXD1: length 7.7
  TOP w0.127: U1.AD7 v2(174.12,107.65)
  BOTTOM w0.127: R118.1 180.79,106.87 177.48,106.87 176.71,107.65 v2(174.12,107.65)
U_EC2_TXD2: length 9.7
  TOP w0.127: U1.AB6 v2(172.52,106.85)
  BOTTOM w0.127: R120.1 177.67,105.79 177.02,106.44 176.01,106.44 175.21,107.24 172.91,107.24 v2(172.52,106.85)
U_EC2_TXD3: length 6.7
  TOP w0.127: U1.AC6 v2(173.32,106.85)
  BOTTOM w0.127: R122.1 177.55,105.28 176.78,106.05 175.64,106.05 175.25,106.44 173.72,106.44 v2(173.32,106.85)
UART1_CTS_N: length 58.5
  TOP w0.127: U39.9 138.42,70.6 139.19,71.37 146.3,71.37 151.64,76.71 160.4,76.71 171.8,88.1 171.8,94.9 170.81,95.89 170.81,101.22 170.94,101.35 170.94,103.63 170.53,104.05 U1.Y2
UART1_RTS_N: length 57.7
  TOP w0.127: U1.Y1 170.43,103.16 170.43,95.76 171.4,94.8 171.4,88.21 160.27,77.09 151.51,77.09 146.18,71.76 138.94,71.76 137.77,70.59 U39.10
UART1_RXD: length 59.9
  TOP w0.127: U39.12 136.47,70.56 138.43,72.52 145.92,72.52 151.26,77.85 160.02,77.85 170.6,88.43 170.6,93.31 v1(170.43,93.47) ; U1.AA1 171.32,101.08 171.2,100.97 171.2,96.01 172.21,95 172.21,93.98 v1(172.34,93.85)
  BOTTOM w0.127: v1(172.34,93.85) 170.81,93.85 v1(170.43,93.47)
UART1_TXD: length 61.1
  TOP w0.127: U39.11 137.12,70.57 138.68,72.14 146.05,72.14 151.38,77.47 160.15,77.47 171,88.32 171,94.18 v1(170.81,94.36) ; v1(172.85,94.36) 172.85,94.87 171.58,96.14 171.58,100.58 171.7,100.71 171.7,103.66 U1.AA2
  BOTTOM w0.127: v1(170.81,94.36) v1(172.85,94.36)
UART2_CTS_N: length 68.4
  TOP w0.127: U1.Y4 v2(170.92,105.25) ; U41.9 131.31,71.24 132.97,72.9 145.8,72.9 151.13,78.23 159.89,78.23 167.22,85.56 167.22,93.94 167.64,94.36 v1(167.64,94.87)
  L3SIG w0.102: v1(167.64,94.87) 167.18,95.33 166.68,95.33 166.37,95.63 166.37,96.14 168.53,98.3 170.43,98.3 171.32,99.19 171.32,104.84 v2(170.92,105.25)
UART2_RTS_N: length 68
  TOP w0.127: v1(166.88,94.87) 166.82,94.81 166.82,85.67 159.77,78.61 151,78.61 145.67,73.28 132.72,73.28 130.66,71.22 U41.10 ; U1.V4 v2(169.32,105.25)
  L3SIG w0.102: v1(166.88,94.87) 165.86,94.87 165.35,95.38 165.35,96.14 168.27,99.06 169.29,99.06 169.7,99.47 169.7,104.87 v2(169.32,105.25)
UART2_RXD: length 67.4
  TOP w0.127: U41.12 129.36,71.19 132.21,74.04 145.41,74.04 150.75,79.38 159.51,79.38 165.86,85.73 v1(165.86,95.5) ; U1.W4 v2(170.12,105.25)
  L3SIG w0.102: v2(170.12,105.25) 170.53,104.83 170.53,99.41 169.8,98.68 168.4,98.68 165.86,96.14 v1(165.86,95.5)
UART2_TXD: length 67.9
  TOP w0.127: U1.AA4 v2(171.72,105.25) ; v1(166.88,95.89) 166.37,95.38 166.37,85.73 159.64,78.99 150.88,78.99 145.54,73.66 132.46,73.66 130.01,71.21 U41.11
  L3SIG w0.102: v2(171.72,105.25) 172.1,104.87 172.1,104.28 171.65,103.84 171.65,99.01 170.56,97.92 168.91,97.92 v1(166.88,95.89)
USB1_DM: length 22.5
  TOP w0.102: U38.4 113.67,27.04 v1(113.54,27.18)
  BOTTOM w0.102: J41.6 108.8,12.01 108.9,12.11 108.9,12.82 108.51,13.21 107.31,13.21 106.7,13.82 106.7,15.46 107.94,16.71 107.94,20.39 112.52,24.97 112.52,26.16 v1(113.54,27.18) 113.44,27.28 L1.3 113.28,28.14 R168.2
USB1_DP: length 23.4
  TOP w0.102: U38.6 113.79,26.04 v1(113.53,25.78)
  BOTTOM w0.102: J41.7 109.23,12.01 109.13,12.11 109.13,12.91 108.6,13.44 107.4,13.44 106.93,13.91 106.93,15.37 108.17,16.61 108.17,20.29 112.75,24.87 112.75,25.93 112.85,26.03 113.28,26.03 v1(113.53,25.78) 114.14,26.39 L1.2 114.29,28.14 R167.2
USB1_FLG_N: length 12.6
  TOP w0.127: U37.9 101.84,25.79 v1(102.1,25.53) ; v1(102.22,32.14) R157.2 R159.1 103.51,34.99 Q3.1
  L3SIG w0.102: v1(102.1,25.53) 102.86,26.29 102.86,28.58 102.22,29.22 v1(102.22,32.14)
USB1_PWREN: length 116.1
  TOP w0.127: U37.2 101.84,30.6 102.59,31.35 104.49,31.35 R162.2 105.41,31.38 106.42,32.38 106.42,34.8 v1(106.93,35.31) ; U1.F6 v2(158.92,106.85)
  L3SIG w0.102: v1(106.93,35.31) 107.18,35.05 108.97,35.05 116.08,42.16 120.52,42.16 123.57,45.21 123.57,72.64 132.33,81.41 143.26,81.41 151.13,89.28 151.13,93.98 152.63,95.48 155.3,95.48 158.24,98.43 158.24,102.43 158.5,102.69 158.5,103 158.27,103.23 157.99,103.23 157.74,103.48 157.74,104.62 157.94,104.83 158.27,104.83 158.5,105.05 158.5,106.43 v2(158.92,106.85)
USB1_VBUSCLMP: length 111.4
  TOP w0.127: 106.93,29.84 R166.2 ; U1.E4 v2(158.12,105.25)
  TOP w0.254: R164.1 106.93,29.84 106.88,29.79 D4.2 ; R166.2 106.94,34.3 107.94,35.31 v1(107.94,35.56)
  L3SIG w0.102: 156.96,104.87 157.47,104.87 157.86,105.25 v2(158.12,105.25)
  L3SIG w0.254: v1(107.94,35.56) 108.84,35.56 115.95,42.67 120.4,42.67 123.06,45.34 123.06,72.9 132.08,81.92 143,81.92 150.62,89.54 150.62,94.23 153.03,96.65 155.45,96.65 156.72,97.92 156.72,104.62 156.96,104.87
USB2_DM: length 20.4
  TOP w0.102: U38.3 116.33,27.04 v1(116.45,26.92)
  BOTTOM w0.102: J41.2 108.8,14.63 108.9,14.73 108.9,20.01 112.14,23.24 114.94,23.24 115.57,23.88 115.57,26.41 115.89,26.73 116.26,26.73 v1(116.45,26.92) 115.98,27.4 L2.3 115.82,28.14 R170.2
USB2_DP: length 21.2
  TOP w0.102: U38.1 116.4,26.04 v1(116.46,26.1)
  BOTTOM w0.102: J41.3 109.23,14.63 109.13,14.73 109.13,19.91 112.23,23.01 115.03,23.01 115.8,23.78 115.8,26.31 115.98,26.49 116.29,26.49 116.46,26.33 v1(116.46,26.1) 116.52,26.1 116.9,26.48 116.9,27.11 116.68,27.34 L2.2 116.83,28.14 R169.2
USB2_FLG_N: length 13
  TOP w0.127: Q4.1 99.17,34.63 R160.2 ; R160.2 99.18,33.54 R158.1 ; R160.2 99.17,32.65 v1(99.31,32.51) ; U37.7 100.84,25.92 v1(100.58,25.65)
  L3SIG w0.102: v1(99.31,32.51) 98.42,31.62 98.42,27.81 v1(100.58,25.65)
USB2_PWREN: length 127.6
  TOP w0.127: U1.J5 v2(161.32,106.05) ; v1(95.63,33.53) 96.63,32.52 R161.2 97.9,32.52 99.44,30.99 100.2,30.99 100.84,30.35 U37.4
  L3SIG w0.102: v1(95.63,33.53) 96.64,34.54 105.79,34.54 106.42,33.91 109.35,33.91 116.46,41.02 120.9,41.02 124.71,44.83 124.71,72.26 132.71,80.26 143.64,80.26 152.27,88.9 152.27,93.6 153.16,94.49 157.61,94.49 159,95.89 159,97.66 160.14,98.79 160.14,104.6 160.36,104.83 160.67,104.83 160.91,105.06 160.91,105.64 v2(161.32,106.05)
USB2_VBUSCLMP: length 129.4
  TOP w0.127: U1.J4 v2(161.32,105.25)
  TOP w0.254: v1(97.15,31.5) 97.15,30.23 95.37,28.45 95.37,25.78 95.63,25.53 96.13,25.53 R165.2 R163.1 97.15,23.69 D3.2
  L3SIG w0.102: 160.91,104.14 160.91,104.65 161.32,105.06 v2(161.32,105.25)
  L3SIG w0.254: 160.91,104.14 160.59,103.82 160.59,98.74 159.38,97.54 159.38,95.76 157.78,94.16 153.34,94.16 152.78,93.6 152.78,88.65 143.89,79.76 132.97,79.76 125.22,72.01 125.22,44.7 121.03,40.51 116.59,40.51 109.47,33.4 106.17,33.4 105.54,34.04 99.69,34.04 v1(97.15,31.5)
USB_REFCLK: length 86.9
  TOP w0.127: R175.2 R176.2 v1(91.06,88.52)
  BOTTOM w0.127: R880.2 150.24,114.42 R873.1 146.68,116.97 114.42,116.97 112.9,115.44 95.67,115.44 92.58,112.35 92.58,90.04 v1(91.06,88.52)
VCORE: length 161.6
  TOP w0.305: U1.R18 v2(166.92,117.25) ; U1.R16 v2(166.92,115.65) ; U1.L16 v2(162.92,115.65) ; U1.Y11 v2(170.92,110.85) ; U1.T9 v2(167.72,109.25) ; U1.Y9 v2(170.92,109.25) ; U1.R12 v2(166.92,111.65) ; U1.N18 v2(164.52,117.25) ; U1.V13 v2(169.32,112.45) ; U1.M19 v2(163.72,118.05) ; U1.K17 v2(162.12,116.45) ; U1.V15 v2(169.32,114.85) ; U1.L14 v2(162.92,113.25) ; U1.L12 v2(162.92,111.65) ; U1.K15 v2(162.12,114.85) ; U1.R14 v2(166.92,113.25) ; U1.U16 v2(168.52,115.65) ; U1.R20 v2(166.92,118.85) ; U1.N14 v2(164.52,113.25) ; U1.K19 v2(162.12,118.05) ; U1.U18 v2(168.52,117.25) ; U1.V17 v2(169.32,116.45) ; U1.N12 v2(164.52,111.65) ; U1.N20 v2(164.52,118.85) ; U1.V9 v2(169.32,109.25) ; U1.Y8 v2(170.92,108.45) ; U1.P11 v2(165.32,110.85) ; U1.T13 v2(167.72,112.45) ; U1.P17 v2(165.32,116.45) ; U1.W14 v2(170.12,113.25) ; U1.P13 v2(165.32,112.45) ; U1.L18 v2(162.92,117.25) ; U1.T15 v2(167.72,114.85) ; U1.T19 v2(167.72,118.05) ; U1.U14 v2(168.52,113.25) ; U1.M17 v2(163.72,116.45) ; U1.N16 v2(164.52,115.65) ; U1.T17 v2(167.72,116.45) ; U1.U20 v2(168.52,118.85) ; U1.L20 v2(162.92,118.85) ; U1.P19 v2(165.32,118.05) ; U1.M15 v2(163.72,114.85) ; U1.V19 v2(169.32,118.05) ; U1.M9 v2(163.72,109.25) ; U1.P9 v2(165.32,109.25) ; U1.P15 v2(165.32,114.85) ; U1.M13 v2(163.72,112.45)
  TOP w0.508: R909.2 132.47,114.93 v3(132.72,114.68)
  L3SIG w0.508: J11.2 56.39,150.11 57.78,150.11 58.93,148.97 68.71,148.97 71.25,146.43 112.4,146.43 123.83,135 133.22,135 139.45,128.78 143.26,128.78 153.54,118.49 153.54,116.08 154.3,115.32 155.7,115.32
  BOTTOM w0.457: C913.1 165.61,117.75 v2(165.32,118.05) ; C912.1 165.52,116.65 v2(165.32,116.45) ; C914.1 165.32,112.44 v2(165.32,112.45) ; C915.1 165.62,114.55 v2(165.32,114.85)
  BOTTOM w0.508: v1(150.75,100.84) 150.75,99.95 153.67,97.03 159,97.03 159.55,96.48 FB11.2
  vias: v3(132.72,113.41) v3(132.72,112.14) v3(132.72,109.6) v3(132.72,108.33) v3(132.72,107.06) v3(132.72,105.79) v3(132.72,104.52) v3(133.6,114.68) v3(133.6,113.41) v3(133.6,112.14) v3(133.6,110.87) v3(133.6,109.6) v3(133.6,108.33) v3(133.6,107.06) v3(133.6,105.79) v3(133.6,104.52) v3(134.49,114.68) v3(134.49,113.41) v3(134.49,112.14)
VCORE_EN: length 69.6
  TOP w0.127: U65.R14 v1(70.52,99.42) ; U103.16 103.51,106.93 103.12,107.32 102.62,107.32 102.23,107.7 R906.2 C1212.2 98.31,107.96 96.9,106.55 v1(96.9,83.31)
  L6SIG w0.102: v1(70.52,99.42) 71.08,98.86 71.08,97.57 71.63,97.03 75.57,97.03 77.34,95.25 77.34,89.03 79.25,87.12 83.44,87.12 84.84,85.73 87.25,85.73 89.66,83.31 v1(96.9,83.31)
VCORE_SLP: length 7.8
  TOP w0.305: U1.R10 v2(166.92,110.05) ; U1.M11 v2(163.72,110.85) U1.L10 ; U1.V11 v2(169.32,110.85) ; U1.T11 v2(167.72,110.85) ; U1.N10 v2(164.52,110.05) ; U1.W10 v2(170.12,110.05) ; U1.K11 v2(162.12,110.85) ; U1.U10 v2(168.52,110.05) ; U1.W12 v2(170.12,111.65) ; U1.U12 v2(168.52,111.65) ; U1.K13 v2(162.12,112.45)
  BOTTOM w0.457: v2(166.92,110.05) 166.62,110.34 C238.1
  vias: v1(137.67,100.71) v1(137.67,99.19) v1(137.67,97.66) v1(137.67,96.14) v1(138.43,100.71) v1(138.43,99.19) v1(138.43,97.66) v1(138.43,96.14) v3(126.11,93.73) v3(126.11,92.58) v3(126.11,91.44) v3(127.38,93.73) v3(127.38,92.58) v3(127.38,91.44) v3(128.65,93.73) v3(128.65,92.58) v3(128.65,91.44) v3(129.92,93.73) v3(129.92,92.58) v3(129.92,91.44)
VTT: length 115.8
  TOP w0.305: U81.3 227.33,150.99 C885.1
  TOP w0.508: J1.120 227.45,156.18 ; J1.120 226.39,155.12 ; J1.120 226.39,156.18 ; J1.120 227.45,155.12 ; J1.240 227.45,159.98 ; J1.240 226.39,158.92 ; J1.240 226.39,159.98 ; J1.240 227.45,158.92 ; R694.2 v1(223.53,148.85)
  BOTTOM w0.508: 153.03,164.47 153.03,164.97 153.42,165.35 226.69,165.35 228.98,163.07 228.98,155.45 227.84,154.3 227.84,153.16 v1(223.53,148.85) ; J1.240 227.45,159.98 ; J1.240 227.45,158.92 ; J1.240 226.39,158.92 ; J1.240 226.39,159.98 ; J1.48 151.45,156.18 ; J1.48 150.39,156.18 ; J1.48 150.39,155.12 ; J1.48 151.45,155.12 ; 226.39,155.12 J1.120 ; J1.120 227.45,156.18 ; J1.120 227.45,155.12 ; J1.120 226.39,156.18 ; J1.49 156.45,158.08 ; J1.49 155.39,157.02 ; J1.49 155.39,158.08 ; J1.49 156.45,157.02
  vias: v1(148.72,163.96) v1(149.48,163.96) v1(150.24,163.96) v1(151,163.96)
XFI_RX_C_N: length 26.8
  TOP w0.127: C60.2 198.4,104.49 191.61,111.28 arc(189,113.03) 185.92,113.64 182.56,113.64 180.32,114.04 arc(180.21,114.06) 180.12,114.12 178.28,115.41 arc(178.13,115.49) 177.96,115.54 177.57,115.61 arc(177.42,115.63) 177.27,115.63 176.71,115.63 arc(176.52,115.59) 176.36,115.49 U1.AG16
XFI_RX_C_P: length 27.1
  TOP w0.127: U1.AH16 176.95,115.28 177.27,115.28 arc(177.39,115.27) 177.51,115.26 177.9,115.19 arc(177.99,115.16) 178.07,115.11 178.21,115.02 arc(178.27,114.93) 178.24,114.84 178.24,114.82 arc(178.21,114.72) 178.27,114.62 178.45,114.5 arc(178.56,114.47) 178.65,114.53 178.65,114.53 arc(178.75,114.59) 178.85,114.57 179.03,114.44 arc(179.09,114.35) 179.07,114.24 arc(179.05,114.13) 179.1,114.04 179.29,113.91 arc(179.39,113.89) 179.49,113.95 arc(179.58,114.01) 179.69,113.99 179.92,113.82 179.92,113.82 arc(180.08,113.74) 180.25,113.69 180.31,113.68 arc(180.39,113.62) 180.41,113.53 180.4,113.48 arc(180.43,113.34) 180.55,113.27 180.69,113.24 arc(180.83,113.27) 180.9,113.39 arc(180.98,113.5) 181.11,113.53 181.25,113.51 arc(181.37,113.43) 181.4,113.3 arc(181.43,113.16) 181.55,113.09 181.69,113.06 arc(181.83,113.09) 181.9,113.21 arc(181.98,113.33) 182.11,113.36 182.53,113.28 185.92,113.28 arc(188.86,112.7) 191.36,111.03 198.15,104.24 C59.2
XFI_RX_N: length 54.7
  TOP w0.102: U101.V6 195.02,56.14 arc(195,56.07) 194.97,56.02 194.95,56 arc(194.9,55.96) 194.84,55.95 194.81,55.95 arc(194.76,55.96) 194.71,56 194.65,56.05 194.65,57.19 194.73,57.26 194.73,57.28
  TOP w0.127: 194.73,57.28 194.73,60.16 arc(195.39,63.51) 197.29,66.35 203.83,72.9 arc(205.98,76.11) 206.73,79.89 206.73,85.5 arc(205.11,94.48) 200.47,102.33 199.55,103.24 C60.1
XFI_RX_P: length 54.3
  TOP w0.102: U101.U6 194.95,55.51 arc(194.91,55.51) 194.88,55.54 194.45,55.97 194.45,57.13 arc(194.44,57.17) 194.41,57.21 194.37,57.25 194.37,57.28
  TOP w0.127: C59.1 199.21,103.09 200.21,102.09 arc(204.78,94.35) 206.38,85.5 206.38,79.89 arc(205.65,76.24) 203.58,73.15 197.04,66.61 arc(195.06,63.65) 194.37,60.16 194.37,57.28
XFI_TX_N: length 84.2
  TOP w0.127: v1(196.22,110.17) 196.22,110.32 arc(196.25,110.41) 196.34,110.45 arc(198.49,110.02) 200.31,108.81 203.21,105.9 arc(205.66,102.92) 207.48,99.52 208.15,97.91 arc(209.2,94.45) 209.55,90.86 209.55,81.84 arc(208.35,75.8) 204.93,70.69 197.93,63.69 arc(197.47,63) 197.31,62.18 197.31,61.63 arc(197.27,61.43) 197.15,61.25 C1117.1 ; U1.AE16 v2(174.92,115.65)
  BOTTOM w0.127: v1(196.22,110.17) 196.22,110.3 arc(196.17,110.41) 196.06,110.45 194.48,110.45 arc(193.61,110.49) 192.74,110.6 187.91,111.46 arc(185.09,112.28) 182.51,113.69 181.04,114.72 arc(180.77,114.87) 180.48,114.95 180.27,114.99 arc(180.18,114.97) 180.12,114.88 arc(180.07,114.8) 179.97,114.78 179.74,114.82 arc(179.65,114.87) 179.62,114.96 179.62,114.98 arc(179.59,115.07) 179.5,115.12 179.27,115.16 arc(179.17,115.14) 179.12,115.06 arc(179.07,114.97) 178.97,114.95 178.74,114.99 arc(178.65,115.04) 178.62,115.13 178.62,115.16 arc(178.59,115.25) 178.5,115.3 178.27,115.34 arc(178.17,115.32) 178.12,115.24 arc(178.07,115.15) 177.97,115.13 177.74,115.17 arc(177.65,115.22) 177.62,115.31 177.62,115.34 arc(177.59,115.43) 177.5,115.48 177.27,115.52 arc(177.17,115.5) 177.12,115.41 arc(177.07,115.33) 176.97,115.31 176.74,115.35 arc(176.65,115.4) 176.62,115.49 176.62,115.5 arc(176.6,115.6) 176.51,115.65 176.36,115.68 arc(176.26,115.69) 176.16,115.7 176.13,115.7 arc(176.03,115.68) 175.95,115.62 175.81,115.48 arc(175.76,115.45) 175.72,115.44 175.57,115.44 arc(175.52,115.45) 175.48,115.48 175.35,115.6 arc(175.25,115.67) 175.13,115.7 174.97,115.7 v2(174.92,115.65)
XFI_TX_P: length 84.4
  TOP w0.127: U1.AD16 v2(174.12,115.65) ; C1118.1 197.82,61.25 arc(197.7,61.43) 197.66,61.63 197.66,62.18 arc(197.8,62.86) 198.18,63.44 205.18,70.43 arc(208.68,75.67) 209.91,81.84 209.91,90.86 arc(209.54,94.52) 208.48,98.05 207.81,99.66 arc(205.96,103.12) 203.47,106.15 200.56,109.06 arc(198.63,110.35) 196.34,110.81 arc(196.25,110.84) 196.22,110.93 v1(196.22,111.09)
  BOTTOM w0.127: v1(196.22,111.09) 196.22,110.93 arc(196.18,110.84) 196.09,110.81 194.48,110.81 arc(193.64,110.84) 192.8,110.95 187.97,111.81 arc(185.22,112.61) 182.71,113.98 181.25,115.01 arc(180.91,115.2) 180.54,115.3 180.34,115.34 180.33,115.34 176.43,116.03 arc(176.29,116.05) 176.16,116.05 174.73,116.05 arc(174.54,116.01) 174.37,115.9 v2(174.12,115.65)
XGT1_CM_N: length 29.3
  TOP w0.102: J50.15 186.86,23.81 187.2,23.81 187.45,23.56 187.45,22.76 186.92,22.23 185.8,22.23 185.06,22.96 185.06,28.6 189.64,33.17 189.64,36.08 191.66,38.1 191.66,39.01 191.62,39.05 191.62,42.74 191.78,42.9 192.87,42.9 193.02,42.76 U101.D8
XGT1_CM_P: length 29.4
  TOP w0.102: U101.E8 193.02,43.28 192.84,43.11 191.7,43.11 191.42,42.83 191.42,39.05 191.38,39.01 191.38,38.22 189.36,36.2 189.36,33.29 184.78,28.72 184.78,22.85 185.69,21.95 187.04,21.95 J50.14
XGT1_INT_N: length 168.7
  TOP w0.127: U65.M2 58.01,102.93 v1(57.51,102.42)
  L6SIG w0.102: v1(57.51,102.42) 56.7,102.42 55.5,101.22 55.5,97.13 59.63,93 59.63,91.82 66.42,85.03 66.42,83.06 67.56,81.92 67.56,77.47 70.48,74.55 74.68,74.55 75.95,73.28 92.46,73.28 93.22,72.52 134.87,72.52 136.02,71.37 176.91,71.37 180.21,68.08 v1(180.21,50.91)
  BOTTOM w0.127: R885.2 R884.1 180.51,49.41 180.21,49.71 v1(180.21,50.91)
XGT1_LED_GRN: length 45.5
  TOP w0.127: U101.K1 v1(200.52,48.01)
  L3SIG w0.102: v1(200.52,48.01) 200.52,47.21 201.42,46.3 201.42,26.99 200.61,26.18 200.61,23.97 200.12,23.49 200.12,16.78 197.82,14.48 194.57,14.48 v1(193.29,13.21)
  BOTTOM w0.127: R902.2 v1(193.29,13.21)
XGT1_LED_YEL: length 48
  TOP w0.127: U101.L1 200.02,49.34 v1(199.72,49.05)
  L3SIG w0.102: v1(190.75,11.56) 194.08,14.88 197.62,14.88 199.72,16.98 199.72,25.79 201.02,27.09 201.02,46.2 200.02,47.21 200.02,48.75 v1(199.72,49.05)
  BOTTOM w0.127: v1(190.75,11.56) 189.74,10.54 R903.2
XGT1_MDI0_N: length 22.8
  TOP w0.102: U101.A2 199.02,39.95 199.12,40.05 199.26,40.05 199.37,39.95 199.37,34.67 196.98,32.27 196.98,29.73 194.44,27.19 194.44,21.08 194.18,20.83 J50.9
XGT1_MDI0_P: length 22.8
  TOP w0.102: J50.8 194.95,20.83 194.72,21.06 194.72,27.08 197.26,29.62 197.26,32.16 199.65,34.55 199.65,40.06 199.21,40.51 U101.B2
XGT1_MDI1_N: length 26.1
  TOP w0.102: U101.A4 197.02,39.97 197.11,40.07 197.28,40.07 197.38,39.97 197.38,35.85 195.05,33.52 195.05,30.72 192.72,28.4 192.72,22.43 192.09,21.79 192.09,20.26 193.42,18.93 193.42,18.54 193.17,18.29 J50.3
XGT1_MDI1_P: length 26.1
  TOP w0.102: J50.2 193.93,18.29 193.7,18.52 193.7,19.04 192.37,20.37 192.37,21.68 193,22.31 193,28.28 195.33,30.61 195.33,33.4 197.66,35.74 197.66,40.08 197.4,40.35 197.24,40.51 U101.B4
XGT1_MDI2_N: length 25.8
  TOP w0.102: J50.5 189.1,18.29 189.34,18.52 189.34,19.17 190.88,20.72 190.88,29.35 193.21,31.68 193.21,34.6 195.38,36.77 195.38,39.95 195.26,40.06 195.12,40.06 195.02,39.96 U101.A6
XGT1_MDI2_P: length 25.8
  TOP w0.102: U101.B6 195.21,40.51 195.66,40.06 195.66,36.65 193.48,34.48 193.48,31.56 191.16,29.24 191.16,20.6 189.62,19.05 189.62,18.54 189.87,18.29 J50.4
XGT1_MDI3_N: length 23.3
  TOP w0.102: U101.A8 193.02,39.96 193.12,40.06 193.26,40.06 193.37,39.95 193.37,37.56 191.3,35.49 191.3,32.63 188.98,30.3 188.98,24.64 189.55,24.07 189.55,22.87 188.32,21.64 188.32,21.06 188.08,20.83 J50.11
XGT1_MDI3_P: length 23.4
  TOP w0.102: J50.10 188.85,20.83 188.6,21.08 188.6,21.53 189.83,22.76 189.83,24.18 189.26,24.75 189.26,30.19 191.58,32.51 191.58,35.37 193.65,37.44 193.65,40.07 193.21,40.51 U101.B8
XGT1_RST_N: length 188.4
  TOP w0.127: U65.P15 71.52,100.42 71.52,97.68 70.99,97.16 70.36,97.16 65.41,92.2 v1(60.13,92.2)
  L6SIG w0.102: v1(60.13,92.2) 60.13,91.69 66.68,85.15 66.68,83.19 67.82,82.04 67.82,77.6 70.61,74.8 74.8,74.8 76.07,73.53 92.58,73.53 93.34,72.77 135,72.77 136.14,71.63 177.1,71.63 180.59,68.14 180.59,52.96 181.86,51.69 181.86,47.88 182.25,47.5 196.01,47.5 v1(196.52,48.01)
  BOTTOM w0.127: R896.1 v1(196.52,48.01)
XGT1_SPI_CS_N: length 9.2
  TOP w0.127: U101.G2 199.56,44.96 U102.1 206.25,44.96 206.76,45.47 R943.1
XGT1_SPI_SCLK: length 15.5
  TOP w0.127: U102.6 210.31,42.42 209.17,43.56 209.17,46.61 208.41,47.37 205.99,47.37 204.13,45.51 U101.G1
XGT1_SPI_SDI: length 13.3
  TOP w0.127: U101.F2 199.02,44.51 199.52,44 202.38,44 203.33,43.05 207.64,43.05 209.55,41.15 U102.5
XGT1_SPI_SDO: length 6
  TOP w0.127: U101.F1 202.64,44.51 203.45,43.69 U102.2
XGT1_TCK: length 23.4
  TOP w0.127: U101.K14 v1(186.52,49.01)
  L3SIG w0.102: v1(186.52,49.01) 186.01,49.51 186.01,50.21 185.71,50.51 185.31,50.51 185.01,50.81 185.01,51.12 184.57,51.56 183.13,51.56 178.56,56.13 178.56,56.9 177.8,57.66 172.85,57.66 172.21,58.29 172.21,60.2 J51.3
XGT1_TDI: length 24.8
  TOP w0.127: U101.L14 v1(186.52,50.01)
  L3SIG w0.102: J51.1 175.01,64.77 175.01,60.45 176.15,59.31 179.58,59.31 180.97,57.91 180.97,56.85 184.41,53.41 184.41,52.5 185.4,51.51 185.71,51.51 186.01,51.21 186.01,50.81 186.52,50.3 v1(186.52,50.01)
XGT1_TDO: length 15.5
  TOP w0.127: U101.L15 v1(185.52,50.01)
  L3SIG w0.102: 173.35,56.26 174.5,55.12 178.31,55.12 182.92,50.51 184.71,50.51 185.21,50.01 v1(185.52,50.01)
XGT1_TMS: length 23.1
  TOP w0.127: U101.M16 v1(184.52,51.01)
  L3SIG w0.102: v1(184.52,51.01) 183.06,51.01 178.08,55.98 178.08,56.61 177.39,57.3 172.69,57.3 171.83,58.17 171.83,62.36 J51.2
XGT1_TRST_N: length 17
  TOP w0.127: U101.M15 v1(185.52,51.01)
  L3SIG w0.102: v1(185.52,51.01) 184.11,52.41 184.11,53.13 180.47,56.77 180.47,57.66 179.32,58.8 173.35,58.8
XGT2_CM_N: length 29.3
  TOP w0.102: U108.D8 243.82,42.76 243.67,42.9 242.58,42.9 242.42,42.74 242.42,39.05 242.46,39.01 242.46,38.1 240.44,36.08 240.44,33.17 235.86,28.6 235.86,22.96 236.6,22.23 237.72,22.23 238.25,22.76 238.25,23.56 238,23.81 237.66,23.81 J56.15
XGT2_CM_P: length 29.4
  TOP w0.102: J56.14 237.84,21.95 236.49,21.95 235.58,22.85 235.58,28.72 240.16,33.29 240.16,36.2 242.18,38.22 242.18,39.01 242.22,39.05 242.22,42.83 242.5,43.11 243.64,43.11 243.82,43.28 U108.E8
XGT2_INT_N: length 222.6
  TOP w0.127: v1(56.51,101.42) 57.01,101.93 U65.N1
  L6SIG w0.102: v1(232.47,47.82) 232.79,47.5 233.55,47.5 233.81,47.75 233.81,57.09 233.55,57.34 233.55,65.02 229.62,68.96 181.61,68.96 177.55,73.03 156.21,73.03 155.51,72.33 136.21,72.33 135.25,73.28 93.66,73.28 92.9,74.04 76.33,74.04 75.06,75.31 71.63,75.31 69.09,77.85 69.09,81.66 68.71,82.04 68.2,82.04 67.12,83.12 67.12,85.09 60.64,91.57 60.64,92.46 55.82,97.28 55.82,100.73 v1(56.51,101.42)
  BOTTOM w0.127: R959.2 R957.1 231.31,48.54 232.03,47.82 v1(232.47,47.82)
XGT2_LED_GRN: length 45.5
  TOP w0.127: U108.K1 v1(251.32,48.01)
  L3SIG w0.102: v1(251.32,48.01) 251.32,47.21 252.22,46.3 252.22,26.99 251.41,26.18 251.41,23.97 250.92,23.49 250.92,16.78 248.62,14.48 245.37,14.48 v1(244.09,13.21)
  BOTTOM w0.127: R977.2 v1(244.09,13.21)
XGT2_LED_YEL: length 48
  TOP w0.127: U108.L1 250.82,49.34 v1(250.52,49.05)
  L3SIG w0.102: v1(241.55,11.56) 244.88,14.88 248.42,14.88 250.52,16.98 250.52,25.79 251.82,27.09 251.82,46.2 250.82,47.21 250.82,48.75 v1(250.52,49.05)
  BOTTOM w0.127: R978.2 240.54,10.54 v1(241.55,11.56)
XGT2_MDI0_N: length 22.8
  TOP w0.102: U108.A2 249.82,39.95 249.92,40.05 250.06,40.05 250.17,39.95 250.17,34.67 247.78,32.27 247.78,29.73 245.24,27.19 245.24,21.08 244.98,20.83 J56.9
XGT2_MDI0_P: length 22.8
  TOP w0.102: J56.8 245.75,20.83 245.52,21.06 245.52,27.08 248.06,29.62 248.06,32.16 250.45,34.55 250.45,40.06 250.01,40.51 U108.B2
XGT2_MDI1_N: length 26.1
  TOP w0.102: U108.A4 247.82,39.97 247.91,40.07 248.08,40.07 248.18,39.97 248.18,35.85 245.85,33.52 245.85,30.72 243.52,28.4 243.52,22.43 242.89,21.79 242.89,20.26 244.22,18.93 244.22,18.54 243.97,18.29 J56.3
XGT2_MDI1_P: length 26.1
  TOP w0.102: U108.B4 248.04,40.51 248.2,40.35 248.46,40.08 248.46,35.74 246.13,33.4 246.13,30.61 243.8,28.28 243.8,22.31 243.17,21.68 243.17,20.37 244.5,19.04 244.5,18.52 244.73,18.29 J56.2
XGT2_MDI2_N: length 25.8
  TOP w0.102: U108.A6 245.82,39.96 245.92,40.06 246.06,40.06 246.18,39.95 246.18,36.77 244.01,34.6 244.01,31.68 241.68,29.35 241.68,20.72 240.14,19.17 240.14,18.52 239.9,18.29 J56.5
XGT2_MDI2_P: length 25.8
  TOP w0.102: J56.4 240.67,18.29 240.42,18.54 240.42,19.05 241.96,20.6 241.96,29.24 244.28,31.56 244.28,34.48 246.46,36.65 246.46,40.06 246.01,40.51 U108.B6
XGT2_MDI3_N: length 23.3
  TOP w0.102: U108.A8 243.82,39.96 243.92,40.06 244.06,40.06 244.17,39.95 244.17,37.56 242.1,35.49 242.1,32.63 239.78,30.3 239.78,24.64 240.35,24.07 240.35,22.87 239.12,21.64 239.12,21.06 238.88,20.83 J56.11
XGT2_MDI3_P: length 23.4
  TOP w0.102: J56.10 239.65,20.83 239.4,21.08 239.4,21.53 240.63,22.76 240.63,24.18 240.06,24.75 240.06,30.19 242.38,32.51 242.38,35.37 244.45,37.44 244.45,40.07 244.01,40.51 U108.B8
XGT2_RST_N: length 234.6
  TOP w0.127: U65.N14 70.02,101.92 v1(70.52,101.42)
  L6SIG w0.102: v1(247.32,48.01) 235.33,48.01 234.76,48.58 234.76,56.71 233.93,57.53 233.93,65.15 229.87,69.22 181.72,69.22 177.65,73.28 156.1,73.28 155.41,72.58 136.31,72.58 135.36,73.53 93.77,73.53 93.01,74.3 76.43,74.3 75.16,75.57 71.73,75.57 69.34,77.96 69.34,82.55 67.37,84.52 67.37,85.47 v1(61.15,91.69)
  BOTTOM w0.127: v1(70.52,101.42) 70.04,100.94 70.04,97.28 64.83,92.08 61.53,92.08 v1(61.15,91.69) ; R969.1 v1(247.32,48.01)
XGT2_SPI_CS_N: length 9.1
  TOP w0.127: R976.1 257.44,45.47 256.92,44.96 U109.1 250.36,44.96 U108.G2
XGT2_SPI_SCLK: length 15.5
  TOP w0.127: U108.G1 254.93,45.51 256.79,47.37 259.21,47.37 259.97,46.61 259.97,43.56 261.11,42.42 U109.6
XGT2_SPI_SDI: length 13.3
  TOP w0.127: U109.5 260.35,41.15 258.44,43.05 254.13,43.05 253.18,44 250.32,44 249.82,44.51 U108.F2
XGT2_SPI_SDO: length 6
  TOP w0.127: U109.2 254.25,43.69 253.44,44.51 U108.F1
XGT2_TCK: length 23.4
  TOP w0.127: U108.K14 v1(237.32,49.01)
  L3SIG w0.102: v1(237.32,49.01) 236.81,49.51 236.81,50.21 236.51,50.51 236.11,50.51 235.81,50.81 235.81,51.12 235.37,51.56 233.93,51.56 229.36,56.13 229.36,56.9 228.6,57.66 223.65,57.66 223.01,58.29 223.01,60.2 J55.3
XGT2_TDI: length 24.8
  TOP w0.127: U108.L14 v1(237.32,50.01)
  L3SIG w0.102: J55.1 225.81,64.77 225.81,60.45 226.95,59.31 230.38,59.31 231.77,57.91 231.77,56.85 235.21,53.41 235.21,52.5 236.2,51.51 236.51,51.51 236.81,51.21 236.81,50.81 237.32,50.3 v1(237.32,50.01)
XGT2_TDO: length 15.5
  TOP w0.127: U108.L15 v1(236.32,50.01)
  L3SIG w0.102: v1(236.32,50.01) 236.01,50.01 235.51,50.51 233.72,50.51 229.11,55.12 225.3,55.12 224.16,56.26
XGT2_TMS: length 23.1
  TOP w0.127: U108.M16 v1(235.32,51.01)
  L3SIG w0.102: J55.2 222.63,62.36 222.63,58.17 223.49,57.3 228.19,57.3 228.88,56.61 228.88,55.98 233.86,51.01 v1(235.32,51.01)
XGT2_TRST_N: length 17
  TOP w0.127: U108.M15 v1(236.32,51.01)
  L3SIG w0.102: 224.16,58.8 230.12,58.8 231.27,57.66 231.27,56.77 234.91,53.13 234.91,52.41 v1(236.32,51.01)
XVDD: length 8.4
  TOP w0.305: U1.AC18 v2(173.32,117.25) ; U1.AC9 v2(173.32,109.25) ; U1.AC15 v2(173.32,114.85) ; U1.AC12 v2(173.32,111.65) ; U1.AC21 v2(173.32,119.65)
  BOTTOM w0.127: 172.92,120.04 v2(173.32,119.65) 172.92,119.25 172.28,119.25 171.96,119.57 171.96,119.7 172.3,120.04 172.92,120.04
  BOTTOM w0.381: C254.1 170.86,119.76 171.9,119.76 171.96,119.7 ; R140.1 173.32,114.21 v2(173.32,114.85)
  vias: v1(194.94,129.67) v1(194.94,128.65) v1(194.94,127.64) v1(195.71,129.67) v1(195.71,127.64)
N16747459: length 1.5
  TOP w0.127: v2(168.15,125.6) 168.12,125.57 U1.U28
  BOTTOM w0.127: R1.2 v2(168.15,125.6)
N16747463: length 1.5
  TOP w0.127: v2(165.48,125.48) 165.72,125.24 U1.P28
  BOTTOM w0.127: v2(165.48,125.48) 165.76,125.19 R3.2
N16800565: length 2.1
  TOP w0.127: v1(103.76,123.44) 103.72,123.4 U4.53
  BOTTOM w0.127: R42.1 103.77,123.45 v1(103.76,123.44)
N16800570: length 2.6
  TOP w0.127: v1(120.02,129.41) 120.12,129.41 120.14,129.4 U4.16
  BOTTOM w0.127: R41.1 v1(120.02,129.41)
N16821816: length 9
  TOP w0.127: U1.E14 v2(158.12,113.25)
  BOTTOM w0.127: v2(158.12,113.25) 158.12,113.28 157.73,113.67 154.43,113.67 154.18,113.92 150.76,113.92 R5.1
N16864329: length 6.9
  TOP w0.127: R58.2 255.66,132.46 U13.8 261.75,132.46 262,132.72 U15.2
N16864338: length 7.4
  TOP w0.127: U15.5 265.72,140.68 266.32,140.08 U13.15 268.48,140.08 268.73,139.83 268.73,138.94 269.12,138.55 R866.2 R55.1
N16864354: length 6.9
  TOP w0.127: U15.6 263.27,141.1 263.53,141.35 269.23,141.35 R865.2
N16864378: length 24.4
  TOP w0.127: 257.84,141.35 261.75,141.35 262,141.1 U15.7 261.4,140.08 259.97,140.08 259.59,139.7 259.59,134.11 259.97,133.73 262.76,133.73 263.27,133.22 U15.3 263.27,132.72 263.53,132.46 U13.9 268.98,132.46 R57.1
N16869850: length 4.8
  TOP w0.127: R211.2 165.11,50.04 163.96,50.04 163.58,50.41 C300.2 163.15,50.11 U46.19
N16869910: length 3.1
  TOP w0.127: U46.14 162.08,48.11 162.81,47.38 162.81,46.86 163.19,46.48 R209.2
N16869938: length 2.9
  TOP w0.127: U46.16 162.06,48.91 162.11,48.96 162.12,48.96 162.12,48.96 162.49,48.96 162.49,48.96 162.5,48.96 162.81,48.64 162.81,48.26 163.58,47.5 R213.2
N16869959: length 2.4
  TOP w0.127: U46.17 162.78,49.31 163.58,48.51 R214.2
N16869976: length 2.2
  TOP w0.127: R215.2 163.4,49.71 U46.18
N16869978: length 3.6
  TOP w0.127: U46.13 161.97,47.71 162.43,47.24 162.43,46.23 163.19,45.47 R216.2
N16870294: length 2.2
  TOP w0.508: T1.15 v1(156.52,30.95)
  BOTTOM w0.508: v1(156.52,30.95) 156.5,30.93 R207.1
N16870296: length 15.4
  BOTTOM w0.508: 157.95,29.12 158.37,28.7 160.51,28.7 161,29.19 ; 157.95,29.12 157.53,28.7 155.32,28.7 154.9,29.12 R207.2 154.77,29.72 153.52,29.72 C302.1 ; 157.95,29.12 R208.2 ; R212.2 164.05,29.17 163.56,28.69 161.51,28.69 161,29.19 ; 161,29.19 R210.2
N16870306: length 2.2
  TOP w0.508: T1.18 v1(159.52,30.95)
  BOTTOM w0.508: R208.1 159.55,30.92 v1(159.52,30.95)
N16870310: length 2.2
  TOP w0.508: T1.21 v1(162.52,30.95)
  BOTTOM w0.508: v1(162.52,30.95) 162.6,30.87 R210.1
N16870330: length 2.2
  TOP w0.508: T1.24 v1(165.52,30.95)
  BOTTOM w0.508: R212.1 165.65,30.82 v1(165.52,30.95)
N16870380: length 16.7
  TOP w0.508: T1.1 v1(165.52,40.31) ; T1.4 v1(162.52,40.31) ; T1.7 v1(159.52,40.31) ; T1.10 v1(156.52,40.31)
  BOTTOM w0.508: C298.2 159.51,40.31 v1(159.52,40.31) ; C299.2 162.56,40.28 v1(162.52,40.31) ; v1(162.52,40.31) v1(165.52,40.31) 165.48,40.28 C301.2 ; v1(162.52,40.31) v1(159.52,40.31) ; v1(159.52,40.31) v1(156.52,40.31) 156.46,40.26 C296.2
N16870828: length 20
  TOP w0.508: v1(167.13,41.53) 167.12,41.54 C297.1 167.12,43.48 FB26.2
  L6SIG w0.508: J14.A11 167.12,28.21 167.12,41.52 v1(167.13,41.53)
N16870844: length 34.3
  TOP w0.127: v1(150.88,40.13) 151.25,40.51 C307.1 FB63.2
  L6SIG w0.102: v1(150.88,40.13) 151.38,39.62 151.38,24.51 152.15,23.75 155.96,23.75 156.97,24.77 162.18,24.77 163.19,23.75 165.2,23.75 J14.A12
N16870888: length 17.4
  TOP w0.127: R219.2 152.15,56.65 v1(152.53,57.02) ; FB63.1 152.02,43.05 152.02,43.94 v1(152.15,44.07)
  L6SIG w0.102: v1(152.15,44.07) 153.16,45.09 153.16,49.4 153.92,50.16 153.92,56.13 153.03,57.02 v1(152.53,57.02)
N16870890: length 18.4
  TOP w0.127: v1(153.29,40.39) 153.17,40.51 C308.1 FB62.2
  L6SIG w0.102: J14.A9 152.66,27.3 151.64,28.32 151.64,37.34 152.4,38.1 152.4,39.5 v1(153.29,40.39)
N16870898: length 18.2
  TOP w0.127: R218.2 v1(155.19,57.9) ; FB62.1 v1(152.53,43.31)
  L6SIG w0.102: v1(152.53,43.31) 152.53,43.81 153.48,44.77 153.48,48.22 154.15,48.89 154.15,56.87 v1(155.19,57.9) 155.19,57.91
N16871038: length 5
  TOP w0.127: R221.1 165.23,51.56 164.97,51.82 163.58,51.82 162.81,51.05 162.81,50.67 162.61,50.47 162.11,50.47 162.06,50.51 U46.20
N16873302: length 8.4
  TOP w0.127: U46.42 155.01,50.11 154.87,49.97 154.5,49.97 153.68,50.8 150.62,50.8 149.65,51.78 Y1.1 149.65,53.37 C304.1
N16873318: length 4.5
  TOP w0.127: U46.43 154.11,49.71 153.67,50.16 C305.1 151.8,50.16 Y1.3
N16873350: length 3.1
  TOP w0.127: U46.29 159.1,53.48 159.05,53.52 159.05,54.02 160.02,54.99 R220.2
N16874872: length 4
  TOP w0.127: U46.46 154.39,48.51 154.38,48.5 153.15,48.5 152.92,48.27 C303.1 R217.1
N16877780: length 2.5
  TOP w0.127: U46.33 157.5,53.32 157.23,53.59 157.23,54.62 R222.1
N16879465: length 0.8
  BOTTOM w0.508: R224.1 154.56,46.61 v1(154.69,46.74)
N16880733: length 1.7
  TOP w0.127: R822.2 154.19,51.82 154.94,51.82 155.04,51.71 U46.38
N16880820: length 1
  BOTTOM w0.508: R224.2 151.9,46.61 C309.1
N16890207: length 2.9
  TOP w0.127: U46.39 155.06,51.31 154.87,51.5 153.49,51.5 R227.2
N16973728: length 0.8
  BOTTOM w0.508: R253.1 132.33,47.24 v1(132.46,47.37)
N16973810: length 1.7
  TOP w0.127: U49.38 132.82,52.35 132.72,52.45 131.96,52.45 R825.2
N16973842: length 1
  BOTTOM w0.508: R253.2 129.67,47.24 C341.1
N16974061: length 4.8
  TOP w0.127: R238.2 142.88,50.67 141.73,50.67 141.36,51.05 C331.2 140.92,50.75 U49.19
N16974094: length 3.1
  TOP w0.127: R239.2 140.97,47.12 140.59,47.5 140.59,48.01 139.86,48.75 U49.14
N16974110: length 2.9
  TOP w0.127: U49.16 139.84,49.55 139.88,49.59 139.89,49.59 139.9,49.59 140.27,49.59 140.27,49.59 140.27,49.59 140.59,49.28 140.59,48.89 141.35,48.13 R242.2
N16974123: length 2.4
  TOP w0.127: U49.17 140.55,49.95 141.35,49.15 R243.2
N16974136: length 2.2
  TOP w0.127: R244.2 141.18,50.35 U49.18
N16974138: length 3.6
  TOP w0.127: U49.13 139.74,48.35 140.21,47.88 140.21,46.86 140.97,46.1 R245.2
N16974225: length 2.2
  TOP w0.508: T2.15 v1(140.64,30.95)
  BOTTOM w0.508: R236.1 140.63,30.93 v1(140.64,30.95)
N16974227: length 15.2
  BOTTOM w0.508: C334.1 137.52,29.84 R236.2 139.03,29.12 139.45,28.7 141.61,28.7 142.07,29.16 ; 145.12,29.19 144.63,28.7 142.54,28.7 142.07,29.16 ; 145.12,29.19 R240.2 ; 145.12,29.19 145.63,28.69 147.68,28.69 148.17,29.17 R241.2 ; R237.2 142.07,29.16
N16974244: length 2.2
  TOP w0.508: T2.18 v1(143.64,30.95)
  BOTTOM w0.508: R237.1 143.68,30.92 v1(143.64,30.95)
N16974248: length 2.2
  TOP w0.508: T2.21 v1(146.65,30.95)
  BOTTOM w0.508: v1(146.65,30.95) 146.72,30.87 R240.1
N16974260: length 2.2
  TOP w0.508: T2.24 v1(149.65,30.95)
  BOTTOM w0.508: R241.1 149.77,30.82 v1(149.65,30.95)
N16974322: length 16.6
  TOP w0.508: T2.10 v1(140.64,40.31) ; T2.1 149.65,39.97 v1(149.35,40.26) ; T2.4 v1(146.65,40.31) ; T2.7 v1(143.64,40.31)
  BOTTOM w0.508: v1(146.65,40.31) 146.69,40.28 C332.2 ; v1(146.65,40.31) v1(143.64,40.31) ; v1(146.65,40.31) 149.3,40.31 v1(149.35,40.26) 149.61,40 C333.2 ; v1(143.64,40.31) v1(140.64,40.31) 140.59,40.26 C328.2 ; v1(143.64,40.31) 143.64,40.31 C330.2
N16974528: length 59.5
  TOP w0.508: v1(135.25,38.73) 135.25,38.74 C329.1 135.25,40.61 FB29.2
  L6SIG w0.508: v1(135.25,38.73) 136.65,37.34 136.65,32 139.57,29.08 147.7,29.08 148.97,27.81 148.97,25.4 153.03,21.34 153.03,10.41 151.38,8.76 151.38,7.49 152.02,6.86 155.96,6.86 157.26,8.17 J14.B11
N16974538: length 51.1
  TOP w0.127: v1(150.75,42.42) 150.63,42.54 C337.1 149.47,43.18 149.1,43.18 148.08,44.2 FB61.2
  L6SIG w0.102: v1(150.75,42.42) 150.75,40.69 150.39,40.34 150.39,39.85 151.13,39.12 151.13,24.38 153.8,21.72 153.8,10.29 154.69,9.4 165.14,9.4 J14.B12
N16974570: length 30.1
  TOP w0.127: FB61.1 v1(148.08,46.35) ; R248.2 v1(129.03,56.77)
  L6SIG w0.102: v1(129.03,56.77) 129.54,57.28 132.21,57.28 132.97,58.04 133.86,58.04 134.37,57.53 134.37,53.98 135.38,52.96 143.26,52.96 144.65,51.56 146.43,51.56 147.95,50.04 147.95,46.48 v1(148.08,46.35)
N16974572: length 40.9
  TOP w0.127: FB60.2 147.07,44.7 149.1,42.67 C338.1 148.47,42.54 v1(148.34,42.67)
  L6SIG w0.102: v1(148.34,42.67) 149.61,41.4 149.61,40.77 150.11,40.26 150.11,39.75 150.88,38.99 150.88,24.26 153.54,21.59 153.54,9.05 J14.B9
N16974576: length 25.1
  TOP w0.127: v1(133.35,57.53) 132.96,57.14 R247.2 ; v1(147.19,46.48) 147.07,46.35 FB60.1
  L6SIG w0.102: v1(147.19,46.48) 147.7,46.99 147.7,49.97 146.34,51.33 144.5,51.33 143.13,52.7 134.62,52.7 133.22,54.1 133.22,57.28 133.35,57.4 v1(133.35,57.53)
N16974631: length 4
  TOP w0.127: R250.1 141.99,52.97 140.59,51.56 140.59,51.31 140.38,51.1 139.88,51.1 139.84,51.15 U49.20
N16974829: length 8.4
  TOP w0.127: U49.42 132.78,50.75 132.65,50.61 132.28,50.61 131.45,51.43 128.4,51.43 127.42,52.41 Y2.1 127.42,54.01 C339.1
N16974847: length 4.5
  TOP w0.127: U49.43 131.89,50.35 131.44,50.79 C340.1 129.58,50.79 Y2.3
N16974885: length 3.1
  TOP w0.127: U49.29 136.87,54.11 136.83,54.16 136.83,54.66 137.79,55.63 R249.2
N16975047: length 4
  TOP w0.127: U49.46 132.16,49.15 132.16,49.14 130.93,49.14 130.69,48.9 C335.1 R246.1
N16975158: length 2.5
  TOP w0.127: U49.33 135.27,53.96 135,54.23 135,55.25 R251.1
N16975193: length 2.9
  TOP w0.127: U49.39 132.83,51.95 132.65,52.13 131.26,52.13 R256.2
N16980127: length 10.3
  TOP w0.127: R408.1 268.48,94.62 268.99,94.11 270.89,94.11 272.03,95.25 273.56,95.25 274.57,94.23 274.57,92.6 J18.B11
N16980167: length 2.3
  TOP w0.127: R403.1 268.35,87.88 J18.A8
N16980179: length 8.3
  TOP w0.127: R400.1 269.62,93.6 270.64,92.58 270.64,91.69 271.15,91.19 272.94,91.19 J18.B9
N16980191: length 3.9
  TOP w0.127: J18.A5 267.93,86.08 R401.1
N16980203: length 1.9
  TOP w0.127: R402.1 267.92,87.08 J18.A6
N16980532: length 12.3
  TOP w0.127: C607.1 267.71,101.74 268.01,102.04 270.2,102.04 271.28,100.97 274.39,100.97 274.95,100.4 274.95,97.66 274.7,97.41 274.3,97.41 274.05,97.66 J18.B15
N16980534: length 12.3
  TOP w0.127: J18.B14 275.31,97.82 275.31,100.55 274.54,101.32 271.42,101.32 270.34,102.4 268.05,102.4 C606.1
N16984231: length 2.6
  TOP w0.127: J19.33 179.57,197.7 177.75,197.7 C598.1
N16984233: length 2.6
  TOP w0.127: J19.31 179.57,198.05 177.73,198.05 C599.1
N16984263: length 2.6
  TOP w0.127: C1265.1 177.79,200.91 179.56,200.91 J19.25
N16984265: length 2.6
  TOP w0.127: C1266.1 177.67,201.29 179.61,201.29 J19.23
N16985354: length 2.6
  TOP w0.127: C630.1 90.98,205.65 89.16,205.65 J20.33
N16985356: length 2.6
  TOP w0.127: J20.31 89.16,205.3 91,205.3 C631.1
N16985386: length 2.6
  TOP w0.127: C1269.1 90.94,202.44 89.17,202.44 J20.25
N16985388: length 2.6
  TOP w0.127: C1270.1 91.07,202.06 89.12,202.06 J20.23
N17013042: length 103.6
  TOP w0.102: v1(114.17,31.12) 113.89,31.4 113.89,64.36 127.38,77.85 140.46,77.85 149.71,87.1 149.71,96.68 152.47,99.44 157.3,99.44 159.13,101.28 159.13,103.06 U1.F1
  BOTTOM w0.102: R167.1 114.29,29.52 L1.1 114.14,30.28 113.9,30.51 113.9,30.85 v1(114.17,31.12)
N17013078: length 104.5
  TOP w0.102: v1(113.38,31.12) 113.66,31.4 113.66,64.45 127.29,78.08 140.37,78.08 149.48,87.19 149.48,96.77 152.37,99.67 157.2,99.67 158.9,101.37 158.9,103.63 U1.F2
  BOTTOM w0.102: R168.1 113.28,29.52 L1.4 113.44,30.28 113.67,30.51 113.67,30.82 v1(113.38,31.12)
N17013302: length 9.7
  TOP w0.127: U1.H4 v2(160.52,105.25)
  BOTTOM w0.127: v2(160.52,105.25) 160.11,104.84 160.11,103.48 159.87,103.24 159.55,103.24 157.72,103.24 156.46,101.98 156.46,99.96 R172.2
N17013307: length 6.6
  TOP w0.127: U1.F4 v2(158.92,105.25)
  BOTTOM w0.127: R173.2 155.83,102.36 156.51,103.04 156.51,104.24 157.12,104.85 158.52,104.85 v2(158.92,105.25)
N17013374: length 8.3
  TOP w0.127: U1.G4 v2(159.72,105.25)
  BOTTOM w0.127: C1022.1 R171.2 155.82,101.85 156.91,102.94 156.91,103.84 157.11,104.04 159.11,104.04 159.31,104.24 159.31,104.84 v2(159.72,105.25)
N17020476: length 103.2
  TOP w0.102: v1(116.73,31.12) 116.45,31.4 116.45,64.95 127.96,76.45 140.84,76.45 150.98,86.59 150.98,96.17 152.49,97.69 157.45,97.69 160.76,101 160.76,103.09 U1.H1
  BOTTOM w0.102: R169.1 116.83,29.52 L2.1 116.68,30.28 116.44,30.51 116.44,30.82 v1(116.73,31.12)
N17020482: length 104.1
  TOP w0.102: v1(115.94,31.12) 116.23,31.4 116.23,65.04 127.86,76.68 140.75,76.68 150.75,86.68 150.75,96.27 152.4,97.92 157.35,97.92 160.53,101.09 160.53,103.66 U1.H2
  BOTTOM w0.102: R170.1 115.82,29.52 L2.4 115.98,30.28 116.21,30.51 116.21,30.85 v1(115.94,31.12)
N17021121: length 120.2
  TOP w0.127: U1.F5 v2(158.92,106.05) ; v1(100.2,38.48) R156.1 101.21,38.47 Q3.3 101.22,35.93 R157.1
  L3SIG w0.102: v1(100.2,38.48) 100.96,37.72 103.63,37.72 106.67,34.67 109.09,34.67 116.2,41.78 120.65,41.78 123.95,45.09 123.95,72.52 132.46,81.03 143.38,81.03 151.51,89.15 151.51,93.85 152.81,95.15 155.47,95.15 158.54,98.21 158.54,102.44 158.7,102.6 158.7,103.09 158.54,103.25 158.54,104.6 158.76,104.83 159.07,104.83 159.3,105.05 159.3,105.67 v2(158.92,106.05)
N17021131: length 125.8
  TOP w0.127: R160.1 98.17,33.9 96.51,35.57 Q4.3 96.51,38.34 R155.1 96.52,39 96.9,39.37 99.18,39.37 v1(99.56,38.99) ; U1.H5 v2(160.52,106.05)
  L3SIG w0.102: v1(99.56,38.99) 99.56,38.35 100.55,37.36 103.47,37.36 106.55,34.29 109.22,34.29 116.33,41.4 120.78,41.4 124.33,44.96 124.33,72.39 132.59,80.65 143.51,80.65 151.89,89.03 151.89,93.73 152.98,94.82 155.65,94.82 159.13,98.3 159.13,103.76 159.3,103.93 159.3,104.57 159.56,104.83 159.87,104.83 160.14,105.09 160.14,105.67 v2(160.52,106.05)
N17040696: length 3.9
  TOP w0.127: v1(164.47,100.33) 164.91,100.77 164.91,103.24 U1.N1
  BOTTOM w0.127: R59.1 v1(164.47,100.33)
N17040868: length 1.7
  TOP w0.127: U1.K1 v2(162.12,102.85)
  BOTTOM w0.127: R61.1 162.13,102.86 v2(162.12,102.85)
N17055310: length 5.3
  TOP w0.254: C273.1 133.35,64.52 133.6,64.77 134.24,64.77 134.52,64.49 U39.2
N17055339: length 2
  TOP w0.254: U39.6 137.12,62.44 136.91,62.23 C275.1
N17055373: length 3.5
  TOP w0.254: C271.2 134.23,60.59 133.98,60.83 133.98,62.36 133.87,62.47 U39.1
N17055376: length 2.2
  TOP w0.254: U39.3 135.17,62.65 134.62,62.1 C271.1
N17055394: length 3.7
  TOP w0.254: C274.2 135.51,60.59 135.25,60.84 135.25,62.1 135.82,62.67 U39.4
N17055396: length 2.2
  TOP w0.254: C274.1 135.89,61.98 136.47,62.56 U39.5
N17055419: length 3.9
  TOP w0.127: U39.14 135.17,68.11 134.87,67.81 R196.1
N17055422: length 5.5
  TOP w0.127: R197.1 133.72,65.78 135.82,67.87 U39.13
N17055459: length 2.2
  TOP w0.127: R199.1 138.42,62.11 U39.8
N17055461: length 2
  TOP w0.127: R198.1 137.77,61.74 U39.7
N17055495: length 33
  TOP w0.127: v1(131.95,63.12) 131.95,66.17 R196.2 ; FB18.1 v1(121.16,39.5)
  L6SIG w0.102: v1(121.16,39.5) 121.16,41.53 124.33,44.7 124.33,54.36 128.27,58.29 128.27,59.44 v1(131.95,63.12)
N17055507: length 34
  TOP w0.127: R197.2 v1(132.59,62.48) ; FB19.1 v1(121.16,36.45)
  L6SIG w0.102: v1(121.16,36.45) 122.05,37.34 122.05,41.4 125.09,44.45 125.09,54.1 130.17,59.18 130.17,60.07 v1(132.59,62.48)
N17055527: length 35.5
  TOP w0.127: v1(128.78,58.42) 130.68,58.42 132.08,59.82 134.87,59.82 135.38,59.31 137.41,59.31 137.92,59.82 R198.2 ; FB20.1 v1(121.16,37.97)
  L6SIG w0.102: v1(121.16,37.97) 121.67,38.48 121.67,41.53 124.71,44.58 124.71,54.23 128.78,58.29 v1(128.78,58.42)
N17055529: length 38.7
  TOP w0.127: R199.2 138.94,59.94 137.92,58.93 134.75,58.93 134.37,59.31 v1(132.59,59.31) ; FB21.1 v1(121.16,34.92)
  L6SIG w0.102: v1(132.59,59.31) 130.81,59.31 125.48,53.98 125.48,44.32 122.43,41.27 122.43,36.2 v1(121.16,34.92)
N17056698: length 5.3
  TOP w0.254: C287.1 126.24,64.52 126.52,64.8 127.1,64.8 127.41,64.49 U41.2
N17056714: length 2
  TOP w0.254: U41.6 130.01,62.57 129.79,62.36 C288.1
N17056740: length 3.5
  TOP w0.254: C285.2 127.13,60.59 126.87,60.84 126.87,62.36 126.76,62.47 U41.1
N17056750: length 2.2
  TOP w0.254: U41.3 128.06,62.65 127.51,62.1 C285.1
N17056764: length 3.7
  TOP w0.254: C284.2 128.39,60.59 128.14,60.83 128.14,62.1 128.71,62.67 U41.4
N17056766: length 2.2
  TOP w0.254: C284.1 128.78,61.98 129.36,62.56 U41.5
N17056776: length 3.9
  TOP w0.127: R200.1 127.5,67.68 128.06,68.24 U41.14
N17056778: length 5.7
  TOP w0.127: R201.1 126.74,65.65 128.71,67.62 U41.13
N17056796: length 2.2
  TOP w0.127: R203.1 131.31,62.11 U41.8
N17056798: length 2
  TOP w0.127: R202.1 130.66,61.74 U41.7
N17056816: length 40.7
  TOP w0.127: v1(125.86,57.4) 124.84,58.42 124.84,66.05 R200.2 ; FB22.1 v1(121.16,30.35)
  L6SIG w0.102: v1(121.16,30.35) 120.27,31.24 120.27,41.66 123.57,44.96 123.57,54.61 125.86,56.9 v1(125.86,57.4)
N17056834: length 37
  TOP w0.127: v1(126.49,57.91) 126.11,57.91 125.48,58.55 R201.2 ; FB23.1 v1(121.16,31.88)
  L6SIG w0.102: v1(126.49,57.91) 126.49,57.02 123.95,54.48 123.95,44.83 120.65,41.53 120.65,32.38 v1(121.16,31.88)
N17056844: length 39.6
  TOP w0.127: FB24.1 v1(121.16,28.83) ; v1(127.64,58.8) 128.14,59.31 130.17,59.31 130.81,59.94 R202.2
  L6SIG w0.102: v1(121.16,28.83) 119.89,30.1 119.89,41.78 123.19,45.09 123.19,55.5 126.49,58.8 v1(127.64,58.8)
N17056846: length 34.3
  TOP w0.127: FB25.1 v1(121.16,33.4) ; R203.2 131.83,60.2 130.56,58.93 128.52,58.93 128.14,58.55 128.14,56.52 v1(128.52,56.13)
  L6SIG w0.102: v1(128.52,56.13) 128.14,56.13 125.86,53.85 125.86,44.2 122.81,41.15 122.81,35.05 v1(121.16,33.4)
N17059643: length 6.3
  TOP w0.127: U1.U6 v2(168.52,106.85)
  BOTTOM w0.127: R130.1 165.99,104.14 166.69,104.84 167.96,104.84 168.12,105 168.12,105.51 168.52,105.9 v2(168.52,106.85)
N17059732: length 5.8
  TOP w0.127: U1.AC3 v2(173.32,104.45)
  BOTTOM w0.127: v2(173.32,104.45) 173.74,104.03 173.74,102.62 173.61,102.49 173.61,100.2 R121.2
N17059733: length 4.2
  TOP w0.127: U1.AE4 v2(174.92,105.25)
  BOTTOM w0.127: R116.2 176.02,102.23 176.02,103.5 175.31,104.22 175.31,104.85 v2(174.92,105.25)
N17059734: length 2.9
  TOP w0.127: U1.AD3 v2(174.12,104.45)
  BOTTOM w0.127: R119.2 174.12,102.1 v2(174.12,104.45)
N17059735: length 3.2
  TOP w0.127: U1.AE3 v2(174.92,104.45)
  BOTTOM w0.127: R115.2 175.13,102.62 175.39,102.87 175.39,103.73 174.92,104.2 v2(174.92,104.45)
N17059985: length 5.9
  TOP w0.127: U1.AF4 v2(175.72,105.25)
  BOTTOM w0.127: R125.2 179.2,103.37 R123.2 179.07,103.51 179.07,103.76 178.79,104.04 176.92,104.04 v2(175.72,105.25)
N17060054: length 5.1
  TOP w0.127: U1.AF3 v2(175.72,104.45)
  BOTTOM w0.127: R127.2 C55.2 178.18,102.37 178.18,102.74 177.93,103 177.16,103 v2(175.72,104.45)
N17060498: length 4.2
  TOP w0.127: U1.AH3 v2(177.32,104.45)
  BOTTOM w0.127: R129.2 177.64,104.78 v2(177.32,104.45)
N17072443: length 29.1
  TOP w0.127: TP2.1 v1(136.72,129.35) 137.92,128.14 137.92,127.64 150.07,115.48 154.85,115.48 155.07,115.7 155.77,115.7 U1.B17
  BOTTOM w0.127: v1(136.72,129.35) 136.9,129.17 R106.2
N17082319: length 6.2
  TOP w0.127: U1.Y20 v2(170.92,118.85)
  BOTTOM w0.127: R140.2 171.32,114.63 171.32,114.68 171.32,114.68 171.32,117.54 171.58,117.79 171.58,118.3 171.03,118.85 v2(170.92,118.85)
N17082346: length 1.9
  TOP w0.127: U1.AA12 v2(171.72,111.65)
  BOTTOM w0.127: R139.2 172.42,110.74 171.72,111.45 v2(171.72,111.65)
N17109221: length 6.4
  TOP w0.127: U1.AA3 v2(171.72,104.45)
  BOTTOM w0.127: R95.1 170.43,100.07 170.43,102.49 171.72,103.77 v2(171.72,104.45)
N17109223: length 5.8
  TOP w0.127: U1.AB3 v2(172.52,104.45)
  L3SIG w0.102: v2(172.52,104.45) 172.52,104.32 172.08,103.89 v1(172.08,100.2)
  BOTTOM w0.127: R97.1 v1(172.08,100.2)
N17109295: length 128
  TOP w0.127: U19.14 257.26,147.87 v1(257.18,147.95) ; U1.V3 v2(169.32,104.45)
  L6SIG w0.102: v1(257.18,147.95) 257.05,147.83 257.05,146.43 246.82,136.21 246.82,120.84 244.09,118.11 236.22,118.11 232.98,114.87 214.19,114.87 197.36,98.04 178.82,98.04 174.88,101.98 172.32,101.98 170.27,104.03 169.73,104.03 v2(169.32,104.45)
  BOTTOM w0.127: R87.1 169.32,99.71 v2(169.32,104.45)
N17109336: length 128.4
  TOP w0.127: U1.Y3 v2(170.92,104.45) ; U19.15 257.91,148.36 v1(257.81,148.46)
  L6SIG w0.102: v2(170.92,104.45) 170.92,103.79 172.34,102.36 175.01,102.36 179.07,98.3 197.23,98.3 214.12,115.19 232.92,115.19 236.09,118.36 243.9,118.36 246.51,120.97 246.51,136.27 256.67,146.43 256.67,148.11 257.02,148.46 v1(257.81,148.46)
  BOTTOM w0.127: R86.1 169.93,99.56 169.93,102.62 170.92,103.61 v2(170.92,104.45)
N17111815: length 3.4
  TOP w0.127: J19.1 178.04,213.48 177.42,212.85 R399.1
N17112169: length 3.4
  TOP w0.127: J20.1 90.69,189.88 91.31,190.5 R411.1
N17112712: length 2.1
  TOP w0.127: R99.2 257.26,154.14 U19.3
N17112758: length 3.3
  TOP w0.127: U1.C20 v2(156.52,118.85)
  BOTTOM w0.127: R104.2 156.29,118.62 v2(156.52,118.85)
N17112821: length 3.3
  TOP w0.127: U1.B20 v2(156.52,118.05)
  BOTTOM w0.127: R105.2 153.95,117.64 156.11,117.64 v2(156.52,118.05)
N17112937: length 8.6
  TOP w0.127: v2(158.91,110.04) 158.92,110.04 U1.F9
  BOTTOM w0.127: v2(158.91,110.04) 158.51,109.64 158.51,108.28 158.28,108.05 157.92,108.05 157.71,107.84 157.71,107.44 156.71,106.44 156.22,106.44 155.19,105.41 R84.1
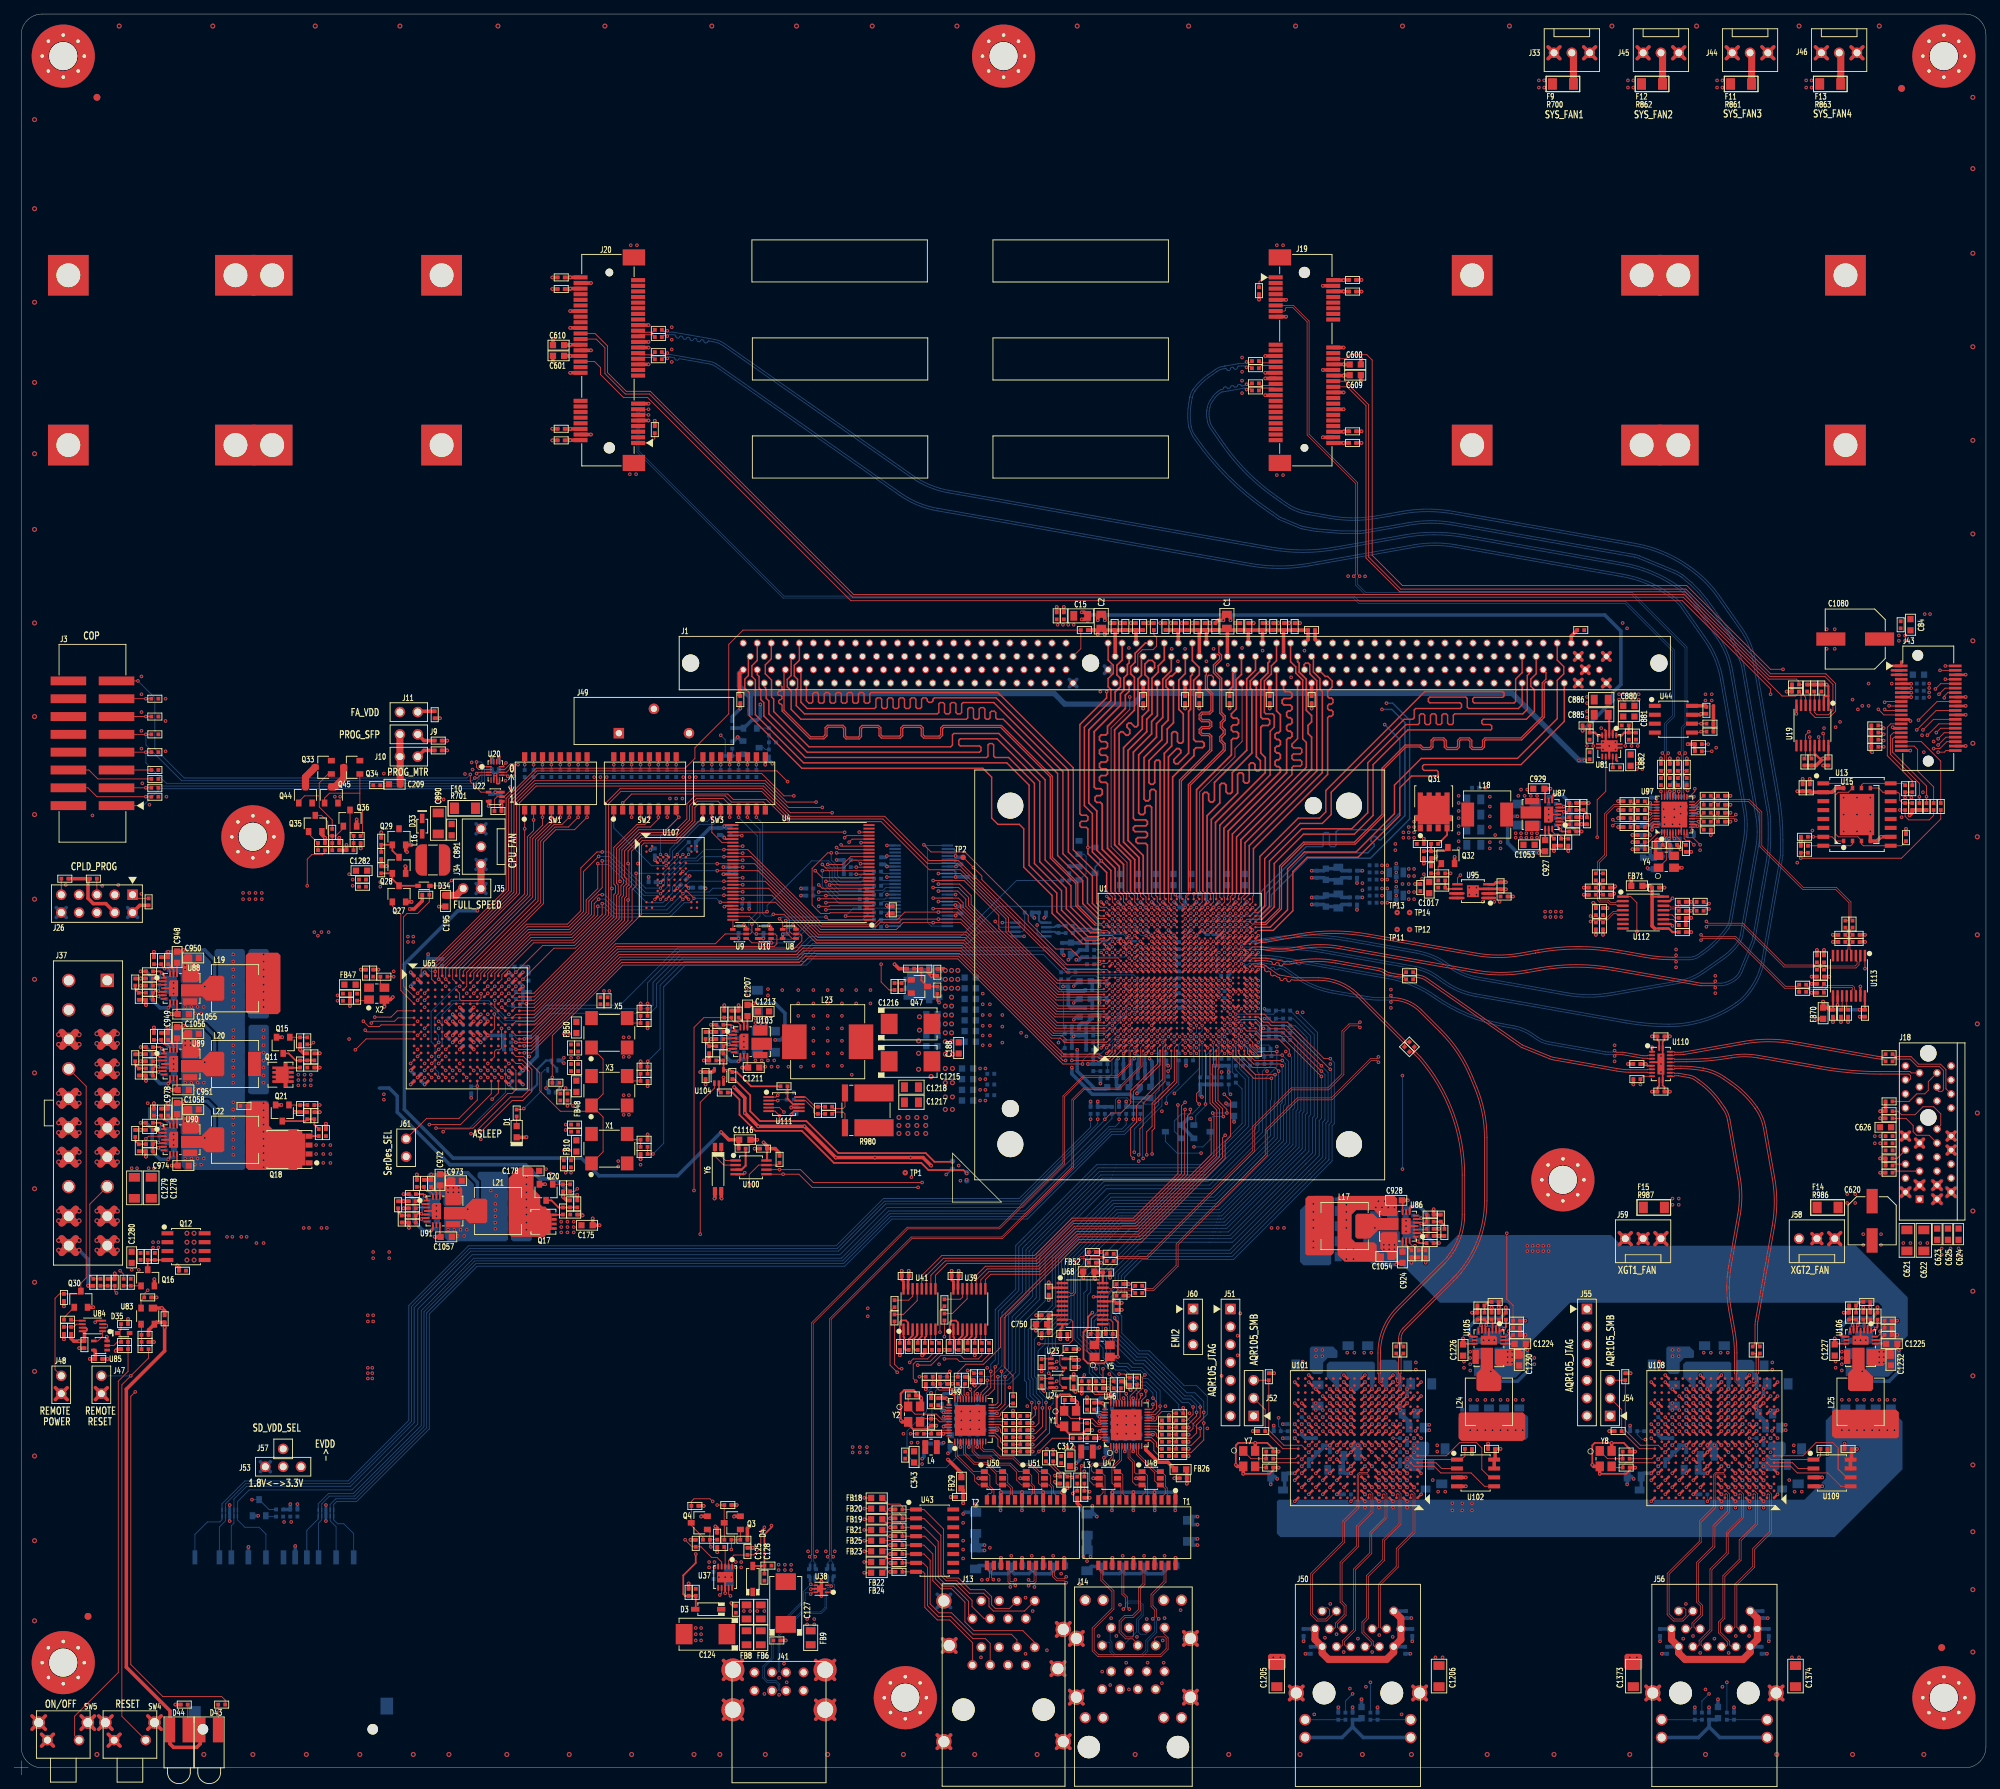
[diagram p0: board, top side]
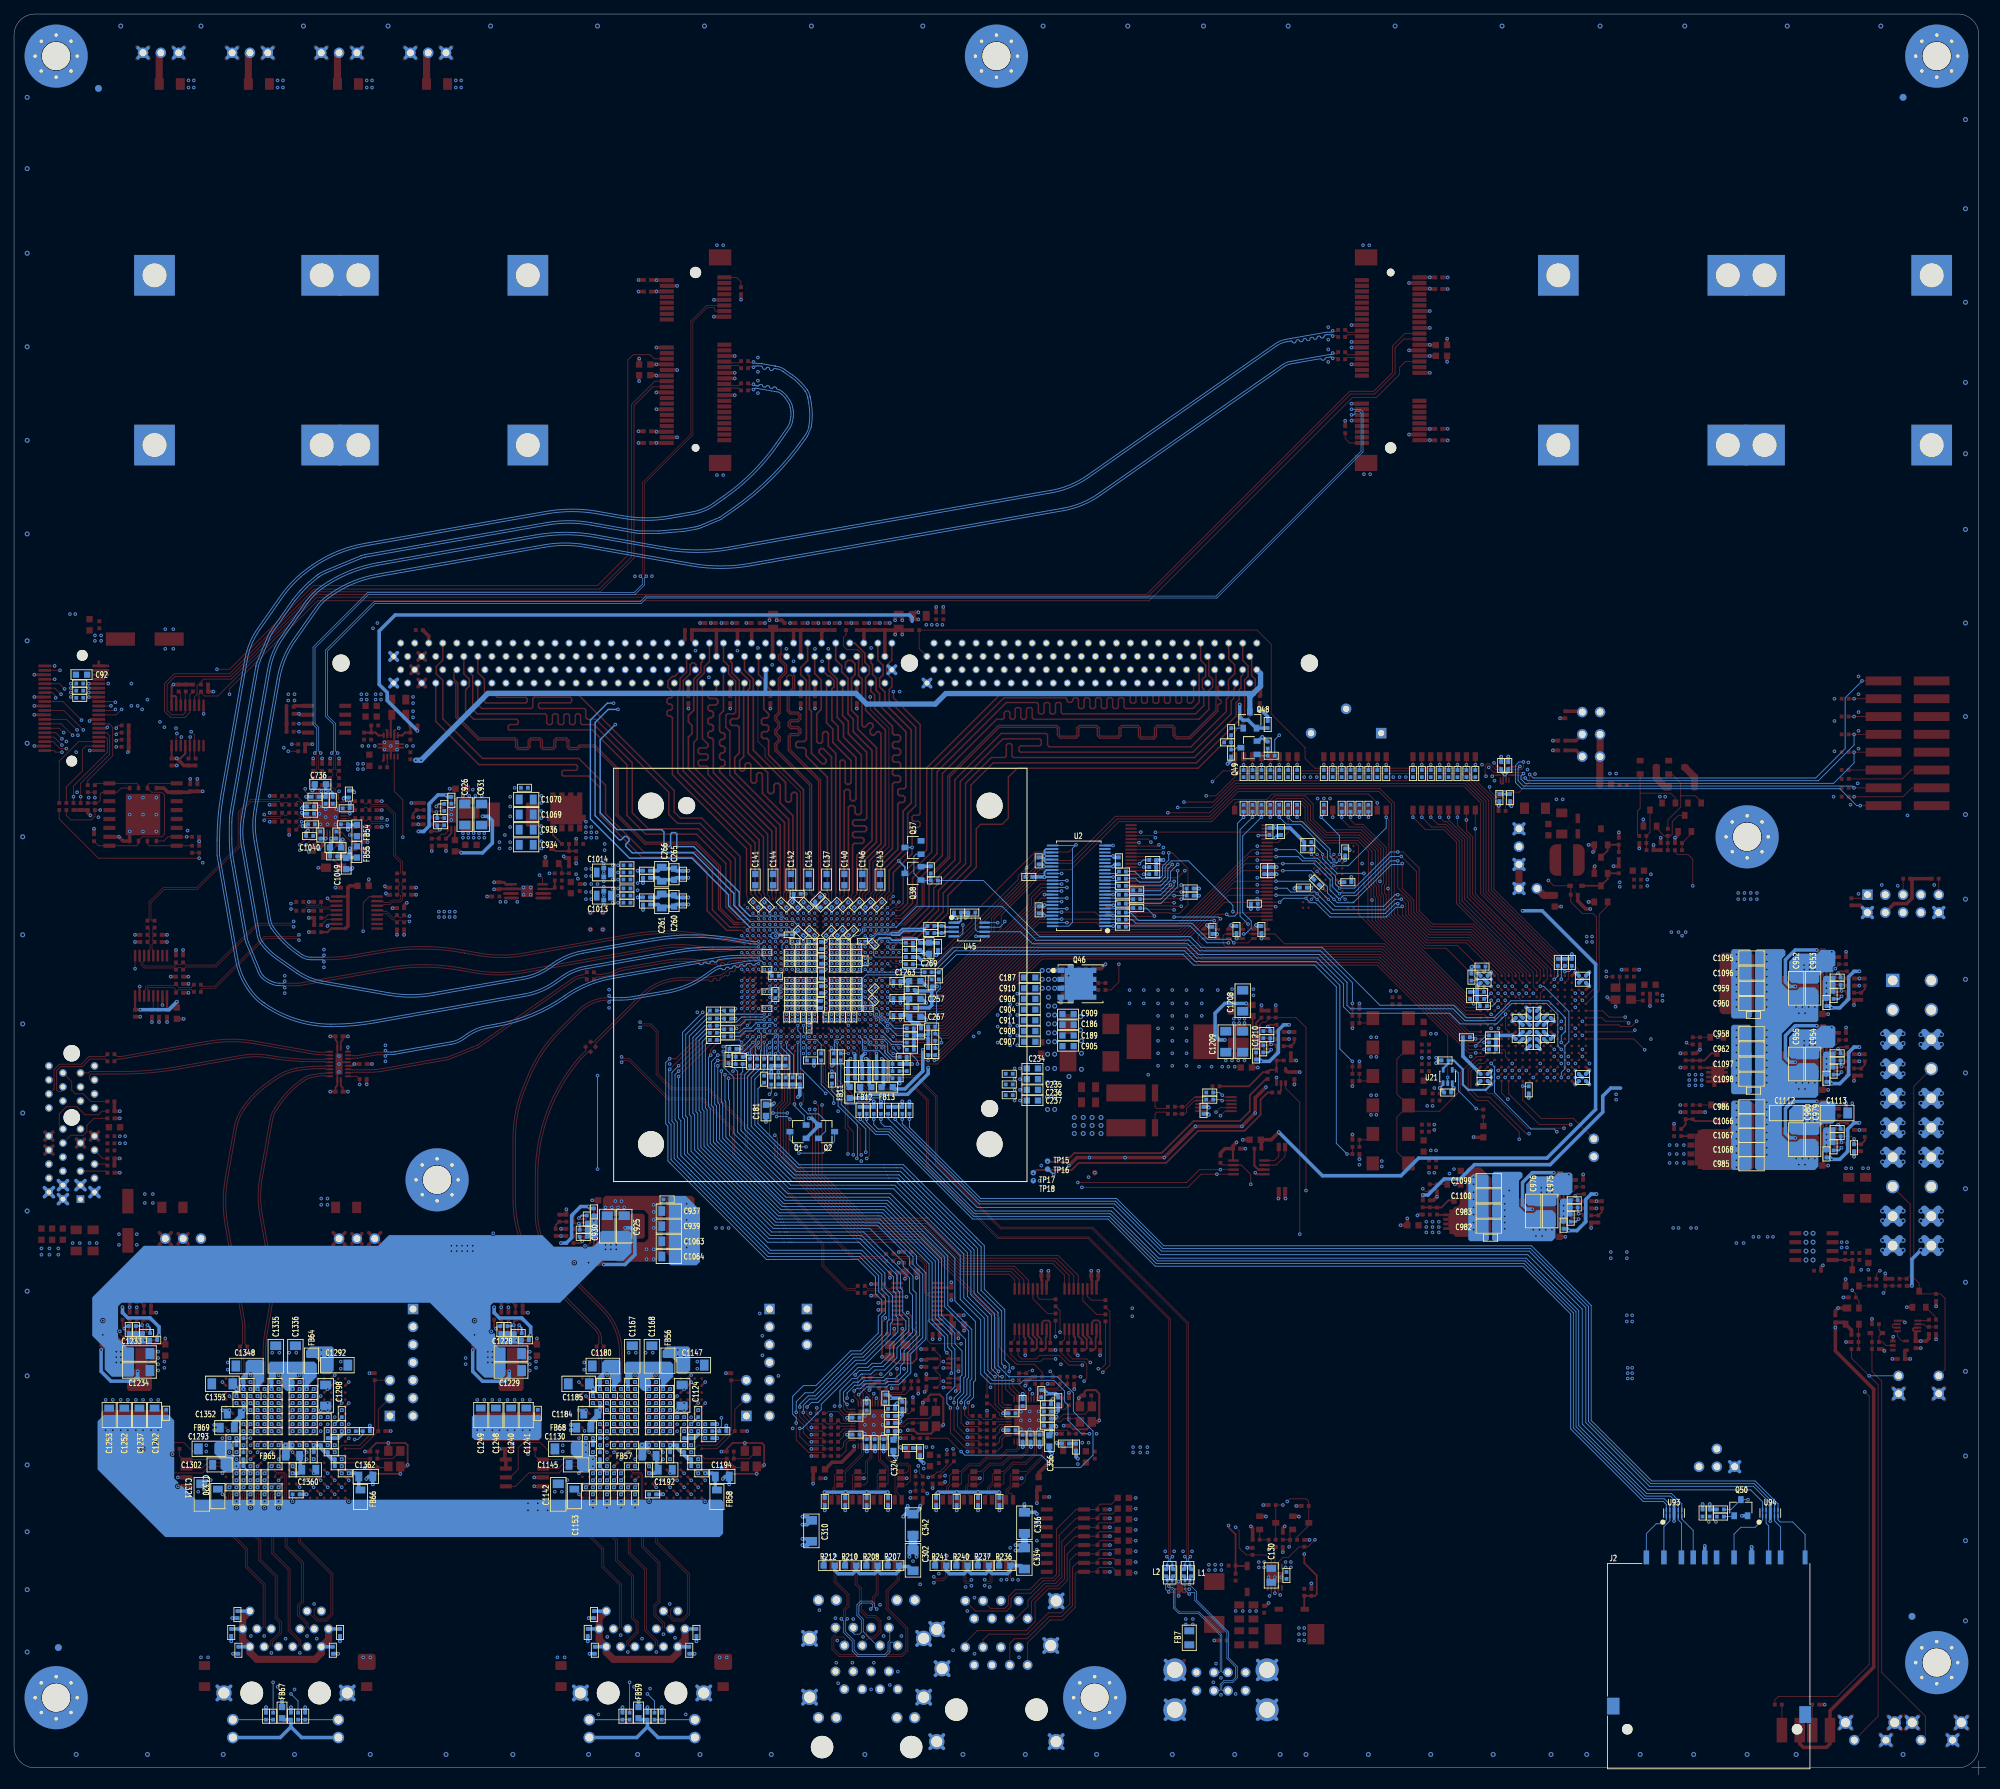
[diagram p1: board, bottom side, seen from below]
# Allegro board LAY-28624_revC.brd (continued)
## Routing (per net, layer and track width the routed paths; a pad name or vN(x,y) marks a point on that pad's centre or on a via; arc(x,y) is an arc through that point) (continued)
N17116912: length 18.9
  TOP w0.127: U1.D3 v2(157.32,104.45)
  L6SIG w0.102: v2(157.32,104.45) 148.9,104.45 v1(148.84,104.39)
  BOTTOM w0.127: v1(148.84,104.39) 148.84,104.9 149.6,105.66 R874.2 149.73,106.67 R70.1 149.54,106.88 149.54,111.57 149.03,112.08 149.03,113.23 R873.2
N17170143: length 3.2
  TOP w0.127: R511.1 C718.1 88.08,98.93 X3.3
N17232338: length 3.2
  TOP w0.127: R517.1 C728.1 88.08,107.19 X5.3
N17271631: length 6.6
  TOP w0.127: U1.F19 v2(158.92,118.05)
  BOTTOM w0.127: R82.1 158.25,116.59 158.51,116.85 158.51,117.64 v2(158.92,118.05)
N17321001: length 8.3
  TOP w0.127: v1(72.64,95) 72.51,94.86 R103.1
  BOTTOM w0.127: U21.4 75.63,100.52 75.18,100.07 75.18,97.54 v1(72.64,95)
N17321019: length 1.4
  TOP w0.127: R103.2 D1.2
N17399246: length 3.6
  TOP w0.127: U83.3 18.17,64.19 R705.1 C893.1 R707.2
N17399288: length 62.9
  TOP w0.127: R707.1 19.17,59.43 v1(16.64,56.9) 15.37,55.63 15.37,8.37 SW4.2
  BOTTOM w0.127: J47.1 v1(16.64,56.9)
N17400346: length 61.5
  TOP w0.127: D35.2 16.25,62.77 R714.1 R711.1 16.25,57.52 14.86,56.13 14.86,14.61 8.64,8.38 8.64,5.6 SW5.2
N17401317: length 2.3
  TOP w0.127: U85.4 11.95,61.86 12.63,62.54 U84.1
N17401544: length 5.1
  TOP w0.127: U85.2 14.22,61.21 14.73,61.72 R714.2 15.25,62.52 D35.1 15.25,63.47 C895.1
N17403382: length 15.4
  TOP w1.016: J34.1 J35.1
  BOTTOM w0.508: 65.84,129.09 J34.1 ; J34.1 67.26,129.09 ; J34.1 65.84,130.5 ; J34.1 67.26,130.5 ; J34.3 67.26,134.17 ; J34.3 65.84,134.17 ; J34.3 65.84,135.58 ; J34.3 67.26,135.58 ; 65.84,127.07 J35.1 ; J35.1 67.26,127.07 ; J35.1 65.84,125.66 ; J35.1 67.26,125.66
N17423481: length 5
  TOP w0.127: J3.5 R112.2
N17423546: length 12.3
  TOP w0.127: J3.6 10.67,143.26 11.94,141.99 R108.1
N17523688: length 1.8
  TOP w0.127: U84.3 13.21,64.26 13.34,64.14 13.34,63.88 13.21,63.76 U84.2
N17523697: length 1.7
  TOP w0.127: R713.1 8.26,64.76 U84.5
N17523706: length 2.8
  TOP w0.127: C896.1 R715.2 8.5,63.87 8.89,64.26 U84.6
N17524661: length 4.8
  TOP w0.254: R704.1 C892.1 53.9,132.6 Q29.1 53.91,131.77 Q28.3
N17525004: length 6.5
  TOP w0.254: R703.1 53.9,128.53 Q28.1 53.91,127.7 Q27.3 57.56,126.75 D34.2
N17736577: length 1.9
  TOP w0.127: SW1.16 v1(72.77,144.02)
  BOTTOM w0.127: R17.1 v1(72.77,144.02)
N17736598: length 1.9
  TOP w0.127: SW1.15 v1(74.04,144.02)
  BOTTOM w0.127: R19.1 v1(74.04,144.02)
N17736619: length 1.9
  TOP w0.127: SW1.14 v1(75.31,144.02)
  BOTTOM w0.127: R21.1 v1(75.31,144.02)
N17736629: length 1.9
  TOP w0.127: SW1.13 v1(76.58,144.02)
  BOTTOM w0.127: R23.1 v1(76.58,144.02)
N17736659: length 1.9
  TOP w0.127: SW1.12 v1(77.85,144.02)
  BOTTOM w0.127: R25.1 v1(77.85,144.02)
N17736669: length 1.9
  TOP w0.127: SW1.11 v1(79.12,144.02)
  BOTTOM w0.127: R27.1 v1(79.12,144.02)
N17736681: length 1.9
  TOP w0.127: SW1.10 v1(80.39,144.02)
  BOTTOM w0.127: R29.1 v1(80.39,144.02)
N17736695: length 1.9
  TOP w0.127: 81.66,145.16 v1(81.66,144.02)
  BOTTOM w0.127: R31.1 v1(81.66,144.02)
N17736739: length 1.9
  TOP w0.127: SW2.16 v1(85.47,144.02)
  BOTTOM w0.127: R33.1 v1(85.47,144.02)
N17736751: length 1.9
  TOP w0.127: 86.74,145.16 v1(86.74,144.02)
  BOTTOM w0.127: R34.1 v1(86.74,144.02)
N17736763: length 1.9
  TOP w0.127: SW2.14 v1(88.01,144.02)
  BOTTOM w0.127: R35.1 v1(88.01,144.02)
N17736781: length 1.9
  TOP w0.127: SW2.13 v1(89.28,144.02)
  BOTTOM w0.127: R36.1 v1(89.28,144.02)
N17736801: length 1.9
  TOP w0.127: SW2.11 v1(91.82,144.02)
  BOTTOM w0.127: R39.1 v1(91.82,144.02)
N17736803: length 1.9
  TOP w0.127: SW2.12 v1(90.55,144.02)
  BOTTOM w0.127: R37.1 v1(90.55,144.02)
N17736817: length 1.9
  TOP w0.127: SW2.10 v1(93.09,144.02)
  BOTTOM w0.127: R38.1 v1(93.09,144.02)
N17736835: length 1.9
  TOP w0.127: SW2.9 v1(94.36,144.02)
  BOTTOM w0.127: R40.1 v1(94.36,144.02)
N18263878: length 1.7
  TOP w0.254: U103.15 104.01,107.2 R904.2
N18263905: length 10.5
  TOP w0.254: R910.1 v1(99.31,106.93) ; v1(103.25,101.73) 103.51,101.98 U103.8
  BOTTOM w0.508: C1220.1 103.51,101.99 v1(103.25,101.73) 102.11,101.73 100.84,103 100.84,106.17 100.08,106.93 v1(99.31,106.93)
N18263955: length 3
  TOP w0.254: R910.2 102.11,106.93 v1(102.36,106.68) 102.66,106.39 U103.1
  BOTTOM w0.254: v1(102.36,106.68) 101.99,106.31 R911.2
N18263961: length 22
  TOP w0.508: R905.1 99.31,105.91 v1(99.31,105.92) R907.2 ; C1207.2 105.19,109.77 v1(105.41,109.98)
  L6SIG w0.508: v1(99.31,105.92) 107.32,105.92 v1(108.46,104.78)
  BOTTOM w0.508: v1(105.41,109.98) 108.46,109.98 109.86,108.59 109.86,105.41 109.22,104.78 v1(108.46,104.78)
N18263987: length 2.3
  TOP w0.254: R905.2 98.55,104.39 C1214.1 99.07,103.89 C1219.1
N18264005: length 23.7
  TOP w0.508: C1214.2 99.06,101.86 R915.2 v1(98.3,101.85)
  L6SIG w0.508: v1(98.3,101.85) 100.58,101.85 102.62,99.82 v1(119.38,99.82)
N18264015: length 3.7
  TOP w0.254: U103.5 101.97,104.02 v1(101.85,104.14) 101.34,104.14 C1219.2 101.09,103.88 R914.2
  BOTTOM w0.254: R913.2 101.99,104.27 v1(101.85,104.14)
N18264194: length 1.6
  TOP w0.127: U103.3 101.2,105.02 R908.2
N18264460: length 2.2
  TOP w0.254: U103.6 102,103.52 v1(101.85,103.38)
  BOTTOM w0.254: C1221.1 102.23,103 v1(101.85,103.38)
N18264464: length 1.7
  TOP w0.254: U103.14 104.51,108.15 C1207.1
N18264487: length 1.7
  TOP w0.254: R907.1 101.6,105.92 102,105.52 U103.2
N18271716: length 2.5
  TOP w0.127: R666.2 R669.2 40.75,105.16 Q15.1
N18271718: length 4.9
  TOP w0.254: R662.2 C873.2 41.77,101.85 R659.2 40.14,101.85 39.12,102.86 Q15.3
N18271794: length 1.3
  TOP w0.254: Q11.4 40.72,100.8 R659.1
N18272820: length 4.9
  TOP w0.254: Q20.3 76.59,81.91 77.6,80.89 R675.2 79.23,80.89 C875.2 R678.2
N18272822: length 2.5
  TOP w0.127: Q20.1 78.22,84.21 R684.2 R681.2
N18272905: length 1.3
  TOP w0.254: R675.1 78.18,79.84 Q17.4
N18273179: length 2.6
  TOP w0.127: Q21.1 39.19,95.5 R685.2 40.77,95.5 R682.2
N18273181: length 6.4
  TOP w0.254: R676.2 42.8,92.7 R679.2 C876.2 41.51,93.21 Q21.3
N18273262: length 1.4
  TOP w0.254: R676.1 42.05,91.07 Q18.4
N18273767: length 2.5
  TOP w0.127: R670.2 R671.2 18.09,69.73 Q16.1
N18273907: length 4.2
  TOP w0.254: Q16.3 R663.2 C874.2 20.07,73.41 Q12.4
N18275087: length 4
  TOP w0.305: U81.1 229.08,148.19 229.48,148.58 C887.1 ; R695.1 230.12,148.59 C887.1 ; C887.1 R696.2
N18275123: length 3
  TOP w0.305: U81.5 225.7,148.19 225.3,148.59 224.54,148.59 C884.1 224.53,148.59 R694.1
N18275169: length 1.6
  TOP w0.127: U81.9 227.83,143.65 R697.1
N18287015: length 6.9
  TOP w0.127: R138.1 149.99,60.71 149.03,59.75 149.03,58.48 149.49,58.02 U23.4 149.67,57.59 149.03,56.96 149.03,55.69 149.49,55.23 U24.4
N18382428: length 1.9
  TOP w0.127: SW3.16 v1(98.17,144.02)
  BOTTOM w0.127: R499.1 v1(98.17,144.02)
N18382505: length 1.9
  TOP w0.127: SW3.15 v1(99.44,144.02)
  BOTTOM w0.127: R500.1 v1(99.44,144.02)
N18382570: length 1.9
  TOP w0.127: SW3.14 v1(100.71,144.02)
  BOTTOM w0.127: R501.1 v1(100.71,144.02)
N18382580: length 1.9
  TOP w0.127: SW3.13 v1(101.98,144.02)
  BOTTOM w0.127: R503.1 v1(101.98,144.02)
N18382664: length 1.9
  TOP w0.127: SW3.11 v1(104.52,144.02)
  BOTTOM w0.127: R507.1 v1(104.52,144.02)
N18382676: length 1.9
  TOP w0.127: 105.79,145.16 v1(105.79,144.02)
  BOTTOM w0.127: R509.1 v1(105.79,144.02)
N18562864: length 2.4
  TOP w0.127: R713.2 7.12,65.21 Q30.1
N18563122: length 15.4
  TOP w0.127: R709.2 R706.1 10.79,71.24 10.79,81.36 J37.8
N18583652: length 1.4
  TOP w0.254: U104.2 100.46,97.54 R918.2
N18583655: length 11.5
  TOP w0.254: R915.1 101.08,101.85 R914.1 101.11,101.85 U104.4 102.04,100.52 R917.2 103,100.2 105.03,98.17 R985.2
N18586245: length 2.8
  BOTTOM w0.254: R205.2 148.85,121.03 C294.2 148.45,121.02 148.28,120.85 U45.2
N18586247: length 2.8
  BOTTOM w0.254: R206.2 148.85,120.02 C294.1 148.51,120.02 148.34,120.2 U45.3
N18848286: length 5.1
  TOP w0.102: U101.V4 197.02,56.19 arc(197.04,56.08) 197.1,55.98 197.13,55.95 arc(197.21,55.92) 197.28,55.95 197.38,56.05 197.38,57.19 197.31,57.26 197.31,57.28
  TOP w0.127: C1117.2 197.15,59.9 arc(197.27,59.73) 197.31,59.53 197.31,57.28
N18848288: length 5
  TOP w0.102: U101.U4 197.08,55.51 arc(197.12,55.51) 197.15,55.54 197.59,55.97 197.59,57.13 arc(197.59,57.17) 197.62,57.21 197.66,57.25 197.66,57.28
  TOP w0.127: 197.66,57.28 197.66,59.53 arc(197.7,59.73) 197.82,59.9 C1118.2
N18849311: length 0.7
  TOP w0.127: U101.K18 v1(182.52,49.01)
N18850569: length 0.7
  TOP w0.127: U101.H3 v1(198.52,46.01)
N18882897: length 1.7
  TOP w0.127: U101.A10 v1(190.52,39.01)
  BOTTOM w0.127: R901.2 190.51,39.01 v1(190.52,39.01)
N19017659: length 29.9
  TOP w1.016: J50.12 185.4,19.31 J50.6 186.42,17.38 187.31,16.48 195.6,16.48 196.62,17.5 J50.1 197.64,19.31 J50.7 197.64,22.35 J50.13
  BOTTOM w0.508: J50.6 186.41,18.28 C1202.2 ; C1201.2 196.62,18.28 J50.1 ; C1198.2 196.62,23.36 J50.13 ; C1204.2 185.39,20.82 J50.12 ; J50.7 197.64,20.82 C1199.2
N19034153: length 5.7
  BOTTOM w0.127: J50.16 199.03,7.88 C1200.1 R902.1
N19034169: length 18.7
  BOTTOM w0.508: FB59.1 191.82,7.88 C1197.1 190.75,6.86 ; J50.17 192.28,5.34 190.75,6.86 ; 190.75,6.86 189.23,5.34 J50.19
N19034241: length 5.7
  BOTTOM w0.127: J50.18 184,7.88 C1203.1 R903.1
N19126530: length 1.9
  TOP w0.127: SW3.12 v1(103.25,144.02)
  BOTTOM w0.127: R505.1 v1(103.25,144.02)
N19163046: length 1.8
  TOP w0.127: R495.1 52.2,112.81 X2.3
N19163064: length 1.8
  TOP w0.127: R494.2 50.43,110.37 X2.1
N19623883: length 4.7
  TOP w0.254: R783.2 201.94,131.7 C996.2 ; C996.2 203.82,131.69 Q32.3 ; C996.2 R784.2
N19623885: length 2.6
  TOP w0.127: R786.2 202.95,128.53 R785.2 202.95,129.47 Q32.1
N19623968: length 2.8
  TOP w0.254: Q31.4 204.22,133.99 R783.1
N19644915: length 22
  TOP w0.508: v1(217.3,131.44) 217.51,131.66 C927.2 ; R735.1 223.4,135.52 v1(223.39,135.51) R731.2
  L3SIG w0.508: v1(223.39,135.51) 217.93,135.51 216.79,136.65 v1(214.25,136.65)
  BOTTOM w0.508: v1(214.25,136.65) 213.49,136.65 212.85,136.02 212.85,132.84 214.25,131.44 v1(217.3,131.44)
N19644936: length 2.3
  TOP w0.254: C943.2 223.64,137.54 C941.2 224.16,137.04 R735.2
N19644956: length 3.7
  TOP w0.254: R736.1 C943.1 221.37,137.29 v1(220.85,137.29) 220.73,137.41 U87.5
  BOTTOM w0.254: v1(220.85,137.29) 220.72,137.15 R745.2
N19644972: length 1.6
  TOP w0.127: R739.2 221.5,136.41 U87.3
N19644986: length 3.3
  TOP w0.127: U87.16 219.2,134.49 219.58,134.11 220.09,134.11 220.47,133.73 R734.2 C932.2
N19645019: length 10.5
  TOP w0.254: R741.1 v1(223.39,134.49) ; U87.8 219.2,139.44 v1(219.46,139.7)
  BOTTOM w0.508: v1(223.39,134.49) 222.63,134.49 221.87,135.25 221.87,138.43 220.6,139.7 v1(219.46,139.7) 219.19,139.44 C946.1
N19645035: length 3
  TOP w0.254: R741.2 220.6,134.49 v1(220.34,134.75) 220.05,135.04 U87.1
  BOTTOM w0.254: v1(220.34,134.75) 220.72,135.12 R743.2
N19645080: length 2.2
  TOP w0.254: v1(220.85,138.05) 220.71,137.91 U87.6
  BOTTOM w0.254: v1(220.85,138.05) 220.48,138.42 C947.1
N19645160: length 1.7
  TOP w0.254: R728.2 218.7,134.22 U87.15
N19645192: length 1.7
  TOP w0.254: C927.1 218.2,133.28 U87.14
N19645200: length 1.7
  TOP w0.254: R731.1 221.11,135.51 220.71,135.91 U87.2
N19646811: length 22
  TOP w0.508: v1(24.13,106.81) 23.91,106.59 C949.2 ; R755.1 18.03,102.74 v1(18.03,102.74) R749.2
  L3SIG w0.508: v1(18.03,102.74) 23.49,102.74 24.64,101.6 v1(27.18,101.6)
  BOTTOM w0.508: v1(24.13,106.81) 27.18,106.81 28.58,105.41 28.58,102.23 27.94,101.6 v1(27.18,101.6)
N19646830: length 2.3
  TOP w0.254: C967.2 17.79,100.71 C965.2 17.27,101.21 R755.2
N19646848: length 3.7
  TOP w0.254: U89.5 20.69,100.85 v1(20.57,100.97) 20.06,100.97 C967.1 R757.1
  BOTTOM w0.254: v1(20.57,100.97) 20.71,101.1 R763.2
N19646866: length 1.7
  TOP w0.254: R749.1 20.32,102.74 20.72,102.35 U89.2
N19646870: length 1.6
  TOP w0.127: U89.3 19.92,101.85 R756.2
N19646891: length 3.3
  TOP w0.127: C957.2 R754.2 20.95,104.52 21.34,104.14 21.84,104.14 22.23,103.76 U89.16
N19646930: length 10.5
  TOP w0.254: v1(21.97,98.55) 22.23,98.81 U89.8 ; R759.1 v1(18.03,103.76)
  BOTTOM w0.508: C970.1 22.23,98.81 v1(21.97,98.55) 20.83,98.55 19.56,99.82 19.56,103 18.8,103.76 v1(18.03,103.76)
N19646940: length 3
  TOP w0.254: R759.2 20.83,103.76 v1(21.08,103.51) 21.38,103.21 U89.1
  BOTTOM w0.254: R761.2 20.71,103.13 v1(21.08,103.51)
N19646995: length 2.2
  TOP w0.254: v1(20.57,100.2) 20.72,100.35 U89.6
  BOTTOM w0.254: v1(20.57,100.2) 20.95,99.83 C971.1
N19647070: length 1.7
  TOP w0.254: U89.15 22.73,104.03 R747.2
N19647102: length 1.7
  TOP w0.254: U89.14 23.23,104.98 C949.1
N19648273: length 22.2
  TOP w0.508: R775.1 18.03,91.94 v1(18.03,91.95) R767.2 ; v1(24.13,96.01) 23.91,95.8 C978.2
  L3SIG w0.508: v1(18.03,91.95) 23.49,91.95 24.64,90.81 v1(27.18,90.81)
  BOTTOM w0.508: v1(24.13,96.01) 27.56,96.01 28.58,95 28.58,91.44 27.94,90.81 v1(27.18,90.81)
N19648275: length 2.3
  TOP w0.254: C991.2 17.79,89.92 C989.2 17.27,90.42 R775.2
N19648310: length 3.7
  TOP w0.254: U90.5 20.69,90.05 v1(20.57,90.17) 20.06,90.17 C991.1 R772.1
  BOTTOM w0.254: v1(20.57,90.17) 20.71,90.3 R781.2
N19648328: length 1.7
  TOP w0.254: U90.2 20.72,91.55 20.32,91.95 R767.1
N19648366: length 3.3
  TOP w0.127: C981.2 R770.2 20.95,93.73 21.34,93.34 21.84,93.34 22.23,92.96 U90.16
N19648414: length 10.5
  TOP w0.254: R777.1 v1(18.03,92.96) ; v1(21.97,87.76) 22.23,88.01 U90.8
  BOTTOM w0.508: C994.1 22.23,88.02 v1(21.97,87.76) 20.83,87.76 19.69,88.9 19.69,92.08 18.8,92.96 v1(18.03,92.96)
N19648420: length 3
  TOP w0.254: R777.2 20.83,92.96 v1(21.08,92.71) 21.38,92.42 U90.1
  BOTTOM w0.254: R779.2 20.71,92.34 v1(21.08,92.71)
N19648465: length 2.2
  TOP w0.254: U90.6 20.72,89.55 v1(20.57,89.41)
  BOTTOM w0.254: C995.1 20.95,89.03 v1(20.57,89.41)
N19648544: length 1.7
  TOP w0.254: U90.15 22.73,93.23 R765.2
N19648572: length 1.7
  TOP w0.254: C978.1 23.23,94.18 U90.14
N19650144: length 22.1
  TOP w0.508: R769.1 55.49,81.78 v1(55.5,81.79) R766.2 ; C972.2 61.38,85.64 v1(61.59,85.85)
  L6SIG w0.508: v1(64.64,80.65) 62.23,80.65 60.96,81.92 55.63,81.92 v1(55.5,81.79)
  BOTTOM w0.508: v1(61.59,85.85) 64.64,85.85 66.04,84.45 66.04,81.28 65.41,80.65 v1(64.64,80.65)
N19650163: length 2.3
  TOP w0.254: R769.2 54.74,80.26 C988.2 55.25,79.76 C990.2
N19650181: length 3.7
  TOP w0.254: R774.1 C990.1 57.52,80.01 v1(58.04,80.01) 58.16,79.89 U91.5
  BOTTOM w0.254: v1(58.04,80.01) 58.17,80.14 R780.2
N19650199: length 1.7
  TOP w0.254: U91.2 58.18,81.39 57.78,81.79 R766.1
N19650212: length 1.6
  TOP w0.127: U91.3 57.39,80.89 R773.2
N19650233: length 3.3
  TOP w0.127: C977.2 R768.2 58.42,83.57 58.8,83.19 59.31,83.19 59.69,82.8 U91.16
N19650272: length 10.5
  TOP w0.254: R776.1 v1(55.5,82.8) ; U91.8 59.69,77.85 v1(59.44,77.6)
  BOTTOM w0.508: v1(55.5,82.8) 56.26,82.8 57.02,82.04 57.02,78.87 58.29,77.6 v1(59.44,77.6) 59.7,77.86 C992.1
N19650282: length 3
  TOP w0.254: U91.1 58.84,82.26 v1(58.55,82.55) 58.29,82.8 R776.2
  BOTTOM w0.254: R778.2 58.17,82.18 v1(58.55,82.55)
N19650331: length 2.2
  TOP w0.254: U91.6 58.18,79.39 v1(58.04,79.25)
  BOTTOM w0.254: v1(58.04,79.25) 58.41,78.87 C993.1
N19650402: length 1.7
  TOP w0.254: R764.2 60.19,83.07 U91.15
N19650430: length 1.7
  TOP w0.254: C972.1 60.69,84.02 U91.14
N19651609: length 22
  TOP w0.508: R751.1 18.03,113.53 v1(18.03,113.54) R748.2 ; C948.2 23.91,117.39 v1(24.13,117.6)
  L3SIG w0.508: v1(27.18,112.4) 24.64,112.4 23.49,113.54 v1(18.03,113.54)
  BOTTOM w0.508: v1(24.13,117.6) 27.18,117.6 28.58,116.2 28.58,113.03 27.94,112.4 v1(27.18,112.4)
N19651628: length 2.3
  TOP w0.254: R751.2 17.27,112.01 C964.2 17.79,111.51 C966.2
N19651646: length 3.7
  TOP w0.254: U88.5 20.69,111.64 v1(20.57,111.76) 20.06,111.76 C966.1 R753.1
  BOTTOM w0.254: R762.2 20.71,111.89 v1(20.57,111.76)
N19651664: length 1.7
  TOP w0.254: U88.2 20.72,113.14 20.32,113.54 R748.1
N19651683: length 1.6
  TOP w0.127: U88.3 19.92,112.64 R752.2
N19651731: length 10.5
  TOP w0.254: R758.1 v1(18.03,114.55) ; v1(21.97,109.35) 22.23,109.6 U88.8
  BOTTOM w0.508: v1(18.03,114.55) 18.8,114.55 19.56,113.79 19.56,110.62 20.83,109.35 v1(21.97,109.35) 22.23,109.61 C968.1
N19651747: length 3
  TOP w0.254: U88.1 21.38,114.01 v1(21.08,114.3) 20.83,114.55 R758.2
  BOTTOM w0.254: R760.2 20.71,113.93 v1(21.08,114.3)
N19651788: length 2.2
  TOP w0.254: v1(20.57,111) 20.72,111.14 U88.6
  BOTTOM w0.254: v1(20.57,111) 20.95,110.62 C969.1
N19651863: length 1.7
  TOP w0.254: U88.15 22.73,114.82 R746.2
N19651895: length 1.7
  TOP w0.254: U88.14 23.23,115.77 C948.1
N19653096: length 22
  TOP w0.508: R729.2 v1(203.07,76.84) 203.08,76.84 R733.1 ; C924.2 197.19,72.99 v1(196.98,72.77)
  L3SIG w0.508: v1(193.93,77.98) 196.47,77.98 197.61,76.84 v1(203.07,76.84)
  BOTTOM w0.508: v1(193.93,77.98) 193.17,77.98 192.53,77.34 192.53,74.17 193.93,72.77 v1(196.98,72.77)
N19653107: length 2.3
  TOP w0.254: R733.2 203.83,78.37 C935.2 203.32,78.87 C942.2
N19653133: length 3.7
  TOP w0.254: U86.5 200.41,78.73 v1(200.53,78.61) 201.05,78.61 C942.1 R738.1
  BOTTOM w0.254: R744.2 200.4,78.48 v1(200.53,78.61)
N19653151: length 1.7
  TOP w0.254: R729.1 200.79,76.84 200.39,77.23 U86.2
N19653170: length 1.6
  TOP w0.127: U86.3 201.18,77.73 R737.2
N19653218: length 10.5
  TOP w0.254: U86.8 198.88,80.77 v1(199.14,81.03) ; R740.1 v1(203.07,75.82)
  BOTTOM w0.508: v1(203.07,75.82) 202.31,75.82 201.55,76.58 201.55,79.76 200.28,81.03 v1(199.14,81.03) 198.87,80.76 C944.1
N19653234: length 3
  TOP w0.254: R740.2 200.28,75.82 v1(200.02,76.07) 199.73,76.37 U86.1
  BOTTOM w0.254: R742.2 200.4,76.45 v1(200.02,76.07)
N19653275: length 2.2
  TOP w0.254: v1(200.53,79.38) 200.39,79.23 U86.6
  BOTTOM w0.254: C945.1 200.16,79.75 v1(200.53,79.38)
N19653350: length 1.7
  TOP w0.254: R730.2 198.38,75.55 U86.15
N19653382: length 1.7
  TOP w0.254: C924.1 197.88,74.6 U86.14
N20366563: length 2.8
  TOP w0.254: R807.2 R806.1 204.14,126.31 U95.6
N20516568: length 44.5
  TOP w0.127: U1.E6 v2(158.12,106.85)
  L3SIG w0.102: v1(127,85.85) 134.37,93.22 148.72,93.22 152.78,97.28 155.19,97.28 156.21,98.3 156.21,104.78 157.1,105.66 157.48,105.66 157.73,105.92 157.73,106.46 v2(158.12,106.85)
N20553507: length 7.4
  BOTTOM w0.127: R831.2 150.37,127.52 R830.2 151.69,127.51 Q38.1 151.83,127.57 152.78,128.52 152.78,130.94 152.46,131.26 Q37.1
N20559490: length 3.2
  TOP w0.127: R820.2 R821.2 41.98,134.18 Q35.1
N20559492: length 9.1
  TOP w0.127: Q35.3 43.81,136.79 44.7,135.89 44.7,134.11 44.95,133.87 R816.2 ; Q36.1 46.93,134.94 45.85,133.87 R816.2 ; R816.2 45.35,133.86 C1023.2 R818.2
N20559589: length 13
  TOP w0.127: R816.1 45.34,136.14 43.5,137.98 43.5,139.57 ; 43.5,139.57 41.4,139.57 40.58,138.75 Q44.1 ; 43.5,139.57 43.5,141.42 44.77,142.69 Q33.1
N20559634: length 3.4
  TOP w1.016: Q44.3 41.53,142.25 Q33.3
N20559669: length 5.9
  TOP w0.127: Q36.3 47.88,134.37 R817.1 C1024.1 48.38,132.83 R819.1
N20559724: length 15.1
  TOP w0.127: Q45.1 44.26,139.26 44.96,139.95 49.28,139.95 ; Q34.1 49.28,139.95 ; 49.28,139.95 49.28,137.79 49.66,137.41 49.66,134.12 R817.2
N20562248: length 29.3
  TOP w0.127: U1.Y15 v2(170.92,114.85)
  L3SIG w0.102: v2(170.92,114.85) 171.33,115.26 171.91,115.26 172.1,115.45 172.1,115.84 172.33,116.06 180.07,116.06 184.28,120.27 196.85,120.27 v1(197.1,120.52)
N20562257: length 29.3
  TOP w0.127: U1.AB15 v2(172.52,114.85)
  L3SIG w0.102: v2(172.52,114.85) 172.9,115.23 179.74,115.23 184.4,119.89 198.25,119.89 v1(198.88,120.52)
N20562271: length 29.2
  TOP w0.127: U1.Y19 v2(170.92,118.05)
  L3SIG w0.102: v1(197.1,122.94) 196.98,122.81 182.37,122.81 178.82,119.25 172.34,119.25 172.1,119.01 172.1,118.38 171.77,118.05 v2(170.92,118.05)
N20562273: length 29
  TOP w0.127: U1.AB19 v2(172.52,118.05)
  L3SIG w0.102: v2(172.52,118.05) 172.93,118.46 175.11,118.46 175.51,118.87 178.94,118.87 182.5,122.43 198.5,122.43 198.88,122.81 v1(198.88,122.94)
N20562350: length 1
  BOTTOM w0.127: R814.2 153.8,100.33 C1022.2
N21754633: length 11.9
  TOP w0.127: J43.28 267.44,149.84 266.95,149.35 266.95,145.29 270.51,141.73 R867.1
N21754692: length 12.8
  TOP w0.127: R868.1 274.57,144.53 271.8,147.3 J43.36
N21754708: length 11.1
  TOP w0.127: J43.38 270.79,146.66 271.27,146.18 271.27,143.13 273.56,140.84 R869.1
N22257590: length 2.2
  BOTTOM w0.127: R14.1 124.16,121.5 U2.2
N22257592: length 2
  BOTTOM w0.127: R15.1 123.64,122 U2.3
N22257594: length 2
  BOTTOM w0.127: R16.1 123.62,123 U2.5
N22258098: length 2.1
  BOTTOM w0.127: U2.8 123.85,124.5 R20.1
N22258100: length 4.1
  BOTTOM w0.127: U2.9 124.23,125 124.08,124.84 R22.1
N22258102: length 2.2
  BOTTOM w0.127: U2.11 124.08,126 R24.1
N22258104: length 4.2
  BOTTOM w0.127: R26.1 123.84,126.11 124.22,126.5 U2.12
N22258216: length 4.1
  BOTTOM w0.127: R18.1 124.08,123.57 124.15,123.5 U2.6
N22258634: length 2.1
  BOTTOM w0.127: U2.13 123.81,127 R28.1
N22258636: length 2.1
  BOTTOM w0.127: R30.1 123.83,127.5 U2.14
N22258638: length 2.1
  BOTTOM w0.127: R32.1 123.85,128.5 U2.16
N22360230: length 4.5
  TOP w1.016: J33.2 222.23,245.26 F9.2
N22360382: length 4.5
  TOP w1.016: F11.2 247.63,245.26 J44.2
N22360534: length 4.5
  TOP w1.016: R862.2 234.93,245.26 J45.2
N22361017: length 4.5
  TOP w1.016: J46.2 260.33,245.26 F13.2
N22361656: length 3.6
  TOP w0.127: R702.2 29.08,10.03 D43.1
N22361689: length 3.6
  TOP w0.127: D44.1 24.76,6.4 R699.2
N22440478: length 3.8
  TOP w1.016: Q34.3 46.98,142.11 45.73,140.85 Q45.3
N23085337: length 134.4
  TOP w0.508: v1(100.77,91.63) 101.85,90.55 C1116.1 103.26,90.47 R883.1
  L6SIG w0.508: J49.1 86.15,148.51 83.69,146.05 67.82,146.05 67.18,145.41 67.18,140.08 68.58,138.68 68.58,125.73 v1(66.04,123.19)
  BOTTOM w0.508: v1(100.77,91.63) 94.56,85.42 83.36,85.42 80.85,87.93 62.56,87.93 55.63,94.87 55.63,115.57 63.25,123.19 v1(66.04,123.19)
N23085351: length 4.1
  TOP w0.305: U100.3 103.69,86.29 104.26,86.86 R883.2
N23085389: length 4.8
  TOP w0.127: Y6.1 99.88,88.21 101.15,86.94 U100.2
N23085395: length 3.6
  TOP w0.127: U100.1 101.39,87.59 100.78,88.2 Y6.4
N23146172: length 1.9
  TOP w0.102: U97.14 239.69,136.31 239.75,136.37 240.32,136.37 R520.1
N23146174: length 1.9
  TOP w0.102: R521.1 240.29,136.65 239.75,136.65 239.69,136.71 U97.15
N23146290: length 5.9
  TOP w0.127: U97.2 235.2,133.85 234.94,133.6 C733.1 234.95,132.59 235.46,132.08 235.46,130.43 Y4.1
N23146296: length 4
  TOP w0.127: Y4.3 235.97,131.61 C734.1 235.33,133.23 235.33,133.6 235.6,133.87 U97.3
N23146369: length 1.9
  TOP w0.102: U97.22 238,139.95 237.95,140 237.95,140.67 R525.1
N23146371: length 2
  TOP w0.102: R526.1 237.67,140.55 237.67,140 237.6,139.94 U97.23
N23146377: length 1.9
  TOP w0.102: U97.28 235.6,139.94 235.53,140.01 235.53,140.67 R530.1
N23146379: length 1.9
  TOP w0.102: U97.29 235.2,139.95 235.25,140 235.25,140.55 R532.1
N23146385: length 2.1
  TOP w0.102: U97.33 233.2,137.91 232.4,138.71 R536.1
N23146387: length 2.3
  TOP w0.102: U97.34 233.21,137.51 232.71,138 232.53,138 232.4,137.88 R537.1
N23146565: length 2.3
  TOP w0.102: U97.37 233.46,136.31 232.4,135.25 R837.1
N23146571: length 2
  TOP w0.102: R836.1 232.64,136.16 232.92,136.16 233.47,136.71 U97.36
N23146840: length 4
  TOP w0.127: U97.1 234.35,134.41 232.92,132.97 R829.2 R842.2
N23147063: length 2.5
  TOP w0.127: R834.2 238.13,132.58 236.8,133.91 U97.6
N23147551: length 3.3
  TOP w0.127: R175.1 C132.1 88.21,90.55 X1.3
N23148282: length 8.1
  TOP w0.127: Y5.1 153.76,59.6 152.91,60.45 152.91,62.36 153.42,62.86 C739.1 153.54,62.98 153.54,65.02 154.08,65.56 U68.13
N23148288: length 5
  TOP w0.127: U68.12 156.2,64.91 156.58,64.52 C738.1 156.58,61.72 Y5.3
N23178619: length 1.5
  TOP w0.127: U1.AB1 v2(172.52,102.85)
  BOTTOM w0.127: v2(172.52,102.85) 172.08,102.41 R875.2
N23180170: length 6.6
  TOP w0.127: U1.AD5 v2(174.12,106.05)
  BOTTOM w0.127: R881.2 172.11,103.14 172.11,105.43 172.31,105.64 173.71,105.64 174.12,106.04 v2(174.12,106.05)
N23238405: length 4.7
  TOP w0.127: C1119.1 R898.1 176.27,45.09 Y7.1
N23238411: length 6.7
  TOP w0.127: Y7.3 177.04,43.81 C1120.1 178.44,44.08 178.87,44.51 U101.F18
N23238429: length 3.7
  TOP w0.127: R898.2 182.6,45.09 U101.G18
N23238970: length 0.7
  TOP w0.127: U101.N17 v1(183.52,52.01)
N23239280: length 0.7
  TOP w0.127: U101.J15 v1(185.52,47.01)
N23239284: length 0.7
  TOP w0.127: U101.G17 v1(183.52,45.01)
N23239286: length 0.7
  TOP w0.127: U101.H16 v1(184.52,46.01)
N23239292: length 0.7
  TOP w0.127: U101.J16 v1(184.52,47.01)
N23239393: length 0.7
  TOP w0.127: U101.K15 v1(185.52,49.01)
N23240310: length 1.7
  TOP w0.127: U101.J4 v1(197.52,47.01)
  BOTTOM w0.127: R895.2 R896.2
N23240770: length 0.7
  TOP w0.127: U101.F17 v1(183.52,44.01)
N23240781: length 0.7
  TOP w0.127: U101.G13 v1(187.52,45.01)
N23327185: length 0.7
  TOP w0.127: U101.F5 v1(196.52,44.01)
N23371818: length 9.4
  TOP w0.127: U1.D1 157.72,103.23 156.21,101.73 154.43,101.73 154.3,101.85 v1(150.75,101.85)
  BOTTOM w0.127: R882.1 R876.1 v1(150.75,101.85)
N23371833: length 4.9
  TOP w0.127: U1.D4 v2(157.32,105.25)
  BOTTOM w0.127: v2(157.32,105.25) 157.06,105.25 155.96,104.14 154.55,104.14 R877.1
N23371894: length 4.8
  TOP w0.127: U1.D5 v2(157.32,106.05)
  BOTTOM w0.127: v2(157.32,106.05) 155.79,104.52 154.39,104.52 154.26,104.39 R878.1
N23373428: length 6.6
  TOP w0.127: U1.E9 v2(158.12,109.25)
  BOTTOM w0.127: R879.1 155.52,106.43 156.34,107.24 156.68,107.24 156.91,107.47 156.91,107.9 157.06,108.05 157.48,108.05 157.71,108.28 157.71,108.84 158.11,109.25 v2(158.12,109.25)
N23374222: length 15.7
  TOP w0.127: U1.F8 v2(158.92,108.45)
  BOTTOM w0.127: R880.1 154.43,114.43 154.81,114.05 159.58,114.05 160.11,113.51 160.11,108.99 159.96,108.84 159.31,108.84 v2(158.92,108.45)
N23395649: length 22
  TOP w0.508: R922.2 v1(211.58,66.67) 211.57,66.68 R926.1 ; v1(215.65,60.57) 215.43,60.79 C1224.2
  L3SIG w0.508: v1(211.58,66.67) 211.58,61.21 210.44,60.06 v1(210.44,57.52)
  BOTTOM w0.508: v1(215.65,60.57) 215.65,57.52 214.25,56.13 211.07,56.13 210.44,56.76 v1(210.44,57.52)
N23395651: length 2.3
  TOP w0.254: C1244.2 209.55,66.91 C1239.2 210.05,67.43 R926.2
N23395686: length 3.7
  TOP w0.254: U105.5 209.68,64.01 v1(209.8,64.13) 209.8,64.64 C1244.1 R930.1
  BOTTOM w0.254: R937.2 209.94,63.99 v1(209.8,64.13)
N23395694: length 1.7
  TOP w0.254: R922.1 211.58,64.38 211.18,63.98 U105.2
N23395911: length 1.7
  TOP w0.254: U105.14 213.81,61.48 C1224.1
N23398740: length 1.6
  TOP w0.127: U105.3 210.69,64.78 R931.2
N23398788: length 10.5
  TOP w0.254: U105.8 207.65,62.48 v1(207.39,62.73) ; R933.1 v1(212.6,66.67)
  BOTTOM w0.508: v1(212.6,66.67) 212.6,65.91 211.84,65.14 208.66,65.14 207.39,63.87 v1(207.39,62.73) 207.65,62.47 C1246.1
N23398805: length 3
  TOP w0.254: R933.2 212.6,63.87 v1(212.34,63.62) 212.05,63.33 U105.1
  BOTTOM w0.254: R935.2 211.97,63.99 v1(212.34,63.62)
N23398854: length 2.2
  TOP w0.254: U105.6 209.19,63.98 v1(209.04,64.13)
  BOTTOM w0.254: v1(209.04,64.13) 208.67,63.75 C1247.1
N23398896: length 1.7
  TOP w0.254: U105.15 212.87,61.98 R923.2
N23399971: length 22
  TOP w0.508: v1(268.61,60.58) 268.39,60.79 C1225.2 ; R924.2 v1(264.54,66.68) 264.53,66.68 R928.1
  L3SIG w0.508: 263.4,57.52 v1(263.4,57.53) 263.4,60.06 264.54,61.21 v1(264.54,66.68)
  BOTTOM w0.508: v1(263.4,57.53) 263.4,56.77 264.03,56.13 267.21,56.13 268.61,57.53 v1(268.61,60.58)
N23399992: length 2.3
  TOP w0.254: R928.2 263.01,67.44 C1243.2 262.51,66.92 C1245.2
N23400010: length 3.7
  TOP w0.254: R929.1 C1245.1 262.76,64.65 v1(262.76,64.14) 262.64,64.02 U106.5
  BOTTOM w0.254: R938.2 262.9,64 v1(262.76,64.14)
N23400026: length 1.7
  TOP w0.254: R924.1 264.54,64.39 264.14,63.99 U106.2
N23400036: length 1.6
  TOP w0.127: U106.3 263.64,64.79 R932.2
N23400099: length 10.5
  TOP w0.254: v1(260.35,62.74) 260.61,62.48 U106.8 ; R934.1 v1(265.56,66.68)
  BOTTOM w0.508: v1(265.56,66.68) 265.56,65.91 264.8,65.15 261.62,65.15 260.35,63.88 v1(260.35,62.74) 260.61,62.48 C1250.1
N23400105: length 3
  TOP w0.254: U106.1 265.01,63.33 v1(265.3,63.63) 265.56,63.88 R934.2
  BOTTOM w0.254: R936.2 264.93,64 v1(265.3,63.63)
N23400150: length 2.2
  TOP w0.254: v1(262,64.14) 262.14,63.99 U106.6
  BOTTOM w0.254: v1(262,64.14) 261.63,63.76 C1251.1
N23400230: length 1.7
  TOP w0.254: U106.15 265.83,61.98 R921.2
N23400248: length 1.7
  TOP w0.254: U106.14 266.77,61.48 C1225.1
N23495851: length 2.6
  BOTTOM w0.127: R949.2 102.36,145.3 R948.2 103.69,145.29 Q49.1
N23495853: length 3.6
  BOTTOM w0.127: R946.2 107.57,147.2 C1273.2 107.57,147.19 R947.2 107.07,146.17 106.81,146.43 Q49.3
N23495929: length 1.7
  BOTTOM w0.127: Q48.1 R946.1
N23503182: length 15.6
  TOP w0.127: U101.H17 184.01,46.51 183.51,47.01 180.96,47.01 178.82,49.15 R942.1 176.66,56.27 J52.3
N23503185: length 11.1
  TOP w0.127: U101.H18 180.82,46.51 R941.1 178.3,52.08 J52.2
N23535138: length 2.9
  TOP w0.127: R951.2 101.34,32.38 U37.3
N23647021: length 1.5
  BOTTOM w0.127: Q50.1 35.99,36.83 R954.2
N23886478: length 5.5
  TOP w0.102: U108.V4 247.75,56.44 247.75,56.01 247.85,55.91 248.06,55.91 248.23,56.08 248.23,57.17 248.26,57.2 248.26,57.28
  TOP w0.127: 248.26,57.28 248.26,59.95 248.13,60.08 C1285.2
N23886479: length 5.1
  TOP w0.102: 248.62,57.28 248.62,57.27 248.44,57.09 248.44,56 248.21,55.77 248.21,55.76 247.96,55.51 U108.U4
  TOP w0.127: 248.62,57.28 248.62,59.9 C1286.2
N23886494: length 0.7
  TOP w0.127: U108.K18 v1(233.32,49.01)
N23886496: length 0.7
  TOP w0.127: U108.H3 v1(249.32,46.01)
N23886499: length 1.7
  TOP w0.127: U108.A10 v1(241.32,39.01)
  BOTTOM w0.127: v1(241.32,39.01) 241.31,39.01 R974.2
N23886523: length 4.7
  TOP w0.127: C1287.1 R971.1 227.07,45.09 Y8.1
N23886526: length 6.7
  TOP w0.127: Y8.3 227.84,43.81 C1288.1 229.24,44.08 229.67,44.51 U108.F18
N23886535: length 3.7
  TOP w0.127: U108.G18 233.4,45.09 R971.2
N23886543: length 0.7
  TOP w0.127: U108.N17 v1(234.32,52.01)
N23886546: length 0.7
  TOP w0.127: U108.J15 v1(236.32,47.01)
N23886548: length 0.7
  TOP w0.127: U108.G17 v1(234.32,45.01)
N23886549: length 0.7
  TOP w0.127: U108.H16 v1(235.32,46.01)
N23886551: length 0.7
  TOP w0.127: U108.J16 v1(235.32,47.01)
N23886557: length 0.7
  TOP w0.127: U108.K15 v1(236.32,49.01)
N23886561: length 1.7
  TOP w0.127: U108.J4 v1(248.32,47.01)
  BOTTOM w0.127: R968.2 R969.2
N23886562: length 0.7
  TOP w0.127: U108.F17 v1(234.32,44.01)
N23886563: length 0.7
  TOP w0.127: U108.G13 v1(238.32,45.01)
N23886575: length 0.7
  TOP w0.127: U108.F5 v1(247.32,44.01)
N23886602: length 15.6
  TOP w0.127: U108.H17 234.81,46.51 234.31,47.01 231.76,47.01 229.62,49.15 R965.1 227.46,56.27 J54.3
N23886603: length 11.1
  TOP w0.127: U108.H18 231.62,46.51 R966.1 229.1,52.08 J54.2
N23890340: length 29.9
  TOP w1.016: J56.13 248.44,22.35 J56.7 248.44,19.31 J56.1 247.42,17.5 246.4,16.48 238.11,16.48 237.22,17.38 J56.6 236.2,19.31 J56.12
  BOTTOM w0.508: J56.13 247.42,23.36 C1366.2 ; C1372.2 237.21,18.28 J56.6 ; C1370.2 236.19,20.82 J56.12 ; J56.1 247.42,18.28 C1367.2 ; J56.7 248.44,20.82 C1369.2
N23890653: length 5.7
  BOTTOM w0.127: J56.16 249.83,7.88 C1368.1 R977.1
N23890655: length 18.7
  BOTTOM w0.508: 241.55,6.86 C1365.1 242.62,7.88 FB67.1 ; 241.55,6.86 243.08,5.34 J56.17 ; 241.55,6.86 240.03,5.34 J56.19
N23890663: length 5.7
  BOTTOM w0.127: J56.18 234.8,7.88 C1371.1 R978.1
N23926306: length 2.1
  TOP w0.254: v1(131.83,110.11) 131.57,110.37 R912.2
  BOTTOM w0.508: Q46.4 v1(131.83,110.11)
N23926329: length 5.3
  TOP w0.254: R912.1 131.56,112.4 Q47.3 129.29,113.28 C1222.1 R916.1
N23926341: length 2.6
  TOP w0.127: R919.2 R920.2 126.94,113.34 Q47.1
N23927707: length 4
  TOP w0.127: R981.2 116.83,95 118.16,95 118.42,95.25 R980.2
N23927714: length 4
  TOP w0.127: R982.2 116.83,94.49 118.16,94.49 118.42,94.23 R980.3
N23928633: length 2.6
  TOP w0.127: U111.2 v1(108.84,96.13)
  BOTTOM w0.127: v1(108.84,96.13) 108.97,96.26 110.11,96.26 R983.2
N23928636: length 2.9
  TOP w0.127: U111.1 108.57,96.63 v1(108.84,96.9)
  BOTTOM w0.127: v1(108.84,96.9) 109.22,97.28 R984.2
N23929117: length 3.8
  TOP w0.254: U111.8 111,95.63 110.23,96.4 R985.1
N23965067: length 22.9
  TOP w0.127: U1.AG17 176.32,116.25 arc(176.52,116.38) 176.76,116.43 178.39,116.43 arc(178.43,116.43) 178.47,116.42 181.05,115.97 181.05,115.97 arc(181.54,115.92) 182.03,115.97 182.69,116.08 182.72,116.09 arc(185.56,116.33) 188.4,116.08 194.56,115 arc(194.99,114.87) 195.37,114.66 195.45,114.61 arc(195.77,114.43) 196.12,114.33 197.26,114.13 arc(197.44,114.11) 197.63,114.1 197.83,114.1 arc(198.03,114.14) 198.21,114.25 C1268.2
N23965070: length 22.7
  TOP w0.127: U1.AH17 176.94,116.07 178.17,116.07 arc(178.39,116.07) 178.61,116.04 179.14,115.94 arc(179.25,115.88) 179.3,115.76 179.3,115.74 arc(179.32,115.62) 179.43,115.55 179.6,115.52 arc(179.73,115.55) 179.8,115.66 arc(179.86,115.76) 179.99,115.79 180.16,115.76 arc(180.27,115.69) 180.3,115.57 180.3,115.57 arc(180.32,115.44) 180.43,115.37 180.6,115.34 arc(180.73,115.37) 180.8,115.48 180.8,115.48 arc(180.87,115.59) 180.99,115.62 arc(181.54,115.57) 182.09,115.62 182.75,115.73 182.76,115.73 arc(182.77,115.74) 182.79,115.74 arc(185.56,115.98) 188.34,115.73 194.5,114.65 arc(194.85,114.54) 195.17,114.37 195.25,114.31 arc(195.63,114.1) 196.06,113.98 197.19,113.78 arc(197.41,113.75) 197.63,113.74 197.85,113.74 arc(198.04,113.7) 198.2,113.6 C1267.2
N24071716: length 4
  TOP w0.508: J58.2 257.63,75.75 ; J58.2 256.21,75.75 ; J58.2 257.63,77.16 ; J58.2 256.21,77.16
N24071917: length 4
  TOP w0.508: J59.2 232.86,75.75 ; J59.2 231.45,75.75 ; J59.2 231.45,77.16 ; J59.2 232.86,77.16
N24117705: length 2.5
  TOP w0.127: R1015.1 240.8,138.65 240.67,138.78 240.38,138.78 239.51,137.91 U97.18
N24117707: length 2.2
  TOP w0.127: R1012.1 240.74,139.57 239.47,138.31 U97.19
N24120812: length 141
  TOP w0.102: v1(241.17,121.67) 241.43,121.41 246.38,121.41 252.34,115.46 256.54,115.46 R990.2 257.25,115.51 257.61,115.51 R1008.2 257.94,115.44 258.06,115.32 262.37,115.32 262.65,115.6 262.65,115.93 262.47,116.12 U113.3 ; C1382.2 157.08,73.93 161.43,73.93 176.53,89.03 176.53,92.46 182.02,97.94 187.22,97.94 189.23,99.95 189.23,106.05 190.25,107.06 191.55,107.06 v1(191.81,107.32)
  L3SIG w0.102: v1(241.17,121.67) 240.92,121.41 237.49,121.41 236.45,122.45 230.1,122.45 227.46,125.09 224.41,125.09 223.9,124.59 218.19,124.59 215.9,122.3 215.9,119.76 203.2,107.06 192.06,107.06 v1(191.81,107.32)
N24120822: length 4.7
  TOP w0.102: U113.5 261.17,117.53 261.35,117.72 261.35,118.37 R1004.2 261.24,119.01 261.24,119.5 R996.2 261.24,120.02 261.24,120.53 C1388.2
N24120824: length 4.7
  TOP w0.102: U113.4 261.82,117.53 261.63,117.72 261.63,118.37 R1006.2 261.75,119.01 261.75,119.5 R992.2 261.75,120.02 261.75,120.53 C1386.2
N24120892: length 141.1
  TOP w0.102: U113.2 263.12,116.05 262.93,115.87 262.93,115.49 262.48,115.04 258.17,115.04 R1010.2 257.61,115.13 257.25,115.13 R988.2 256.54,115.18 252.22,115.18 246.26,121.13 241.4,121.13 v1(241.17,120.9) ; C1384.2 157.08,73.65 161.55,73.65 176.81,88.91 176.81,92.34 182.13,97.66 187.34,97.66 189.51,99.83 189.51,105.93 190.36,106.78 191.58,106.78 v1(191.81,106.55)
  L3SIG w0.102: v1(241.17,120.9) 240.94,121.13 237.37,121.13 236.33,122.17 229.98,122.17 227.34,124.82 224.52,124.82 224.02,124.31 218.3,124.31 216.18,122.19 216.18,119.65 203.32,106.78 192.04,106.78 v1(191.81,106.55)
N24121080: length 2
  TOP w0.127: U113.12 261.17,109.28 R1000.1
N24121082: length 2
  TOP w0.127: R1002.1 260.52,109.25 U113.11
N24122901: length 7.4
  TOP w0.102: C1385.2 225.74,127.2 225.74,126.82 R991.2 225.74,126.17 225.74,125.8 R1009.2 225.65,125.24 225.65,124.73 225.95,124.43 227.09,124.43 227.43,124.1 228.27,124.1 228.45,123.91 U112.3
N24122903: length 96.5
  TOP w0.102: U112.5 228.48,122.61 228.3,122.8 227.98,122.8 227.08,121.89 226.8,121.89 R1005.2 226.12,121.85 225.75,121.85 R998.2 225.16,121.79 224.79,121.79 v1(224.66,121.67) ; v1(194.44,101.6) 194.21,101.83 193.41,101.83 187.82,96.24 183,96.24 178.59,91.83 178.59,88.28 165.89,75.58 165.89,72.53 162.43,69.08 161.14,69.08 C1389.2
  L3SIG w0.102: v1(224.66,121.67) 224.42,121.91 223.39,121.91 219.99,118.5 219.99,117.25 204.57,101.83 194.67,101.83 v1(194.44,101.6)
N24122905: length 96.5
  TOP w0.102: v1(224.66,122.43) 224.79,122.3 225.16,122.3 R994.2 225.75,122.24 226.12,122.24 R1007.2 226.44,122.56 226.82,122.17 226.96,122.17 227.86,123.08 228.3,123.08 228.48,123.26 U112.4 ; C1387.2 161.14,69.35 162.32,69.35 165.61,72.64 165.61,75.69 178.31,88.39 178.31,91.95 182.88,96.52 187.71,96.52 193.29,102.11 194.18,102.11 v1(194.44,102.36)
  L3SIG w0.102: v1(194.44,102.36) 194.69,102.11 204.46,102.11 219.71,117.36 219.71,118.62 223.28,122.19 224.42,122.19 v1(224.66,122.43)
N24122973: length 7.2
  TOP w0.102: C1383.2 226.12,127.2 226.12,126.82 R989.2 226.19,126.23 226.19,125.74 R1011.2 226.06,125.48 225.93,125.35 225.93,124.85 226.06,124.71 227.2,124.71 227.54,124.38 228.26,124.38 228.45,124.56 U112.2
N24123129: length 2.4
  TOP w0.127: R1001.1 236.73,122.17 236.29,122.61 U112.12
N24123131: length 2.5
  TOP w0.127: U112.11 236.44,121.96 R1003.1

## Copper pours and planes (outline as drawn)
0V85 on TOP (solid shape): 188.09,82.3 188.09,74.42 187.71,74.04 184.28,74.04 184.02,74.3 184.02,82.17 184.4,82.55 187.83,82.55
0V85 on BOTTOM (solid shape): 187.71,82.3 187.71,72.9 187.45,72.64 183.77,72.64 183.26,73.15 183.26,80.52 185.29,82.55 187.45,82.55
0V85 on BOTTOM (solid shape): 188.59,60.45 188.59,59.56 188.47,59.44 187.2,59.44 186.56,58.8 186.56,57.4 186.31,57.15 185.17,57.15 184.66,57.66 184.66,60.83 184.91,61.09 187.96,61.09
0V85 on BOTTOM (solid shape): 239.39,60.45 239.39,59.56 239.27,59.44 238,59.44 237.36,58.8 237.36,57.4 237.11,57.15 235.97,57.15 235.46,57.66 235.46,60.83 235.71,61.09 238.76,61.09
0V85 on BOTTOM (solid shape): 192.02,47.11 192.02,45 191.92,44.9 191.12,44.9 190.92,45.1 190.92,46.1 190.87,46.15 190.86,46.16 190.79,46.28 190.67,46.35 190.66,46.36 190.32,46.71 190.32,47.31 190.42,47.41 191.72,47.41
0V85 on BOTTOM (solid shape): 242.82,47.11 242.82,45 242.72,44.9 241.92,44.9 241.72,45.1 241.72,46.1 241.67,46.15 241.66,46.16 241.59,46.28 241.47,46.35 241.46,46.36 241.12,46.71 241.12,47.31 241.22,47.41 242.52,47.41
0V85 on L3SIG: 187.32,46.35 186.94,46.74 186.94,51.05 186.31,51.69 185.42,51.69 184.91,52.2 184.91,58.29 183.39,59.82 183.39,83.31 183.9,83.82 188.98,83.82 189.36,83.44 189.36,73.28 190.25,72.39 201.68,72.39 202.82,73.53 234.19,73.53 247.52,60.2 247.52,46.86 247.01,46.35 238.12,46.35 237.74,46.74 237.74,51.05 237.11,51.69 236.22,51.69 235.71,52.2 235.71,58.29 226.44,67.56 205.1,67.56 196.72,59.18 196.72,46.86 196.22,46.35
0V85_XGT1_VDDSRDS on BOTTOM (solid shape): 193.93,58.67 193.93,55.88 193.8,55.75 193.42,55.75 193.29,55.88 193.29,56.26 192.91,56.64 192.83,56.7 192.84,56.8 192.47,57.38 192.25,56.73 192.27,56.67 192.22,56.64 192.15,56.64 191.9,56.39 191.9,55.24 191.39,54.74 190.5,54.74 190.37,54.86 190.37,56.39 190.12,56.64 189.92,56.64 189.83,56.7 189.84,56.8 189.52,57.39 189.2,56.8 189.2,56.7 189.11,56.64 189.1,56.64 188.85,56.39 188.85,54.86 188.72,54.74 188.34,54.74 188.24,54.84 188.24,55.29 188.21,55.29 188.21,55.63 187.07,56.77 187.07,58.55 187.45,58.93 193.67,58.93
0V85_XGT1_VDDSRDS on L6SIG (solid shape): outline of 565 points within 187.96,53.47 197.1,55.63
0V85_XGT2_VDDSRDS on BOTTOM (solid shape): 244.73,58.67 244.73,55.88 244.6,55.75 244.22,55.75 244.09,55.88 244.09,56.26 243.71,56.64 243.63,56.7 243.64,56.8 243.27,57.38 243.05,56.73 243.07,56.67 243.02,56.64 242.95,56.64 242.7,56.39 242.7,55.24 242.19,54.74 241.3,54.74 241.17,54.86 241.17,56.39 240.92,56.64 240.72,56.64 240.63,56.7 240.64,56.8 240.32,57.39 240,56.8 240,56.7 239.91,56.64 239.9,56.64 239.65,56.39 239.65,54.86 239.52,54.74 239.14,54.74 239.04,54.84 239.04,55.29 239.01,55.29 239.01,55.63 237.87,56.77 237.87,58.55 238.25,58.93 244.47,58.93
0V85_XGT2_VDDSRDS on L6SIG (solid shape): outline of 565 points within 238.76,53.47 247.9,55.63
1V0_FA_VL on L3SIG: 159.89,116.97 160.02,116.84 160.02,116.2 159.77,115.95 158.37,115.95 158.24,116.08 158.24,116.84 158.37,116.97
1V0_USB_SVDD on L5PWR: 161.8,110.11 161.8,108.97 161.92,108.84 162.31,108.84 162.56,108.59 162.56,106.05 160.66,104.14 160.66,101.98 160.91,101.73 162.56,101.73 164.21,103.38 164.21,109.6 163.45,110.36 162.05,110.36
1V0S on TOP: 197.87,124.08 197.61,124.33 197.61,126.24 197.87,126.49 199.64,126.49 199.9,126.24 202.18,126.24 202.69,126.75 203.07,126.75 203.2,126.62 203.2,126.11 203.45,125.86 204.85,125.86 204.85,125.09 206.5,125.09 206.5,125.86 206.76,125.86 206.76,124.59 206.25,124.08
1V0S on BOTTOM: 197.61,126.11 197.61,124.59 197.74,124.46 199.77,124.46 199.9,124.59 199.9,126.11 199.77,126.24 197.74,126.24
1V2 on TOP (solid shape): 215.39,51.3 215.39,48.01 215,47.62 206.25,47.62 205.87,48 205.87,51.43 206.12,51.69 215.01,51.69
1V2 on BOTTOM (solid shape): 215.77,51.05 215.77,48.13 215.39,47.75 206.25,47.75 205.87,48.13 205.87,51.05 206.12,51.3 215.52,51.3
1V2 on BOTTOM (solid shape): 201.68,47.24 201.68,45.85 200.79,44.96 200.79,43.69 200.49,43.39 200.47,43.38 200.37,43.36 200.28,43.31 199.14,43.31 198.88,43.56 198.37,43.56 198.12,43.81 198.12,45.21 198.37,45.47 199.01,45.47 199.14,45.59 199.14,47.24 199.39,47.5 201.42,47.5
1V2 on BOTTOM (solid shape): 252.48,47.24 252.48,45.85 251.59,44.96 251.59,43.69 251.29,43.39 251.27,43.38 251.17,43.36 251.08,43.31 249.94,43.31 249.68,43.56 249.17,43.56 248.92,43.81 248.92,44.62 248.98,44.72 249.08,44.7 249.61,44.76 249.58,45.29 249.55,45.4 249.64,45.47 249.81,45.47 249.94,45.59 249.94,45.61 249.99,45.7 250.1,45.7 250.7,46 250.1,46.31 249.99,46.3 249.94,46.39 249.94,47.24 250.19,47.5 252.22,47.5
1V2 on L6SIG (solid shape): outline of 3941 points within 179.96,41.4 250.19,50.29
1V2 on L3SIG: 167.13,105.79 167.39,105.54 171.83,105.54 172.08,105.79 172.08,106.93 171.7,107.32 167.39,107.32 167.13,107.06
1V2 on L5PWR: 217.04,71.63 217.04,58.42 216.79,58.17 212.72,58.17 191.64,79.25 175.77,79.25 175.51,79.5 175.51,101.47 175.01,101.98 171.32,101.98 171.07,102.23 171.07,107.19 171.32,107.44 207.26,107.44 207.52,107.19 207.52,81.15
1V5 on TOP (solid shape): 37.97,116.84 37.97,108.84 37.59,108.46 33.4,108.46 33.02,108.84 33.02,116.84 33.4,117.22 37.59,117.22
1V5 on BOTTOM (solid shape): 36.32,117.48 36.32,108.08 36.07,107.82 33.66,107.82 33.4,108.08 33.4,117.48 33.66,117.73 36.07,117.73
1V5 on L5PWR: 191.52,220.73 32.26,220.73 19.43,207.9 19.43,109.09 19.69,108.84 36.2,108.84 36.96,109.6 36.96,156.59 58.17,177.8 193.29,177.8 193.55,178.05 193.55,218.69 ; 2 cut-outs
1V05_EC1_AVDD on TOP: 126.87,47.75 130.05,47.75 130.17,47.62 130.17,45.85 130.05,45.72 127.64,45.72 127.51,45.85 126.75,45.85 126.62,45.97 126.62,47.5
1V05_EC1_AVDD on L3SIG: 127.76,48.13 131.06,48.13 131.7,48.77 131.7,51.94 131.95,52.2 137.29,52.2 137.79,51.69 137.79,46.23 137.54,45.97 127.76,45.97 127.51,46.23 127.51,47.88
1V05_EC2_AVDD on TOP: 149.1,47.12 152.27,47.12 152.4,46.99 152.4,45.21 152.27,45.09 149.86,45.09 149.73,45.21 148.97,45.21 148.84,45.34 148.84,46.86
1V05_EC2_AVDD on L3SIG: 149.99,47.5 153.29,47.5 153.92,48.13 153.92,51.31 154.18,51.56 159.51,51.56 160.02,51.05 160.02,45.59 159.77,45.34 149.99,45.34 149.73,45.59 149.73,47.24
1V8 on TOP: 39.12,100.33 39.12,98.04 39.5,97.66 42.93,97.66 43.31,98.04 43.31,100.08 43.05,100.33 42.16,100.33 42.04,100.46 42.04,100.97 41.91,101.09 41.66,101.09 41.53,100.97 41.53,100.46 41.4,100.33
1V8 on TOP: 78.23,103.89 80.65,103.89 80.77,104.01 80.77,106.17 80.65,106.3 78.36,106.3 77.98,105.92 77.98,104.14
1V8 on TOP: 42.93,138.81 42.93,138.05 41.27,136.4 41.27,123.19 43.69,120.78 43.69,119.51 43.43,119.25 43.18,119.25 40,122.43 40,136.91 42.04,138.94 42.8,138.94
1V8 on BOTTOM: 87.38,139.19 87.38,138.3 87.63,138.05 106.05,138.05 106.3,138.3 106.3,139.19 106.05,139.45 87.63,139.45
1V8 on BOTTOM: 49.66,44.96 55.5,50.8 55.5,79.12 54.74,79.88 54.74,93.34 53.85,94.23 53.85,96.52 53.09,97.28 52.45,97.28 52.2,97.03 52.2,51.31 48.77,47.88 36.83,47.88 34.67,45.72 34.67,43.18 35.05,42.8 36.7,42.8 37.21,43.31 37.21,44.32 37.85,44.96
1V8 on L4PWR: 151.13,107.46 151.74,108.08 155.32,108.08 156.59,109.35 160.15,109.35 160.27,109.22 160.27,107.44 160.15,107.32 160.15,107.29 155.72,102.87 151.38,102.87 151.13,103.12
1V8 on L5PWR: 102.49,156.21 125.09,133.6 136.4,133.6 151.13,118.87 161.29,118.87 161.67,118.49 161.67,113.16 161.54,113.03 160.53,113.03 160.02,113.54 154.3,113.54 153.8,113.03 153.8,107.06 154.43,106.43 155.96,106.43 156.21,106.17 156.21,102.11 155.96,101.85 77.6,101.85 71.76,96.01 40.39,96.01 39.62,96.77 39.62,100.97 40.13,101.47 52.83,101.47 55.63,104.27 66.17,104.27 67.44,105.54 67.44,109.47 66.55,110.36 55.24,110.36 54.99,110.62 54.99,152.27 66.17,163.45 102.23,163.45 102.49,163.19
1V8 on L6SIG: 57.15,118.36 57.28,118.49 57.28,119.51 55.88,120.9 43.05,120.9 42.55,120.4 42.55,119 43.18,118.36
1V8_0641_VDD on L3SIG: 236.22,131.7 238.25,133.73 240.03,133.73 240.66,134.37 240.66,137.29 240.41,137.54 240.03,137.54 239.78,137.79 239.78,139.57 239.52,139.83 232.92,139.83 232.41,139.32 232.41,131.95 232.66,131.7
1V8_0641_VDDIO on L6SIG: 236.6,140.46 237.74,139.32 239.78,139.32 240.28,138.81 240.28,133.73 239.52,132.97 235.2,132.97 234.19,133.98 233.43,133.98 232.92,134.49 232.92,138.94 233.81,139.83 234.7,139.83 235.33,140.46
1V8_MTR on L3SIG: 158.62,111.12 159.13,111.12 159.26,111 159.26,110.36 159,110.11 155.19,110.11 155.07,110.24 155.07,111.25 155.19,111.38 158.37,111.38
1V8_OSC_USB on TOP: 80.14,93.09 80.14,91.44 79.5,90.81 79.5,90.04 79.63,89.92 83.19,89.92 83.44,90.17 83.44,92.96 83.19,93.22 80.26,93.22
1V8_SFP on L3SIG: 158.37,113.16 159.26,112.27 159.26,111.51 159.13,111.38 158.75,111.38 158.5,111.63 155.19,111.63 155.07,111.76 155.07,113.03 155.19,113.16
1V8_SLP on BOTTOM (solid shape): 36.32,106.68 36.32,97.28 36.07,97.03 33.66,97.03 33.4,97.28 33.4,106.68 33.66,106.93 36.07,106.93
1V8_SLP on TOP: 33.4,97.66 33.02,98.04 33.02,106.05 33.4,106.43 36.2,106.43 36.58,106.05 36.58,104.46 37.53,103.51 37.53,102.3 37.85,101.98 38.23,101.98 38.48,101.73 38.48,98.04 38.1,97.66
1V8_SLP on TOP: 77.34,97.03 77.47,96.9 79.12,96.9 79.5,96.52 80.52,96.52 80.77,96.77 80.77,97.66 80.52,97.92 79.12,97.92 78.11,98.93 77.6,98.93 77.47,98.81 77.47,98.3 77.34,98.17
1V8_SLP on TOP: 77.85,87.38 80.39,87.38 80.65,87.63 80.65,89.28 80.52,89.41 77.98,89.41 77.72,89.15 77.72,87.5
1V8_SLP on TOP: 212.09,125.48 211.96,125.6 211.45,125.6 211.2,125.86 210.95,125.86 210.95,125.09 209.3,125.09 209.3,125.86 209.04,125.86 209.04,124.21 209.17,124.08 211.84,124.08 212.09,124.33
1V8_SLP on BOTTOM: 230.25,134.11 230.25,132.72 230.5,132.46 230.76,132.46 231.39,131.83 232.54,131.83 232.66,131.95 232.66,134.24 232.54,134.37 230.5,134.37
1V8_SLP on L3SIG: 75.95,93.98 75.95,88.9 76.45,88.39 81.41,88.39 85.73,92.71 85.73,109.73 87.63,111.63 107.95,111.63 110.62,108.97 110.62,101.35 114.81,97.16 148.08,97.16 148.97,98.04 148.97,102.11 151.13,104.27 155.45,104.27 157.1,105.92 157.1,106.17 158.11,107.19 162.43,107.19 162.69,107.44 162.69,112.52 162.31,112.9 160.27,112.9 159.89,112.52 159.89,110.36 159.38,109.86 154.69,109.86 153.29,111.25 153.29,112.9 151,115.19 151,116.97 150.62,117.35 147.57,117.35 144.91,114.68 144.91,105.28 144.4,104.78 143.51,104.78 142.88,105.41 142.88,114.43 136.78,120.52 73.66,120.52 70.36,117.22 70.36,114.05 70.87,113.54 70.87,109.86 70.1,109.09 67.31,109.09 65.02,111.38 65.02,114.55 64.39,115.19 58.29,115.19 57.91,114.81 57.91,112.01
1V8_SLP on L5PWR: 33.66,98.04 33.66,108.08 33.91,108.33 36.45,108.33 37.46,109.35 37.46,156.46 58.29,177.29 237.36,177.29 242.19,172.47 242.19,125.98 240.03,123.83 208.28,123.83 208.03,124.08 208.03,126.75 216.03,134.75 222.25,134.75 225.55,138.05 225.55,144.14 230.63,149.22 230.63,161.04 226.44,165.23 104.39,165.23 103.12,163.96 65.91,163.96 54.48,152.53 54.48,110.49 55.12,109.86 66.29,109.86 66.93,109.22 66.93,105.79 65.91,104.78 55.37,104.78 52.58,101.98 39.88,101.98 39.12,101.22 39.12,97.66 38.86,97.41 34.29,97.41
1V8_USB_OVDD on L5PWR: 161.04,108.84 161.54,108.84 161.67,108.97 161.67,110.24 161.54,110.36 160.91,110.36 156.72,106.17 156.72,101.98 156.97,101.73 158.62,101.73 158.88,101.98 158.88,105.79 160.53,107.44 160.53,108.33
1V8_XGT1_VREGSRDS on BOTTOM (solid shape): 197.23,58.8 197.23,57.4 197.87,56.77 197.87,55.88 197.74,55.75 197.36,55.75 197.25,55.87 197.25,56.29 197.23,56.29 197.23,56.39 196.98,56.64 196.92,56.64 196.83,56.7 196.84,56.8 196.52,57.39 196.2,56.8 196.2,56.7 196.11,56.64 196.09,56.64 195.83,56.39 195.83,54.86 195.71,54.74 195.33,54.74 195.24,54.82 195.24,55.29 195.2,55.29 195.2,55.5 194.56,56.13 194.56,58.93 194.82,59.18 196.85,59.18
1V8_XGT2_VREGSRDS on BOTTOM (solid shape): 248.03,58.8 248.03,57.4 248.67,56.77 248.67,55.88 248.54,55.75 248.16,55.75 248.05,55.87 248.05,56.29 248.03,56.29 248.03,56.39 247.78,56.64 247.72,56.64 247.63,56.7 247.64,56.8 247.32,57.39 247,56.8 247,56.7 246.91,56.64 246.89,56.64 246.63,56.39 246.63,54.86 246.51,54.74 246.13,54.74 246.04,54.82 246.04,55.29 246,55.29 246,55.5 245.36,56.13 245.36,58.93 245.62,59.18 247.65,59.18
1V35 on TOP: 199.9,127.89 199.9,128.91 200.15,129.16 200.15,133.6 200.41,133.86 203.07,133.86 203.33,134.11 203.33,135.89 203.07,136.14 198.25,136.14 190.63,128.52 190.63,123.06 191.01,122.68 195.58,122.68 196.6,123.7 196.6,127.25 196.98,127.64 199.64,127.64
1V35 on BOTTOM: 197.61,129.54 197.61,127.89 197.74,127.76 199.77,127.76 199.9,127.89 199.9,129.54 199.77,129.67 197.74,129.67
1V35 on BOTTOM: 176.02,127.38 176.4,127 176.4,124.46 176.02,124.08 175.64,124.08 175.26,124.46 174.88,124.46 174.5,124.08 174.12,124.08 173.74,124.46 173.35,124.46 172.97,124.08 171.7,124.08 171.32,124.46 170.94,124.46 170.56,124.08 170.05,124.08 169.67,124.46 169.29,124.46 168.91,124.08 168.53,124.08 168.15,124.46 167.77,124.46 166.5,125.73 165.73,125.73 165.61,125.6 165.61,125.09 165.86,124.84 165.86,124.59 165.35,124.08 164.97,124.08 164.59,124.46 164.08,124.46 163.7,124.08 163.32,124.08 162.94,124.46 162.56,124.46 162.18,124.08 161.67,124.08 161.29,124.46 160.91,124.46 160.53,124.08 160.15,124.08 159.77,124.46 159.38,124.46 159,124.08 158.5,124.08 158.11,124.46 157.73,124.46 157.35,124.08 156.72,124.08 156.46,124.33 156.46,127.13 156.72,127.38 ; 1 cut-out
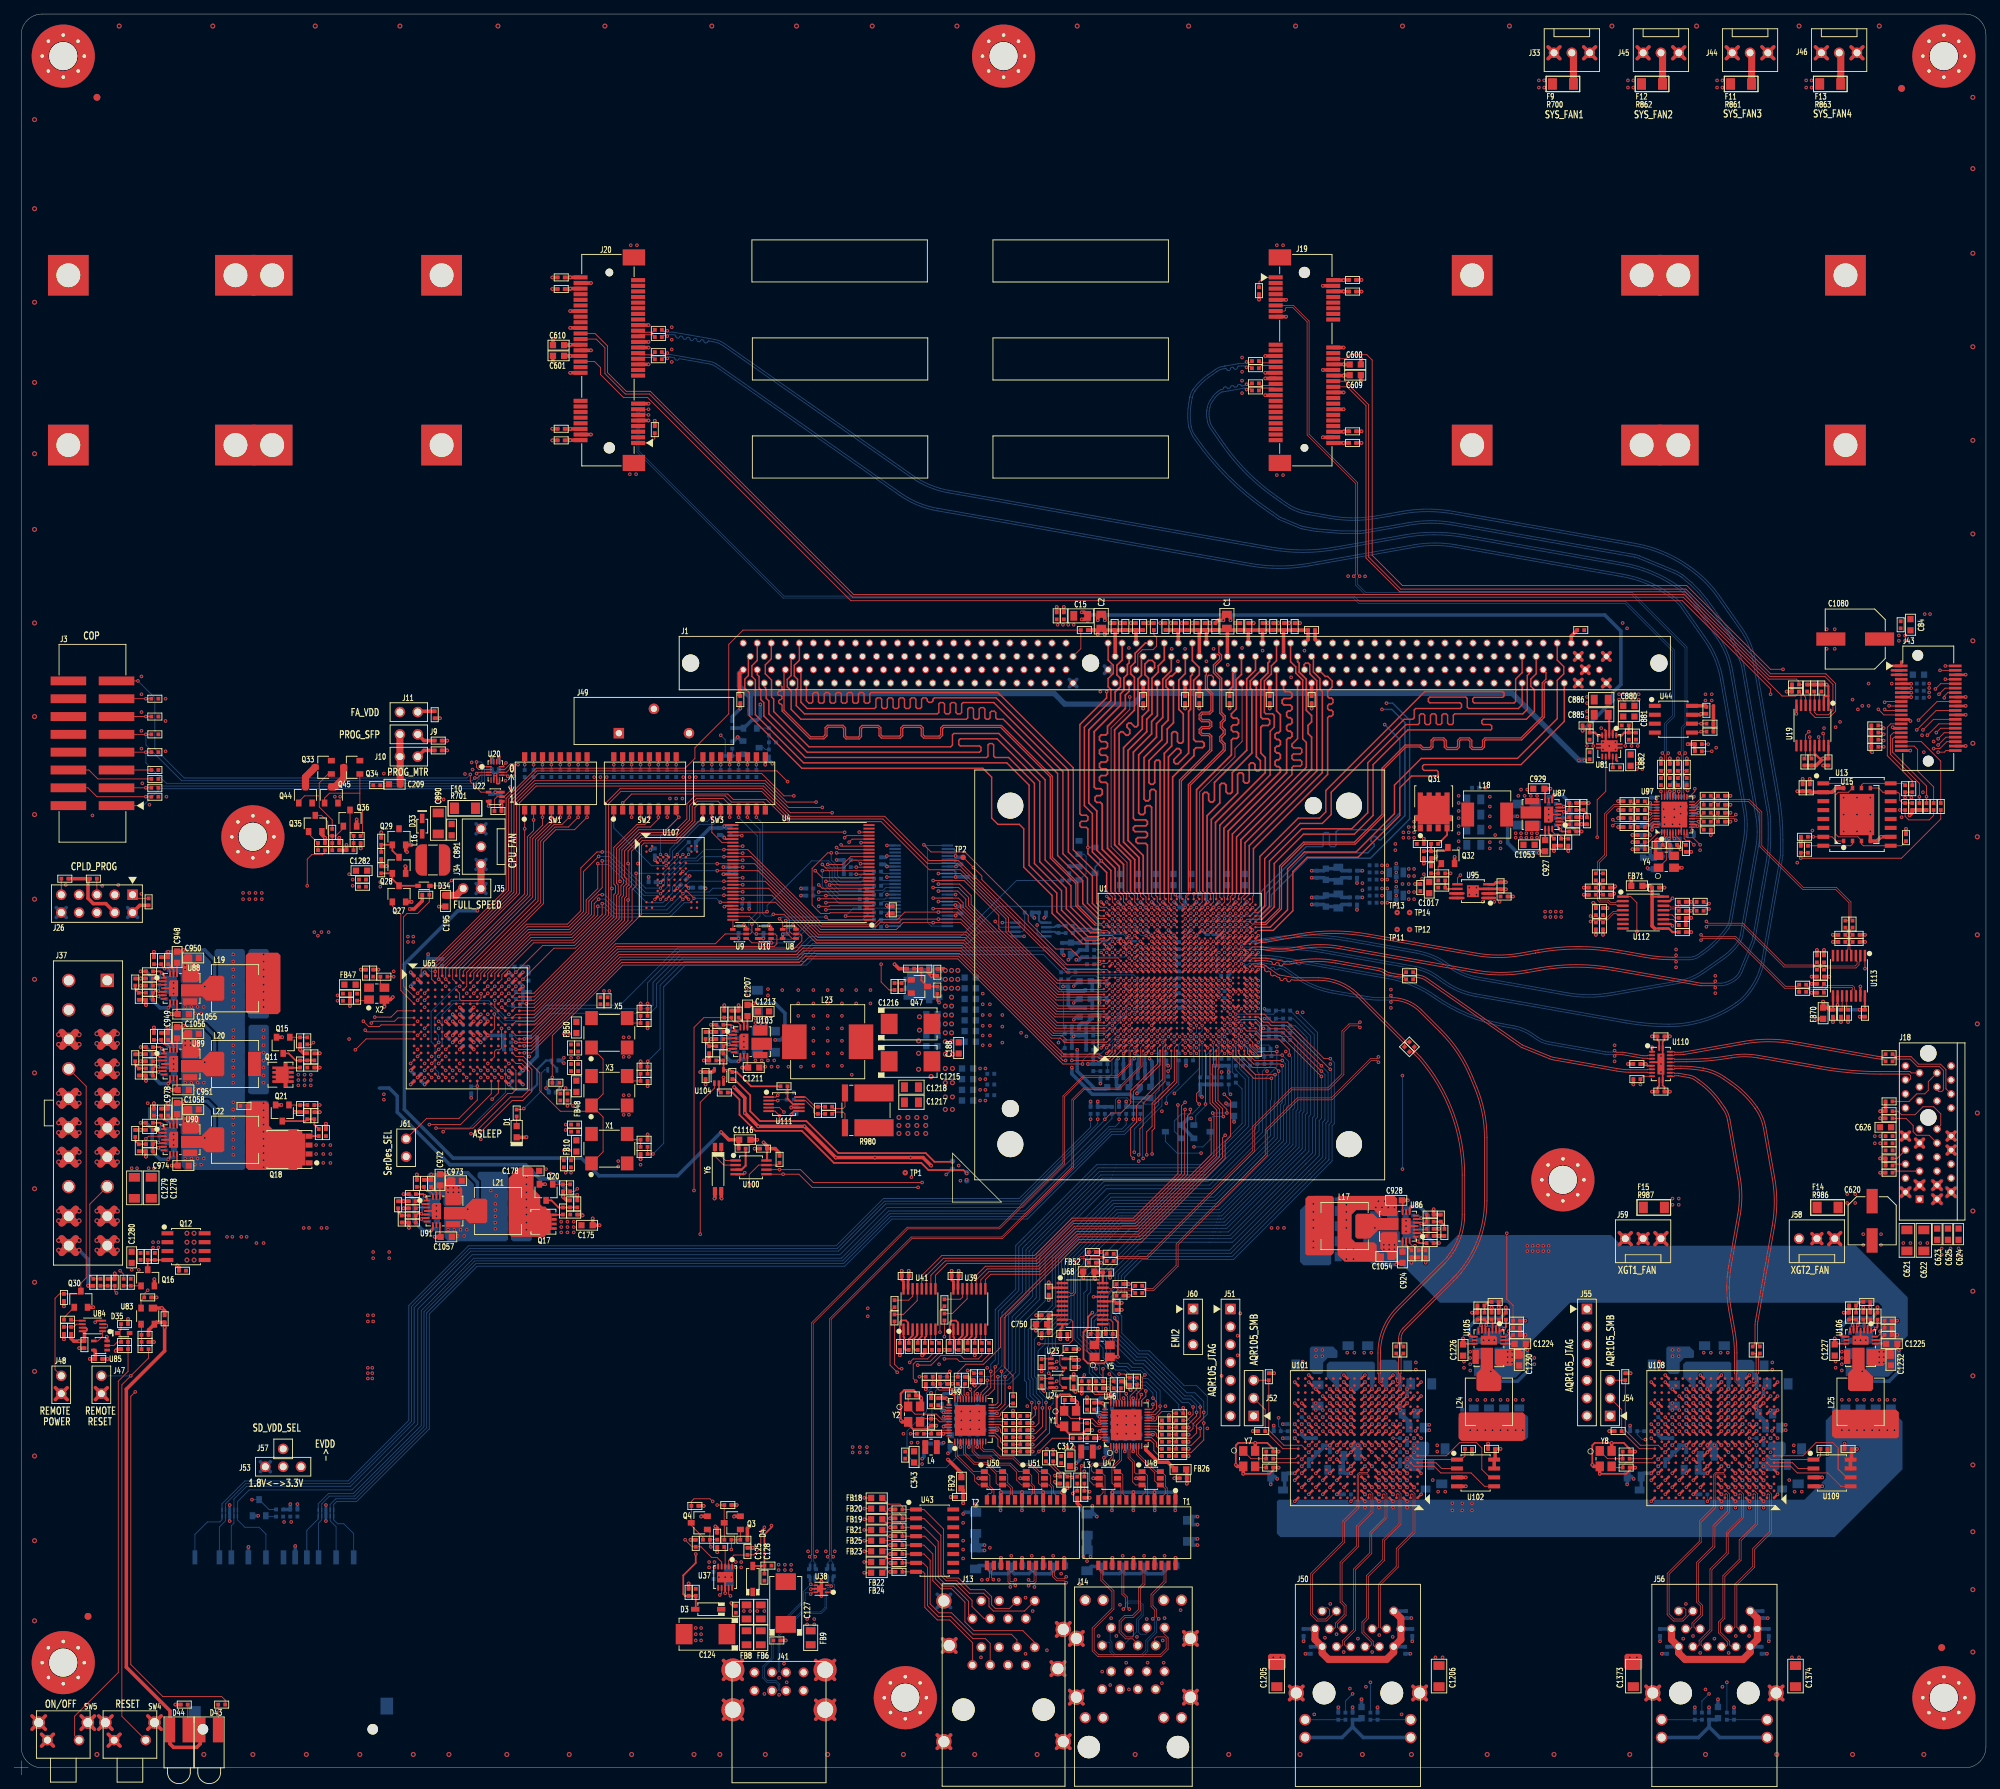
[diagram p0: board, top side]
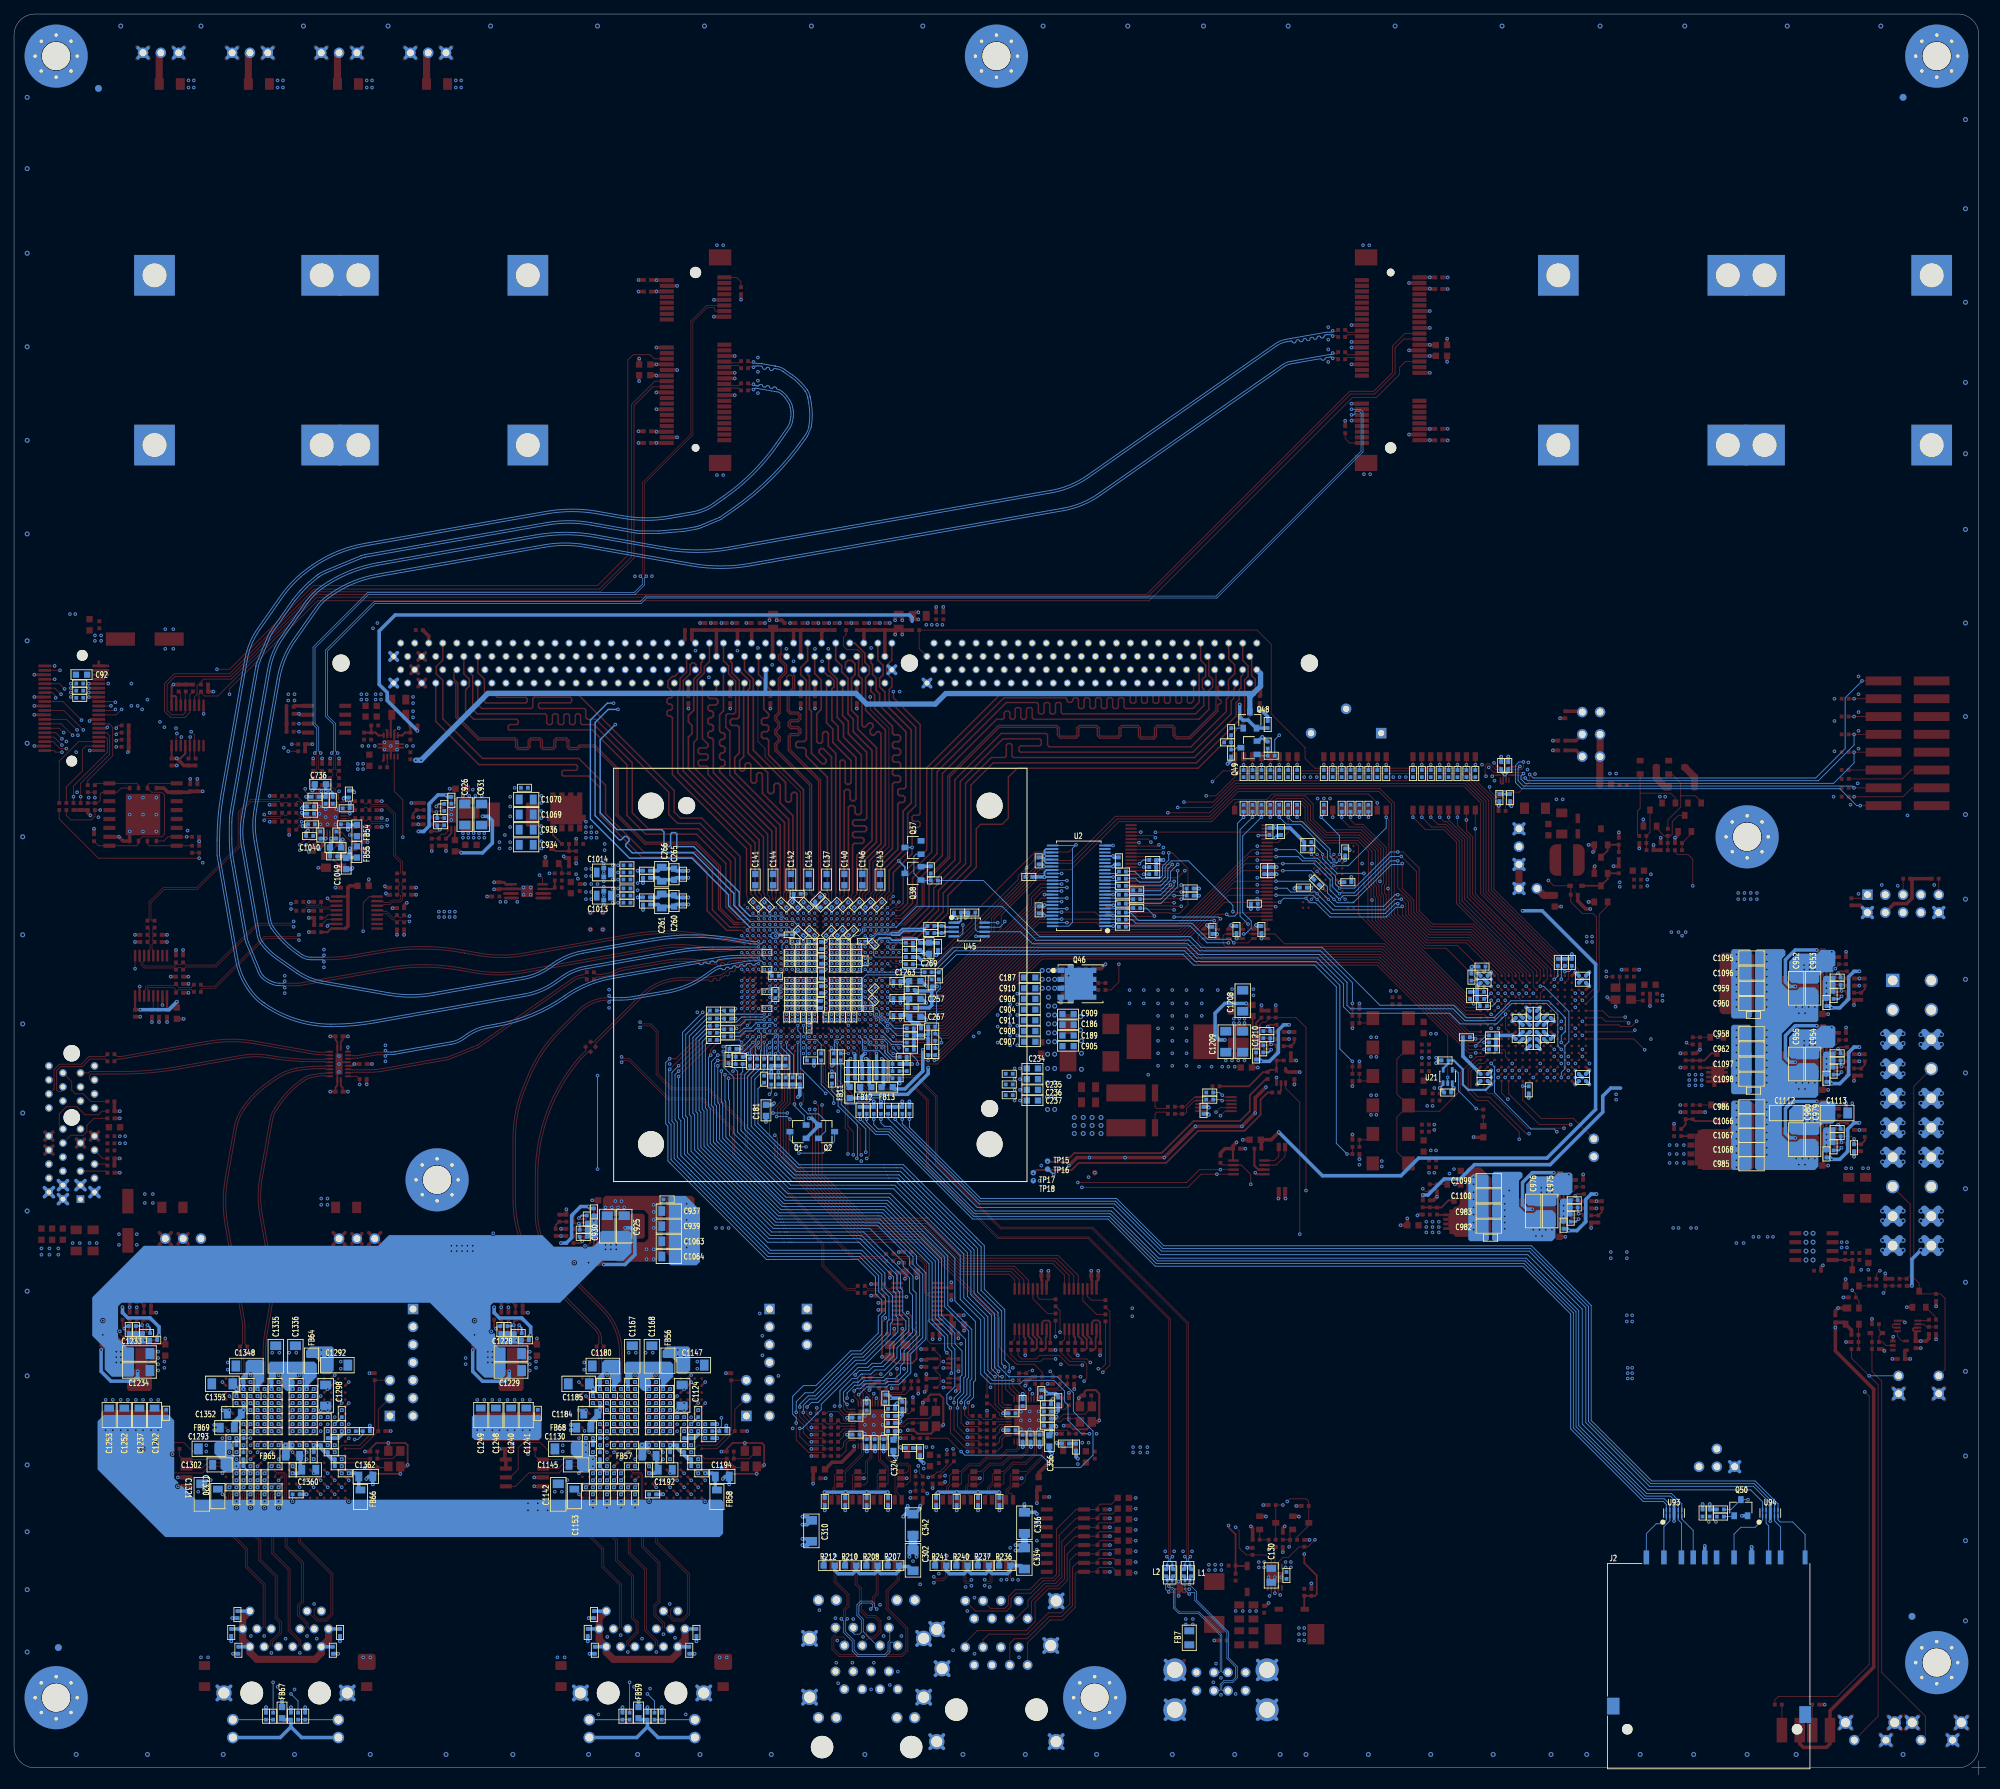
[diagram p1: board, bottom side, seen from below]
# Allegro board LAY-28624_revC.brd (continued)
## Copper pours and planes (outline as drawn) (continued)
1V35 on L5PWR: 169.16,119.38 169.67,119.89 172.21,119.89 172.47,120.14 177.16,120.14 184.66,127.64 208.15,127.64 215.77,135.25 222.12,135.25 225.04,138.18 225.04,144.4 230.12,149.48 230.12,160.91 226.31,164.72 105.66,164.72 103,162.05 103,156.84 125.35,134.49 136.4,134.49 151.51,119.38
1V35_SLP on TOP: 205.49,131.83 208.03,131.83 208.41,132.21 208.41,140.72 207.9,141.22 200.02,141.22 199.52,140.72 199.52,136.91 199.9,136.52 204.6,136.52 205.1,136.02 205.1,132.21
1V35_SLP on TOP: 228.35,149.61 227.71,148.97 227.71,148.72 227.97,148.72 228.09,148.84 228.98,148.84 229.36,149.22 229.36,149.99 229.87,150.5 229.87,154.18 229.74,154.3 228.47,154.3 228.35,154.18
1V35_SLP on BOTTOM: 205.1,140.97 205.1,131.57 205.36,131.32 207.77,131.32 208.03,131.57 208.03,140.97 207.77,141.22 205.36,141.22
1V35_SLP on L4PWR: 161.8,119.38 161.8,119.49 161.4,119.89 159.13,119.89 158.62,120.4 151.13,120.4 136.78,134.75 126.49,134.75 126.48,134.74 125.49,134.74 106.81,153.42 106.4,153.42 102.87,156.95 102.87,162.07 104.25,163.45 227.61,163.45 230.12,160.93 230.12,149.46 225.04,144.38 225.04,138.15 217.57,130.68 187.73,130.68 177.44,120.4 170.2,120.4 169.19,119.38
2V1 on TOP (solid shape): 268.61,51.69 268.61,48.26 268.34,48 259.46,48 259.08,48.38 259.08,51.81 259.33,52.06 268.23,52.06
2V1 on BOTTOM (solid shape): outline of 529 points within 179.96,33.91 269.11,51.31
2V1 on L3SIG (solid shape): outline of 126 points within 251.84,46.55 268.48,50.55
2V1 on L3SIG (solid shape): outline of 304 points within 201.04,37.34 209.04,50.55
2V1 on L3SIG (solid shape): outline of 339 points within 191.64,37.34 199.39,41.4
2V1 on L3SIG (solid shape): outline of 523 points within 242.44,37.34 250.19,41.4
2V1_XGT1_VDDSRDS on L3SIG: 197.36,55.75 199.26,55.75 199.64,55.37 199.64,51.56 199.26,51.18 197.48,51.18 197.23,51.43 197.23,55.63
2V1_XGT2_VDDSRDS on L3SIG: 248.16,55.88 250.06,55.88 250.44,55.5 250.44,51.69 250.06,51.31 248.28,51.31 248.03,51.56 248.03,55.75
2V5 on TOP: 76.58,79.25 76.58,77.09 76.96,76.71 81.03,76.71 81.28,76.96 81.28,79.12 81.03,79.38 79.63,79.38 79.5,79.5 79.5,80.01 79.38,80.14 79.12,80.14 78.99,80.01 78.99,79.5 78.87,79.38 76.71,79.38
2V5 on L4PWR: 174.5,77.6 174.5,101.96 169.9,106.55 169.72,106.55 169.04,107.24 169.04,108.59 169.16,108.71 170.13,108.71 170.31,108.53 170.31,108.15 170.64,107.82 171.85,107.82 171.98,107.7 181.25,107.7 181.61,107.34 181.61,77.7 181.25,77.34 174.75,77.34
2V5 on L5PWR: 151.26,60.45 151.38,60.32 152.02,60.32 152.78,59.56 152.78,52.32 147.7,47.24 113.16,47.24 81.03,79.38 77.6,79.38 77.22,78.99 77.22,77.34 76.58,76.71 72.14,76.71 71.88,76.45 71.88,66.68 72.14,66.42 76.07,66.42 77.22,65.28 77.22,40.64 81.66,36.2 130.56,36.2 134.37,40 158.11,40 162.81,44.7 182.63,44.7 185.93,41.4 260.1,41.4 263.27,44.58 263.27,49.4 255.02,57.66 212.6,57.66 191.52,78.74 166.12,78.74 151.26,63.88
2V5_SLP on TOP (solid shape): 74.04,86.36 74.04,83.5 74.99,82.55 74.99,81.34 75.31,81.03 75.69,81.03 75.95,80.77 75.95,77.09 75.57,76.71 70.87,76.71 70.48,77.09 70.48,85.09 72.01,86.61 73.79,86.61
2V5_SLP on BOTTOM (solid shape): 73.79,84.96 73.79,76.33 73.53,76.07 71.12,76.07 70.87,76.33 70.87,85.34 71.12,85.6 73.15,85.6
2V5_SLP on L4PWR: 173.33,99.44 167.13,105.64 167.13,107.9 167.39,108.15 167.39,108.59 167.51,108.71 168.66,108.71 168.78,108.59 168.78,107.14 169.54,106.37 169.54,106.19 173.99,101.75 173.99,99.57 173.86,99.44
2V5_SLP on L5PWR: 76.71,77.72 76.2,77.22 72.14,77.22 71.88,77.47 71.88,95.38 77.85,101.35 117.73,101.35 117.98,101.09 117.98,90.55 119.76,88.77 164.59,88.77 171.07,95.25 171.07,101.22 171.32,101.47 174.75,101.47 175.01,101.22 175.01,79.5 174.75,79.25 165.86,79.25 150.75,64.14 150.75,60.32 151.26,59.82 151.89,59.82 152.27,59.44 152.27,52.58 147.45,47.75 113.28,47.75 81.15,79.88 77.34,79.88 76.71,79.25
3V3 on TOP: 238.51,152.15 242.32,152.15 242.44,152.27 242.44,154.3 242.19,154.56 238.76,154.56 238.25,154.05 238.25,152.4
3V3 on TOP: 41.4,90.17 41.4,86.61 41.78,86.23 47.24,86.23 50.93,89.92 50.93,100.46 48.26,103.12 48.26,106.93 45.09,110.11 45.09,116.71 35.31,126.49 30.1,126.49 29.34,125.73 29.34,119.76 29.97,119.13 36.83,119.13 38.73,117.22 38.73,109.35 44.2,103.89 44.2,95.12 45.21,94.11 45.21,91.57 44.96,91.31 44.32,91.31 44.2,91.19 44.2,90.81 43.81,90.42 41.66,90.42
3V3 on TOP: 20.32,153.8 20.32,139.06 20.57,138.81 22.1,138.81 22.35,139.06 22.35,153.8 22.1,154.05 20.57,154.05
3V3 on TOP: 267.21,92.84 267.21,91.82 267.46,91.57 267.46,88.9 267.59,88.77 268.35,88.77 269.24,89.66 269.88,89.66 270.64,88.9 274.45,88.9 275.34,88.01 276.73,88.01 277.11,88.39 277.11,91.82 276.61,92.33 275.21,92.33 274.96,92.08 274.96,91.57 274.57,91.19 274.57,90.42 274.45,90.3 273.94,90.3 273.3,90.93 271.02,90.93 270.38,91.57 270.38,92.46 269.88,92.96 267.34,92.96
3V3 on TOP: 46.86,138.18 46.86,139.45 46.61,139.7 45.59,139.7 45.47,139.57 45.47,138.18 45.72,137.92 46.61,137.92
3V3 on BOTTOM: 270,153.03 271.27,153.03 271.4,153.16 271.4,157.48 271.27,157.61 270,157.61 269.88,157.48 269.88,153.16
3V3 on L4PWR: outline of 90 points within 12.7,35.05 277.5,216.79
3V3_OSC_CPLD on TOP: 49.66,111.63 51.31,111.63 51.43,111.76 51.43,113.92 51.31,114.05 48.51,114.05 48.13,113.67 48.13,112.27 48.64,111.76 48.64,111.25 48.77,111.12 49.15,111.12
3V3_SLP on TOP (solid shape): 36.32,95.63 36.32,92.58 36.83,92.08 40.51,92.08 40.77,91.82 40.77,86.61 40.39,86.23 33.4,86.23 33.02,86.61 33.02,95.63 33.4,96.01 35.94,96.01
3V3_SLP on BOTTOM (solid shape): 36.32,95.89 36.32,86.49 36.07,86.23 33.66,86.23 33.4,86.49 33.4,95.89 33.66,96.14 36.07,96.14
3V3_SLP on TOP: 45.59,110.24 45.72,110.11 47.12,110.11 47.12,111.76 47.5,112.14 47.5,113.16 47.24,113.41 45.97,113.41 45.59,113.03
3V3_SLP on TOP: 228.22,144.4 228.6,144.02 228.6,143.26 228.85,143 232.16,143 232.41,143.26 232.41,144.27 232.16,144.53 229.36,144.53 228.47,145.41 228.22,145.41
3V3_SLP on TOP: 221.87,160.27 221.87,158.75 222.76,157.86 222.76,157.23 223.14,156.84 224.66,156.84 225.17,157.35 225.17,158.37 224.92,158.62 224.66,158.62 224.28,159 224.28,159.89 225.17,160.78 225.17,161.67 225.55,162.05 229.87,162.05 230.38,162.56 230.38,164.08 229.74,164.72 224.54,164.72 223.52,163.7 223.52,162.94 222.63,162.05 222.63,161.04
3V3_SLP on L4PWR: outline of 82 points within 12.7,27.69 238.76,174.75
3V3_USB_HVDD on L5PWR: 162.18,108.71 161.16,108.71 160.78,108.33 160.78,107.32 159.13,105.66 159.13,101.98 159.38,101.73 160.15,101.73 160.4,101.98 160.4,104.27 162.31,106.17 162.31,108.59
5V0_SB on TOP: 11.18,80.77 11.18,78.49 11.56,78.11 14.99,78.11 15.37,78.49 15.37,80.77 14.99,81.15 11.56,81.15
5V0_SB on BOTTOM: 5.71,59.05 6.35,58.42 18.16,58.42 18.92,59.18 18.92,78.49 16.26,81.15 11.56,81.15 11.18,80.77 11.18,78.49 11.56,78.11 15.37,78.11 16.38,77.09 16.38,73.91 15.37,72.9 11.18,72.9 11.05,72.77 11.05,69.53 10.79,69.28 10.29,69.28 10.03,69.53 10.03,72.77 9.91,72.9 6.86,72.9 5.71,71.76
5V0_SLP on TOP (solid shape): 25.4,116.84 25.4,115.95 25.65,115.7 26.03,115.7 26.42,115.32 26.42,113.28 26.16,113.03 24.13,113.03 24,113.16 24,116.59 24.38,116.97 25.27,116.97
5V0_SLP on TOP (solid shape): 25.4,106.05 25.4,105.16 25.65,104.9 26.03,104.9 26.42,104.52 26.42,102.49 26.16,102.23 24.13,102.23 24,102.36 24,105.79 24.38,106.17 25.27,106.17
5V0_SLP on TOP (solid shape): 25.4,95.25 25.4,94.36 25.65,94.11 26.03,94.11 26.42,93.73 26.42,91.69 26.16,91.44 24.13,91.44 24,91.57 24,95 24.38,95.38 25.27,95.38
5V0_SLP on TOP (solid shape): 62.86,85.09 62.86,84.2 63.12,83.95 63.5,83.95 63.88,83.57 63.88,81.53 63.63,81.28 61.59,81.28 61.47,81.41 61.47,84.84 61.85,85.22 62.74,85.22
5V0_SLP on TOP (solid shape): 197.1,77.22 197.1,73.79 196.72,73.41 195.83,73.41 195.71,73.53 195.71,74.42 195.45,74.68 195.07,74.68 194.69,75.06 194.69,77.09 194.94,77.34 196.98,77.34
5V0_SLP on TOP (solid shape): 215.01,60.32 215.01,59.43 214.88,59.3 214,59.3 213.74,59.05 213.74,58.67 213.36,58.29 211.33,58.29 211.07,58.54 211.07,60.57 211.2,60.7 214.63,60.7
5V0_SLP on TOP (solid shape): 267.97,60.32 267.97,59.43 267.84,59.3 266.95,59.3 266.7,59.05 266.7,58.67 266.32,58.29 264.29,58.29 264.03,58.54 264.03,60.57 264.16,60.7 267.59,60.7
5V0_SLP on BOTTOM (solid shape): 24,106.3 26.92,106.3 28.07,105.16 28.07,102.49 27.69,102.11 27.05,102.11 26.92,101.98 24,101.98 23.75,102.23 23.75,103.12 23.24,103.63 21.84,103.63 21.46,104.01 21.46,106.55 21.72,106.81 23.49,106.81
5V0_SLP on BOTTOM (solid shape): 24,95.5 27.3,95.5 28.07,94.74 28.07,91.69 27.69,91.31 26.92,91.31 26.8,91.19 24,91.19 23.75,91.44 23.75,92.33 23.24,92.84 21.84,92.84 21.46,93.22 21.46,95.76 21.72,96.01 23.49,96.01
5V0_SLP on BOTTOM (solid shape): 61.47,85.34 64.39,85.34 65.53,84.2 65.53,81.53 65.15,81.15 64.39,81.15 64.26,81.03 61.47,81.03 61.21,81.28 61.21,82.17 60.71,82.68 59.31,82.68 58.93,83.06 58.93,85.6 59.18,85.85 60.96,85.85
5V0_SLP on BOTTOM (solid shape): 24,117.09 26.92,117.09 28.07,115.95 28.07,113.28 27.69,112.9 26.92,112.9 26.8,112.78 24,112.78 23.75,113.03 23.75,113.92 23.24,114.43 21.84,114.43 21.74,114.53 21.71,114.6 21.74,114.67 21.82,115.06 21.51,115.31 21.46,115.32 21.46,117.35 21.72,117.6 23.49,117.6
5V0_SLP on BOTTOM (solid shape): outline of 259 points within 193.04,56.63 269.88,77.6
5V0_SLP on L6SIG (solid shape): outline of 627 points within 193.04,74.3 203.58,82.55
5V0_SLP on L6SIG (solid shape): outline of 848 points within 205.61,56.63 216.03,67.18
5V0_SLP on L6SIG (solid shape): outline of 890 points within 258.56,56.9 269.11,67.18
5V0_SLP on TOP: 217.3,136.02 215.26,136.02 213.74,134.49 213.74,133.6 214,133.35 215.77,133.35 216.03,133.1 216.03,132.21 216.15,132.08 217.04,132.08 217.42,132.46 217.42,135.89
5V0_SLP on TOP: 102.23,29.46 102.36,29.34 103.88,29.34 104.01,29.46 104.01,30.48 103.88,30.61 102.61,30.61 102.23,30.23
5V0_SLP on TOP: 100.45,29.46 100.32,29.34 98.8,29.34 98.67,29.46 98.67,30.48 98.8,30.61 100.07,30.61 100.45,30.23
5V0_SLP on TOP: 105.41,105.41 107.44,105.41 107.7,105.66 107.7,107.7 107.32,108.08 106.93,108.08 106.68,108.33 106.68,109.22 106.55,109.35 105.66,109.35 105.28,108.97 105.28,105.54
5V0_SLP on TOP, BOTTOM: 11.18,93.34 11.18,91.06 11.56,90.68 14.99,90.68 15.37,91.06 15.37,93.34 14.99,93.73 11.56,93.73
5V0_SLP on TOP, BOTTOM: 6.1,73.91 5.71,74.3 5.71,80.77 6.1,81.15 9.53,81.15 9.91,80.77 9.91,74.3 9.53,73.91
5V0_SLP on TOP, BOTTOM: 11.18,101.73 11.18,99.44 11.56,99.06 14.99,99.06 15.37,99.44 15.37,101.73 14.99,102.11 11.56,102.11
5V0_SLP on BOTTOM: 103.75,28.96 104.01,29.21 104.01,30.48 103.75,30.73 98.93,30.73 98.67,30.48 98.67,29.21 99.18,28.7 99.94,28.7 100.2,28.96
5V0_SLP on BOTTOM: 103,109.98 104.78,109.98 105.28,109.47 108.2,109.47 109.35,108.33 109.35,105.66 108.97,105.28 108.2,105.28 108.08,105.16 105.28,105.16 105.03,105.41 105.03,106.3 104.52,106.81 103.12,106.81 102.74,107.19 102.74,109.73
5V0_SLP on BOTTOM: 213.36,133.1 213.36,135.76 213.74,136.14 214.5,136.14 214.63,136.27 217.42,136.27 217.68,136.02 217.68,135.13 218.19,134.62 219.58,134.62 219.96,134.24 221.23,134.24 223.39,132.08 223.39,122.43 222.88,121.92 218.06,121.92 217.8,122.17 217.8,131.57 217.42,131.95 214.5,131.95
5V0_SLP on L3SIG: 5.46,102.49 15.62,102.49 16.26,101.85 16.26,87.38 18.03,85.6 35.94,85.6 37.34,87 82.42,87 87.12,91.69 87.12,108.97 88.52,110.36 107.19,110.36 109.09,108.46 109.09,60.96 94.23,46.1 7.75,46.1 4.83,49.02 4.83,101.85
5V0_SLP on L4PWR: 55.1,75.82 54.74,76.18 54.74,87.52 54.84,87.63 85.37,87.63 88.27,84.73 88.27,75.82
5V0_SLP on L5PWR: 34.04,96.9 33.15,97.79 33.15,108.08 32.89,108.33 7.37,108.33 4.7,105.66 4.7,68.2 6.48,66.42 71.12,66.42 71.37,66.68 71.37,95.25 71.12,95.5 40.13,95.5 38.73,96.9
5V0_SLP on L5PWR: 224.16,123.06 223.9,123.32 208.28,123.32 208.03,123.06 208.03,81.28 215.01,74.3 223.77,74.3 224.16,74.68
5V0_SLP on L6SIG: 239.9,147.83 239.9,172.08 231.77,180.21 13.84,180.21 3.94,170.31 3.94,29.21 8.13,25.02 113.92,25.02 114.3,25.4 114.3,29.34 105.66,37.97 26.16,37.97 13.97,50.16 13.97,72.01 30.1,88.14 30.1,124.33 17.27,137.16 17.27,156.46 25.78,164.97 226.57,164.97 229.87,161.67 229.87,152.91 225.42,148.46 218.95,148.46 212.34,141.86 212.34,132.08 213.49,130.94 223.01,130.94
5V0_USB1 on TOP: 102.23,26.8 102.23,26.03 103.12,25.15 107.31,25.15 107.69,24.77 107.69,23.11 107.44,22.86 105.79,22.86 105.66,22.73 105.66,20.07 105.79,19.94 107.18,19.94 107.69,19.43 107.69,19.05 107.82,18.92 108.33,18.92 108.45,19.05 108.45,19.56 109.6,20.7 110.99,20.7 111.37,21.08 111.37,24.77 110.48,25.65 108.58,25.65 107.44,26.8 107.44,27.69 107.18,27.94 103.37,27.94
5V0_USB2 on TOP: 97.15,27.05 100.32,27.05 100.45,26.92 100.45,25.53 102.61,23.37 103.12,23.37 103.63,22.86 105.02,22.86 105.15,22.73 105.15,20.07 105.02,19.94 103.75,19.94 102.61,18.8 99.94,18.8 99.05,19.69 99.05,23.11 98.04,24.13 98.04,25.78 97.53,26.29 97.02,26.29 96.9,26.42 96.9,26.8
12V on TOP: 219.71,240.03 219.96,240.28 219.96,241.81 219.71,242.06 217.17,242.06 216.92,241.81 216.92,240.28 217.17,240.03
12V on TOP: 257.81,240.03 258.06,240.28 258.06,241.81 257.81,242.06 255.27,242.06 255.02,241.81 255.02,240.28 255.27,240.03
12V on TOP: 233.93,82.3 233.93,80.01 234.19,79.76 237.36,79.76 237.74,80.14 237.74,82.3 237.49,82.55 234.19,82.55
12V on TOP: 273.56,77.47 273.18,77.09 268.73,77.09 266.45,79.38 259.59,79.38 259.21,79.76 259.21,83.82 259.59,84.2 270,84.2 270.76,84.96 274.83,84.96 275.59,84.2 276.99,84.2 278,83.19 278,77.72 277.75,77.47
12V on TOP: 232.41,240.03 232.66,240.28 232.66,241.81 232.41,242.06 229.87,242.06 229.62,241.81 229.62,240.28 229.87,240.03
12V on TOP: 24.26,71.5 24.26,77.47 24.64,77.85 27.81,77.85 28.07,77.6 28.07,71.5 27.81,71.25 24.51,71.25
12V on TOP: 245.11,240.03 245.36,240.28 245.36,241.81 245.11,242.06 242.57,242.06 242.32,241.81 242.32,240.28 242.57,240.03
12V on TOP: 264.03,163.7 263.65,163.32 263.65,157.73 264.8,156.59 267.72,156.59 267.84,156.72 267.84,158.37 267.97,158.5 269.62,158.5 270.26,159.13 270.26,160.15 271.27,161.16 271.27,163.32 270.89,163.7
12V on BOTTOM: 277.75,81.66 277.75,121.67 271.15,128.27 271.15,151 269.37,152.78 269.37,157.61 269.88,158.11 269.88,159.77 271.15,161.04 271.15,228.35 257.56,241.94 145.67,241.94 143.51,239.78 138.68,239.78 136.52,241.94 22.61,241.94 12.7,232.03 12.7,164.47 9.4,161.16 9.4,136.65 27.69,118.36 36.07,118.36 36.83,117.6 36.83,84.71 32,79.88 25.4,79.88 23.37,77.85 23.37,73.66 24.13,72.9 34.04,72.9 42.67,81.53 42.67,125.73 40.64,127.76 30.99,127.76 21.46,137.29 17.78,137.29 16.89,138.18 16.89,156.46 20.83,160.4 20.83,226.95 27.81,233.93 254.76,233.93 265.68,223.01 265.68,183.51 262.76,180.59 262.76,123.57 266.7,119.63 266.7,84.71 265.3,83.31 236.09,83.31 235.84,83.06 235.84,80.77 236.09,80.52 276.61,80.52
12V_SLP on TOP: 61.85,137.79 61.85,137.29 62.1,137.03 63.37,137.03 63.88,137.54 63.88,139.19 63.25,139.83 60.07,139.83 59.82,139.57 59.82,138.68 60.07,138.43 61.21,138.43
12V_SLP on TOP: 23.49,74.8 22.86,74.17 16.13,74.17 15.88,73.91 11.56,73.91 11.18,74.3 11.18,76.58 11.94,77.34 15.24,77.34 16.13,78.23 16.13,83.19 16.51,83.57 23.11,83.57 23.49,83.19
12V_SLP on BOTTOM: 11.18,76.58 11.18,74.3 11.56,73.91 14.99,73.91 15.37,74.3 15.37,76.58 14.99,76.96 11.56,76.96
12V_SLP on BOTTOM: 51.82,81.41 39.88,69.47 21.84,69.47 19.43,71.88 19.43,76.33 19.69,76.58 22.1,76.58 22.61,76.07 22.61,73.53 24,72.14 34.29,72.14 43.31,81.15 43.31,139.19 43.69,139.57 61.21,139.57 61.59,139.19 61.59,133.1 52.58,124.08 52.58,97.66 52.2,97.66 51.82,97.28
AGND_SD1_PLL1 on L6SIG: 185.17,125.48 185.29,125.35 185.29,124.84 185.17,124.71 183.26,124.71 179.96,121.41 179.96,117.86 178.56,116.46 172.85,116.46 171.96,115.57 171.96,115.44 171.83,115.32 171.45,115.32 171.2,115.57 171.2,117.6 171.45,117.86 178.44,117.86 179.32,118.75 179.32,121.67 183.13,125.48
AGND_SD1_PLL2 on L6SIG: 171.45,118.75 171.58,118.62 171.96,118.62 172.08,118.75 172.08,119.13 172.72,119.76 177.8,119.76 178.31,120.27 178.31,122.56 184.28,128.52 185.17,128.52 185.29,128.65 185.29,129.16 185.17,129.29 184.15,129.29 177.67,122.81 177.67,121.16 176.66,120.14 171.83,120.14 171.45,119.76
AVDD_CGA1 on L5PWR: 159.26,111.12 159.89,111.12 160.02,111 160.02,110.62 159.89,110.49 159.38,110.49 159,110.11 157.99,110.11 157.23,109.35 154.56,109.35 154.3,109.6 154.3,111.12 154.56,111.38 159,111.38
AVDD_CGA2 on L5PWR: 160.02,112.78 160.02,111.51 159.89,111.38 159.38,111.38 159.13,111.63 154.56,111.63 154.3,111.89 154.3,112.9 154.43,113.03 159.77,113.03
AVDD_PLAT on L5PWR: 159,109.86 159.51,110.36 159.89,110.36 160.02,110.24 160.02,109.73 157.23,106.93 154.69,106.93 154.3,107.32 154.3,108.84 154.56,109.09 157.23,109.09 157.99,109.86
AVDD_SD1_PLL1 on L6SIG: 185.17,124.46 185.29,124.33 185.29,123.83 185.17,123.7 183.39,123.7 180.72,121.03 180.72,117.09 178.69,115.06 172.47,115.06 172.21,115.32 172.21,115.57 172.85,116.2 178.56,116.2 180.09,117.73 180.09,121.29 183.26,124.46
AVDD_SD1_PLL2 on L6SIG: 178.44,120.14 178.44,122.43 184.28,128.27 185.17,128.27 185.29,128.14 185.29,127.64 185.17,127.51 184.4,127.51 179.07,122.17 179.07,119.13 178.31,118.36 172.34,118.36 172.21,118.49 172.21,119 172.59,119.38 177.67,119.38
GND on TOP (solid shape): 181.23,17.02 181.23,15.24 180.97,14.99 178.94,14.99 178.69,15.24 178.69,17.02 178.94,17.27 180.97,17.27
GND on TOP (solid shape): 232.03,17.02 232.03,15.24 231.77,14.99 229.74,14.99 229.49,15.24 229.49,17.02 229.74,17.27 231.77,17.27
GND on TOP (solid shape): 197.1,82.17 197.1,79.88 196.98,79.76 194.56,79.76 193.8,80.52 191.26,80.52 190.63,79.88 190.63,76.45 191.13,75.95 193.8,75.95 194.18,75.57 194.18,74.8 194.69,74.3 195.07,74.3 195.2,74.17 195.2,73.28 195.07,73.15 189.61,73.15 188.59,74.17 188.59,82.3 188.85,82.55 196.72,82.55
GND on TOP (solid shape): outline of 254 points within 2.52,240.52 11.52,249.52
GND on TOP (solid shape): outline of 254 points within 2.52,11.52 11.52,20.52
GND on TOP (solid shape): outline of 254 points within 29.54,129.23 38.54,138.23
GND on TOP (solid shape): outline of 254 points within 136.52,240.52 145.52,249.52
GND on TOP (solid shape): outline of 254 points within 216.23,80.34 225.23,89.34
GND on TOP (solid shape): outline of 254 points within 270.52,240.52 279.52,249.52
GND on BOTTOM (solid shape): 23.24,113.67 23.24,110.49 23.11,110.36 22.48,110.36 22.35,110.49 22.35,111.12 22.1,111.38 21.59,111.38 21.46,111.51 21.46,113.79 21.59,113.92 22.99,113.92
GND on BOTTOM (solid shape): 23.24,102.87 23.24,99.7 23.11,99.57 22.48,99.57 22.35,99.7 22.35,100.33 22.1,100.58 21.59,100.58 21.46,100.71 21.46,103 21.59,103.12 22.99,103.12
GND on BOTTOM (solid shape): 23.24,92.08 23.24,88.9 23.11,88.77 22.48,88.77 22.35,88.9 22.35,89.54 22.1,89.79 21.59,89.79 21.46,89.92 21.46,92.2 21.59,92.33 22.99,92.33
GND on BOTTOM (solid shape): 60.71,81.92 60.71,78.74 60.58,78.61 59.94,78.61 59.82,78.74 59.82,79.38 59.56,79.63 59.05,79.63 58.93,79.76 58.93,82.04 59.05,82.17 60.45,82.17
GND on BOTTOM (solid shape): 198.75,79.88 198.75,79.25 199.01,78.99 199.52,78.99 199.64,78.87 199.64,76.58 199.52,76.45 198.12,76.45 197.87,76.71 197.87,79.88 197.99,80.01 198.63,80.01
GND on BOTTOM (solid shape): 211.96,63.11 211.96,61.71 211.71,61.46 208.53,61.46 208.41,61.59 208.41,62.22 208.53,62.35 209.17,62.35 209.42,62.6 209.42,63.11 209.55,63.24 211.84,63.24
GND on BOTTOM (solid shape): 264.92,63.11 264.92,61.71 264.67,61.46 261.49,61.46 261.37,61.59 261.37,62.22 261.49,62.35 262.13,62.35 262.38,62.6 262.38,63.11 262.51,63.24 264.8,63.24
GND on BOTTOM (solid shape): 70.36,85.73 70.36,76.33 70.1,76.07 61.85,76.07 61.34,76.58 61.34,80.01 61.85,80.52 64.01,80.52 64.39,80.14 65.66,80.14 66.55,81.03 66.55,84.71 66.04,85.22 66.04,85.73 66.29,85.98 70.1,85.98
GND on BOTTOM (solid shape): 32.89,117.48 32.89,86.49 32.64,86.23 24.38,86.23 23.88,86.74 23.88,90.17 24.38,90.68 26.54,90.68 26.92,90.3 28.19,90.3 29.08,91.19 29.08,95.25 27.81,96.52 24.26,96.52 23.88,96.9 23.88,100.97 24.38,101.47 26.67,101.47 27.05,101.09 28.19,101.09 29.08,101.98 29.08,105.66 27.43,107.32 24.13,107.32 23.88,107.57 23.88,111.76 24.38,112.27 26.54,112.27 26.92,111.89 28.19,111.89 29.08,112.78 29.08,116.33 28.58,116.84 28.58,117.48 28.83,117.73 32.64,117.73
GND on BOTTOM (solid shape): outline of 254 points within 2.52,240.52 11.52,249.52
GND on BOTTOM (solid shape): outline of 254 points within 2.52,11.52 11.52,20.52
GND on BOTTOM (solid shape): outline of 254 points within 29.54,129.23 38.54,138.23
GND on BOTTOM (solid shape): outline of 254 points within 136.52,240.52 145.52,249.52
GND on BOTTOM (solid shape): outline of 254 points within 216.23,80.34 225.23,89.34
GND on BOTTOM (solid shape): outline of 254 points within 270.52,240.52 279.52,249.52
GND on TOP: 107.06,24.77 107.31,24.51 107.31,23.37 107.06,23.11 103.88,23.11 103.12,23.88 102.61,23.88 102.1,24.38 102.1,24.64 102.23,24.77
GND on TOP: 79.5,85.34 79.63,85.47 79.63,86.74 79.5,86.87 74.68,86.87 74.42,86.61 74.42,85.6 74.68,85.34
GND on TOP: 126.62,45.21 126.62,44.07 126.87,43.81 129.67,43.81 129.92,44.07 129.92,45.09 129.67,45.34 126.75,45.34
GND on TOP: 225.81,150.5 225.81,154.18 225.3,154.69 224.41,154.69 223.9,155.19 223.9,156.34 223.77,156.46 222.12,156.46 222,156.34 222,146.81 223.27,145.54 225.55,145.54 225.93,145.92 228.6,145.92 229.49,145.03 232.79,145.03 234.95,147.19 234.95,153.8 234.44,154.3 230.5,154.3 230.38,154.18 230.38,150.5 231.77,149.1 231.77,148.08 231.52,147.83 229.36,147.83 228.98,147.45 225.68,147.45 225.3,147.83 223.39,147.83 222.76,148.46 222.76,149.99 223.01,150.24 224.92,150.24 225.17,149.99 225.17,149.48 225.81,148.84 226.57,148.84 226.69,148.72 226.95,148.72 226.95,148.97 226.44,149.48 226.44,149.86
GND on TOP: 214.88,138.43 217.3,138.43 217.42,138.56 217.42,140.84 217.04,141.22 209.8,141.22 208.91,140.33 208.91,131.95 208.28,131.32 205.1,131.32 204.6,130.81 204.6,129.54 204.85,129.29 213.74,129.29 215.52,131.06 215.52,132.84 215.39,132.97 213.87,132.97 213.36,133.48 213.36,134.37 213.11,134.62 211.45,134.62 210.95,135.13 210.95,138.56 211.58,139.19 214.12,139.19
GND on TOP: 16.26,73.53 16.26,70.61 16.38,70.48 17.65,70.48 18.29,71.12 18.29,73.53 18.16,73.66 16.38,73.66
GND on TOP: 252.86,14.99 254.89,14.99 255.14,15.24 255.14,17.02 254.89,17.27 252.86,17.27 252.6,17.02 252.6,15.24
GND on TOP: 79.88,96.01 79.5,96.01 79.12,96.39 77.47,96.39 77.34,96.27 77.34,95.63 77.98,95 80.01,95 80.14,95.12 80.14,95.76
GND on TOP: 78.23,101.09 80.77,101.09 81.15,101.47 81.15,102.87 80.65,103.38 78.36,103.38 77.98,103 77.98,101.35
GND on TOP: 266.57,91.82 266.95,91.44 266.95,88.9 266.83,88.77 265.05,88.77 264.67,89.15 264.67,93.47 265.05,93.85 266.7,93.85 266.83,93.73 266.83,93.22 266.57,92.96
GND on TOP: 133.1,38.23 135.51,38.23 136.02,37.72 136.02,28.7 135.76,28.45 133.22,28.45 132.84,28.83 132.84,37.97
GND on TOP: 53.85,140.72 53.98,140.84 53.98,142.88 53.85,143 52.2,143 51.94,142.75 51.94,140.84 52.07,140.72
GND on TOP: 49.15,129.67 49.4,129.41 49.4,126.37 49.28,126.24 48.01,126.24 47.5,126.75 47.5,129.41 47.75,129.67
GND on TOP: 202.06,126.75 202.56,127.25 203.07,127.25 203.2,127.38 203.2,127.76 203.07,127.89 201.55,127.89 201.29,128.14 201.29,128.52 201.17,128.65 200.41,128.65 200.28,128.52 200.28,127.76 199.9,127.38 199.9,126.87 200.02,126.75
GND on TOP: 202.06,14.99 204.09,14.99 204.34,15.24 204.34,17.02 204.09,17.27 202.06,17.27 201.8,17.02 201.8,15.24
GND on TOP: 148.84,44.58 148.84,43.43 149.1,43.18 151.51,43.18 151.76,43.43 151.76,44.45 151.51,44.7 148.97,44.7
GND on TOP: 84.07,112.27 83.06,111.25 83.06,110.74 83.19,110.62 85.22,110.62 85.47,110.36 85.47,106.68 84.33,105.54 84.33,86.36 84.71,85.98 89.15,85.98 89.54,86.36 89.54,88.65 89.41,88.77 87,88.77 85.98,89.79 85.98,92.46 86.36,92.84 88.52,92.84 88.77,93.09 88.77,97.54 88.52,97.79 86.61,97.79 85.85,98.55 85.85,100.58 86.61,101.35 87.88,101.35 88.52,101.98 88.52,105.28 87.63,106.17 86.61,106.17 86.11,106.68 86.11,108.97 86.36,109.22 89.28,109.22 89.54,109.47 89.54,112.01 89.28,112.27
GND on TOP: 78.23,91.44 79.5,91.44 79.63,91.57 79.63,93.09 79.5,93.22 78.23,93.22 78.11,93.09 78.11,91.57
GND on TOP: outline of 223 points within 1.78,1.78 280.25,250.25 ; 12 cut-outs
GND on TOP: 104.27,115.06 112.4,115.06 113.16,115.82 122.43,115.82 122.94,115.32 122.94,112.4 124.21,111.12 125.86,111.12 126.11,111.38 126.11,111.89 126.37,112.14 128.65,112.14 129.54,111.25 130.3,111.25 131.95,109.6 131.95,104.14 132.59,103.51 135.25,103.51 135.64,103.89 135.64,111.38 136.02,111.76 138.18,111.76 143.13,106.81 143.13,105.54 144.27,104.39 144.27,87.25 141.48,84.45 138.3,84.45 134.49,88.27 131.83,88.27 130.94,89.15 130.94,94.23 130.43,94.74 128.02,94.74 127.76,95 127.76,108.97 127.25,109.47 119.13,109.47 118.49,108.84 118.49,99.44 117.98,98.93 106.17,98.93 105.41,99.7 105.41,103 107.82,103 109.35,101.47 113.16,101.47 113.54,101.85 113.54,107.19 113.16,107.57 108.46,107.57 107.57,108.46 107.19,108.46 107.06,108.59 107.06,109.6 106.05,110.62 104.14,110.62 103.76,111 103.76,114.55
GND on TOP: 232.41,128.27 232.92,127.76 237.36,127.76 238.12,128.52 238.12,130.94 237.87,131.19 237.87,131.95 237.62,132.21 237.36,132.21 237.24,132.08 237.24,131.95 237.49,131.7 237.49,130.05 237.11,129.67 236.85,129.67 235.58,128.4 233.55,128.4 233.3,128.65 233.3,130.17 233.68,130.56 234.82,130.56 234.95,130.68 234.95,131.32 234.19,132.08 234.19,133.1 234.06,133.22 233.81,133.22 233.43,132.84 233.43,131.83 232.41,130.81
GND on TOP: 206.25,60.71 208.53,60.71 208.66,60.58 208.66,58.17 207.9,57.4 207.9,54.86 208.53,54.23 211.96,54.23 212.47,54.74 212.47,57.4 212.85,57.78 213.61,57.78 214.12,58.29 214.12,58.67 214.25,58.8 215.26,58.8 216.28,59.82 216.28,65.02 213.11,68.2 213.11,88.27 214.5,89.66 236.73,89.66 240.03,86.36 240.03,70.36 238.12,68.45 223.39,68.45 222.5,67.56 222.5,55.12 219.58,52.2 206.12,52.2 205.87,52.45 205.87,60.32
GND on TOP: 112.77,19.94 112.64,20.07 112.64,22.35 112.65,22.36 112.65,23.62 113.41,24.38 116.46,24.38 117.73,25.65 117.73,64.01 121.92,68.2 123.7,68.2 124.08,67.82 124.08,42.04 123.06,41.02 120.9,41.02 120.4,40.51 120.4,24.89 115.44,19.94
GND on BOTTOM: 80.26,107.7 90.55,107.7 91.19,107.06 91.19,103.76 89.79,102.36 89.79,101.09 91.95,98.93 91.95,90.68 90.3,89.03 90.3,87.12 89.66,86.49 83.19,86.49 79.76,89.92 77.98,89.92 76.96,90.93 76.96,95 79.25,97.28 79.25,98.3 78.11,99.44 78.11,103.63 79.76,105.28 79.76,107.19
GND on BOTTOM: 156.21,48.77 156.59,48.39 156.59,47.75 156.72,47.62 160.53,47.62 160.78,47.88 160.78,51.56 160.15,52.2 158.88,52.2 157.61,53.47 156.59,53.47 156.21,53.09
GND on BOTTOM: 96.65,76.71 95.76,77.6 95.76,85.85 101.35,91.44 101.35,91.82 100.97,92.2 100.58,92.2 96.14,87.76 93.98,87.76 93.34,88.39 93.34,111.76 96.14,114.55 113.54,114.55 114.43,115.44 122.94,115.44 123.19,115.19 123.19,110.49 121.79,109.09 121.79,92.96 124.33,90.42 130.43,90.42 130.94,90.93 130.94,97.41 128.4,99.95 128.4,108.33 129.16,109.09 130.3,109.09 130.43,108.97 130.43,103.12 136.02,103.12 136.52,103.63 136.52,115.19 136.65,115.32 145.16,115.32 148.84,111.63 148.84,105.66 148.34,105.16 148.34,104.01 148.84,103.51 148.84,89.03 142.88,83.06 123.32,83.06 116.97,76.71 ; 4 cut-outs
GND on BOTTOM: 155.7,127.89 155.19,128.4 155.19,132.33 154.69,132.84 151.38,132.84 150.75,132.21 150.75,129.54 150.5,129.29 139.19,129.29 134.49,133.98 112.4,133.98 106.43,139.95 72.52,139.95 71.88,140.59 71.88,142.11 72.26,142.49 106.3,142.49 106.68,142.88 106.68,144.14 106.81,144.27 107.82,144.27 108.33,144.78 108.33,151.13 108.71,151.51 159.77,151.51 161.29,153.03 193.93,153.03 194.31,152.65 194.31,149.73 196.6,147.45 196.6,137.29 194.56,135.25 185.93,135.25 178.56,127.89
GND on BOTTOM: 102.87,106.3 104.27,106.3 104.52,106.05 104.52,102.87 104.39,102.74 103.76,102.74 103.63,102.87 103.63,103.51 103.38,103.76 102.87,103.76 102.74,103.89 102.74,106.17
GND on BOTTOM: 133.98,49.4 134.37,49.02 134.37,48.39 134.49,48.26 138.3,48.26 138.56,48.51 138.56,52.2 137.92,52.83 136.65,52.83 135.38,54.1 134.37,54.1 133.98,53.72
GND on BOTTOM: 18.29,96.01 18.29,93.73 18.54,93.47 20.32,93.47 20.57,93.73 20.57,96.01 20.32,96.27 18.54,96.27
GND on BOTTOM: 234.19,137.16 234.19,134.49 234.44,134.24 237.74,134.24 237.87,134.11 237.87,133.73 238,133.6 238.38,133.6 238.63,133.86 238.63,134.87 238.38,135.13 238.38,136.27 238.51,136.4 238.51,138.43 238.25,138.68 234.19,138.68 233.93,138.43 233.93,137.41
GND on BOTTOM: 264.92,184.02 263.14,182.25 188.34,182.25 180.34,190.25 180.34,202.95 179.2,204.09 173.61,204.09 173.58,204.06 170.78,204.06 154.56,187.83 129.41,187.83 108.59,208.66 90.17,208.66 86.87,205.36 86.87,162.43 83.19,158.75 23.24,158.75 21.59,160.4 21.59,226.31 28.45,233.17 254.51,233.17 264.92,222.76
GND on BOTTOM: 112.64,20.07 112.77,19.94 114.29,19.94 114.42,20.07 114.42,22.35 114.29,22.48 112.77,22.48 112.64,22.35
GND on BOTTOM: 193.42,130.05 193.42,124.08 192.28,124.08 191.64,124.71 191.64,130.05 191.77,130.17 193.29,130.17
GND on BOTTOM: outline of 206 points within 1.78,1.78 280.25,250.25 ; 2 cut-outs
GND on BOTTOM: 200.53,128.4 202.56,130.43 207.77,130.43 208.53,131.19 208.53,140.97 208.79,141.22 217.04,141.22 217.55,140.72 217.55,137.29 217.04,136.78 214.88,136.78 214.5,137.16 213.23,137.16 212.34,136.27 212.34,132.46 214.38,130.43 215.52,130.43 216.15,129.79 216.15,123.06 215.26,122.17 201.17,122.17 200.53,122.81
GND on BOTTOM: 218.31,138.68 218.95,138.68 219.07,138.56 219.07,137.92 219.33,137.67 219.84,137.67 219.96,137.54 219.96,135.25 219.84,135.13 218.44,135.13 218.19,135.38 218.19,138.56
GND on BOTTOM: 196.6,130.17 196.6,123.95 196.72,123.83 197.23,123.83 197.36,123.95 197.36,126.37 197.61,126.62 200.66,126.62 200.79,126.75 200.79,127.25 200.66,127.38 197.61,127.38 197.36,127.64 197.36,130.17 197.23,130.3 196.72,130.3
GND on L2GND: outline of 83 points within 1.78,1.78 280.25,250.25 ; 44 cut-outs
GND on L3SIG: 3.3,128.02 1.78,129.54 1.78,248.02 2.43,249.6 4.02,250.25 278.02,250.25 279.6,249.6 280.25,248.02 280.25,126.08 278.89,124.71 266.45,124.71 242.32,148.84 242.32,149.99 241.3,151 231.52,151 230.25,152.27 230.25,161.42 228.22,163.45 62.99,163.45 50.67,151.13 50.67,132.59 46.1,128.02 ; 1 cut-out
GND on L4PWR: outline of 86 points within 1.78,1.78 280.25,250.25 ; 1 cut-out
GND on L5PWR: 184.91,127.13 207.26,127.13 207.52,126.87 207.52,108.2 207.26,107.95 175.39,107.95 175.13,108.2 175.13,119.51 175.39,119.76 177.55,119.76
GND on L5PWR: outline of 87 points within 1.78,1.78 280.29,250.25 ; 1 cut-out
GND on L6SIG: 80.9,112.65 126.11,112.65 127.38,111.38 127.38,87.88 125.86,86.36 85.34,86.36 83.95,87.76 81.15,87.76 77.98,90.93 77.98,109.73
GND on L6SIG: 1.78,182.37 1.78,248.02 2.43,249.6 4.02,250.25 278.02,250.25 279.6,249.6 280.25,248.02 280.25,161.64 279.65,161.04 270.51,161.04 269.24,159.77 244.86,159.77 240.92,163.7 240.92,172.21 232.16,180.97 3.18,180.97
GND on L7GND: outline of 83 points within 1.78,1.78 280.25,250.25
SVDD on BOTTOM: 193.93,126.62 193.93,124.08 196.09,124.08 196.34,124.33 196.34,126.37 196.09,126.62
SVDD on L4PWR: 170.69,113.72 169.93,114.48 169.93,118.92 169.92,118.94 169.92,119.39 170.41,119.89 171.96,119.89 172.21,119.63 172.21,112.14 172.08,112.01 170.94,112.01 170.69,112.27
SVDD on L5PWR: 170.05,114.55 171.2,114.55 171.45,114.81 171.45,119.38 171.2,119.63 170.18,119.63 169.93,119.38 169.93,114.68
SVDD on L6SIG: 188.09,111.12 196.09,119.13 196.09,126.49 195.83,126.75 187.07,126.75 186.31,125.98 186.31,123.57 185.8,123.06 184.15,123.06 181.48,120.4 181.48,116.71 179.32,114.55 171.07,114.55 170.81,114.81 170.81,119.25 170.69,119.38 168.91,119.38 168.66,119.13 168.66,111.63 169.16,111.12
VDD_SD on BOTTOM: 37.72,35.81 37.72,30.23 37.97,29.97 38.86,29.97 39.12,30.23 39.12,34.54 40.64,36.07 40.64,36.96 40.51,37.08 38.23,37.08 38.1,36.96 38.1,36.2
VDD_SD on L3SIG: 37.59,45.21 39.62,45.21 40,44.83 40,35.81 39.75,35.56 37.46,35.56 37.21,35.81 37.21,44.83
(no net) on TOP: 24.13,102.23 26.16,102.23 26.42,102.49 26.42,104.52 26.03,104.9 25.65,104.9 25.4,105.16 25.4,106.05 25.27,106.17 24.38,106.17 24,105.79 24,102.36
(no net) on TOP: 24.13,113.03 26.16,113.03 26.42,113.28 26.42,115.32 26.03,115.7 25.65,115.7 25.4,115.95 25.4,116.84 25.27,116.97 24.38,116.97 24,116.59 24,113.16
(no net) on TOP: 24.13,91.44 26.16,91.44 26.42,91.69 26.42,93.73 26.03,94.11 25.65,94.11 25.4,94.36 25.4,95.25 25.27,95.38 24.38,95.38 24,95 24,91.57
(no net) on TOP: 29.72,88.77 27.43,88.77 26.8,89.41 24,89.41 23.88,89.54 23.88,90.93 24,91.06 26.67,91.06 27.94,92.33 29.72,92.33 29.97,92.08 29.97,89.03
(no net) on TOP: 29.72,110.36 27.43,110.36 26.8,111 24,111 23.88,111.12 23.88,112.52 24,112.65 26.67,112.65 27.94,113.92 29.72,113.92 29.97,113.67 29.97,110.62
(no net) on TOP: 178.94,14.99 180.97,14.99 181.23,15.24 181.23,17.02 180.97,17.27 178.94,17.27 178.69,17.02 178.69,15.24
(no net) on TOP: 188.09,82.3 187.83,82.55 184.4,82.55 184.02,82.17 184.02,74.3 184.28,74.04 187.71,74.04 188.09,74.42
(no net) on TOP: 196.98,77.34 194.94,77.34 194.69,77.09 194.69,75.06 195.07,74.68 195.45,74.68 195.71,74.42 195.71,73.53 195.83,73.41 196.72,73.41 197.1,73.79 197.1,77.22
(no net) on TOP: 67.18,78.61 64.9,78.61 64.26,79.25 61.47,79.25 61.34,79.38 61.34,80.77 61.47,80.9 64.14,80.9 65.41,82.17 67.18,82.17 67.44,81.92 67.44,78.87
(no net) on TOP: 229.74,14.99 231.77,14.99 232.03,15.24 232.03,17.02 231.77,17.27 229.74,17.27 229.49,17.02 229.49,15.24
(no net) on TOP: 264.03,60.57 264.03,58.54 264.29,58.29 266.32,58.29 266.7,58.67 266.7,59.05 266.95,59.3 267.84,59.3 267.97,59.43 267.97,60.32 267.59,60.7 264.16,60.7
(no net) on TOP: 33.02,86.61 33.4,86.23 40.39,86.23 40.77,86.61 40.77,91.82 40.51,92.08 36.83,92.08 36.32,92.58 36.32,95.63 35.94,96.01 33.4,96.01 33.02,95.63
(no net) on TOP: 208.41,54.98 208.41,57.27 209.04,57.9 209.04,60.7 209.17,60.83 210.57,60.83 210.69,60.7 210.69,58.03 211.96,56.76 211.96,54.98 211.71,54.73 208.66,54.73
(no net) on TOP: 70.48,85.09 70.48,77.09 70.87,76.71 75.57,76.71 75.95,77.09 75.95,80.77 75.69,81.03 75.31,81.03 74.99,81.34 74.99,82.55 74.04,83.5 74.04,86.36 73.79,86.61 72.01,86.61
(no net) on TOP: 29.72,99.57 27.43,99.57 26.8,100.2 24,100.2 23.88,100.33 23.88,101.73 24,101.85 26.67,101.85 27.94,103.12 29.72,103.12 29.97,102.87 29.97,99.82
(no net) on TOP: 211.07,60.57 211.07,58.54 211.33,58.29 213.36,58.29 213.74,58.67 213.74,59.05 214,59.3 214.88,59.3 215.01,59.43 215.01,60.32 214.63,60.7 211.2,60.7
(no net) on TOP: 259.33,52.06 259.08,51.81 259.08,48.38 259.46,48 268.34,48 268.61,48.26 268.61,51.69 268.23,52.06
(no net) on TOP: 33.4,117.22 33.02,116.84 33.02,108.84 33.4,108.46 37.59,108.46 37.97,108.84 37.97,116.84 37.59,117.22
(no net) on TOP: 261.37,54.98 261.37,57.27 262,57.9 262,60.7 262.13,60.83 263.53,60.83 263.65,60.7 263.65,58.03 264.92,56.76 264.92,54.98 264.67,54.73 261.62,54.73
(no net) on TOP: 194.56,79.76 196.98,79.76 197.1,79.88 197.1,82.17 196.72,82.55 188.85,82.55 188.59,82.3 188.59,74.17 189.61,73.15 195.07,73.15 195.2,73.28 195.2,74.17 195.07,74.3 194.69,74.3 194.18,74.8 194.18,75.57 193.8,75.95 191.13,75.95 190.63,76.45 190.63,79.88 191.26,80.52 193.8,80.52
(no net) on TOP: 205.87,51.43 205.87,48 206.25,47.62 215,47.62 215.39,48.01 215.39,51.3 215.01,51.69 206.12,51.69
(no net) on TOP: 61.59,81.28 63.63,81.28 63.88,81.53 63.88,83.57 63.5,83.95 63.12,83.95 62.86,84.2 62.86,85.09 62.74,85.22 61.85,85.22 61.47,84.84 61.47,81.41
(no net) on TOP: 191.39,80.01 193.67,80.01 194.31,79.38 197.1,79.38 197.23,79.25 197.23,77.85 197.1,77.72 194.44,77.72 193.17,76.45 191.39,76.45 191.13,76.71 191.13,79.76
(no net) on BOTTOM: 73.79,76.33 73.79,84.96 73.15,85.6 71.12,85.6 70.87,85.34 70.87,76.33 71.12,76.07 73.53,76.07
(no net) on BOTTOM: 36.32,86.49 36.32,95.89 36.07,96.14 33.66,96.14 33.4,95.89 33.4,86.49 33.66,86.23 36.07,86.23
(no net) on BOTTOM: 201.68,47.24 201.68,45.85 200.79,44.96 200.79,43.69 200.41,43.31 199.14,43.31 198.88,43.56 198.37,43.56 198.12,43.81 198.12,45.21 198.37,45.47 199.01,45.47 199.14,45.59 199.14,47.24 199.39,47.5 201.42,47.5
(no net) on BOTTOM: 60.58,78.61 59.94,78.61 59.82,78.74 59.82,79.38 59.56,79.63 59.05,79.63 58.93,79.76 58.93,82.04 59.05,82.17 60.45,82.17 60.71,81.92 60.71,78.74
(no net) on BOTTOM: 261.37,61.59 261.37,62.22 261.49,62.35 262.13,62.35 262.38,62.6 262.38,63.11 262.51,63.24 264.8,63.24 264.92,63.11 264.92,61.71 264.67,61.46 261.49,61.46
(no net) on BOTTOM: 23.11,88.77 22.48,88.77 22.35,88.9 22.35,89.54 22.1,89.79 21.59,89.79 21.46,89.92 21.46,92.2 21.59,92.33 22.99,92.33 23.24,92.08 23.24,88.9
(no net) on BOTTOM: 23.11,99.57 22.48,99.57 22.35,99.7 22.35,100.33 22.1,100.58 21.59,100.58 21.46,100.71 21.46,103 21.59,103.12 22.99,103.12 23.24,102.87 23.24,99.7
(no net) on BOTTOM: 194.56,58.93 194.56,56.13 195.2,55.5 195.2,54.86 195.33,54.74 195.71,54.74 195.83,54.86 195.83,56.39 196.09,56.64 196.98,56.64 197.23,56.39 197.23,55.88 197.36,55.75 197.74,55.75 197.87,55.88 197.87,56.77 197.23,57.4 197.23,58.8 196.85,59.18 194.82,59.18
(no net) on BOTTOM: 61.21,82.17 61.21,81.28 61.47,81.03 64.26,81.03 64.39,81.15 65.15,81.15 65.53,81.53 65.53,84.2 64.39,85.34 61.47,85.34 60.96,85.85 59.18,85.85 58.93,85.6 58.93,83.06 59.31,82.68 60.71,82.68
(no net) on BOTTOM: 191.72,47.41 192.02,47.11 192.02,45 191.92,44.9 191.12,44.9 190.92,45.1 190.92,46.1 190.32,46.71 190.32,47.31 190.42,47.41
(no net) on BOTTOM: 242.52,47.41 242.82,47.11 242.82,45 242.72,44.9 241.92,44.9 241.72,45.1 241.72,46.1 241.12,46.71 241.12,47.31 241.22,47.41
(no net) on BOTTOM: 23.75,103.12 23.75,102.23 24,101.98 26.92,101.98 27.05,102.11 27.69,102.11 28.07,102.49 28.07,105.16 26.92,106.3 24,106.3 23.49,106.81 21.72,106.81 21.46,106.55 21.46,104.01 21.84,103.63 23.24,103.63
(no net) on BOTTOM: 208.41,61.59 208.41,62.22 208.53,62.35 209.17,62.35 209.42,62.6 209.42,63.11 209.55,63.24 211.84,63.24 211.96,63.11 211.96,61.71 211.71,61.46 208.53,61.46
(no net) on BOTTOM: 36.32,97.28 36.32,106.68 36.07,106.93 33.66,106.93 33.4,106.68 33.4,97.28 33.66,97.03 36.07,97.03
(no net) on BOTTOM: 24.38,86.23 23.88,86.74 23.88,90.17 24.38,90.68 26.54,90.68 26.92,90.3 28.19,90.3 29.08,91.19 29.08,95.25 27.81,96.52 24.26,96.52 23.88,96.9 23.88,100.97 24.38,101.47 26.67,101.47 27.05,101.09 28.19,101.09 29.08,101.98 29.08,105.66 27.43,107.32 24.13,107.32 23.88,107.57 23.88,111.76 24.38,112.27 26.54,112.27 26.92,111.89 28.19,111.89 29.08,112.78 29.08,116.33 28.58,116.84 28.58,117.48 28.83,117.73 32.64,117.73 32.89,117.48 32.89,86.49 32.64,86.23
(no net) on BOTTOM: 215.77,51.05 215.52,51.3 206.12,51.3 205.87,51.05 205.87,48.13 206.25,47.75 215.39,47.75 215.77,48.13
(no net) on BOTTOM: 235.71,61.09 235.46,60.83 235.46,57.66 235.97,57.15 237.11,57.15 237.36,57.4 237.36,58.8 238,59.44 239.27,59.44 239.39,59.56 239.39,60.45 238.76,61.09
(no net) on BOTTOM: 36.32,108.08 36.32,117.48 36.07,117.73 33.66,117.73 33.4,117.48 33.4,108.08 33.66,107.82 36.07,107.82
(no net) on BOTTOM: 179.96,38.99 180.21,39.24 255.14,39.24 258.19,42.29 258.19,50.55 258.95,51.31 268.22,51.31 269.11,50.42 269.11,43.56 259.46,33.91 180.47,33.91 179.96,34.42
(no net) on BOTTOM: 70.36,85.73 70.36,76.33 70.1,76.07 61.85,76.07 61.34,76.58 61.34,80.01 61.85,80.52 64.01,80.52 64.39,80.14 65.66,80.14 66.55,81.03 66.55,84.71 66.04,85.22 66.04,85.73 66.29,85.98 70.1,85.98
(no net) on BOTTOM: 23.75,113.92 23.75,113.03 24,112.78 26.8,112.78 26.92,112.9 27.69,112.9 28.07,113.28 28.07,115.95 26.92,117.09 24,117.09 23.49,117.6 21.72,117.6 21.46,117.35 21.46,114.81 21.84,114.43 23.24,114.43
(no net) on BOTTOM: 23.75,92.33 23.75,91.44 24,91.19 26.8,91.19 26.92,91.31 27.69,91.31 28.07,91.69 28.07,94.74 27.3,95.5 24,95.5 23.49,96.01 21.72,96.01 21.46,95.76 21.46,93.22 21.84,92.84 23.24,92.84
(no net) on BOTTOM: 245.36,58.93 245.36,56.13 246,55.5 246,54.86 246.13,54.74 246.51,54.74 246.63,54.86 246.63,56.39 246.89,56.64 247.78,56.64 248.03,56.39 248.03,55.88 248.16,55.75 248.54,55.75 248.67,55.88 248.67,56.77 248.03,57.4 248.03,58.8 247.65,59.18 245.62,59.18
(no net) on BOTTOM: 197.99,80.01 198.63,80.01 198.75,79.88 198.75,79.25 199.01,78.99 199.52,78.99 199.64,78.87 199.64,76.58 199.52,76.45 198.12,76.45 197.87,76.71 197.87,79.88
(no net) on BOTTOM: 187.45,72.64 187.71,72.9 187.71,82.3 187.45,82.55 185.29,82.55 183.26,80.52 183.26,73.15 183.77,72.64
(no net) on BOTTOM: 244.73,55.88 244.6,55.75 244.22,55.75 244.09,55.88 244.09,56.26 243.71,56.64 242.95,56.64 242.7,56.39 242.7,55.24 242.19,54.74 241.3,54.74 241.17,54.86 241.17,56.39 240.92,56.64 239.9,56.64 239.65,56.39 239.65,54.86 239.52,54.74 239.14,54.74 239.01,54.86 239.01,55.63 237.87,56.77 237.87,58.55 238.25,58.93 244.47,58.93 244.73,58.67
(no net) on BOTTOM: 23.11,110.36 22.48,110.36 22.35,110.49 22.35,111.12 22.1,111.38 21.59,111.38 21.46,111.51 21.46,113.79 21.59,113.92 22.99,113.92 23.24,113.67 23.24,110.49
(no net) on BOTTOM: 193.93,55.88 193.8,55.75 193.42,55.75 193.29,55.88 193.29,56.26 192.91,56.64 192.15,56.64 191.9,56.39 191.9,55.24 191.39,54.74 190.5,54.74 190.37,54.86 190.37,56.39 190.12,56.64 189.1,56.64 188.85,56.39 188.85,54.86 188.72,54.74 188.34,54.74 188.21,54.86 188.21,55.63 187.07,56.77 187.07,58.55 187.45,58.93 193.67,58.93 193.93,58.67
(no net) on BOTTOM: 252.48,47.24 252.48,45.85 251.59,44.96 251.59,43.69 251.21,43.31 249.94,43.31 249.68,43.56 249.17,43.56 248.92,43.81 248.92,45.21 249.17,45.47 249.81,45.47 249.94,45.59 249.94,47.24 250.19,47.5 252.22,47.5
(no net) on BOTTOM: 184.91,61.09 184.66,60.83 184.66,57.66 185.17,57.15 186.31,57.15 186.56,57.4 186.56,58.8 187.2,59.44 188.47,59.44 188.59,59.56 188.59,60.45 187.96,61.09
(no net) on BOTTOM: 215.14,60.71 215.14,57.78 214,56.64 214,56.63 211.33,56.63 211.33,56.64 210.95,57.02 210.95,57.78 210.95,57.79 210.95,60.83 211.07,60.95 211.96,60.95 212.47,61.46 212.47,62.86 212.85,63.24 212.98,63.24 213.11,63.37 213.11,66.93 212.72,67.31 203.2,67.31 197.23,73.28 194.18,73.28 193.04,74.42 193.04,77.22 193.42,77.6 197.23,77.6 197.48,77.34 197.48,76.33 198.5,75.31 204.09,75.31 205.74,76.96 227.58,76.96 229.11,75.44 262.51,75.44 269.88,68.07 269.88,62.61 268.1,60.83 268.1,57.78 267.08,56.77 264.16,56.77 263.91,57.02 263.91,60.83 264.03,60.96 264.92,60.96 266.19,62.23 266.19,66.8 265.68,67.31 221.74,67.31
(no net) on L3SIG: 242.7,41.4 249.81,41.4 250.19,41.02 250.19,37.85 249.68,37.34 242.82,37.34 242.44,37.72 242.44,41.15
(no net) on L3SIG: 257.3,49.66 267.97,49.66 268.48,49.15 268.48,46.99 268.03,46.55 252.79,46.55 251.84,47.5 251.84,50.16 252.22,50.55 256.41,50.55
(no net) on L3SIG: 191.9,41.4 199.01,41.4 199.39,41.02 199.39,37.85 198.88,37.34 192.02,37.34 191.64,37.72 191.64,41.15
(no net) on L3SIG: 209.04,46.48 209.04,37.85 208.53,37.34 203.58,37.34 203.07,37.85 203.07,42.42 202.06,43.43 202.06,46.48 201.04,47.5 201.04,50.16 201.42,50.55 204.98,50.55
(no net) on L6SIG: 269.11,65.41 269.11,58.16 267.84,56.9 259.97,56.9 258.56,58.3 258.56,66.04 259.71,67.18 267.33,67.18
(no net) on L6SIG: 203.58,80.77 203.58,77.6 203.33,77.34 200.41,77.34 197.36,74.3 193.55,74.3 193.04,74.8 193.04,81.41 194.18,82.55 201.8,82.55
(no net) on L6SIG: 207.39,67.18 212.73,67.18 212.74,67.18 214.76,67.18 216.03,65.91 216.03,61.59 215.26,60.83 215.26,58.54 213.36,56.63 206.76,56.63 205.61,57.78 205.61,65.4
(no net) on L6SIG: 187.96,55.37 187.96,53.72 188.21,53.47 196.85,53.47 197.1,53.72 197.1,55.37 196.85,55.63 188.21,55.63
(no net) on L6SIG: 181.61,41.4 180.72,42.29 180.72,46.35 179.96,47.12 179.96,50.04 180.21,50.29 181.23,50.29 181.48,50.04 181.48,47.75 182.63,46.61 200.41,46.61 203.83,50.04 229.74,50.04 233.17,46.61 249.68,46.61 250.19,46.1 250.19,41.78 249.81,41.4
(no net) on L6SIG: 238.76,55.37 238.76,53.72 239.01,53.47 247.65,53.47 247.9,53.72 247.9,55.37 247.65,55.63 239.01,55.63
EARTH on TOP (solid shape): outline of 254 points within 122.52,6.52 131.52,15.52
EARTH on TOP (solid shape): outline of 254 points within 270.52,6.52 279.52,15.52
EARTH on BOTTOM (solid shape): outline of 254 points within 122.52,6.52 131.52,15.52
EARTH on BOTTOM (solid shape): outline of 254 points within 270.52,6.52 279.52,15.52
EARTH on TOP: 100.46,17.02 103.38,17.02 104.39,16 104.39,11.56 105.28,10.67 112.9,10.67 113.54,11.3 113.54,16.26 118.49,21.21 133.1,21.21 134.62,19.69 134.62,14.22 135.64,13.21 146.56,13.21 147.32,13.97 147.32,16 148.08,16.76 148.08,21.59 148.72,22.23 151,22.23 152.78,20.45 152.78,11.43 154.18,10.03 164.59,10.03 166.24,11.68 166.24,20.45 167,21.21 168.66,21.21 170.05,19.81 170.05,14.48 171.32,13.21 183.64,13.21 184.15,12.7 184.15,10.54 182.37,8.76 182.37,4.57 183.26,3.68 199.9,3.68 200.79,4.57 200.79,8.64 198.88,10.54 198.88,12.7 199.39,13.21 234.31,13.21 234.95,12.57 234.95,10.54 233.17,8.76 233.17,4.57 234.06,3.68 250.57,3.68 251.46,4.57 251.46,8.76 249.68,10.54 249.68,12.57 250.32,13.21 268.35,13.21 270.89,15.75 279.53,15.75 280.25,15.02 280.25,4.02 279.6,2.43 278.02,1.78 100.33,1.78 99.82,2.29 99.82,16.38
EARTH on BOTTOM: 123.57,26.29 133.35,26.29 134.62,25.02 134.62,14.22 135.64,13.21 146.56,13.21 147.32,13.97 147.32,16 148.08,16.76 148.08,21.59 148.72,22.23 151,22.23 152.78,20.45 152.78,11.43 154.18,10.03 164.59,10.03 166.24,11.68 166.24,20.45 167,21.21 168.66,21.21 170.05,19.81 170.05,14.48 171.32,13.21 183.64,13.21 184.15,12.7 184.15,10.54 182.37,8.76 182.37,4.57 183.26,3.68 199.9,3.68 200.79,4.57 200.79,8.64 198.88,10.54 198.88,12.7 199.39,13.21 234.31,13.21 234.95,12.57 234.95,10.54 233.17,8.76 233.17,4.57 234.06,3.68 250.57,3.68 251.46,4.57 251.46,8.76 249.68,10.54 249.68,12.57 250.32,13.21 268.35,13.21 270.89,15.75 279.53,15.75 280.25,15.02 280.25,4.02 279.6,2.43 278.02,1.78 165.74,1.78 100.33,1.78 99.82,2.29 99.82,16.38 100.46,17.02 103.38,17.02 104.39,16 104.39,11.56 105.28,10.67 113.28,10.67 113.92,11.3 113.92,15.62 114.81,16.51 114.81,17.53
EARTH on L2GND: 104.39,11.56 105.28,10.67 112.9,10.67 113.54,11.3 113.54,16.26 123.57,26.29 128.4,26.29 128.91,25.78 128.91,23.37 131.06,21.21 133.1,21.21 134.62,19.69 134.62,14.22 135.64,13.21 146.56,13.21 147.32,13.97 147.32,16 148.08,16.76 148.08,24 146.18,25.91 139.57,25.91 138.43,27.05 137.79,27.05 136.52,28.32 136.52,32.77 136.91,33.15 138.68,33.15 140.33,31.5 149.99,31.5 150.75,32.26 154.81,32.26 155.57,31.5 164.97,31.5 166.24,32.77 166.24,34.16 166.62,34.54 168.66,34.54 170.05,33.15 170.05,14.48 171.32,13.21 183.64,13.21 184.15,12.7 184.15,10.54 182.37,8.76 182.37,4.57 183.26,3.68 199.9,3.68 200.79,4.57 200.79,8.64 198.88,10.54 198.88,12.7 199.39,13.21 234.31,13.21 234.95,12.57 234.95,10.54 233.17,8.76 233.17,4.57 234.06,3.68 250.57,3.68 251.46,4.57 251.46,8.76 249.68,10.54 249.68,12.57 250.32,13.21 268.35,13.21 270.89,15.75 279.49,15.75 280.25,14.99 280.25,4.02 279.6,2.43 278.02,1.78 100.33,1.78 99.82,2.29 99.82,16.38 100.46,17.02 103.38,17.02 104.39,16
EARTH on L4PWR: 113.54,16.26 123.57,26.29 128.29,26.29 128.91,25.68 128.91,23.39 131.09,21.21 133.12,21.21 134.62,19.71 134.62,14.37 135.66,13.34 146.54,13.34 147.32,14.12 147.32,16.15 148.08,16.91 148.08,23.98 146.16,25.91 139.68,25.91 138.54,27.05 137.65,27.05 136.52,28.17 136.52,32.79 136.88,33.15 138.71,33.15 140.35,31.51 149.98,31.51 150.73,32.26 154.81,32.26 155.57,31.5 164.97,31.5 166.24,32.77 166.24,34.16 166.62,34.54 168.66,34.54 170.05,33.15 170.05,14.48 171.32,13.21 183.64,13.21 184.15,12.7 184.15,10.54 182.37,8.76 182.37,4.57 183.26,3.68 199.9,3.68 200.79,4.57 200.79,8.64 198.88,10.54 198.88,12.7 199.39,13.21 234.31,13.21 234.95,12.57 234.95,10.54 233.17,8.76 233.17,4.57 234.06,3.68 250.57,3.68 251.46,4.57 251.46,8.76 249.68,10.54 249.68,12.57 250.32,13.21 268.35,13.21 270.89,15.75 279.53,15.75 280.25,15.02 280.25,4.02 279.6,2.43 278.02,1.78 100.33,1.78 99.82,2.29 99.82,16.38 100.46,17.02 103.38,17.02 104.39,16 104.39,11.56 105.28,10.67 112.9,10.67 113.54,11.3
EARTH on L5PWR: 123.57,26.29 128.4,26.29 128.91,25.78 128.91,23.37 131.06,21.21 133.1,21.21 134.62,19.69 134.62,14.22 135.64,13.21 146.56,13.21 147.32,13.97 147.32,16 148.08,16.76 148.08,24 146.18,25.91 139.57,25.91 138.43,27.05 137.79,27.05 136.52,28.32 136.52,32.77 136.91,33.15 138.68,33.15 140.33,31.5 149.99,31.5 150.75,32.26 154.81,32.26 155.57,31.5 164.97,31.5 166.24,32.77 166.24,34.16 166.62,34.54 168.66,34.54 170.05,33.15 170.05,14.48 171.32,13.21 183.64,13.21 184.15,12.7 184.15,10.54 182.37,8.76 182.37,4.57 183.26,3.68 199.9,3.68 200.79,4.57 200.79,8.64 198.88,10.54 198.88,12.7 199.39,13.21 234.31,13.21 234.95,12.57 234.95,10.54 233.17,8.76 233.17,4.57 234.06,3.68 250.57,3.68 251.46,4.57 251.46,8.76 249.68,10.54 249.68,12.57 250.32,13.21 268.35,13.21 270.89,15.75 279.49,15.75 280.25,14.99 280.25,4.02 279.6,2.43 278.02,1.78 100.33,1.78 99.82,2.29 99.82,16.38 100.46,17.02 103.38,17.02 104.39,16 104.39,11.56 105.28,10.67 112.9,10.67 113.54,11.3 113.54,16.26
EARTH on L7GND: 123.57,26.29 128.4,26.29 128.91,25.78 128.91,23.37 131.06,21.21 133.1,21.21 134.62,19.69 134.62,14.22 135.64,13.21 146.56,13.21 147.32,13.97 147.32,16 148.08,16.76 148.08,24 146.18,25.91 139.57,25.91 138.43,27.05 137.79,27.05 136.52,28.32 136.52,32.77 136.91,33.15 138.68,33.15 140.33,31.5 149.99,31.5 150.75,32.26 154.81,32.26 155.57,31.5 164.97,31.5 166.24,32.77 166.24,34.16 166.62,34.54 168.66,34.54 170.05,33.15 170.05,14.48 171.32,13.21 183.64,13.21 184.15,12.7 184.15,10.54 182.37,8.76 182.37,4.57 183.26,3.68 199.9,3.68 200.79,4.57 200.79,8.64 198.88,10.54 198.88,12.7 199.39,13.21 234.31,13.21 234.95,12.57 234.95,10.54 233.17,8.76 233.17,4.57 234.06,3.68 250.57,3.68 251.46,4.57 251.46,8.76 249.68,10.54 249.68,12.57 250.32,13.21 268.35,13.21 270.89,15.75 279.53,15.75 280.25,15.02 280.25,4.02 279.6,2.43 278.02,1.78 100.33,1.78 99.82,2.29 99.82,16.38 100.46,17.02 103.38,17.02 104.39,16 104.39,11.56 105.28,10.67 112.9,10.67 113.54,11.3 113.54,16.26
EVDD on TOP: 52.58,127.25 52.58,126.49 52.32,126.24 50.04,126.24 49.91,126.37 49.91,143.26 48.89,144.27 44.45,144.27 44.32,144.4 44.32,145.16 44.58,145.41 49.53,145.41 51.43,143.51 51.43,128.4
EVDD on L4PWR: 106.8,94.86 95.61,106.05 74.91,106.05 54.72,126.24 51.79,126.24 51.56,126.47 51.56,127.66 51.67,127.76 57.04,127.76 76.09,108.71 97.94,108.71 107.97,98.68 151.13,98.68 151.64,99.19 151.64,102.11 151.89,102.36 155.93,102.36 160.77,107.2 160.77,108.07 160.78,108.08 160.78,109.09 161.04,109.35 162.94,109.35 163.32,108.97 163.32,107.95 163.45,107.82 163.45,103.38 159,98.93 159,96.14 158.62,95.76 158.37,95.76 158.24,95.89 158.24,96.27 157.73,96.77 156.72,96.77 155.7,95.76 154.3,95.76 154.18,95.89 154.18,96.27 153.67,96.77 152.78,96.77 150.88,94.87 107.57,94.87 107.56,94.86
